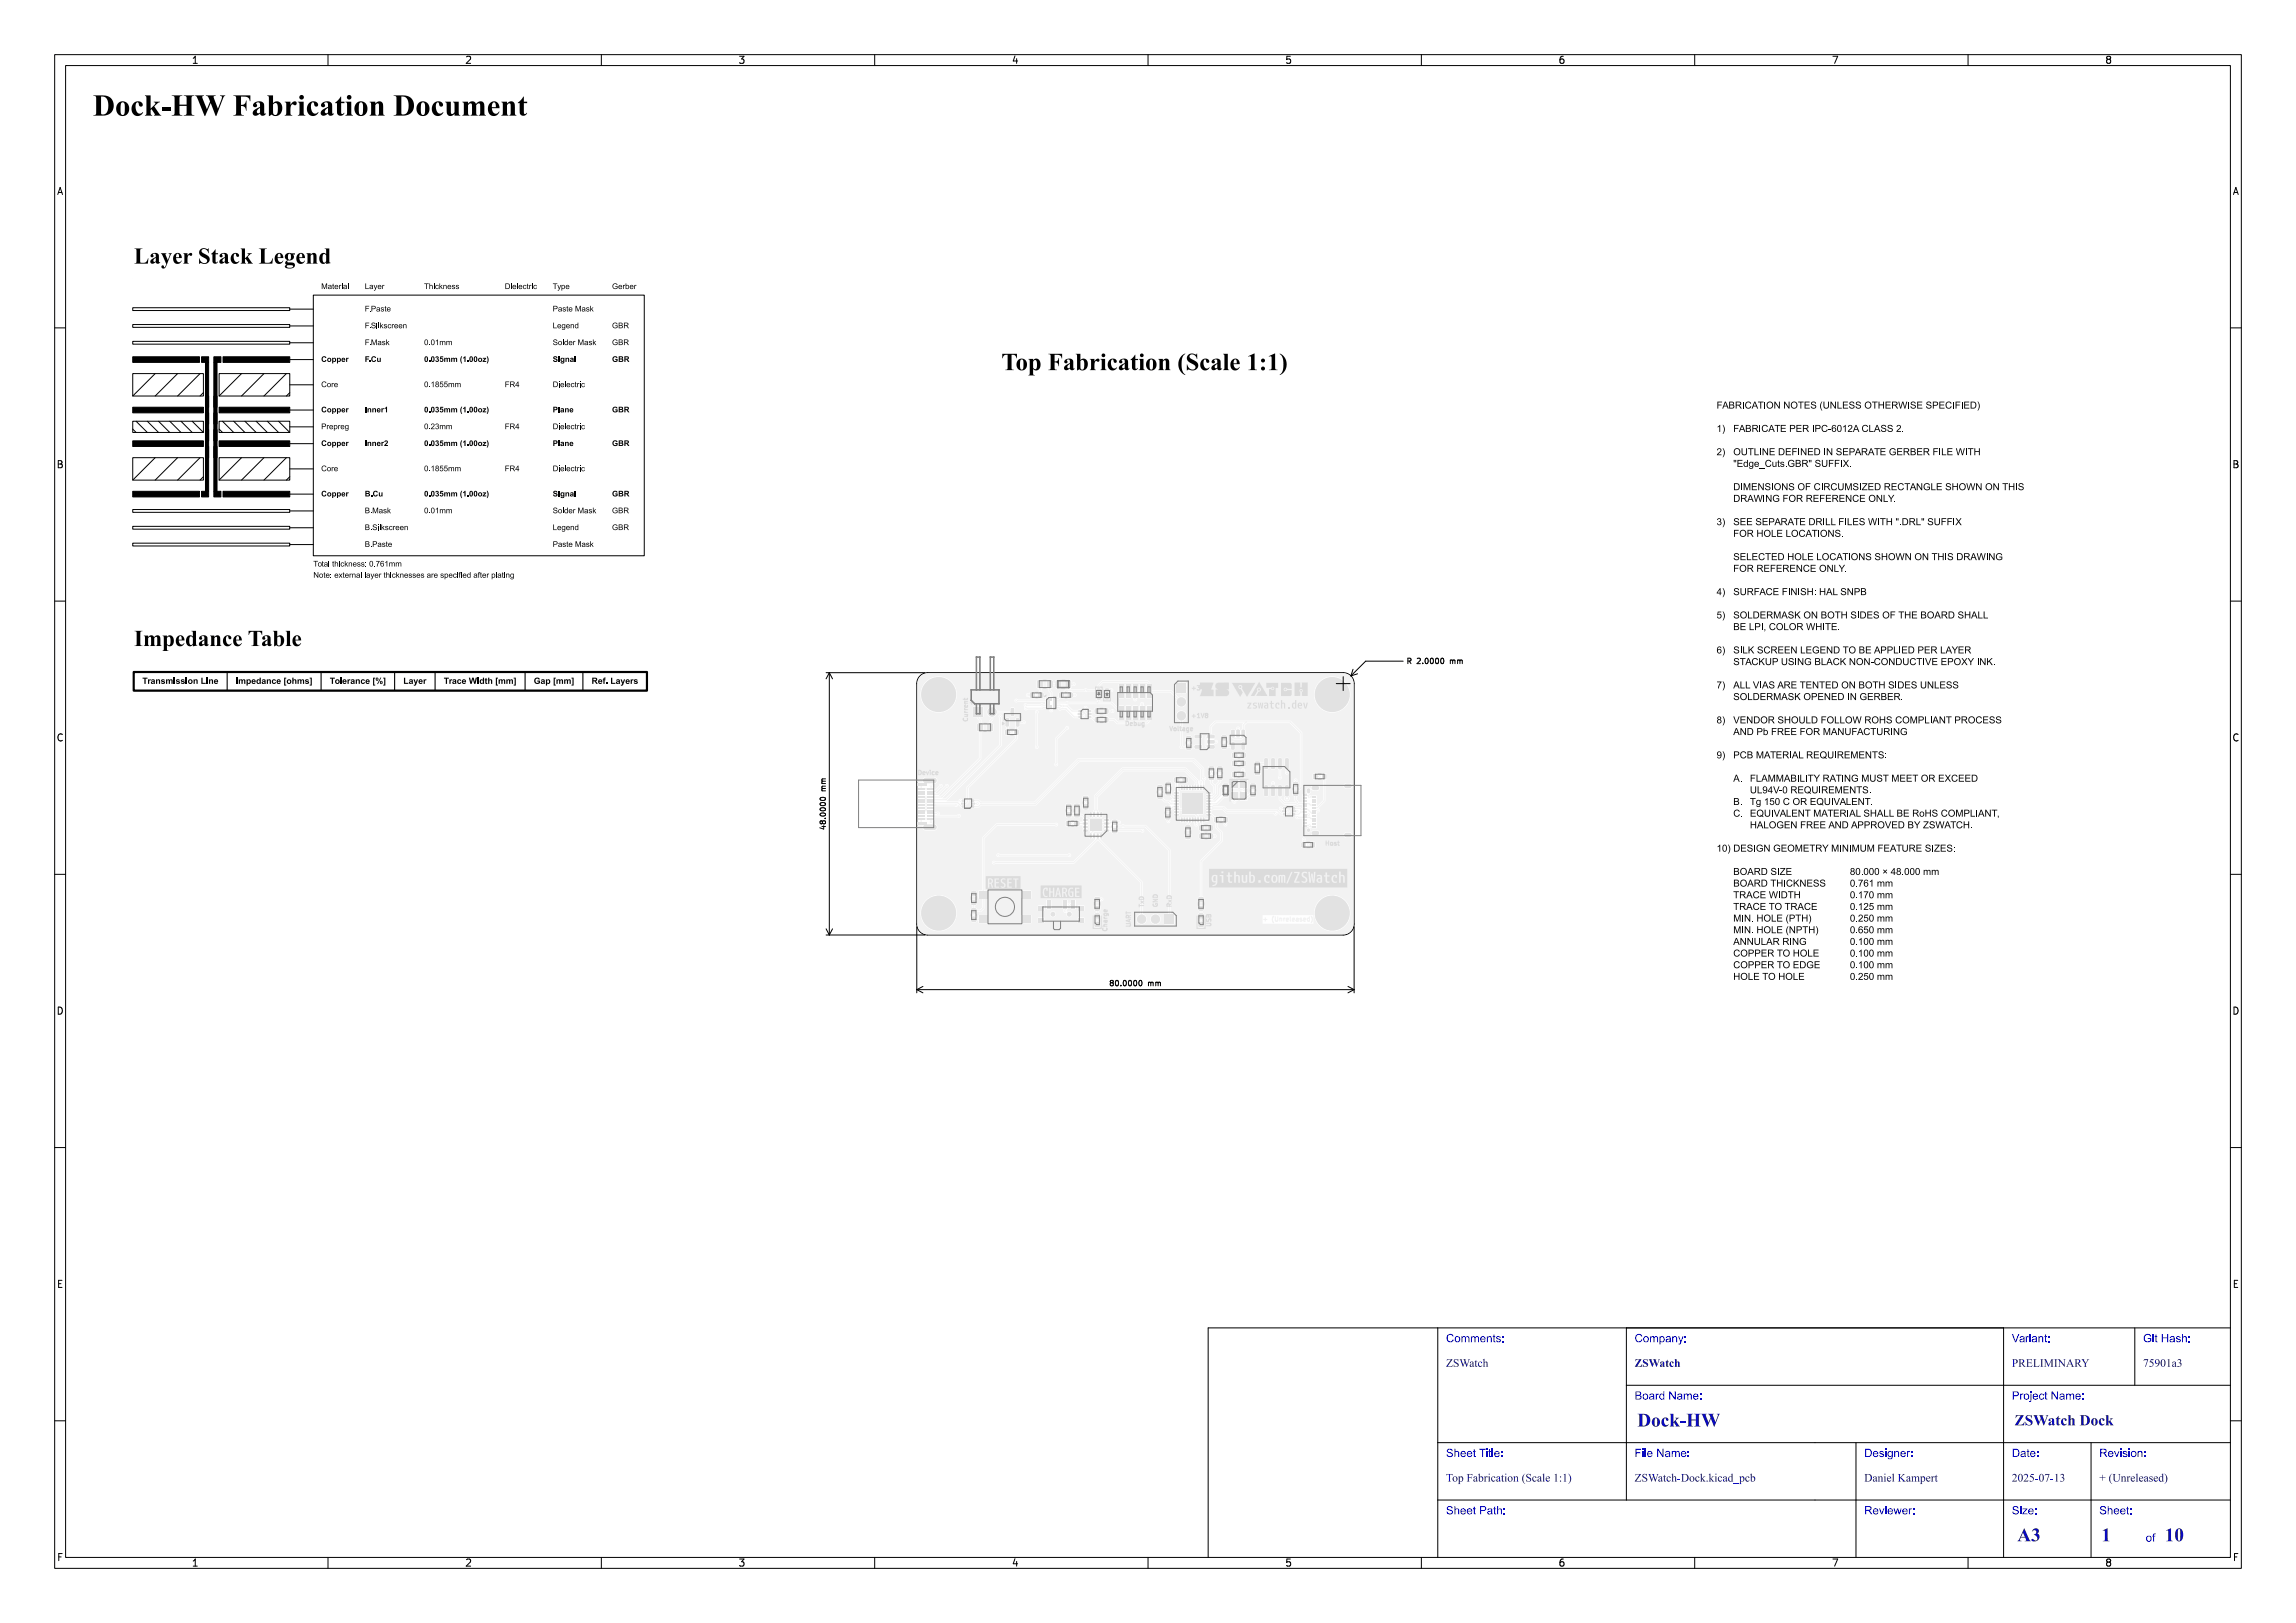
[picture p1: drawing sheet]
<svg xmlns="http://www.w3.org/2000/svg" width="420mm" height="297mm" viewBox="0 0 420 297" stroke-linecap="round" stroke-linejoin="round" font-family="sans-serif">
<defs><g id="words">
<text font-size="5.3" fill="#fff" x="17" y="21.5">Dock-HW Fabrication Document</text>
<text font-size="4.3" fill="#fff" x="174.4" y="68">Top Fabrication (Scale 1:1)</text>
<g font-size="3.3" fill="#fff">
<text x="299.5" y="261.2">Dock-HW</text>
<text x="369" y="282.2">A3</text>
<text x="384.4" y="282.3">1</text>
<text x="396" y="282.3">10</text>
</g>
<text font-size="2.7" fill="#fff" x="368.5" y="261">ZSWatch Dock</text>
<g font-size="2" fill="#fff">
<text x="264.5" y="245.7">Comments:</text>
<text x="299" y="245.7">Company:</text>
<text x="368" y="245.7">Variant:</text>
<text x="392" y="245.7">Git Hash:</text>
<text x="264.5" y="250.2">ZSWatch</text>
<text x="299" y="250.2">ZSWatch</text>
<text x="368" y="250.2">PRELIMINARY</text>
<text x="392" y="250.2">75901a3</text>
<text x="299" y="256.2">Board Name:</text>
<text x="368" y="256.2">Project Name:</text>
<text x="264.5" y="266.7">Sheet Title:</text>
<text x="299" y="266.7">File Name:</text>
<text x="341" y="266.7">Designer:</text>
<text x="368" y="266.7">Date:</text>
<text x="384" y="266.7">Revision:</text>
<text x="264.5" y="271.2">Top Fabrication (Scale 1:1)</text>
<text x="299" y="271.2">ZSWatch-Dock.kicad_pcb</text>
<text x="341" y="271.2">Daniel Kampert</text>
<text x="368" y="271.2">2025-07-13</text>
<text x="384" y="271.2">+ (Unreleased)</text>
<text x="264.5" y="277.2">Sheet Path:</text>
<text x="341" y="277.2">Reviewer:</text>
<text x="368" y="277.2">Size:</text>
<text x="384" y="277.2">Sheet:</text>
<text x="392.5" y="282.2">of</text>
</g>
<g font-size="1.7" fill="#fff">
<text x="35" y="11.6">1</text>
<text x="85" y="11.6">2</text>
<text x="135" y="11.6">3</text>
<text x="185" y="11.6">4</text>
<text x="235" y="11.6">5</text>
<text x="285" y="11.6">6</text>
<text x="335" y="11.6">7</text>
<text x="385" y="11.6">8</text>
<text x="10.5" y="35.6">A</text>
<text x="408.5" y="35.6">A</text>
<text x="10.5" y="85.6">B</text>
<text x="408.5" y="85.6">B</text>
<text x="10.5" y="135.6">C</text>
<text x="408.5" y="135.6">C</text>
<text x="10.5" y="185.6">D</text>
<text x="408.5" y="185.6">D</text>
<text x="10.5" y="235.6">E</text>
<text x="408.5" y="235.6">E</text>
<text x="10.5" y="285.6">F</text>
<text x="35" y="286.7">1</text>
<text x="85" y="286.7">2</text>
<text x="135" y="286.7">3</text>
<text x="185" y="286.7">4</text>
<text x="235" y="286.7">5</text>
<text x="285" y="286.7">6</text>
<text x="335" y="286.7">7</text>
<text x="385" y="286.7">8</text>
<text x="408.5" y="285.6">F</text>
</g>
<g font-size="1.3" fill="#fff">
<text x="258.1" y="121.5">R 2.0000 mm</text>
<text x="151" y="151.1" transform="rotate(-90 151 151.1)">48.0000 mm</text>
<text x="203.7" y="180.4">80.0000 mm</text>
</g>
<text font-size="1.1" fill="#fff" x="178.1" y="128.9" transform="rotate(-90 178.1 128.9)">+</text>
</g></defs>
<path d="M168.3 123.7l.9-.5 .5-.1h76a2 2 0 0 1 2 2v44a2 2 0 0 1-2 2h-76a2 2 0 0 1-2-2v-44l.1-.5z" fill="none" stroke="#000" stroke-width=".18"/>
<g fill="none" stroke="#f2f2f2" stroke-width=".18">
<path d="M231.1 168.3h.7M231.4 168v.6M233 167.6a.92 .92 0 0 0 0 1.3M233.3 167.8v.6l.1 .2 .3-.2v-.6M234.1 168v.6M234.1 168.1h.3l.1 .5M234.8 168v.6M235.1 168l-.3 .2M235.3 168.3l.4-.1-.1-.1h-.3v.4h.3M236 167.8v.6l.1 .2M236.4 168.3l.4-.1-.1-.1h-.3v.4h.3M237.1 168.1h.3l.1 .5"/>
<path d="M237.5 168.2l-.4 .2 .1 .2 .3-.1M238.1 168.1h-.3l.3 .2v.2h-.3M238.5 168.3l.3-.1v-.1h-.3v.4h.3M239.5 168.1l-.2-.1-.2 .2 .1 .3h.3M239.5 167.8v.8M239.8 167.6a.92 .92 0 0 1 0 1.3"/>
</g>
<g fill="#f2f2f2">
<path d="M202 151.9h.8v.2h-.8z" fill-rule="evenodd"/>
<path d="M202 151.2h.8v.3h-.8z" fill-rule="evenodd"/>
<path d="M202 150.6h.8v.2h-.8z" fill-rule="evenodd"/>
<path d="M202 149.9h.8v.3h-.8z" fill-rule="evenodd"/>
<path d="M201.3 148.7h.3v.8h-.3z" fill-rule="evenodd"/>
<path d="M200.7 148.7h.2v.8h-.2z" fill-rule="evenodd"/>
<path d="M200 148.7h.3v.8h-.3z" fill-rule="evenodd"/>
<path d="M199.4 148.7h.2v.8h-.2z" fill-rule="evenodd"/>
<path d="M198.1 149.9h.8v.3h-.8z" fill-rule="evenodd"/>
<path d="M198.1 150.6h.8v.2h-.8z" fill-rule="evenodd"/>
<path d="M198.1 151.2h.8v.3h-.8z" fill-rule="evenodd"/>
<path d="M198.1 151.9h.8v.2h-.8z" fill-rule="evenodd"/>
<path d="M199.4 152.6h.2v.8h-.2z" fill-rule="evenodd"/>
<path d="M200 152.6h.3v.8h-.3z" fill-rule="evenodd"/>
<path d="M200.7 152.6h.2v.8h-.2z" fill-rule="evenodd"/>
<path d="M201.3 152.6h.3v.8h-.3z" fill-rule="evenodd"/>
<path d="M199.4 150h2.1v2.1h-2.1z" fill-rule="evenodd"/>
<path d="M202.2 127.4h.6v.6h-.6z" fill-rule="evenodd"/>
<path d="M202.2 126h.6v.6h-.6z" fill-rule="evenodd"/>
<path d="M219.3 165.9h.8v.7h-.8z" fill-rule="evenodd"/>
<path d="M219.3 164.2h.8v.7h-.8z" fill-rule="evenodd"/>
<path d="M227.2 133.6l.5 .1-.1 1.2-.5-.1z" fill-rule="evenodd"/>
<path d="M226.2 133.6l.6 .1-.1 1.2-.5-.1z" fill-rule="evenodd"/>
<path d="M225.3 133.6l.5 .1-.1 1.2-.5-.1z" fill-rule="evenodd"/>
<path d="M225.3 135.9h.5l-.1 1.3-.5-.1z" fill-rule="evenodd"/>
<path d="M227.2 135.9h.5l-.1 1.3-.5-.1z" fill-rule="evenodd"/>
<path d="M203.5 151.6h.8v.8h-.8z" fill-rule="evenodd"/>
<path d="M203.5 150.1h.8v.8h-.8z" fill-rule="evenodd"/>
<path d="M219.5 152.6h.7v.8h-.7z" fill-rule="evenodd"/>
<path d="M221 152.6h.8v.8h-.8z" fill-rule="evenodd"/>
<path d="M241.9 141.7h.7v.8h-.7z" fill-rule="evenodd"/>
<path d="M240.2 141.7h.7v.8h-.7z" fill-rule="evenodd"/>
<path d="M238.4 150.9h.7v.3h-.7z" fill-rule="evenodd"/>
<path d="M238.4 150.4h.7v.3h-.7z" fill-rule="evenodd"/>
<path d="M238.4 149.9h.7v.3h-.7z" fill-rule="evenodd"/>
<path d="M238.4 149.4h.7v.3h-.7z" fill-rule="evenodd"/>
<path d="M238.4 148.9h.7v.3h-.7z" fill-rule="evenodd"/>
<path d="M238.4 148.4h.7v.3h-.7z" fill-rule="evenodd"/>
<path d="M238.4 147.9h.7v.3h-.7z" fill-rule="evenodd"/>
<path d="M238.4 147.4h.7v.3h-.7z" fill-rule="evenodd"/>
<path d="M238.4 146.9h.7v.3h-.7z" fill-rule="evenodd"/>
<path d="M238.4 146.4h.7v.3h-.7z" fill-rule="evenodd"/>
<path d="M238.4 145.9h.7v.3h-.7z" fill-rule="evenodd"/>
<path d="M238.4 145.4h.7v.3h-.7z" fill-rule="evenodd"/>
<path d="M240.1 145.7h.7v.3h-.7z" fill-rule="evenodd"/>
<path d="M240.1 146.2h.7v.3h-.7z" fill-rule="evenodd"/>
<path d="M240.1 146.7h.7v.3h-.7z" fill-rule="evenodd"/>
<path d="M240.1 147.2h.7v.3h-.7z" fill-rule="evenodd"/>
<path d="M240.1 147.7h.7v.3h-.7z" fill-rule="evenodd"/>
<path d="M240.1 148.2h.7v.3h-.7z" fill-rule="evenodd"/>
<path d="M240.1 148.7h.7v.3h-.7z" fill-rule="evenodd"/>
<path d="M240.1 149.2h.7v.3h-.7z" fill-rule="evenodd"/>
<path d="M240.1 149.7h.7v.3h-.7z" fill-rule="evenodd"/>
<path d="M240.1 150.2h.7v.3h-.7z" fill-rule="evenodd"/>
<path d="M240.1 150.7h.7v.3h-.7z" fill-rule="evenodd"/>
<path d="M240.1 151.2h.7v.3h-.7z" fill-rule="evenodd"/>
</g>
<g fill="#f2f2f2">
<circle cx="241.3" cy="167.1" r=".4"/>
<circle cx="242" cy="165.4" r=".4"/>
<circle cx="242" cy="168.8" r=".4"/>
<circle cx="243.7" cy="164.7" r=".4"/>
<circle cx="243.7" cy="167.1" r="3.2"/>
<circle cx="243.7" cy="169.5" r=".4"/>
<circle cx="245.4" cy="165.4" r=".4"/>
<circle cx="245.4" cy="168.8" r=".4"/>
<circle cx="246.1" cy="167.1" r=".4"/>
</g>
<path d="M240.3 152.4h.6M240.3 144.2h.6M246.3 152.8h.6M246.3 143.8h.6" fill="none" stroke="#f2f2f2" stroke-width=".8"/>
<g fill="#f2f2f2">
<path d="M239.8 154.2h.7v.8h-.7z" fill-rule="evenodd"/>
<path d="M238.1 154.2h.7v.8h-.7z" fill-rule="evenodd"/>
<path d="M200.3 165.9h.8v.7h-.8z" fill-rule="evenodd"/>
<path d="M200.3 164.2h.8v.7h-.8z" fill-rule="evenodd"/>
<path d="M216.9 152.8h.8v.7h-.8z" fill-rule="evenodd"/>
<path d="M216.9 151.1h.8v.7h-.8z" fill-rule="evenodd"/>
<path d="M178.1 129.4h1.7v1.7h-1.7z" fill-rule="evenodd"/>
<path d="M222.7 141.9h.8v.8h-.8z" fill-rule="evenodd"/>
<path d="M222.7 140.3h.8v.8h-.8z" fill-rule="evenodd"/>
<path d="M180.7 132.5l.7-.1 .2 .2v.9l-.1 .3h-.7l-.2-.2z" fill-rule="evenodd"/>
<path d="M178.8 132.5l.8-.1 .2 .2v.9l-.2 .3h-.6l-.2-.2z" fill-rule="evenodd"/>
<path d="M193.2 124.6l.7-.1 .2 .2v.9l-.1 .3h-.7l-.2-.2z" fill-rule="evenodd"/>
<path d="M195 124.6l.7-.1 .2 .2v.9l-.1 .3h-.6l-.3-.2z" fill-rule="evenodd"/>
<path d="M235.1 138.8l.6 .1-.1 1.8-.5-.1z" fill-rule="evenodd"/>
<path d="M233.9 138.8l.5 .1-.1 1.8-.5-.1z" fill-rule="evenodd"/>
<path d="M232.6 138.8l.6 .1-.1 1.8-.5-.1z" fill-rule="evenodd"/>
<path d="M231.3 138.8l.6 .1-.1 1.8-.5-.1z" fill-rule="evenodd"/>
<path d="M231.3 143.8h.6l-.1 1.9-.5-.1z" fill-rule="evenodd"/>
<path d="M232.6 143.8h.6l-.1 1.9-.5-.1z" fill-rule="evenodd"/>
<path d="M233.9 143.8h.5l-.1 1.9-.5-.1z" fill-rule="evenodd"/>
<path d="M235.1 143.8h.6l-.1 1.9-.5-.1z" fill-rule="evenodd"/>
<path d="M223.5 136.2h.8v.8h-.8z" fill-rule="evenodd"/>
<path d="M223.5 134.6h.8v.8h-.8z" fill-rule="evenodd"/>
<path d="M213.1 167.4h1.6v1.6h-1.6z" fill-rule="evenodd"/>
<path d="M183.9 133.6h.7v.8h-.7z" fill-rule="evenodd"/>
<path d="M185.6 133.6h.7v.8h-.7z" fill-rule="evenodd"/>
<path d="M179.1 163h1.5v1.4h-1.5z" fill-rule="evenodd"/>
<path d="M179.1 167.6h1.5v1.2h-1.5z" fill-rule="evenodd"/>
<path d="M187 163h1.6v1.4h-1.6z" fill-rule="evenodd"/>
<path d="M187 167.6h1.6v1.2h-1.6z" fill-rule="evenodd"/>
<path d="M200.3 129.7h.7v.8h-.7z" fill-rule="evenodd"/>
<path d="M202 129.7h.7v.8h-.7z" fill-rule="evenodd"/>
<path d="M213.2 147.5h.8v.8h-.8z" fill-rule="evenodd"/>
<path d="M213.2 149.1h.8v.8h-.8z" fill-rule="evenodd"/>
<path d="M200.7 126h.6v.6h-.6z" fill-rule="evenodd"/>
<path d="M200.7 127.4h.6v.6h-.6z" fill-rule="evenodd"/>
<path d="M229.6 139.4h.8v.7h-.8z" fill-rule="evenodd"/>
<path d="M229.6 141.1h.8v.7h-.8z" fill-rule="evenodd"/>
<path d="M177.7 147.4h.4l.1 .3-.5 .1z" fill-rule="evenodd"/>
<path d="M177.7 146.9h.6v.3h-.6z" fill-rule="evenodd"/>
<path d="M177.7 146.4h.5v.3h-.5z" fill-rule="evenodd"/>
<path d="M176 146.4h.5v.3h-.5z" fill-rule="evenodd"/>
<path d="M175.9 146.9h.5l.1 .3h-.6z" fill-rule="evenodd"/>
<path d="M176 147.4h.4l.1 .3-.5 .1z" fill-rule="evenodd"/>
<path d="M184 131.5h.5v1.4l-.5-.1z" fill-rule="evenodd"/>
<path d="M185.9 131.5h.5v1.4l-.5-.1z" fill-rule="evenodd"/>
<path d="M184.9 129.6l.6 .1-.1 1.3-.5-.1z" fill-rule="evenodd"/>
<path d="M211.8 145.3h.8v.8h-.8z" fill-rule="evenodd"/>
<path d="M211.8 143.8h.8v.7h-.8z" fill-rule="evenodd"/>
<path d="M197.3 130l.4-.1 .1 .4h-.4z" fill-rule="evenodd"/>
<path d="M197.2 130.5h.6v.3h-.6z" fill-rule="evenodd"/>
<path d="M197.3 131h.4l.1 .3-.4 .1z" fill-rule="evenodd"/>
<path d="M199 131h.4l.1 .3-.4 .1z" fill-rule="evenodd"/>
<path d="M199 130.5h.6v.3h-.6z" fill-rule="evenodd"/>
<path d="M199 130l.4-.1 .1 .4h-.4z" fill-rule="evenodd"/>
<path d="M196.6 147.2h.8v.6h-.8z" fill-rule="evenodd"/>
<path d="M196.6 148.8h.8v.7h-.8z" fill-rule="evenodd"/>
<path d="M213.3 143.1h.8v.7h-.8z" fill-rule="evenodd"/>
<path d="M213.3 144.8h.8v.7h-.8z" fill-rule="evenodd"/>
<path d="M190 126.8h.8v.8h-.8z" fill-rule="evenodd"/>
<path d="M188.5 126.8h.7v.8h-.7z" fill-rule="evenodd"/>
<path d="M234.7 147.8l.4-.1 .1 .4h-.4z" fill-rule="evenodd"/>
<path d="M234.6 148.3h.6v.3h-.6z" fill-rule="evenodd"/>
<path d="M234.7 148.8h.4l.1 .3-.4 .1z" fill-rule="evenodd"/>
<path d="M236.4 148.8h.4l.1 .3-.4 .1z" fill-rule="evenodd"/>
<path d="M236.4 148.3h.6v.3h-.6z" fill-rule="evenodd"/>
<path d="M236.4 147.8l.4-.1 .1 .4h-.4z" fill-rule="evenodd"/>
<path d="M177.7 163.2h.8v.7h-.8z" fill-rule="evenodd"/>
<path d="M177.7 164.8h.8v.7h-.8z" fill-rule="evenodd"/>
<path d="M225.2 142.8h1.2v1.4h-1.2z" fill-rule="evenodd"/>
<path d="M225.2 145h1.2v1.4h-1.2z" fill-rule="evenodd"/>
<path d="M226.9 145h1.2v1.4h-1.2z" fill-rule="evenodd"/>
<path d="M226.9 142.8h1.2v1.4h-1.2z" fill-rule="evenodd"/>
<path d="M236.6 144.8h.8v.7h-.8z" fill-rule="evenodd"/>
<path d="M236.6 143.2h.8v.8h-.8z" fill-rule="evenodd"/>
<path d="M177.7 166.3h.8v.8h-.8z" fill-rule="evenodd"/>
<path d="M177.7 167.8h.8v.8h-.8z" fill-rule="evenodd"/>
<path d="M220.1 143.8h.2l-.1 .8-.2-.1z" fill-rule="evenodd"/>
<path d="M219.6 143.8h.2l-.1 .8-.2-.1z" fill-rule="evenodd"/>
<path d="M219.1 143.8h.2l-.1 .8-.2-.1z" fill-rule="evenodd"/>
<path d="M218.6 143.8h.2l-.1 .8-.2-.1z" fill-rule="evenodd"/>
<path d="M218.1 143.8h.2l-.1 .8-.2-.1z" fill-rule="evenodd"/>
<path d="M217.6 143.8h.2l-.1 .8-.2-.1z" fill-rule="evenodd"/>
<path d="M217.1 143.8h.2l-.1 .8-.2-.1z" fill-rule="evenodd"/>
<path d="M216.6 143.8h.2l-.1 .8-.2-.1z" fill-rule="evenodd"/>
<path d="M216.1 143.8h.2l-.1 .8-.2-.1z" fill-rule="evenodd"/>
<path d="M214.8 145h.8v.2h-.7z" fill-rule="evenodd"/>
<path d="M214.8 145.5h.8v.2h-.7z" fill-rule="evenodd"/>
<path d="M214.8 146h.8v.2h-.7z" fill-rule="evenodd"/>
<path d="M214.8 146.5h.8v.2h-.7z" fill-rule="evenodd"/>
<path d="M214.8 147h.8v.2h-.7z" fill-rule="evenodd"/>
<path d="M214.8 147.5h.8v.2h-.7z" fill-rule="evenodd"/>
<path d="M214.8 148h.8v.2h-.7z" fill-rule="evenodd"/>
<path d="M214.8 148.5h.8v.2h-.7z" fill-rule="evenodd"/>
<path d="M214.8 149h.8v.2h-.7z" fill-rule="evenodd"/>
<path d="M216.1 149.6l.2 .1-.1 .8-.2-.1z" fill-rule="evenodd"/>
<path d="M216.6 149.6l.2 .1-.1 .8-.2-.1z" fill-rule="evenodd"/>
<path d="M217.1 149.6l.2 .1-.1 .8-.2-.1z" fill-rule="evenodd"/>
<path d="M217.6 149.6l.2 .1-.1 .8-.2-.1z" fill-rule="evenodd"/>
<path d="M218.1 149.6l.2 .1-.1 .8-.2-.1z" fill-rule="evenodd"/>
<path d="M218.6 149.6l.2 .1-.1 .8-.2-.1z" fill-rule="evenodd"/>
<path d="M219.1 149.6l.2 .1-.1 .8-.2-.1z" fill-rule="evenodd"/>
<path d="M219.6 149.6l.2 .1-.1 .8-.2-.1z" fill-rule="evenodd"/>
<path d="M220.1 149.6l.2 .1-.1 .8-.2-.1z" fill-rule="evenodd"/>
<path d="M220.7 149h.8v.2h-.8z" fill-rule="evenodd"/>
<path d="M220.7 148.5h.8v.2h-.8z" fill-rule="evenodd"/>
<path d="M220.7 148h.8v.2h-.8z" fill-rule="evenodd"/>
<path d="M220.7 147.5h.8v.2h-.8z" fill-rule="evenodd"/>
<path d="M220.7 147h.8v.2h-.8z" fill-rule="evenodd"/>
<path d="M220.7 146.5h.8v.2h-.8z" fill-rule="evenodd"/>
<path d="M220.7 146h.8v.2h-.8z" fill-rule="evenodd"/>
<path d="M220.7 145.5h.8v.2h-.8z" fill-rule="evenodd"/>
<path d="M220.7 145h.8v.2h-.8z" fill-rule="evenodd"/>
<path d="M216.3 145.2h3.7v3.7h-3.7z" fill-rule="evenodd"/>
<path d="M227 137.8h.8v.8h-.8z" fill-rule="evenodd"/>
<path d="M225.5 137.8h.7v.8h-.7z" fill-rule="evenodd"/>
<path d="M200.3 168.8h.8v.8h-.8z" fill-rule="evenodd"/>
<path d="M200.3 167.2h.8v.8h-.8z" fill-rule="evenodd"/>
<path d="M190 165.8h1v.8h-1z" fill-rule="evenodd"/>
<path d="M190 168h1v.8h-1z" fill-rule="evenodd"/>
<path d="M197.2 165.8h1.1v.8h-1.1z" fill-rule="evenodd"/>
<path d="M197.2 168h1.1v.8h-1.1z" fill-rule="evenodd"/>
<path d="M191.5 164.8h.7v1.5h-.7z" fill-rule="evenodd"/>
<path d="M194.5 164.8h.7v1.5h-.7z" fill-rule="evenodd"/>
<path d="M196 164.8h.7v1.5h-.7z" fill-rule="evenodd"/>
<path d="M222.2 149.6h.6v.8h-.6z" fill-rule="evenodd"/>
<path d="M223.8 149.6h.7v.8h-.7z" fill-rule="evenodd"/>
<path d="M227 139.3h.8v.8h-.8z" fill-rule="evenodd"/>
<path d="M225.5 139.3h.7v.8h-.7z" fill-rule="evenodd"/>
<path d="M169.7 149.7h1.2v.3h-1.2z" fill-rule="evenodd"/>
<path d="M169.7 149.2h1.2v.3h-1.2z" fill-rule="evenodd"/>
<path d="M169.7 148.7h1.2v.3h-1.2z" fill-rule="evenodd"/>
<path d="M169.7 148.2h1.2v.3h-1.2z" fill-rule="evenodd"/>
<path d="M169.7 147.7h1.2v.3h-1.2z" fill-rule="evenodd"/>
<path d="M169.7 147.2h1.2v.3h-1.2z" fill-rule="evenodd"/>
<path d="M169.7 146.7h1.2v.3h-1.2z" fill-rule="evenodd"/>
<path d="M169.7 146.2h1.2v.3h-1.2z" fill-rule="evenodd"/>
<path d="M169.7 145.7h1.2v.3h-1.2z" fill-rule="evenodd"/>
<path d="M169.7 145.2h1.2v.3h-1.2z" fill-rule="evenodd"/>
<path d="M169.7 144.7h1.2v.3h-1.2z" fill-rule="evenodd"/>
<path d="M169.7 144.2h1.2v.3h-1.2z" fill-rule="evenodd"/>
<path d="M167.9 144.2h1.1v.3h-1.1z" fill-rule="evenodd"/>
<path d="M167.9 144.7h1.1v.3h-1.1z" fill-rule="evenodd"/>
<path d="M167.9 145.2h1.1v.3h-1.1z" fill-rule="evenodd"/>
<path d="M167.9 145.7h1.1v.3h-1.1z" fill-rule="evenodd"/>
<path d="M167.9 146.2h1.1v.3h-1.1z" fill-rule="evenodd"/>
<path d="M167.9 146.7h1.1v.3h-1.1z" fill-rule="evenodd"/>
<path d="M167.9 147.2h1.1v.3h-1.1z" fill-rule="evenodd"/>
<path d="M167.9 147.7h1.1v.3h-1.1z" fill-rule="evenodd"/>
<path d="M167.9 148.2h1.1v.3h-1.1z" fill-rule="evenodd"/>
<path d="M167.9 148.7h1.1v.3h-1.1z" fill-rule="evenodd"/>
<path d="M167.9 149.2h1.1v.3h-1.1z" fill-rule="evenodd"/>
<path d="M167.9 149.7h1.1v.3h-1.1z" fill-rule="evenodd"/>
</g>
<g fill="#f2f2f2">
<circle cx="181.5" cy="130.3" r=".85"/>
<circle cx="211.4" cy="168.2" r=".85"/>
<circle cx="208.8" cy="168.2" r=".85"/>
<circle cx="241.3" cy="127.1" r=".4"/>
<circle cx="242" cy="125.4" r=".4"/>
<circle cx="242" cy="128.8" r=".4"/>
<circle cx="243.7" cy="124.7" r=".4"/>
<circle cx="243.7" cy="127.1" r="3.2"/>
<circle cx="243.7" cy="129.5" r=".4"/>
<circle cx="245.4" cy="125.4" r=".4"/>
<circle cx="245.4" cy="128.8" r=".4"/>
<circle cx="246.1" cy="127.1" r=".4"/>
<circle cx="169.3" cy="167.1" r=".4"/>
<circle cx="170" cy="165.4" r=".4"/>
<circle cx="170" cy="168.8" r=".4"/>
<circle cx="171.7" cy="164.7" r=".4"/>
<circle cx="171.7" cy="167.1" r="3.2"/>
<circle cx="171.7" cy="169.5" r=".4"/>
<circle cx="173.4" cy="165.4" r=".4"/>
<circle cx="173.4" cy="168.8" r=".4"/>
<circle cx="174.1" cy="167.1" r=".4"/>
</g>
<path d="M169.3 142.8h1.6" fill="none" stroke="#f2f2f2" stroke-width="1"/>
<g fill="#f2f2f2">
<path d="M167.8 143.3h1.8v.5h-1.8z" fill-rule="evenodd"/>
<path d="M167.8 150.4h1.8v.5h-1.8z" fill-rule="evenodd"/>
</g>
<path d="M169.3 151.4h1.6" fill="none" stroke="#f2f2f2" stroke-width="1"/>
<g fill="#f2f2f2">
<path d="M214.9 142.3h.7v.8h-.7z" fill-rule="evenodd"/>
<path d="M216.4 142.3h.8v.8h-.8z" fill-rule="evenodd"/>
<path d="M228.8 143.5h.8v.7h-.8z" fill-rule="evenodd"/>
<path d="M228.8 145h.8v.8h-.8z" fill-rule="evenodd"/>
<path d="M209.8 125.3h.8v2.4h-.8z" fill-rule="evenodd"/>
<path d="M209.8 129.2h.8v2.4h-.8z" fill-rule="evenodd"/>
<path d="M208.5 125.3h.8v2.4h-.8z" fill-rule="evenodd"/>
<path d="M208.5 129.2h.8v2.4h-.8z" fill-rule="evenodd"/>
<path d="M207.3 125.3h.7v2.4h-.7z" fill-rule="evenodd"/>
<path d="M207.3 129.2h.7v2.4h-.7z" fill-rule="evenodd"/>
<path d="M206 125.3h.7v2.4h-.7z" fill-rule="evenodd"/>
<path d="M206 129.2h.7v2.4h-.7z" fill-rule="evenodd"/>
<path d="M204.7 125.3h.8v2.4h-.8z" fill-rule="evenodd"/>
<path d="M204.7 129.2h.8v2.4h-.8z" fill-rule="evenodd"/>
<path d="M221.1 151.1h.7v.8h-.7z" fill-rule="evenodd"/>
<path d="M219.4 151.1h.7v.8h-.7z" fill-rule="evenodd"/>
<path d="M215.2 125.1h1.7v1.7h-1.7z" fill-rule="evenodd"/>
<path d="M189.8 124.6l.7-.1 .2 .2v.9l-.1 .3h-.7l-.2-.2z" fill-rule="evenodd"/>
<path d="M191.6 124.6l.7-.1 .2 .2v.9l-.1 .3h-.6l-.3-.2z" fill-rule="evenodd"/>
<path d="M191.3 127.7h.6v.2h-.6z" fill-rule="evenodd"/>
<path d="M191.8 127.5h.1v.3h-.1z" fill-rule="evenodd"/>
<path d="M191.3 128.1h.6v.2h-.6z" fill-rule="evenodd"/>
<path d="M191.3 128.5h.6v.2h-.6z" fill-rule="evenodd"/>
<path d="M191.3 128.9h.6v.2h-.6z" fill-rule="evenodd"/>
<path d="M191.3 129.3h.6v.2h-.6z" fill-rule="evenodd"/>
<path d="M192.2 129.1h.2v.6h-.2z" fill-rule="evenodd"/>
<path d="M192.6 129.3h.6v.2h-.6z" fill-rule="evenodd"/>
<path d="M192.6 128.9h.6v.2h-.6z" fill-rule="evenodd"/>
<path d="M192.6 128.5h.6v.2h-.6z" fill-rule="evenodd"/>
<path d="M192.6 128.1h.6v.2h-.6z" fill-rule="evenodd"/>
<path d="M192.6 127.7h.6v.2h-.6z" fill-rule="evenodd"/>
<path d="M192.2 127.5h.2v.6h-.2z" fill-rule="evenodd"/>
<path d="M219.3 168.8h.8v.8h-.8z" fill-rule="evenodd"/>
<path d="M219.3 167.2h.8v.8h-.8z" fill-rule="evenodd"/>
<path d="M223.8 143.4h.8v.7h-.8z" fill-rule="evenodd"/>
<path d="M223.8 145.1h.8v.7h-.8z" fill-rule="evenodd"/>
<path d="M193.8 126.8h.8v.8h-.8z" fill-rule="evenodd"/>
<path d="M195.4 126.8h.7v.8h-.7z" fill-rule="evenodd"/>
<path d="M195.1 148.7h.8v.8h-.8z" fill-rule="evenodd"/>
<path d="M195.1 147.2h.8v.7h-.8z" fill-rule="evenodd"/>
<path d="M221.2 142h.8v.7h-.8z" fill-rule="evenodd"/>
<path d="M221.2 140.3h.8v.7h-.8z" fill-rule="evenodd"/>
<path d="M196.6 150.3h.8v.8h-.8z" fill-rule="evenodd"/>
<path d="M195 150.3h.8v.8h-.8z" fill-rule="evenodd"/>
<path d="M200.3 131.3h.7v.8h-.7z" fill-rule="evenodd"/>
<path d="M202 131.3h.7v.8h-.7z" fill-rule="evenodd"/>
<path d="M198.2 147.3h.8v.7h-.8z" fill-rule="evenodd"/>
<path d="M198.2 145.7h.8v.8h-.8z" fill-rule="evenodd"/>
<path d="M227 141.3h.8v.8h-.8z" fill-rule="evenodd"/>
<path d="M225.4 141.3h.8v.8h-.8z" fill-rule="evenodd"/>
<path d="M217 136.3h.9v.8h-.9z" fill-rule="evenodd"/>
<path d="M217 134.8h.9v.8h-.9z" fill-rule="evenodd"/>
<path d="M220.9 136.4h1.2v.5l-1.2 .1z" fill-rule="evenodd"/>
<path d="M220.9 135.5l1.2-.1v.5l-1.2 .1z" fill-rule="evenodd"/>
<path d="M220.9 134.5h1.2v.5l-1.2 .1z" fill-rule="evenodd"/>
<path d="M218.6 134.5h1.2l.1 .5-1.3 .1z" fill-rule="evenodd"/>
<path d="M218.6 136.4h1.2l.1 .5-1.3 .1z" fill-rule="evenodd"/>
</g>
<g fill="#f2f2f2">
<circle cx="216.1" cy="128.4" r=".85"/>
<circle cx="216.1" cy="131" r=".85"/>
<circle cx="169.3" cy="127.1" r=".4"/>
<circle cx="170" cy="125.4" r=".4"/>
<circle cx="170" cy="128.8" r=".4"/>
<circle cx="171.7" cy="124.7" r=".4"/>
<circle cx="171.7" cy="127.1" r="3.2"/>
<circle cx="171.7" cy="129.5" r=".4"/>
<circle cx="173.4" cy="125.4" r=".4"/>
<circle cx="173.4" cy="128.8" r=".4"/>
<circle cx="174.1" cy="127.1" r=".4"/>
<circle cx="227.4" cy="140.9" r=".22"/>
<circle cx="237" cy="142.8" r=".23"/>
<circle cx="232.9" cy="143.3" r=".23"/>
<circle cx="235.6" cy="148.5" r=".23"/>
<circle cx="196.6" cy="127.2" r=".22"/>
<circle cx="222.2" cy="153" r=".23"/>
<circle cx="198.6" cy="146.9" r=".22"/>
<circle cx="207.6" cy="128" r=".23"/>
<circle cx="223.9" cy="135.8" r=".23"/>
<circle cx="178.1" cy="167.5" r=".22"/>
<circle cx="225.8" cy="146.7" r=".22"/>
<circle cx="196.2" cy="150.7" r=".23"/>
<circle cx="218.8" cy="150.9" r=".23"/>
<circle cx="196.4" cy="125.2" r=".22"/>
<circle cx="223.1" cy="141.5" r=".22"/>
<circle cx="198.2" cy="131" r=".23"/>
<circle cx="230" cy="140.7" r=".22"/>
<circle cx="217.4" cy="135.9" r=".22"/>
<circle cx="203.3" cy="126.3" r=".22"/>
<circle cx="222.4" cy="135.7" r=".22"/>
<circle cx="226.6" cy="139.7" r=".23"/>
<circle cx="212.2" cy="144.9" r=".22"/>
<circle cx="226.6" cy="138.2" r=".23"/>
<circle cx="170.3" cy="150.4" r=".23"/>
<circle cx="192.3" cy="130" r=".22"/>
<circle cx="229.2" cy="144.6" r=".23"/>
<circle cx="216.1" cy="142.7" r=".22"/>
<circle cx="213.7" cy="150.3" r=".23"/>
<circle cx="224.1" cy="150.9" r=".23"/>
<circle cx="239.5" cy="145.8" r=".23"/>
<circle cx="204.7" cy="150.5" r=".23"/>
<circle cx="221.6" cy="141.5" r=".22"/>
<circle cx="188" cy="127.2" r=".22"/>
<circle cx="219.7" cy="168.4" r=".22"/>
<circle cx="241.4" cy="142.1" r=".23"/>
<circle cx="170.3" cy="143.8" r=".23"/>
<circle cx="226.5" cy="133.3" r=".22"/>
<circle cx="178.8" cy="147.1" r=".23"/>
<circle cx="239.3" cy="154.6" r=".22"/>
<circle cx="227.5" cy="144.5" r=".23"/>
<circle cx="195.5" cy="148.2" r=".23"/>
<circle cx="239.6" cy="151.1" r=".22"/>
<circle cx="194.9" cy="166.7" r=".23"/>
<circle cx="189.6" cy="136.7" r=".22"/>
<circle cx="189.6" cy="130.3" r=".22"/>
<circle cx="189.6" cy="127.2" r=".22"/>
<circle cx="216.1" cy="136.7" r=".22"/>
<circle cx="209" cy="152" r=".22"/>
<circle cx="195.2" cy="133.2" r=".22"/>
<circle cx="195.2" cy="128.6" r=".22"/>
<circle cx="193.2" cy="150.9" r=".23"/>
<circle cx="193.2" cy="139.9" r=".22"/>
<circle cx="233.3" cy="148.9" r=".22"/>
<circle cx="234.3" cy="147.9" r=".23"/>
<circle cx="187.7" cy="129.6" r=".22"/>
<circle cx="173.2" cy="143.8" r=".23"/>
<circle cx="190.6" cy="129" r=".22"/>
<circle cx="172.1" cy="143.8" r=".23"/>
<circle cx="187.6" cy="129" r=".22"/>
<circle cx="187.3" cy="132.2" r=".23"/>
<circle cx="201.5" cy="164.6" r=".22"/>
<circle cx="235.4" cy="146.1" r=".4"/>
<circle cx="237.3" cy="147.1" r=".23"/>
<circle cx="237.3" cy="148.5" r=".23"/>
<circle cx="220.8" cy="150" r=".22"/>
<circle cx="237.3" cy="149.6" r=".23"/>
<circle cx="183" cy="131.1" r=".23"/>
<circle cx="185.9" cy="128.2" r=".22"/>
<circle cx="220.3" cy="142.5" r=".22"/>
<circle cx="219.7" cy="143.1" r=".23"/>
<circle cx="213.7" cy="144.3" r=".22"/>
<circle cx="235.4" cy="141.4" r=".23"/>
<circle cx="171.6" cy="148.8" r=".22"/>
<circle cx="181.8" cy="157.8" r=".22"/>
<circle cx="175.4" cy="149.3" r=".23"/>
<circle cx="195.6" cy="156.5" r=".23"/>
<circle cx="182.6" cy="156.5" r=".23"/>
<circle cx="205.4" cy="151.2" r=".22"/>
<circle cx="198.6" cy="126.3" r=".22"/>
<circle cx="198.6" cy="129.5" r=".22"/>
<circle cx="195.6" cy="165.5" r=".23"/>
<circle cx="185.1" cy="134" r=".23"/>
<circle cx="200.7" cy="168.4" r=".22"/>
<circle cx="194.4" cy="129.2" r=".22"/>
<circle cx="193.9" cy="129.7" r=".23"/>
<circle cx="234.1" cy="142.3" r=".23"/>
<circle cx="214.4" cy="146.6" r=".23"/>
<circle cx="203.5" cy="130.1" r=".22"/>
<circle cx="208.9" cy="128.8" r=".22"/>
<circle cx="238.5" cy="153.6" r=".22"/>
<circle cx="239.4" cy="149.1" r=".23"/>
<circle cx="238" cy="148.6" r=".23"/>
<circle cx="241.1" cy="148.3" r=".22"/>
<circle cx="174.9" cy="147.3" r=".23"/>
<circle cx="175.7" cy="146.5" r=".23"/>
</g>
<g fill="none" stroke="#f2f2f2" stroke-width=".2">
<path d="M178.9 130.3v1.1l.4 .4v7l-7 7.1h-3.8M179.3 133.1h.1M181.5 130.3v1.4l-.4 .3v1.1M181.5 130.3h.1M181.5 130.3h3.7M183 131.1v5.3l-10 10h-2.7M184.2 132.2l.1 1.8h.8M185.9 128.2h5.7v.4M187.3 132.2h-1.2v.8l-.2 .2v2l-8.9 8.9v2.6l-.4 .4h-.4M187.6 129h4M188 127.2h.9M189.6 127.2h1.4l.6 .6"/>
<path d="M189.6 130.3v6.4M190.2 125.2l.2 2M191.6 129.4h-.7l-.2 .2-3 .1M192.3 129.4v.6M192.9 127.8h.7l1.5-1.5h5.9v-.9l.7-.7h8.2l.3 .3v1.5h4l1.9 1.9M192.9 128.2v.4h10.4l1.8 1.8M192.9 129.4h.7l.3 .3h1.1l1.5 1.5h1M192.9 129l2.3 .2 .9 .9h1.4M193.6 125.2h-1.6v1.2l.3 .3v1.1M195.2 133.2l-2 2v4.7M195.4 125.2h1M195.8 127.2h.8"/>
<path d="M197.5 130.7h.4l.2 .2M198.6 129.5v.7l.5 .5h.2M199.3 131.2h.3l.5 .5h.6l-.2 .2M199.3 130.1h1.4M202.3 130.1h1.2M202.5 126.3h.8M202.5 127.7h-1.5v.6l-.3 .3M208.9 126.5h-1.3v1.5M208.9 128.8v1.6M210.2 130.4v1.5l-.4 .4h-5.4l-.6-.6h-1.5M216.1 131v5.7h3.1M217.5 135.2v.7"/>
<path d="M221.6 135.7h.8M221.6 134.8h-.7l-.3 .3v1.3l.2 .3h.8M223.9 135v.8M225.5 136.5l-1.6 .1M225.8 138.2h.8M225.8 139.7h.8M226.5 133.3v.9M227.4 136.5v3.2M227.4 138.2h.1M228 132.1l-.6 .6v2.1l-.3 .3h-1.3l-.3-.2v-.7M230.9 139.7l-.1 .1M231.6 139.7l-1.6 .1"/>
<path d="M234.1 139.7v2.6M235.4 139.7v1.7M238 134.1l-2-2h-13.7l-.8 .8v1.9M238 134.2v10M168.5 148.4h1.8M168.7 143.5l-.2 .2v.6h1.8v-.5M169 145.9l.4 .3v1.9l-.2 .3M170.3 150.4v-.5h-1.8v.6l.2 .2M170.3 148.9h1.3M170.3 146.9h4.9l.7 .7h.3M171.1 147.3h.1M172.1 143.8l-1 1h-.8"/>
<path d="M173.2 143.8l-1.6 1.6h-1.3M174.9 147.3h-4.6M175.4 149.3l-5.1 .1M175.7 146.5h.5M178 147.1h.8M182.6 156.5h13M193.2 150.9h-10.9l-2.4 2.4v12.9l-.5 .5h-1.3v-1.5M195.4 150.7h.8M195.5 147.6v.6M195.5 149.1l2.4 .1 .6 .6v.3M197 150.7h1.5M198.6 146.1v.8"/>
<path d="M198.6 147.6v1.2l.3 .3h.6M200.8 153.5l8 8v6.7M200.8 153.5l-4.4 4.4h-14.6M200.8 153v.5M202.4 152h6.6M202.4 151.3h1.9l.2-.1h5l4.4 4.4v12.6M204.7 150.5h-1.5l-.2 .2h-1.2l-.4 .3h-.9v.6l-1 1v.4M212.2 144.1v.8M212.2 145.7l.9 .9h.6l.5 .5h1M213.6 149.5l.1 .8M213.7 144.3v.8l1 1h.5M214.4 146.6h.8"/>
<path d="M215.2 147.6h-.6l-.3 .3h-.7M215.2 142.5v2.6M216.1 142.7h.7M216.7 147.1h1.5M217.7 150v.5l-.4 .3v.7M218.2 147.1l-1 1h-2M218.2 147.1v1.3l1 1v.6h-.5v.7l.1 .2M219.7 150v.5l.1 .2v2.3M220.2 150h.6M221.1 149.1h.5l.9 .9v1.4l1 1v1.4l-3.8 3.8v7M221.4 153h.8M221.6 140.7v.8"/>
<path d="M221.6 142.3v1l.5 .5v1.4l-.4 .4h-.6M223.1 140.7v.8M223.1 142.3v.8l-.6 .6v1.6l-.8 .8h-.6M224.2 150v.9M225.8 145.7v1M225.8 141.7v1.8h-.7l-.2 .3h-1.1l-.5 .5v1.2l-1.1 1.1h-1.1M225.8 142.4h.1M227.4 140.9v.8M227.5 143.5v1M229.2 145.4h-.6l-.3 .3h-.8v-.3l-.7-.7h-1.9l-2.4 2.4h-1.4M229.2 143.9v.7M230 140.7v.7"/>
<path d="M232.9 143.3v1.4M234.1 144.7v1.5l.9 .9h4.5l.2 .2h.7M234.9 148.5h.7M235.4 141.4h.1M236.7 148.5h.6M237 142.8v.8M237 145.2v1.2l.3 .3v.4M237.3 149.6h2.3l.2 .2h.6M238 144.1l-1 1.1M238.5 153.6v1M238.7 151.1h.9l.2 .2h.6M238.7 145.6h.6l.2 .2h.9"/>
<path d="M238.7 149.1h.7M239.3 154.6h.8M240.6 142.1h.8M242.2 142.1v4.5l-1.2 1.2h-.6M178.1 167.5v.7h1.8M194.9 165.5v1.2M195.6 165.5h.7M200.7 164.6h.8M200.7 166.2v1.4M200.7 168.4v.8M219.7 166.2v1.4M219.7 168.4v.8"/>
</g>
<path d="M218.7 144.2l.1-1.2-2.1-2.1h-11.2l-4.9 4.9v2.5l.2 .1v.7M219.2 144.2l-.1-1.3-2.2-2.2h-11.6l-5 5v2.6l-.1 .1v.7M219.7 143.1v1.1M220.2 144.2v-1.2l-.4-.4v-1.8l-1.6-1.6h-20.8l-8 8h-10l-.4 .4h-1.1M220.3 142.5l-.2-.3v-1.5l-1.7-1.7h-21.2l-7.9 7.9h-9.9l-.4-.4h-1.1M221.1 148.1l2.6-.1 .6 .6h8.8l.2 .3M221.1 147.6l2.7 .1 .7 .7h9.2l.6 .6h.6M234.3 147.9h.6M236.7 147.9l2.5 .2 .7 .7h.5M238.7 148.6h-.7l-.4 .4h-.9M240.4 148.3h.7" fill="none" stroke="#f2f2f2" stroke-width=".18"/>
<path d="M235.4 144.7v1.4" fill="none" stroke="#f2f2f2" stroke-width=".4"/>
<path d="M168.4 123.8l.6-.5 .7-.1h76.2a1.9 1.9 0 0 1 1.7 1.9v44.2a1.9 1.9 0 0 1-1.9 1.7h-76.2a1.91 1.91 0 0 1-1.7-1.9v-2.2h.6a3.3 3.3 0 0 0 4.4 3.4 3.3 3.3 0 0 0 1.4-5.4h3.3v.6l.4 .3v.3l-.4 .3v.6l.3 .3-.3 .7v.6l.3 .2h.7l.2-.4h.2l.2 .6h1.5l.1-1.5h6.2v1.4l.1 .1h1.6l.1-1h1.1v.8l.1 .1h1.1l.1-.9h6l.1 .9h1.1l.1-.1v-.8l-.1-.1h-1.1l-.1 .1h-6l-.1-.1-2.3 .1-.1-.6h-1.6l-.1 .1-7.8-.1-.1 .6a.49 .49 0 0 1-.5-.8h13.5v.2a.55 .55 0 0 0 .9 .4 .55 .55 0 0 0 0-1 .55 .55 0 0 0-.9 .4h-13.5l.2-.3h.8l.5-.6 .1-.5h9.7l.1 .9h1.1l.1-.1v-.8l-.1-.1h-1.1l-.1 .1h-9.7v-1h11.3v1.5l.1 .1 .8-.1v-1.5h2.1v1.5l.1 .1a.42 .42 0 0 0 .1 .5 .42 .42 0 0 0 .5 .1 .57 .57 0 0 0 .4 .9 .57 .57 0 0 0 .6-.8 .57 .57 0 0 0-.9-.2l-.1-.4 .2-.2 .1-.5 .5 .1 .1 .5h.7l.1-.1v-.5h.3v.8l.1 .1h1.1l.1-.7h1.7v.5l.4 .3v.2l-.4 .3v.6l.3 .3v.4l-.3 .3v.6l.3 .3 .6-.1 .3-.2v-.6l-.3-.3v-.4l.3-.3v-.6l-.4-.3v-.2l.4-.3-.1-.7-.1-.1h-.7l-.3 .3h-1.7l-.1-.3-1.5 .1-.1-1.1h-.7l-.1 .5h-.5l-.2-.5h-.7l-.1 .1h-2.1l-.1-.1h-.7l-.1 .1h-11.3v-.3l.6-.1v-1.4h6.2v1.4l.1 .1h1.6l.1-.2h11.4v.6l.1 .1 .8 .1 .2-.1a.46 .46 0 0 0 .6-.6l-.8-.4-.7 .1-.2 .2h-11.4v-1.3l-.1-.1h-1.6l-.1 .1h-6.2l-.6-.1v-5.1h1.3v.1a.37 .37 0 0 0 .3 .3 .37 .37 0 0 0 .4-.1h14.3l4.4-4.3 7.8 7.7v5.7a.98 .98 0 0 0-.7 1.2 .98 .98 0 0 0 1.1 .8 .98 .98 0 0 0 .8-1.1h.6v.2a.98 .98 0 0 0 1.5 .7 .98 .98 0 0 0 0-1.6 .98 .98 0 0 0-1.5 .7l-.6-.1a1.17 1.17 0 0 0-.8-.8v-5.9l-7.7-7.7 .4-.2v-.9l-.4-.1-.2 .2-.4-.2-.2 .2-.5-.2 .2-.2h1.4l.1-1.1 .2-.2 .1 .1-.1 .3 .1 .4h-.1v.5l1.3 .1 .3 .3h.8l.3-.3h4.1a.36 .36 0 0 0 .5 0 .36 .36 0 0 0 0-.5 .36 .36 0 0 0-.5 0h-4.1l-.2-.2 .2-.2 .8 .1 .3-.1h3.7l4.3 4.3v11.5l-.8 .1 .1 1.9 1.9-.1v-1.8l-.8-.1v-1.2h5v.5l.4 .3v.2l-.4 .4v.5l.3 .3v.4l-.3 .3v.5l.3 .4 .8-.1 .1-.6h20v-1.6h-9.3v1.6h-10.7l-.1-.3-.2-.2v-.4l.3-.3v-.6l-.4-.4h20.5a3.3 3.3 0 0 0 4.7 3.2 3.3 3.3 0 0 0 .6-5.7 3.3 3.3 0 0 0-5.3 2.2v.3h-20.5l.4-.4v-.6l-.2-.2h-.8l-.2 .3h-5v-1.7h5v.6l.1 .1 .8 .1 .2-.1 .1-.7-.4-.3v-6.3l3.4-3.4h14.7v.7l.2 .2h.6l.3-.3h.5l.2 .3h.6l.2-.1 .1-.8-.2-.2-.7-.1-.2 .3h-.5l-.4-.3a.41 .41 0 0 0 .1-.5 .41 .41 0 0 0-.5-.2l-.2 .3 .2 .3-.3 .4h-14.7l.4-.4v-1.5h16.1l.1 .4 .3 .2h.8l.4-.3h4.3l.1 .4 .3 .2h.8a.53 .53 0 0 0 .5-.5 .53 .53 0 0 0-.5-.5h-.8l-.4 .4h-4.3a.52 .52 0 0 0-.4-.8l-.9 .1-.3 .4h-16.1l-1-1.1v-.6l.3-.3v-.7h.6v.7l.3 .2a.38 .38 0 0 0 0 .5 .38 .38 0 0 0 .5 0 .38 .38 0 0 0 0-.5l.3-.3v-.7l-.2-.1-.6-.1-.3 .3h-.6l-.2-.3h-.6l-.6-.5v-.2h-1v.6l.9 .1 .5 .4v.6l.3 .3v.8l.9 1v1.2l-3.7 3.9v6.4l-.4 .3h-5v-8.8l-2.1-2.1h4.7l.2 .2h.7l.2-.1 .1-.3h-.5v.4h-.2v-.4h-.5v.2h-4.7l-.5-.5h5.2v.2h1.2l-.1-.4-.4-.1v.5h-.2v-.5l-.4 .1-.1 .2h-5.2l-2-2h-5a.39 .39 0 0 0 .5-.3 .39 .39 0 0 0-.3-.5l-.4-.2h-.7l-.3 .3-.3 .1-.1-.5h-.9a.32 .32 0 0 0 0 .5v.2h-.3l-.2-.7-2.2 .1v2.2l.1 .2-.2 .3v.8l.4 .1 .2-.1 .5 .2-4 4h-14.3a.35 .35 0 0 0-.6 .2h-1.3v-1.3h2.1a.37 .37 0 0 0 .3 .3 .37 .37 0 0 0 .4-.1h12.4a.36 .36 0 0 0 .6 0 .36 .36 0 0 0-.1-.5 .36 .36 0 0 0-.5 .1h-12.4a.35 .35 0 0 0-.4-.1 .35 .35 0 0 0-.3 .3h-2.1v-3l2.3-2.4h10.5a.36 .36 0 0 0 .5 .1 .36 .36 0 0 0 0-.6 .36 .36 0 0 0-.5 .1h-10.7l-2.6 2.6v9.6l-.6 .1v1.4l.6 .1v1.6l-.3 .3h-.5l-.4-.3v-.4l.3-.3v-.5l-.2-.2h-.7l-.3 .2h-3.3a3.3 3.3 0 0 0-3.6-.9 3.3 3.3 0 0 0-2.2 2.9h-.6v-3.1h9.7l.3 .2h.7l.2-.2v-.2h-.5v.4h-.1v-.4h-.6v.2h-9.7v-.5h9.7v.2h1.2v-.4l-.3-.1h-.2v.5h-.1v-.5l-.4 .1-.2 .2h-9.7v-12.2h1v.6l.4 .3h1.7a.63 .63 0 0 0 .6-.6 .63 .63 0 0 0-.6-.7h-.3l.1-.3h24.1l.1 .7 .1 .1 .8 .1a.58 .58 0 0 1 .9 0h.2v-1.2h-.3a.5 .5 0 0 1-.4 .3 .5 .5 0 0 1-.4-.3h-.7l-.3 .3h-24.1l-.1-.2 .3-.1 .1-.5h4.2a.36 .36 0 0 0 .5-.1 .36 .36 0 0 0-.1-.5 .36 .36 0 0 0-.5 .1h-3.2a.39 .39 0 0 0-.1-.5 .39 .39 0 0 0-.5 0h-.3v-1h3.6l.3 .1 .4-.4 .7 .6h.5l.1-.2v-.4l.6-.5v-.4h.4v1.3l.2 .2 1.3-.1 .4-.4h9.9l.2-.1h5.3v.6a.51 .51 0 0 1 0 .9v.6l.2 .3h.8l.3-.4h.2l.3 .4h.7l.2-.3h.2l.3 .3-.1 .3v.3h-.4l-.3-.2h-.3v1.2h.3l.3-.2h.4v.4l.1 .2-.1 .1v.4l1 .1 .1-.2-.2-.4 .2-.3v-1.4l-.6-.6h.7l.2 .2v-.5h-.2v.3h-.7l-.5-.4-.4-.1-.1-.2h1.7v.3h.2v-.5l-.2 .2-2.6-.1a.32 .32 0 0 1-.5 .2 .58 .58 0 0 1 0-1l.3-.1 .3 .3 1.3-.1 .3 .3h.7l.2-.3v-.2h-.5v.5h-.2v-.5h-.5v.2h-.5l.1-.3h-.5v.4h-.2v-.4h-.5v.1h-.3v-.4h.3v.1h1.2l-.1-.3-.2-.1h-.2v.4h-.2v-.4h-.4l-.1 .3h-.3l-.2-.3h-.7l-.3 .3h-5.3l1.5-1.5h6.9v.6a.5 .5 0 0 1 .3 .5 .5 .5 0 0 1-.3 .4v.3h1.2l-.1-.4-.2-.2v-.3l.3-.3v-.6l-.1-.2-.9-.1-.2 .3h-6.9l6.4-6.3h20.6l1.4 1.3 .1 1.9-.3 .2-2.4-2.5-11.7 .1-5.1 5v2.6l-.2 .6-.3-.2v1.1l.2-.2 .3 .2 .4-.1a.32 .32 0 0 0 .6 0l.5 .1 .1-.4h11.3v.6l.4 .3a.39 .39 0 0 0 .4 .5 .39 .39 0 0 0 .2-.6l.2-.3h1.7l.1 .8h.9l.2 .1v.3l-.4 .3 .1 .7 .2 .1h.7l.1-.1 .1-.7-.3-.3 .3-.4 .2 .1v-1.1l-3.9 .2v-.6l-.3-.2h-.6l-.3 .3h-11.3v-.6l-.4-.1-.2 .2-.3-.5h12.2l.2 .2 .4 .1v-.5h-.6v.2l-12.2-.1v-.4h12.2v.2h.6v-.6l-.4 .1-.2 .3h-12.2v-1.8l2-2h8.8v.6l.2 .2 .1 .4-.3 .3v.6l.2 .3h.6l.6 .5h.6l.4 .5h-.3v1.2l.4-.1 .6-.5v1.3l.2 .2 .8-.1 .1-1h.4l.1 .8h2.2l.3 .3-.4 .2-.2-.1v1.1l.2-.1v.3a.39 .39 0 0 0 .5 .4 .39 .39 0 0 0 .2-.6l.3-.1 .2 .3-.4 .4 .1 .7 .3 .5-.3 .2v.8l.1 .1h.9l.1-.1v-.7h.4v.7l.3 .2h.6l.3-.3a.39 .39 0 0 0 .5-.3 .39 .39 0 0 0-.5-.3l-.3-.3h-.6l-.3 .3h-.4l-.3-.3v-.3l.2-.3h.6l.3 .3h.5l.2-.2v-.3h-.4v.5h-.1v-.5h-.5v.2h-.6v-.6h.6v.2h1v-.3l-.2-.2h-.2v.5h-.1v-.5l-.4 .1-.1 .2h-.6l-.3-.3v-.3l.4-.1 .1-.2a.37 .37 0 0 0 .5 0 .37 .37 0 0 0 0-.5 .37 .37 0 0 0-.5 0l-.2-.3h-.9l-.2-.4 .9-.1v-3.5h.5v.3v2.7h1v-.2l.3-.1h1.7l.7 .7h8.6a.4 .4 0 0 0 .5 .3 .4 .4 0 0 0 .3-.4l.5 .4 .6 .1h.5v-.5a.39 .39 0 0 0 .6-.3 .39 .39 0 0 0-.6-.4l-.1-.5-.6 .1a.38 .38 0 0 0-.6 .2 .38 .38 0 0 0 .4 .4v.5l-.7-.7h-9.1l-.7-.6h-2l-.1-.1 .9-.1 1.3-1.3 .7-.1 .1-.2v-.6l.2-.1 .1 1.5 .3 .1a.39 .39 0 0 0 .4 .5 .39 .39 0 0 0 .4-.5l.3-.1 .1-1.5h.2l.1 1.5h1.2l.1-.5 .4-.2 .3 .2 .8-.1 .1-.2v-.6l-.3-.3v-.3l.3-.3v-.4h1.4v1.8l.2 .2h.5l.1-.2v-1.8h.4l.1 1.8 .1 .2h.4l.3-.2v-1.8l-.2-.2 .1-.3h3.2v.6l.1 .2 .8 .1 .3-.3v-.6l-.3-.3a.39 .39 0 0 0-.3-.5 .39 .39 0 0 0-.3 .5l-.3 .3h-3.2a.37 .37 0 0 0-.5-.3 .37 .37 0 0 0-.1 .6l-.2 .2h-.4l-.2-.2h-.5l-.1 .2h-1.4l-.1-.5h-.9l-.2 .2v.6l.3 .3v.4l-.6 .6-.1-.5-.5-.1 .1-.4 .4-.1v-1.5l-1.3-.1-.1 .1v1.4l.3 .2v.3l-.3-.2h-1.9l-.5 .4h-.6l-.2 .2-.1-.7 .2-.2 .9 .1 .4-.3 .2 .3h1.3v-1.5l-.5-.2 .1-.3 .3-.2v-.7h.4v.7l.1 .2h.8l.3-.3-.1-.6-.2-.3a.39 .39 0 0 0-.3-.5 .39 .39 0 0 0-.4 .5l-.2 .3h-.4l-.3-.3h-.6l-.2 .2v.8l.3 .2v.4h-.5v.5l-.3 .3-.3-.3-.7 .1-.1 .1-.1 .3-.5 .6v1.1l-1 1h-.2l.8-1v-1.6l.6-.6 .1-.3 .3-.2v-.8a.5 .5 0 0 1-.3-.4 .5 .5 0 0 1 .3-.4v-.7l-.1-.2-.8-.1-.2 .2-.1 .8 .3 .2v.4l-.3 .2v.6l.4 .5-.6 .6-.5-.4v-.3l.4-.3v-.6l-.3-.3v-.5l.3-.2-.1-.7-.2-.2-.8 .1-.1 .2v.6a.72 .72 0 0 1 .2 .8l-.2 .2v.6l.4 .3v.5l.5 .5v1.3l-.2 .1-.1-.1h-1v.3h-.5l-.1-.4h-3.7l-.2 2.8h-.3v-.5l-.1-.1 .1-2.3h5.8l-.1-.2h-.3v.2h-.2v-.2l-.3 .1-.1 .1h-4.8v-.3l-.3-.1v-.8h.4v.7l.1 .2h2.1v-1.1h-2l-.2 .2h-.4l.1-.5a.59 .59 0 0 1 .9 0h.6l.2-.1 .1-.8-.2-.2-.7-.1-.3 .3h-.3l-.2-.2-.4-.1v.6l-.6 .1v.4l.3 .2v1.2l-.3 .1-.1 1-.3-.3-.1-.7-.2-.2v-.5l.2-.1 .1-.4h-1.2v.3a.71 .71 0 0 1 .2 .8l-.2 .2 .1 .7 .1 .1 .7 .1 .4 .5-.4 .3-.3-.1h-.5l-.4-.4v-.6l-.3-.3v-.4l.3-.2v-.6l-.3-.3h-.7l-.2 .3h-8.8l.7-.7h9.6v.2h1.2l-.1-.3-.2-.2h-.2v.5h-.2v-.5l-.4 .1-.1 .2h-9.6l.8-.8h10.4v.3h.5v-.6l-.4 .1-.1 .2h-10.4l1.3-1.2h11l1.9 1.8-.1 .7-.2-.1v1.1l2.2-.1v-1.7a.43 .43 0 0 0 .2-.5 .43 .43 0 0 0-.3-.3l-.1-1.6-1.1-1.1h6.2v.7l.1 .1h.9a.46 .46 0 0 1 .8 .1h.6l.3-.2v-.3h-.5v.5h-.2v-.7l2.1-.1 .1 .7 .3 .2-.1 .5-.3 .2v.6l.2 .2h.8l.2-.2v-.5l-.3-.3-.1-.6 .3-.1 .1-.2h.5l.1 .8h.7l.1-.2v-1.7h.4l.1 1.8 .1 .1h.5l.2-.2v-1.7h.4v1.7l.2 .3v1.1a.36 .36 0 0 0 0 .5 .36 .36 0 0 0 .5 0 .36 .36 0 0 0 0-.5v-1.1l.2-.3v-1.7h.4v1.7l.2 .3v.2a.36 .36 0 0 0 0 .6 .36 .36 0 0 0 .5-.1 .36 .36 0 0 0-.1-.5l.2-.5v-1.7l-.2-.3-.5 .1-.1 .2h-.4l-.3-.3-.4 .1-.2 .2h-.4l-.3-.3-.4 .1-.2 .2h-.4l-.1-.2-.5-.1-.2 .2v.7h-.5l-.4-.3-.7 .1-.2 .2h-1.4l-.2-.3-.3-.1v.5h-.2v-.5l-.3 .1-.2 .2h-.4l-.2-.3h-.6l-.3 .3h-6.2l-.7-.7h-21.2l-8 8h-9.7l-.4-.4-1.3-.1-.2 .2h-.4l.1-2.2 4.3-4.3h11.2a.36 .36 0 0 0 .5 .3 .36 .36 0 0 0 .1-.6v-1.7h31.9v.7l.2 .2h.7l.2-.3h.4l.3 .3h.6l.3-.2v-.3h-.5v.5h-.2v-.7h.7l-.1-.4-.2-.1h-.2v.5h-.2v-.5h-.2l-.3 .3h-.4l-.2-.3h-.7l-.2 .3h-31.9v-2.6l1.8-1.7a.36 .36 0 0 0 .4-.4 .36 .36 0 0 0-.4-.4 .36 .36 0 0 0-.4 .4l-1.8 2v4.4l-.2 .3h-11.2l4.5-4.6 .1-.6 .3-.4-.1-.7-.2-.3 .4-.4v-.5h.4a.36 .36 0 0 0 .5 0 .36 .36 0 0 0 0-.5 .36 .36 0 0 0-.5 0h-.4v-.4l-.2-.2-.6 .1v1.6l-.2 .4a.62 .62 0 0 1-.8 .2l-.3-.3 .2-.5v-1.3l-.2-.2h-.5l-.2 .3v1.2l.2 .5-.2 .3v.8l.2 .2h.5l.3-.3h.6l.3 .3v.5l-8.9 8.9v2.6l-.2 .1-.1-.5h-.4a.49 .49 0 0 0-.6 0 .49 .49 0 0 0-.2 .5l-2.1-.1 10-10.1v-5.1a.36 .36 0 0 0 .1-.5 .36 .36 0 0 0-.6 0 .36 .36 0 0 0 .1 .5v4.9l-9.8 9.8h-.6l7.1-7.2v-4.9l.4-.3v-1.1h.6v1l.1 .3h1l.2-.3-.1-1.1-.4-.4 .4-.3v-.6l.4-.2 .3-.5h2.3l.2 .6 .5 .1 .2-.2v-.7h3.7l.1 .3v5.8a.36 .36 0 0 0 0 .6 .36 .36 0 0 0 .5-.1 .36 .36 0 0 0 0-.5v-5.8a.35 .35 0 0 0-.1-.6 .35 .35 0 0 0-.5 .3h-3.7v-.7l-.2-.2-.5 .1-.2 .6h-2.3a1 1 0 0 0-1.7-.5 1 1 0 0 0 .5 1.7l-.3 1h-.3l-.1 .3h-.6l-.3-.3-.1-.6-.3-.4 .7-.1v-1.8h-1.9v1.8l.7 .1v.2l.4 .4v.4h-.3l-.2 .3 .1 1.1 .4 .3v4.7l-6.9 6.9h-.4l1.4-1.4a.36 .36 0 0 0 .4-.4 .36 .36 0 0 0-.4-.4 .36 .36 0 0 0-.4 .4l-1.2 1.3h-.4l.9-.9a.36 .36 0 0 0 .3-.4 .36 .36 0 0 0-.4-.4 .36 .36 0 0 0-.3 .4l-.7 .7-.1-.4-.3-.1v-.5a.66 .66 0 0 0 .7-.2 .66 .66 0 0 0 .1-.8l-.5-.3h-1.6a.72 .72 0 0 0-.6 .9h-.9v-16.2h.6a3.3 3.3 0 0 0 2.7 3.5 3.3 3.3 0 0 0 3.8-2.2h10.7a.37 .37 0 0 0 .6 .3h5v.3l-.6-.1-.3 .1h-2.4a.38 .38 0 0 0-.6 .1 .38 .38 0 0 0 .1 .5 .36 .36 0 0 0 .1 .5 .36 .36 0 0 0 .5-.1h2.8l.2-.1h1a.39 .39 0 0 0 0 .5 .39 .39 0 0 0 .6 0 .39 .39 0 0 0 0-.5h.9a.37 .37 0 0 0 .3 .3 .37 .37 0 0 0 .4-.1h.7l1.6 1.5 1.2 .1 .3-.2a.39 .39 0 0 0 .5-.3 .39 .39 0 0 0-.4-.5l-.2-.1v-.4l-.1-.2-1.6 .1-.4-.4h2.5l.1 .8 .5 .6v.6h.6l.9 .8h.6l.1-.1 .1-.8h.6v.7l.2 .2h.6l.3-.4h.8l.7 .6h5.4l.6-.5v-.3l.3-.1v-.7h4.4a1.13 1.13 0 0 0 .8 1.1v4.4a.36 .36 0 0 0 0 .6 .36 .36 0 0 0 .5 0h.4l.3 .3h.6l.4-.3 .2-.1 .4 .2h1.1l.2-.2v-.5l-.2-.1-1.1-.1-.6 .3-.1-.2a.45 .45 0 0 1 0-.8v-.7l-.3-.2h-.6l-.2 .1v.8a.54 .54 0 0 1 0 .9h-.6v-1.8h2.1v.4l.3 .2h1.1l.2-.2h.4v1.5l.5 .6 1.3-.1 .1-.5-.3-.3 .2-.1a.4 .4 0 0 0 .6-.4 .4 .4 0 0 0-.6-.3l-.2-.2 .3-.2v-.2h1v.5a.66 .66 0 0 1 0 1v.6l.3 .2h.7l.2-.3h.5l.1 .3 .2 .2h.5l.1-.3h1.1l.2 .3h.5l.1-.2 .1-.5h-.4v.7h-.1v-.7h-.4v.4h-1.1v-1h1.1v.4h.9l-.1-.5-.1-.2h-.2v.7h-.1v-.7l-.3 .1-.1 .2h-1.1l-.1-.3h-.5l-.2 .2v.4l-.5 .1-.1-.3a.45 .45 0 0 1 0-.7v-.7l-.2-.2h-.7l-.3 .3h-1l-.1-.4-.5-.1v-1.3l.7-.7h5l-.2 .3v.8l-.3 .3-.1-.2a.39 .39 0 0 0-.3-.6 .39 .39 0 0 0-.4 .6l-.1 .2-.3-.3-.4 .1-.2 .1v1.2l.6 .5h1.5l.6-.4 .1-1.2-.2-.3v-.6l.4-.5h7.8l1.9 1.9v9.8l-.5 .6h-.7l-.2 .2v.7l.4 .2v.7l.2 .4h-1.9l-.7-.7 .5-.1a.54 .54 0 0 0 .7 .6 .54 .54 0 0 0 .2-.9v-2l-.6-.1-.2 .2v1.9l-.1 .3h-.5l.2-.4-.1-1.8-.2-.2-.5 .1-.1 1.9 .2 .2v.5l.9 1h2.2l.3 .1 .9-.1v.6l-1.4-.3-.5 .1v1.5l.2 .1h.5a.38 .38 0 0 0 .1 .5 .38 .38 0 0 0 .5 0h.6l.1 1.5h1l.1 .2a.45 .45 0 0 0-.4 .6 .45 .45 0 0 0 .7 .2 .45 .45 0 0 0 0-.8h1.2v-2.8a.41 .41 0 0 0 .5-.2 .41 .41 0 0 0-.1-.5l-.1-.1 1.3-1.3v-2.8h3.2l.1 .4 .3 .1 .8 .1a.53 .53 0 0 0 .5-.6 .53 .53 0 0 0-.5-.5h-.8l-.4 .5h-3.2v-1l.2-.3v-.8l-.2-.2-.7 .1a.59 .59 0 0 1-.7 .1l-.2-.2h-.6l-.2 .3v.7l.1 .1 .7 .1 .2-.3h.6l.3 .4v3.6l-1.1 1.1-.1-1.9h-1l-.4-.2 .4-.4 .1-.5 .3 .2 1-.1a.53 .53 0 0 0 .2-.5 .53 .53 0 0 0-.4-.4h-.9l-.4 .6a.43 .43 0 0 0-.5-.1 .43 .43 0 0 0-.3 .3l.2 .8-.9 .1v1.4h-.6l-.4-.5v-.5l.4-.3v-.7l.6-.5v-10.2l-2.1-2.2h-13.8l-1 1-.1 1.4-.4 .1-.4 .6h-.4v-.5l-.2-.2h-1.1l-.3 .3h-2.1v-2.7a.98 .98 0 0 0 .4-1.7 .98 .98 0 0 0-1.6 .7h-4.4v-1.7l-.9-.1-.1 .1v2.4l.3 .2-.3 .3h-5.2l-.6-.6h-1l-.3-.4h-.6l-.2 .3h-.6l-.2-.3h-.6l-.3 .3-.4-.4 .1-.7 .3 .1 .3 .3h.7l.1-.2v-.7h.6v.7l.2 .2h.6l.3-.3h.3a.36 .36 0 0 0 .6-.1 .36 .36 0 0 0-.1-.5 .36 .36 0 0 0-.5 .1h-.3l-.3-.4h-.6l-.2 .3h-.6l-.2-.3h-.6l-.3 .4h-1.3a.38 .38 0 0 0 0-.6 .38 .38 0 0 0-.5 .2h-2.5l-.5-.5 .2-.1h7.7l1.4 1.3v1.4l.1 .1 .9-.1v-2.4h.3v2.5l1-.1v-2.4h.2l.1 2.4 .9 .1v-2.5h.3v2.4l.9 .1 .1-2.5-.2-.2a.38 .38 0 0 0-.4-.5 .38 .38 0 0 0-.2 .6l-.2 .1-.4-.1h-.7l-.2 .1-.3-.1h-.8l-.1 .1-1.2-.1-.2 .4-1.1-1.1h-2.2v-.3l.3-.2h.5l.3 .2 .6-.1 .1-.6-.3-.1h-.5l-.2 .2-1.3-.2-.2 .1v.5l.3 .3-.2 .2h-7.2v-.3l.3-.1 .2-.2 .7-.1 .2-.1v-.7l.4-.4 .2 .1-.2 .3v.7l.1 .1 .8 .1 .2-.3a.41 .41 0 0 0 .5 0 .41 .41 0 0 0 .1-.5l-.3-.2-.2 .1-.3-.3 2.2-.1 .3 .2 .3-.2h1.6l.2 .2h.5l.3-.1v-.5h.5v.5l.2 .1h.6l.2-.2a.38 .38 0 0 0 .6 0 .38 .38 0 0 0-.1-.5 .38 .38 0 0 0-.5 .1l-.2-.2h-.5l-.3 .2h-.5l-.3-.2v-.4l.2-.2h3.2v2.4l.9 .1 .1-2.5h.3v2.4l.9 .1 .1-.1v-2.4h.2l.1 2.5a.43 .43 0 0 0 .2 .5 .43 .43 0 0 0 .5-.1l.2-.5 .1-1 .2 .1v1l1-.1-.1-2.5h-.9v1.1l-.3-.1v-.9l-.1-.1h-.7l-.2 .1-.3-.1h-.8l-.1 .1-.4-.1-4.1 .1 .4-.4h8l.2 .2-.3 .2 .1 2.5h.8l.1-1.1h3.3l1.3 1.2a.99 .99 0 0 0 .6 1.5 .99 .99 0 0 0 1.2-1.2 .99 .99 0 0 0-1.5-.6l-.7-.7h25.5v.4a3.3 3.3 0 0 0 5 2.7 3.3 3.3 0 0 0 0-5.8 3.3 3.3 0 0 0-5 2.7h-25.5l-.7-.6h-3.5v-1l-.3-.3h4.7v.8h.5v.2h-.5l.1 .8 .8 .1v-.5h.2v.5h.8l.1-.1v-.8h-.5v-.2h.5l-.1-.8-.8-.1v.5h-.2v-.5h-.8l-.1 .1h-4.7l-.5-.5h-8.2l-.9 .8v.5l-.3 .3h-1.6l-.3-.2-.3 .2h-2.4l.2-.6a.39 .39 0 0 0 .5 0 .39 .39 0 0 0 0-.6 .39 .39 0 0 0-.5 0 .45 .45 0 0 0-.4-.5h-.6l-.2 .1-.1 1.2 .2 .4-.5 .5-.7 .1-.3 .9h-1v-1l-.2-.3v-.3a.51 .51 0 0 0 .4-.6h.2a.48 .48 0 0 0 .4 .6h.7l.2-.3v-1.2l-.2-.1h-.7a.45 .45 0 0 0-.4 .6h-.2l-.1-.5-.2-.1h-.7l-.2 .1-.1 1.3 .4 .2v.5l.3 .3-.1 .6-.4 .1-1-1-.1-.4 .3-.4v-1.2l-.3-.1h-.8l-.1 .3v1.1l.6 .6a.52 .52 0 0 1-.4 .5 .52 .52 0 0 1-.6-.3h-.7l-.2 .3a.39 .39 0 0 0-.6 .1 .39 .39 0 0 0 .1 .5 .39 .39 0 0 0 .5 0l.3 .3h.6l.3-.3h.3l.3 .3h.6l.3-.2 .2 .4h-5a.35 .35 0 0 0-.4-.1 .35 .35 0 0 0-.2 .3h-10.7v-.3a3.3 3.3 0 0 0-2.7-4.1 3.3 3.3 0 0 0-3.8 3.1h-.6v-2.1l.1-.4z" fill-rule="evenodd" fill="#f2f2f2"/>
<g fill="#fff">
<circle cx="227.4" cy="140.9" r=".13"/>
<circle cx="237" cy="142.8" r=".12"/>
<circle cx="232.9" cy="143.3" r=".13"/>
<circle cx="235.6" cy="148.5" r=".12"/>
<circle cx="196.6" cy="127.2" r=".13"/>
<circle cx="222.2" cy="153" r=".12"/>
<circle cx="198.6" cy="146.8" r=".13"/>
<circle cx="207.6" cy="128" r=".12"/>
<circle cx="223.9" cy="135.8" r=".12"/>
<circle cx="178.1" cy="167.5" r=".12"/>
<circle cx="225.8" cy="146.7" r=".13"/>
<circle cx="196.2" cy="150.7" r=".13"/>
<circle cx="218.8" cy="150.9" r=".12"/>
<circle cx="196.4" cy="125.2" r=".13"/>
<circle cx="223.1" cy="141.5" r=".13"/>
<circle cx="198.1" cy="130.9" r=".12"/>
<circle cx="230" cy="140.7" r=".12"/>
<circle cx="217.4" cy="135.9" r=".12"/>
<circle cx="203.3" cy="126.3" r=".13"/>
<circle cx="222.5" cy="135.7" r=".13"/>
<circle cx="226.6" cy="139.7" r=".12"/>
<circle cx="212.2" cy="144.9" r=".13"/>
<circle cx="226.6" cy="138.2" r=".12"/>
<circle cx="170.3" cy="150.4" r=".12"/>
<circle cx="192.3" cy="130" r=".13"/>
<circle cx="229.2" cy="144.6" r=".12"/>
<circle cx="216.1" cy="142.7" r=".13"/>
<circle cx="213.7" cy="150.3" r=".12"/>
<circle cx="224.1" cy="150.9" r=".12"/>
<circle cx="239.5" cy="145.8" r=".13"/>
<circle cx="204.7" cy="150.5" r=".12"/>
<circle cx="221.6" cy="141.5" r=".13"/>
<circle cx="188" cy="127.2" r=".13"/>
<circle cx="219.7" cy="168.4" r=".12"/>
<circle cx="241.4" cy="142.1" r=".12"/>
<circle cx="170.3" cy="143.8" r=".12"/>
<circle cx="226.5" cy="133.3" r=".12"/>
<circle cx="178.8" cy="147.1" r=".12"/>
<circle cx="239.3" cy="154.6" r=".13"/>
<circle cx="227.5" cy="144.5" r=".12"/>
<circle cx="195.5" cy="148.2" r=".12"/>
<circle cx="239.6" cy="151.1" r=".12"/>
<circle cx="194.8" cy="166.7" r=".12"/>
<circle cx="189.6" cy="136.7" r=".13"/>
<circle cx="189.7" cy="130.3" r=".12"/>
<circle cx="189.6" cy="127.2" r=".13"/>
<circle cx="216.1" cy="136.7" r=".13"/>
<circle cx="209" cy="152" r=".12"/>
<circle cx="195.2" cy="133.2" r=".12"/>
<circle cx="195.2" cy="128.6" r=".12"/>
<circle cx="193.2" cy="150.9" r=".12"/>
<circle cx="193.2" cy="139.9" r=".13"/>
<circle cx="233.3" cy="148.9" r=".12"/>
<circle cx="234.3" cy="147.9" r=".12"/>
<circle cx="187.7" cy="129.7" r=".13"/>
<circle cx="173.2" cy="143.8" r=".13"/>
<circle cx="190.6" cy="129" r=".13"/>
<circle cx="172.1" cy="143.8" r=".12"/>
<circle cx="187.6" cy="129" r=".13"/>
<circle cx="187.3" cy="132.2" r=".13"/>
<circle cx="201.5" cy="164.6" r=".13"/>
<circle cx="235.4" cy="146.1" r=".2"/>
<circle cx="237.3" cy="147.1" r=".13"/>
<circle cx="237.3" cy="148.5" r=".12"/>
<circle cx="220.8" cy="150" r=".12"/>
<circle cx="237.3" cy="149.6" r=".12"/>
<circle cx="183" cy="131.1" r=".12"/>
<circle cx="185.9" cy="128.2" r=".13"/>
<circle cx="220.3" cy="142.5" r=".12"/>
<circle cx="219.7" cy="143.1" r=".12"/>
<circle cx="213.7" cy="144.3" r=".13"/>
<circle cx="235.4" cy="141.4" r=".12"/>
<circle cx="171.5" cy="148.9" r=".13"/>
<circle cx="181.8" cy="157.9" r=".12"/>
<circle cx="175.4" cy="149.3" r=".12"/>
<circle cx="195.6" cy="156.5" r=".13"/>
<circle cx="182.6" cy="156.5" r=".12"/>
<circle cx="205.4" cy="151.2" r=".12"/>
<circle cx="198.6" cy="126.3" r=".13"/>
<circle cx="198.6" cy="129.5" r=".13"/>
<circle cx="195.6" cy="165.5" r=".13"/>
<circle cx="185.1" cy="134" r=".12"/>
<circle cx="200.7" cy="168.4" r=".12"/>
<circle cx="194.4" cy="129.2" r=".13"/>
<circle cx="193.9" cy="129.7" r=".12"/>
<circle cx="234.1" cy="142.3" r=".12"/>
<circle cx="214.4" cy="146.6" r=".13"/>
<circle cx="203.5" cy="130.1" r=".12"/>
<circle cx="208.9" cy="128.8" r=".13"/>
<circle cx="238.5" cy="153.6" r=".13"/>
<circle cx="239.4" cy="149.1" r=".12"/>
<circle cx="238" cy="148.6" r=".12"/>
<circle cx="241.1" cy="148.3" r=".13"/>
<circle cx="174.9" cy="147.3" r=".12"/>
<circle cx="175.7" cy="146.5" r=".13"/>
<circle cx="241.3" cy="167.1" r=".25"/>
<circle cx="242" cy="165.4" r=".25"/>
<circle cx="242" cy="168.8" r=".25"/>
<circle cx="243.7" cy="164.7" r=".25"/>
<circle cx="243.7" cy="167.1" r="1.6"/>
<circle cx="243.7" cy="169.5" r=".25"/>
<circle cx="245.4" cy="165.4" r=".25"/>
<circle cx="245.4" cy="168.8" r=".25"/>
<circle cx="246.1" cy="167.1" r=".25"/>
<circle cx="239.4" cy="151.9" r=".33"/>
</g>
<path d="M239.4 144.6v.3" fill="none" stroke="#fff" stroke-width=".65"/>
<path d="M240.3 152.4h.6M240.3 144.2h.6M246.3 152.8h.6M246.3 143.8h.6" fill="none" stroke="#fff" stroke-width=".5"/>
<g fill="#fff">
<circle cx="178.9" cy="130.3" r=".5"/>
<circle cx="181.5" cy="130.3" r=".5"/>
<circle cx="213.9" cy="168.2" r=".5"/>
<circle cx="211.4" cy="168.2" r=".5"/>
<circle cx="208.8" cy="168.2" r=".5"/>
<circle cx="241.3" cy="127.1" r=".25"/>
<circle cx="242" cy="125.4" r=".25"/>
<circle cx="242" cy="128.8" r=".25"/>
<circle cx="243.7" cy="124.7" r=".25"/>
<circle cx="243.7" cy="127.1" r="1.6"/>
<circle cx="243.7" cy="129.5" r=".25"/>
<circle cx="245.4" cy="125.4" r=".25"/>
<circle cx="245.4" cy="128.8" r=".25"/>
<circle cx="246.1" cy="127.1" r=".25"/>
<circle cx="169.3" cy="167.1" r=".25"/>
<circle cx="170" cy="165.4" r=".25"/>
<circle cx="170" cy="168.8" r=".25"/>
<circle cx="171.7" cy="164.7" r=".25"/>
<circle cx="171.7" cy="167.1" r="1.6"/>
<circle cx="171.7" cy="169.5" r=".25"/>
<circle cx="173.4" cy="165.4" r=".25"/>
<circle cx="173.4" cy="168.8" r=".25"/>
<circle cx="174.1" cy="167.1" r=".25"/>
<circle cx="192.6" cy="167.3" r=".45"/>
<circle cx="195.6" cy="167.3" r=".45"/>
</g>
<path d="M169.3 142.8h1.6M169.3 151.4h1.6" fill="none" stroke="#fff" stroke-width=".5"/>
<g fill="#fff">
<circle cx="216.1" cy="125.9" r=".5"/>
<circle cx="216.1" cy="128.4" r=".5"/>
<circle cx="216.1" cy="131" r=".5"/>
<circle cx="169.3" cy="127.1" r=".25"/>
<circle cx="170" cy="125.4" r=".25"/>
<circle cx="170" cy="128.8" r=".25"/>
<circle cx="171.7" cy="124.7" r=".25"/>
<circle cx="171.7" cy="127.1" r="1.6"/>
<circle cx="171.7" cy="129.5" r=".25"/>
<circle cx="173.4" cy="125.4" r=".25"/>
<circle cx="173.4" cy="128.8" r=".25"/>
<circle cx="174.1" cy="127.1" r=".25"/>
</g>
<g fill="#e2e2e2">
<path d="M202 151.9h.8v.2h-.8z" fill-rule="evenodd"/>
<path d="M202 151.2h.8v.3h-.8z" fill-rule="evenodd"/>
<path d="M202 150.6h.8v.2h-.8z" fill-rule="evenodd"/>
<path d="M202 149.9h.8v.3h-.8z" fill-rule="evenodd"/>
<path d="M201.3 148.7h.3v.8h-.3z" fill-rule="evenodd"/>
<path d="M200.7 148.7h.2v.8h-.2z" fill-rule="evenodd"/>
<path d="M200 148.7h.3v.8h-.3z" fill-rule="evenodd"/>
<path d="M199.4 148.7h.2v.8h-.2z" fill-rule="evenodd"/>
<path d="M198.1 149.9h.8v.3h-.8z" fill-rule="evenodd"/>
<path d="M198.1 150.6h.8v.2h-.8z" fill-rule="evenodd"/>
<path d="M198.1 151.2h.8v.3h-.8z" fill-rule="evenodd"/>
<path d="M198.1 151.9h.8v.2h-.8z" fill-rule="evenodd"/>
<path d="M199.4 152.6h.2v.8h-.2z" fill-rule="evenodd"/>
<path d="M200 152.6h.3v.8h-.3z" fill-rule="evenodd"/>
<path d="M200.7 152.6h.2v.8h-.2z" fill-rule="evenodd"/>
<path d="M201.3 152.6h.3v.8h-.3z" fill-rule="evenodd"/>
<path d="M199.4 150h2.1v2.1h-2.1z" fill-rule="evenodd"/>
<path d="M202.2 127.4h.6v.6h-.6z" fill-rule="evenodd"/>
<path d="M202.2 126h.6v.6h-.6z" fill-rule="evenodd"/>
<path d="M219.3 165.9h.8v.7h-.8z" fill-rule="evenodd"/>
<path d="M219.3 164.2h.8v.7h-.8z" fill-rule="evenodd"/>
<path d="M227.2 133.6l.5 .1-.1 1.2-.5-.1z" fill-rule="evenodd"/>
<path d="M226.2 133.6l.6 .1-.1 1.2-.5-.1z" fill-rule="evenodd"/>
<path d="M225.3 133.6l.5 .1-.1 1.2-.5-.1z" fill-rule="evenodd"/>
<path d="M225.3 135.9h.5l-.1 1.3-.5-.1z" fill-rule="evenodd"/>
<path d="M227.2 135.9h.5l-.1 1.3-.5-.1z" fill-rule="evenodd"/>
<path d="M203.5 151.6h.8v.8h-.8z" fill-rule="evenodd"/>
<path d="M203.5 150.1h.8v.8h-.8z" fill-rule="evenodd"/>
<path d="M219.5 152.6h.7v.8h-.7z" fill-rule="evenodd"/>
<path d="M221 152.6h.8v.8h-.8z" fill-rule="evenodd"/>
<path d="M241.9 141.7h.7v.8h-.7z" fill-rule="evenodd"/>
<path d="M240.2 141.7h.7v.8h-.7z" fill-rule="evenodd"/>
</g>
<g fill="#e2e2e2">
<circle cx="241.3" cy="167.1" r=".4"/>
<circle cx="242" cy="165.4" r=".4"/>
<circle cx="242" cy="168.8" r=".4"/>
<circle cx="243.7" cy="164.7" r=".4"/>
<circle cx="243.7" cy="167.1" r="3.2"/>
<circle cx="243.7" cy="169.5" r=".4"/>
<circle cx="245.4" cy="165.4" r=".4"/>
<circle cx="245.4" cy="168.8" r=".4"/>
<circle cx="246.1" cy="167.1" r=".4"/>
<circle cx="239.4" cy="151.9" r=".33"/>
</g>
<path d="M239.4 144.6v.3" fill="none" stroke="#e2e2e2" stroke-width=".65"/>
<g fill="#e2e2e2">
<path d="M238.4 150.9h.7v.3h-.7z" fill-rule="evenodd"/>
<path d="M238.4 150.4h.7v.3h-.7z" fill-rule="evenodd"/>
<path d="M238.4 149.9h.7v.3h-.7z" fill-rule="evenodd"/>
<path d="M238.4 149.4h.7v.3h-.7z" fill-rule="evenodd"/>
<path d="M238.4 148.9h.7v.3h-.7z" fill-rule="evenodd"/>
<path d="M238.4 148.4h.7v.3h-.7z" fill-rule="evenodd"/>
<path d="M238.4 147.9h.7v.3h-.7z" fill-rule="evenodd"/>
<path d="M238.4 147.4h.7v.3h-.7z" fill-rule="evenodd"/>
<path d="M238.4 146.9h.7v.3h-.7z" fill-rule="evenodd"/>
<path d="M238.4 146.4h.7v.3h-.7z" fill-rule="evenodd"/>
<path d="M238.4 145.9h.7v.3h-.7z" fill-rule="evenodd"/>
<path d="M238.4 145.4h.7v.3h-.7z" fill-rule="evenodd"/>
<path d="M240.1 145.7h.7v.3h-.7z" fill-rule="evenodd"/>
<path d="M240.1 146.2h.7v.3h-.7z" fill-rule="evenodd"/>
<path d="M240.1 146.7h.7v.3h-.7z" fill-rule="evenodd"/>
<path d="M240.1 147.2h.7v.3h-.7z" fill-rule="evenodd"/>
<path d="M240.1 147.7h.7v.3h-.7z" fill-rule="evenodd"/>
<path d="M240.1 148.2h.7v.3h-.7z" fill-rule="evenodd"/>
<path d="M240.1 148.7h.7v.3h-.7z" fill-rule="evenodd"/>
<path d="M240.1 149.2h.7v.3h-.7z" fill-rule="evenodd"/>
<path d="M240.1 149.7h.7v.3h-.7z" fill-rule="evenodd"/>
<path d="M240.1 150.2h.7v.3h-.7z" fill-rule="evenodd"/>
<path d="M240.1 150.7h.7v.3h-.7z" fill-rule="evenodd"/>
<path d="M240.1 151.2h.7v.3h-.7z" fill-rule="evenodd"/>
</g>
<path d="M240.3 152.4h.6M240.3 144.2h.6M246.3 152.8h.6M246.3 143.8h.6" fill="none" stroke="#e2e2e2" stroke-width=".8"/>
<g fill="#e2e2e2">
<path d="M239.8 154.2h.7v.8h-.7z" fill-rule="evenodd"/>
<path d="M238.1 154.2h.7v.8h-.7z" fill-rule="evenodd"/>
<path d="M200.3 165.9h.8v.7h-.8z" fill-rule="evenodd"/>
<path d="M200.3 164.2h.8v.7h-.8z" fill-rule="evenodd"/>
<path d="M216.9 152.8h.8v.7h-.8z" fill-rule="evenodd"/>
<path d="M216.9 151.1h.8v.7h-.8z" fill-rule="evenodd"/>
<path d="M178.1 129.4h1.7v1.7h-1.7z" fill-rule="evenodd"/>
<path d="M222.7 141.9h.8v.8h-.8z" fill-rule="evenodd"/>
<path d="M222.7 140.3h.8v.8h-.8z" fill-rule="evenodd"/>
<path d="M180.7 132.5l.7-.1 .2 .2v.9l-.1 .3h-.7l-.2-.2z" fill-rule="evenodd"/>
<path d="M178.8 132.5l.8-.1 .2 .2v.9l-.2 .3h-.6l-.2-.2z" fill-rule="evenodd"/>
<path d="M193.2 124.6l.7-.1 .2 .2v.9l-.1 .3h-.7l-.2-.2z" fill-rule="evenodd"/>
<path d="M195 124.6l.7-.1 .2 .2v.9l-.1 .3h-.6l-.3-.2z" fill-rule="evenodd"/>
<path d="M235.1 138.8l.6 .1-.1 1.8-.5-.1z" fill-rule="evenodd"/>
<path d="M233.9 138.8l.5 .1-.1 1.8-.5-.1z" fill-rule="evenodd"/>
<path d="M232.6 138.8l.6 .1-.1 1.8-.5-.1z" fill-rule="evenodd"/>
<path d="M231.3 138.8l.6 .1-.1 1.8-.5-.1z" fill-rule="evenodd"/>
<path d="M231.3 143.8h.6l-.1 1.9-.5-.1z" fill-rule="evenodd"/>
<path d="M232.6 143.8h.6l-.1 1.9-.5-.1z" fill-rule="evenodd"/>
<path d="M233.9 143.8h.5l-.1 1.9-.5-.1z" fill-rule="evenodd"/>
<path d="M235.1 143.8h.6l-.1 1.9-.5-.1z" fill-rule="evenodd"/>
<path d="M223.5 136.2h.8v.8h-.8z" fill-rule="evenodd"/>
<path d="M223.5 134.6h.8v.8h-.8z" fill-rule="evenodd"/>
<path d="M213.1 167.4h1.6v1.6h-1.6z" fill-rule="evenodd"/>
<path d="M183.9 133.6h.7v.8h-.7z" fill-rule="evenodd"/>
<path d="M185.6 133.6h.7v.8h-.7z" fill-rule="evenodd"/>
<path d="M179.1 163h1.5v1.4h-1.5z" fill-rule="evenodd"/>
<path d="M179.1 167.6h1.5v1.2h-1.5z" fill-rule="evenodd"/>
<path d="M187 163h1.6v1.4h-1.6z" fill-rule="evenodd"/>
<path d="M187 167.6h1.6v1.2h-1.6z" fill-rule="evenodd"/>
<path d="M200.3 129.7h.7v.8h-.7z" fill-rule="evenodd"/>
<path d="M202 129.7h.7v.8h-.7z" fill-rule="evenodd"/>
<path d="M213.2 147.5h.8v.8h-.8z" fill-rule="evenodd"/>
<path d="M213.2 149.1h.8v.8h-.8z" fill-rule="evenodd"/>
<path d="M200.7 126h.6v.6h-.6z" fill-rule="evenodd"/>
<path d="M200.7 127.4h.6v.6h-.6z" fill-rule="evenodd"/>
<path d="M229.6 139.4h.8v.7h-.8z" fill-rule="evenodd"/>
<path d="M229.6 141.1h.8v.7h-.8z" fill-rule="evenodd"/>
<path d="M177.7 147.4h.4l.1 .3-.5 .1z" fill-rule="evenodd"/>
<path d="M177.7 146.9h.6v.3h-.6z" fill-rule="evenodd"/>
<path d="M177.7 146.4h.5v.3h-.5z" fill-rule="evenodd"/>
<path d="M176 146.4h.5v.3h-.5z" fill-rule="evenodd"/>
<path d="M175.9 146.9h.5l.1 .3h-.6z" fill-rule="evenodd"/>
<path d="M176 147.4h.4l.1 .3-.5 .1z" fill-rule="evenodd"/>
<path d="M184 131.5h.5v1.4l-.5-.1z" fill-rule="evenodd"/>
<path d="M185.9 131.5h.5v1.4l-.5-.1z" fill-rule="evenodd"/>
<path d="M184.9 129.6l.6 .1-.1 1.3-.5-.1z" fill-rule="evenodd"/>
<path d="M211.8 145.3h.8v.8h-.8z" fill-rule="evenodd"/>
<path d="M211.8 143.8h.8v.7h-.8z" fill-rule="evenodd"/>
<path d="M197.3 130l.4-.1 .1 .4h-.4z" fill-rule="evenodd"/>
<path d="M197.2 130.5h.6v.3h-.6z" fill-rule="evenodd"/>
<path d="M197.3 131h.4l.1 .3-.4 .1z" fill-rule="evenodd"/>
<path d="M199 131h.4l.1 .3-.4 .1z" fill-rule="evenodd"/>
<path d="M199 130.5h.6v.3h-.6z" fill-rule="evenodd"/>
<path d="M199 130l.4-.1 .1 .4h-.4z" fill-rule="evenodd"/>
<path d="M196.6 147.2h.8v.6h-.8z" fill-rule="evenodd"/>
<path d="M196.6 148.8h.8v.7h-.8z" fill-rule="evenodd"/>
<path d="M213.3 143.1h.8v.7h-.8z" fill-rule="evenodd"/>
<path d="M213.3 144.8h.8v.7h-.8z" fill-rule="evenodd"/>
<path d="M190 126.8h.8v.8h-.8z" fill-rule="evenodd"/>
<path d="M188.5 126.8h.7v.8h-.7z" fill-rule="evenodd"/>
<path d="M234.7 147.8l.4-.1 .1 .4h-.4z" fill-rule="evenodd"/>
<path d="M234.6 148.3h.6v.3h-.6z" fill-rule="evenodd"/>
<path d="M234.7 148.8h.4l.1 .3-.4 .1z" fill-rule="evenodd"/>
<path d="M236.4 148.8h.4l.1 .3-.4 .1z" fill-rule="evenodd"/>
<path d="M236.4 148.3h.6v.3h-.6z" fill-rule="evenodd"/>
<path d="M236.4 147.8l.4-.1 .1 .4h-.4z" fill-rule="evenodd"/>
<path d="M177.7 163.2h.8v.7h-.8z" fill-rule="evenodd"/>
<path d="M177.7 164.8h.8v.7h-.8z" fill-rule="evenodd"/>
<path d="M225.2 142.8h1.2v1.4h-1.2z" fill-rule="evenodd"/>
<path d="M225.2 145h1.2v1.4h-1.2z" fill-rule="evenodd"/>
<path d="M226.9 145h1.2v1.4h-1.2z" fill-rule="evenodd"/>
<path d="M226.9 142.8h1.2v1.4h-1.2z" fill-rule="evenodd"/>
<path d="M236.6 144.8h.8v.7h-.8z" fill-rule="evenodd"/>
<path d="M236.6 143.2h.8v.8h-.8z" fill-rule="evenodd"/>
<path d="M177.7 166.3h.8v.8h-.8z" fill-rule="evenodd"/>
<path d="M177.7 167.8h.8v.8h-.8z" fill-rule="evenodd"/>
<path d="M220.1 143.8h.2l-.1 .8-.2-.1z" fill-rule="evenodd"/>
<path d="M219.6 143.8h.2l-.1 .8-.2-.1z" fill-rule="evenodd"/>
<path d="M219.1 143.8h.2l-.1 .8-.2-.1z" fill-rule="evenodd"/>
<path d="M218.6 143.8h.2l-.1 .8-.2-.1z" fill-rule="evenodd"/>
<path d="M218.1 143.8h.2l-.1 .8-.2-.1z" fill-rule="evenodd"/>
<path d="M217.6 143.8h.2l-.1 .8-.2-.1z" fill-rule="evenodd"/>
<path d="M217.1 143.8h.2l-.1 .8-.2-.1z" fill-rule="evenodd"/>
<path d="M216.6 143.8h.2l-.1 .8-.2-.1z" fill-rule="evenodd"/>
<path d="M216.1 143.8h.2l-.1 .8-.2-.1z" fill-rule="evenodd"/>
<path d="M214.8 145h.8v.2h-.7z" fill-rule="evenodd"/>
<path d="M214.8 145.5h.8v.2h-.7z" fill-rule="evenodd"/>
<path d="M214.8 146h.8v.2h-.7z" fill-rule="evenodd"/>
<path d="M214.8 146.5h.8v.2h-.7z" fill-rule="evenodd"/>
<path d="M214.8 147h.8v.2h-.7z" fill-rule="evenodd"/>
<path d="M214.8 147.5h.8v.2h-.7z" fill-rule="evenodd"/>
<path d="M214.8 148h.8v.2h-.7z" fill-rule="evenodd"/>
<path d="M214.8 148.5h.8v.2h-.7z" fill-rule="evenodd"/>
<path d="M214.8 149h.8v.2h-.7z" fill-rule="evenodd"/>
<path d="M216.1 149.6l.2 .1-.1 .8-.2-.1z" fill-rule="evenodd"/>
<path d="M216.6 149.6l.2 .1-.1 .8-.2-.1z" fill-rule="evenodd"/>
<path d="M217.1 149.6l.2 .1-.1 .8-.2-.1z" fill-rule="evenodd"/>
<path d="M217.6 149.6l.2 .1-.1 .8-.2-.1z" fill-rule="evenodd"/>
<path d="M218.1 149.6l.2 .1-.1 .8-.2-.1z" fill-rule="evenodd"/>
<path d="M218.6 149.6l.2 .1-.1 .8-.2-.1z" fill-rule="evenodd"/>
<path d="M219.1 149.6l.2 .1-.1 .8-.2-.1z" fill-rule="evenodd"/>
<path d="M219.6 149.6l.2 .1-.1 .8-.2-.1z" fill-rule="evenodd"/>
<path d="M220.1 149.6l.2 .1-.1 .8-.2-.1z" fill-rule="evenodd"/>
<path d="M220.7 149h.8v.2h-.8z" fill-rule="evenodd"/>
<path d="M220.7 148.5h.8v.2h-.8z" fill-rule="evenodd"/>
<path d="M220.7 148h.8v.2h-.8z" fill-rule="evenodd"/>
<path d="M220.7 147.5h.8v.2h-.8z" fill-rule="evenodd"/>
<path d="M220.7 147h.8v.2h-.8z" fill-rule="evenodd"/>
<path d="M220.7 146.5h.8v.2h-.8z" fill-rule="evenodd"/>
<path d="M220.7 146h.8v.2h-.8z" fill-rule="evenodd"/>
<path d="M220.7 145.5h.8v.2h-.8z" fill-rule="evenodd"/>
<path d="M220.7 145h.8v.2h-.8z" fill-rule="evenodd"/>
<path d="M216.3 145.2h3.7v3.7h-3.7z" fill-rule="evenodd"/>
<path d="M227 137.8h.8v.8h-.8z" fill-rule="evenodd"/>
<path d="M225.5 137.8h.7v.8h-.7z" fill-rule="evenodd"/>
<path d="M200.3 168.8h.8v.8h-.8z" fill-rule="evenodd"/>
<path d="M200.3 167.2h.8v.8h-.8z" fill-rule="evenodd"/>
<path d="M190 165.8h1v.8h-1z" fill-rule="evenodd"/>
<path d="M190 168h1v.8h-1z" fill-rule="evenodd"/>
<path d="M197.2 165.8h1.1v.8h-1.1z" fill-rule="evenodd"/>
<path d="M197.2 168h1.1v.8h-1.1z" fill-rule="evenodd"/>
<path d="M191.5 164.8h.7v1.5h-.7z" fill-rule="evenodd"/>
<path d="M194.5 164.8h.7v1.5h-.7z" fill-rule="evenodd"/>
<path d="M196 164.8h.7v1.5h-.7z" fill-rule="evenodd"/>
<path d="M222.2 149.6h.6v.8h-.6z" fill-rule="evenodd"/>
<path d="M223.8 149.6h.7v.8h-.7z" fill-rule="evenodd"/>
<path d="M227 139.3h.8v.8h-.8z" fill-rule="evenodd"/>
<path d="M225.5 139.3h.7v.8h-.7z" fill-rule="evenodd"/>
<path d="M169.7 149.7h1.2v.3h-1.2z" fill-rule="evenodd"/>
<path d="M169.7 149.2h1.2v.3h-1.2z" fill-rule="evenodd"/>
<path d="M169.7 148.7h1.2v.3h-1.2z" fill-rule="evenodd"/>
<path d="M169.7 148.2h1.2v.3h-1.2z" fill-rule="evenodd"/>
<path d="M169.7 147.7h1.2v.3h-1.2z" fill-rule="evenodd"/>
<path d="M169.7 147.2h1.2v.3h-1.2z" fill-rule="evenodd"/>
<path d="M169.7 146.7h1.2v.3h-1.2z" fill-rule="evenodd"/>
<path d="M169.7 146.2h1.2v.3h-1.2z" fill-rule="evenodd"/>
<path d="M169.7 145.7h1.2v.3h-1.2z" fill-rule="evenodd"/>
<path d="M169.7 145.2h1.2v.3h-1.2z" fill-rule="evenodd"/>
<path d="M169.7 144.7h1.2v.3h-1.2z" fill-rule="evenodd"/>
<path d="M169.7 144.2h1.2v.3h-1.2z" fill-rule="evenodd"/>
<path d="M167.9 144.2h1.1v.3h-1.1z" fill-rule="evenodd"/>
<path d="M167.9 144.7h1.1v.3h-1.1z" fill-rule="evenodd"/>
<path d="M167.9 145.2h1.1v.3h-1.1z" fill-rule="evenodd"/>
<path d="M167.9 145.7h1.1v.3h-1.1z" fill-rule="evenodd"/>
<path d="M167.9 146.2h1.1v.3h-1.1z" fill-rule="evenodd"/>
<path d="M167.9 146.7h1.1v.3h-1.1z" fill-rule="evenodd"/>
<path d="M167.9 147.2h1.1v.3h-1.1z" fill-rule="evenodd"/>
<path d="M167.9 147.7h1.1v.3h-1.1z" fill-rule="evenodd"/>
<path d="M167.9 148.2h1.1v.3h-1.1z" fill-rule="evenodd"/>
<path d="M167.9 148.7h1.1v.3h-1.1z" fill-rule="evenodd"/>
<path d="M167.9 149.2h1.1v.3h-1.1z" fill-rule="evenodd"/>
<path d="M167.9 149.7h1.1v.3h-1.1z" fill-rule="evenodd"/>
</g>
<g fill="#e2e2e2">
<circle cx="181.5" cy="130.3" r=".85"/>
<circle cx="211.4" cy="168.2" r=".85"/>
<circle cx="208.8" cy="168.2" r=".85"/>
<circle cx="241.3" cy="127.1" r=".4"/>
<circle cx="242" cy="125.4" r=".4"/>
<circle cx="242" cy="128.8" r=".4"/>
<circle cx="243.7" cy="124.7" r=".4"/>
<circle cx="243.7" cy="127.1" r="3.2"/>
<circle cx="243.7" cy="129.5" r=".4"/>
<circle cx="245.4" cy="125.4" r=".4"/>
<circle cx="245.4" cy="128.8" r=".4"/>
<circle cx="246.1" cy="127.1" r=".4"/>
<circle cx="169.3" cy="167.1" r=".4"/>
<circle cx="170" cy="165.4" r=".4"/>
<circle cx="170" cy="168.8" r=".4"/>
<circle cx="171.7" cy="164.7" r=".4"/>
<circle cx="171.7" cy="167.1" r="3.2"/>
<circle cx="171.7" cy="169.5" r=".4"/>
<circle cx="173.4" cy="165.4" r=".4"/>
<circle cx="173.4" cy="168.8" r=".4"/>
<circle cx="174.1" cy="167.1" r=".4"/>
<circle cx="192.6" cy="167.3" r=".45"/>
<circle cx="195.6" cy="167.3" r=".45"/>
</g>
<path d="M169.3 142.8h1.6" fill="none" stroke="#e2e2e2" stroke-width="1"/>
<g fill="#e2e2e2">
<path d="M167.8 143.3h1.8v.5h-1.8z" fill-rule="evenodd"/>
<path d="M167.8 150.4h1.8v.5h-1.8z" fill-rule="evenodd"/>
</g>
<path d="M169.3 151.4h1.6" fill="none" stroke="#e2e2e2" stroke-width="1"/>
<g fill="#e2e2e2">
<path d="M214.9 142.3h.7v.8h-.7z" fill-rule="evenodd"/>
<path d="M216.4 142.3h.8v.8h-.8z" fill-rule="evenodd"/>
<path d="M228.8 143.5h.8v.7h-.8z" fill-rule="evenodd"/>
<path d="M228.8 145h.8v.8h-.8z" fill-rule="evenodd"/>
<path d="M209.8 125.3h.8v2.4h-.8z" fill-rule="evenodd"/>
<path d="M209.8 129.2h.8v2.4h-.8z" fill-rule="evenodd"/>
<path d="M208.5 125.3h.8v2.4h-.8z" fill-rule="evenodd"/>
<path d="M208.5 129.2h.8v2.4h-.8z" fill-rule="evenodd"/>
<path d="M207.3 125.3h.7v2.4h-.7z" fill-rule="evenodd"/>
<path d="M207.3 129.2h.7v2.4h-.7z" fill-rule="evenodd"/>
<path d="M206 125.3h.7v2.4h-.7z" fill-rule="evenodd"/>
<path d="M206 129.2h.7v2.4h-.7z" fill-rule="evenodd"/>
<path d="M204.7 125.3h.8v2.4h-.8z" fill-rule="evenodd"/>
<path d="M204.7 129.2h.8v2.4h-.8z" fill-rule="evenodd"/>
<path d="M221.1 151.1h.7v.8h-.7z" fill-rule="evenodd"/>
<path d="M219.4 151.1h.7v.8h-.7z" fill-rule="evenodd"/>
<path d="M215.2 125.1h1.7v1.7h-1.7z" fill-rule="evenodd"/>
<path d="M189.8 124.6l.7-.1 .2 .2v.9l-.1 .3h-.7l-.2-.2z" fill-rule="evenodd"/>
<path d="M191.6 124.6l.7-.1 .2 .2v.9l-.1 .3h-.6l-.3-.2z" fill-rule="evenodd"/>
<path d="M191.3 127.7h.6v.2h-.6z" fill-rule="evenodd"/>
<path d="M191.8 127.5h.1v.3h-.1z" fill-rule="evenodd"/>
<path d="M191.3 128.1h.6v.2h-.6z" fill-rule="evenodd"/>
<path d="M191.3 128.5h.6v.2h-.6z" fill-rule="evenodd"/>
<path d="M191.3 128.9h.6v.2h-.6z" fill-rule="evenodd"/>
<path d="M191.3 129.3h.6v.2h-.6z" fill-rule="evenodd"/>
<path d="M192.2 129.1h.2v.6h-.2z" fill-rule="evenodd"/>
<path d="M192.6 129.3h.6v.2h-.6z" fill-rule="evenodd"/>
<path d="M192.6 128.9h.6v.2h-.6z" fill-rule="evenodd"/>
<path d="M192.6 128.5h.6v.2h-.6z" fill-rule="evenodd"/>
<path d="M192.6 128.1h.6v.2h-.6z" fill-rule="evenodd"/>
<path d="M192.6 127.7h.6v.2h-.6z" fill-rule="evenodd"/>
<path d="M192.2 127.5h.2v.6h-.2z" fill-rule="evenodd"/>
<path d="M219.3 168.8h.8v.8h-.8z" fill-rule="evenodd"/>
<path d="M219.3 167.2h.8v.8h-.8z" fill-rule="evenodd"/>
<path d="M223.8 143.4h.8v.7h-.8z" fill-rule="evenodd"/>
<path d="M223.8 145.1h.8v.7h-.8z" fill-rule="evenodd"/>
<path d="M193.8 126.8h.8v.8h-.8z" fill-rule="evenodd"/>
<path d="M195.4 126.8h.7v.8h-.7z" fill-rule="evenodd"/>
<path d="M195.1 148.7h.8v.8h-.8z" fill-rule="evenodd"/>
<path d="M195.1 147.2h.8v.7h-.8z" fill-rule="evenodd"/>
<path d="M221.2 142h.8v.7h-.8z" fill-rule="evenodd"/>
<path d="M221.2 140.3h.8v.7h-.8z" fill-rule="evenodd"/>
<path d="M196.6 150.3h.8v.8h-.8z" fill-rule="evenodd"/>
<path d="M195 150.3h.8v.8h-.8z" fill-rule="evenodd"/>
<path d="M200.3 131.3h.7v.8h-.7z" fill-rule="evenodd"/>
<path d="M202 131.3h.7v.8h-.7z" fill-rule="evenodd"/>
<path d="M198.2 147.3h.8v.7h-.8z" fill-rule="evenodd"/>
<path d="M198.2 145.7h.8v.8h-.8z" fill-rule="evenodd"/>
<path d="M227 141.3h.8v.8h-.8z" fill-rule="evenodd"/>
<path d="M225.4 141.3h.8v.8h-.8z" fill-rule="evenodd"/>
<path d="M217 136.3h.9v.8h-.9z" fill-rule="evenodd"/>
<path d="M217 134.8h.9v.8h-.9z" fill-rule="evenodd"/>
<path d="M220.9 136.4h1.2v.5l-1.2 .1z" fill-rule="evenodd"/>
<path d="M220.9 135.5l1.2-.1v.5l-1.2 .1z" fill-rule="evenodd"/>
<path d="M220.9 134.5h1.2v.5l-1.2 .1z" fill-rule="evenodd"/>
<path d="M218.6 134.5h1.2l.1 .5-1.3 .1z" fill-rule="evenodd"/>
<path d="M218.6 136.4h1.2l.1 .5-1.3 .1z" fill-rule="evenodd"/>
<path d="M200.6 151.2h.8v.7h-.8z" fill-rule="evenodd"/>
<path d="M200.6 150.1h.8v.8h-.8z" fill-rule="evenodd"/>
<path d="M199.6 151.2h.7v.7h-.7z" fill-rule="evenodd"/>
<path d="M199.6 150.1h.7v.8h-.7z" fill-rule="evenodd"/>
<path d="M202 151.9h.8v.2h-.8z" fill-rule="evenodd"/>
<path d="M202 151.2h.8v.3h-.8z" fill-rule="evenodd"/>
<path d="M202 150.6h.8v.2h-.8z" fill-rule="evenodd"/>
<path d="M202 149.9h.8v.3h-.8z" fill-rule="evenodd"/>
<path d="M201.3 148.7h.3v.8h-.3z" fill-rule="evenodd"/>
<path d="M200.7 148.7h.2v.8h-.2z" fill-rule="evenodd"/>
<path d="M200 148.7h.3v.8h-.3z" fill-rule="evenodd"/>
<path d="M199.4 148.7h.2v.8h-.2z" fill-rule="evenodd"/>
<path d="M198.1 149.9h.8v.3h-.8z" fill-rule="evenodd"/>
<path d="M198.1 150.6h.8v.2h-.8z" fill-rule="evenodd"/>
<path d="M198.1 151.2h.8v.3h-.8z" fill-rule="evenodd"/>
<path d="M198.1 151.9h.8v.2h-.8z" fill-rule="evenodd"/>
<path d="M199.4 152.6h.2v.8h-.2z" fill-rule="evenodd"/>
<path d="M200 152.6h.3v.8h-.3z" fill-rule="evenodd"/>
<path d="M200.7 152.6h.2v.8h-.2z" fill-rule="evenodd"/>
<path d="M201.3 152.6h.3v.8h-.3z" fill-rule="evenodd"/>
<path d="M202.2 127.4h.6v.6h-.6z" fill-rule="evenodd"/>
<path d="M202.2 126h.6v.6h-.6z" fill-rule="evenodd"/>
<path d="M219.3 165.9h.8v.7h-.8z" fill-rule="evenodd"/>
<path d="M219.3 164.2h.8v.7h-.8z" fill-rule="evenodd"/>
<path d="M227.2 133.6l.5 .1-.1 1.2-.5-.1z" fill-rule="evenodd"/>
<path d="M226.2 133.6l.6 .1-.1 1.2-.5-.1z" fill-rule="evenodd"/>
<path d="M225.3 133.6l.5 .1-.1 1.2-.5-.1z" fill-rule="evenodd"/>
<path d="M225.3 135.9h.5l-.1 1.3-.5-.1z" fill-rule="evenodd"/>
<path d="M227.2 135.9h.5l-.1 1.3-.5-.1z" fill-rule="evenodd"/>
<path d="M203.5 151.6h.8v.8h-.8z" fill-rule="evenodd"/>
<path d="M203.5 150.1h.8v.8h-.8z" fill-rule="evenodd"/>
<path d="M219.5 152.6h.7v.8h-.7z" fill-rule="evenodd"/>
<path d="M221 152.6h.8v.8h-.8z" fill-rule="evenodd"/>
<path d="M241.9 141.7h.7v.8h-.7z" fill-rule="evenodd"/>
<path d="M240.2 141.7h.7v.8h-.7z" fill-rule="evenodd"/>
<path d="M238.4 150.9h.7v.3h-.7z" fill-rule="evenodd"/>
<path d="M238.4 150.4h.7v.3h-.7z" fill-rule="evenodd"/>
<path d="M238.4 149.9h.7v.3h-.7z" fill-rule="evenodd"/>
<path d="M238.4 149.4h.7v.3h-.7z" fill-rule="evenodd"/>
<path d="M238.4 148.9h.7v.3h-.7z" fill-rule="evenodd"/>
<path d="M238.4 148.4h.7v.3h-.7z" fill-rule="evenodd"/>
<path d="M238.4 147.9h.7v.3h-.7z" fill-rule="evenodd"/>
<path d="M238.4 147.4h.7v.3h-.7z" fill-rule="evenodd"/>
<path d="M238.4 146.9h.7v.3h-.7z" fill-rule="evenodd"/>
<path d="M238.4 146.4h.7v.3h-.7z" fill-rule="evenodd"/>
<path d="M238.4 145.9h.7v.3h-.7z" fill-rule="evenodd"/>
<path d="M238.4 145.4h.7v.3h-.7z" fill-rule="evenodd"/>
<path d="M240.1 145.7h.7v.3h-.7z" fill-rule="evenodd"/>
<path d="M240.1 146.2h.7v.3h-.7z" fill-rule="evenodd"/>
<path d="M240.1 146.7h.7v.3h-.7z" fill-rule="evenodd"/>
<path d="M240.1 147.2h.7v.3h-.7z" fill-rule="evenodd"/>
<path d="M240.1 147.7h.7v.3h-.7z" fill-rule="evenodd"/>
<path d="M240.1 148.2h.7v.3h-.7z" fill-rule="evenodd"/>
<path d="M240.1 148.7h.7v.3h-.7z" fill-rule="evenodd"/>
<path d="M240.1 149.2h.7v.3h-.7z" fill-rule="evenodd"/>
<path d="M240.1 149.7h.7v.3h-.7z" fill-rule="evenodd"/>
<path d="M240.1 150.2h.7v.3h-.7z" fill-rule="evenodd"/>
<path d="M240.1 150.7h.7v.3h-.7z" fill-rule="evenodd"/>
<path d="M240.1 151.2h.7v.3h-.7z" fill-rule="evenodd"/>
<path d="M239.8 154.2h.7v.8h-.7z" fill-rule="evenodd"/>
<path d="M238.1 154.2h.7v.8h-.7z" fill-rule="evenodd"/>
<path d="M200.3 165.9h.8v.7h-.8z" fill-rule="evenodd"/>
<path d="M200.3 164.2h.8v.7h-.8z" fill-rule="evenodd"/>
<path d="M216.9 152.8h.8v.7h-.8z" fill-rule="evenodd"/>
<path d="M216.9 151.1h.8v.7h-.8z" fill-rule="evenodd"/>
<path d="M222.7 141.9h.8v.8h-.8z" fill-rule="evenodd"/>
<path d="M222.7 140.3h.8v.8h-.8z" fill-rule="evenodd"/>
<path d="M180.7 132.5l.7-.1 .2 .2v.9l-.1 .3h-.7l-.2-.2z" fill-rule="evenodd"/>
<path d="M178.8 132.5l.8-.1 .2 .2v.9l-.2 .3h-.6l-.2-.2z" fill-rule="evenodd"/>
<path d="M235.1 138.8l.6 .1-.1 1.8-.5-.1z" fill-rule="evenodd"/>
<path d="M233.9 138.8l.5 .1-.1 1.8-.5-.1z" fill-rule="evenodd"/>
<path d="M232.6 138.8l.6 .1-.1 1.8-.5-.1z" fill-rule="evenodd"/>
<path d="M231.3 138.8l.6 .1-.1 1.8-.5-.1z" fill-rule="evenodd"/>
<path d="M231.3 143.8h.6l-.1 1.9-.5-.1z" fill-rule="evenodd"/>
<path d="M232.6 143.8h.6l-.1 1.9-.5-.1z" fill-rule="evenodd"/>
<path d="M233.9 143.8h.5l-.1 1.9-.5-.1z" fill-rule="evenodd"/>
<path d="M235.1 143.8h.6l-.1 1.9-.5-.1z" fill-rule="evenodd"/>
<path d="M223.5 136.2h.8v.8h-.8z" fill-rule="evenodd"/>
<path d="M223.5 134.6h.8v.8h-.8z" fill-rule="evenodd"/>
<path d="M183.9 133.6h.7v.8h-.7z" fill-rule="evenodd"/>
<path d="M185.6 133.6h.7v.8h-.7z" fill-rule="evenodd"/>
<path d="M179.1 163h1.5v1.4h-1.5z" fill-rule="evenodd"/>
<path d="M179.1 167.6h1.5v1.2h-1.5z" fill-rule="evenodd"/>
<path d="M187 163h1.6v1.4h-1.6z" fill-rule="evenodd"/>
<path d="M187 167.6h1.6v1.2h-1.6z" fill-rule="evenodd"/>
<path d="M200.3 129.7h.7v.8h-.7z" fill-rule="evenodd"/>
<path d="M202 129.7h.7v.8h-.7z" fill-rule="evenodd"/>
<path d="M213.2 147.5h.8v.8h-.8z" fill-rule="evenodd"/>
<path d="M213.2 149.1h.8v.8h-.8z" fill-rule="evenodd"/>
<path d="M200.7 126h.6v.6h-.6z" fill-rule="evenodd"/>
<path d="M200.7 127.4h.6v.6h-.6z" fill-rule="evenodd"/>
<path d="M229.6 139.4h.8v.7h-.8z" fill-rule="evenodd"/>
<path d="M229.6 141.1h.8v.7h-.8z" fill-rule="evenodd"/>
<path d="M177.7 147.4h.4l.1 .3-.5 .1z" fill-rule="evenodd"/>
<path d="M177.7 146.9h.6v.3h-.6z" fill-rule="evenodd"/>
<path d="M177.7 146.4h.5v.3h-.5z" fill-rule="evenodd"/>
<path d="M176 146.4h.5v.3h-.5z" fill-rule="evenodd"/>
<path d="M175.9 146.9h.5l.1 .3h-.6z" fill-rule="evenodd"/>
<path d="M176 147.4h.4l.1 .3-.5 .1z" fill-rule="evenodd"/>
<path d="M184 131.5h.5v1.4l-.5-.1z" fill-rule="evenodd"/>
<path d="M185.9 131.5h.5v1.4l-.5-.1z" fill-rule="evenodd"/>
<path d="M184.9 129.6l.6 .1-.1 1.3-.5-.1z" fill-rule="evenodd"/>
<path d="M211.8 145.3h.8v.8h-.8z" fill-rule="evenodd"/>
<path d="M211.8 143.8h.8v.7h-.8z" fill-rule="evenodd"/>
<path d="M197.3 130l.4-.1 .1 .4h-.4z" fill-rule="evenodd"/>
<path d="M197.2 130.5h.6v.3h-.6z" fill-rule="evenodd"/>
<path d="M197.3 131h.4l.1 .3-.4 .1z" fill-rule="evenodd"/>
<path d="M199 131h.4l.1 .3-.4 .1z" fill-rule="evenodd"/>
<path d="M199 130.5h.6v.3h-.6z" fill-rule="evenodd"/>
<path d="M199 130l.4-.1 .1 .4h-.4z" fill-rule="evenodd"/>
<path d="M196.6 147.2h.8v.6h-.8z" fill-rule="evenodd"/>
<path d="M196.6 148.8h.8v.7h-.8z" fill-rule="evenodd"/>
<path d="M213.3 143.1h.8v.7h-.8z" fill-rule="evenodd"/>
<path d="M213.3 144.8h.8v.7h-.8z" fill-rule="evenodd"/>
<path d="M190 126.8h.8v.8h-.8z" fill-rule="evenodd"/>
<path d="M188.5 126.8h.7v.8h-.7z" fill-rule="evenodd"/>
<path d="M234.7 147.8l.4-.1 .1 .4h-.4z" fill-rule="evenodd"/>
<path d="M234.6 148.3h.6v.3h-.6z" fill-rule="evenodd"/>
<path d="M234.7 148.8h.4l.1 .3-.4 .1z" fill-rule="evenodd"/>
<path d="M236.4 148.8h.4l.1 .3-.4 .1z" fill-rule="evenodd"/>
<path d="M236.4 148.3h.6v.3h-.6z" fill-rule="evenodd"/>
<path d="M236.4 147.8l.4-.1 .1 .4h-.4z" fill-rule="evenodd"/>
<path d="M177.7 163.2h.8v.7h-.8z" fill-rule="evenodd"/>
<path d="M177.7 164.8h.8v.7h-.8z" fill-rule="evenodd"/>
<path d="M225.2 142.8h1.2v1.4h-1.2z" fill-rule="evenodd"/>
<path d="M225.2 145h1.2v1.4h-1.2z" fill-rule="evenodd"/>
<path d="M226.9 145h1.2v1.4h-1.2z" fill-rule="evenodd"/>
<path d="M226.9 142.8h1.2v1.4h-1.2z" fill-rule="evenodd"/>
<path d="M236.6 144.8h.8v.7h-.8z" fill-rule="evenodd"/>
<path d="M236.6 143.2h.8v.8h-.8z" fill-rule="evenodd"/>
<path d="M177.7 166.3h.8v.8h-.8z" fill-rule="evenodd"/>
<path d="M177.7 167.8h.8v.8h-.8z" fill-rule="evenodd"/>
<path d="M219 145.4h.8v.9h-.8z" fill-rule="evenodd"/>
<path d="M217.7 145.4h.9v.9h-.9z" fill-rule="evenodd"/>
<path d="M216.5 145.4h.9v.9h-.9z" fill-rule="evenodd"/>
<path d="M219 146.7h.8v.8h-.8z" fill-rule="evenodd"/>
<path d="M217.7 146.7h.9v.8h-.9z" fill-rule="evenodd"/>
<path d="M216.5 146.7h.9v.8h-.9z" fill-rule="evenodd"/>
<path d="M219 147.9h.8v.9h-.8z" fill-rule="evenodd"/>
<path d="M217.7 147.9h.9v.9h-.9z" fill-rule="evenodd"/>
<path d="M216.5 147.9h.9v.9h-.9z" fill-rule="evenodd"/>
<path d="M220.1 143.8h.2l-.1 .8-.2-.1z" fill-rule="evenodd"/>
<path d="M219.6 143.8h.2l-.1 .8-.2-.1z" fill-rule="evenodd"/>
<path d="M219.1 143.8h.2l-.1 .8-.2-.1z" fill-rule="evenodd"/>
<path d="M218.6 143.8h.2l-.1 .8-.2-.1z" fill-rule="evenodd"/>
<path d="M218.1 143.8h.2l-.1 .8-.2-.1z" fill-rule="evenodd"/>
<path d="M217.6 143.8h.2l-.1 .8-.2-.1z" fill-rule="evenodd"/>
<path d="M217.1 143.8h.2l-.1 .8-.2-.1z" fill-rule="evenodd"/>
<path d="M216.6 143.8h.2l-.1 .8-.2-.1z" fill-rule="evenodd"/>
<path d="M216.1 143.8h.2l-.1 .8-.2-.1z" fill-rule="evenodd"/>
<path d="M214.8 145h.8v.2h-.7z" fill-rule="evenodd"/>
<path d="M214.8 145.5h.8v.2h-.7z" fill-rule="evenodd"/>
<path d="M214.8 146h.8v.2h-.7z" fill-rule="evenodd"/>
<path d="M214.8 146.5h.8v.2h-.7z" fill-rule="evenodd"/>
<path d="M214.8 147h.8v.2h-.7z" fill-rule="evenodd"/>
<path d="M214.8 147.5h.8v.2h-.7z" fill-rule="evenodd"/>
<path d="M214.8 148h.8v.2h-.7z" fill-rule="evenodd"/>
<path d="M214.8 148.5h.8v.2h-.7z" fill-rule="evenodd"/>
<path d="M214.8 149h.8v.2h-.7z" fill-rule="evenodd"/>
<path d="M216.1 149.6l.2 .1-.1 .8-.2-.1z" fill-rule="evenodd"/>
<path d="M216.6 149.6l.2 .1-.1 .8-.2-.1z" fill-rule="evenodd"/>
<path d="M217.1 149.6l.2 .1-.1 .8-.2-.1z" fill-rule="evenodd"/>
<path d="M217.6 149.6l.2 .1-.1 .8-.2-.1z" fill-rule="evenodd"/>
<path d="M218.1 149.6l.2 .1-.1 .8-.2-.1z" fill-rule="evenodd"/>
<path d="M218.6 149.6l.2 .1-.1 .8-.2-.1z" fill-rule="evenodd"/>
<path d="M219.1 149.6l.2 .1-.1 .8-.2-.1z" fill-rule="evenodd"/>
<path d="M219.6 149.6l.2 .1-.1 .8-.2-.1z" fill-rule="evenodd"/>
<path d="M220.1 149.6l.2 .1-.1 .8-.2-.1z" fill-rule="evenodd"/>
<path d="M220.7 149h.8v.2h-.8z" fill-rule="evenodd"/>
<path d="M220.7 148.5h.8v.2h-.8z" fill-rule="evenodd"/>
<path d="M220.7 148h.8v.2h-.8z" fill-rule="evenodd"/>
<path d="M220.7 147.5h.8v.2h-.8z" fill-rule="evenodd"/>
<path d="M220.7 147h.8v.2h-.8z" fill-rule="evenodd"/>
<path d="M220.7 146.5h.8v.2h-.8z" fill-rule="evenodd"/>
<path d="M220.7 146h.8v.2h-.8z" fill-rule="evenodd"/>
<path d="M220.7 145.5h.8v.2h-.8z" fill-rule="evenodd"/>
<path d="M220.7 145h.8v.2h-.8z" fill-rule="evenodd"/>
<path d="M227 137.8h.8v.8h-.8z" fill-rule="evenodd"/>
<path d="M225.5 137.8h.7v.8h-.7z" fill-rule="evenodd"/>
<path d="M200.3 168.8h.8v.8h-.8z" fill-rule="evenodd"/>
<path d="M200.3 167.2h.8v.8h-.8z" fill-rule="evenodd"/>
<path d="M190 165.8h1v.8h-1z" fill-rule="evenodd"/>
<path d="M190 168h1v.8h-1z" fill-rule="evenodd"/>
<path d="M197.2 165.8h1.1v.8h-1.1z" fill-rule="evenodd"/>
<path d="M197.2 168h1.1v.8h-1.1z" fill-rule="evenodd"/>
<path d="M191.5 164.8h.7v1.5h-.7z" fill-rule="evenodd"/>
<path d="M194.5 164.8h.7v1.5h-.7z" fill-rule="evenodd"/>
<path d="M196 164.8h.7v1.5h-.7z" fill-rule="evenodd"/>
<path d="M222.2 149.6h.6v.8h-.6z" fill-rule="evenodd"/>
<path d="M223.8 149.6h.7v.8h-.7z" fill-rule="evenodd"/>
<path d="M227 139.3h.8v.8h-.8z" fill-rule="evenodd"/>
<path d="M225.5 139.3h.7v.8h-.7z" fill-rule="evenodd"/>
<path d="M169.7 149.7h1.2v.3h-1.2z" fill-rule="evenodd"/>
<path d="M169.7 149.2h1.2v.3h-1.2z" fill-rule="evenodd"/>
<path d="M169.7 148.7h1.2v.3h-1.2z" fill-rule="evenodd"/>
<path d="M169.7 148.2h1.2v.3h-1.2z" fill-rule="evenodd"/>
<path d="M169.7 147.7h1.2v.3h-1.2z" fill-rule="evenodd"/>
<path d="M169.7 147.2h1.2v.3h-1.2z" fill-rule="evenodd"/>
<path d="M169.7 146.7h1.2v.3h-1.2z" fill-rule="evenodd"/>
<path d="M169.7 146.2h1.2v.3h-1.2z" fill-rule="evenodd"/>
<path d="M169.7 145.7h1.2v.3h-1.2z" fill-rule="evenodd"/>
<path d="M169.7 145.2h1.2v.3h-1.2z" fill-rule="evenodd"/>
<path d="M169.7 144.7h1.2v.3h-1.2z" fill-rule="evenodd"/>
<path d="M169.7 144.2h1.2v.3h-1.2z" fill-rule="evenodd"/>
<path d="M167.9 144.2h1.1v.3h-1.1z" fill-rule="evenodd"/>
<path d="M167.9 144.7h1.1v.3h-1.1z" fill-rule="evenodd"/>
<path d="M167.9 145.2h1.1v.3h-1.1z" fill-rule="evenodd"/>
<path d="M167.9 145.7h1.1v.3h-1.1z" fill-rule="evenodd"/>
<path d="M167.9 146.2h1.1v.3h-1.1z" fill-rule="evenodd"/>
<path d="M167.9 146.7h1.1v.3h-1.1z" fill-rule="evenodd"/>
<path d="M167.9 147.2h1.1v.3h-1.1z" fill-rule="evenodd"/>
<path d="M167.9 147.7h1.1v.3h-1.1z" fill-rule="evenodd"/>
<path d="M167.9 148.2h1.1v.3h-1.1z" fill-rule="evenodd"/>
<path d="M167.9 148.7h1.1v.3h-1.1z" fill-rule="evenodd"/>
<path d="M167.9 149.2h1.1v.3h-1.1z" fill-rule="evenodd"/>
<path d="M167.9 149.7h1.1v.3h-1.1z" fill-rule="evenodd"/>
<path d="M167.8 143.3h1.8v.5h-1.8z" fill-rule="evenodd"/>
<path d="M167.8 150.4h1.8v.5h-1.8z" fill-rule="evenodd"/>
<path d="M214.9 142.3h.7v.8h-.7z" fill-rule="evenodd"/>
<path d="M216.4 142.3h.8v.8h-.8z" fill-rule="evenodd"/>
<path d="M228.8 143.5h.8v.7h-.8z" fill-rule="evenodd"/>
<path d="M228.8 145h.8v.8h-.8z" fill-rule="evenodd"/>
<path d="M209.8 125.3h.8v2.4h-.8z" fill-rule="evenodd"/>
<path d="M209.8 129.2h.8v2.4h-.8z" fill-rule="evenodd"/>
<path d="M208.5 125.3h.8v2.4h-.8z" fill-rule="evenodd"/>
<path d="M208.5 129.2h.8v2.4h-.8z" fill-rule="evenodd"/>
<path d="M207.3 125.3h.7v2.4h-.7z" fill-rule="evenodd"/>
<path d="M207.3 129.2h.7v2.4h-.7z" fill-rule="evenodd"/>
<path d="M206 125.3h.7v2.4h-.7z" fill-rule="evenodd"/>
<path d="M206 129.2h.7v2.4h-.7z" fill-rule="evenodd"/>
<path d="M204.7 125.3h.8v2.4h-.8z" fill-rule="evenodd"/>
<path d="M204.7 129.2h.8v2.4h-.8z" fill-rule="evenodd"/>
<path d="M221.1 151.1h.7v.8h-.7z" fill-rule="evenodd"/>
<path d="M219.4 151.1h.7v.8h-.7z" fill-rule="evenodd"/>
<path d="M189.8 124.6l.7-.1 .2 .2v.9l-.1 .3h-.7l-.2-.2z" fill-rule="evenodd"/>
<path d="M191.6 124.6l.7-.1 .2 .2v.9l-.1 .3h-.6l-.3-.2z" fill-rule="evenodd"/>
<path d="M191.3 127.7h.6v.2h-.6z" fill-rule="evenodd"/>
<path d="M191.8 127.5h.1v.3h-.1z" fill-rule="evenodd"/>
<path d="M191.3 128.1h.6v.2h-.6z" fill-rule="evenodd"/>
<path d="M191.3 128.5h.6v.2h-.6z" fill-rule="evenodd"/>
<path d="M191.3 128.9h.6v.2h-.6z" fill-rule="evenodd"/>
<path d="M191.3 129.3h.6v.2h-.6z" fill-rule="evenodd"/>
<path d="M192.2 129.1h.2v.6h-.2z" fill-rule="evenodd"/>
<path d="M192.6 129.3h.6v.2h-.6z" fill-rule="evenodd"/>
<path d="M192.6 128.9h.6v.2h-.6z" fill-rule="evenodd"/>
<path d="M192.6 128.5h.6v.2h-.6z" fill-rule="evenodd"/>
<path d="M192.6 128.1h.6v.2h-.6z" fill-rule="evenodd"/>
<path d="M192.6 127.7h.6v.2h-.6z" fill-rule="evenodd"/>
<path d="M192.2 127.5h.2v.6h-.2z" fill-rule="evenodd"/>
<path d="M219.3 168.8h.8v.8h-.8z" fill-rule="evenodd"/>
<path d="M219.3 167.2h.8v.8h-.8z" fill-rule="evenodd"/>
<path d="M193.8 126.8h.8v.8h-.8z" fill-rule="evenodd"/>
<path d="M195.4 126.8h.7v.8h-.7z" fill-rule="evenodd"/>
<path d="M195.1 148.7h.8v.8h-.8z" fill-rule="evenodd"/>
<path d="M195.1 147.2h.8v.7h-.8z" fill-rule="evenodd"/>
<path d="M221.2 142h.8v.7h-.8z" fill-rule="evenodd"/>
<path d="M221.2 140.3h.8v.7h-.8z" fill-rule="evenodd"/>
<path d="M196.6 150.3h.8v.8h-.8z" fill-rule="evenodd"/>
<path d="M195 150.3h.8v.8h-.8z" fill-rule="evenodd"/>
<path d="M200.3 131.3h.7v.8h-.7z" fill-rule="evenodd"/>
<path d="M202 131.3h.7v.8h-.7z" fill-rule="evenodd"/>
<path d="M198.2 147.3h.8v.7h-.8z" fill-rule="evenodd"/>
<path d="M198.2 145.7h.8v.8h-.8z" fill-rule="evenodd"/>
<path d="M227 141.3h.8v.8h-.8z" fill-rule="evenodd"/>
<path d="M225.4 141.3h.8v.8h-.8z" fill-rule="evenodd"/>
<path d="M217 136.3h.9v.8h-.9z" fill-rule="evenodd"/>
<path d="M217 134.8h.9v.8h-.9z" fill-rule="evenodd"/>
<path d="M220.9 136.4h1.2v.5l-1.2 .1z" fill-rule="evenodd"/>
<path d="M220.9 135.5l1.2-.1v.5l-1.2 .1z" fill-rule="evenodd"/>
<path d="M220.9 134.5h1.2v.5l-1.2 .1z" fill-rule="evenodd"/>
<path d="M218.6 134.5h1.2l.1 .5-1.3 .1z" fill-rule="evenodd"/>
<path d="M218.6 136.4h1.2l.1 .5-1.3 .1z" fill-rule="evenodd"/>
</g>
<g fill="#e2e2e2">
<circle cx="216.1" cy="128.4" r=".85"/>
<circle cx="216.1" cy="131" r=".85"/>
<circle cx="169.3" cy="127.1" r=".4"/>
<circle cx="170" cy="125.4" r=".4"/>
<circle cx="170" cy="128.8" r=".4"/>
<circle cx="171.7" cy="124.7" r=".4"/>
<circle cx="171.7" cy="127.1" r="3.2"/>
<circle cx="171.7" cy="129.5" r=".4"/>
<circle cx="173.4" cy="125.4" r=".4"/>
<circle cx="173.4" cy="128.8" r=".4"/>
<circle cx="174.1" cy="127.1" r=".4"/>
</g>
<g fill="none" stroke="#dbdbdb" stroke-width=".18">
<path d="M176.3 131.4a.36 .36 0 0 0 .3 .5 .36 .36 0 0 0 .3-.5M176.5 130.7h.5M176.5 130.4h.5M176.5 130.1l.1 .3M176.5 127.8v.3M176.5 129.6l.1 .3M176.5 129.9h.5M176.5 128.7h.5M176.9 130.7l.1 .3-.5 .1M177 129.1l-.1 .3h-.4v-.3l.1-.1 .1 .4M177 127.8l-.1 .2h-.7M177 128.3l-.5 .1v.3"/>
<path d="M177.5 128.6h.6M177.8 128.3v.6M206 132a.4 .4 0 0 1 .4 .4 .4 .4 0 0 1-.4 .4zM206.7 132.5l.4-.1v-.1h-.4l.1 .4h.3M207.5 132.3l.2-.1 .2 .2-.1 .3h-.3M207.5 132v.8M208.2 132.2v.5h.3M208.5 132.2v.6M209.3 132.7h-.4l.1-.4h.3v.6l-.2 .1h-.2M214 132.9l.2 .8 .3-.8M214.8 133.2h.2l.1 .1-.1 .4-.3-.1zM215.5 132.9v.7l.1 .1"/>
<path d="M215.8 133.2h.3M215.9 132.9v.7l.2 .1M216.4 133.2h.3v.5M216.7 133.4l-.4 .1 .1 .2h.3M217.4 133.7l-.3-.1v-.4h.3v.6l-.1 .2h-.2M217.8 133.5l.4-.1-.1-.2-.3 .1v.4h.3M218.1 126h.6M218.1 131h.6M218.4 125.7v.6M218.4 130.7v.6M219 125.5h.5l-.3 .3h.2v.4h-.4M219 131.3h.5"/>
<path d="M219 130.8l.2-.3v.8M219.7 125.5l.3 .8 .2-.8M219.7 130.5l.3 .8 .2-.8M220.4 125.5h.5l-.2 .3h.2v.4h-.5M220.6 130.9l-.1-.2 .1-.2 .3 .2-.1 .2M220.6 130.9l-.1 .1 .1 .3 .3-.1-.1-.3M220.6 130.9h.2M168.1 141a.4 .4 0 0 1 .4 .4 .4 .4 0 0 1-.4 .4zM168.8 141.5l.4-.1v-.1h-.4l.1 .4h.3M169.5 141.2l.2 .6 .2-.6M170.2 141h.1M170.2 141.2v.6"/>
<path d="M170.9 141.3l-.2-.1-.2 .2 .1 .3h.3M171.2 141.5l.4-.1-.1-.1h-.3v.4h.3M242.6 153.9v.8M242.6 154.3h.4M243 153.9v.8M243.5 154.2h.1l.2 .1-.2 .4-.2-.2zM244.4 154.2l-.3 .1 .3 .2v.1h-.3M244.7 154.2h.3M244.8 153.9v.7l.2 .1M201.7 169.5h.8M201.8 169.8a.36 .36 0 0 0 .3 .5 .36 .36 0 0 0 .3-.5M202 167.8l.1 .2"/>
<path d="M202 168h.5M202 167.2h.6l.2 .2-.1 .1M202 167.2v.2l.1 .2 .4-.1v-.3M202.2 168.4l.1 .4 .2-.1v-.3M202.5 166.5l-.1 .4-.4-.1v-.3h.2v.4M202.5 168.4l-.5 .1v.3M202.5 169.1l-.5 .1v.3M206 169h.7l.1 .2-.1 .3h-.7M206 166.8v.5M206 167h.8M206.4 168v-.4l-.3-.1-.1 .5h.8M206.6 168.3v.4"/>
<path d="M206.8 168.2l-.8 .3 .8 .3M206.8 167.5l-.4 .3M208.4 165.5v.4M208.4 165.7h.8M208.4 164.3a.43 .43 0 0 1 .5-.2 .43 .43 0 0 1 .3 .5h-.8zM208.7 164.9l.5 .4M209.2 164.9l-.5 .4M210.9 164.6h.8l-.8 .4h.8M211 165.4a.36 .36 0 0 0 .3 .5 .36 .36 0 0 0 .3-.5h-.2v.1M211 163.9a.43 .43 0 0 1 .5-.1 .43 .43 0 0 1 .2 .4h-.8zM213.6 164a.42 .42 0 0 1 .5 0 .42 .42 0 0 1 .2 .4h-.8zM213.7 164.7l.6 .4"/>
<path d="M213.9 165.8l-.1-.4h-.3v.4h.8M214.3 165.4l-.4 .2M214.3 164.7l-.6 .4M220.7 169h.6l.2 .1-.2 .3h-.6M220.7 167.5l.2-.1 .2 .1 .2-.1 .2 .1v.3h-.8zM220.7 168.2l.1 .4a.33 .33 0 0 0 .4-.4h.3v.4M221.1 167.5v.3"/>
</g>
<g fill="#dbdbdb">
<path d="M181 160.9a.31 .31 0 0 1 .4 .3 .31 .31 0 0 1-.4 .3z" fill-rule="evenodd"/>
<path d="M180.3 160.3h6.4v2.4h-6.4v-1.9h.4v1.6h.3v-.7l.2 .2 .2 .5h1.3v-.2h-.5v-.6h.5v-.2h-.5v-.2h.8l.1 .3a.58 .58 0 0 1 .5 .7l-.3 .1-.2-.2v.3l.4 .1 1.6-.1v-.2h-.6v-.6h.5v-.2h-.5v-.5h1.2v1.5h.2v-1.5h.4v-.2h-1v.2h-.2v-.2h-.9v1.7h-.6a.58 .58 0 0 0 .3-.6 .58 .58 0 0 0-.5-.4v-.4h.5v-.2a.55 .55 0 0 0-.9 .4h-.8v-.3h.5v-.2h-.8v1.7h-.2l-.3-.7a.56 .56 0 0 0 .1-.8 .56 .56 0 0 0-.8-.1h-.4z" fill-rule="evenodd"/>
</g>
<path d="M201.9 126.3v2h1.2v-2M203.4 151.1v.3M204.4 151.1v.3M220.5 152.5h.3M220.5 153.5h.3M219.2 165.2v.4M220.2 165.2v.4" fill="none" stroke="#dbdbdb" stroke-width=".18"/>
<g fill="#dbdbdb">
<path d="M235.6 129.3h.3v.4h-.3z" fill-rule="evenodd"/>
<path d="M238.4 128.6h.2l.2 .9 .2-.9h.2l-.3 1.1h-.2z" fill-rule="evenodd"/>
<path d="M228.2 128.6h.7l-.5 .9h.5v.2h-.7l.4-.9h-.4z" fill-rule="evenodd"/>
<path d="M230.1 128.6h.2l.1 .8 .1-.8h.2l.1 .9 .1-.9h.2l-.2 1.1h-.2l-.1-.9-.2 .9h-.2z" fill-rule="evenodd"/>
<path d="M234.3 128.1h.2v.5l.5 .1 .1 1h-.2v-.8l-.2-.2-.2 .1v.9h-.2z" fill-rule="evenodd"/>
<path d="M232.5 128.2h.2v.4h.3v.2h-.3v.7h.3v.2h-.4l-.1-.2v-.7h-.3v-.2h.3z" fill-rule="evenodd"/>
<path d="M233.4 128.7l.6-.1v.4h-.2v-.3a.37 .37 0 0 0-.3 .5 .37 .37 0 0 0 .5 .3v.1a.57 .57 0 0 1-.7-.2 .57 .57 0 0 1 .1-.7z" fill-rule="evenodd"/>
<path d="M236.9 128.1h.2v1.5a.51 .51 0 0 1-.5 0 .51 .51 0 0 1-.3-.5h.3l.1 .4h.2l-.1-.7h-.2v.3h-.3a.41 .41 0 0 1 .1-.4 .41 .41 0 0 1 .5-.1z" fill-rule="evenodd"/>
<path d="M229.3 128.6h.6v.2l-.3-.1-.2 .2 .3 .2a.37 .37 0 0 1 .2 .5 .37 .37 0 0 1-.6 .1l-.1-.3 .3 .1 .2-.1-.5-.4z" fill-rule="evenodd"/>
<path d="M237.5 128.7a.44 .44 0 0 1 .5-.1 .44 .44 0 0 1 .2 .6h-.6l.1 .2 .4 .1v.1a.51 .51 0 0 1-.6 0 .51 .51 0 0 1-.1-.6h.6l-.2-.3-.2 .3h-.2z" fill-rule="evenodd"/>
<path d="M231.3 128.6a.43 .43 0 0 1 .4 0 .43 .43 0 0 1 .3 .4v.6a.51 .51 0 0 1-.8-.3l.6 .2v-.4l-.6 .2 .1-.2 .5-.1-.1-.2h-.4z" fill-rule="evenodd"/>
</g>
<g fill="none" stroke="#dbdbdb" stroke-width=".18">
<path d="M180 132.4h.4M180 133.8h.4M183.6 130.6v1.3M184.9 133.5h.4M184.9 134.5h.4M186.8 130.6v1.3M189.5 126.7h.3M189.5 127.7h.3M194.3 124.5h.4M194.3 125.9h.4M200.4 127.7v-2h1.2v2M201.3 129.6h.4"/>
<path d="M201.3 130.6h.4M223.4 135.7v.2M224.4 135.7v.2M196.5 148.1v.5M197.5 148.1v.5M211.7 144.8v.3M212.7 144.8v.3M213.1 148.6v.2M213.2 144.1v.4M214.1 148.6v.2M214.2 144.1v.4M216.8 152.1v.4"/>
<path d="M217.8 152.1v.4M222.6 141.4v.2M223.6 141.4v.2M229.5 140.4v.4M230.5 140.4v.4M239.1 154.1h.4M239.1 155.1h.4M241.2 141.6h.4M241.2 142.6h.4M200.2 165.2v.4M201.2 165.2v.4"/>
</g>
<path d="M183.4 132.2l.3 .2-.3 .2z" fill="#dbdbdb" stroke="#dbdbdb" stroke-width=".18"/>
<g fill="#dbdbdb">
<path d="M236.8 124.9h1l.1 .9h.2v-.9h1.1v2.5l-1.1-.1v-.6l.2-.4-.3-.2-.3 .2 .2 .4-.1 .7-1-.1z" fill-rule="evenodd"/>
<path d="M231.6 125h2.2v.9h-.5v1.5h-1.2v-1.3l.8 .2 .2-.3-.3-.3-.3 .2h-.9z" fill-rule="evenodd"/>
<path d="M219.5 124.9h2.5l-.5 1.3h.5v1.2h-2.5l.4-1.3h-.4z" fill-rule="evenodd"/>
<path d="M234.3 125h1.7l.2 .1 .1 .9h-.9l-.3-.2-.3 .3 .1 .3 .2 .1 .4-.2h.8v.8l-.2 .2-1.8 .1z" fill-rule="evenodd"/>
<path d="M222.5 125.1l.3-.2h2v1.3h-.4l.4 .3v.4l-.1 .3-.4 .2h-1.9v-1.2h.5l-.6-.4v-.4z" fill-rule="evenodd"/>
<path d="M230.3 124.8l1.5 2.6-2-.1 .4-.7 .3-.1 .2-.2-.2-.4-.3-.1-.2 .2v.5l-.5 .8h-.7z" fill-rule="evenodd"/>
<path d="M225.3 125h4.3l-1.5 2.5-.9-1.5v-.4l-.1-.2a.37 .37 0 0 0-.6 .3 .37 .37 0 0 0 .4 .4l.4 .6-.5 .8z" fill-rule="evenodd"/>
<circle cx="232.8" cy="126" r=".17"/>
<circle cx="226.9" cy="125.7" r=".19"/>
<circle cx="230.3" cy="126.2" r=".2"/>
<circle cx="235.1" cy="126.2" r=".18"/>
<circle cx="238" cy="126.4" r=".17"/>
</g>
<path d="M226.5 137.7h.3M226.5 138.7h.3M228.3 142.6h-3.3v4M236.5 144.2v.3M237.5 144.2v.3M177.6 164.1v.5M177.6 167.3v.3M178.6 167.3v.3M178.6 164.1v.5M200 167.6v2.3h1.4v-2.3" fill="none" stroke="#dbdbdb" stroke-width=".18"/>
<g fill="#dbdbdb">
<path d="M241.2 160.9l.3-.1v.5h-.3z" fill-rule="evenodd"/>
<path d="M222 160.4l.4-.1v.9l-.2 .1-.2-.2z" fill-rule="evenodd"/>
<path d="M228.8 160.4l.1-.1a.53 .53 0 0 1 .4 .5 .53 .53 0 0 1-.3 .6l-.2-.1z" fill-rule="evenodd"/>
<path d="M232.9 160.4l.1-.1a.52 .52 0 0 1 .5 .5 .52 .52 0 0 1-.4 .5l-.2-.2z" fill-rule="evenodd"/>
<path d="M221.2 159h25.2v3.4h-25.2v-1.6h.4l.2 .6h.6l-.2 .4-.4 .1v.3l.5-.1 .4-.5h12.9l.7-1.8h1.1l-.7 1.7h1v-.2h-.6l.5-1.3h.5l.1 .4 .2 .2a.41 .41 0 0 1 .4 .6 .41 .41 0 0 1-.7 0v.2l.1 .1a.62 .62 0 0 0 .9-.3 .62 .62 0 0 0-.5-.8l-.2-.2 .1-.4 .6 .1v-.3l-.2-.1h.4l.2 2h.3l.1-1.3 .2 1.3h.4v-.4h.3l.2 .3 .2 .2 .6-.1v-1.1l-.1-.2h.5v.2h.3l.1 1.1h.6v-.2h-.4v-.5h.8l.1 .6 .5 .2 1-.1v-1.1l.3-.1 .2 .2v1h.3v-1.1l-.2-.3-.6 .1v-.7h-.3v2h-.5h.1v-.2h-.1a.51 .51 0 0 1-.5-.4 .51 .51 0 0 1 .4-.6v.3h.3v-.5h-.2a.64 .64 0 0 0-.8 .7h-.8v-.4h.4v-.2h-.4v-.6h-.3v.6h-1.6v.2h.1a.33 .33 0 0 1 .5 .2l-.4 .1-.3 .4h-.3l.1-1.6h-.2l-.1 1.8-.2-1.4h-.2l-.2 1.2-.1-1.6h-1.1l-.3 .1-.1 .4h-.5l.1-.5h-1v.3h-.4l.1-.3h-.2l-.9 2.1h-12.6v-1.5h-.2h.6v.2h.4v1.2h.3v-1.3h.6v.2h.3v.9l.4 .3 1-.1v-1.1l.2-.1 .2 .2v1h.3v-.4h.3l.1 .4 .3 .1 3.1-.1v-.4h-.4v.4h-1l.3-.2 .1-.5h1.6a.66 .66 0 0 0 .3 .7 .66 .66 0 0 0 .7 0v-.2l-.3 .1-.3-.2-.1-.4h1a.59 .59 0 0 0 .6 .8 .59 .59 0 0 0 .6-.8l-.2-.6h.4v1.3h.2v-1.1l.2-.1 .1 1.2h.2v-1.1l.2-.1v1.2h.3l-.1-1.3h-1.6a.6 .6 0 0 0-.6 0 .6 .6 0 0 0-.3 .6h-1l.2-.5h.2v.3h.3v-.5h-.1a.64 .64 0 0 0-.9 .7h-1.6l-.2-.6-.6-.1v-.6h-.3v2h-.4v-1.4h-.3l.1 1.2h-.4l-.1-1.2h-.3v1h-.3l-.1-.9-.3-.1-.3 .1v-.7h-.3v2h-.4v-.2h-.4l-.1-.9h.5v-.2h-.5v-.6h-.2v.6l-2.7-.1-.2 .1-.2 .6h-.4v-1h2.6v-.3h-.4v.3h-2.2z" fill-rule="evenodd"/>
</g>
<path d="M226.5 139.2h.3M223.1 149.5h.5M223.1 150.5h.5M226.5 140.2h.3" fill="none" stroke="#dbdbdb" stroke-width=".18"/>
<g fill="#dbdbdb">
<path d="M193.5 162.7l.2 .8h-.3z" fill-rule="evenodd"/>
<path d="M194.5 162.6a.31 .31 0 0 1 .4 .3 .31 .31 0 0 1-.4 .3z" fill-rule="evenodd"/>
<path d="M190.4 162h7.4v2.4h-7.4v-1.1h.3a.66 .66 0 0 0 .8 .8h.7v-.8h.4v.8h.7v-.4h.4l.1 .4h.3l-.4-1.6h.6v1.6h.2v-.7l.3 .2 .2 .5h.2l-.3-.7 .5-.1a.65 .65 0 0 0 .1 .7 .65 .65 0 0 0 .7 .1h1.3v-.2h-.6v-.6h.5v-.2h-.5v-.5h.6v-.2h-.9v1.7h-.4h.2v-1h-.6v.2h.3v.6a.66 .66 0 0 1-.4-1l.1-.2h.5v-.2a.67 .67 0 0 0-.7 .1 .67 .67 0 0 0-.2 .7h-.3a.57 .57 0 0 0-.1-.8 .57 .57 0 0 0-.7 0l-.9-.1-.4 1.7h-.1v-1.7h-.3v.7h-.4v-.7h-.3v1.7h-.4l.1-.2a.46 .46 0 0 1-.5-.1 .46 .46 0 0 1-.1-.5l.2-.7h.2v.4h.2v-.5a.65 .65 0 0 0-.7 .1 .65 .65 0 0 0-.2 .7h-.3z" fill-rule="evenodd"/>
</g>
<g fill="none" stroke="#dbdbdb" stroke-width=".18">
<path d="M190.9 124.5h.4M190.9 125.9h.4M191.4 129.8h.5M192.6 129.8h.5M192.7 127.5h.4M194.8 126.7h.3M194.8 127.7h.3M201.3 131.2h.4M201.3 132.2h.4M216.9 135.8v.3M218 135.8v.3M195 148.2v.3"/>
<path d="M196 148.2v.3M196.1 150.2h.2M196.1 151.2h.2M198.1 146.7v.3M199.1 146.7v.3M215.9 142.2h.3M215.9 143.2h.3M220.4 151h.4M220.4 152h.4M221.1 141.3v.4M222.1 141.3v.4M223.7 144.4v.4"/>
<path d="M224.7 144.4v.4M226.5 142.2h.2M226.5 141.2h.2M228.7 144.5v.3M229.7 144.5v.3M219 167.6v2.3h1.4v-2.3"/>
</g>
<path d="M191.3 127.2v.3h-.3z" fill="#dbdbdb" stroke="#dbdbdb" stroke-width=".18"/>
<g fill="none" stroke="#818181" stroke-width=".18">
<path d="M177.6 126.2h5.2zM177.6 126.2l.1 2zM177.7 128.1l-.1 .1 .7 .6M177.7 128.1l.6 .7M178.3 128.7l4.5 .1zM178.6 120.2h.7zM178.6 120.2v6.1zM178.6 128.7v2zM178.6 130.6h.7zM179.2 132.5h2v1.2h-2zM179.2 120.2v6.1zM179.2 128.7v2z"/>
<path d="M181.1 120.2h.7zM181.1 120.2v6.1zM181.1 128.7v2zM181.1 130.6h.7zM181.8 120.2v6.1zM181.8 128.7v2zM182.7 126.2v2.6zM183.8 130.6h2.8v1.3h-2.5l-.3-.3zM184.3 133.6h1.6v.8h-1.6zM188.8 126.8h1.6v.8h-1.6zM190.1 124.6h2v1.2h-2zM191.9 127.6h1.2v2h-1.7v-1.5z"/>
<path d="M193.5 124.5l2.1 .1zM193.5 124.5v1.4zM193.5 125.8h2.1zM194.2 126.8h1.6v.8h-1.6zM195.5 124.5v1.4zM198.1 129.8h.9v1.7h-1.3v-1.4zM200.5 126.3h.9v1.4h-.9zM200.7 129.7h1.6v.8h-1.6zM200.7 131.3h1.6v.8h-1.6zM200.8 126.8h.4M201 126.8l.2 .3h-.4zM201 126.7v.1"/>
<path d="M201 127.1v.1M202 126.3h1v1.4h-1zM202.3 126.9h.4l-.2 .3zM202.3 127.2h.4M202.5 126.8v.1M202.5 127.2v.1M204.5 126.7h5.9l.4 .5v3h-6.3zM204.9 126.7v-1h.4v1M204.9 130.2v1h.4v-1M206.2 126.7v-1h.4v1M206.2 130.2v1h.4v-1M207.4 126.7v-1h.4v1"/>
<path d="M207.4 130.2v1h.4v-1M208.7 126.7v-1h.4v1M208.7 130.2v1h.4v-1M210 126.7v-1h.4v1M210 130.2v1h.4v-1M215.5 124.6h1.9v7.7h-2.6v-7zM217.1 135.1h.7v1.6h-.7zM219.6 134.3h1.6v2.5l-.5 .4h-1.1zM223.5 135h.8v1.6h-.8zM225 134.6h2.5l.4 .4v1.2h-2.9zM225.8 137.8h1.6v.8h-1.6zM225.8 139.3h1.6v.8h-1.6z"/>
<path d="M229.6 139.8h.8v1.6h-.8zM157 142.7h13.8v8.8h-13.8zM176.4 146.2h1.3v1.4l-.3 .3h-1zM195.1 147.5h.8v1.6h-.8zM195.4 150.3h1.6v.8h-1.6zM196.6 147.5h.8v1.6h-.8zM198.2 146.1h.8v1.6h-.8zM198.5 149h4v3l-1 1h-3zM203.5 150.5h.8v1.6h-.8zM211.8 144.1h.8v1.6h-.8zM213.2 147.9h.8v1.6h-.8zM213.3 143.5h.8v1.6h-.8z"/>
<path d="M215.2 144.1h5l1 1v5h-6zM215.2 142.3h1.6v.8h-1.6zM216.9 151.5h.8v1.6h-.8zM219.8 151.1h1.6v.8h-1.6zM219.8 152.6h1.6v.8h-1.6zM221.2 140.7h.8v1.6h-.8zM222.5 149.6h1.6v.8h-1.6zM222.7 140.7h.8v1.6h-.8zM223.8 143.8h.9zM223.8 143.8v1.7zM223.8 145.4h.9zM224.6 143.8v1.7z"/>
<path d="M225.6 143h2.1l.2 .2v2.8l-.2 .2h-2.1l-.2-.2v-2.8zM225.8 141.3h1.6v.8h-1.6zM226.4 143l-1 1M228.8 143.8h.8v1.6h-.8zM231.1 140.3h3.9l1 1v2.9h-4.9zM235.1 147.9l.4-.3h1v1.7h-1.4zM236.6 143.6h.8v1.6h-.8zM238.5 154.2h1.6v.8h-1.6zM238.5 143.7h10.5v9.2h-10.5zM240.6 141.7h1.6v.8h-1.6zM177.7 163.5h.8v1.6h-.8zM177.7 166.7h.8v1.6h-.8z"/>
<path d="M180.7 162.8h6.2v6.2h-6.2zM190.7 166h6.7v2.6h-6.7zM194 168.6v1.3l-.3 .2h-.8l-.2-.2v-1.3M200.3 164.6h.8v1.6h-.8zM200.3 167.6h.8v1.6h-.5l-.3-.3zM207.6 166.9h6.9l.7 .7v1.9h-7.6zM219.3 164.6h.8v1.6h-.8zM219.3 167.6h.8v1.6h-.5l-.3-.3z"/>
<circle cx="183.8" cy="166" r="1.75"/>
</g>
<path d="M24.5 123h93.8v3.4h-93.8z" fill="none" stroke="#000" stroke-width=".4"/>
<path d="M24.5 126.4h93.8M24.5 123h93.8M41.6 123v3.4M58.7 123v3.4M72.2 123v3.4M79.6 123v3.4M96 123v3.4M106.6 123v3.4" fill="none" stroke="#000" stroke-width=".2"/>
<g fill="#000">
<path d="M24.6 45.5h1.5l-.5 .3v2.1a.87 .87 0 0 0 1.5-.6l-.1 .9h-2.4l.3-.1 .1-.3v-2.1z" fill-rule="evenodd"/>
<path d="M27.6 46.6a.79 .79 0 0 1 .9-.3 .79 .79 0 0 1 .6 .7v.9h.2a.39 .39 0 0 1-.4 .4 .39 .39 0 0 1-.4-.3 .52 .52 0 0 1-.5 .3 .52 .52 0 0 1-.5-.4v-.2h.5l.3 .2 .2-.1v-.6l-.5 .5h-.5l.3-.3 .7-.4v-.4a.25 .25 0 0 0-.4-.2 .25 .25 0 0 0 0 .4 .3 .3 0 0 1-.5 .2 .3 .3 0 0 1 0-.4z" fill-rule="evenodd"/>
<path d="M29.4 46.3h1.1l-.2 .3 .4 1 .3-1-.2-.3h.7l-.3 .3-.8 2.2a.39 .39 0 0 1-.6 .4 .39 .39 0 0 1-.1-.6h.2l.2 .3 .3-.6z" fill-rule="evenodd"/>
<path d="M31.9 46.6a.77 .77 0 0 1 1-.2 .77 .77 0 0 1 .4 .8h-1.1a.54 .54 0 0 0 .3 .7 .54 .54 0 0 0 .7-.2 .79 .79 0 0 1-1 .6 .79 .79 0 0 1-.5-1v-.3l1.1 .1-.2-.6a.37 .37 0 0 0-.4 .1 .37 .37 0 0 0 0 .4h-.5z" fill-rule="evenodd"/>
<path d="M33.5 46.3h.8v.5a.46 .46 0 0 1 .3-.5 .46 .46 0 0 1 .6 .2 .33 .33 0 0 1-.3 .3 .33 .33 0 0 1-.4-.1l-.2 .4v.7v.3l.2 .1h-1l.2-.1v-.3v-1.2z" fill-rule="evenodd"/>
<path d="M36.7 45.6a1.57 1.57 0 0 1 1.4 0l.1-.2v.9a.78 .78 0 0 0-.5-.6 .78 .78 0 0 0-.8 .1l.1 .4a2.11 2.11 0 0 1 1.4 1.3 1.12 1.12 0 0 1-1.8 .6l-.2 .2v-1a.91 .91 0 0 0 1.4 .6 .57 .57 0 0 0-.5-.7 .92 .92 0 0 1-.8-.6 .92 .92 0 0 1 .2-1z" fill-rule="evenodd"/>
<path d="M39.4 45.6v.7h.5v.2h-.5v1.4l.2 .1 .2-.2a.51 .51 0 0 1-.6 .4 .51 .51 0 0 1-.3-.6v-1.1h-.3z" fill-rule="evenodd"/>
<path d="M40.3 46.6a.79 .79 0 0 1 .9-.3 .79 .79 0 0 1 .5 .7v.9h.2a.39 .39 0 0 1-.4 .4 .39 .39 0 0 1-.4-.3 .52 .52 0 0 1-.5 .3 .52 .52 0 0 1-.5-.4l.1-.2h.5l.2 .2 .2-.1v-.6l-.4 .5h-.5l.2-.3 .7-.4v-.4a.25 .25 0 0 0-.3-.2 .25 .25 0 0 0-.1 .4 .3 .3 0 0 1-.4 .2 .3 .3 0 0 1 0-.4z" fill-rule="evenodd"/>
<path d="M42.5 46.5a.63 .63 0 0 1 .8-.3 .63 .63 0 0 1 .4 .7 .38 .38 0 0 1-.5 0 .38 .38 0 0 1-.1-.4l-.1-.1a.92 .92 0 0 0 .4 1.6l.3-.2a.83 .83 0 0 1-1.1 .4 .83 .83 0 0 1-.4-1.1z" fill-rule="evenodd"/>
<path d="M44 45.5h.8v1.8l.6-.6v-.2l-.2-.2h.9l-.8 .7 1 1.2h-1l.1-.2-.5-.6-.1 .1v.5l.2 .2h-1l.2-.4v-2.1z" fill-rule="evenodd"/>
<path d="M47.4 45.5h1.4l-.4 .3v2.1a.87 .87 0 0 0 .9 .1 .87 .87 0 0 0 .5-.7v.9h-2.4l.3-.1v-.3v-2.1z" fill-rule="evenodd"/>
<path d="M50.5 46.6a.77 .77 0 0 1 .9-.2 .77 .77 0 0 1 .4 .8h-1a.54 .54 0 0 0 .3 .7 .54 .54 0 0 0 .7-.2 .79 .79 0 0 1-1 .6 .79 .79 0 0 1-.6-1l.1-.3 1 .1-.1-.6a.37 .37 0 0 0-.4 .1 .37 .37 0 0 0 0 .4h-.5z" fill-rule="evenodd"/>
<path d="M52.3 46.5l.6-.2 1.1 .1v.2h-.4a.73 .73 0 0 1 0 .9 .73 .73 0 0 1-.9 .2l-.1 .3a1.38 1.38 0 0 1 1.3 .4 .74 .74 0 0 1-.9 .7 .62 .62 0 0 1-.9-.4h.3a.72 .72 0 0 0 1.2 0l-.8-.2-.2 .1-.2 .1h-.3l.3-.2a.46 .46 0 0 1-.2-.5 .46 .46 0 0 1 .4-.4l-.4-.3-.1-.3h.6v.2a.27 .27 0 0 0 .3 .4 .27 .27 0 0 0 .2-.4v-.6a.24 .24 0 0 0-.3-.2 .24 .24 0 0 0-.2 .2v.4h-.6z" fill-rule="evenodd"/>
<path d="M54.5 46.6a.77 .77 0 0 1 .9-.2 .77 .77 0 0 1 .4 .8h-1.1a.54 .54 0 0 0 .3 .7 .54 .54 0 0 0 .7-.2 .79 .79 0 0 1-.9 .6 .79 .79 0 0 1-.6-1v-.3l1.1 .1-.2-.6a.37 .37 0 0 0-.4 .1 .37 .37 0 0 0 0 .4h-.5z" fill-rule="evenodd"/>
<path d="M56 46.3h.8v.3a.59 .59 0 0 1 .8-.3 .59 .59 0 0 1 .3 .8v.9l.2 .2h-1l.2-.2v-1.2a.21 .21 0 0 0-.1-.3 .21 .21 0 0 0-.3 .2l-.1 1.3 .2 .2h-1l.2-.4v-1.3z" fill-rule="evenodd"/>
<path d="M58.9 51.9h.2l.3 .8 .3-.8h.1v1h-.1v-.9l-.3 .9h-.1l-.3-.9v.9h-.1z" fill-rule="evenodd"/>
<path d="M59.4 45.5h.8v2.4l.3 .3-.8 .1v-.3a.75 .75 0 0 1-1 .2 .75 .75 0 0 1-.3-1h.6v.6a.31 .31 0 0 0 .4 .3 .31 .31 0 0 0 .3-.3v-1a.34 .34 0 0 0-.5-.3 .34 .34 0 0 0-.2 .4v.3h-.6a.76 .76 0 0 1 .4-.8 .76 .76 0 0 1 .9 .1l-.1-.8z" fill-rule="evenodd"/>
<path d="M60.1 52.2h.5l.1 .7-.2-.1-.4 .1-.1-.2h.1a.17 .17 0 0 0 .3 .1 .17 .17 0 0 0 0-.3l-.4 .2 .1-.2 .4-.1-.1-.2-.4 .2z" fill-rule="evenodd"/>
<path d="M60.9 52l.1-.1v.2h.1l-.1 .1v.5l.1 .2-.2-.1-.1-.6z" fill-rule="evenodd"/>
<path d="M61.3 52.2l.3-.1 .3 .2v.3h-.6l.1 .2 .5-.1a.36 .36 0 0 1-.5 .2 .36 .36 0 0 1-.2-.5h.5l-.2-.2-.3 .2z" fill-rule="evenodd"/>
<path d="M62 52.1l.1 .2 .3-.1-.2 .2v.5h-.2z" fill-rule="evenodd"/>
<path d="M62.5 51.9h.1v.1h-.1z" fill-rule="evenodd"/>
<path d="M62.5 52.1h.1v.8h-.1z" fill-rule="evenodd"/>
<path d="M62.9 52.2h.5l.1 .7-.2-.1-.4 .1-.1-.2h.1a.17 .17 0 0 0 .3 .1 .17 .17 0 0 0 0-.3l-.4 .2 .1-.2 .4-.1-.1-.2-.4 .2z" fill-rule="evenodd"/>
<path d="M63.6 51.9h.2v1h-.2z" fill-rule="evenodd"/>
<path d="M66.8 51.9h.2v.9h.5v.1h-.7z" fill-rule="evenodd"/>
<path d="M66.8 56h.7v.1h-.5v.3h.5v.1h-.5v.5h-.2z" fill-rule="evenodd"/>
<path d="M67.7 59.9h.1v.2h-.1z" fill-rule="evenodd"/>
<path d="M67.7 56.9h.1v.1h-.1z" fill-rule="evenodd"/>
<path d="M68 59.1l.4-.1a.16 .16 0 0 1 .2 .1 .16 .16 0 0 1 0 .2 .21 .21 0 0 0-.3-.2 .21 .21 0 0 0-.1 .3l.1 .1a.36 .36 0 0 1 .4 .5 .36 .36 0 0 1-.6 0l-.2-.3h.1a.24 .24 0 0 0 .3 .3 .24 .24 0 0 0 .2-.4l-.5-.1z" fill-rule="evenodd"/>
<path d="M67.7 52.2h.5l.1 .7-.2-.1-.4 .1-.1-.2h.1a.17 .17 0 0 0 .2 .1 .17 .17 0 0 0 .1-.3l-.4 .2 .1-.2 .4-.1-.1-.2-.4 .2z" fill-rule="evenodd"/>
<path d="M68.3 52.1h.2l.2 .6 .2-.6h.1l-.5 1.1-.1-.1 .2-.2z" fill-rule="evenodd"/>
<path d="M68 56h.3a.31 .31 0 0 1 .4 .3 .31 .31 0 0 1-.3 .3h-.3v.4h-.1v-.5l.5-.1 .1-.1-.1-.2h-.4v.4h-.1z" fill-rule="evenodd"/>
<path d="M68.9 59h.1v.2h-.1z" fill-rule="evenodd"/>
<path d="M68.9 59.3h.1v.8h-.1z" fill-rule="evenodd"/>
<path d="M69.2 59h.1v1.1h-.1z" fill-rule="evenodd"/>
<path d="M69 56.3h.5v.7l-.1-.1-.4 .1-.2-.2h.2a.17 .17 0 0 0 .2 .1 .17 .17 0 0 0 .1-.3l-.4 .2 .1-.2 .4-.1-.1-.2-.4 .2z" fill-rule="evenodd"/>
<path d="M69.2 52.2l.3-.1 .3 .2v.3h-.6l.1 .2 .5-.1a.36 .36 0 0 1-.5 .2 .36 .36 0 0 1-.2-.5h.5l-.2-.2-.3 .2z" fill-rule="evenodd"/>
<path d="M69.7 56.3h.4l.1 .1-.1 .1a.14 .14 0 0 0-.2-.2 .14 .14 0 0 0-.1 .2h.2a.28 .28 0 0 1 .2 .4 .28 .28 0 0 1-.3 .2 .28 .28 0 0 1-.3-.3h.2a.16 .16 0 0 0 .1 .2 .18 .18 0 0 0 .2-.3l-.4-.1z" fill-rule="evenodd"/>
<path d="M69.9 52.1l.1 .2 .3-.1-.2 .2v.5h-.2z" fill-rule="evenodd"/>
<path d="M70.3 59.4l.3-.1 .2 .2h-.1a.14 .14 0 0 0-.2-.1 .14 .14 0 0 0-.1 .2h.1a.28 .28 0 0 1 .2 .3 .28 .28 0 0 1-.3 .3 .28 .28 0 0 1-.2-.4h.1a.16 .16 0 0 0 .2 .2 .16 .16 0 0 0 .1-.2l-.4-.2z" fill-rule="evenodd"/>
<path d="M70.4 56.1l.2-.1v.3h.1h-.1v.5l.1 .2-.3-.1-.1-.6z" fill-rule="evenodd"/>
<path d="M70.9 56.3l.3-.1 .2 .3v.2h-.5l.1 .2 .4-.1a.36 .36 0 0 1-.4 .2 .36 .36 0 0 1-.2-.4h.5l-.2-.3-.3 .3z" fill-rule="evenodd"/>
<path d="M71 59.4l.4-.1 .2 .2-.2 .1a.21 .21 0 0 0-.3-.1 .21 .21 0 0 0 0 .4 .21 .21 0 0 0 .4-.1h.1a.37 .37 0 0 1-.6 .2 .37 .37 0 0 1 0-.6z" fill-rule="evenodd"/>
<path d="M72.2 59.4l.3-.1 .3 .2v.2h-.6l.2 .3 .4-.2a.36 .36 0 0 1-.4 .3 .36 .36 0 0 1-.3-.5h.6l-.2-.2-.4 .2z" fill-rule="evenodd"/>
<path d="M73 59.4l.3-.1 .3 .2v.2h-.6l.2 .3 .4-.2a.36 .36 0 0 1-.4 .3 .36 .36 0 0 1-.3-.5h.6l-.2-.2-.4 .2z" fill-rule="evenodd"/>
<path d="M77.6 51.9h.8v.1h-.3v.9h-.2v-.9h-.3z" fill-rule="evenodd"/>
<path d="M78.5 51.9h.2v.3l.2-.1 .2 .2 .1 .6h-.2v-.5l-.1-.2-.2 .1v.6h-.2z" fill-rule="evenodd"/>
<path d="M79.3 51.9h.2v.1h-.2z" fill-rule="evenodd"/>
<path d="M79.3 52.1h.2v.8h-.2z" fill-rule="evenodd"/>
<path d="M79.7 52.2h.4l.2 .2h-.2a.21 .21 0 0 0-.3 0 .21 .21 0 0 0 0 .3 .21 .21 0 0 0 .3-.1h.2a.37 .37 0 0 1-.6 .2 .37 .37 0 0 1 0-.6z" fill-rule="evenodd"/>
<path d="M80.4 51.9h.1v.5l.5-.3-.3 .3 .3 .5h-.2l-.2-.4-.1 .4h-.1z" fill-rule="evenodd"/>
<path d="M81.1 52.1l.6 .1v.7h-.1v-.5l-.2-.2-.2 .2v.5h-.1z" fill-rule="evenodd"/>
<path d="M81.9 52.2l.4-.1 .2 .2v.3h-.5l.1 .2 .4-.1a.36 .36 0 0 1-.4 .2 .36 .36 0 0 1-.2-.5h.5l-.2-.2-.3 .2z" fill-rule="evenodd"/>
<path d="M82.7 52.2h.4l.1 .1-.1 .1a.14 .14 0 0 0-.2-.2 .14 .14 0 0 0-.1 .2h.2a.28 .28 0 0 1 .2 .4 .28 .28 0 0 1-.3 .2 .28 .28 0 0 1-.3-.3h.2a.16 .16 0 0 0 .1 .2 .18 .18 0 0 0 .2-.3l-.4-.1z" fill-rule="evenodd"/>
<path d="M83.4 52.2h.4l.1 .1-.1 .1a.14 .14 0 0 0-.1-.2 .14 .14 0 0 0-.1 .2h.1a.28 .28 0 0 1 .2 .4 .28 .28 0 0 1-.3 .2 .28 .28 0 0 1-.2-.3h.1a.16 .16 0 0 0 .2 .2 .16 .16 0 0 0 .1-.3l-.4-.1z" fill-rule="evenodd"/>
<path d="M92.4 51.9h.4a.52 .52 0 0 1 .5 .5 .52 .52 0 0 1-.5 .5h-.4v-.1h.4a.4 .4 0 0 0 .3-.4 .4 .4 0 0 0-.3-.4h-.2v.8h-.2z" fill-rule="evenodd"/>
<path d="M93.5 51.9h.1v.1h-.1z" fill-rule="evenodd"/>
<path d="M93.5 52.1h.1v.8h-.1z" fill-rule="evenodd"/>
<path d="M93.8 52.2l.4-.1 .2 .2v.3h-.5l.1 .2 .4-.1a.36 .36 0 0 1-.4 .2 .36 .36 0 0 1-.3-.5h.6l-.2-.2-.4 .2z" fill-rule="evenodd"/>
<path d="M94.6 51.9h.1v1h-.1z" fill-rule="evenodd"/>
<path d="M95 52.2l.3-.1 .2 .2v.3h-.5l.1 .2 .4-.1a.36 .36 0 0 1-.4 .2 .36 .36 0 0 1-.2-.5h.5l-.2-.2-.3 .2z" fill-rule="evenodd"/>
<path d="M95.8 52.2h.4l.1 .2h-.1a.21 .21 0 0 0-.3 0 .21 .21 0 0 0 0 .3 .21 .21 0 0 0 .3-.1h.1a.37 .37 0 0 1-.6 .2 .37 .37 0 0 1 .1-.6z" fill-rule="evenodd"/>
<path d="M96.4 52l.2-.1v.2h.1l-.1 .1v.5l.1 .2-.2-.1-.1-.6h-.1z" fill-rule="evenodd"/>
<path d="M96.8 52.1l.1 .2 .3-.1-.2 .2-.1 .5h-.1z" fill-rule="evenodd"/>
<path d="M97.3 51.9h.1v.1h-.1z" fill-rule="evenodd"/>
<path d="M97.3 52.1h.1v.8h-.1z" fill-rule="evenodd"/>
<path d="M97.7 52.2h.4l.1 .2h-.1a.21 .21 0 0 0-.3 0 .21 .21 0 0 0 0 .3 .21 .21 0 0 0 .3-.1h.1a.37 .37 0 0 1-.6 .2 .37 .37 0 0 1 .1-.6z" fill-rule="evenodd"/>
<path d="M101.1 51.9h.8v.1h-.3v.9h-.1v-.9h-.4z" fill-rule="evenodd"/>
<path d="M101.2 56h.4a.31 .31 0 0 1 .4 .3 .31 .31 0 0 1-.4 .3h-.3v.4h-.1v-.5l.5-.1 .2-.1-.2-.2h-.4v.4h-.1z" fill-rule="evenodd"/>
<path d="M102 52.1h.1l.2 .6 .2-.6h.1l-.5 1.1-.1-.1 .2-.2z" fill-rule="evenodd"/>
<path d="M102 59.4l.4-.1 .2 .2v.2h-.5l.1 .3 .4-.2a.36 .36 0 0 1-.4 .3 .36 .36 0 0 1-.2-.5h.5l-.2-.2-.3 .2z" fill-rule="evenodd"/>
<path d="M102.2 56.3h.5l.1 .7-.2-.1-.3 .1-.2-.2h.1a.17 .17 0 0 0 .3 .1 .17 .17 0 0 0 .1-.3l-.5 .2 .1-.2 .4-.1-.1-.2-.4 .2z" fill-rule="evenodd"/>
<path d="M103 56.3h.4l.1 .1-.1 .1a.14 .14 0 0 0-.2-.2 .14 .14 0 0 0-.1 .2h.1a.28 .28 0 0 1 .3 .4 .28 .28 0 0 1-.4 .2 .28 .28 0 0 1-.2-.3h.1a.16 .16 0 0 0 .2 .2 .16 .16 0 0 0 .1-.3l-.3-.1z" fill-rule="evenodd"/>
<path d="M102.7 52.1l.1 .1a.34 .34 0 0 1 .6 .3 .34 .34 0 0 1-.6 .3v.4h-.1v-.7h.1a.25 .25 0 0 0 .4 .3 .25 .25 0 0 0 0-.5l-.2-.1-.3 .3z" fill-rule="evenodd"/>
<path d="M102.8 59.4l.6-.1v.7a.32 .32 0 0 1-.2 .4 .32 .32 0 0 1-.4-.3l.3 .2 .2-.2v-.1l-.2 .1-.3-.1-.1-.3h.2a.24 .24 0 0 0 .3 .2 .24 .24 0 0 0 .1-.4 .24 .24 0 0 0-.4 0v.2h-.2z" fill-rule="evenodd"/>
<path d="M103.6 52.2l.3-.1 .2 .2 .1 .3h-.6l.1 .2 .4-.1a.36 .36 0 0 1-.4 .2 .36 .36 0 0 1-.2-.5h.5l-.2-.2-.3 .2z" fill-rule="evenodd"/>
<path d="M103.7 56.1l.1-.1v.3h.1h-.1v.5l.2 .2-.3-.1v-.6h-.1z" fill-rule="evenodd"/>
<path d="M103.6 59.4l.4-.1 .2 .2v.2h-.5l.1 .3 .4-.2a.36 .36 0 0 1-.4 .3 .36 .36 0 0 1-.2-.5h.5l-.2-.2-.3 .2z" fill-rule="evenodd"/>
<path d="M104.1 56.3l.3-.1 .3 .3v.2h-.5l.1 .2 .4-.1a.36 .36 0 0 1-.4 .2 .36 .36 0 0 1-.3-.4h.6l-.2-.3-.4 .3z" fill-rule="evenodd"/>
<path d="M105.3 56h.2l.3 .8 .3-.8h.2v1h-.2v-.9l-.3 .9h-.1l-.3-.9v.9h-.1z" fill-rule="evenodd"/>
<path d="M106.5 56.3h.5l.1 .7-.2-.1-.3 .1-.2-.2h.2a.17 .17 0 0 0 .2 .1 .17 .17 0 0 0 .1-.3l-.5 .2 .1-.2 .4-.1-.1-.2-.4 .2z" fill-rule="evenodd"/>
<path d="M107.3 56.3h.4l.1 .1-.1 .1a.14 .14 0 0 0-.2-.2 .14 .14 0 0 0-.1 .2h.1a.28 .28 0 0 1 .3 .4 .28 .28 0 0 1-.4 .2 .28 .28 0 0 1-.2-.3h.1a.16 .16 0 0 0 .2 .2 .16 .16 0 0 0 .1-.3l-.3-.1z" fill-rule="evenodd"/>
<path d="M108 56h.1v.6l.5-.3-.3 .2 .3 .5h-.2l-.2-.4-.1 .4h-.1z" fill-rule="evenodd"/>
<path d="M112.2 52l.5-.1 .2 .1 .1 .2h-.2a.4 .4 0 0 0-.5-.1 .4 .4 0 0 0 0 .6 .4 .4 0 0 0 .5 0v-.2h-.3v-.1h.5v.3a.56 .56 0 0 1-.8 .1 .56 .56 0 0 1 0-.8z" fill-rule="evenodd"/>
<path d="M112.2 59.2l.5-.2 .2 .2 .1 .1-.2 .1a.4 .4 0 0 0-.5-.1 .4 .4 0 0 0 0 .6 .4 .4 0 0 0 .5 0v-.2h-.3v-.2h.5v.4a.56 .56 0 0 1-.8 .1 .56 .56 0 0 1 0-.8z" fill-rule="evenodd"/>
<path d="M113.2 52.2l.3-.1 .3 .2v.3h-.6l.2 .2 .4-.1a.36 .36 0 0 1-.4 .2 .36 .36 0 0 1-.3-.5h.6l-.2-.2-.4 .2z" fill-rule="evenodd"/>
<path d="M113.2 59l.7 .2-.1 .3 .1 .3-.1 .2-.6 .1v-.1l.5-.1 .1-.1-.1-.2h-.4v.4h-.1v-.5h.5l.1-.2-.1-.1h-.4v.3h-.1z" fill-rule="evenodd"/>
<path d="M114 52.1l.1 .2 .3-.1-.3 .2v.5h-.1z" fill-rule="evenodd"/>
<path d="M114.4 51.9h.2v.3a.34 .34 0 0 1 .5 .3 .34 .34 0 0 1-.5 .3l-.2 .1v-.4h.2a.24 .24 0 0 0 .3 .3 .25 .25 0 0 0 0-.5l-.2-.1-.3 .3z" fill-rule="evenodd"/>
<path d="M114.1 59h.5a.29 .29 0 0 1 .4 .3 .29 .29 0 0 1-.3 .3l.3 .5h-.1a.5 .5 0 0 0-.6-.5v.5h-.2v-.6h.6l.1-.2-.5-.1v.3h-.2z" fill-rule="evenodd"/>
<path d="M115.3 52.2l.3-.1 .3 .2v.3h-.6l.1 .2 .5-.1a.36 .36 0 0 1-.5 .2 .36 .36 0 0 1-.2-.5h.5l-.2-.2-.3 .2z" fill-rule="evenodd"/>
<path d="M116 52.1l.1 .2 .3-.1-.2 .2v.5h-.2z" fill-rule="evenodd"/>
<path d="M58.9 77.5h.3a.31 .31 0 0 1 .4 .3 .31 .31 0 0 1-.3 .3h-.3v.4h-.1v-.5h.5l.1-.2-.1-.2h-.4v.4h-.1z" fill-rule="evenodd"/>
<path d="M58.9 74.6l.6-.2 .2 .3-.2 .1a.28 .28 0 0 0-.4-.1 .28 .28 0 0 0 0 .4 .28 .28 0 0 0 .4 .1l.2-.1a.5 .5 0 0 1-.8 .3 .5 .5 0 0 1 0-.8z" fill-rule="evenodd"/>
<path d="M58.9 65.3l.6-.1 .2 .3h-.2a.28 .28 0 0 0-.4 0 .28 .28 0 0 0 0 .4 .28 .28 0 0 0 .4 0h.2a.5 .5 0 0 1-.8 .2 .5 .5 0 0 1 0-.8z" fill-rule="evenodd"/>
<path d="M59 69.9l.5-.1 .2 .2-.1 .1a.34 .34 0 0 0-.5 0 .34 .34 0 0 0 0 .5 .34 .34 0 0 0 .5-.1h.1a.5 .5 0 0 1-.7 .2 .5 .5 0 0 1 0-.8z" fill-rule="evenodd"/>
<path d="M59.8 77.8l.1 .1 .3-.1-.3 .2v.5h-.1z" fill-rule="evenodd"/>
<path d="M59.9 70.2a.37 .37 0 0 1 .6 0 .37 .37 0 0 1-.2 .6 .37 .37 0 0 1-.5-.3h.2a.25 .25 0 0 0 .3 .2 .25 .25 0 0 0 .1-.4 .25 .25 0 0 0-.4 0v.2h-.2z" fill-rule="evenodd"/>
<path d="M60 74.8a.39 .39 0 0 1 .6 .1 .39 .39 0 0 1-.3 .5 .39 .39 0 0 1-.5-.3h.2a.19 .19 0 0 0 .3 .1 .19 .19 0 0 0 .1-.3 .19 .19 0 0 0-.3 .1l-.3 .1z" fill-rule="evenodd"/>
<path d="M60 65.5a.39 .39 0 0 1 .6 .2 .39 .39 0 0 1-.3 .5 .39 .39 0 0 1-.5-.3h.2a.19 .19 0 0 0 .3 .1 .19 .19 0 0 0 .1-.3 .19 .19 0 0 0-.3 .1l-.3 .1z" fill-rule="evenodd"/>
<path d="M60.3 77.9l.4-.1 .2 .2v.2h-.5l.1 .2 .4-.1a.36 .36 0 0 1-.4 .2 .36 .36 0 0 1-.3-.4h.6l-.2-.2-.4 .2z" fill-rule="evenodd"/>
<path d="M60.7 70.1l.1 .1 .3-.1-.3 .2v.5h-.1z" fill-rule="evenodd"/>
<path d="M60.8 74.7h.1v.1a.34 .34 0 0 1 .5 .1 .34 .34 0 0 1 0 .4 .34 .34 0 0 1-.4 .1v.3h-.2v-.6h.2v.1a.18 .18 0 0 0 .3 0 .18 .18 0 0 0-.1-.2 .18 .18 0 0 0-.2 .1h-.2z" fill-rule="evenodd"/>
<path d="M60.8 65.5h.1v.1a.34 .34 0 0 1 .5 0 .34 .34 0 0 1 0 .5 .34 .34 0 0 1-.4 0v.4h-.2v-.7l.2 .1a.17 .17 0 0 0 .2 .1 .17 .17 0 0 0 0-.3 .17 .17 0 0 0-.2 .1h-.2z" fill-rule="evenodd"/>
<path d="M61.1 77.8l.1 .1a.34 .34 0 0 1 .5 .3 .34 .34 0 0 1-.5 .3v.3h-.1v-.6h.1a.24 .24 0 0 0 .3 .2 .24 .24 0 0 0 .1-.4l-.3-.1-.2 .3z" fill-rule="evenodd"/>
<path d="M61.2 70.2l.3-.1 .3 .2v.2h-.6l.2 .2 .4-.1a.36 .36 0 0 1-.5 .2 .36 .36 0 0 1-.2-.4h.6l-.2-.2-.4 .2z" fill-rule="evenodd"/>
<path d="M61.9 77.8l.1 .1 .3-.1-.3 .2v.5h-.1z" fill-rule="evenodd"/>
<path d="M61.6 74.7h.2v.1a.34 .34 0 0 1 .5 .1 .34 .34 0 0 1 0 .4 .34 .34 0 0 1-.5 .1v.3h-.2v-.6h.2l.1 .1a.19 .19 0 0 0 .2 0 .19 .19 0 0 0 0-.2 .19 .19 0 0 0-.3 .1h-.2z" fill-rule="evenodd"/>
<path d="M61.6 65.5h.2v.1a.34 .34 0 0 1 .5 0 .34 .34 0 0 1 0 .5 .34 .34 0 0 1-.5 0v.4h-.2v-.7l.2 .1a.17 .17 0 0 0 .3 .1 .17 .17 0 0 0 0-.3 .17 .17 0 0 0-.3 .1h-.2z" fill-rule="evenodd"/>
<path d="M62.4 77.9l.3-.1 .3 .2v.2h-.6l.2 .2 .4-.1a.36 .36 0 0 1-.5 .2 .36 .36 0 0 1-.2-.4h.6l-.2-.2-.4 .2z" fill-rule="evenodd"/>
<path d="M62.6 74.8h.4l.2 .3-.5 .1 .1 .1h.3a.36 .36 0 0 1-.4 .2 .36 .36 0 0 1-.2-.5h.5l-.2-.2-.3 .2z" fill-rule="evenodd"/>
<path d="M62.6 65.6l.4-.1 .2 .4-.5 .1 .1 .1 .3-.1a.36 .36 0 0 1-.4 .2 .36 .36 0 0 1-.2-.4h.5l-.2-.2-.3 .2z" fill-rule="evenodd"/>
<path d="M63.2 77.9l.6-.1v.6a.33 .33 0 0 1-.3 .4 .33 .33 0 0 1-.4-.2l.3 .1 .2-.1v-.2l-.2 .1-.2-.1-.1-.2h.1a.24 .24 0 0 0 .4 .1 .24 .24 0 0 0 0-.3 .24 .24 0 0 0-.3 0l-.1 .2h-.1z" fill-rule="evenodd"/>
<path d="M63.3 74.7h.2v.1l.3-.1-.1 .2h-.2v.6h-.2z" fill-rule="evenodd"/>
<path d="M63.3 65.5l.2 .1 .3-.1-.1 .2h-.2v.5h-.2z" fill-rule="evenodd"/>
<path d="M66.8 74.4h.2v1.1h-.2z" fill-rule="evenodd"/>
<path d="M66.8 65.2h.7v.2h-.5v.2h.5v.2h-.5v.4h-.2z" fill-rule="evenodd"/>
<path d="M66.8 62.1h.7v.1h-.5v.4h.5v.1h-.5v.5h-.2z" fill-rule="evenodd"/>
<path d="M66.8 59h.7v.2h-.5v.3h.5v.1h-.5v.5h-.2z" fill-rule="evenodd"/>
<path d="M67.6 66h.2v.2h-.2z" fill-rule="evenodd"/>
<path d="M67.7 63h.1v.2h-.1z" fill-rule="evenodd"/>
<path d="M67.2 74.7l.7 .1v.7h-.2v-.6l-.1-.1-.2 .2v.5h-.2z" fill-rule="evenodd"/>
<path d="M67.9 62.1h.3l.2 .9 .3-.9h.2v1.1h-.1v-.9l-.3 .9h-.1l-.3-.9v.9h-.2z" fill-rule="evenodd"/>
<path d="M68 65.3l.6-.1 .2 .3h-.2a.28 .28 0 0 0-.4 0 .28 .28 0 0 0 0 .4 .28 .28 0 0 0 .4 0h.2a.5 .5 0 0 1-.8 .2 .5 .5 0 0 1 0-.8z" fill-rule="evenodd"/>
<path d="M68.1 74.7l.6 .1 .1 .7h-.2v-.5l-.1-.2-.2 .2v.5h-.2z" fill-rule="evenodd"/>
<path d="M69 74.8h.5l.1 .3-.5 .1 .2 .1h.3a.36 .36 0 0 1-.4 .2 .36 .36 0 0 1-.3-.5h.5l-.1-.2-.4 .2z" fill-rule="evenodd"/>
<path d="M69 65.5h.2v.5l.1 .1 .1-.1 .1-.5h.2v.7h-.2v-.1l-.4 .1z" fill-rule="evenodd"/>
<path d="M69.5 59h.2v.6l.4-.3-.3 .3 .3 .5h-.1l-.3-.4v.4h-.2z" fill-rule="evenodd"/>
<path d="M69.2 62.5h.5l.1 .7-.2-.1-.4 .1-.1-.2h.1a.17 .17 0 0 0 .3 .1 .17 .17 0 0 0 0-.3l-.4 .2 .1-.2 .4-.1-.1-.2-.4 .1z" fill-rule="evenodd"/>
<path d="M69.9 62.5l.4-.1 .2 .2h-.2a.14 .14 0 0 0-.1-.2 .16 .16 0 0 0-.1 .3h.1a.28 .28 0 0 1 .2 .3 .28 .28 0 0 1-.3 .2 .28 .28 0 0 1-.2-.3h.1a.16 .16 0 0 0 .2 .2 .16 .16 0 0 0 .1-.2l-.3-.2z" fill-rule="evenodd"/>
<path d="M69.8 74.7h.2v.1l.3-.1-.3 .3v.5h-.2z" fill-rule="evenodd"/>
<path d="M70.6 62.1h.2v.6l.4-.3-.2 .3 .3 .5h-.2l-.2-.4-.1 .4h-.2z" fill-rule="evenodd"/>
<path d="M70.3 74.7l.5-.3v1.1h-.2v-.8l-.3 .2z" fill-rule="evenodd"/>
<path d="M71.7 59.3l.1 .1h.3l-.3 .1v.6h-.1z" fill-rule="evenodd"/>
<path d="M73.8 59.3l.5 .1 .1 .7h-.2v-.6l-.1-.1-.2 .1v.6h-.1z" fill-rule="evenodd"/>
<path d="M77.7 77.6l.2-.1a.51 .51 0 0 1 .4 .5 .51 .51 0 0 1-.5 .5l-.1-.2-.1-.3h.2a.26 .26 0 0 0 0 .4 .26 .26 0 0 0 .3 0 .26 .26 0 0 0 .1-.4 .26 .26 0 0 0-.1-.3 .26 .26 0 0 0-.3 0 .26 .26 0 0 0 0 .3h-.2z" fill-rule="evenodd"/>
<path d="M77.7 69.9l.2-.1a.51 .51 0 0 1 .4 .6 .51 .51 0 0 1-.5 .4l-.1-.2-.1-.3h.2a.26 .26 0 0 0 0 .4 .26 .26 0 0 0 .3 0 .26 .26 0 0 0 .1-.4 .26 .26 0 0 0-.1-.3 .26 .26 0 0 0-.3 0 .26 .26 0 0 0 0 .3h-.2z" fill-rule="evenodd"/>
<path d="M77.7 62.2l.2-.1a.51 .51 0 0 1 .4 .6 .51 .51 0 0 1-.5 .4l-.1-.2-.1-.3h.2a.26 .26 0 0 0 0 .4 .26 .26 0 0 0 .3 0 .26 .26 0 0 0 .1-.4 .26 .26 0 0 0-.1-.3 .26 .26 0 0 0-.3 0 .26 .26 0 0 0 0 .3h-.2z" fill-rule="evenodd"/>
<path d="M77.8 74.5a.5 .5 0 0 1 .5 .5 .5 .5 0 0 1-.5 .5l-.2-.5h.2l.2 .3 .1-.5-.2-.2-.1 .4h-.2z" fill-rule="evenodd"/>
<path d="M77.7 65.3l.1-.1a.5 .5 0 0 1 .5 .5 .5 .5 0 0 1-.5 .5l-.2-.5h.2l.2 .4 .1-.5-.2-.2-.1 .3h-.2z" fill-rule="evenodd"/>
<path d="M78.5 75.3h.2v.2h-.2z" fill-rule="evenodd"/>
<path d="M78.5 66h.2v.2h-.2z" fill-rule="evenodd"/>
<path d="M78.5 78.4h.1v.1h-.1z" fill-rule="evenodd"/>
<path d="M78.5 70.7h.1v.1h-.1z" fill-rule="evenodd"/>
<path d="M78.5 63h.1v.2h-.1z" fill-rule="evenodd"/>
<path d="M78.9 62.2l.2-.1a.51 .51 0 0 1 .4 .6 .51 .51 0 0 1-.5 .4l-.2-.3v-.2h.2a.26 .26 0 0 0 0 .4 .26 .26 0 0 0 .3 0 .26 .26 0 0 0 .1-.4 .26 .26 0 0 0-.1-.3 .26 .26 0 0 0-.3 0 .26 .26 0 0 0 0 .3h-.2z" fill-rule="evenodd"/>
<path d="M79 74.5a.5 .5 0 0 1 .5 .5 .5 .5 0 0 1-.5 .5l-.2-.5h.2l.2 .3 .1-.5-.2-.2-.1 .4h-.2z" fill-rule="evenodd"/>
<path d="M78.9 65.3l.1-.1a.5 .5 0 0 1 .5 .5 .5 .5 0 0 1-.5 .5l-.2-.5h.2l.2 .4 .1-.5-.2-.2-.1 .3h-.2z" fill-rule="evenodd"/>
<path d="M78.9 70.1l.4-.3v1h-.1v-.8l-.3 .2z" fill-rule="evenodd"/>
<path d="M78.9 77.6a.36 .36 0 0 1 .6 .1 .36 .36 0 0 1-.3 .5l-.2 .2h.5v.1h-.7l.4-.4a.22 .22 0 0 0 .2-.3 .22 .22 0 0 0-.2-.2 .22 .22 0 0 0-.2 .2h-.2z" fill-rule="evenodd"/>
<path d="M79.7 74.5a.28 .28 0 0 1 .5 0 .28 .28 0 0 1-.1 .4 .32 .32 0 0 1 0 .6 .32 .32 0 0 1-.5-.3h.2a.16 .16 0 0 0 .2 .1 .16 .16 0 0 0 .1-.2 .16 .16 0 0 0-.2-.1l.2-.3h-.5z" fill-rule="evenodd"/>
<path d="M79.7 65.3a.28 .28 0 0 1 .5-.1 .28 .28 0 0 1-.1 .5 .32 .32 0 0 1 0 .5 .32 .32 0 0 1-.5-.2l.2-.1a.16 .16 0 0 0 .2 .1 .16 .16 0 0 0 .1-.2 .16 .16 0 0 0-.2 0l.2-.4-.5 .1z" fill-rule="evenodd"/>
<path d="M79.7 77.6a.27 .27 0 0 1 .5 0 .27 .27 0 0 1-.1 .4 .32 .32 0 0 1 0 .5 .32 .32 0 0 1-.5-.2l.2-.1a.21 .21 0 0 0 .2 .2 .21 .21 0 0 0 .2-.2 .21 .21 0 0 0-.3-.2v-.1a.18 .18 0 0 0 .2-.1 .18 .18 0 0 0-.2-.2 .18 .18 0 0 0-.1 .2h-.2z" fill-rule="evenodd"/>
<path d="M79.7 69.9a.27 .27 0 0 1 .5 0 .27 .27 0 0 1-.1 .4 .32 .32 0 0 1 0 .5 .32 .32 0 0 1-.5-.3h.2a.21 .21 0 0 0 .3 .2 .21 .21 0 0 0 0-.3 .21 .21 0 0 0-.3 .1h-.2l.2-.2-.1-.2h.1a.17 .17 0 0 0 .2 .1 .17 .17 0 0 0 .1-.3 .17 .17 0 0 0-.3 .1l-.1 .1z" fill-rule="evenodd"/>
<path d="M79.7 62.4l.4-.3v1.1h-.1v-.9l-.3 .2z" fill-rule="evenodd"/>
<path d="M80.5 69.8h.6v.1h-.5v.3a.34 .34 0 0 1 .5 .2 .34 .34 0 0 1-.2 .4 .34 .34 0 0 1-.5-.2h.2a.23 .23 0 0 0 .3 .1 .23 .23 0 0 0 0-.4 .23 .23 0 0 0-.3 .1h-.2z" fill-rule="evenodd"/>
<path d="M80.6 74.4h.5v.2h-.4v.2a.35 .35 0 0 1 .4 .2 .35 .35 0 0 1-.3 .5 .35 .35 0 0 1-.4-.3h.2a.18 .18 0 0 0 .3 0 .18 .18 0 0 0 0-.3 .18 .18 0 0 0-.3 .1h-.1z" fill-rule="evenodd"/>
<path d="M80.6 65.2h.5v.2h-.4v.2a.35 .35 0 0 1 .4 .2 .35 .35 0 0 1-.3 .4 .35 .35 0 0 1-.4-.2l.2-.1a.18 .18 0 0 0 .3 .1 .18 .18 0 0 0 0-.3 .18 .18 0 0 0-.3 .1l-.1-.1z" fill-rule="evenodd"/>
<path d="M80.5 77.8l.1 .1 .3-.1 .1 .1 .4-.1 .1 .7h-.2v-.5l-.1-.1-.2 .1v.5h-.1v-.5l-.1-.1-.2 .1v.5h-.1z" fill-rule="evenodd"/>
<path d="M80.5 62.4l.5 .1 .4-.1 .1 .8h-.2v-.6l-.1-.1-.2 .1v.6h-.1v-.6l-.1-.1-.2 .1v.6h-.1z" fill-rule="evenodd"/>
<path d="M81.3 69.8h.6v.1h-.5v.3a.34 .34 0 0 1 .5 .2 .34 .34 0 0 1-.2 .4 .34 .34 0 0 1-.5-.2h.2a.23 .23 0 0 0 .3 .1 .23 .23 0 0 0 0-.4 .23 .23 0 0 0-.3 .1h-.2z" fill-rule="evenodd"/>
<path d="M81.3 74.7l.1 .1 .3-.1 .2 .1 .3-.1 .1 .8h-.2l-.1-.7-.1 .1v.6h-.2l-.1-.7-.1 .1-.1 .6h-.1z" fill-rule="evenodd"/>
<path d="M81.3 65.5l.1 .1 .3-.1 .2 .1 .3-.1 .1 .7h-.2l-.1-.6-.1 .1v.5h-.2l-.1-.6-.1 .1-.1 .5h-.1z" fill-rule="evenodd"/>
<path d="M81.7 77.8l.5 .1 .4-.1 .1 .7h-.2v-.5l-.1-.1-.2 .1v.5h-.1v-.5l-.1-.1-.2 .1v.5h-.1z" fill-rule="evenodd"/>
<path d="M81.7 62.4l.5 .1 .4-.1 .1 .8h-.2v-.6l-.1-.1-.2 .1v.6h-.1v-.6l-.1-.1-.2 .1v.6h-.1z" fill-rule="evenodd"/>
<path d="M82.1 70.1l.1 .1 .1-.1 .3 .1 .4-.1 .1 .7h-.2v-.5l-.1-.1-.2 .1v.5h-.1v-.5l-.1-.1-.2 .1v.5h-.1z" fill-rule="evenodd"/>
<path d="M82.5 74.7l.2 .1 .2-.1 .3 .1 .3-.1 .1 .8h-.2l-.1-.7-.1 .1v.6h-.2l-.1-.7-.2 .1v.6h-.2z" fill-rule="evenodd"/>
<path d="M82.5 65.5l.2 .1 .2-.1 .3 .1 .3-.1 .1 .7h-.2l-.1-.6-.1 .1v.5h-.2l-.1-.6-.2 .1v.5h-.2z" fill-rule="evenodd"/>
<path d="M83.2 70.1l.2 .1 .1-.1 .3 .1 .4-.1 .1 .7h-.2v-.5l-.1-.1-.2 .1v.5h-.1v-.5l-.1-.1-.2 .1v.5h-.2z" fill-rule="evenodd"/>
<path d="M84.4 74.4h.1l-.1 .7 .1 .7a.92 .92 0 0 1-.1-1.4z" fill-rule="evenodd"/>
<path d="M84.4 65.2h.1l-.1 .7 .1 .6a.92 .92 0 0 1-.1-1.3z" fill-rule="evenodd"/>
<path d="M84.7 74.7l.5-.3v1.1h-.2v-.8l-.3 .2z" fill-rule="evenodd"/>
<path d="M84.7 65.5l.5-.3v1h-.2v-.7l-.3 .1z" fill-rule="evenodd"/>
<path d="M85.5 75.3h.2v.2h-.2z" fill-rule="evenodd"/>
<path d="M85.5 66h.2v.2h-.2z" fill-rule="evenodd"/>
<path d="M86 74.5a.5 .5 0 0 1 .5 .5 .5 .5 0 0 1-.5 .5l-.1-.5h.2l.1 .3 .1-.5-.2-.2v.4h-.2z" fill-rule="evenodd"/>
<path d="M86 65.3v-.1a.5 .5 0 0 1 .5 .5 .5 .5 0 0 1-.5 .5l-.1-.5h.2l.1 .4 .1-.5-.2-.2v.3h-.2z" fill-rule="evenodd"/>
<path d="M86.7 74.5h.1a.5 .5 0 0 1 .5 .5 .5 .5 0 0 1-.5 .5l-.2-.5h.3l.1 .3 .1-.5-.2-.2v.4h-.3z" fill-rule="evenodd"/>
<path d="M86.7 65.3l.1-.1a.5 .5 0 0 1 .5 .5 .5 .5 0 0 1-.5 .5l-.2-.5h.3l.1 .4 .1-.5-.2-.2v.3h-.3z" fill-rule="evenodd"/>
<path d="M87.6 74.8a.39 .39 0 0 1 .6 .1 .39 .39 0 0 1-.3 .5 .39 .39 0 0 1-.5-.3h.2a.19 .19 0 0 0 .3 .1 .19 .19 0 0 0 .1-.3 .19 .19 0 0 0-.3 .1l-.3 .1z" fill-rule="evenodd"/>
<path d="M87.6 65.5a.39 .39 0 0 1 .6 .2 .39 .39 0 0 1-.3 .5 .39 .39 0 0 1-.5-.3h.2a.19 .19 0 0 0 .3 .1 .19 .19 0 0 0 .1-.3 .19 .19 0 0 0-.3 .1l-.3 .1z" fill-rule="evenodd"/>
<path d="M88.3 74.7h.6l-.4 .6h.4v.2h-.6l.4-.6h-.4z" fill-rule="evenodd"/>
<path d="M88.3 65.5h.6l-.4 .6h.4v.1h-.6l.4-.6h-.4z" fill-rule="evenodd"/>
<path d="M89 74.4l.2 .1 .2 .5-.2 .8h-.2l.2-.7z" fill-rule="evenodd"/>
<path d="M89 65.2l.2 .1 .2 .4-.2 .8h-.2l.2-.6z" fill-rule="evenodd"/>
<path d="M92.4 77.5h.7v.1h-.5v.3h.5v.2h-.5v.4h-.2z" fill-rule="evenodd"/>
<path d="M92.4 69.8h.7v.1h-.5v.4h.5v.1h-.5v.4h-.2z" fill-rule="evenodd"/>
<path d="M93.3 77.5h.5a.29 .29 0 0 1 .3 .2 .29 .29 0 0 1-.2 .4l.3 .4h-.1a.5 .5 0 0 0-.6-.4v.4h-.2v-.5l.6-.1 .1-.2-.5-.1v.4h-.2z" fill-rule="evenodd"/>
<path d="M93.3 69.8h.5a.29 .29 0 0 1 .3 .3 .29 .29 0 0 1-.2 .3l.3 .4h-.1a.5 .5 0 0 0-.6-.4v.4h-.2v-.5l.6-.1 .1-.2-.5-.1v.4h-.2z" fill-rule="evenodd"/>
<path d="M94.7 77.5h.1v.7h.2l-.2 .3h-.1v-.2h-.4v-.1h.4v-.5l-.4 .5z" fill-rule="evenodd"/>
<path d="M94.7 69.8h.1v.7h.2l-.2 .3h-.1v-.2h-.4v-.1h.4v-.5l-.4 .5z" fill-rule="evenodd"/>
<path d="M101.3 65.3l.4-.1 .2 .2 .1 .1h-.2l-.3-.1v.2a.39 .39 0 0 1 .5 .2 .39 .39 0 0 1-.3 .5 .39 .39 0 0 1-.5-.2v-.2h.2a.19 .19 0 0 0 .2 .2 .19 .19 0 0 0 .1-.3l-.5-.2z" fill-rule="evenodd"/>
<path d="M101.3 62.2l.4-.1a.16 .16 0 0 1 .2 .1 .16 .16 0 0 1-.1 .2 .22 .22 0 0 0-.2-.3 .22 .22 0 0 0-.1 .4h.1a.36 .36 0 0 1 .3 .6 .36 .36 0 0 1-.6 0l-.1-.3h.1a.24 .24 0 0 0 .3 .3 .24 .24 0 0 0 .1-.4l-.4-.1z" fill-rule="evenodd"/>
<path d="M101.2 59h.1v1h.5v.1h-.6z" fill-rule="evenodd"/>
<path d="M101.2 77.5h.4a.52 .52 0 0 1 .5 .5 .52 .52 0 0 1-.5 .5h-.4v-.1h.4a.4 .4 0 0 0 .3-.4 .4 .4 0 0 0-.3-.4h-.3v.8h-.1z" fill-rule="evenodd"/>
<path d="M101.2 69.8h.4a.52 .52 0 0 1 .5 .5 .52 .52 0 0 1-.5 .5h-.4v-.1h.4a.4 .4 0 0 0 .3-.4 .4 .4 0 0 0-.3-.4h-.3v.8h-.1z" fill-rule="evenodd"/>
<path d="M101.2 74.4h.3a.34 .34 0 0 1 .4 .1 .34 .34 0 0 1 0 .4l-.5 .2v.4h-.2v-.6h.5l.1-.1-.4-.2v.3h-.2z" fill-rule="evenodd"/>
<path d="M102.2 74.4h.2v1.1h-.2z" fill-rule="evenodd"/>
<path d="M102.2 65.2h.2v.2h-.2z" fill-rule="evenodd"/>
<path d="M102.2 65.5h.2v.7h-.2z" fill-rule="evenodd"/>
<path d="M102.2 77.5h.2v.1h-.2z" fill-rule="evenodd"/>
<path d="M102.2 77.8h.2v.7h-.2z" fill-rule="evenodd"/>
<path d="M102.2 69.8h.2v.2h-.2z" fill-rule="evenodd"/>
<path d="M102.2 70.1h.2v.7h-.2z" fill-rule="evenodd"/>
<path d="M102.2 62.5a.37 .37 0 0 1 .6 .1 .37 .37 0 0 1-.2 .5 .37 .37 0 0 1-.5-.3h.1a.23 .23 0 0 0 .4 .2 .23 .23 0 0 0 0-.4 .23 .23 0 0 0-.4 .1l-.1 .1z" fill-rule="evenodd"/>
<path d="M102.6 65.6l.6-.1v.7a.36 .36 0 0 1-.3 .3 .36 .36 0 0 1-.4-.2h.5v-.2l-.2 .1-.2-.1-.1-.3h.2a.18 .18 0 0 0 .3 .2 .18 .18 0 0 0 0-.3 .18 .18 0 0 0-.3 .1h-.2z" fill-rule="evenodd"/>
<path d="M102.6 77.9l.3-.1 .3 .2v.2h-.6l.2 .2 .4-.1a.36 .36 0 0 1-.5 .2 .36 .36 0 0 1-.2-.4h.6l-.2-.2-.4 .2z" fill-rule="evenodd"/>
<path d="M102.6 70.2l.3-.1 .3 .2v.2h-.6l.2 .2 .4-.1a.36 .36 0 0 1-.5 .2 .36 .36 0 0 1-.2-.4h.6l-.2-.2-.4 .2z" fill-rule="evenodd"/>
<path d="M102.6 74.8h.5l.1 .7-.6-.1-.1-.2 .3 .1 .2-.2-.5 .1 .5-.2-.1-.1h-.4z" fill-rule="evenodd"/>
<path d="M102.9 62.1h.2v1.1h-.2z" fill-rule="evenodd"/>
<path d="M103.3 77.5h.2v1h-.2z" fill-rule="evenodd"/>
<path d="M103.3 69.8h.2v1h-.2z" fill-rule="evenodd"/>
<path d="M103.3 62.5l.2-.1 .2 .1v-.4h.2v1.1l-.5-.1-.2-.2 .2-.1a.24 .24 0 0 0 .3 .2 .24 .24 0 0 0 0-.4l-.2-.1-.3 .3z" fill-rule="evenodd"/>
<path d="M103.4 74.7l.6 .1v.7h-.2v-.6l-.1-.1-.1 .2v.5h-.2z" fill-rule="evenodd"/>
<path d="M103.7 77.9l.3-.1 .3 .2v.2h-.5l.1 .2 .4-.1a.36 .36 0 0 1-.4 .2 .36 .36 0 0 1-.3-.4h.6l-.2-.2-.4 .2z" fill-rule="evenodd"/>
<path d="M103.7 70.2l.3-.1 .3 .2v.2h-.5l.1 .2 .4-.1a.36 .36 0 0 1-.4 .2 .36 .36 0 0 1-.3-.4h.6l-.2-.2-.4 .2z" fill-rule="evenodd"/>
<path d="M103.4 65.5h.7v.7h-.2v-.5l-.1-.1-.2 .1v.5h-.2z" fill-rule="evenodd"/>
<path d="M104.4 59.3l.5 .1 .1 .7h-.1v-.6l-.2-.1-.2 .1v.6h-.1z" fill-rule="evenodd"/>
<path d="M104.1 62.5l.3-.1 .3 .2v.2h-.5l.1 .2 .4-.1a.36 .36 0 0 1-.4 .2 .36 .36 0 0 1-.3-.4h.6l-.2-.2-.4 .2z" fill-rule="evenodd"/>
<path d="M104.3 74.8h.4l.2 .3-.5 .1 .1 .1h.4a.36 .36 0 0 1-.5 .2 .36 .36 0 0 1-.2-.5h.5l-.2-.2-.3 .2z" fill-rule="evenodd"/>
<path d="M104.3 65.6l.6-.1 .1 .7h-.7v-.2l.3 .1 .1-.1v-.1l-.4 .1 .4-.3-.1-.1-.3 .1z" fill-rule="evenodd"/>
<path d="M104.9 62.4l.1 .1 .3-.1-.3 .2v.6h-.1z" fill-rule="evenodd"/>
<path d="M104.5 77.9l.4-.1 .2 .2h-.2a.21 .21 0 0 0-.3 0 .21 .21 0 0 0 0 .3 .21 .21 0 0 0 .4 0h.1a.37 .37 0 0 1-.6 .2 .37 .37 0 0 1 0-.6z" fill-rule="evenodd"/>
<path d="M104.5 70.2l.4-.1 .2 .2h-.2a.21 .21 0 0 0-.3 0 .21 .21 0 0 0 0 .3 .21 .21 0 0 0 .4 0h.1a.37 .37 0 0 1-.6 .2 .37 .37 0 0 1 0-.6z" fill-rule="evenodd"/>
<path d="M105.1 65.2h.2v1h-.2z" fill-rule="evenodd"/>
<path d="M105.2 77.6l.1-.1v.3h.2l-.2 .1v.4l.2 .2h-.3l-.1-.6z" fill-rule="evenodd"/>
<path d="M105.2 69.9l.1-.1v.3h.2l-.2 .1v.4l.2 .2h-.3l-.1-.6z" fill-rule="evenodd"/>
<path d="M105.6 77.8l.1 .1 .3-.1-.3 .2v.5h-.1z" fill-rule="evenodd"/>
<path d="M105.6 70.1l.1 .1 .3-.1-.3 .2v.5h-.1z" fill-rule="evenodd"/>
<path d="M105.8 62.1h.2l.3 .9 .3-.9h.1v1.1h-.1v-.9l-.3 .9h-.1l-.3-.9v.9h-.1z" fill-rule="evenodd"/>
<path d="M105.2 59.4l.3-.1 .2 .1v-.4h.1v1.1l-.5-.1-.2-.2 .2-.1a.24 .24 0 0 0 .3 .3 .25 .25 0 0 0 0-.5l-.2-.1-.1 .3h-.2z" fill-rule="evenodd"/>
<path d="M106.1 77.5h.1v.1h-.1z" fill-rule="evenodd"/>
<path d="M106.1 77.8h.1v.7h-.1z" fill-rule="evenodd"/>
<path d="M106.1 69.8h.1v.2h-.1z" fill-rule="evenodd"/>
<path d="M106.1 70.1h.1v.7h-.1z" fill-rule="evenodd"/>
<path d="M106.5 77.9l.3-.1 .2 .2h-.1a.21 .21 0 0 0-.4 0 .21 .21 0 0 0 .1 .3 .21 .21 0 0 0 .3 0h.1a.37 .37 0 0 1-.6 .2 .37 .37 0 0 1 .1-.6z" fill-rule="evenodd"/>
<path d="M106.5 70.2l.3-.1 .2 .2h-.1a.21 .21 0 0 0-.4 0 .21 .21 0 0 0 .1 .3 .21 .21 0 0 0 .3 0h.1a.37 .37 0 0 1-.6 .2 .37 .37 0 0 1 .1-.6z" fill-rule="evenodd"/>
<path d="M107 62.5h.5l.1 .7-.2-.1-.4 .1-.1-.2h.1a.17 .17 0 0 0 .3 .1 .17 .17 0 0 0 0-.3l-.4 .2 .1-.2 .4-.1-.1-.2-.4 .1z" fill-rule="evenodd"/>
<path d="M107.8 62.5l.3-.1 .2 .2h-.1a.14 .14 0 0 0-.2-.2 .16 .16 0 0 0-.1 .3h.1a.28 .28 0 0 1 .2 .3 .28 .28 0 0 1-.3 .3 .28 .28 0 0 1-.2-.4h.1a.16 .16 0 0 0 .2 .2 .16 .16 0 0 0 .1-.2l-.3-.2z" fill-rule="evenodd"/>
<path d="M108.5 62.1h.1v.6l.4-.3-.2 .3 .3 .5h-.2l-.2-.4-.1 .4h-.1z" fill-rule="evenodd"/>
<path d="M112.2 74.5l.5-.1 .3 .3-.2 .1a.29 .29 0 0 0-.5-.1 .29 .29 0 0 0 0 .5 .29 .29 0 0 0 .5-.1h-.3v-.2h.5v.4a.56 .56 0 0 1-.8 .1 .56 .56 0 0 1 0-.9z" fill-rule="evenodd"/>
<path d="M112.2 65.3l.5-.1 .3 .3h-.2a.29 .29 0 0 0-.5 0 .29 .29 0 0 0 0 .4 .29 .29 0 0 0 .5 0h-.3v-.2h.5v.4a.56 .56 0 0 1-.8 0 .56 .56 0 0 1 0-.8z" fill-rule="evenodd"/>
<path d="M112.2 62.2l.5-.1 .2 .2 .1 .1h-.2a.4 .4 0 0 0-.5 0 .4 .4 0 0 0 0 .6 .4 .4 0 0 0 .5-.1v-.2h-.3v-.1h.5v.4a.56 .56 0 0 1-.8 0 .56 .56 0 0 1 0-.8z" fill-rule="evenodd"/>
<path d="M113.2 62.1l.7 .1-.1 .4 .1 .3-.1 .2-.6 .1v-.2h.5l.1-.1-.1-.2h-.4v.3h-.1v-.4l.5-.1 .1-.1-.1-.1-.4-.1v.4h-.1z" fill-rule="evenodd"/>
<path d="M113.2 74.4l.7 .1 .1 .2-.2 .2a.28 .28 0 0 1 .2 .3 .28 .28 0 0 1-.3 .3h-.5v-.2h.5l.1-.1-.1-.2h-.3v.3h-.2v-.5h.5l.1-.1-.4-.1v.2h-.2z" fill-rule="evenodd"/>
<path d="M113.2 65.2l.7 .1 .1 .2-.2 .2a.28 .28 0 0 1 .2 .3 .28 .28 0 0 1-.3 .2h-.5v-.1l.5-.1 .1-.1-.1-.1h-.3v.3h-.2v-.5l.6-.1-.4-.1v.2h-.2z" fill-rule="evenodd"/>
<path d="M114.1 62.1h.5a.29 .29 0 0 1 .4 .3 .29 .29 0 0 1-.3 .3l.3 .5h-.1a.5 .5 0 0 0-.6-.5v.5h-.2v-.6h.6l.1-.2-.5-.2v.4h-.2z" fill-rule="evenodd"/>
<path d="M114.2 74.4h.4a.3 .3 0 0 1 .4 .2 .3 .3 0 0 1-.2 .4l.3 .5h-.2l-.4-.5-.1 .5h-.2v-.6h.6v-.2l-.4-.1v.3h-.2z" fill-rule="evenodd"/>
<path d="M114.2 65.2h.4a.3 .3 0 0 1 .4 .2 .3 .3 0 0 1-.2 .4l.3 .4h-.2l-.4-.4-.1 .4h-.2v-.6h.6v-.1l-.4-.1v.2h-.2z" fill-rule="evenodd"/>
<path d="M314.1 73.5h.9v.1h-.7v.4h.6v.2h-.6v.6h-.2z" fill-rule="evenodd"/>
<path d="M314.2 78.1l.5-.3v1.2h-.2v-1l-.3 .2z" fill-rule="evenodd"/>
<path d="M315.1 77.7a1.04 1.04 0 0 1 0 1.7l.3-.8z" fill-rule="evenodd"/>
<path d="M315.5 73.5h.2l.5 1.3h-.2l-.1-.4h-.5l-.2 .4h-.2l.2-.6h.6l-.2-.6-.2 .6h-.2z" fill-rule="evenodd"/>
<path d="M316.3 73.5l.8 .1 .1 .3-.2 .2 .3 .3a.38 .38 0 0 1-.5 .4h-.5v-.2l.8-.1-.1-.3h-.5v.4h-.2v-.6h.4a.2 .2 0 0 0 .3-.1 .2 .2 0 0 0-.1-.3h-.4v.4h-.2z" fill-rule="evenodd"/>
<path d="M317.2 77.8h.9v.1h-.7v.4h.6v.2h-.6v.5h-.2z" fill-rule="evenodd"/>
<path d="M317.5 73.5h.6a.35 .35 0 0 1 .4 .3 .35 .35 0 0 1-.3 .4l.4 .6h-.2a.62 .62 0 0 0-.7-.6v.6h-.2v-.7l.8-.1a.21 .21 0 0 0 0-.3 .21 .21 0 0 0-.2-.1h-.4v.5h-.2z" fill-rule="evenodd"/>
<path d="M318.8 73.5h.2v1.3h-.2z" fill-rule="evenodd"/>
<path d="M318.6 77.8h.2l.5 1.2h-.2l-.2-.3h-.5l-.1 .3h-.2l.2-.5h.6l-.2-.6-.3 .6h-.1z" fill-rule="evenodd"/>
<path d="M319.4 77.8l.8 .1v.2l-.1 .3 .2 .3a.38 .38 0 0 1-.5 .3h-.4v-.1l.7-.1-.1-.3-.5-.1v.5h-.1v-.6h.4a.2 .2 0 0 0 .3-.1 .2 .2 0 0 0-.2-.3h-.4v.4h-.1z" fill-rule="evenodd"/>
<path d="M319.4 73.6l.6-.1 .3 .3-.1 .1a.45 .45 0 0 0-.7-.2 .45 .45 0 0 0-.1 .7l.4 .2h.2l.2-.3 .1 .1a.62 .62 0 0 1-.9 .2 .62 .62 0 0 1 0-1z" fill-rule="evenodd"/>
<path d="M320.5 77.8h.6a.35 .35 0 0 1 .5 .3 .35 .35 0 0 1-.4 .4l.5 .5h-.2l-.4-.5h-.2h-.2v.5h-.2v-.7l.9-.1a.21 .21 0 0 0-.1-.2 .21 .21 0 0 0-.2-.1h-.4v.4h-.2z" fill-rule="evenodd"/>
<path d="M320.9 73.5h.2l.5 1.3h-.2l-.1-.4h-.6l-.1 .4h-.2l.2-.6h.6l-.2-.6-.2 .6h-.2z" fill-rule="evenodd"/>
<path d="M321.9 77.8h.1v1.2h-.1z" fill-rule="evenodd"/>
<path d="M321.6 73.5h1v.1h-.4v1.2h-.2v-1.2h-.4z" fill-rule="evenodd"/>
<path d="M322.7 73.5h.2v1.3h-.2z" fill-rule="evenodd"/>
<path d="M322.4 77.9l.6-.1 .3 .2-.1 .2a.45 .45 0 0 0-.6-.2 .45 .45 0 0 0-.1 .7l.4 .2 .2-.1 .1-.2h.2a.62 .62 0 0 1-1 .3 .62 .62 0 0 1 0-1z" fill-rule="evenodd"/>
<path d="M323.3 73.7a.63 .63 0 0 1 1 0 .63 .63 0 0 1-.3 1 .63 .63 0 0 1-.9-.5h.2a.48 .48 0 0 0 .8 .3 .48 .48 0 0 0-.1-.8h-.5l-.2 .5h-.2z" fill-rule="evenodd"/>
<path d="M324.6 73.5h.1l.7 1v-1h.2v1.3h-.2l-.7-1v1h-.1z" fill-rule="evenodd"/>
<path d="M324 77.8h.1l.6 1.2h-.2l-.2-.3h-.5l-.2 .3h-.1l.2-.5h.6l-.3-.6-.2 .6h-.1z" fill-rule="evenodd"/>
<path d="M324.6 77.8h1v.1h-.4v1.1h-.2v-1.1h-.4z" fill-rule="evenodd"/>
<path d="M325.7 77.8h1v.1h-.8v.4h.7v.2h-.7v.4h.8v.1h-1z" fill-rule="evenodd"/>
<path d="M326.3 73.5h.2l.7 1v-1h.1v1.3h-.1l-.7-1v1h-.2z" fill-rule="evenodd"/>
<path d="M327.4 77.8h.5a.39 .39 0 0 1 .5 .3 .39 .39 0 0 1-.5 .4h-.3v.5h-.2v-.6l.7-.1 .1-.2-.1-.2h-.5v.5h-.2z" fill-rule="evenodd"/>
<path d="M327.7 73.7a.63 .63 0 0 1 1 0 .63 .63 0 0 1-.3 1 .63 .63 0 0 1-.8-.5h.2a.48 .48 0 0 0 .7 .3 .48 .48 0 0 0-.1-.8h-.5l-.1 .5h-.2z" fill-rule="evenodd"/>
<path d="M328.6 77.8h.9v.1h-.7v.4h.7v.2h-.7v.4h.8v.1h-1z" fill-rule="evenodd"/>
<path d="M328.9 73.5h1v.1h-.4v1.2h-.2v-1.2h-.4z" fill-rule="evenodd"/>
<path d="M330.1 73.5h.9v.1h-.7v.4h.7v.2h-.7v.4h.7v.2h-.9z" fill-rule="evenodd"/>
<path d="M329.8 77.8h.6a.35 .35 0 0 1 .4 .3 .35 .35 0 0 1-.3 .4l.4 .5h-.2l-.3-.5h-.2h-.2v.5h-.2v-.7h.7l.1-.2-.1-.2h-.5v.4h-.2z" fill-rule="evenodd"/>
<path d="M331.4 73.6l.6-.1 .2 .3-.2 .1a.27 .27 0 0 0-.3-.3 .27 .27 0 0 0-.2 .4h.2a.43 .43 0 0 1 .5 .6 .43 .43 0 0 1-.7 .1l-.3-.3 .2-.1a.31 .31 0 0 0 .3 .3 .31 .31 0 0 0 .3-.3l-.6-.3z" fill-rule="evenodd"/>
<path d="M331.6 77.8h.2v1.2h-.2z" fill-rule="evenodd"/>
<path d="M332.1 77.8h.4a.39 .39 0 0 1 .5 .3 .39 .39 0 0 1-.4 .4h-.4v.5h-.1v-.6l.6-.1 .2-.2-.2-.2h-.5v.5h-.1z" fill-rule="evenodd"/>
<path d="M333.2 73.5h.2l-.3 .9 .3 .7-.2-.1-.3-.6 .1-.5z" fill-rule="evenodd"/>
<path d="M333.4 77.9l.6-.1 .3 .2-.2 .2a.45 .45 0 0 0-.6-.2 .45 .45 0 0 0-.1 .7l.4 .2 .2-.1 .2-.2h.1a.62 .62 0 0 1-.9 .3 .62 .62 0 0 1 0-1z" fill-rule="evenodd"/>
<path d="M333.6 73.5h.1v.7a.34 .34 0 0 0 .4 .4 .34 .34 0 0 0 .3-.4v-.7h.2v.7a.5 .5 0 0 1-.5 .6 .5 .5 0 0 1-.5-.6z" fill-rule="evenodd"/>
<path d="M334.4 78.5h.5v.2h-.5z" fill-rule="evenodd"/>
<path d="M334.8 73.5h.2l.7 1v-1h.1v1.3h-.1l-.7-1v1h-.2z" fill-rule="evenodd"/>
<path d="M335.2 77.8h.4l.3 .3-.5-.2-.2 .5a.41 .41 0 0 1 .7 .1 .41 .41 0 0 1-.4 .6 .41 .41 0 0 1-.4-.5h.1a.26 .26 0 0 0 .4 .2 .26 .26 0 0 0 .1-.4 .26 .26 0 0 0-.5 .1l-.1 .1z" fill-rule="evenodd"/>
<path d="M336.1 73.5h.2v1.1h.6v.2h-.8z" fill-rule="evenodd"/>
<path d="M336.2 77.9l.3-.1a.71 .71 0 0 1 .4 .6 .71 .71 0 0 1-.4 .7 .51 .51 0 0 1-.5-.7h.2a.32 .32 0 0 0 0 .4 .32 .32 0 0 0 .5 0 .32 .32 0 0 0 0-.4 .32 .32 0 0 0 0-.4 .32 .32 0 0 0-.5 0 .32 .32 0 0 0 0 .4h-.2z" fill-rule="evenodd"/>
<path d="M337.1 73.5h.9v.1h-.7v.4h.7v.2h-.7v.4h.8v.2h-1z" fill-rule="evenodd"/>
<path d="M337.2 78.1l.4-.3v1.2h-.1v-1l-.3 .2z" fill-rule="evenodd"/>
<path d="M338.4 73.6l.6-.1 .2 .3-.2 .1a.27 .27 0 0 0-.3-.3 .27 .27 0 0 0-.2 .4h.2a.43 .43 0 0 1 .5 .6 .43 .43 0 0 1-.7 .1l-.3-.3 .2-.1a.31 .31 0 0 0 .3 .3 .31 .31 0 0 0 .3-.3l-.6-.3z" fill-rule="evenodd"/>
<path d="M338.2 77.9a.41 .41 0 0 1 .6 0 .41 .41 0 0 1-.2 .6l-.4 .4h.6v.1h-.8l.5-.6a.27 .27 0 0 0 .2-.2 .27 .27 0 0 0-.2-.3 .27 .27 0 0 0-.3 .2h-.2z" fill-rule="evenodd"/>
<path d="M339.6 73.6l.6-.1 .2 .3-.2 .1a.27 .27 0 0 0-.3-.3 .27 .27 0 0 0-.2 .4h.2a.43 .43 0 0 1 .5 .6 .43 .43 0 0 1-.7 .1l-.3-.3 .2-.1a.31 .31 0 0 0 .3 .3 .31 .31 0 0 0 .3-.3l-.7-.3z" fill-rule="evenodd"/>
<path d="M339.4 77.8h.2l.5 1.2h-.2l-.1-.3h-.6l-.1 .3h-.2l.2-.5h.6l-.2-.6-.2 .6h-.2z" fill-rule="evenodd"/>
<path d="M340.8 77.9l.6-.1 .3 .2-.2 .2a.45 .45 0 0 0-.6-.2 .45 .45 0 0 0-.1 .7l.4 .2 .2-.1 .2-.2h.1a.62 .62 0 0 1-.9 .3 .62 .62 0 0 1 0-1z" fill-rule="evenodd"/>
<path d="M341.3 73.7a.63 .63 0 0 1 1 0 .63 .63 0 0 1-.4 1 .63 .63 0 0 1-.8-.5h.2a.48 .48 0 0 0 .7 .3 .48 .48 0 0 0-.1-.8h-.4l-.2 .5h-.2z" fill-rule="evenodd"/>
<path d="M341.9 77.8h.2v1.1h.6v.1h-.8z" fill-rule="evenodd"/>
<path d="M342.4 73.5h1v.1h-.4v1.2h-.1v-1.2h-.5z" fill-rule="evenodd"/>
<path d="M343.6 73.5h.2v.5h.7v-.5h.1v1.3h-.1v-.6h-.7v.6h-.2z" fill-rule="evenodd"/>
<path d="M343.3 77.8h.2l.5 1.2h-.2l-.2-.3h-.5l-.1 .3h-.2l.2-.5h.6l-.2-.6-.3 .6h-.1z" fill-rule="evenodd"/>
<path d="M344.2 77.9l.6-.1 .2 .3h-.1a.27 .27 0 0 0-.4-.3 .27 .27 0 0 0-.2 .4l.3 .1a.43 .43 0 0 1 .4 .6 .43 .43 0 0 1-.7 .1l-.2-.3 .1-.1a.31 .31 0 0 0 .3 .3 .31 .31 0 0 0 .3-.4l-.6-.2z" fill-rule="evenodd"/>
<path d="M344.9 73.5h.9v.1h-.7v.4h.7v.2h-.7v.4h.8v.2h-1z" fill-rule="evenodd"/>
<path d="M345.4 77.9l.6-.1 .2 .3h-.2a.27 .27 0 0 0-.3-.3 .27 .27 0 0 0-.2 .4l.2 .1a.43 .43 0 0 1 .5 .6 .43 .43 0 0 1-.7 .1l-.3-.3 .2-.1a.31 .31 0 0 0 .3 .3 .31 .31 0 0 0 .3-.4l-.6-.2z" fill-rule="evenodd"/>
<path d="M346.1 73.5h.6a.35 .35 0 0 1 .4 .3 .35 .35 0 0 1-.3 .4l.4 .6h-.2a.62 .62 0 0 0-.7-.6v.6h-.2v-.7l.8-.1a.21 .21 0 0 0 0-.3 .21 .21 0 0 0-.2-.1h-.4v.5h-.2z" fill-rule="evenodd"/>
<path d="M347.2 73.5h.2l.3 1.1 .3-1.1h.2l.2 1.1 .3-1.1h.2l-.4 1.3h-.1l-.3-1.2-.3 1.2h-.2z" fill-rule="evenodd"/>
<path d="M347 77.9a.41 .41 0 0 1 .7 0 .41 .41 0 0 1-.2 .6l-.4 .4h.6v.1h-.8l.4-.6a.27 .27 0 0 0 .3-.2 .27 .27 0 0 0-.2-.3 .27 .27 0 0 0-.3 .2h-.2z" fill-rule="evenodd"/>
<path d="M348 78.9h.2v.1h-.2z" fill-rule="evenodd"/>
<path d="M349 73.5h.2v1.3h-.2z" fill-rule="evenodd"/>
<path d="M349.6 73.6l.6-.1 .2 .3-.1 .1a.27 .27 0 0 0-.3-.3 .27 .27 0 0 0-.2 .4h.2a.43 .43 0 0 1 .4 .6 .43 .43 0 0 1-.7 .1l-.2-.3 .1-.1a.31 .31 0 0 0 .4 .3 .31 .31 0 0 0 .2-.3l-.6-.3z" fill-rule="evenodd"/>
<path d="M350.7 73.5h.9v.1h-.7v.4h.7v.2h-.7v.4h.7v.2h-.9z" fill-rule="evenodd"/>
<path d="M352.5 73.6l.6-.1 .2 .3-.2 .1a.27 .27 0 0 0-.3-.3 .27 .27 0 0 0-.2 .4h.2a.43 .43 0 0 1 .5 .6 .43 .43 0 0 1-.7 .1l-.3-.3 .2-.1a.31 .31 0 0 0 .3 .3 .31 .31 0 0 0 .3-.3l-.7-.3z" fill-rule="evenodd"/>
<path d="M353.6 73.5h.4a.39 .39 0 0 1 .5 .4 .39 .39 0 0 1-.4 .3h-.4v.6h-.1v-.7h.6l.2-.2-.2-.2-.5-.1v.5h-.1z" fill-rule="evenodd"/>
<path d="M354.7 73.5h1v.1h-.8v.4h.7v.2h-.7v.4h.8v.2h-1z" fill-rule="evenodd"/>
<path d="M356.1 73.6l.6-.1 .3 .3-.2 .1a.45 .45 0 0 0-.6-.2 .45 .45 0 0 0-.1 .7l.4 .2h.2l.1-.3 .2 .1a.62 .62 0 0 1-1 .2 .62 .62 0 0 1 .1-1z" fill-rule="evenodd"/>
<path d="M357.2 73.5h.2v1.3h-.2z" fill-rule="evenodd"/>
<path d="M357.7 73.5h.9v.1h-.7v.4h.6v.2h-.6v.6h-.2z" fill-rule="evenodd"/>
<path d="M358.8 73.5h.2v1.3h-.2z" fill-rule="evenodd"/>
<path d="M359.3 73.5h.9v.1h-.7v.4h.7v.2h-.7v.4h.7v.2h-.9z" fill-rule="evenodd"/>
<path d="M360.5 73.5h.4a.64 .64 0 0 1 .6 .6 .64 .64 0 0 1-.6 .7h-.4v-.2h.4a.49 .49 0 0 0 .4-.5 .49 .49 0 0 0-.4-.5h-.3v1h-.1z" fill-rule="evenodd"/>
<path d="M361.7 73.5a1.04 1.04 0 0 1 0 1.6l.3-.8z" fill-rule="evenodd"/>
<path d="M58.9 89.9l.6-.1 .2 .3-.2 .1a.28 .28 0 0 0-.4-.1 .28 .28 0 0 0 0 .4 .28 .28 0 0 0 .4 0h.2a.5 .5 0 0 1-.8 .2 .5 .5 0 0 1 0-.8z" fill-rule="evenodd"/>
<path d="M58.9 80.7l.6-.1 .2 .3h-.2a.28 .28 0 0 0-.4 0 .28 .28 0 0 0 0 .4 .28 .28 0 0 0 .4 0h.2a.5 .5 0 0 1-.8 .2 .5 .5 0 0 1 0-.8z" fill-rule="evenodd"/>
<path d="M59 85.3l.5-.1 .2 .2-.1 .1a.34 .34 0 0 0-.5 0 .34 .34 0 0 0 0 .5 .34 .34 0 0 0 .5-.1h.1a.5 .5 0 0 1-.7 .2 .5 .5 0 0 1 0-.8z" fill-rule="evenodd"/>
<path d="M59.9 85.6a.37 .37 0 0 1 .6 0 .37 .37 0 0 1-.2 .6 .37 .37 0 0 1-.5-.3h.2a.25 .25 0 0 0 .3 .1 .25 .25 0 0 0 .1-.3 .25 .25 0 0 0-.4 0v.2h-.2z" fill-rule="evenodd"/>
<path d="M60 90.2a.39 .39 0 0 1 .6 .1 .39 .39 0 0 1-.3 .5 .39 .39 0 0 1-.5-.3h.2a.19 .19 0 0 0 .3 .1 .19 .19 0 0 0 .1-.3 .19 .19 0 0 0-.3 .1l-.3 .1z" fill-rule="evenodd"/>
<path d="M60 80.9a.39 .39 0 0 1 .6 .1 .39 .39 0 0 1-.3 .6 .39 .39 0 0 1-.5-.4h.2a.19 .19 0 0 0 .3 .2 .19 .19 0 0 0 .1-.3 .19 .19 0 0 0-.3 .1h-.3z" fill-rule="evenodd"/>
<path d="M60.7 85.5l.1 .1 .3-.1-.3 .2v.5h-.1z" fill-rule="evenodd"/>
<path d="M60.8 90.1h.1v.1a.34 .34 0 0 1 .5 0 .34 .34 0 0 1 0 .5 .34 .34 0 0 1-.4 .1v.3h-.2v-.6h.2a.17 .17 0 0 0 .2 .1 .17 .17 0 0 0 0-.3 .17 .17 0 0 0-.2 .2h-.2z" fill-rule="evenodd"/>
<path d="M60.8 80.9h.1v.1a.34 .34 0 0 1 .5 0 .34 .34 0 0 1 0 .5 .34 .34 0 0 1-.4 0v.4h-.2v-.7l.2 .1a.17 .17 0 0 0 .2 .1 .17 .17 0 0 0 0-.3 .17 .17 0 0 0-.2 .1h-.2z" fill-rule="evenodd"/>
<path d="M61.2 85.6l.3-.1 .3 .2v.2h-.6l.2 .2 .4-.1a.36 .36 0 0 1-.5 .2 .36 .36 0 0 1-.2-.4h.6l-.2-.2-.4 .2z" fill-rule="evenodd"/>
<path d="M61.6 90.1h.2v.1a.34 .34 0 0 1 .5 0 .34 .34 0 0 1 0 .5 .34 .34 0 0 1-.5 .1v.3h-.2v-.6h.2a.17 .17 0 0 0 .3 .1 .17 .17 0 0 0 0-.3 .18 .18 0 0 0-.3 .2h-.2z" fill-rule="evenodd"/>
<path d="M61.6 80.9h.2v.1a.34 .34 0 0 1 .5 0 .34 .34 0 0 1 0 .5 .34 .34 0 0 1-.5 0v.4h-.2v-.7l.2 .1a.17 .17 0 0 0 .3 .1 .17 .17 0 0 0 0-.3 .17 .17 0 0 0-.3 .1h-.2z" fill-rule="evenodd"/>
<path d="M62.6 90.2l.4-.1 .2 .4-.5 .1 .1 .1 .3-.1a.36 .36 0 0 1-.4 .3 .36 .36 0 0 1-.2-.5h.5l-.2-.2-.3 .2z" fill-rule="evenodd"/>
<path d="M62.6 81l.4-.1 .2 .4-.5 .1 .1 .1 .3-.1a.36 .36 0 0 1-.4 .2 .36 .36 0 0 1-.2-.4h.5l-.2-.2-.3 .2z" fill-rule="evenodd"/>
<path d="M63.3 90.1l.2 .1 .3-.1-.1 .2h-.2v.5h-.2z" fill-rule="evenodd"/>
<path d="M63.3 80.9h.2v.1l.3-.1-.1 .2h-.2v.5h-.2z" fill-rule="evenodd"/>
<path d="M66.8 80.6h.2v1h-.2z" fill-rule="evenodd"/>
<path d="M66.8 99.1l.7 .1-.1 .3 .2 .3-.1 .2-.7 .1v-.1l.6-.1 .1-.1-.1-.2h-.4v.4h-.2v-.5h.5l.1-.2-.1-.1h-.3v.3h-.2z" fill-rule="evenodd"/>
<path d="M66.8 96l.7 .1-.1 .4 .2 .2-.1 .2-.7 .1v-.1h.6l.1-.2-.1-.2h-.4v.4h-.2v-.5h.5l.1-.1-.1-.2h-.3v.3h-.2z" fill-rule="evenodd"/>
<path d="M66.8 92.9l.7 .1-.1 .4 .2 .2-.1 .3h-.7v-.1h.6l.1-.2-.1-.1-.4-.1v.4h-.2v-.5h.5l.1-.1-.1-.2h-.3v.3h-.2z" fill-rule="evenodd"/>
<path d="M66.8 89.8l.7 .1 .1 .2-.1 .2a.28 .28 0 0 1 .2 .3 .28 .28 0 0 1-.3 .2h-.6v-.1h.6l.1-.2-.1-.1h-.4v.3h-.2v-.5l.6-.1-.4-.1v.2h-.2z" fill-rule="evenodd"/>
<path d="M67.8 99.9h.2v.2h-.2z" fill-rule="evenodd"/>
<path d="M67.8 96.9h.2v.1h-.2z" fill-rule="evenodd"/>
<path d="M67.8 93.8h.2v.1h-.2z" fill-rule="evenodd"/>
<path d="M67.9 90.7h.2v.1h-.2z" fill-rule="evenodd"/>
<path d="M67.2 80.9h.7v.7h-.2v-.5l-.1-.1-.2 .1v.5h-.2z" fill-rule="evenodd"/>
<path d="M68.3 96.1l.4-.1a.16 .16 0 0 1 .2 .1 .16 .16 0 0 1-.1 .2 .22 .22 0 0 0-.3-.3 .22 .22 0 0 0-.1 .4h.2a.36 .36 0 0 1 .3 .5 .36 .36 0 0 1-.6 0l-.2-.2h.2a.24 .24 0 0 0 .3 .2 .24 .24 0 0 0 .1-.3l-.5-.2z" fill-rule="evenodd"/>
<path d="M68.2 92.9h.2l.3 .9 .3-.9h.2v1h-.2v-.8l-.3 .8h-.1l-.3-.8v.8h-.1z" fill-rule="evenodd"/>
<path d="M68.2 99.1h.4a.31 .31 0 0 1 .4 .2 .31 .31 0 0 1-.4 .4h-.3v.4h-.1v-.6h.5l.1-.1-.1-.2h-.4v.3h-.1z" fill-rule="evenodd"/>
<path d="M68.1 80.9h.6l.1 .7h-.2v-.5l-.1-.1-.2 .1v.5h-.2z" fill-rule="evenodd"/>
<path d="M68.4 89.9l.5-.1 .2 .3-.2 .1a.28 .28 0 0 0-.4-.1 .28 .28 0 0 0 0 .4 .28 .28 0 0 0 .4 0h.2a.5 .5 0 0 1-.7 .2 .5 .5 0 0 1 0-.8z" fill-rule="evenodd"/>
<path d="M69.1 96h.2v.1h-.2z" fill-rule="evenodd"/>
<path d="M69.1 96.3h.2v.7h-.2z" fill-rule="evenodd"/>
<path d="M69 81l.5-.1 .1 .4-.5 .1 .2 .1 .3-.1a.36 .36 0 0 1-.4 .2 .36 .36 0 0 1-.3-.4h.5l-.1-.2-.4 .2z" fill-rule="evenodd"/>
<path d="M69.4 96h.2v1h-.2z" fill-rule="evenodd"/>
<path d="M69.2 99.4h.5l.1 .7h-.6l-.1-.2h.1a.17 .17 0 0 0 .3 .1 .17 .17 0 0 0 0-.3l-.4 .2 .1-.2 .4-.1-.1-.2-.4 .1z" fill-rule="evenodd"/>
<path d="M69.8 96h.1v.6l.5-.3-.3 .2 .3 .5h-.2l-.2-.4-.1 .4h-.1z" fill-rule="evenodd"/>
<path d="M69.4 93.3l.5-.1 .1 .7-.1-.1-.4 .1-.2-.2h.2a.17 .17 0 0 0 .2 .1 .17 .17 0 0 0 .1-.2l-.5 .1 .2-.2h.3l-.1-.2-.3 .1z" fill-rule="evenodd"/>
<path d="M69.3 90.1h.2v.5l.1 .1 .2-.1v-.5h.2v.7h-.2v-.1l-.4 .1z" fill-rule="evenodd"/>
<path d="M70 99.4l.3-.1 .2 .2h-.2a.14 .14 0 0 0-.1-.1 .14 .14 0 0 0-.1 .2h.1a.28 .28 0 0 1 .2 .3 .28 .28 0 0 1-.3 .3 .28 .28 0 0 1-.2-.3l.1-.1a.16 .16 0 0 0 .2 .2 .16 .16 0 0 0 .1-.2l-.3-.1z" fill-rule="evenodd"/>
<path d="M69.8 80.9h.2v.1l.3-.1-.3 .2v.5h-.2z" fill-rule="evenodd"/>
<path d="M70.2 93.2h.4l.1 .2h-.1a.14 .14 0 0 0-.2-.2 .14 .14 0 0 0-.1 .2l.1 .1a.28 .28 0 0 1 .3 .3 .28 .28 0 0 1-.4 .2 .28 .28 0 0 1-.2-.3h.1a.16 .16 0 0 0 .2 .2 .16 .16 0 0 0 .1-.3l-.3-.1z" fill-rule="evenodd"/>
<path d="M70.5 96.3h.4l.1 .2h-.1a.14 .14 0 0 0-.2-.2 .14 .14 0 0 0-.1 .2l.2 .1a.28 .28 0 0 1 .2 .3 .28 .28 0 0 1-.3 .2 .28 .28 0 0 1-.3-.3h.2a.16 .16 0 0 0 .1 .2 .18 .18 0 0 0 .2-.3l-.4-.1z" fill-rule="evenodd"/>
<path d="M70.9 92.9h.1v.6l.5-.3-.3 .3 .3 .4h-.2l-.2-.4-.1 .4h-.1z" fill-rule="evenodd"/>
<path d="M70.7 99.2l.1-.1v.2h.1l-.1 .1v.5l.1 .2-.2-.1-.1-.6z" fill-rule="evenodd"/>
<path d="M70.4 80.7a.35 .35 0 0 1 .5 .1 .35 .35 0 0 1-.2 .5l-.1 .1h.4v.2h-.7l.4-.5a.15 .15 0 0 0 .1-.2 .15 .15 0 0 0-.2-.1 .15 .15 0 0 0-.1 .1h-.2z" fill-rule="evenodd"/>
<path d="M71.1 99.4l.3-.1 .3 .2v.2h-.6l.2 .3 .4-.1a.36 .36 0 0 1-.5 .2 .36 .36 0 0 1-.2-.5h.6l-.2-.2-.4 .2z" fill-rule="evenodd"/>
<path d="M71.3 96.3h.4l.1 .2h-.1a.21 .21 0 0 0-.3 0 .21 .21 0 0 0 0 .3 .21 .21 0 0 0 .3-.1h.1a.37 .37 0 0 1-.6 .2 .37 .37 0 0 1 .1-.6z" fill-rule="evenodd"/>
<path d="M71.9 96.3l.1 .1 .3-.1-.2 .2-.1 .5h-.1z" fill-rule="evenodd"/>
<path d="M72.5 96.3l.3-.1 .2 .3v.2h-.5l.1 .2 .4-.1a.36 .36 0 0 1-.4 .2 .36 .36 0 0 1-.2-.4h.5l-.2-.3-.3 .3z" fill-rule="evenodd"/>
<path d="M73.3 96.3l.3-.1 .2 .3v.2h-.5l.1 .2 .4-.1a.36 .36 0 0 1-.4 .2 .36 .36 0 0 1-.2-.4h.5l-.2-.3-.3 .3z" fill-rule="evenodd"/>
<path d="M74 96.3h.6v.7h-.1v-.6l-.2-.1-.2 .2v.5h-.1z" fill-rule="evenodd"/>
<path d="M77.7 93l.2-.1a.51 .51 0 0 1 .4 .5 .51 .51 0 0 1-.5 .5l-.1-.3-.1-.2h.2a.26 .26 0 0 0 0 .4 .26 .26 0 0 0 .3 0 .26 .26 0 0 0 .1-.4 .26 .26 0 0 0-.1-.3 .26 .26 0 0 0-.3 0 .26 .26 0 0 0 0 .3h-.2z" fill-rule="evenodd"/>
<path d="M77.7 85.3l.2-.1a.52 .52 0 0 1 .4 .5 .52 .52 0 0 1-.5 .5l-.1-.3-.1-.2h.2a.26 .26 0 0 0 0 .4 .26 .26 0 0 0 .3 0 .26 .26 0 0 0 .1-.4 .26 .26 0 0 0-.1-.3 .26 .26 0 0 0-.3 0 .26 .26 0 0 0 0 .3h-.2z" fill-rule="evenodd"/>
<path d="M77.7 89.9l.1-.1a.5 .5 0 0 1 .5 .5 .5 .5 0 0 1-.5 .5l-.2-.5h.2l.2 .4 .1-.5-.2-.2-.1 .3h-.2z" fill-rule="evenodd"/>
<path d="M77.8 80.6a.5 .5 0 0 1 .5 .5 .5 .5 0 0 1-.5 .5l-.2-.5h.2l.2 .4 .1-.6-.2-.1-.1 .3h-.2z" fill-rule="evenodd"/>
<path d="M78.5 90.7h.2v.1h-.2z" fill-rule="evenodd"/>
<path d="M78.5 81.4h.2v.2h-.2z" fill-rule="evenodd"/>
<path d="M78.5 93.8h.1v.1h-.1z" fill-rule="evenodd"/>
<path d="M78.5 86.1h.1v.1h-.1z" fill-rule="evenodd"/>
<path d="M78.9 93l.2-.1a.51 .51 0 0 1 .4 .5 .51 .51 0 0 1-.5 .5l-.2-.4v-.1h.2a.26 .26 0 0 0 0 .4 .26 .26 0 0 0 .3 0 .26 .26 0 0 0 .1-.4 .26 .26 0 0 0-.1-.3 .26 .26 0 0 0-.3 0 .26 .26 0 0 0 0 .3h-.2z" fill-rule="evenodd"/>
<path d="M78.9 89.9l.1-.1a.5 .5 0 0 1 .5 .5 .5 .5 0 0 1-.5 .5l-.2-.5h.2l.2 .4 .1-.5-.2-.2-.1 .3h-.2z" fill-rule="evenodd"/>
<path d="M79 80.6a.5 .5 0 0 1 .5 .5 .5 .5 0 0 1-.5 .5l-.2-.5h.2l.2 .4 .1-.6-.2-.1-.1 .3h-.2z" fill-rule="evenodd"/>
<path d="M78.9 85.5l.4-.3v1h-.1v-.8l-.3 .2z" fill-rule="evenodd"/>
<path d="M79.7 89.9a.28 .28 0 0 1 .5 0 .28 .28 0 0 1-.1 .4 .32 .32 0 0 1 0 .6 .32 .32 0 0 1-.5-.3l.2-.1a.16 .16 0 0 0 .2 .2 .16 .16 0 0 0 .1-.3 .16 .16 0 0 0-.2 0l.2-.3h-.5z" fill-rule="evenodd"/>
<path d="M79.7 80.7a.28 .28 0 0 1 .5-.1 .28 .28 0 0 1-.1 .5 .32 .32 0 0 1 0 .5 .32 .32 0 0 1-.5-.3h.2a.16 .16 0 0 0 .2 .1 .16 .16 0 0 0 .1-.2 .16 .16 0 0 0-.2 0l.2-.4-.5 .1z" fill-rule="evenodd"/>
<path d="M79.7 85.3a.27 .27 0 0 1 .5 0 .27 .27 0 0 1-.1 .4 .32 .32 0 0 1 0 .5 .32 .32 0 0 1-.5-.3h.2a.21 .21 0 0 0 .3 .2 .21 .21 0 0 0 0-.3 .21 .21 0 0 0-.3 .1h-.2l.2-.2-.1-.2h.1a.17 .17 0 0 0 .2 .1 .17 .17 0 0 0 .1-.3 .17 .17 0 0 0-.3 .1l-.1 .1z" fill-rule="evenodd"/>
<path d="M79.7 93.1l.4-.2v1h-.1v-.8l-.3 .2z" fill-rule="evenodd"/>
<path d="M80.5 85.2h.6v.1h-.5v.3a.34 .34 0 0 1 .5 .2 .34 .34 0 0 1-.2 .4 .34 .34 0 0 1-.5-.2h.2a.23 .23 0 0 0 .3 .1 .23 .23 0 0 0 0-.4 .23 .23 0 0 0-.3 .1l-.2-.1z" fill-rule="evenodd"/>
<path d="M80.6 89.8h.5v.2h-.4v.2a.35 .35 0 0 1 .4 .2 .35 .35 0 0 1-.3 .5 .35 .35 0 0 1-.4-.3h.2a.18 .18 0 0 0 .3 0 .18 .18 0 0 0 0-.3 .18 .18 0 0 0-.3 .1h-.1z" fill-rule="evenodd"/>
<path d="M80.6 80.6h.5v.2h-.4v.2a.35 .35 0 0 1 .4 .2 .35 .35 0 0 1-.3 .4 .35 .35 0 0 1-.4-.2l.2-.1a.18 .18 0 0 0 .3 .1 .18 .18 0 0 0 0-.3 .18 .18 0 0 0-.3 .1l-.1-.1z" fill-rule="evenodd"/>
<path d="M80.5 93.2l.5 .1 .4-.1 .1 .7h-.2v-.5l-.1-.1-.2 .1v.5h-.1v-.5l-.1-.1-.2 .1v.5h-.1z" fill-rule="evenodd"/>
<path d="M81.3 85.2h.6v.1h-.5v.3a.34 .34 0 0 1 .5 .2 .34 .34 0 0 1-.2 .4 .34 .34 0 0 1-.5-.2h.2a.23 .23 0 0 0 .3 .1 .23 .23 0 0 0 0-.4 .23 .23 0 0 0-.3 .1l-.2-.1z" fill-rule="evenodd"/>
<path d="M81.3 90.1l.1 .1 .2-.1 .3 .1 .3-.1 .1 .7h-.2l-.1-.6-.1 .1v.5h-.2l-.1-.6-.1 .1-.1 .5h-.1z" fill-rule="evenodd"/>
<path d="M81.3 80.9l.1 .1 .3-.2 .2 .2 .3-.1 .1 .7h-.2l-.1-.6-.1 .1v.5h-.2l-.1-.6-.1 .1-.1 .5h-.1z" fill-rule="evenodd"/>
<path d="M81.7 93.2l.5 .1 .4-.1 .1 .7h-.2v-.5l-.1-.1-.2 .1v.5h-.1v-.5l-.1-.1-.2 .1v.5h-.1z" fill-rule="evenodd"/>
<path d="M82.1 85.5l.1 .1 .2-.1 .2 .1 .4-.1 .1 .7h-.2v-.5l-.1-.1-.2 .1v.5h-.1v-.5l-.1-.1-.2 .1v.5h-.1z" fill-rule="evenodd"/>
<path d="M82.5 90.1l.2 .1 .2-.1 .3 .1 .3-.1 .1 .7h-.2l-.1-.6-.1 .1v.5h-.2l-.1-.6-.2 .1v.5h-.2z" fill-rule="evenodd"/>
<path d="M82.5 80.9l.2 .1 .2-.2 .3 .2 .3-.1 .1 .7h-.2l-.1-.6-.1 .1v.5h-.2l-.1-.6-.2 .1v.5h-.2z" fill-rule="evenodd"/>
<path d="M83.2 85.5l.2 .1 .2-.1 .2 .1 .4-.1 .1 .7h-.2v-.5l-.1-.1-.2 .1v.5h-.1v-.5l-.1-.1-.2 .1v.5h-.2z" fill-rule="evenodd"/>
<path d="M84.4 89.8h.1l-.1 .7 .1 .6a.92 .92 0 0 1-.1-1.3z" fill-rule="evenodd"/>
<path d="M84.4 80.6h.1l-.1 .6 .1 .7a.92 .92 0 0 1-.1-1.3z" fill-rule="evenodd"/>
<path d="M84.7 90.1l.5-.3v1h-.2v-.7l-.3 .2z" fill-rule="evenodd"/>
<path d="M84.7 80.8l.5-.2v1h-.2v-.7l-.3 .1z" fill-rule="evenodd"/>
<path d="M85.5 90.7h.2v.1h-.2z" fill-rule="evenodd"/>
<path d="M85.5 81.4h.2v.2h-.2z" fill-rule="evenodd"/>
<path d="M86 89.9v-.1a.5 .5 0 0 1 .5 .5 .5 .5 0 0 1-.5 .5l-.1-.5h.2l.1 .4 .1-.5-.2-.2v.3h-.2z" fill-rule="evenodd"/>
<path d="M86 80.6a.5 .5 0 0 1 .5 .5 .5 .5 0 0 1-.5 .5l-.1-.5h.2l.1 .4 .1-.6-.2-.1v.3h-.2z" fill-rule="evenodd"/>
<path d="M86.7 89.9l.1-.1a.5 .5 0 0 1 .5 .5 .5 .5 0 0 1-.5 .5l-.2-.5h.3l.1 .4 .1-.5-.2-.2v.3h-.3z" fill-rule="evenodd"/>
<path d="M86.8 80.6a.5 .5 0 0 1 .5 .5 .5 .5 0 0 1-.5 .5l-.2-.5h.3l.1 .4 .1-.6-.2-.1v.3h-.3z" fill-rule="evenodd"/>
<path d="M87.6 90.2a.39 .39 0 0 1 .6 .1 .39 .39 0 0 1-.3 .5 .39 .39 0 0 1-.5-.3h.2a.19 .19 0 0 0 .3 .1 .19 .19 0 0 0 .1-.3 .19 .19 0 0 0-.3 .1l-.3 .1z" fill-rule="evenodd"/>
<path d="M87.6 80.9a.39 .39 0 0 1 .6 .1 .39 .39 0 0 1-.3 .6 .39 .39 0 0 1-.5-.4h.2a.19 .19 0 0 0 .3 .2 .19 .19 0 0 0 .1-.3 .19 .19 0 0 0-.3 .1h-.3z" fill-rule="evenodd"/>
<path d="M88.3 90.1h.6l-.4 .6h.4v.1h-.6l.4-.5h-.4z" fill-rule="evenodd"/>
<path d="M88.3 80.9h.6l-.4 .5h.4v.2h-.6l.4-.6h-.4z" fill-rule="evenodd"/>
<path d="M89 89.8l.2 .1 .2 .4-.2 .8h-.2l.2-.6z" fill-rule="evenodd"/>
<path d="M89 80.6l.2 .1 .2 .4-.2 .8h-.2l.2-.7z" fill-rule="evenodd"/>
<path d="M92.4 85.2h.7v.1h-.5v.3h.5v.2h-.5v.4h-.2z" fill-rule="evenodd"/>
<path d="M93.3 85.2h.5a.29 .29 0 0 1 .3 .2 .29 .29 0 0 1-.2 .4l.3 .4h-.1a.5 .5 0 0 0-.6-.4v.4h-.2v-.5l.6-.1 .1-.2-.5-.1v.4h-.2z" fill-rule="evenodd"/>
<path d="M94.7 85.2h.1v.7h.2l-.2 .3h-.1v-.2h-.4v-.1h.4v-.5l-.4 .5z" fill-rule="evenodd"/>
<path d="M101.3 89.9l.4-.1 .2 .2 .1 .1h-.2l-.3-.1v.2a.39 .39 0 0 1 .5 .3 .39 .39 0 0 1-.3 .4 .39 .39 0 0 1-.5-.2v-.2h.2a.19 .19 0 0 0 .2 .3 .21 .21 0 0 0 .1-.4l-.5-.1z" fill-rule="evenodd"/>
<path d="M101.3 93l.4-.1a.16 .16 0 0 1 .2 .1 .16 .16 0 0 1-.1 .2 .22 .22 0 0 0-.2-.3 .22 .22 0 0 0-.1 .4h.1a.36 .36 0 0 1 .3 .5 .36 .36 0 0 1-.6 .1l-.1-.3h.1a.24 .24 0 0 0 .3 .3 .24 .24 0 0 0 .1-.4l-.4-.2z" fill-rule="evenodd"/>
<path d="M101.2 96h.1v.9h.5v.1h-.6z" fill-rule="evenodd"/>
<path d="M101.2 85.2h.4a.52 .52 0 0 1 .5 .5 .52 .52 0 0 1-.5 .5h-.4v-.1h.4a.4 .4 0 0 0 .3-.4 .4 .4 0 0 0-.3-.4h-.3v.8h-.1z" fill-rule="evenodd"/>
<path d="M101.2 99.1h.4a.31 .31 0 0 1 .4 .2 .31 .31 0 0 1-.4 .4h-.3v.4h-.1v-.6h.5l.2-.1-.2-.2h-.4v.3h-.1z" fill-rule="evenodd"/>
<path d="M101.2 80.6h.3a.34 .34 0 0 1 .4 .1 .34 .34 0 0 1 0 .4l-.5 .1v.4h-.2v-.5l.5-.1 .1-.1-.4-.1v.3h-.2z" fill-rule="evenodd"/>
<path d="M102.2 89.8h.2v.2h-.2z" fill-rule="evenodd"/>
<path d="M102.2 90.1h.2v.7h-.2z" fill-rule="evenodd"/>
<path d="M102.2 80.6h.2v1h-.2z" fill-rule="evenodd"/>
<path d="M102.2 85.2h.2v.1h-.2z" fill-rule="evenodd"/>
<path d="M102.2 85.5h.2v.7h-.2z" fill-rule="evenodd"/>
<path d="M102 96.3l.4-.1 .2 .3v.2h-.5l.1 .2 .4-.1a.36 .36 0 0 1-.4 .2 .36 .36 0 0 1-.2-.4h.5l-.2-.3-.3 .3z" fill-rule="evenodd"/>
<path d="M102.2 93.2a.37 .37 0 0 1 .6 .1 .37 .37 0 0 1-.2 .6 .37 .37 0 0 1-.5-.3h.1a.23 .23 0 0 0 .4 .1 .23 .23 0 0 0 0-.4 .23 .23 0 0 0-.4 .2l-.1 .1z" fill-rule="evenodd"/>
<path d="M102.2 99.4h.5l.1 .7h-.5l-.2-.2h.1a.17 .17 0 0 0 .3 .1 .17 .17 0 0 0 .1-.3l-.5 .2 .1-.2 .4-.1-.1-.2-.4 .1z" fill-rule="evenodd"/>
<path d="M102.6 90.2l.6-.1v.7a.36 .36 0 0 1-.3 .3 .36 .36 0 0 1-.4-.2h.5v-.2l-.2 .1-.2-.1-.1-.2h.2a.18 .18 0 0 0 .3 .1 .18 .18 0 0 0 0-.3 .18 .18 0 0 0-.3 .1l-.2 .1z" fill-rule="evenodd"/>
<path d="M103 99.4l.4-.1 .1 .2h-.1a.14 .14 0 0 0-.2-.1 .14 .14 0 0 0-.1 .2h.1a.28 .28 0 0 1 .3 .3 .28 .28 0 0 1-.4 .3 .28 .28 0 0 1-.2-.3l.1-.1a.16 .16 0 0 0 .2 .2 .16 .16 0 0 0 .1-.2l-.3-.1z" fill-rule="evenodd"/>
<path d="M102.6 85.6l.3-.1 .3 .2v.2h-.6l.2 .2 .4-.1a.36 .36 0 0 1-.5 .2 .36 .36 0 0 1-.2-.4h.6l-.2-.2-.4 .2z" fill-rule="evenodd"/>
<path d="M102.6 80.9h.5l.1 .7h-.6l-.1-.2 .3 .1 .2-.2-.5 .1 .5-.3-.1-.1-.4 .1z" fill-rule="evenodd"/>
<path d="M102.9 92.9h.2v1h-.2z" fill-rule="evenodd"/>
<path d="M102.8 96.3h.6v.6a.32 .32 0 0 1-.2 .4 .32 .32 0 0 1-.4-.2l.3 .1 .2-.1v-.2l-.2 .1-.3-.1-.1-.3h.2a.24 .24 0 0 0 .3 .2 .24 .24 0 0 0 .1-.4 .24 .24 0 0 0-.4 0v.2h-.2z" fill-rule="evenodd"/>
<path d="M103.3 85.2h.2v1h-.2z" fill-rule="evenodd"/>
<path d="M103.3 93.2h.2l.2 .1v-.4h.2v1h-.5l-.2-.3h.2a.24 .24 0 0 0 .3 .2 .24 .24 0 0 0 0-.4l-.2-.1-.1 .3h-.2z" fill-rule="evenodd"/>
<path d="M103.7 99.2l.1-.1v.2h.1l-.1 .1v.5l.2 .2-.3-.1v-.6h-.1z" fill-rule="evenodd"/>
<path d="M103.6 96.3l.4-.1 .2 .3v.2h-.5l.1 .2 .4-.1a.36 .36 0 0 1-.4 .2 .36 .36 0 0 1-.2-.4h.5l-.2-.3-.3 .3z" fill-rule="evenodd"/>
<path d="M103.4 80.9h.6v.7h-.2v-.5l-.1-.1-.1 .1v.5h-.2z" fill-rule="evenodd"/>
<path d="M103.7 85.6l.3-.1 .3 .2v.2h-.5l.1 .2 .4-.1a.36 .36 0 0 1-.4 .2 .36 .36 0 0 1-.3-.4h.6l-.2-.2-.4 .2z" fill-rule="evenodd"/>
<path d="M103.4 90.1l.7 .1v.6h-.2v-.5l-.1-.1-.2 .1v.5h-.2z" fill-rule="evenodd"/>
<path d="M104.4 96.3h.5l.1 .7h-.1v-.6l-.2-.1-.2 .2v.5h-.1z" fill-rule="evenodd"/>
<path d="M104.1 99.4l.3-.1 .3 .2v.2h-.5l.1 .3 .4-.1a.36 .36 0 0 1-.4 .2 .36 .36 0 0 1-.3-.5h.6l-.2-.2-.4 .2z" fill-rule="evenodd"/>
<path d="M104.1 93.3l.3-.1 .3 .2v.2h-.5l.1 .2 .4-.1a.36 .36 0 0 1-.4 .2 .36 .36 0 0 1-.3-.4h.6l-.2-.2-.4 .2z" fill-rule="evenodd"/>
<path d="M104.3 81l.4-.1 .2 .4-.5 .1 .1 .1 .4-.1a.36 .36 0 0 1-.5 .2 .36 .36 0 0 1-.2-.4h.5l-.2-.2-.3 .2z" fill-rule="evenodd"/>
<path d="M104.3 90.2h.6l.1 .6h-.7v-.2l.3 .1 .1-.1v-.1l-.4 .1 .4-.2-.1-.2-.3 .1z" fill-rule="evenodd"/>
<path d="M104.9 93.2l.1 .1 .3-.1-.3 .2v.5h-.1z" fill-rule="evenodd"/>
<path d="M104.5 85.6l.4-.1 .2 .2h-.2a.21 .21 0 0 0-.3 0 .21 .21 0 0 0 0 .3 .21 .21 0 0 0 .4 0h.1a.37 .37 0 0 1-.6 .2 .37 .37 0 0 1 0-.6z" fill-rule="evenodd"/>
<path d="M105.1 89.8h.2v1h-.2z" fill-rule="evenodd"/>
<path d="M105.2 85.3l.1-.1v.3h.2l-.2 .1v.4l.2 .2h-.3l-.1-.6z" fill-rule="evenodd"/>
<path d="M105.6 85.5l.1 .1 .3-.1-.3 .2v.5h-.1z" fill-rule="evenodd"/>
<path d="M105.8 92.9h.2l.3 .9 .3-.9h.1v1h-.1v-.8l-.3 .8h-.1l-.3-.8v.8h-.1z" fill-rule="evenodd"/>
<path d="M105.2 96.3l.3-.1 .2 .1v-.3h.1v1h-.5l-.2-.3 .2-.1a.24 .24 0 0 0 .3 .3 .24 .24 0 0 0 0-.4l-.2-.1-.1 .2h-.2z" fill-rule="evenodd"/>
<path d="M106.1 85.2h.1v.1h-.1z" fill-rule="evenodd"/>
<path d="M106.1 85.5h.1v.7h-.1z" fill-rule="evenodd"/>
<path d="M106.5 99.4h.5l.1 .7h-.5l-.2-.2h.2a.17 .17 0 0 0 .2 .1 .17 .17 0 0 0 .1-.3l-.5 .2 .1-.2 .4-.1-.1-.2-.4 .1z" fill-rule="evenodd"/>
<path d="M106.5 85.6l.3-.1 .2 .2h-.1a.21 .21 0 0 0-.4 0 .21 .21 0 0 0 0 .3 .21 .21 0 0 0 .4 0h.1a.37 .37 0 0 1-.6 .2 .37 .37 0 0 1 .1-.6z" fill-rule="evenodd"/>
<path d="M107.3 99.4l.4-.1 .1 .2h-.1a.14 .14 0 0 0-.2-.1 .14 .14 0 0 0-.1 .2h.1a.28 .28 0 0 1 .3 .3 .28 .28 0 0 1-.4 .3 .28 .28 0 0 1-.2-.3l.1-.1a.16 .16 0 0 0 .2 .2 .16 .16 0 0 0 .1-.2l-.3-.1z" fill-rule="evenodd"/>
<path d="M107 93.3l.5-.1 .1 .7-.2-.1-.4 .1-.1-.2h.1a.17 .17 0 0 0 .3 .1 .17 .17 0 0 0 0-.2l-.4 .1 .1-.2h.4l-.1-.2-.4 .1z" fill-rule="evenodd"/>
<path d="M107.8 93.2h.3l.2 .2h-.1a.14 .14 0 0 0-.2-.2 .14 .14 0 0 0-.1 .2l.1 .1a.28 .28 0 0 1 .2 .3 .28 .28 0 0 1-.3 .2 .28 .28 0 0 1-.2-.3h.1a.16 .16 0 0 0 .2 .2 .16 .16 0 0 0 .1-.3l-.3-.1z" fill-rule="evenodd"/>
<path d="M108.5 92.9h.1v.6l.4-.3-.2 .3 .3 .4h-.2l-.2-.4-.1 .4h-.1z" fill-rule="evenodd"/>
<path d="M112.2 89.9l.5-.1 .3 .3h-.2a.29 .29 0 0 0-.5 0 .29 .29 0 0 0 0 .4 .29 .29 0 0 0 .5 0h-.3v-.2h.5v.4a.56 .56 0 0 1-.8 0 .56 .56 0 0 1 0-.8z" fill-rule="evenodd"/>
<path d="M112.2 80.7l.5-.1 .3 .3h-.2a.29 .29 0 0 0-.5 0 .29 .29 0 0 0 0 .4 .29 .29 0 0 0 .5-.1h-.3v-.1h.5v.4a.56 .56 0 0 1-.8 0 .56 .56 0 0 1 0-.8z" fill-rule="evenodd"/>
<path d="M112.2 96.1l.5-.1 .2 .1 .1 .2h-.2a.4 .4 0 0 0-.5 0 .4 .4 0 0 0 0 .5 .4 .4 0 0 0 .5 0v-.2h-.3v-.1h.5v.4a.56 .56 0 0 1-.8 0 .56 .56 0 0 1 0-.8z" fill-rule="evenodd"/>
<path d="M112.2 93l.5-.1 .2 .2 .1 .1h-.2a.4 .4 0 0 0-.5 0 .4 .4 0 0 0 0 .6 .4 .4 0 0 0 .5-.1v-.2h-.3v-.1h.5v.4a.56 .56 0 0 1-.8 0 .56 .56 0 0 1 0-.8z" fill-rule="evenodd"/>
<path d="M113.2 96l.7 .1-.1 .4 .1 .2-.1 .2-.6 .1v-.1h.5l.1-.2-.1-.2h-.4v.4h-.1v-.5h.5l.1-.1-.1-.2h-.4v.3h-.1z" fill-rule="evenodd"/>
<path d="M113.2 92.9l.7 .1-.1 .4 .1 .2-.1 .3h-.6v-.1h.5l.1-.2-.1-.1-.4-.1v.4h-.1v-.5h.5l.1-.1-.1-.2h-.4v.3h-.1z" fill-rule="evenodd"/>
<path d="M113.2 89.8l.7 .1 .1 .2-.2 .2a.28 .28 0 0 1 .2 .3 .28 .28 0 0 1-.3 .2h-.5v-.1h.5l.1-.2-.1-.1h-.3v.3h-.2v-.5l.6-.1-.4-.1v.2h-.2z" fill-rule="evenodd"/>
<path d="M113.2 80.6h.7l.1 .2-.2 .3a.28 .28 0 0 1 .2 .3 .28 .28 0 0 1-.3 .2h-.5v-.2h.5l.1-.1-.1-.1h-.3v.2h-.2v-.4l.6-.1-.4-.1v.2h-.2z" fill-rule="evenodd"/>
<path d="M114.1 96h.5a.29 .29 0 0 1 .4 .2 .29 .29 0 0 1-.3 .3l.3 .5h-.1a.5 .5 0 0 0-.6-.5v.5h-.2v-.6h.6l.1-.2-.5-.1v.3h-.2z" fill-rule="evenodd"/>
<path d="M114.1 92.9h.5a.29 .29 0 0 1 .4 .2 .29 .29 0 0 1-.3 .4l.3 .4h-.1l-.5-.4h-.1v.4h-.2v-.6h.6l.1-.1-.1-.2h-.4v.3h-.2z" fill-rule="evenodd"/>
<path d="M114.2 89.8h.4a.3 .3 0 0 1 .4 .2 .3 .3 0 0 1-.2 .4l.3 .4h-.2l-.4-.4-.1 .4h-.2v-.5l.6-.1v-.1l-.4-.1v.3h-.2z" fill-rule="evenodd"/>
<path d="M114.2 80.6h.4a.3 .3 0 0 1 .4 .2 .3 .3 0 0 1-.2 .4l.3 .4h-.2l-.4-.4-.1 .4h-.2v-.6h.6v-.1l-.4-.1v.2h-.2z" fill-rule="evenodd"/>
<path d="M314.2 94.9a.34 .34 0 0 1 .5 0 .34 .34 0 0 1 0 .5 .4 .4 0 0 1 0 .7 .4 .4 0 0 1-.6-.3l.1-.1a.26 .26 0 0 0 .3 .3 .26 .26 0 0 0 .2-.3 .26 .26 0 0 0-.3-.2v-.1a.22 .22 0 0 0 .3-.2 .22 .22 0 0 0-.2-.3 .22 .22 0 0 0-.3 .3h-.1z" fill-rule="evenodd"/>
<path d="M314.2 82.1a.41 .41 0 0 1 .6 .1 .41 .41 0 0 1-.1 .6l-.4 .4h.6v.1h-.8l.4-.6a.27 .27 0 0 0 .3-.2 .27 .27 0 0 0-.3-.3 .27 .27 0 0 0-.3 .2h-.1z" fill-rule="evenodd"/>
<path d="M315.1 82a1.04 1.04 0 0 1 0 1.7l.3-.9z" fill-rule="evenodd"/>
<path d="M315.1 94.8a1.04 1.04 0 0 1 0 1.7l.3-.9z" fill-rule="evenodd"/>
<path d="M317.3 94.9h.6l.2 .2-.2 .1a.27 .27 0 0 0-.3-.3 .27 .27 0 0 0-.2 .4l.2 .1a.43 .43 0 0 1 .5 .5 .43 .43 0 0 1-.7 .2l-.3-.3 .2-.1a.31 .31 0 0 0 .3 .3 .31 .31 0 0 0 .3-.4l-.6-.2z" fill-rule="evenodd"/>
<path d="M317.1 84.2h.2v.4z" fill-rule="evenodd"/>
<path d="M317.2 97h.9v.1h-.7v.4h.6v.2h-.6v.5h-.2z" fill-rule="evenodd"/>
<path d="M317.4 84.2h.2v.4z" fill-rule="evenodd"/>
<path d="M317.2 88.4h.4a.64 .64 0 0 1 .6 .7 .64 .64 0 0 1-.6 .6h-.4v-.1h.4a.49 .49 0 0 0 .5-.5 .49 .49 0 0 0-.5-.5h-.2v1h-.2z" fill-rule="evenodd"/>
<path d="M317.2 90.6h.4a.64 .64 0 0 1 .6 .6 .64 .64 0 0 1-.6 .6h-.4v-.1h.4a.49 .49 0 0 0 .5-.5 .49 .49 0 0 0-.5-.5h-.2v1h-.2z" fill-rule="evenodd"/>
<path d="M317.8 84.2h.9v.1h-.7v.4h.7v.2h-.7v.4h.8v.1h-1z" fill-rule="evenodd"/>
<path d="M317.3 82.2a.63 .63 0 0 1 1 .1 .63 .63 0 0 1-.3 .9 .63 .63 0 0 1-.9-.5h.2a.48 .48 0 0 0 .8 .4 .48 .48 0 0 0-.1-.9h-.5l-.2 .5h-.2z" fill-rule="evenodd"/>
<path d="M318.4 94.8h.9v.2h-.8v.4h.7v.1h-.7v.5h.8v.1h-.9z" fill-rule="evenodd"/>
<path d="M318.5 88.4h.2v1.3h-.2z" fill-rule="evenodd"/>
<path d="M318.4 97.1a.63 .63 0 0 1 1 .1 .63 .63 0 0 1-.3 .9 .63 .63 0 0 1-.9-.5h.2a.48 .48 0 0 0 .7 .4 .48 .48 0 0 0 0-.8h-.5l-.2 .4h-.2z" fill-rule="evenodd"/>
<path d="M319 88.4h.2l.4 1.1 .3-1.1h.3v1.3h-.2v-1.1l-.4 1.1h-.1l-.4-1.1v1.1h-.1z" fill-rule="evenodd"/>
<path d="M318.5 90.6h.5a.35 .35 0 0 1 .5 .3 .35 .35 0 0 1-.4 .4l.5 .5h-.2l-.4-.5h-.2h-.2v.5h-.1v-.7h.7l.1-.2-.2-.2h-.5v.4h-.1z" fill-rule="evenodd"/>
<path d="M318.6 82h.1v.8a.34 .34 0 0 0 .4 .4 .34 .34 0 0 0 .3-.4v-.8h.2v.8a.5 .5 0 0 1-.5 .5 .5 .5 0 0 1-.5-.5z" fill-rule="evenodd"/>
<path d="M319.6 94.8h.9v.2h-.8v.4h.7v.1h-.7v.5h.8v.1h-.9z" fill-rule="evenodd"/>
<path d="M319.1 84.6l.2-.1 .3 .1v-.4h.1v1.2h-.1v-.1l-.2 .1h-.3l-.2-.4h.2a.29 .29 0 0 0 .4 .3 .29 .29 0 0 0 .1-.5l-.3-.2-.2 .4h-.2z" fill-rule="evenodd"/>
<path d="M319.8 82h1v.2h-.5v1.1h-.1v-1.1h-.4z" fill-rule="evenodd"/>
<path d="M319.7 97h.5a.35 .35 0 0 1 .5 .3 .35 .35 0 0 1-.4 .4l.5 .5h-.2a.62 .62 0 0 0-.8-.5v.5h-.1v-.7h.7l.1-.2-.2-.2h-.5v.4h-.1z" fill-rule="evenodd"/>
<path d="M320 84.6l.3-.1 .3 .1 .1-.1v.8a.4 .4 0 0 1-.3 .5 .4 .4 0 0 1-.5-.3l.4 .2 .2-.2 .1-.2-.3 .1-.3-.1-.1-.3h.2a.3 .3 0 0 0 .4 .3 .3 .3 0 0 0 0-.5l-.2-.2-.2 .4h-.2z" fill-rule="evenodd"/>
<path d="M320.4 88.4h1v.2h-.8v.4h.7v.1h-.7v.5h.8v.1h-1z" fill-rule="evenodd"/>
<path d="M320.1 90.6h.2l.5 1.2h-.2l-.1-.3h-.6l-.1 .3h-.2l.2-.5h.6l-.2-.6-.2 .6h-.2z" fill-rule="evenodd"/>
<path d="M320.9 82h.2v1.2h.6v.1h-.8z" fill-rule="evenodd"/>
<path d="M320.8 90.6h.2l.2 1.1 .3-1.1h.2l.3 1.1 .3-1.1h.1l-.3 1.2h-.2l-.3-1.1-.3 1.1h-.2z" fill-rule="evenodd"/>
<path d="M321.3 94.9h.6l.2 .2-.1 .1a.27 .27 0 0 0-.3-.3 .27 .27 0 0 0-.2 .4l.2 .1a.43 .43 0 0 1 .4 .5 .43 .43 0 0 1-.7 .2l-.2-.3 .1-.1a.31 .31 0 0 0 .4 .3 .31 .31 0 0 0 .2-.4l-.6-.2z" fill-rule="evenodd"/>
<path d="M321 84.6l.2-.1a.43 .43 0 0 1 .6 .5h-.7l.2 .3 .4-.1a.44 .44 0 0 1-.5 .2 .44 .44 0 0 1-.3-.5h.7l-.3-.3-.4 .3z" fill-rule="evenodd"/>
<path d="M321.4 97h.2v.5h.7v-.5h.1v1.2h-.1v-.6h-.7v.6h-.2z" fill-rule="evenodd"/>
<path d="M321.6 88.4h.2l.7 1v-1h.1v1.3h-.1l-.7-1v1h-.2z" fill-rule="evenodd"/>
<path d="M321.8 85.7h1v.1h-1z" fill-rule="evenodd"/>
<path d="M322 82h.1v1.3h-.1z" fill-rule="evenodd"/>
<path d="M322.4 82h.2l.7 1v-1h.1v1.3h-.2l-.6-1v1h-.2z" fill-rule="evenodd"/>
<path d="M322.4 94.8h.9v.2h-.7v.4h.7v.1h-.7v.5h.8v.1h-1z" fill-rule="evenodd"/>
<path d="M322.6 90.6h.1v1.2h-.1z" fill-rule="evenodd"/>
<path d="M323 88.5h.6l.2 .2-.1 .1a.27 .27 0 0 0-.3-.3 .27 .27 0 0 0-.2 .4l.2 .1a.43 .43 0 0 1 .4 .5 .43 .43 0 0 1-.7 .2l-.2-.3 .1-.1a.31 .31 0 0 0 .4 .3 .31 .31 0 0 0 .2-.4l-.6-.2z" fill-rule="evenodd"/>
<path d="M323 90.6h.2l.7 1v-1h.1v1.2h-.1l-.7-1v1h-.2z" fill-rule="evenodd"/>
<path d="M322.8 97.1a.63 .63 0 0 1 1 .1 .63 .63 0 0 1-.3 .9 .63 .63 0 0 1-.8-.5h.1a.48 .48 0 0 0 .8 .4 .48 .48 0 0 0 0-.8l-.5-.1-.2 .2-.1 .3h-.1z" fill-rule="evenodd"/>
<path d="M323.7 82h.9v.2h-.7v.4h.7v.1h-.7v.5h.8v.1h-1z" fill-rule="evenodd"/>
<path d="M323.1 84.3l.6-.1 .3 .2-.2 .2a.45 .45 0 0 0-.6-.2 .45 .45 0 0 0-.1 .7l.4 .2 .2-.1 .2-.2h.1a.62 .62 0 0 1-.9 .3 .62 .62 0 0 1 0-1z" fill-rule="evenodd"/>
<path d="M324.1 97h.2v1.1h.6v.1h-.8z" fill-rule="evenodd"/>
<path d="M324.1 88.4h.2v1.3h-.2z" fill-rule="evenodd"/>
<path d="M323.6 94.8h.5a.39 .39 0 0 1 .5 .4 .39 .39 0 0 1-.5 .4h-.3v.5h-.2v-.7h.6l.2-.2-.1-.2h-.5v.4h-.2z" fill-rule="evenodd"/>
<path d="M324.2 84.5h.2v.7l.2 .1 .2-.1v-.7h.2v.9h-.2v-.1l-.3 .2-.2-.2z" fill-rule="evenodd"/>
<path d="M324.5 90.7l.6-.1 .3 .2v.1l-.1 .1a.49 .49 0 0 0-.7-.1 .49 .49 0 0 0 0 .7 .49 .49 0 0 0 .7 0v-.3h-.4v-.1h.6v.5a.69 .69 0 0 1-1 0 .69 .69 0 0 1 0-1z" fill-rule="evenodd"/>
<path d="M325.1 97h.9v.1h-.7v.4h.7v.2h-.7v.4h.7v.1h-.9z" fill-rule="evenodd"/>
<path d="M324.7 88.6a.63 .63 0 0 1 1 .1 .63 .63 0 0 1-.3 .9 .63 .63 0 0 1-.9-.5h.2a.48 .48 0 0 0 .8 .4 .48 .48 0 0 0-.1-.9h-.5l-.2 .5h-.2z" fill-rule="evenodd"/>
<path d="M325.2 84.3l.2-.1v.3h.1v.1h-.1v.6l.2 .2a.23 .23 0 0 1-.3 0 .23 .23 0 0 1-.1-.2v-.6h-.1z" fill-rule="evenodd"/>
<path d="M325.7 84.6l.5-.1 .2 .3h-.2a.18 .18 0 0 0-.2-.2 .18 .18 0 0 0-.1 .2l.1 .1a.33 .33 0 0 1 .3 .5 .33 .33 0 0 1-.5 0l-.2-.2 .2-.1a.2 .2 0 0 0 .2 .3 .2 .2 0 0 0 .1-.3 .36 .36 0 0 1-.4-.5z" fill-rule="evenodd"/>
<path d="M325.1 94.8h.2l.5 1.3h-.2l-.2-.4h-.5l-.1 .4h-.2l.2-.5h.6l-.2-.6-.3 .6h-.1z" fill-rule="evenodd"/>
<path d="M325.4 82h.4a.64 .64 0 0 1 .6 .7 .64 .64 0 0 1-.6 .6h-.4v-.1h.4a.49 .49 0 0 0 .5-.5 .49 .49 0 0 0-.5-.5h-.3v1h-.1z" fill-rule="evenodd"/>
<path d="M326 88.4h.1l.7 1v-1h.2v1.3h-.2l-.7-1v1h-.1z" fill-rule="evenodd"/>
<path d="M326.2 90.6h.9v.1h-.7v.4h.6v.2h-.6v.5h-.2z" fill-rule="evenodd"/>
<path d="M325.8 94.8h.6a.35 .35 0 0 1 .5 .3 .35 .35 0 0 1-.4 .4l.5 .6h-.2a.62 .62 0 0 0-.8-.6v.6h-.2v-.7h.8l.1-.3-.2-.1h-.5v.4h-.2z" fill-rule="evenodd"/>
<path d="M326.6 85.3h.2v.1h-.2z" fill-rule="evenodd"/>
<path d="M326.7 82h.9v.2h-.8v.4h.7v.1h-.7v.5h.8v.1h-.9z" fill-rule="evenodd"/>
<path d="M326.8 97h.1v1.1h.6v.1h-.7z" fill-rule="evenodd"/>
<path d="M327.3 88.5h.6l.3 .2-.2 .1a.27 .27 0 0 0-.3-.3 .27 .27 0 0 0-.2 .4l.2 .1a.43 .43 0 0 1 .5 .5 .43 .43 0 0 1-.8 .2l-.2-.3 .2-.1a.31 .31 0 0 0 .3 .3 .31 .31 0 0 0 .3-.4l-.7-.2z" fill-rule="evenodd"/>
<path d="M327.2 84.3l.7-.1 .3 .2v.1l-.1 .1a.49 .49 0 0 0-.8-.1 .49 .49 0 0 0 0 .7 .49 .49 0 0 0 .8 0v-.3h-.4v-.1h.5v.5a.69 .69 0 0 1-.9 0 .69 .69 0 0 1-.1-1z" fill-rule="evenodd"/>
<path d="M327.9 82h.8v.2h-.7v.4h.6v.1h-.6v.6h-.1z" fill-rule="evenodd"/>
<path d="M327.4 90.7a.63 .63 0 0 1 1 .1 .63 .63 0 0 1-.3 .9 .63 .63 0 0 1-.9-.5h.2a.48 .48 0 0 0 .8 .4 .48 .48 0 0 0-.1-.8h-.5l-.2 .4h-.2z" fill-rule="evenodd"/>
<path d="M327.5 94.8h.2l.5 1.3h-.2l-.2-.4h-.5l-.1 .4h-.2l.2-.5h.6l-.2-.6-.2 .6h-.2z" fill-rule="evenodd"/>
<path d="M327.9 97.1a.63 .63 0 0 1 .9 .1 .63 .63 0 0 1-.3 .9 .63 .63 0 0 1-.8-.5h.2a.48 .48 0 0 0 .7 .4 .48 .48 0 0 0-.1-.8h-.4l-.2 .4h-.2z" fill-rule="evenodd"/>
<path d="M328.1 94.8h1.1v.2h-.5v1.1h-.1v-1.1h-.5z" fill-rule="evenodd"/>
<path d="M329 82h.1v1.3h-.1z" fill-rule="evenodd"/>
<path d="M328.5 84.2l.8 .1 .1 .2-.2 .3 .2 .3a.39 .39 0 0 1-.4 .3h-.5v-.1l.7-.1v-.3l-.6-.1v.5h-.1v-.6h.4a.2 .2 0 0 0 .3-.1 .2 .2 0 0 0-.2-.3h-.4v.4h-.1z" fill-rule="evenodd"/>
<path d="M329.3 94.8h.9v.2h-.8v.4h.7v.1h-.7v.5h.8v.1h-.9z" fill-rule="evenodd"/>
<path d="M328.7 90.6h.5a.35 .35 0 0 1 .5 .3 .35 .35 0 0 1-.4 .4l.5 .5h-.2l-.4-.5h-.2h-.2v.5h-.1v-.7h.7l.1-.2-.2-.2h-.5v.4h-.1z" fill-rule="evenodd"/>
<path d="M329.4 82h.2l.7 1v-1h.1v1.3h-.1l-.7-1v1h-.2z" fill-rule="evenodd"/>
<path d="M329.1 88.6a.63 .63 0 0 1 .9 .1 .63 .63 0 0 1-.3 .9 .63 .63 0 0 1-.8-.5h.2a.48 .48 0 0 0 .7 .4 .48 .48 0 0 0-.1-.9h-.4l-.2 .5h-.2z" fill-rule="evenodd"/>
<path d="M329.3 97.1l.6-.1 .3 .2-.2 .2a.45 .45 0 0 0-.6-.2 .45 .45 0 0 0-.1 .7l.4 .2 .2-.1 .1-.2h.2a.62 .62 0 0 1-1 .3 .62 .62 0 0 1 .1-1z" fill-rule="evenodd"/>
<path d="M330.3 88.4h.9v.2h-.7v.4h.6v.1h-.6v.6h-.2z" fill-rule="evenodd"/>
<path d="M329.7 84.2h.5a.35 .35 0 0 1 .5 .3 .35 .35 0 0 1-.4 .4l.5 .5h-.2l-.4-.5h-.2h-.2v.5h-.1v-.7h.7l.1-.2-.1-.2h-.6v.4h-.1z" fill-rule="evenodd"/>
<path d="M330.7 82h.9v.2h-.7v.4h.7v.1h-.7v.5h.8v.1h-1z" fill-rule="evenodd"/>
<path d="M330.9 84.2h.2l-.1 .4z" fill-rule="evenodd"/>
<path d="M330.4 90.6h.6a.35 .35 0 0 1 .5 .3 .35 .35 0 0 1-.4 .4l.5 .5h-.2l-.4-.5h-.2h-.2v.5h-.2v-.7h.8l.1-.2-.2-.2h-.5v.4h-.2z" fill-rule="evenodd"/>
<path d="M331.2 84.2h.2l-.1 .4z" fill-rule="evenodd"/>
<path d="M330.8 97h.1l.6 1.2h-.2l-.2-.3h-.5l-.1 .3h-.2l.2-.5h.6l-.3-.6-.2 .6h-.1z" fill-rule="evenodd"/>
<path d="M330.9 94.8h.5a.64 .64 0 0 1 .6 .7 .64 .64 0 0 1-.6 .6h-.5v-.1h.5a.49 .49 0 0 0 .4-.5 .49 .49 0 0 0-.4-.5h-.3v1h-.2z" fill-rule="evenodd"/>
<path d="M331.7 90.6h1v.1h-.8v.4h.7v.2h-.7v.4h.8v.1h-1z" fill-rule="evenodd"/>
<path d="M331.4 97h1v.1h-.4v1.1h-.1v-1.1h-.5z" fill-rule="evenodd"/>
<path d="M332.2 84.3l.6-.1 .2 .3h-.2a.27 .27 0 0 0-.3-.3 .27 .27 0 0 0-.2 .4l.2 .1a.43 .43 0 0 1 .5 .6 .43 .43 0 0 1-.7 .1l-.3-.3 .2-.1a.31 .31 0 0 0 .3 .3 .31 .31 0 0 0 .3-.4l-.7-.2z" fill-rule="evenodd"/>
<path d="M331.9 82h.4a.64 .64 0 0 1 .6 .7 .64 .64 0 0 1-.5 .6h-.5v-.1h.4a.49 .49 0 0 0 .5-.5 .49 .49 0 0 0-.5-.5h-.2v1h-.2z" fill-rule="evenodd"/>
<path d="M332.6 97h.1v1.2h-.1z" fill-rule="evenodd"/>
<path d="M332 88.6l.6-.2 .3 .3-.1 .1a.45 .45 0 0 0-.7-.1 .45 .45 0 0 0 0 .6l.3 .3 .3-.1 .1-.2h.2a.62 .62 0 0 1-1 .3 .62 .62 0 0 1 0-1z" fill-rule="evenodd"/>
<path d="M332.2 94.8h.6a.35 .35 0 0 1 .4 .3 .35 .35 0 0 1-.3 .4l.4 .6h-.2l-.3-.5-.2-.1h-.2v.6h-.2v-.7h.7l.2-.2-.1-.2h-.6v.4h-.2z" fill-rule="evenodd"/>
<path d="M332.9 90.6h.9v.1h-.7v.4h.6v.2h-.6v.5h-.2z" fill-rule="evenodd"/>
<path d="M333.2 88.4h.2v1.3h-.2z" fill-rule="evenodd"/>
<path d="M333.5 94.8h.2v1.3h-.2z" fill-rule="evenodd"/>
<path d="M333.2 97.1a.63 .63 0 0 1 .9 .1 .63 .63 0 0 1-.3 .9 .63 .63 0 0 1-.8-.5h.2a.48 .48 0 0 0 .7 .4 .48 .48 0 0 0 0-.8l-.5-.1-.2 .2v.3h-.2z" fill-rule="evenodd"/>
<path d="M333.7 82h.2v1.3h-.2z" fill-rule="evenodd"/>
<path d="M334 94.8h.2v1.2h.6v.1h-.8z" fill-rule="evenodd"/>
<path d="M334 90.6h.9v.1h-.7v.4h.7v.2h-.7v.4h.8v.1h-1z" fill-rule="evenodd"/>
<path d="M333.3 84.2h.1v.7a.34 .34 0 0 0 .4 .4 .34 .34 0 0 0 .3-.4v-.7h.2v.7a.5 .5 0 0 1-.5 .6 .5 .5 0 0 1-.5-.6z" fill-rule="evenodd"/>
<path d="M334.2 82h.1l.7 1v-1h.2v1.3h-.2l-.7-1v1h-.1z" fill-rule="evenodd"/>
<path d="M333.7 88.4h.5a.35 .35 0 0 1 .5 .3 .35 .35 0 0 1-.4 .4l.5 .6h-.2a.62 .62 0 0 0-.8-.6v.6h-.1v-.7h.7l.1-.3-.2-.1h-.5v.4h-.1z" fill-rule="evenodd"/>
<path d="M334.4 97h.2l.7 1v-1h.1v1.2h-.1l-.7-1v1h-.2z" fill-rule="evenodd"/>
<path d="M334.5 84.2h.9v.1h-.7v.4h.6v.2h-.6v.5h-.2z" fill-rule="evenodd"/>
<path d="M335 94.8h.2v1.2h.6v.1h-.8z" fill-rule="evenodd"/>
<path d="M335.6 84.2h.9v.1h-.7v.4h.6v.2h-.6v.5h-.2z" fill-rule="evenodd"/>
<path d="M335.8 97.1l.6-.1 .2 .3h-.1a.27 .27 0 0 0-.3-.3 .27 .27 0 0 0-.2 .4l.2 .1a.43 .43 0 0 1 .4 .6 .43 .43 0 0 1-.7 .1l-.2-.3 .1-.1a.31 .31 0 0 0 .4 .3 .31 .31 0 0 0 .2-.4l-.6-.2z" fill-rule="evenodd"/>
<path d="M335.1 88.6l.6-.2 .3 .3-.2 .1a.45 .45 0 0 0-.6-.1 .45 .45 0 0 0-.1 .6l.4 .3 .2-.1 .2-.2h.1a.62 .62 0 0 1-.9 .3 .62 .62 0 0 1 0-1z" fill-rule="evenodd"/>
<path d="M335.2 90.6h.6a.35 .35 0 0 1 .4 .3 .35 .35 0 0 1-.4 .4l.5 .5h-.2l-.3-.5h-.2h-.2v.5h-.2v-.7l.8-.1a.21 .21 0 0 0 0-.2 .21 .21 0 0 0-.2-.1h-.4v.4h-.2z" fill-rule="evenodd"/>
<path d="M336 82.1h.6l.2 .2-.1 .1a.27 .27 0 0 0-.3-.3 .27 .27 0 0 0-.2 .4l.2 .1a.43 .43 0 0 1 .5 .5 .43 .43 0 0 1-.8 .2l-.2-.3 .1-.1a.31 .31 0 0 0 .4 .3 .31 .31 0 0 0 .3-.4l-.7-.2z" fill-rule="evenodd"/>
<path d="M336.4 94.8h.9v.2h-.7v.4h.6v.1h-.6v.6h-.2z" fill-rule="evenodd"/>
<path d="M336.5 90.6h.9v.1h-.8v.4h.7v.2h-.7v.4h.8v.1h-.9z" fill-rule="evenodd"/>
<path d="M336.7 84.2h.2v1.2h-.2z" fill-rule="evenodd"/>
<path d="M336.9 98.1h.2v.1h-.2z" fill-rule="evenodd"/>
<path d="M336.2 88.4h.2v.8a.34 .34 0 0 0 .3 .4 .34 .34 0 0 0 .4-.4v-.8h.1v.8a.5 .5 0 0 1-.5 .5 .5 .5 0 0 1-.5-.5z" fill-rule="evenodd"/>
<path d="M337.1 84.2h.2l.4 .4 .3-.4h.2l-.4 .6 .4 .6h-.2l-.3-.5-.4 .5h-.2l.5-.6z" fill-rule="evenodd"/>
<path d="M337.1 82h.9v.2h-.7v.4h.7v.1h-.7v.5h.8v.1h-1z" fill-rule="evenodd"/>
<path d="M337.5 88.4h.3l.3 1.1 .4-1.1h.2v1.3h-.1v-1.1l-.4 1.1h-.2l-.3-1.1v1.1h-.2z" fill-rule="evenodd"/>
<path d="M337.5 94.8h.2v1.3h-.2z" fill-rule="evenodd"/>
<path d="M337.7 90.6h.1l.7 1v-1h.2v1.2h-.2l-.7-1v1h-.1z" fill-rule="evenodd"/>
<path d="M338 94.8h.1v1.2h.7v.1h-.8z" fill-rule="evenodd"/>
<path d="M338.4 85.3h.2v.1h-.2z" fill-rule="evenodd"/>
<path d="M338.3 82h.5a.39 .39 0 0 1 .5 .4 .39 .39 0 0 1-.5 .4h-.3v.5h-.2v-.7h.7l.1-.2-.1-.2h-.5v.4h-.2z" fill-rule="evenodd"/>
<path d="M339.1 88.5h.6l.2 .2-.1 .1a.27 .27 0 0 0-.4-.3 .27 .27 0 0 0-.2 .4l.3 .1a.43 .43 0 0 1 .4 .5 .43 .43 0 0 1-.7 .2l-.2-.3 .1-.1a.31 .31 0 0 0 .3 .3 .31 .31 0 0 0 .3-.4l-.6-.2z" fill-rule="evenodd"/>
<path d="M339 94.8h.9v.2h-.8v.4h.7v.1h-.7v.5h.8v.1h-.9z" fill-rule="evenodd"/>
<path d="M339.1 90.7l.6-.1 .3 .2-.2 .2a.45 .45 0 0 0-.6-.2 .45 .45 0 0 0-.1 .7l.4 .2 .2-.1 .1-.2h.2a.62 .62 0 0 1-.9 .3 .62 .62 0 0 1 0-1z" fill-rule="evenodd"/>
<path d="M340.2 94.9h.6l.3 .2-.2 .1a.27 .27 0 0 0-.3-.3 .27 .27 0 0 0-.2 .4l.2 .1a.43 .43 0 0 1 .5 .5 .43 .43 0 0 1-.7 .2l-.3-.3 .2-.1a.31 .31 0 0 0 .3 .3 .31 .31 0 0 0 .3-.4l-.7-.2z" fill-rule="evenodd"/>
<path d="M340.2 88.4h.2v1.3h-.2z" fill-rule="evenodd"/>
<path d="M340.2 90.6h.9v.1h-.7v.4h.7v.2h-.7v.4h.8v.1h-1z" fill-rule="evenodd"/>
<path d="M339.8 82h.2l.5 1.3h-.2l-.2-.4h-.5l-.1 .4h-.2l.2-.5h.6l-.2-.6-.2 .6h-.2z" fill-rule="evenodd"/>
<path d="M340.7 88.4h.9l-.8 1.2h.8v.1h-1l.8-1.1h-.7z" fill-rule="evenodd"/>
<path d="M340.6 82h.5a.35 .35 0 0 1 .5 .3 .35 .35 0 0 1-.4 .4l.5 .6h-.2a.62 .62 0 0 0-.8-.6v.6h-.1v-.7h.7l.1-.3-.2-.1h-.5v.4h-.1z" fill-rule="evenodd"/>
<path d="M341.8 88.4h.9v.2h-.8v.4h.7v.1h-.7v.5h.8v.1h-.9z" fill-rule="evenodd"/>
<path d="M341.7 94.8h.2l.2 1.1 .3-1.1h.2l.3 1.1 .3-1.1h.2l-.4 1.3h-.2l-.3-1.1-.3 1.1h-.1z" fill-rule="evenodd"/>
<path d="M342 90.7a.63 .63 0 0 1 1 .1 .63 .63 0 0 1-.3 .9 .63 .63 0 0 1-.9-.5h.2a.48 .48 0 0 0 .8 .4 .48 .48 0 0 0-.1-.8h-.5l-.2 .4h-.2z" fill-rule="evenodd"/>
<path d="M342.2 82h.2l.5 1.3h-.2l-.2-.4h-.5l-.1 .4h-.2l.2-.5h.6l-.2-.6-.2 .6h-.2z" fill-rule="evenodd"/>
<path d="M342.9 82h1v.2h-.5v1.1h-.1v-1.1h-.4z" fill-rule="evenodd"/>
<path d="M343.3 90.6h.1l.7 1v-1h.2v1.2h-.2l-.7-1v1h-.1z" fill-rule="evenodd"/>
<path d="M342.9 88.4h.5a.64 .64 0 0 1 .6 .7 .64 .64 0 0 1-.6 .6h-.5v-.1h.5a.49 .49 0 0 0 .4-.5 .49 .49 0 0 0-.4-.5h-.3v1h-.2z" fill-rule="evenodd"/>
<path d="M343.5 94.8h.2v1.3h-.2z" fill-rule="evenodd"/>
<path d="M344 82h.9v.2h-.8v.4h.7v.1h-.7v.5h.8v.1h-.9z" fill-rule="evenodd"/>
<path d="M343.9 94.8h1v.2h-.4v1.1h-.2v-1.1h-.4z" fill-rule="evenodd"/>
<path d="M344.6 90.6h.1v1.1h.7v.1h-.8z" fill-rule="evenodd"/>
<path d="M345.1 94.8h.2v.6h.6v-.6h.2v1.3h-.2v-.6h-.6v.6h-.2z" fill-rule="evenodd"/>
<path d="M344.7 88.4h.6a.35 .35 0 0 1 .4 .3 .35 .35 0 0 1-.3 .4l.4 .6h-.2a.62 .62 0 0 0-.7-.6v.6h-.2v-.7l.8-.1a.21 .21 0 0 0 0-.3 .21 .21 0 0 0-.2 0h-.4v.4h-.2z" fill-rule="evenodd"/>
<path d="M345.4 90.6h.2l.3 .6 .4-.6h.2l-.5 .7v.5h-.2v-.5z" fill-rule="evenodd"/>
<path d="M346 88.4h.9v.2h-.7v.4h.7v.1h-.7v.5h.8v.1h-1z" fill-rule="evenodd"/>
<path d="M345.8 82.2l.6-.2 .3 .2 .1 .2h-.2a.49 .49 0 0 0-.7 0 .49 .49 0 0 0 0 .7 .49 .49 0 0 0 .7-.1v-.2h-.4v-.1h.6v.4a.69 .69 0 0 1-1 .1 .69 .69 0 0 1 0-1z" fill-rule="evenodd"/>
<path d="M346.5 91.7h.2v.1h-.2z" fill-rule="evenodd"/>
<path d="M346.8 94.8h.2v.5z" fill-rule="evenodd"/>
<path d="M347 82h1v.2h-.8v.4h.7v.1h-.7v.5h.8v.1h-1z" fill-rule="evenodd"/>
<path d="M347.1 94.8h.2l-.1 .5z" fill-rule="evenodd"/>
<path d="M347.5 95.9h.2v.2h-.2z" fill-rule="evenodd"/>
<path d="M347.3 88.6l.6-.2 .3 .3-.1 .1a.45 .45 0 0 0-.7-.1 .45 .45 0 0 0 0 .6l.3 .3 .3-.1 .1-.2h.2a.62 .62 0 0 1-1 .3 .62 .62 0 0 1 0-1z" fill-rule="evenodd"/>
<path d="M348 94.8h.4a.64 .64 0 0 1 .6 .7 .64 .64 0 0 1-.5 .6h-.5v-.1h.4a.49 .49 0 0 0 .5-.5 .49 .49 0 0 0-.5-.5h-.2v1h-.2z" fill-rule="evenodd"/>
<path d="M348.4 88.4h1v.2h-.4v1.1h-.2v-1.1h-.4z" fill-rule="evenodd"/>
<path d="M348.2 82h.6a.35 .35 0 0 1 .4 .3 .35 .35 0 0 1-.3 .4l.4 .6h-.2a.62 .62 0 0 0-.7-.6v.6h-.2v-.7h.7l.2-.3-.2-.1h-.5v.4h-.2z" fill-rule="evenodd"/>
<path d="M349.3 94.8h.5a.35 .35 0 0 1 .5 .3 .35 .35 0 0 1-.4 .4l.5 .6h-.2a.62 .62 0 0 0-.8-.6v.6h-.1v-.7h.7l.1-.3-.2-.1h-.5v.4h-.1z" fill-rule="evenodd"/>
<path d="M349.5 82l.8 .1 .1 .3-.2 .2 .3 .3a.38 .38 0 0 1-.5 .4h-.5v-.1l.8-.2-.1-.2-.5-.1v.5h-.2v-.6h.4a.2 .2 0 0 0 .3-.2 .2 .2 0 0 0-.2-.2h-.3v.4h-.2z" fill-rule="evenodd"/>
<path d="M349.8 88.4h.2l.5 1.3h-.1l-.2-.4h-.5l-.2 .4h-.1l.2-.5h.6l-.3-.6-.2 .6h-.1z" fill-rule="evenodd"/>
<path d="M350.6 94.8h.1v1.2h.6v.1h-.7z" fill-rule="evenodd"/>
<path d="M350.6 88.4h.2l.7 1v-1h.1v1.3h-.2l-.6-1v1h-.2z" fill-rule="evenodd"/>
<path d="M350.7 82h.9v.2h-.7v.4h.7v.1h-.7v.5h.7v.1h-.9z" fill-rule="evenodd"/>
<path d="M351.5 94.8h.2l-.1 .5z" fill-rule="evenodd"/>
<path d="M351.8 94.8h.2l-.1 .5z" fill-rule="evenodd"/>
<path d="M352 88.6l.7-.2 .3 .2v.2h-.1a.49 .49 0 0 0-.8 0 .49 .49 0 0 0 0 .7 .49 .49 0 0 0 .8-.1v-.2h-.4v-.1h.5v.4a.69 .69 0 0 1-.9 .1 .69 .69 0 0 1-.1-1z" fill-rule="evenodd"/>
<path d="M351.9 82h.5a.35 .35 0 0 1 .5 .3 .35 .35 0 0 1-.4 .4l.5 .6h-.2a.62 .62 0 0 0-.8-.6v.6h-.1v-.7h.7l.1-.3-.2-.1h-.5v.4h-.1z" fill-rule="evenodd"/>
<path d="M352.8 94.9h.6l.2 .2-.2 .1a.27 .27 0 0 0-.3-.3 .27 .27 0 0 0-.2 .4l.2 .1a.43 .43 0 0 1 .5 .5 .43 .43 0 0 1-.7 .2l-.3-.3 .2-.1a.31 .31 0 0 0 .3 .3 .31 .31 0 0 0 .3-.4l-.7-.2z" fill-rule="evenodd"/>
<path d="M353.3 88.4h.1v1.2h.7v.1h-.8z" fill-rule="evenodd"/>
<path d="M353.7 82h.8v.2h-.7v.4h.6v.1h-.6v.6h-.1z" fill-rule="evenodd"/>
<path d="M354.3 88.4h.9v.2h-.8v.4h.7v.1h-.7v.5h.8v.1h-.9z" fill-rule="evenodd"/>
<path d="M353.9 94.8h.1v.8a.34 .34 0 0 0 .4 .4 .34 .34 0 0 0 .3-.4v-.8h.2v.8a.5 .5 0 0 1-.5 .5 .5 .5 0 0 1-.5-.5z" fill-rule="evenodd"/>
<path d="M354.8 82h.1v1.3h-.1z" fill-rule="evenodd"/>
<path d="M355.1 94.8h.9v.2h-.7v.4h.6v.1h-.6v.6h-.2z" fill-rule="evenodd"/>
<path d="M355.2 82h.2v1.2h.6v.1h-.8z" fill-rule="evenodd"/>
<path d="M356 88.5h.6l.3 .2-.2 .1a.27 .27 0 0 0-.3-.3 .27 .27 0 0 0-.2 .4l.2 .1a.43 .43 0 0 1 .5 .5 .43 .43 0 0 1-.8 .2l-.2-.3 .1-.1a.31 .31 0 0 0 .4 .3 .31 .31 0 0 0 .3-.4l-.7-.2z" fill-rule="evenodd"/>
<path d="M356.2 82h.9v.2h-.7v.4h.7v.1h-.7v.5h.8v.1h-1z" fill-rule="evenodd"/>
<path d="M356.2 94.8h.9v.2h-.7v.4h.6v.1h-.6v.6h-.2z" fill-rule="evenodd"/>
<path d="M357.1 88.4h.2v.6h.7v-.6h.1v1.3h-.1v-.6h-.7v.6h-.2z" fill-rule="evenodd"/>
<path d="M357.3 94.8h.2v1.3h-.2z" fill-rule="evenodd"/>
<path d="M357.7 94.8h.2l.4 .5 .3-.5h.2l-.4 .6 .4 .7h-.2l-.3-.5-.4 .5h-.2l.5-.7z" fill-rule="evenodd"/>
<path d="M357.8 82h.1l.3 1.1 .3-1.1h.2l.3 1.1 .2-1.1h.2l-.3 1.3h-.2l-.3-1.1-.3 1.1h-.2z" fill-rule="evenodd"/>
<path d="M358.5 88.6a.63 .63 0 0 1 1 .1 .63 .63 0 0 1-.3 .9 .63 .63 0 0 1-.8-.5h.1a.48 .48 0 0 0 .8 .4 .48 .48 0 0 0-.1-.9h-.5l-.2 .5h-.1z" fill-rule="evenodd"/>
<path d="M359.6 82h.2v1.3h-.2z" fill-rule="evenodd"/>
<path d="M359.7 88.4h.2l.2 1.1 .3-1.1h.2l.3 1.1 .2-1.1h.2l-.3 1.3h-.2l-.3-1.1-.3 1.1h-.2z" fill-rule="evenodd"/>
<path d="M360 82h1v.2h-.4v1.1h-.2v-1.1h-.4z" fill-rule="evenodd"/>
<path d="M361.2 82h.1v.6h.7v-.6h.2v1.3h-.2v-.6h-.7v.6h-.1z" fill-rule="evenodd"/>
<path d="M361.5 88.4h.1l.7 1v-1h.2v1.3h-.2l-.7-1v1h-.1z" fill-rule="evenodd"/>
<path d="M363.4 88.6a.63 .63 0 0 1 1 .1 .63 .63 0 0 1-.4 .9 .63 .63 0 0 1-.8-.5h.2a.48 .48 0 0 0 .7 .4 .48 .48 0 0 0 0-.8l-.5-.1-.2 .2v.3h-.2z" fill-rule="evenodd"/>
<path d="M364.6 88.4h.2l.7 1v-1h.1v1.3h-.1l-.7-1v1h-.2z" fill-rule="evenodd"/>
<path d="M366.3 88.4h1v.2h-.4v1.1h-.2v-1.1h-.4z" fill-rule="evenodd"/>
<path d="M367.5 88.4h.1v.6h.7v-.6h.2v1.3h-.2v-.6h-.7v.6h-.1z" fill-rule="evenodd"/>
<path d="M368.8 88.4h.1v1.3h-.1z" fill-rule="evenodd"/>
<path d="M369.3 88.5h.6l.2 .2-.1 .1a.27 .27 0 0 0-.3-.3 .27 .27 0 0 0-.2 .4l.2 .1a.43 .43 0 0 1 .5 .5 .43 .43 0 0 1-.8 .2l-.2-.3 .1-.1a.31 .31 0 0 0 .4 .3 .31 .31 0 0 0 .3-.4l-.7-.2z" fill-rule="evenodd"/>
<path d="M24.6 115.4h1.5l-.4 .3v2a.4 .4 0 0 0 .4 .5h-1.5l.3-.1 .1-.4v-2z" fill-rule="evenodd"/>
<path d="M26.3 116.3h.8v.3a.59 .59 0 0 1 .6-.4 .59 .59 0 0 1 .5 .4 .61 .61 0 0 1 .8-.3 .61 .61 0 0 1 .3 .7l.1 1 .1 .2h-.9l.2-.2v-1.2a.27 .27 0 0 0-.3-.3 .27 .27 0 0 0-.3 .3v1.2l.2 .2h-1l.2-.2v-1.2a.22 .22 0 0 0-.1-.3 .22 .22 0 0 0-.3 .2l-.1 .1v1l.2 .4h-1l.2-.4v-1.3z" fill-rule="evenodd"/>
<path d="M29.7 116.3h.8v.3a.73 .73 0 0 1 1-.2 .73 .73 0 0 1 .3 .9 .77 .77 0 0 1-.3 .8 .77 .77 0 0 1-1-.1l.1 .9 .2 .2h-1.1l.3-.2v-2.1h.5v1a.31 .31 0 0 0 .3 .3 .31 .31 0 0 0 .3-.3v-1.1a.31 .31 0 0 0-.3-.2 .31 .31 0 0 0-.3 .3h-.5l-.1-.4z" fill-rule="evenodd"/>
<path d="M32.4 116.5a.77 .77 0 0 1 .9-.2 .77 .77 0 0 1 .5 .9h-1.1a.54 .54 0 0 0 .3 .7 .54 .54 0 0 0 .7-.3 .79 .79 0 0 1-1 .7 .79 .79 0 0 1-.6-1l.1-.3 1 .1-.1-.7a.37 .37 0 0 0-.4 .2 .37 .37 0 0 0 0 .4h-.5z" fill-rule="evenodd"/>
<path d="M35 115.4h.9v2.5l.2 .2-.8 .2v-.3a.75 .75 0 0 1-1 .1 .75 .75 0 0 1-.3-.9h.6l.1 .6a.31 .31 0 0 0 .3 .2 .31 .31 0 0 0 .3-.2v-1.1a.34 .34 0 0 0-.4-.2 .34 .34 0 0 0-.3 .4v.3h-.6a.77 .77 0 0 1 .4-.8 .77 .77 0 0 1 .9 .1v-.9z" fill-rule="evenodd"/>
<path d="M36.5 116.5a.79 .79 0 0 1 .9-.3 .79 .79 0 0 1 .6 .8v.9h.2a.39 .39 0 0 1-.4 .3 .39 .39 0 0 1-.4-.3 .52 .52 0 0 1-.5 .4 .52 .52 0 0 1-.5-.4v-.2h.5l.2 .2 .3-.1v-.6l-.5 .5h-.5l.3-.3 .7-.4v-.4a.25 .25 0 0 0-.4-.2 .25 .25 0 0 0 0 .4 .3 .3 0 0 1-.5 .2 .3 .3 0 0 1 0-.5z" fill-rule="evenodd"/>
<path d="M38.4 116.3h.8v.3a.59 .59 0 0 1 .8-.3 .59 .59 0 0 1 .3 .8v.9l.2 .2h-1l.2-.2v-1.3a.21 .21 0 0 0-.2-.2 .21 .21 0 0 0-.2 .2l-.1 1.1 .2 .4h-1l.2-.4v-1.3z" fill-rule="evenodd"/>
<path d="M41.1 116.5a.63 .63 0 0 1 .8-.3 .63 .63 0 0 1 .4 .7 .38 .38 0 0 1-.5 0 .38 .38 0 0 1-.1-.5h-.1a.92 .92 0 0 0 .4 1.5l.3-.2a.83 .83 0 0 1-1.1 .5 .83 .83 0 0 1-.4-1.1z" fill-rule="evenodd"/>
<path d="M42.9 116.5a.77 .77 0 0 1 .9-.2 .77 .77 0 0 1 .4 .9h-1a.54 .54 0 0 0 .3 .7 .54 .54 0 0 0 .7-.3 .79 .79 0 0 1-1 .7 .79 .79 0 0 1-.6-1l.1-.3 1 .1-.1-.7a.37 .37 0 0 0-.4 .2 .37 .37 0 0 0 0 .4h-.5z" fill-rule="evenodd"/>
<path d="M45.5 115.4h2.5v.8a.76 .76 0 0 0-1-.6l.1 2.3 .3 .3h-1.4l.4-.3v-2.3a.75 .75 0 0 0-.9 .6z" fill-rule="evenodd"/>
<path d="M48.1 116.5a.79 .79 0 0 1 .9-.3 .79 .79 0 0 1 .5 .8v.9h.2a.39 .39 0 0 1-.4 .3 .39 .39 0 0 1-.4-.3 .52 .52 0 0 1-.5 .4 .52 .52 0 0 1-.5-.4l.1-.2h.5l.2 .2 .2-.1v-.6l-.4 .5h-.5l.2-.3 .7-.4v-.4a.25 .25 0 0 0-.3-.2 .25 .25 0 0 0-.1 .4 .3 .3 0 0 1-.4 .2 .3 .3 0 0 1 0-.5z" fill-rule="evenodd"/>
<path d="M49.9 115.4h.8v1.1a.78 .78 0 0 1 1-.1 .78 .78 0 0 1 .3 1 .88 .88 0 0 1-.5 .8 .88 .88 0 0 1-1-.1l-.4 .2v-1.6h.6a1.56 1.56 0 0 0 .1 1.4h.3a1.44 1.44 0 0 0 0-1.6l-.4 .2h-.6v-1.1z" fill-rule="evenodd"/>
<path d="M52.3 115.4h.8v2.6l.2 .2h-1l.2-.4v-2.1z" fill-rule="evenodd"/>
<path d="M53.8 116.5a.77 .77 0 0 1 .9-.2 .77 .77 0 0 1 .4 .9h-1.1a.54 .54 0 0 0 .3 .7 .54 .54 0 0 0 .7-.3 .79 .79 0 0 1-.9 .7 .79 .79 0 0 1-.6-1v-.3l1.1 .1-.2-.7a.37 .37 0 0 0-.4 .2 .37 .37 0 0 0 0 .4h-.5z" fill-rule="evenodd"/>
<path d="M57.4 104.7h.2l.5 .8v-.8h.1v1h-.1l-.5-.8v.8h-.2z" fill-rule="evenodd"/>
<path d="M57.3 102.6h.9v.2h-.4v.9h-.1v-.9h-.4z" fill-rule="evenodd"/>
<path d="M58.3 103a.37 .37 0 0 1 .5 .1 .37 .37 0 0 1-.2 .5 .37 .37 0 0 1-.4-.3h.1a.25 .25 0 0 0 .3 .2 .25 .25 0 0 0 .1-.4 .25 .25 0 0 0-.4 0v.2h-.1z" fill-rule="evenodd"/>
<path d="M58.5 105a.37 .37 0 0 1 .6 .1 .37 .37 0 0 1-.2 .6 .37 .37 0 0 1-.5-.4h.1a.25 .25 0 0 0 .4 .2 .25 .25 0 0 0 .1-.4 .25 .25 0 0 0-.4 .1l-.1 .1h-.1z" fill-rule="evenodd"/>
<path d="M58.9 102.7h.2v.2h.1l-.1 .1v.5l.1 .2-.2-.1-.1-.6z" fill-rule="evenodd"/>
<path d="M59.3 104.8l.1-.1v.3h.1l-.1 .1v.4l.1 .2h-.2v-.6h-.1z" fill-rule="evenodd"/>
<path d="M59.4 103h.5l.1 .7-.2-.1-.4 .1-.1-.2h.1a.17 .17 0 0 0 .3 .1 .17 .17 0 0 0 0-.3l-.4 .2 .1-.2 .4-.1-.1-.2-.4 .1z" fill-rule="evenodd"/>
<path d="M59.7 105.1l.3-.1 .3 .2v.2h-.6l.1 .2 .5-.1a.36 .36 0 0 1-.5 .2 .36 .36 0 0 1-.2-.4h.6l-.3-.2-.3 .2z" fill-rule="evenodd"/>
<path d="M60.1 102.6h.1v1.1h-.1z" fill-rule="evenodd"/>
<path d="M60.5 105h.1v.1h-.1z" fill-rule="evenodd"/>
<path d="M60.5 105.6h.1v.1h-.1z" fill-rule="evenodd"/>
<path d="M60.9 102.7h.1v.2h.1l-.1 .1v.5l.1 .2-.2-.1-.1-.6z" fill-rule="evenodd"/>
<path d="M61.2 102.6h.2v.4l.2-.1 .2 .1v.7h-.1v-.6l-.1-.1-.2 .1v.6h-.2z" fill-rule="evenodd"/>
<path d="M61.3 105.1l.3-.1 .3 .2v.2h-.6l.1 .2 .5-.1a.36 .36 0 0 1-.5 .2 .36 .36 0 0 1-.2-.4h.5l-.2-.2-.3 .2z" fill-rule="evenodd"/>
<path d="M62 105h.1l.2 .2 .2-.2h.1l-.2 .3 .2 .4h-.1l-.2-.3-.2 .3h-.2l.3-.4z" fill-rule="evenodd"/>
<path d="M62 102.6h.2v.2h-.2z" fill-rule="evenodd"/>
<path d="M62 102.9h.2v.8h-.2z" fill-rule="evenodd"/>
<path d="M62.4 103l.4-.1 .2 .2-.2 .1a.21 .21 0 0 0-.3-.1 .21 .21 0 0 0 0 .4 .21 .21 0 0 0 .3-.1h.2a.37 .37 0 0 1-.6 .2 .37 .37 0 0 1 0-.6z" fill-rule="evenodd"/>
<path d="M62.8 104.8l.1-.1v.3h.1l-.1 .1v.4l.1 .2h-.2l-.1-.6z" fill-rule="evenodd"/>
<path d="M63.1 102.6h.1v.6l.5-.3-.3 .3 .3 .5h-.2l-.2-.4-.1 .4h-.1z" fill-rule="evenodd"/>
<path d="M63.2 105.1l.3-.1 .3 .2v.2h-.6l.2 .2 .4-.1a.36 .36 0 0 1-.5 .2 .36 .36 0 0 1-.2-.4h.6l-.2-.2-.4 .2z" fill-rule="evenodd"/>
<path d="M63.8 102.9l.5 .1 .1 .7h-.1v-.6l-.2-.1-.2 .1v.6h-.1z" fill-rule="evenodd"/>
<path d="M63.9 105l.2 .1 .3-.1-.3 .2v.5h-.2z" fill-rule="evenodd"/>
<path d="M64.4 105h.6v.7h-.1v-.5l-.2-.1-.1 .1v.5h-.2z" fill-rule="evenodd"/>
<path d="M64.6 103l.4-.1 .2 .2v.2h-.5l.1 .3 .4-.2a.36 .36 0 0 1-.4 .3 .36 .36 0 0 1-.3-.5h.6l-.2-.2-.4 .2z" fill-rule="evenodd"/>
<path d="M65.4 103l.4-.1 .1 .2h-.1a.14 .14 0 0 0-.2-.1 .14 .14 0 0 0-.1 .2h.2a.28 .28 0 0 1 .2 .3 .28 .28 0 0 1-.3 .3 .28 .28 0 0 1-.3-.4h.2a.16 .16 0 0 0 .1 .2 .16 .16 0 0 0 .1-.2l-.3-.1z" fill-rule="evenodd"/>
<path d="M65.3 105h.5l.1 .7-.2-.1-.4 .1-.1-.2h.1a.17 .17 0 0 0 .3 .1 .17 .17 0 0 0 0-.2l-.4 .1 .1-.2 .4-.1-.1-.1-.4 .1z" fill-rule="evenodd"/>
<path d="M66 104.7h.1v1h-.1z" fill-rule="evenodd"/>
<path d="M66.1 103l.4-.1 .1 .2h-.1a.14 .14 0 0 0-.2-.1 .14 .14 0 0 0 0 .2h.1a.28 .28 0 0 1 .2 .3 .28 .28 0 0 1-.3 .3 .28 .28 0 0 1-.2-.4h.1a.16 .16 0 0 0 .2 .2 .16 .16 0 0 0 .1-.2l-.4-.1z" fill-rule="evenodd"/>
<path d="M66.7 104.7h.2v1h-.2z" fill-rule="evenodd"/>
<path d="M66.9 102.9h.1v.2h-.1z" fill-rule="evenodd"/>
<path d="M66.9 103.5h.1v.2h-.1z" fill-rule="evenodd"/>
<path d="M67.1 105h.5l.1 .7-.2-.1-.3 .1-.2-.2h.1a.17 .17 0 0 0 .3 .1 .17 .17 0 0 0 .1-.2l-.5 .1 .1-.2 .4-.1-.1-.1-.4 .1z" fill-rule="evenodd"/>
<path d="M67.8 105h.1l.2 .6 .2-.6h.2l-.5 1-.2-.1 .3-.2z" fill-rule="evenodd"/>
<path d="M67.7 102.7l.1-.1a.51 .51 0 0 1 .5 .6 .51 .51 0 0 1-.5 .5l-.2-.3v-.2h.1a.26 .26 0 0 0 0 .3 .26 .26 0 0 0 .4 0 .26 .26 0 0 0 0-.3 .26 .26 0 0 0 0-.4 .26 .26 0 0 0-.4 0 .26 .26 0 0 0 0 .4h-.1z" fill-rule="evenodd"/>
<path d="M68.4 103.5h.2v.2h-.2z" fill-rule="evenodd"/>
<path d="M68.8 102.7h.7l-.4 1h-.2l.1-.3 .3-.6h-.5z" fill-rule="evenodd"/>
<path d="M68.6 105.1l.4-.1 .2 .2v.2h-.5l.1 .2 .4-.1a.36 .36 0 0 1-.4 .2 .36 .36 0 0 1-.3-.4h.6l-.2-.2-.4 .2z" fill-rule="evenodd"/>
<path d="M69.4 105l.1 .1 .3-.1-.3 .2v.5h-.1z" fill-rule="evenodd"/>
<path d="M69.7 102.7h.4l.1 .2-.3-.2a.19 .19 0 0 0-.2 .1 .19 .19 0 0 0 0 .3 .19 .19 0 0 0 .3-.1 .34 .34 0 0 1 .3 .4 .34 .34 0 0 1-.4 .3 .34 .34 0 0 1-.3-.4h.1a.21 .21 0 0 0 .3 .2 .21 .21 0 0 0 .1-.3 .21 .21 0 0 0-.4 .1h-.1z" fill-rule="evenodd"/>
<path d="M70.3 104.8l.1-.1v.3h.1l-.1 .1v.4l.1 .2h-.2l-.1-.6z" fill-rule="evenodd"/>
<path d="M70.6 104.7h.2v.4l.2-.1 .2 .1 .1 .6h-.2v-.5l-.1-.1-.2 .1v.5h-.2z" fill-rule="evenodd"/>
<path d="M70.5 102.9l.3-.3v1.1h-.1v-.8l-.2 .1z" fill-rule="evenodd"/>
<path d="M71.2 102.9l.6 .1 .3-.1 .1 .8h-.1v-.6l-.1-.1-.2 .2v.5h-.2v-.6l-.1-.1-.1 .1-.1 .6h-.1z" fill-rule="evenodd"/>
<path d="M71.4 104.7h.2v.1h-.2z" fill-rule="evenodd"/>
<path d="M71.4 105h.2v.7h-.2z" fill-rule="evenodd"/>
<path d="M71.8 105h.4l.2 .2h-.2a.21 .21 0 0 0-.3 0 .21 .21 0 0 0 0 .3 .21 .21 0 0 0 .3 0h.2a.37 .37 0 0 1-.6 .1 .37 .37 0 0 1 0-.6z" fill-rule="evenodd"/>
<path d="M72.4 102.9l.6 .1 .3-.1 .1 .8h-.1v-.6l-.1-.1-.2 .2v.5h-.2v-.6l-.1-.1-.2 .1v.6h-.1z" fill-rule="evenodd"/>
<path d="M72.5 104.7h.1v.6l.5-.3-.3 .3 .3 .4h-.2l-.2-.4-.1 .4h-.1z" fill-rule="evenodd"/>
<path d="M73.2 105h.6v.7h-.1v-.5l-.2-.1-.2 .1v.5h-.1z" fill-rule="evenodd"/>
<path d="M74.1 105.1l.3-.1 .2 .2v.2h-.5l.1 .2 .4-.1a.36 .36 0 0 1-.4 .2 .36 .36 0 0 1-.2-.4h.5l-.2-.2-.3 .2z" fill-rule="evenodd"/>
<path d="M74.8 105h.4l.1 .2h-.1a.14 .14 0 0 0-.2-.2 .14 .14 0 0 0 0 .2l.1 .1a.28 .28 0 0 1 .2 .3 .28 .28 0 0 1-.3 .2 .28 .28 0 0 1-.3-.3h.2a.16 .16 0 0 0 .2 .2 .16 .16 0 0 0 .1-.3l-.4-.1z" fill-rule="evenodd"/>
<path d="M75.5 105h.4l.2 .2h-.2a.14 .14 0 0 0-.1-.2 .14 .14 0 0 0-.1 .2l.1 .1a.28 .28 0 0 1 .2 .3 .28 .28 0 0 1-.3 .2 .28 .28 0 0 1-.2-.3h.1a.16 .16 0 0 0 .2 .2 .16 .16 0 0 0 .1-.3l-.4-.1z" fill-rule="evenodd"/>
<path d="M76.3 105.1l.3-.1 .2 .2 .1 .2h-.6l.1 .2 .5-.1a.36 .36 0 0 1-.5 .2 .36 .36 0 0 1-.2-.4h.5l-.2-.2-.3 .2z" fill-rule="evenodd"/>
<path d="M77 105h.4l.2 .2h-.2a.14 .14 0 0 0-.1-.2 .14 .14 0 0 0-.1 .2l.1 .1a.28 .28 0 0 1 .2 .3 .28 .28 0 0 1-.3 .2 .28 .28 0 0 1-.2-.3h.1a.16 .16 0 0 0 .2 .2 .16 .16 0 0 0 .1-.3l-.3-.1z" fill-rule="evenodd"/>
<path d="M78.2 105.1l.5-.1 .1 .7-.2-.1-.4 .1-.1-.2h.1a.17 .17 0 0 0 .3 .1 .17 .17 0 0 0 0-.2l-.4 .1 .1-.2 .4-.1-.1-.1-.4 .1z" fill-rule="evenodd"/>
<path d="M78.9 105l.2 .1 .2-.1-.2 .2v.5h-.2z" fill-rule="evenodd"/>
<path d="M79.5 105.1l.3-.1 .2 .2 .1 .2h-.6l.1 .2 .5-.1a.36 .36 0 0 1-.5 .2 .36 .36 0 0 1-.2-.4h.5l-.2-.2-.3 .2z" fill-rule="evenodd"/>
<path d="M80.6 105h.4l.2 .2h-.2a.14 .14 0 0 0-.1-.2 .14 .14 0 0 0-.1 .2l.1 .1a.28 .28 0 0 1 .2 .3 .28 .28 0 0 1-.3 .2 .28 .28 0 0 1-.2-.3h.1a.16 .16 0 0 0 .2 .2 .16 .16 0 0 0 .1-.3l-.4-.1z" fill-rule="evenodd"/>
<path d="M81.3 105l.1 .1a.34 .34 0 0 1 .6 .2 .34 .34 0 0 1-.5 .3v.4h-.2v-.6h.1a.24 .24 0 0 0 .4 .2 .24 .24 0 0 0 0-.4l-.2-.1-.3 .3z" fill-rule="evenodd"/>
<path d="M82.2 105.1l.3-.1 .2 .2 .1 .2h-.6l.1 .2 .5-.1a.36 .36 0 0 1-.5 .2 .36 .36 0 0 1-.2-.4h.5l-.2-.2-.3 .2z" fill-rule="evenodd"/>
<path d="M83 105h.4l.1 .2h-.1a.21 .21 0 0 0-.3 0 .21 .21 0 0 0 0 .3 .21 .21 0 0 0 .3 0h.1a.37 .37 0 0 1-.5 .1 .37 .37 0 0 1 0-.6z" fill-rule="evenodd"/>
<path d="M83.6 104.7h.2v.1h-.2z" fill-rule="evenodd"/>
<path d="M83.6 105h.2v.7h-.2z" fill-rule="evenodd"/>
<path d="M84 104.7h.3l-.2 .2 .2 .2h-.2v.6h-.1v-.6h-.1z" fill-rule="evenodd"/>
<path d="M84.4 104.7h.1v.1h-.1z" fill-rule="evenodd"/>
<path d="M84.4 105h.1v.7h-.1z" fill-rule="evenodd"/>
<path d="M84.7 105.1l.4-.1 .2 .2v.2h-.5l.1 .2 .4-.1a.36 .36 0 0 1-.4 .2 .36 .36 0 0 1-.3-.4h.6l-.2-.2-.4 .2z" fill-rule="evenodd"/>
<path d="M85.5 105h.2l.3 .1v-.4h.1v1h-.5l-.2-.3 .2-.1a.24 .24 0 0 0 .3 .3 .24 .24 0 0 0 0-.4l-.2-.1-.1 .2h-.2z" fill-rule="evenodd"/>
<path d="M86.7 105h.5l.1 .7-.1-.1-.4 .1-.2-.2h.2a.17 .17 0 0 0 .2 .1 .17 .17 0 0 0 .1-.2l-.5 .1 .2-.2 .4-.1-.2-.1-.3 .1z" fill-rule="evenodd"/>
<path d="M87.6 104.7h.2l-.2 .2 .2 .2h-.2v.6h-.1v-.6h-.1z" fill-rule="evenodd"/>
<path d="M87.9 104.8l.1-.1v.3h.1l-.1 .1v.4l.2 .2h-.3l-.1-.6z" fill-rule="evenodd"/>
<path d="M88.3 105.1l.4-.1 .2 .2v.2h-.5l.1 .2 .4-.1a.36 .36 0 0 1-.4 .2 .36 .36 0 0 1-.3-.4h.6l-.2-.2-.4 .2z" fill-rule="evenodd"/>
<path d="M89.1 105l.1 .1 .3-.1-.3 .2v.5h-.1z" fill-rule="evenodd"/>
<path d="M89.9 105l.2 .1a.34 .34 0 0 1 .5 .2 .34 .34 0 0 1-.5 .3v.4h-.2v-.6h.2a.24 .24 0 0 0 .3 .2 .24 .24 0 0 0 0-.4l-.2-.1-.3 .3z" fill-rule="evenodd"/>
<path d="M90.7 104.7h.2v1h-.2z" fill-rule="evenodd"/>
<path d="M91.1 105.1l.5-.1 .1 .7-.1-.1-.4 .1-.2-.2h.2a.17 .17 0 0 0 .2 .1 .17 .17 0 0 0 .1-.2l-.5 .1 .2-.2 .3-.1-.1-.1-.4 .1z" fill-rule="evenodd"/>
<path d="M91.9 104.8l.1-.1v.3h.1l-.1 .1v.4l.2 .2h-.3l-.1-.6z" fill-rule="evenodd"/>
<path d="M92.3 104.7h.1v.1h-.1z" fill-rule="evenodd"/>
<path d="M92.3 105h.1v.7h-.1z" fill-rule="evenodd"/>
<path d="M92.6 105h.5l.1 .7h-.1v-.5l-.2-.1-.2 .1v.5h-.1z" fill-rule="evenodd"/>
<path d="M93.4 105h.6v.6a.33 .33 0 0 1-.3 .4 .33 .33 0 0 1-.3-.2l.2 .1 .2-.1 .1-.2-.2 .1-.3-.1-.1-.3h.2a.24 .24 0 0 0 .3 .2 .24 .24 0 0 0 .1-.4 .24 .24 0 0 0-.4 .1v.1h-.2z" fill-rule="evenodd"/>
<path d="M105.3 99.1h.2l.3 .8 .3-.8h.2v1h-.2v-.9l-.3 .9h-.1l-.3-.9v.9h-.1z" fill-rule="evenodd"/>
<path d="M108 99.1h.1v.5l.5-.3-.3 .3 .3 .5h-.2l-.2-.4-.1 .4h-.1z" fill-rule="evenodd"/>
<path d="M314.2 111.9h.7v.2h-.6v.3a.42 .42 0 0 1 .6 .2 .42 .42 0 0 1-.3 .6 .42 .42 0 0 1-.5-.4h.1a.28 .28 0 0 0 .5 .1 .28 .28 0 0 0 0-.4 .28 .28 0 0 0-.5 .1h-.1z" fill-rule="evenodd"/>
<path d="M314.3 118.4l.4-.1 .2 .3-.5-.2-.2 .5a.41 .41 0 0 1 .7 .2 .41 .41 0 0 1-.4 .5 .41 .41 0 0 1-.4-.4h.1a.26 .26 0 0 0 .4 .2 .26 .26 0 0 0 .1-.5 .26 .26 0 0 0-.4 .2l-.2 .1z" fill-rule="evenodd"/>
<path d="M314.6 107.6h.1v.9h.2v.1h-.2v.3h-.1v-.3h-.6v-.1h.6v-.6l-.4 .6h-.2z" fill-rule="evenodd"/>
<path d="M315.1 107.6a1.04 1.04 0 0 1 0 1.7l.3-.9z" fill-rule="evenodd"/>
<path d="M315.1 111.9a1.04 1.04 0 0 1 0 1.6l.3-.8z" fill-rule="evenodd"/>
<path d="M315.1 118.3a1.04 1.04 0 0 1 0 1.6l.3-.8z" fill-rule="evenodd"/>
<path d="M317.3 101.3h.6l.2 .2-.2 .1a.27 .27 0 0 0-.3-.3 .27 .27 0 0 0-.2 .4l.2 .1a.43 .43 0 0 1 .5 .5 .43 .43 0 0 1-.7 .2l-.3-.3 .2-.1a.31 .31 0 0 0 .3 .3 .31 .31 0 0 0 .3-.4l-.6-.2z" fill-rule="evenodd"/>
<path d="M317.3 107.7h.6l.2 .2-.2 .1a.27 .27 0 0 0-.3-.3 .27 .27 0 0 0-.2 .4l.2 .1a.43 .43 0 0 1 .5 .5 .43 .43 0 0 1-.7 .2l-.3-.3 .2-.1a.31 .31 0 0 0 .3 .3 .31 .31 0 0 0 .3-.4l-.6-.2z" fill-rule="evenodd"/>
<path d="M317.3 112l.6-.1 .2 .3-.2 .1a.27 .27 0 0 0-.3-.3 .27 .27 0 0 0-.2 .4h.2a.43 .43 0 0 1 .5 .6 .43 .43 0 0 1-.7 .1l-.3-.3 .2-.1a.31 .31 0 0 0 .3 .4 .31 .31 0 0 0 .3-.4l-.6-.3z" fill-rule="evenodd"/>
<path d="M317.3 118.4l.6-.1 .2 .3-.2 .1a.27 .27 0 0 0-.3-.3 .27 .27 0 0 0-.2 .4h.2a.43 .43 0 0 1 .5 .6 .43 .43 0 0 1-.7 .1l-.3-.3 .2-.1a.31 .31 0 0 0 .3 .4 .31 .31 0 0 0 .3-.4l-.6-.3z" fill-rule="evenodd"/>
<path d="M317.2 103.4h.9v.1h-.7v.4h.6v.2h-.6v.5h-.2z" fill-rule="evenodd"/>
<path d="M317.2 114l.8 .1 .1 .3-.2 .2 .2 .3a.39 .39 0 0 1-.4 .4h-.5v-.1l.7-.2v-.2l-.6-.1v.5h-.1v-.6h.4a.2 .2 0 0 0 .3-.2 .2 .2 0 0 0-.2-.2h-.4v.4h-.1z" fill-rule="evenodd"/>
<path d="M318.4 101.2h.9v.2h-.8v.4h.7v.1h-.7v.5h.8v.1h-.9z" fill-rule="evenodd"/>
<path d="M318.4 114h.9v.2h-.8v.4h.7v.1h-.7v.5h.8v.1h-.9z" fill-rule="evenodd"/>
<path d="M318.4 118.3h.2v1.3h-.2z" fill-rule="evenodd"/>
<path d="M318.9 118.3h.1v1.1h.7v.2h-.8z" fill-rule="evenodd"/>
<path d="M318.4 103.5a.63 .63 0 0 1 1 .1 .63 .63 0 0 1-.3 .9 .63 .63 0 0 1-.9-.5h.2a.48 .48 0 0 0 .7 .4 .48 .48 0 0 0 0-.8h-.5l-.2 .4h-.2z" fill-rule="evenodd"/>
<path d="M318.5 112.1a.63 .63 0 0 1 1 .1 .63 .63 0 0 1-.4 .9 .63 .63 0 0 1-.8-.5h.2a.48 .48 0 0 0 .7 .3 .48 .48 0 0 0 0-.8h-.5l-.2 .5h-.2z" fill-rule="evenodd"/>
<path d="M318.4 107.6h.1v.8a.34 .34 0 0 0 .4 .4 .34 .34 0 0 0 .3-.4v-.8h.2v.8a.5 .5 0 0 1-.5 .5 .5 .5 0 0 1-.5-.5z" fill-rule="evenodd"/>
<path d="M319.5 101.2h.2v1.2h.6v.1h-.8z" fill-rule="evenodd"/>
<path d="M319.7 111.9h.2v1.1h.6v.2h-.8z" fill-rule="evenodd"/>
<path d="M319.8 118.3h.2v.6l.6-.6h.3l-.6 .5 .6 .8h-.2l-.5-.7-.2 .2v.5h-.2z" fill-rule="evenodd"/>
<path d="M320 114h.2v1.2h.6v.1h-.8z" fill-rule="evenodd"/>
<path d="M319.7 103.4h.5a.35 .35 0 0 1 .5 .3 .35 .35 0 0 1-.4 .4l.5 .5h-.2a.62 .62 0 0 0-.8-.5v.5h-.1v-.7h.7l.1-.2-.2-.2h-.5v.4h-.1z" fill-rule="evenodd"/>
<path d="M319.7 107.6h.5a.35 .35 0 0 1 .5 .3 .35 .35 0 0 1-.4 .4l.5 .6h-.2l-.4-.5-.2-.1h-.2v.6h-.1v-.7h.7l.1-.2-.1-.2h-.6v.4h-.1z" fill-rule="evenodd"/>
<path d="M320.5 101.2h1v.2h-.8v.4h.7v.1h-.7v.5h.8v.1h-1z" fill-rule="evenodd"/>
<path d="M320.9 107.6h.9v.2h-.7v.4h.6v.1h-.6v.6h-.2z" fill-rule="evenodd"/>
<path d="M320.7 111.9h.5a.64 .64 0 0 1 .6 .6 .64 .64 0 0 1-.6 .7h-.5v-.2h.5a.49 .49 0 0 0 .4-.5 .49 .49 0 0 0-.4-.5h-.3v1h-.2z" fill-rule="evenodd"/>
<path d="M321.6 118.4l.6-.1 .2 .3-.1 .1a.27 .27 0 0 0-.3-.3 .27 .27 0 0 0-.2 .4h.2a.43 .43 0 0 1 .4 .6 .43 .43 0 0 1-.7 .1l-.2-.3 .1-.1a.31 .31 0 0 0 .4 .4 .31 .31 0 0 0 .2-.4l-.6-.3z" fill-rule="evenodd"/>
<path d="M321 114h.5a.39 .39 0 0 1 .5 .4 .39 .39 0 0 1-.5 .4h-.3v.5h-.2v-.7h.7l.1-.2-.1-.2h-.5v.4h-.2z" fill-rule="evenodd"/>
<path d="M322 111.9h.9v.1h-.7v.4h.7v.2h-.7v.4h.8v.2h-1z" fill-rule="evenodd"/>
<path d="M321.4 103.4h.6a.35 .35 0 0 1 .4 .3 .35 .35 0 0 1-.3 .4l.5 .5h-.3a.62 .62 0 0 0-.7-.5v.5h-.2v-.7h.7l.2-.2-.2-.2h-.5v.4h-.2z" fill-rule="evenodd"/>
<path d="M322.3 114h.1v1.3h-.1z" fill-rule="evenodd"/>
<path d="M321.8 101.4l.7-.2 .3 .3-.2 .1a.44 .44 0 0 0-.6-.1 .44 .44 0 0 0-.1 .6l.4 .3 .2-.1 .1-.2h.2a.62 .62 0 0 1-1 .3 .62 .62 0 0 1 0-1z" fill-rule="evenodd"/>
<path d="M322.7 103.4h.9v.1h-.7v.4h.7v.2h-.7v.4h.8v.1h-1z" fill-rule="evenodd"/>
<path d="M322.7 115.1a.22 .22 0 0 1 .2 .2 .22 .22 0 0 1-.1 .3z" fill-rule="evenodd"/>
<path d="M322.3 107.6h.2l.5 1.3h-.2l-.1-.4h-.5l-.2 .4h-.2l.2-.5h.6l-.2-.6-.2 .6h-.2z" fill-rule="evenodd"/>
<path d="M322.9 101.2h1v.2h-.4v1.1h-.2v-1.1h-.4z" fill-rule="evenodd"/>
<path d="M322.8 118.5l.6-.2 .3 .3-.1 .1a.45 .45 0 0 0-.7-.2 .45 .45 0 0 0 0 .7l.4 .2h.2l.1-.3 .2 .1a.62 .62 0 0 1-1 .3 .62 .62 0 0 1 0-1z" fill-rule="evenodd"/>
<path d="M323.2 111.9h.6a.35 .35 0 0 1 .4 .3 .35 .35 0 0 1-.3 .4l.4 .6h-.2l-.3-.5-.2-.1h-.2v.6h-.2v-.7l.8-.1a.21 .21 0 0 0 0-.3 .21 .21 0 0 0-.2-.1h-.4v.5h-.2z" fill-rule="evenodd"/>
<path d="M323.9 103.4h.9v.1h-.7v.4h.6v.2h-.6v.5h-.2z" fill-rule="evenodd"/>
<path d="M323.2 107.8l.6-.2 .3 .3-.1 .1a.45 .45 0 0 0-.7-.1 .45 .45 0 0 0 0 .6l.3 .3 .3-.1 .1-.2h.2a.62 .62 0 0 1-1 .3 .62 .62 0 0 1 0-1z" fill-rule="evenodd"/>
<path d="M324.1 101.2h.9v.2h-.7v.4h.7v.1h-.7v.5h.7v.1h-.9z" fill-rule="evenodd"/>
<path d="M324.4 107.6h.9v.2h-.7v.4h.7v.1h-.7v.5h.7v.1h-.9z" fill-rule="evenodd"/>
<path d="M324.5 111.9h.2l.4 1.1 .4-1.1h.2v1.3h-.2v-1.1l-.3 1.1h-.2l-.4-1.1v1.1h-.1z" fill-rule="evenodd"/>
<path d="M323.8 114.2l.6-.2 .3 .3-.1 .1a.45 .45 0 0 0-.7-.1 .45 .45 0 0 0 0 .6l.3 .3 .3-.1 .1-.2h.2a.62 .62 0 0 1-1 .3 .62 .62 0 0 1 0-1z" fill-rule="evenodd"/>
<path d="M324 118.3h.6a.35 .35 0 0 1 .4 .3 .35 .35 0 0 1-.3 .4l.4 .6h-.2a.62 .62 0 0 0-.7-.6v.6h-.2v-.7l.7-.1 .1-.2-.1-.2h-.5v.5h-.2z" fill-rule="evenodd"/>
<path d="M325 103.4h.9v.1h-.7v.4h.7v.2h-.7v.4h.7v.1h-.9z" fill-rule="evenodd"/>
<path d="M325.3 118.3h.9v.1h-.7v.4h.7v.2h-.7v.4h.7v.2h-.9z" fill-rule="evenodd"/>
<path d="M325.1 114.2a.63 .63 0 0 1 1 .1 .63 .63 0 0 1-.3 .9 .63 .63 0 0 1-.9-.5h.2a.48 .48 0 0 0 .8 .4 .48 .48 0 0 0-.1-.9h-.5l-.2 .5h-.2z" fill-rule="evenodd"/>
<path d="M325.3 101.2h.4a.64 .64 0 0 1 .6 .7 .64 .64 0 0 1-.6 .6h-.4v-.1h.4a.49 .49 0 0 0 .5-.5 .49 .49 0 0 0-.5-.5h-.3v1h-.1z" fill-rule="evenodd"/>
<path d="M326.1 107.6h.8v.2h-.7v.4h.6v.1h-.6v.6h-.1z" fill-rule="evenodd"/>
<path d="M326.4 114h.1v1.2h.7v.1h-.8z" fill-rule="evenodd"/>
<path d="M326.5 118.3h.9v.1h-.8v.4h.7v.2h-.7v.4h.8v.2h-.9z" fill-rule="evenodd"/>
<path d="M326.2 103.4h.5a.35 .35 0 0 1 .5 .3 .35 .35 0 0 1-.4 .4l.5 .5h-.2a.62 .62 0 0 0-.8-.5v.5h-.1v-.7l.8-.1a.21 .21 0 0 0 0-.2 .21 .21 0 0 0-.3-.1h-.4v.4h-.1z" fill-rule="evenodd"/>
<path d="M326.3 111.9h.2l.5 1.3h-.2l-.1-.4h-.5l-.2 .4h-.2l.2-.6h.6l-.2-.6-.2 .6h-.2z" fill-rule="evenodd"/>
<path d="M327.1 101.2h.1v.6h.7v-.6h.2v1.3h-.2v-.6h-.7v.6h-.1z" fill-rule="evenodd"/>
<path d="M327.2 112l.6-.1 .3 .3-.2 .1a.27 .27 0 0 0-.3-.3 .27 .27 0 0 0-.2 .4h.2a.43 .43 0 0 1 .5 .6 .43 .43 0 0 1-.7 .1l-.3-.3 .2-.1a.31 .31 0 0 0 .3 .4 .31 .31 0 0 0 .3-.4l-.7-.3z" fill-rule="evenodd"/>
<path d="M327.2 107.6h.2v1.3h-.2z" fill-rule="evenodd"/>
<path d="M327.5 103.4h.9v.1h-.8v.4h.7v.2h-.7v.4h.8v.1h-.9z" fill-rule="evenodd"/>
<path d="M327.6 107.6h.2l.7 1v-1h.1v1.3h-.1l-.7-1v1h-.2z" fill-rule="evenodd"/>
<path d="M327.6 118.3h.2l.7 1v-1h.2v1.3h-.2l-.7-1v1h-.2z" fill-rule="evenodd"/>
<path d="M327.5 114.2a.63 .63 0 0 1 1 .1 .63 .63 0 0 1-.4 .9 .63 .63 0 0 1-.8-.5h.2a.48 .48 0 0 0 .7 .4 .48 .48 0 0 0-.1-.9h-.4l-.2 .5h-.2z" fill-rule="evenodd"/>
<path d="M328.3 111.9h.2v.6l.6-.6h.3l-.6 .5 .6 .8h-.2l-.5-.7-.2 .2v.5h-.2z" fill-rule="evenodd"/>
<path d="M328.6 103.4h.2l.7 1v-1h.1v1.2h-.1l-.7-1v1h-.2z" fill-rule="evenodd"/>
<path d="M329 107.6h.1v1.3h-.1z" fill-rule="evenodd"/>
<path d="M328.5 101.4a.63 .63 0 0 1 .9 .1 .63 .63 0 0 1-.3 .9 .63 .63 0 0 1-.8-.5h.2a.48 .48 0 0 0 .7 .4 .48 .48 0 0 0-.1-.9h-.4l-.2 .5h-.2z" fill-rule="evenodd"/>
<path d="M329.5 107.7h.6l.2 .2-.1 .1a.27 .27 0 0 0-.3-.3 .27 .27 0 0 0-.2 .4l.2 .1a.43 .43 0 0 1 .4 .5 .43 .43 0 0 1-.7 .2l-.2-.3 .1-.1a.31 .31 0 0 0 .4 .3 .31 .31 0 0 0 .2-.4l-.6-.2z" fill-rule="evenodd"/>
<path d="M328.7 114h.6a.35 .35 0 0 1 .5 .3 .35 .35 0 0 1-.4 .4l.5 .6h-.2l-.4-.5-.2-.1h-.2v.6h-.2v-.7l.8-.1a.21 .21 0 0 0 0-.2 .21 .21 0 0 0-.2-.1h-.4v.4h-.2z" fill-rule="evenodd"/>
<path d="M329.4 118.3h.2v1.1h.6v.2h-.8z" fill-rule="evenodd"/>
<path d="M329.7 101.2h.2v1.2h.6v.1h-.8z" fill-rule="evenodd"/>
<path d="M330.4 118.3h.9v.1h-.7v.4h.7v.2h-.7v.4h.8v.2h-1z" fill-rule="evenodd"/>
<path d="M330.6 107.6h.2v.6h.6v-.6h.2v1.3h-.2v-.6h-.6v.6h-.2z" fill-rule="evenodd"/>
<path d="M330.1 112.1a.63 .63 0 0 1 1 0 .63 .63 0 0 1-.3 1 .63 .63 0 0 1-.8-.5h.1a.48 .48 0 0 0 .8 .3 .48 .48 0 0 0-.1-.8h-.5l-.2 .5h-.1z" fill-rule="evenodd"/>
<path d="M330.7 101.2h.9v.2h-.7v.4h.7v.1h-.7v.5h.8v.1h-1z" fill-rule="evenodd"/>
<path d="M330.4 114h.2l.2 1.1 .3-1.1h.2l.3 1.1 .3-1.1h.1l-.3 1.3h-.2l-.3-1.1-.3 1.1h-.2z" fill-rule="evenodd"/>
<path d="M330 103.5l.6-.1 .3 .2-.1 .2a.45 .45 0 0 0-.6-.2 .45 .45 0 0 0-.1 .7l.4 .2 .2-.1 .1-.2h.2a.62 .62 0 0 1-1 .3 .62 .62 0 0 1 0-1z" fill-rule="evenodd"/>
<path d="M331.2 103.4h.9v.1h-.7v.4h.7v.2h-.7v.4h.8v.1h-1z" fill-rule="evenodd"/>
<path d="M331.4 111.9h.2l.6 1v-1h.2v1.3h-.2l-.6-1v1h-.2z" fill-rule="evenodd"/>
<path d="M331.9 108h.2v.2h-.2z" fill-rule="evenodd"/>
<path d="M331.9 108.7h.2v.2h-.2z" fill-rule="evenodd"/>
<path d="M331.7 118.5l.7-.2 .3 .2v.2h-.1a.49 .49 0 0 0-.8 0 .49 .49 0 0 0 0 .7 .49 .49 0 0 0 .8-.1v-.2h-.4v-.2h.5v.5a.69 .69 0 0 1-.9 0 .69 .69 0 0 1-.1-.9z" fill-rule="evenodd"/>
<path d="M332.2 114h.2v.6h.6v-.6h.2v1.3h-.2v-.6h-.6v.6h-.2z" fill-rule="evenodd"/>
<path d="M332.4 101.2h.2v1.2h.6v.1h-.8z" fill-rule="evenodd"/>
<path d="M332.9 107.6h.2v.6h.6v-.6h.2v1.3h-.2v-.6h-.6v.6h-.2z" fill-rule="evenodd"/>
<path d="M333 118.3h.9v.1h-.7v.4h.7v.2h-.7v.4h.7v.2h-.9z" fill-rule="evenodd"/>
<path d="M333.5 114h.2v1.3h-.2z" fill-rule="evenodd"/>
<path d="M333 103.5a.63 .63 0 0 1 1 .1 .63 .63 0 0 1-.3 .9 .63 .63 0 0 1-.9-.5h.2a.48 .48 0 0 0 .8 .4 .48 .48 0 0 0-.1-.8h-.5l-.2 .4h-.2z" fill-rule="evenodd"/>
<path d="M333.2 111.9l.8 .1 .1 .3-.2 .2 .2 .3a.38 .38 0 0 1-.4 .4h-.5v-.2l.7-.1v-.3h-.6v.4h-.1v-.6h.4a.2 .2 0 0 0 .3-.1 .2 .2 0 0 0-.2-.2l-.4-.1v.4h-.1z" fill-rule="evenodd"/>
<path d="M333.5 101.4a.63 .63 0 0 1 1 .1 .63 .63 0 0 1-.3 .9 .63 .63 0 0 1-.9-.5h.2a.48 .48 0 0 0 .8 .4 .48 .48 0 0 0-.1-.9h-.5l-.2 .5h-.2z" fill-rule="evenodd"/>
<path d="M334.2 118.3h.1l.7 1v-1h.2v1.3h-.2l-.7-1v1h-.1z" fill-rule="evenodd"/>
<path d="M334.3 103.4h.1l.7 1v-1h.2v1.2h-.2l-.7-1v1h-.1z" fill-rule="evenodd"/>
<path d="M333.9 114h1v.2h-.4v1.1h-.2v-1.1h-.4z" fill-rule="evenodd"/>
<path d="M334.5 112.1a.63 .63 0 0 1 1 0 .63 .63 0 0 1-.4 1 .63 .63 0 0 1-.8-.5h.2a.48 .48 0 0 0 .7 .3 .48 .48 0 0 0-.1-.8h-.4l-.2 .5h-.2z" fill-rule="evenodd"/>
<path d="M335.1 114h.9v.2h-.8v.4h.7v.1h-.7v.5h.8v.1h-.9z" fill-rule="evenodd"/>
<path d="M334.5 107.6h.2l.5 1.3h-.2l-.1-.4h-.6l-.1 .4h-.2l.2-.5h.6l-.2-.6-.2 .6h-.2z" fill-rule="evenodd"/>
<path d="M335.3 107.6h.2v1.2h.6v.1h-.8z" fill-rule="evenodd"/>
<path d="M335.5 103.4h.2v1.1h.6v.1h-.8z" fill-rule="evenodd"/>
<path d="M334.9 101.4l.6-.2 .3 .3-.2 .1a.45 .45 0 0 0-.6-.1 .45 .45 0 0 0-.1 .6l.4 .3 .2-.1 .2-.2h.1a.62 .62 0 0 1-.9 .3 .62 .62 0 0 1 0-1z" fill-rule="evenodd"/>
<path d="M335.5 118.3h.4a.64 .64 0 0 1 .6 .6 .64 .64 0 0 1-.6 .7h-.4v-.2h.4a.49 .49 0 0 0 .4-.5 .49 .49 0 0 0-.4-.5h-.3v1h-.1z" fill-rule="evenodd"/>
<path d="M335.7 111.9h1v.1h-.5v1.2h-.1v-1.2h-.4z" fill-rule="evenodd"/>
<path d="M336.3 115.1h.1v.2h-.1z" fill-rule="evenodd"/>
<path d="M336.9 107.7h.6l.2 .2-.2 .1a.27 .27 0 0 0-.3-.3 .27 .27 0 0 0-.2 .4l.2 .1a.43 .43 0 0 1 .5 .5 .43 .43 0 0 1-.7 .2l-.3-.3 .2-.1a.31 .31 0 0 0 .3 .3 .31 .31 0 0 0 .3-.4l-.7-.2z" fill-rule="evenodd"/>
<path d="M336.3 103.4h.2l.4 .6 .4-.6h.2l-.5 .7v.5h-.2v-.5z" fill-rule="evenodd"/>
<path d="M336.8 111.9h.2v.5h.7v-.5h.1v1.3h-.1v-.6h-.7v.6h-.2z" fill-rule="evenodd"/>
<path d="M336.4 101.2h.2l.5 1.3h-.2l-.1-.4h-.6l-.1 .4h-.2l.2-.5h.6l-.2-.6-.2 .6h-.2z" fill-rule="evenodd"/>
<path d="M337.1 101.2h1v.2h-.4v1.1h-.2v-1.1h-.4z" fill-rule="evenodd"/>
<path d="M337.5 104.5h.2v.1h-.2z" fill-rule="evenodd"/>
<path d="M337.1 118.3h1v.1h-.4v1.2h-.2v-1.2h-.4z" fill-rule="evenodd"/>
<path d="M337.9 107.6h.2l.7 1v-1h.2v1.3h-.2l-.7-1v1h-.2z" fill-rule="evenodd"/>
<path d="M338.2 101.2h.2v1.3h-.2z" fill-rule="evenodd"/>
<path d="M338.7 112l.6-.1 .2 .3-.1 .1a.27 .27 0 0 0-.4-.3 .27 .27 0 0 0-.2 .4h.3a.43 .43 0 0 1 .4 .6 .43 .43 0 0 1-.7 .1l-.2-.3 .1-.1a.31 .31 0 0 0 .4 .4 .31 .31 0 0 0 .2-.4l-.6-.3z" fill-rule="evenodd"/>
<path d="M338.4 118.5a.63 .63 0 0 1 1 0 .63 .63 0 0 1-.4 1 .63 .63 0 0 1-.8-.5h.2a.48 .48 0 0 0 .7 .3 .48 .48 0 0 0-.1-.8h-.4l-.2 .5h-.2z" fill-rule="evenodd"/>
<path d="M338.8 101.4a.63 .63 0 0 1 1 .1 .63 .63 0 0 1-.3 .9 .63 .63 0 0 1-.9-.5h.2a.48 .48 0 0 0 .8 .4 .48 .48 0 0 0-.1-.9h-.5l-.2 .5h-.2z" fill-rule="evenodd"/>
<path d="M339.8 111.9h.2v1.3h-.2z" fill-rule="evenodd"/>
<path d="M339.2 107.6h.5a.39 .39 0 0 1 .5 .4 .39 .39 0 0 1-.5 .4h-.3v.5h-.2v-.7h.7l.1-.2-.1-.2h-.5v.4h-.2z" fill-rule="evenodd"/>
<path d="M340.1 101.2h.1l.7 1v-1h.2v1.3h-.2l-.7-1v1h-.1z" fill-rule="evenodd"/>
<path d="M340.1 118.3l.8 .1 .1 .3-.2 .2 .3 .3a.39 .39 0 0 1-.5 .4h-.5v-.2l.8-.1-.1-.3h-.5v.4h-.2v-.6h.5a.2 .2 0 0 0 .2-.1 .2 .2 0 0 0-.1-.2l-.4-.1v.4h-.2z" fill-rule="evenodd"/>
<path d="M340.3 111.9h.4a.64 .64 0 0 1 .6 .6 .64 .64 0 0 1-.6 .7h-.4v-.2h.4a.49 .49 0 0 0 .5-.5 .49 .49 0 0 0-.5-.5h-.2v1h-.2z" fill-rule="evenodd"/>
<path d="M340.4 107.6l.8 .1 .1 .3-.2 .2 .3 .3a.38 .38 0 0 1-.5 .4h-.5v-.1l.8-.2-.1-.2-.5-.1v.5h-.2v-.6h.5a.2 .2 0 0 0 .2-.2 .2 .2 0 0 0-.1-.2h-.4v.4h-.2z" fill-rule="evenodd"/>
<path d="M341.4 101.3h.6l.2 .2-.1 .1a.27 .27 0 0 0-.3-.3 .27 .27 0 0 0-.2 .4l.2 .1a.43 .43 0 0 1 .5 .5 .43 .43 0 0 1-.8 .2l-.2-.3 .1-.1a.31 .31 0 0 0 .4 .3 .31 .31 0 0 0 .3-.4l-.7-.2z" fill-rule="evenodd"/>
<path d="M341.3 118.3h.9v.1h-.7v.4h.7v.2h-.7v.4h.8v.2h-1z" fill-rule="evenodd"/>
<path d="M341.6 111.9h.9v.1h-.8v.4h.7v.2h-.7v.4h.8v.2h-.9z" fill-rule="evenodd"/>
<path d="M342.8 112l.6-.1 .3 .3-.2 .1a.27 .27 0 0 0-.3-.3 .27 .27 0 0 0-.2 .4h.2a.43 .43 0 0 1 .5 .6 .43 .43 0 0 1-.8 .1l-.2-.3 .2-.1a.31 .31 0 0 0 .3 .4 .31 .31 0 0 0 .3-.4l-.7-.3z" fill-rule="evenodd"/>
<path d="M343.1 101.3h.6l.2 .2-.1 .1a.27 .27 0 0 0-.3-.3 .27 .27 0 0 0-.2 .4l.2 .1a.43 .43 0 0 1 .4 .5 .43 .43 0 0 1-.7 .2l-.2-.3 .1-.1a.31 .31 0 0 0 .4 .3 .31 .31 0 0 0 .2-.4l-.6-.2z" fill-rule="evenodd"/>
<path d="M343.3 118.3h.2l.5 1.3h-.2l-.2-.4h-.5l-.1 .4h-.2l.2-.5h.6l-.2-.7-.2 .7h-.2z" fill-rule="evenodd"/>
<path d="M344.2 101.2h.2v.6h.6v-.6h.2v1.3h-.2v-.6h-.6v.6h-.2z" fill-rule="evenodd"/>
<path d="M344.1 118.3h.5a.39 .39 0 0 1 .4 .4 .39 .39 0 0 1-.4 .4h-.4v.5h-.1v-.7h.6l.2-.2-.2-.2-.5-.1v.5h-.1z" fill-rule="evenodd"/>
<path d="M344.6 112.1a.63 .63 0 0 1 .9 0 .63 .63 0 0 1-.3 1 .63 .63 0 0 1-.8-.5h.2a.48 .48 0 0 0 .7 .4 .48 .48 0 0 0 0-.9h-.5l-.2 .2v.3h-.2z" fill-rule="evenodd"/>
<path d="M345.8 111.9h.9v.1h-.7v.4h.6v.2h-.6v.6h-.2z" fill-rule="evenodd"/>
<path d="M345.3 118.3h.4a.39 .39 0 0 1 .5 .4 .39 .39 0 0 1-.4 .4h-.4v.5h-.1v-.7h.6l.2-.2-.2-.2-.5-.1v.5h-.1z" fill-rule="evenodd"/>
<path d="M345.6 101.4a.63 .63 0 0 1 1 .1 .63 .63 0 0 1-.3 .9 .63 .63 0 0 1-.9-.5h.2a.48 .48 0 0 0 .8 .4 .48 .48 0 0 0-.1-.9h-.5l-.2 .5h-.2z" fill-rule="evenodd"/>
<path d="M346.4 118.3h.2v1.1h.6v.2h-.8z" fill-rule="evenodd"/>
<path d="M346.8 101.2h.1l.3 1.1 .3-1.1h.2l.3 1.1 .2-1.1h.2l-.4 1.3h-.1l-.3-1.1-.3 1.1h-.2z" fill-rule="evenodd"/>
<path d="M347.5 118.3h.1v1.3h-.1z" fill-rule="evenodd"/>
<path d="M347.3 111.9h1v.1h-.4v1.2h-.2v-1.2h-.4z" fill-rule="evenodd"/>
<path d="M347.9 118.3h.9v.1h-.7v.4h.7v.2h-.7v.4h.8v.2h-1z" fill-rule="evenodd"/>
<path d="M348.5 111.9h.1v.5h.7v-.5h.2v1.3h-.2v-.6h-.7v.6h-.1z" fill-rule="evenodd"/>
<path d="M348.5 101.2h.2l.7 1v-1h.1v1.3h-.1l-.7-1v1h-.2z" fill-rule="evenodd"/>
<path d="M349.1 118.3h.4a.64 .64 0 0 1 .7 .6 .64 .64 0 0 1-.6 .7h-.5v-.2h.5a.49 .49 0 0 0 .4-.5 .49 .49 0 0 0-.5-.5h-.2v1h-.2z" fill-rule="evenodd"/>
<path d="M349.7 111.9h1v.1h-.8v.4h.7v.2h-.7v.4h.8v.2h-1z" fill-rule="evenodd"/>
<path d="M350.4 101.4a.63 .63 0 0 1 1 .1 .63 .63 0 0 1-.3 .9 .63 .63 0 0 1-.8-.5h.1a.48 .48 0 0 0 .8 .4 .48 .48 0 0 0-.1-.9h-.5l-.2 .5h-.1z" fill-rule="evenodd"/>
<path d="M350.9 118.3h.5a.39 .39 0 0 1 .5 .4 .39 .39 0 0 1-.5 .4h-.3v.5h-.2v-.7h.6l.2-.2-.2-.2-.4-.1v.5h-.2z" fill-rule="evenodd"/>
<path d="M351.7 101.2h.2l.6 1v-1h.2v1.3h-.2l-.6-1v1h-.2z" fill-rule="evenodd"/>
<path d="M351.4 111.9l.8 .1 .1 .3-.2 .2 .3 .3a.38 .38 0 0 1-.5 .4h-.5v-.2l.8-.1-.1-.3h-.5v.4h-.2v-.6h.4a.2 .2 0 0 0 .3-.1 .2 .2 0 0 0-.1-.2l-.4-.1v.4h-.2z" fill-rule="evenodd"/>
<path d="M352.1 118.3h.9v.1h-.8v.4h.7v.2h-.7v.4h.8v.2h-.9z" fill-rule="evenodd"/>
<path d="M352.7 112.1a.63 .63 0 0 1 1 .1 .63 .63 0 0 1-.3 .9 .63 .63 0 0 1-.9-.5h.2a.48 .48 0 0 0 .8 .3 .48 .48 0 0 0-.1-.8h-.5l-.2 .5h-.2z" fill-rule="evenodd"/>
<path d="M353.4 101.2h1v.2h-.4v1.1h-.2v-1.1h-.4z" fill-rule="evenodd"/>
<path d="M353.3 118.3h.5a.35 .35 0 0 1 .5 .3 .35 .35 0 0 1-.4 .4l.5 .6h-.2a.62 .62 0 0 0-.8-.6v.6h-.1v-.7l.8-.1a.21 .21 0 0 0 0-.3 .21 .21 0 0 0-.3-.1h-.4v.5h-.1z" fill-rule="evenodd"/>
<path d="M354.5 101.2h.2v.6h.7v-.6h.1v1.3h-.1v-.6h-.7v.6h-.2z" fill-rule="evenodd"/>
<path d="M355 118.3h.2v1.1h.6v.2h-.8z" fill-rule="evenodd"/>
<path d="M354.3 111.9h.2l.5 1.3h-.2l-.1-.4h-.5l-.2 .4h-.2l.2-.6h.6l-.2-.6-.2 .6h-.2z" fill-rule="evenodd"/>
<path d="M355.2 111.9h.5a.35 .35 0 0 1 .5 .3 .35 .35 0 0 1-.4 .4l.5 .6h-.2a.62 .62 0 0 0-.8-.6v.6h-.1v-.7l.8-.1a.21 .21 0 0 0 0-.3 .21 .21 0 0 0-.3-.1h-.4v.5h-.1z" fill-rule="evenodd"/>
<path d="M355.8 101.2h.2v1.3h-.2z" fill-rule="evenodd"/>
<path d="M356.4 101.3h.6l.2 .2-.1 .1a.27 .27 0 0 0-.3-.3 .27 .27 0 0 0-.2 .4l.2 .1a.43 .43 0 0 1 .4 .5 .43 .43 0 0 1-.7 .2l-.2-.3 .1-.1a.31 .31 0 0 0 .4 .3 .31 .31 0 0 0 .2-.4l-.6-.2z" fill-rule="evenodd"/>
<path d="M356.4 111.9h.5a.64 .64 0 0 1 .6 .6 .64 .64 0 0 1-.6 .7h-.5v-.2h.5a.49 .49 0 0 0 .4-.5 .49 .49 0 0 0-.4-.5h-.3v1h-.2z" fill-rule="evenodd"/>
<path d="M356.4 118.3h.2l.5 1.3h-.2l-.2-.4h-.5l-.1 .4h-.2l.2-.5h.6l-.2-.7-.3 .7h-.1z" fill-rule="evenodd"/>
<path d="M357 118.3h.2l.4 .6 .4-.6h.2l-.5 .7v.6h-.2v-.6z" fill-rule="evenodd"/>
<path d="M358.3 112l.6-.1 .2 .3-.1 .1a.27 .27 0 0 0-.3-.3 .27 .27 0 0 0-.2 .4h.2a.43 .43 0 0 1 .4 .6 .43 .43 0 0 1-.7 .1l-.2-.3 .1-.1a.31 .31 0 0 0 .4 .4 .31 .31 0 0 0 .2-.4l-.6-.3z" fill-rule="evenodd"/>
<path d="M358.3 118.3h.9v.1h-.8v.4h.7v.2h-.7v.4h.8v.2h-.9z" fill-rule="evenodd"/>
<path d="M358 101.2h.4a.64 .64 0 0 1 .6 .7 .64 .64 0 0 1-.6 .6h-.4v-.1h.4a.49 .49 0 0 0 .5-.5 .49 .49 0 0 0-.5-.5h-.2v1h-.2z" fill-rule="evenodd"/>
<path d="M359.4 111.9h.2v.5h.6v-.5h.2v1.3h-.2v-.6h-.6v.6h-.2z" fill-rule="evenodd"/>
<path d="M359.3 101.2h.5a.35 .35 0 0 1 .5 .3 .35 .35 0 0 1-.4 .4l.5 .6h-.2l-.4-.5-.2-.1h-.2v.6h-.1v-.7l.8-.1a.21 .21 0 0 0 0-.3 .21 .21 0 0 0-.3 0h-.4v.4h-.1z" fill-rule="evenodd"/>
<path d="M359.4 118.3h.6a.35 .35 0 0 1 .5 .3 .35 .35 0 0 1-.4 .4l.5 .6h-.2a.62 .62 0 0 0-.8-.6v.6h-.2v-.7l.8-.1 .1-.2-.2-.2h-.5v.5h-.2z" fill-rule="evenodd"/>
<path d="M360.9 101.2h.2l.5 1.3h-.2l-.1-.4h-.6l-.1 .4h-.2l.2-.5h.6l-.2-.6-.2 .6h-.2z" fill-rule="evenodd"/>
<path d="M361 111.9h.2l.5 1.3h-.2l-.1-.4h-.5l-.2 .4h-.2l.3-.6h.5l-.2-.6-.2 .6h-.1z" fill-rule="evenodd"/>
<path d="M361.9 111.9h.1v1.1h.7v.2h-.8z" fill-rule="evenodd"/>
<path d="M361.6 101.2h.2l.2 1.1 .3-1.1h.2l.3 1.1 .3-1.1h.1l-.3 1.3h-.2l-.3-1.1-.3 1.1h-.2z" fill-rule="evenodd"/>
<path d="M362.9 111.9h.1v1.1h.7v.2h-.8z" fill-rule="evenodd"/>
<path d="M363.4 101.2h.2v1.3h-.2z" fill-rule="evenodd"/>
<path d="M363.8 101.2h.2l.7 1v-1h.1v1.3h-.1l-.7-1v1h-.2z" fill-rule="evenodd"/>
<path d="M365.3 101.4l.6-.2 .3 .2v.2h-.1a.49 .49 0 0 0-.7 0 .49 .49 0 0 0 0 .7 .49 .49 0 0 0 .7-.1v-.2h-.4v-.1h.6v.4a.69 .69 0 0 1-1 .1 .69 .69 0 0 1 0-1z" fill-rule="evenodd"/>
<path d="M26.1 124h.9v.2h-.4v.9h-.2v-.9h-.3z" fill-rule="evenodd"/>
<path d="M27.1 124.3h.2v.1l.3-.1-.1 .2-.2 .1v.5h-.2z" fill-rule="evenodd"/>
<path d="M27.7 124.4l.3-.1 .3 .1 .1 .7h-.7l-.1-.2 .4 .1 .1-.2-.5 .1 .1-.2 .4-.1-.1-.1h-.4z" fill-rule="evenodd"/>
<path d="M28.5 124.3h.2v.1l.3-.1 .2 .1 .1 .7h-.2v-.5l-.2-.1-.1 .1v.5h-.3z" fill-rule="evenodd"/>
<path d="M29.5 124.4l.5-.1 .2 .2h-.4l-.1 .1a.34 .34 0 0 1 .5 .2 .34 .34 0 0 1-.2 .4 .34 .34 0 0 1-.4-.1l-.2-.2 .5 .1 .1-.1h-.1a.33 .33 0 0 1-.4-.4z" fill-rule="evenodd"/>
<path d="M30.4 124.3h.2v.1l.2-.1 .3 .1 .4-.1 .1 .8h-.2l-.2-.6-.1 .1v.5h-.2l-.1-.6-.2 .1v.5h-.2z" fill-rule="evenodd"/>
<path d="M31.8 124h.2v.2h-.2z" fill-rule="evenodd"/>
<path d="M31.8 124.3h.2v.8h-.2z" fill-rule="evenodd"/>
<path d="M32.3 124.4l.4-.1 .2 .2h-.4v.1a.34 .34 0 0 1 .4 .2 .34 .34 0 0 1-.2 .4 .34 .34 0 0 1-.4-.1l-.1-.2 .4 .1 .1-.1h-.1a.33 .33 0 0 1-.4-.4z" fill-rule="evenodd"/>
<path d="M33.2 124.4l.4-.1 .2 .2h-.4l-.1 .1a.34 .34 0 0 1 .5 .2 .34 .34 0 0 1-.2 .4 .34 .34 0 0 1-.4-.1l-.2-.2 .5 .1 .1-.1h-.1a.33 .33 0 0 1-.4-.4z" fill-rule="evenodd"/>
<path d="M34 124h.2v.2h-.2z" fill-rule="evenodd"/>
<path d="M34 124.3h.2v.8h-.2z" fill-rule="evenodd"/>
<path d="M34.5 124.4a.43 .43 0 0 1 .7 .1 .43 .43 0 0 1-.3 .6 .43 .43 0 0 1-.5-.4h.2a.21 .21 0 0 0 .3 .2 .21 .21 0 0 0 .1-.4 .22 .22 0 0 0-.4 .2h-.2z" fill-rule="evenodd"/>
<path d="M35.4 124.3h.2v.1l.3-.1 .2 .1 .1 .7h-.3v-.5l-.1-.1-.2 .1v.5h-.2z" fill-rule="evenodd"/>
<path d="M36.8 124h.3v1h.5v.1h-.8z" fill-rule="evenodd"/>
<path d="M37.8 124h.2v.2h-.2z" fill-rule="evenodd"/>
<path d="M37.8 124.3h.2v.8h-.2z" fill-rule="evenodd"/>
<path d="M38.2 124.3h.2v.1l.3-.1 .2 .1 .1 .7h-.2l-.1-.5-.1-.1-.1 .1-.1 .5h-.2z" fill-rule="evenodd"/>
<path d="M39.2 124.4l.3-.1 .2 .1 .2 .4-.5 .1 .1 .1 .4-.1a.4 .4 0 0 1-.5 .3 .4 .4 0 0 1-.3-.5h.6l-.2-.2-.1 .2h-.3z" fill-rule="evenodd"/>
<path d="M43.2 124h.3v1.1h-.3z" fill-rule="evenodd"/>
<path d="M43.7 124.3h.2v.1l.2-.1 .3 .1 .4-.1 .1 .8h-.2l-.1-.6-.2 .1v.5h-.2l-.1-.6-.2 .1v.5h-.2z" fill-rule="evenodd"/>
<path d="M45.1 124.3h.2v.1a.38 .38 0 0 1 .5 .1 .38 .38 0 0 1 0 .5 .38 .38 0 0 1-.5 0v.5h-.2v-.8h.2v.2a.2 .2 0 0 0 .3 0 .2 .2 0 0 0 0-.3 .2 .2 0 0 0-.3 0l-.2 .1z" fill-rule="evenodd"/>
<path d="M46.1 124.4l.3-.1 .2 .1 .2 .4-.6 .1 .2 .1 .4-.1a.4 .4 0 0 1-.5 .3 .4 .4 0 0 1-.3-.5h.6l-.2-.2-.2 .2h-.2z" fill-rule="evenodd"/>
<path d="M47 124.4l.3-.1 .2 .1v-.4h.2v1.1h-.2v-.1l-.4 .1-.2-.4h.2v.2a.2 .2 0 0 0 .3 0 .2 .2 0 0 0 0-.3 .2 .2 0 0 0-.3 0l-.2 .1z" fill-rule="evenodd"/>
<path d="M48 124.4l.2-.1 .3 .1 .1 .7h-.7v-.2l.3 .1 .2-.1v-.1l-.5 .1 .1-.2 .4-.1-.1-.1h-.4z" fill-rule="evenodd"/>
<path d="M48.8 124.3h.2v.1l.3-.1 .2 .1 .1 .7h-.3v-.5l-.1-.1-.2 .1v.5h-.2z" fill-rule="evenodd"/>
<path d="M49.8 124.4l.5-.1 .2 .3-.3-.1a.21 .21 0 0 0-.2 .1 .21 .21 0 0 0 0 .3 .21 .21 0 0 0 .3-.1l.2 .1a.42 .42 0 0 1-.6 .2 .42 .42 0 0 1-.1-.7z" fill-rule="evenodd"/>
<path d="M50.7 124.4l.3-.1 .2 .1 .2 .4-.6 .1 .2 .1 .3-.1a.4 .4 0 0 1-.5 .3 .4 .4 0 0 1-.2-.5h.5l-.1-.2-.2 .2h-.2z" fill-rule="evenodd"/>
<path d="M52 124h.4v.2h-.2v1.1h.2v.2h-.4z" fill-rule="evenodd"/>
<path d="M52.6 124.4a.43 .43 0 0 1 .7 .1 .43 .43 0 0 1-.3 .6 .43 .43 0 0 1-.5-.4h.2a.21 .21 0 0 0 .3 .2 .21 .21 0 0 0 0-.4 .21 .21 0 0 0-.3 .2h-.2z" fill-rule="evenodd"/>
<path d="M53.5 124h.2v.4l.2-.1 .3 .1v.7h-.2v-.6h-.1l-.2 .1v.5h-.2z" fill-rule="evenodd"/>
<path d="M54.4 124.3h.2v.1l.3-.1 .2 .1 .4-.1 .1 .8h-.2l-.1-.6-.1 .1-.1 .5h-.2l-.1-.6-.1 .1-.1 .5h-.2z" fill-rule="evenodd"/>
<path d="M55.9 124.4l.4-.1 .2 .2h-.4v.1a.34 .34 0 0 1 .4 .2 .34 .34 0 0 1-.1 .4 .34 .34 0 0 1-.5-.1l-.1-.2 .4 .1 .1-.1h-.1a.33 .33 0 0 1-.4-.4z" fill-rule="evenodd"/>
<path d="M56.6 124h.4v1.5h-.4v-.2h.2v-1.1h-.2z" fill-rule="evenodd"/>
<path d="M60.4 124h.9v.2h-.4v.9h-.2v-.9h-.3z" fill-rule="evenodd"/>
<path d="M61.4 124.4a.43 .43 0 0 1 .7 .1 .43 .43 0 0 1-.3 .6 .43 .43 0 0 1-.5-.4h.2a.21 .21 0 0 0 .3 .2 .21 .21 0 0 0 .1-.3 .21 .21 0 0 0-.4 .1h-.2z" fill-rule="evenodd"/>
<path d="M62.3 124h.2v1.1h-.2z" fill-rule="evenodd"/>
<path d="M62.7 124.4l.3-.1 .2 .1 .2 .4-.5 .1 .1 .1 .4-.1a.4 .4 0 0 1-.5 .3 .4 .4 0 0 1-.3-.5h.6l-.2-.2-.1 .2h-.3z" fill-rule="evenodd"/>
<path d="M63.6 124.3h.2v.1l.3-.1-.1 .2-.2 .1v.5h-.2z" fill-rule="evenodd"/>
<path d="M64.2 124.4l.3-.1 .3 .1 .1 .7h-.7l-.1-.2 .4 .1 .1-.2-.5 .1 .2-.2 .3-.1v-.1h-.4z" fill-rule="evenodd"/>
<path d="M65.1 124.3h.2v.1l.2-.1 .3 .1v.7h-.2v-.5l-.1-.1-.2 .1v.5h-.2z" fill-rule="evenodd"/>
<path d="M66.1 124.4l.4-.1 .3 .3-.3-.1a.21 .21 0 0 0-.3 .1 .21 .21 0 0 0 .1 .3 .21 .21 0 0 0 .3-.1l.2 .1a.42 .42 0 0 1-.7 .2 .42 .42 0 0 1 0-.7z" fill-rule="evenodd"/>
<path d="M67 124.4l.2-.1 .3 .1 .1 .4-.5 .1 .2 .1 .3-.1a.4 .4 0 0 1-.5 .3 .4 .4 0 0 1-.2-.5h.5l-.1-.2-.2 .2h-.2z" fill-rule="evenodd"/>
<path d="M68.2 124h.4v.2h-.1v1.1h.1v.2h-.4z" fill-rule="evenodd"/>
<path d="M68.8 124.1a.28 .28 0 0 1 .4 0 .28 .28 0 0 1-.1 .4 .28 .28 0 0 1-.4-.2l.3 .1v-.3l-.3 .2z" fill-rule="evenodd"/>
<path d="M69.6 124h.1l-.6 1.2h-.1z" fill-rule="evenodd"/>
<path d="M69.6 124.7a.28 .28 0 0 1 .4 0 .28 .28 0 0 1-.1 .4 .28 .28 0 0 1-.4-.2l.3 .1v-.3l-.3 .2z" fill-rule="evenodd"/>
<path d="M70.1 124h.4v1.5h-.4v-.2h.2v-1.1h-.2z" fill-rule="evenodd"/>
<path d="M73.9 124h.2v1h.6v.1h-.8z" fill-rule="evenodd"/>
<path d="M74.9 124.4l.3-.1 .3 .1 .1 .7h-.7l-.1-.2 .4 .1 .1-.2-.5 .1 .1-.2 .4-.1-.1-.1h-.4z" fill-rule="evenodd"/>
<path d="M75.6 124.3h.3l.2 .6 .2-.6h.2l-.4 1-.2 .2h-.2v-.2l.2-.1z" fill-rule="evenodd"/>
<path d="M76.7 124.4l.2-.1 .3 .1 .1 .4-.5 .1 .2 .1 .3-.1a.4 .4 0 0 1-.5 .3 .4 .4 0 0 1-.2-.5h.5l-.2-.2-.1 .2h-.2z" fill-rule="evenodd"/>
<path d="M77.5 124.3h.2v.1l.3-.1v.2l-.3 .1v.5h-.2z" fill-rule="evenodd"/>
<path d="M81.2 124h.9v.2h-.3v.9h-.3v-.9h-.3z" fill-rule="evenodd"/>
<path d="M82.2 124.3h.2v.1l.3-.1v.2l-.3 .1v.5h-.2z" fill-rule="evenodd"/>
<path d="M82.8 124.4l.3-.1 .3 .1 .1 .7h-.7l-.1-.2 .4 .1 .1-.2-.5 .1 .2-.2 .3-.1-.1-.1h-.3z" fill-rule="evenodd"/>
<path d="M83.7 124.4l.5-.1 .2 .3-.3-.1a.21 .21 0 0 0-.2 .1 .21 .21 0 0 0 0 .3 .21 .21 0 0 0 .3-.1l.2 .1a.42 .42 0 0 1-.6 .2 .42 .42 0 0 1-.1-.7z" fill-rule="evenodd"/>
<path d="M84.6 124.4h.5l.2 .4-.6 .1 .2 .1 .3-.1a.4 .4 0 0 1-.5 .3 .4 .4 0 0 1-.2-.5h.5l-.1-.2-.2 .2h-.2z" fill-rule="evenodd"/>
<path d="M85.8 124h.2l.2 .8 .2-.8h.2l.2 .8 .2-.8h.3l-.3 1.1h-.3l-.2-.8-.2 .8h-.3z" fill-rule="evenodd"/>
<path d="M87.4 124h.2v.2h-.2z" fill-rule="evenodd"/>
<path d="M87.4 124.3h.2v.8h-.2z" fill-rule="evenodd"/>
<path d="M87.8 124.4l.3-.1 .2 .1v-.4h.2v1.1h-.2v-.1l-.3 .1-.3-.4h.3v.2a.2 .2 0 0 0 .3 0 .2 .2 0 0 0 0-.3 .2 .2 0 0 0-.3 0l-.3 .1z" fill-rule="evenodd"/>
<path d="M88.8 124.2l.2-.2v.3h.1v.2h-.1v.3l.2 .3h-.4v-.6h-.1z" fill-rule="evenodd"/>
<path d="M89.3 124h.2v.4l.3-.1 .2 .1v.7h-.2v-.6h-.1l-.2 .1v.5h-.2z" fill-rule="evenodd"/>
<path d="M90.7 124h.4v.2h-.2v1.1h.2v.2h-.4z" fill-rule="evenodd"/>
<path d="M91.2 124.3h.2v.1l.3-.1 .2 .1 .4-.1 .1 .8h-.2l-.1-.6-.2 .1v.5h-.2l-.1-.6-.2 .1v.5h-.2z" fill-rule="evenodd"/>
<path d="M92.6 124.3h.2v.1l.3-.1 .2 .1 .4-.1 .1 .8h-.2l-.1-.6-.1 .1-.1 .5h-.2l-.1-.6-.1 .1-.1 .5h-.2z" fill-rule="evenodd"/>
<path d="M94 124h.4v1.5h-.4v-.2h.1v-1.1h-.1z" fill-rule="evenodd"/>
<path d="M97.9 124.1l.6-.1 .3 .3-.3 .1a.36 .36 0 0 0-.5 0 .36 .36 0 0 0 0 .5 .36 .36 0 0 0 .5 0v-.2h-.2v-.2h.5v.5a.62 .62 0 0 1-.9 0 .62 .62 0 0 1 0-.9z" fill-rule="evenodd"/>
<path d="M99 124.4l.3-.1 .3 .1 .1 .7h-.7l-.1-.2 .4 .1 .1-.2-.5 .1 .2-.2 .3-.1-.1-.1h-.4z" fill-rule="evenodd"/>
<path d="M99.9 124.3h.2v.1a.38 .38 0 0 1 .5 .1 .38 .38 0 0 1 0 .5 .38 .38 0 0 1-.5 0v.5h-.2v-.8h.2v.2a.2 .2 0 0 0 .3 0 .2 .2 0 0 0 0-.3 .2 .2 0 0 0-.3 0l-.2 .1z" fill-rule="evenodd"/>
<path d="M101.3 124h.4v.2h-.2v1.1h.2v.2h-.4z" fill-rule="evenodd"/>
<path d="M101.8 124.3h.2v.1l.2-.1 .3 .1 .4-.1 .1 .8h-.2l-.1-.6-.2 .1v.5h-.2l-.1-.6-.2 .1v.5h-.2z" fill-rule="evenodd"/>
<path d="M103.2 124.3h.2v.1l.3-.1 .2 .1 .4-.1 .1 .8h-.2l-.1-.6-.2 .1v.5h-.2l-.1-.6-.2 .1v.5h-.2z" fill-rule="evenodd"/>
<path d="M104.5 124h.4v1.5h-.4v-.2h.2v-1.1h-.2z" fill-rule="evenodd"/>
<path d="M108.3 124h.5a.33 .33 0 0 1 .4 .2 .33 .33 0 0 1-.2 .4l.3 .5h-.2l-.5-.4v.4h-.3v-.6h.6l.1-.2-.1-.1h-.3v.3h-.3z" fill-rule="evenodd"/>
<path d="M109.5 124.4l.3-.1 .2 .1 .2 .4-.6 .1 .2 .1 .4-.1a.4 .4 0 0 1-.5 .3 .4 .4 0 0 1-.3-.5h.6l-.2-.2-.2 .2h-.2z" fill-rule="evenodd"/>
<path d="M110.4 124h.4v.2h-.2l.2 .3h-.2v.6h-.2v-.6h-.1z" fill-rule="evenodd"/>
<path d="M110.9 124.9h.2v.2h-.2z" fill-rule="evenodd"/>
<path d="M111.8 124h.2v1h.6v.1h-.8z" fill-rule="evenodd"/>
<path d="M112.8 124.4l.3-.1 .2 .1 .1 .7h-.7v-.2l.3 .1 .2-.2-.5 .1 .1-.2 .4-.1-.1-.1h-.4z" fill-rule="evenodd"/>
<path d="M113.5 124.3h.2l.2 .6 .2-.6h.3l-.4 1-.2 .2h-.2v-.2l.2-.1z" fill-rule="evenodd"/>
<path d="M114.5 124.4l.3-.1 .2 .1 .2 .4-.5 .1 .1 .1 .4-.1a.4 .4 0 0 1-.5 .3 .4 .4 0 0 1-.3-.5h.6l-.2-.2-.1 .2h-.3z" fill-rule="evenodd"/>
<path d="M115.4 124.3h.2v.1l.3-.1-.1 .2-.2 .1v.5h-.2z" fill-rule="evenodd"/>
<path d="M116 124.4l.4-.1 .3 .2h-.5v.1a.34 .34 0 0 1 .4 .2 .34 .34 0 0 1-.1 .4 .34 .34 0 0 1-.5-.1l-.1-.2 .5 .1 .1-.1h-.1a.33 .33 0 0 1-.5-.4z" fill-rule="evenodd"/>
<path d="M314.1 124.7h.8l-.5 1.3h-.1v-.4l.4-.7h-.6z" fill-rule="evenodd"/>
<path d="M314.2 137.6l.2-.1a.64 .64 0 0 1 .5 .7 .64 .64 0 0 1-.6 .6l-.2-.3 .5 .1 .2-.4-.5 .1-.2-.3 .1-.1a.26 .26 0 0 0 .4 .2 .26 .26 0 0 0 .1-.4 .26 .26 0 0 0-.5 .1l-.1 .1z" fill-rule="evenodd"/>
<path d="M314.2 131.2a.34 .34 0 0 1 .5 0 .34 .34 0 0 1 0 .5 .4 .4 0 0 1 0 .7 .4 .4 0 0 1-.6-.4h.1a.26 .26 0 0 0 .4 .2 .26 .26 0 0 0 .1-.4 .26 .26 0 0 0-.5 .1l-.1 .1 .2-.3-.2-.3h.2a.21 .21 0 0 0 .3 .2 .21 .21 0 0 0 0-.3 .21 .21 0 0 0-.3 .1h-.2z" fill-rule="evenodd"/>
<path d="M315.1 124.7a1.04 1.04 0 0 1 0 1.6l.3-.8z" fill-rule="evenodd"/>
<path d="M315.1 131.1a1.04 1.04 0 0 1 0 1.6l.3-.8z" fill-rule="evenodd"/>
<path d="M315.1 137.5a1.04 1.04 0 0 1 0 1.7l.3-.9z" fill-rule="evenodd"/>
<path d="M317.3 120.5h.6l.2 .2-.2 .1a.27 .27 0 0 0-.3-.3 .27 .27 0 0 0-.2 .4l.2 .1a.43 .43 0 0 1 .5 .5 .43 .43 0 0 1-.7 .2l-.3-.3 .2-.1a.31 .31 0 0 0 .3 .3 .31 .31 0 0 0 .3-.4l-.6-.2z" fill-rule="evenodd"/>
<path d="M317.3 126.9h.6l.2 .2-.2 .1a.27 .27 0 0 0-.3-.3 .27 .27 0 0 0-.2 .4l.2 .1a.43 .43 0 0 1 .5 .5 .43 .43 0 0 1-.7 .2l-.3-.3 .2-.1a.31 .31 0 0 0 .3 .3 .31 .31 0 0 0 .3-.4l-.6-.2z" fill-rule="evenodd"/>
<path d="M317.1 131.1h.1l.4 1.1 .4-1.1h.2l-.5 1.3h-.2z" fill-rule="evenodd"/>
<path d="M317.2 137.5h.5a.39 .39 0 0 1 .5 .4 .39 .39 0 0 1-.5 .4h-.3v.5h-.2v-.7h.6l.2-.2-.2-.2h-.4v.4h-.2z" fill-rule="evenodd"/>
<path d="M317.5 124.7h.2l.5 1.3h-.2l-.1-.4h-.5l-.2 .4h-.2l.2-.6h.6l-.2-.6-.2 .6h-.2z" fill-rule="evenodd"/>
<path d="M317.5 133.2h.2l.5 1.3h-.2l-.1-.4h-.5l-.2 .4h-.2l.2-.5h.6l-.2-.6-.2 .6h-.2z" fill-rule="evenodd"/>
<path d="M318.4 124.7h.1v1.1h.7v.2h-.8z" fill-rule="evenodd"/>
<path d="M318.4 133.2h.1l.7 1v-1h.2v1.3h-.2l-.7-1v1h-.1z" fill-rule="evenodd"/>
<path d="M318.4 131.1h.9v.2h-.8v.3h.7v.2h-.7v.4h.8v.2h-.9z" fill-rule="evenodd"/>
<path d="M318.3 120.4h1v.2h-.4v1.1h-.2v-1.1h-.4z" fill-rule="evenodd"/>
<path d="M318.5 127a.63 .63 0 0 1 1 .1 .63 .63 0 0 1-.3 .9 .63 .63 0 0 1-.9-.5h.2a.48 .48 0 0 0 .7 .4 .48 .48 0 0 0 0-.9h-.5l-.2 .5h-.2z" fill-rule="evenodd"/>
<path d="M318.5 137.7l.6-.2 .3 .3-.1 .1a.45 .45 0 0 0-.7-.2 .45 .45 0 0 0-.1 .7l.4 .2h.2l.2-.3 .1 .1a.62 .62 0 0 1-.9 .3 .62 .62 0 0 1 0-1z" fill-rule="evenodd"/>
<path d="M319.4 124.7h.1v1.1h.6v.2h-.7z" fill-rule="evenodd"/>
<path d="M319.6 131.1h.1l.7 1v-1h.2v1.3h-.2l-.7-1v1h-.1z" fill-rule="evenodd"/>
<path d="M319.7 126.8h.2v1.2h.6v.1h-.8z" fill-rule="evenodd"/>
<path d="M319.6 137.5l.9 .1v.3l-.1 .2 .2 .3a.38 .38 0 0 1-.5 .4h-.5v-.2l.8-.1-.1-.3h-.5v.4h-.2v-.6h.5a.2 .2 0 0 0 .3-.1 .2 .2 0 0 0-.2-.2h-.4v.3h-.2z" fill-rule="evenodd"/>
<path d="M319.7 133.2h.4a.64 .64 0 0 1 .6 .7 .64 .64 0 0 1-.6 .6h-.4v-.1h.4a.49 .49 0 0 0 .4-.5 .49 .49 0 0 0-.4-.5h-.3v1h-.1z" fill-rule="evenodd"/>
<path d="M319.7 120.4h.2l.5 1.3h-.2l-.1-.4h-.5l-.2 .4h-.1l.2-.5h.5l-.2-.6-.2 .6h-.1z" fill-rule="evenodd"/>
<path d="M320.6 124.7h.2l.4 1.1 .4-1.1h.2l-.5 1.3h-.2z" fill-rule="evenodd"/>
<path d="M320.7 126.8h.5a.64 .64 0 0 1 .6 .7 .64 .64 0 0 1-.6 .6h-.5v-.1h.5a.49 .49 0 0 0 .4-.5 .49 .49 0 0 0-.4-.5h-.3v1h-.2z" fill-rule="evenodd"/>
<path d="M321.3 137.5h.3l.3 1.1 .4-1.1h.2v1.3h-.1v-1.1l-.4 1.1h-.1l-.4-1.1v1.1h-.2z" fill-rule="evenodd"/>
<path d="M320.8 131.1h.5a.64 .64 0 0 1 .6 .6 .64 .64 0 0 1-.6 .7h-.5v-.2h.5a.49 .49 0 0 0 .4-.5 .49 .49 0 0 0-.4-.4h-.3v.9h-.2z" fill-rule="evenodd"/>
<path d="M320.6 120.6l.6-.2 .3 .3-.1 .1a.45 .45 0 0 0-.7-.1 .45 .45 0 0 0 0 .6l.3 .3 .3-.1 .1-.2h.2a.62 .62 0 0 1-1 .3 .62 .62 0 0 1 0-1z" fill-rule="evenodd"/>
<path d="M321.8 120.4h.2v.7l.6-.7h.2l-.5 .6 .5 .7h-.2l-.4-.6-.2 .2v.4h-.2z" fill-rule="evenodd"/>
<path d="M322 124.7h.2v1.3h-.2z" fill-rule="evenodd"/>
<path d="M322 126.8h.9v.2h-.7v.4h.7v.1h-.7v.5h.8v.1h-1z" fill-rule="evenodd"/>
<path d="M321.4 133.2h.5a.39 .39 0 0 1 .5 .4 .39 .39 0 0 1-.5 .4h-.3v.5h-.2v-.7h.7l.1-.2-.1-.2h-.5v.4h-.2z" fill-rule="evenodd"/>
<path d="M322.6 133.2h.2v.5a.42 .42 0 0 1 .6 .4 .42 .42 0 0 1-.7 .3l-.1 .1v-.5h.1a.29 .29 0 0 0 .4 .4 .29 .29 0 0 0 .1-.5l-.3-.2-.2 .3h-.1z" fill-rule="evenodd"/>
<path d="M322.2 131.3a.63 .63 0 0 1 1 .1 .63 .63 0 0 1-.3 .9 .63 .63 0 0 1-.8-.5h.1a.48 .48 0 0 0 .8 .3 .48 .48 0 0 0-.1-.8h-.5l-.2 .5h-.1z" fill-rule="evenodd"/>
<path d="M322.8 124.7h.2l.5 1.3h-.2l-.1-.4h-.6l-.1 .4h-.2l.2-.6h.6l-.2-.6-.2 .6h-.2z" fill-rule="evenodd"/>
<path d="M323.7 124.8l.6-.1 .2 .3-.1 .1a.27 .27 0 0 0-.3-.3 .27 .27 0 0 0-.2 .4h.2a.43 .43 0 0 1 .5 .6 .43 .43 0 0 1-.8 .1l-.2-.3 .1-.1a.31 .31 0 0 0 .4 .4 .31 .31 0 0 0 .3-.4l-.7-.3z" fill-rule="evenodd"/>
<path d="M323 120.4h.1v.8a.34 .34 0 0 0 .4 .4 .34 .34 0 0 0 .3-.4v-.8h.2v.8a.5 .5 0 0 1-.5 .5 .5 .5 0 0 1-.5-.5z" fill-rule="evenodd"/>
<path d="M323.2 137.5h.1l.6 1.3h-.2l-.2-.4h-.5l-.1 .4h-.2l.2-.5h.6l-.3-.7-.2 .7h-.1z" fill-rule="evenodd"/>
<path d="M323.2 126.8h.6a.35 .35 0 0 1 .4 .3 .35 .35 0 0 1-.3 .4l.4 .6h-.2l-.3-.5-.2-.1h-.2v.6h-.2v-.7l.8-.1a.21 .21 0 0 0 0-.2 .21 .21 0 0 0-.2-.1h-.4v.4h-.2z" fill-rule="evenodd"/>
<path d="M324.1 133.2h.9v.2h-.7v.4h.6v.1h-.6v.6h-.2z" fill-rule="evenodd"/>
<path d="M323.5 131.1h.6a.35 .35 0 0 1 .4 .3 .35 .35 0 0 1-.3 .4l.4 .6h-.2l-.3-.5-.2-.1h-.2v.6h-.2v-.7l.8-.1a.21 .21 0 0 0 0-.3 .21 .21 0 0 0-.2-.1h-.4v.5h-.2z" fill-rule="evenodd"/>
<path d="M323.8 137.5h1v.2h-.4v1.1h-.1v-1.1h-.5z" fill-rule="evenodd"/>
<path d="M324.5 126.8h.2l.4 1.1 .4-1.1h.2v1.3h-.2v-1.1l-.3 1.1h-.2l-.4-1.1v1.1h-.1z" fill-rule="evenodd"/>
<path d="M324.3 120.4h.4a.39 .39 0 0 1 .5 .4 .39 .39 0 0 1-.4 .4h-.4v.5h-.1v-.7h.6l.2-.2-.2-.2h-.5v.4h-.1z" fill-rule="evenodd"/>
<path d="M325 137.5h.9v.2h-.8v.3h.7v.2h-.7v.4h.8v.2h-.9z" fill-rule="evenodd"/>
<path d="M325.4 131.2l.6-.1 .2 .3-.2 .1a.27 .27 0 0 0-.3-.3 .27 .27 0 0 0-.2 .4h.2a.43 .43 0 0 1 .5 .6 .43 .43 0 0 1-.7 .1l-.3-.3 .2-.1a.31 .31 0 0 0 .3 .4 .31 .31 0 0 0 .3-.4l-.7-.3z" fill-rule="evenodd"/>
<path d="M325.2 133.2h.5a.35 .35 0 0 1 .5 .3 .35 .35 0 0 1-.4 .4l.5 .6h-.2a.62 .62 0 0 0-.7-.6v.6h-.2v-.7h.7l.1-.3-.2-.1h-.4v.4h-.2z" fill-rule="evenodd"/>
<path d="M325.6 124.7h.2l.5 1.3h-.2l-.1-.4h-.6l-.1 .4h-.2l.2-.6h.6l-.2-.6-.2 .6h-.2z" fill-rule="evenodd"/>
<path d="M326.5 133.2h.9v.2h-.8v.4h.7v.1h-.7v.5h.8v.1h-.9z" fill-rule="evenodd"/>
<path d="M326.5 131.1h.1v.5h.7v-.5h.2v1.3h-.2v-.6h-.7v.6h-.1z" fill-rule="evenodd"/>
<path d="M325.9 120.4h.2v.8a.34 .34 0 0 0 .3 .4 .34 .34 0 0 0 .3-.4v-.8h.2v.8a.5 .5 0 0 1-.5 .5 .5 .5 0 0 1-.5-.5z" fill-rule="evenodd"/>
<path d="M326.1 137.5h.6a.35 .35 0 0 1 .5 .3 .35 .35 0 0 1-.4 .4l.5 .6h-.3l-.3-.5-.2-.1h-.2v.6h-.2v-.7l.7-.1 .2-.2-.1-.1-.6-.1v.5h-.2z" fill-rule="evenodd"/>
<path d="M326.3 126.8h.2l.5 1.3h-.2l-.1-.4h-.5l-.2 .4h-.2l.2-.5h.6l-.2-.6-.2 .6h-.2z" fill-rule="evenodd"/>
<path d="M326.4 124.7h.6a.35 .35 0 0 1 .4 .3 .35 .35 0 0 1-.3 .4l.4 .6h-.2a.62 .62 0 0 0-.7-.6v.6h-.2v-.7l.7-.1 .1-.2-.1-.2h-.5v.5h-.2z" fill-rule="evenodd"/>
<path d="M327.2 126.9h.6l.3 .2-.2 .1a.27 .27 0 0 0-.3-.3 .27 .27 0 0 0-.2 .4l.2 .1a.43 .43 0 0 1 .5 .5 .43 .43 0 0 1-.7 .2l-.3-.3 .2-.1a.31 .31 0 0 0 .3 .3 .31 .31 0 0 0 .3-.4l-.7-.2z" fill-rule="evenodd"/>
<path d="M327.3 120.5h.6l.2 .2-.2 .1a.27 .27 0 0 0-.3-.3 .27 .27 0 0 0-.2 .4l.2 .1a.43 .43 0 0 1 .5 .5 .43 .43 0 0 1-.7 .2l-.3-.3 .2-.1a.31 .31 0 0 0 .3 .3 .31 .31 0 0 0 .3-.4l-.6-.2z" fill-rule="evenodd"/>
<path d="M327.4 137.5h.2v1.3h-.2z" fill-rule="evenodd"/>
<path d="M327.7 133.2h.9v.2h-.8v.4h.7v.1h-.7v.5h.8v.1h-.9z" fill-rule="evenodd"/>
<path d="M327.7 124.7h.9v.2h-.7v.3h.7v.2h-.7v.4h.7v.2h-.9z" fill-rule="evenodd"/>
<path d="M328.3 126.8h.2v.7l.6-.7h.3l-.6 .6 .6 .7h-.2l-.5-.6-.2 .2v.4h-.2z" fill-rule="evenodd"/>
<path d="M327.9 131.3a.63 .63 0 0 1 .9 .1 .63 .63 0 0 1-.3 .9 .63 .63 0 0 1-.8-.5h.2a.48 .48 0 0 0 .7 .3 .48 .48 0 0 0-.1-.8h-.4l-.2 .5h-.2z" fill-rule="evenodd"/>
<path d="M328.4 120.4h.2v1.3h-.2z" fill-rule="evenodd"/>
<path d="M328.9 120.4h.1l.7 1v-1h.2v1.3h-.2l-.7-1v1h-.1z" fill-rule="evenodd"/>
<path d="M328.3 137.5h.1l.6 1.3h-.2l-.2-.4h-.5l-.1 .4h-.2l.2-.5h.6l-.3-.7-.2 .7h-.1z" fill-rule="evenodd"/>
<path d="M329.1 137.5h.2v1.1h.6v.2h-.8z" fill-rule="evenodd"/>
<path d="M329.3 133.2h.9v.2h-.7v.4h.6v.1h-.6v.6h-.2z" fill-rule="evenodd"/>
<path d="M329.3 124.7h1v.2h-.5v1.1h-.1v-1.1h-.4z" fill-rule="evenodd"/>
<path d="M329.1 131.1h.2v.7a.34 .34 0 0 0 .3 .4 .34 .34 0 0 0 .4-.4v-.7h.1v.7a.5 .5 0 0 1-.5 .6 .5 .5 0 0 1-.5-.6z" fill-rule="evenodd"/>
<path d="M330.4 131.1h.2v1.1h.6v.2h-.8z" fill-rule="evenodd"/>
<path d="M330.4 124.7h.9v.2h-.7v.3h.7v.2h-.7v.4h.8v.2h-1z" fill-rule="evenodd"/>
<path d="M330.1 127a.63 .63 0 0 1 1 .1 .63 .63 0 0 1-.3 .9 .63 .63 0 0 1-.8-.5h.1a.48 .48 0 0 0 .8 .4 .48 .48 0 0 0-.1-.9h-.5l-.2 .5h-.1z" fill-rule="evenodd"/>
<path d="M330.3 120.6l.6-.2 .3 .2 .1 .2h-.2a.49 .49 0 0 0-.7 0 .49 .49 0 0 0 0 .7 .49 .49 0 0 0 .7-.1v-.2h-.4v-.1h.6v.4a.69 .69 0 0 1-1 .1 .69 .69 0 0 1 0-1z" fill-rule="evenodd"/>
<path d="M330.5 133.4a.63 .63 0 0 1 1 .1 .63 .63 0 0 1-.3 .9 .63 .63 0 0 1-.8-.5h.1a.48 .48 0 0 0 .8 .4 .48 .48 0 0 0-.1-.9h-.5l-.2 .5h-.1z" fill-rule="evenodd"/>
<path d="M330.5 137.5h.6a.35 .35 0 0 1 .4 .3 .35 .35 0 0 1-.3 .4l.4 .6h-.2l-.3-.5-.2-.1h-.2v.6h-.2v-.7l.7-.1 .2-.2-.2-.2h-.5v.5h-.2z" fill-rule="evenodd"/>
<path d="M331.6 124.7h.2l.6 1v-1h.2v1.3h-.2l-.6-1v1h-.2z" fill-rule="evenodd"/>
<path d="M331.8 137.5h.9v.2h-.7v.3h.7v.2h-.7v.4h.7v.2h-.9z" fill-rule="evenodd"/>
<path d="M331.4 131.1h.4a.64 .64 0 0 1 .7 .6 .64 .64 0 0 1-.6 .7h-.5v-.2h.4a.49 .49 0 0 0 .5-.5 .49 .49 0 0 0-.5-.4h-.2v.9h-.2z" fill-rule="evenodd"/>
<path d="M331.4 126.8h.5a.39 .39 0 0 1 .5 .4 .39 .39 0 0 1-.5 .4h-.3v.5h-.2v-.7h.6l.2-.2-.1-.2h-.5v.4h-.2z" fill-rule="evenodd"/>
<path d="M331.8 133.2h.6a.35 .35 0 0 1 .4 .3 .35 .35 0 0 1-.3 .4l.4 .6h-.2a.62 .62 0 0 0-.7-.6v.6h-.2v-.7h.7l.1-.3-.1-.1h-.5v.4h-.2z" fill-rule="evenodd"/>
<path d="M332.6 126.8h.9v.2h-.7v.4h.7v.1h-.7v.5h.7v.1h-.9z" fill-rule="evenodd"/>
<path d="M332 120.4l.8 .1 .1 .3-.2 .2 .3 .3a.38 .38 0 0 1-.5 .4h-.5v-.1l.8-.2-.1-.2-.5-.1v.5h-.2v-.6h.5a.2 .2 0 0 0 .2-.2 .2 .2 0 0 0-.1-.2h-.4v.4h-.2z" fill-rule="evenodd"/>
<path d="M333.2 131.1h.8v.2h-.6v.3h.6v.2h-.6v.6h-.2z" fill-rule="evenodd"/>
<path d="M333.2 120.4h.2v1.2h.6v.1h-.8z" fill-rule="evenodd"/>
<path d="M332.8 124.7h1v.2h-.4v1.1h-.2v-1.1h-.4z" fill-rule="evenodd"/>
<path d="M333.6 133.2h.2l.4 1.1 .4-1.1h.2v1.3h-.2v-1.1l-.4 1.1h-.1l-.4-1.1v1.1h-.1z" fill-rule="evenodd"/>
<path d="M333.1 137.7a.65 .65 0 0 1 .9 0 .65 .65 0 0 1-.1 .9l.3 .2-.1 .1-.3-.2h-.6l-.3-.4v-.2h.2a.44 .44 0 0 0 .6 .5l-.2-.1 .1-.1a.3 .3 0 0 0 .4 0 .3 .3 0 0 0-.1-.5 .43 .43 0 0 0-.5-.3 .43 .43 0 0 0-.3 .5h-.2z" fill-rule="evenodd"/>
<path d="M333.8 126.8h.1l.7 1v-1h.2v1.3h-.2l-.7-1v1h-.1z" fill-rule="evenodd"/>
<path d="M334 124.7h.9v.2h-.8v.3h.7v.2h-.7v.4h.8v.2h-.9z" fill-rule="evenodd"/>
<path d="M334.4 131.3a.63 .63 0 0 1 1 .1 .63 .63 0 0 1-.4 .9 .63 .63 0 0 1-.8-.5h.2a.48 .48 0 0 0 .7 .3 .48 .48 0 0 0-.1-.8h-.4l-.2 .5h-.2z" fill-rule="evenodd"/>
<path d="M335.1 126.8h.9v.2h-.8v.4h.7v.1h-.7v.5h.8v.1h-.9z" fill-rule="evenodd"/>
<path d="M334.4 137.5h.1v.7a.34 .34 0 0 0 .4 .4 .34 .34 0 0 0 .3-.4v-.7h.2v.7a.5 .5 0 0 1-.5 .6 .5 .5 0 0 1-.5-.6z" fill-rule="evenodd"/>
<path d="M334.5 120.4h.2l.6 1.3h-.2l-.2-.4h-.5l-.2 .4h-.1l.2-.5h.6l-.3-.6-.2 .6h-.1z" fill-rule="evenodd"/>
<path d="M335.6 131.1h.2v1.1h.6v.2h-.8z" fill-rule="evenodd"/>
<path d="M335.7 137.5h.1v1.3h-.1z" fill-rule="evenodd"/>
<path d="M335.2 124.7h.4a.64 .64 0 0 1 .6 .6 .64 .64 0 0 1-.6 .7h-.4v-.2h.4a.49 .49 0 0 0 .4-.5 .49 .49 0 0 0-.4-.4h-.3v.9h-.1z" fill-rule="evenodd"/>
<path d="M335.4 133.2h.2l.5 1.3h-.2l-.1-.4h-.6l-.1 .4h-.2l.2-.5h.6l-.2-.6-.2 .6h-.2z" fill-rule="evenodd"/>
<path d="M336.2 133.2h.2l.7 1v-1h.1v1.3h-.1l-.7-1v1h-.2z" fill-rule="evenodd"/>
<path d="M335.5 120.6l.6-.2 .3 .3-.1 .1a.45 .45 0 0 0-.7-.1 .45 .45 0 0 0 0 .6l.3 .3 .3-.1 .1-.2h.2a.62 .62 0 0 1-1 .3 .62 .62 0 0 1 0-1z" fill-rule="evenodd"/>
<path d="M336.6 131.1h.2v1.1h.6v.2h-.8z" fill-rule="evenodd"/>
<path d="M336.7 120.4h.1v.7l.7-.7h.2l-.5 .6 .5 .7h-.2l-.5-.6-.2 .2v.4h-.1z" fill-rule="evenodd"/>
<path d="M336.2 126.8h.5a.64 .64 0 0 1 .6 .7 .64 .64 0 0 1-.6 .6h-.5v-.1h.5a.49 .49 0 0 0 .4-.5 .49 .49 0 0 0-.4-.5h-.3v1h-.2z" fill-rule="evenodd"/>
<path d="M336.1 137.5h.6a.35 .35 0 0 1 .5 .3 .35 .35 0 0 1-.4 .4l.5 .6h-.2l-.4-.5-.2-.1h-.2v.6h-.2v-.7l.8-.1 .1-.2-.2-.2h-.5v.5h-.2z" fill-rule="evenodd"/>
<path d="M337.4 137.5h.9v.2h-.7v.3h.7v.2h-.7v.4h.8v.2h-1z" fill-rule="evenodd"/>
<path d="M337.1 124.9a.63 .63 0 0 1 .9 .1 .63 .63 0 0 1-.3 .9 .63 .63 0 0 1-.8-.5h.2a.48 .48 0 0 0 .7 .4 .48 .48 0 0 0 0-.9h-.5l-.2 .2v.3h-.2z" fill-rule="evenodd"/>
<path d="M338 126.8h.2v1.3h-.2z" fill-rule="evenodd"/>
<path d="M337.7 131.3a.63 .63 0 0 1 1 .1 .63 .63 0 0 1-.3 .9 .63 .63 0 0 1-.8-.5h.1a.48 .48 0 0 0 .8 .3 .48 .48 0 0 0-.1-.8h-.5l-.2 .5h-.1z" fill-rule="evenodd"/>
<path d="M338.3 124.7h.2l.7 1v-1h.1v1.3h-.2l-.6-1v1h-.2z" fill-rule="evenodd"/>
<path d="M338.3 120.4h.2l.7 1v-1h.1v1.3h-.1l-.7-1v1h-.2z" fill-rule="evenodd"/>
<path d="M337.5 133.2h.2v.8a.34 .34 0 0 0 .3 .4 .34 .34 0 0 0 .4-.4v-.8h.1v.8a.5 .5 0 0 1-.5 .5 .5 .5 0 0 1-.5-.5z" fill-rule="evenodd"/>
<path d="M338.5 126.8h.2l.6 1v-1h.2v1.3h-.2l-.6-1v1h-.2z" fill-rule="evenodd"/>
<path d="M338.6 137.5h.3l.3 1.1 .4-1.1h.2v1.3h-.1v-1.1l-.4 1.1h-.2l-.3-1.1v1.1h-.2z" fill-rule="evenodd"/>
<path d="M338.8 133.2h.9v.2h-.7v.4h.6v.1h-.6v.6h-.2z" fill-rule="evenodd"/>
<path d="M338.9 131.1h.2l.2 1.1 .3-1.1h.2l.3 1.1 .3-1.1h.1l-.3 1.3h-.2l-.3-1.1-.3 1.1h-.2z" fill-rule="evenodd"/>
<path d="M340.1 137.5h.9v.2h-.7v.3h.7v.2h-.7v.4h.7v.2h-.9z" fill-rule="evenodd"/>
<path d="M339.7 120.6a.63 .63 0 0 1 1 .1 .63 .63 0 0 1-.3 .9 .63 .63 0 0 1-.8-.5h.2a.48 .48 0 0 0 .7 .4 .48 .48 0 0 0-.1-.9h-.5l-.1 .5h-.2z" fill-rule="evenodd"/>
<path d="M340.1 124.7l.8 .1 .1 .3-.2 .2 .2 .3a.38 .38 0 0 1-.4 .4h-.5v-.2l.7-.1v-.3h-.5v.4h-.2v-.6h.4a.2 .2 0 0 0 .3-.1 .2 .2 0 0 0-.2-.2h-.3v.3h-.2z" fill-rule="evenodd"/>
<path d="M340.4 127l.7-.2 .2 .2 .1 .2h-.2a.49 .49 0 0 0-.7 0 .49 .49 0 0 0 0 .7 .49 .49 0 0 0 .8-.1v-.2h-.4v-.1h.5v.4a.69 .69 0 0 1-1 .1 .69 .69 0 0 1 0-1z" fill-rule="evenodd"/>
<path d="M340.2 133.2h.2l.5 1.3h-.2l-.1-.4h-.6l-.1 .4h-.2l.2-.5h.6l-.2-.6-.2 .6h-.2z" fill-rule="evenodd"/>
<path d="M341 120.4h.2l.6 1v-1h.2v1.3h-.2l-.6-1v1h-.2z" fill-rule="evenodd"/>
<path d="M341.3 137.5h.1l.7 1v-1h.2v1.3h-.2l-.7-1v1h-.1z" fill-rule="evenodd"/>
<path d="M341.7 126.8h.9v.2h-.8v.4h.7v.1h-.7v.5h.8v.1h-.9z" fill-rule="evenodd"/>
<path d="M341.2 131.1h.5a.35 .35 0 0 1 .5 .3 .35 .35 0 0 1-.4 .4l.5 .6h-.2l-.4-.5-.2-.1h-.2v.6h-.1v-.7l.7-.1 .1-.2-.2-.2h-.5v.5h-.1z" fill-rule="evenodd"/>
<path d="M341.1 133.4l.6-.2 .3 .3-.1 .1a.45 .45 0 0 0-.7-.1 .45 .45 0 0 0-.1 .6l.4 .3 .3-.1 .1-.2h.2a.62 .62 0 0 1-1 .3 .62 .62 0 0 1 0-1z" fill-rule="evenodd"/>
<path d="M341.4 124.9a.63 .63 0 0 1 1 .1 .63 .63 0 0 1-.3 .9 .63 .63 0 0 1-.9-.5h.2a.48 .48 0 0 0 .8 .3 .48 .48 0 0 0-.1-.8h-.5l-.2 .5h-.2z" fill-rule="evenodd"/>
<path d="M342.2 121.2h.5v.1h-.5z" fill-rule="evenodd"/>
<path d="M342.2 133.2h1v.2h-.4v1.1h-.2v-1.1h-.4z" fill-rule="evenodd"/>
<path d="M342.5 137.5h1v.2h-.5v1.1h-.1v-1.1h-.4z" fill-rule="evenodd"/>
<path d="M342.6 124.7h1v.2h-.4v1.1h-.2v-1.1h-.4z" fill-rule="evenodd"/>
<path d="M342.6 131.3a.63 .63 0 0 1 1 .1 .63 .63 0 0 1-.4 .9 .63 .63 0 0 1-.8-.5h.2a.48 .48 0 0 0 .7 .3 .48 .48 0 0 0-.1-.8h-.4l-.2 .5h-.2z" fill-rule="evenodd"/>
<path d="M342.9 126.8h.5a.35 .35 0 0 1 .5 .3 .35 .35 0 0 1-.4 .4l.5 .6h-.2a.62 .62 0 0 0-.8-.6v.6h-.1v-.7h.7l.1-.3-.2-.1h-.5v.4h-.1z" fill-rule="evenodd"/>
<path d="M343.7 137.6l.6-.1 .2 .3-.1 .1a.27 .27 0 0 0-.3-.3 .27 .27 0 0 0-.2 .4h.2a.43 .43 0 0 1 .5 .6 .43 .43 0 0 1-.8 .1l-.2-.3h.1a.31 .31 0 0 0 .4 .3 .31 .31 0 0 0 .3-.4l-.7-.3z" fill-rule="evenodd"/>
<path d="M343.8 124.7h.1v.5h.7v-.5h.1v1.3h-.1v-.6h-.7v.6h-.1z" fill-rule="evenodd"/>
<path d="M343 120.6l.6-.2 .3 .3-.1 .1a.45 .45 0 0 0-.7-.1 .45 .45 0 0 0 0 .6l.3 .3 .3-.1 .1-.2h.2a.62 .62 0 0 1-1 .3 .62 .62 0 0 1 0-1z" fill-rule="evenodd"/>
<path d="M343.8 131.1h.2v.5h.7v-.5h.1v1.3h-.1v-.6h-.7v.6h-.2z" fill-rule="evenodd"/>
<path d="M343.3 133.2h.2v.8a.34 .34 0 0 0 .3 .4 .34 .34 0 0 0 .4-.4v-.8h.1v.8a.5 .5 0 0 1-.5 .5 .5 .5 0 0 1-.5-.5z" fill-rule="evenodd"/>
<path d="M344.1 126.8l.8 .1 .1 .3-.1 .2 .2 .3a.38 .38 0 0 1-.5 .4h-.5v-.1l.8-.2-.1-.2-.5-.1v.5h-.2v-.6h.5a.2 .2 0 0 0 .3-.2 .2 .2 0 0 0-.2-.2h-.4v.4h-.2z" fill-rule="evenodd"/>
<path d="M344.3 120.6a.63 .63 0 0 1 1 .1 .63 .63 0 0 1-.3 .9 .63 .63 0 0 1-.9-.5h.2a.48 .48 0 0 0 .7 .4 .48 .48 0 0 0 0-.9h-.5l-.2 .5h-.2z" fill-rule="evenodd"/>
<path d="M344.8 137.9h.2v.1h-.2z" fill-rule="evenodd"/>
<path d="M344.8 138.6h.2v.2h-.2z" fill-rule="evenodd"/>
<path d="M345.2 131.2l.6-.1 .2 .3-.1 .1a.27 .27 0 0 0-.3-.3 .27 .27 0 0 0-.2 .4h.2a.43 .43 0 0 1 .4 .6 .43 .43 0 0 1-.7 .1l-.2-.3 .1-.1a.31 .31 0 0 0 .4 .4 .31 .31 0 0 0 .2-.4l-.6-.3z" fill-rule="evenodd"/>
<path d="M344.6 133.2h.6a.35 .35 0 0 1 .4 .3 .35 .35 0 0 1-.3 .4l.5 .6h-.3l-.3-.5-.2-.1h-.2v.6h-.2v-.7l.8-.1a.21 .21 0 0 0 0-.2 .21 .21 0 0 0-.2-.1h-.4v.4h-.2z" fill-rule="evenodd"/>
<path d="M345.3 126.8h.9v.2h-.7v.4h.7v.1h-.7v.5h.8v.1h-1z" fill-rule="evenodd"/>
<path d="M345.6 124.8l.6-.1 .2 .3-.1 .1a.27 .27 0 0 0-.3-.3 .27 .27 0 0 0-.2 .4h.2a.43 .43 0 0 1 .4 .6 .43 .43 0 0 1-.7 .1l-.2-.3 .1-.1a.31 .31 0 0 0 .4 .4 .31 .31 0 0 0 .2-.4l-.6-.3z" fill-rule="evenodd"/>
<path d="M345.6 120.4h.1l.7 1v-1h.2v1.3h-.2l-.7-1v1h-.1z" fill-rule="evenodd"/>
<path d="M345.9 133.2h.2v1.3h-.2z" fill-rule="evenodd"/>
<path d="M346.4 133.2h.2l.6 1v-1h.2v1.3h-.2l-.6-1v1h-.2z" fill-rule="evenodd"/>
<path d="M346.7 124.7h.2v1.3h-.2z" fill-rule="evenodd"/>
<path d="M346.5 126.8h.6a.35 .35 0 0 1 .4 .3 .35 .35 0 0 1-.3 .4l.4 .6h-.2a.62 .62 0 0 0-.7-.6v.6h-.2v-.7l.8-.1a.21 .21 0 0 0 0-.2 .21 .21 0 0 0-.2-.1h-.4v.4h-.2z" fill-rule="evenodd"/>
<path d="M346.8 120.4h.5a.64 .64 0 0 1 .6 .7 .64 .64 0 0 1-.6 .6h-.5v-.1h.5a.49 .49 0 0 0 .4-.5 .49 .49 0 0 0-.4-.5h-.3v1h-.2z" fill-rule="evenodd"/>
<path d="M346.9 131.3l.6-.2 .3 .3-.1 .1a.44 .44 0 0 0-.7-.2 .44 .44 0 0 0 0 .7l.3 .2h.3l.1-.3 .2 .1a.62 .62 0 0 1-1 .3 .62 .62 0 0 1 0-1z" fill-rule="evenodd"/>
<path d="M347.2 124.7h.4a.64 .64 0 0 1 .7 .6 .64 .64 0 0 1-.6 .7h-.5v-.2h.4a.49 .49 0 0 0 .5-.5 .49 .49 0 0 0-.5-.4h-.2v.9h-.2z" fill-rule="evenodd"/>
<path d="M347.8 127.9h.2v.2h-.2z" fill-rule="evenodd"/>
<path d="M347.8 133.4l.7-.2 .2 .2 .1 .2h-.1a.49 .49 0 0 0-.8 0 .49 .49 0 0 0 0 .7 .49 .49 0 0 0 .8-.1v-.2h-.4v-.1h.5v.4a.69 .69 0 0 1-1 .1 .69 .69 0 0 1 0-1z" fill-rule="evenodd"/>
<path d="M348.5 124.7h.9v.2h-.7v.3h.7v.2h-.7v.4h.7v.2h-.9z" fill-rule="evenodd"/>
<path d="M348.2 131.3a.63 .63 0 0 1 1 .1 .63 .63 0 0 1-.3 .9 .63 .63 0 0 1-.9-.5h.2a.48 .48 0 0 0 .8 .3 .48 .48 0 0 0-.1-.8h-.5l-.2 .5h-.2z" fill-rule="evenodd"/>
<path d="M348.1 120.4h.2v.8a.34 .34 0 0 0 .3 .4 .34 .34 0 0 0 .4-.4v-.8h.1v.8a.5 .5 0 0 1-.5 .5 .5 .5 0 0 1-.5-.5z" fill-rule="evenodd"/>
<path d="M349.5 131.1h.2l.4 1.1 .3-1.1h.3v1.3h-.2v-1.1l-.4 1.1h-.1l-.4-1.1v1.1h-.1z" fill-rule="evenodd"/>
<path d="M349.8 124.8l.6-.1 .2 .3-.2 .1a.27 .27 0 0 0-.3-.3 .27 .27 0 0 0-.2 .4h.2a.43 .43 0 0 1 .5 .6 .43 .43 0 0 1-.7 .1l-.3-.3 .2-.1a.31 .31 0 0 0 .3 .4 .31 .31 0 0 0 .3-.4l-.7-.3z" fill-rule="evenodd"/>
<path d="M349.5 120.6l.6-.2 .3 .3-.1 .1a.45 .45 0 0 0-.7-.1 .45 .45 0 0 0 0 .6l.3 .3 .3-.1 .1-.2h.2a.62 .62 0 0 1-1 .3 .62 .62 0 0 1 0-1z" fill-rule="evenodd"/>
<path d="M350.6 120.4h1v.2h-.4v1.1h-.2v-1.1h-.4z" fill-rule="evenodd"/>
<path d="M350.9 131.1h.5a.39 .39 0 0 1 .5 .4 .39 .39 0 0 1-.5 .4h-.3v.5h-.2v-.7h.7l.1-.2-.1-.2h-.5v.4h-.2z" fill-rule="evenodd"/>
<path d="M351.8 120.4h.2v1.3h-.2z" fill-rule="evenodd"/>
<path d="M352.1 131.1h.2v1.1h.6v.2h-.8z" fill-rule="evenodd"/>
<path d="M351.3 124.7h.2v.7a.34 .34 0 0 0 .3 .4 .34 .34 0 0 0 .4-.4v-.7h.1v.7a.5 .5 0 0 1-.5 .6 .5 .5 0 0 1-.5-.6z" fill-rule="evenodd"/>
<path d="M352.1 120.4h.2l.4 1.2 .4-1.2h.2l-.5 1.3h-.2z" fill-rule="evenodd"/>
<path d="M352.6 124.7h.2l.7 1v-1h.1v1.3h-.1l-.7-1v1h-.2z" fill-rule="evenodd"/>
<path d="M353.1 131.1h.2v1.3h-.2z" fill-rule="evenodd"/>
<path d="M353.5 120.4h.9v.2h-.8v.4h.7v.1h-.7v.5h.8v.1h-.9z" fill-rule="evenodd"/>
<path d="M353.9 124.7h.2v1.1h.6v.2h-.8z" fill-rule="evenodd"/>
<path d="M354 131.1h.1l.6 1.3h-.2l-.2-.4h-.5l-.1 .4h-.2l.2-.5h.6l-.3-.7-.2 .7h-.1z" fill-rule="evenodd"/>
<path d="M354.8 131.1h.2l.6 1v-1h.2v1.3h-.2l-.6-1v1h-.2z" fill-rule="evenodd"/>
<path d="M354.9 124.7h.9v.2h-.7v.3h.7v.2h-.7v.4h.8v.2h-1z" fill-rule="evenodd"/>
<path d="M355.1 120.4h.9v.2h-.7v.4h.7v.1h-.7v.5h.8v.1h-1z" fill-rule="evenodd"/>
<path d="M356.2 124.8l.6-.1 .2 .3-.2 .1a.27 .27 0 0 0-.3-.3 .27 .27 0 0 0-.2 .4h.2a.43 .43 0 0 1 .5 .6 .43 .43 0 0 1-.7 .1l-.3-.3 .2-.1a.31 .31 0 0 0 .3 .4 .31 .31 0 0 0 .3-.4l-.6-.3z" fill-rule="evenodd"/>
<path d="M356 131.1h1v.2h-.4v1.1h-.2v-1.1h-.4z" fill-rule="evenodd"/>
<path d="M356.3 120.4h.5a.39 .39 0 0 1 .5 .4 .39 .39 0 0 1-.5 .4h-.3v.5h-.2v-.7h.7l.1-.2-.1-.2h-.5v.4h-.2z" fill-rule="evenodd"/>
<path d="M357.4 124.8l.6-.1 .2 .3-.2 .1a.27 .27 0 0 0-.3-.3 .27 .27 0 0 0-.2 .4h.2a.43 .43 0 0 1 .5 .6 .43 .43 0 0 1-.7 .1l-.3-.3 .2-.1a.31 .31 0 0 0 .3 .4 .31 .31 0 0 0 .3-.4l-.7-.3z" fill-rule="evenodd"/>
<path d="M357.6 120.6a.63 .63 0 0 1 1 .1 .63 .63 0 0 1-.3 .9 .63 .63 0 0 1-.9-.5h.2a.48 .48 0 0 0 .8 .4 .48 .48 0 0 0-.1-.9h-.5l-.2 .5h-.2z" fill-rule="evenodd"/>
<path d="M357.6 131.1h.5a.39 .39 0 0 1 .5 .4 .39 .39 0 0 1-.5 .4h-.3v.5h-.2v-.7h.7l.1-.2-.1-.2h-.5v.4h-.2z" fill-rule="evenodd"/>
<path d="M358.8 120.4h.2l.3 .5 .4-.5h.2l-.5 .6 .5 .7h-.2l-.4-.5-.3 .5h-.3l.5-.7z" fill-rule="evenodd"/>
<path d="M358.8 131.1h.6a.35 .35 0 0 1 .4 .3 .35 .35 0 0 1-.3 .4l.4 .6h-.2l-.3-.5-.2-.1h-.2v.6h-.2v-.7l.8-.1a.21 .21 0 0 0 0-.3 .21 .21 0 0 0-.2-.1h-.4v.5h-.2z" fill-rule="evenodd"/>
<path d="M359.9 120.4h.2l.4 .6 .4-.6h.2l-.5 .8v.5h-.2v-.5z" fill-rule="evenodd"/>
<path d="M360.2 131.3a.63 .63 0 0 1 1 .1 .63 .63 0 0 1-.3 .9 .63 .63 0 0 1-.9-.5h.2a.48 .48 0 0 0 .8 .3 .48 .48 0 0 0-.1-.8h-.5l-.2 .5h-.2z" fill-rule="evenodd"/>
<path d="M361.7 120.4h.2v1.3h-.2z" fill-rule="evenodd"/>
<path d="M362.2 120.4h.2l.6 1v-1h.2v1.3h-.2l-.6-1v1h-.2z" fill-rule="evenodd"/>
<path d="M361.6 131.3l.6-.2 .3 .3-.1 .1a.45 .45 0 0 0-.7-.2 .45 .45 0 0 0-.1 .7l.4 .2h.3l.1-.3 .2 .1a.62 .62 0 0 1-1 .3 .62 .62 0 0 1 0-1z" fill-rule="evenodd"/>
<path d="M362.8 131.1h.9v.2h-.8v.3h.7v.2h-.7v.4h.8v.2h-.9z" fill-rule="evenodd"/>
<path d="M363.5 120.4h.1v.7l.7-.7h.2l-.5 .6 .5 .7h-.2l-.4-.6-.3 .2v.4h-.1z" fill-rule="evenodd"/>
<path d="M364 131.2l.6-.1 .3 .3-.2 .1a.27 .27 0 0 0-.3-.3 .27 .27 0 0 0-.2 .4h.2a.43 .43 0 0 1 .5 .6 .43 .43 0 0 1-.8 .1l-.2-.3 .1-.1a.31 .31 0 0 0 .4 .4 .31 .31 0 0 0 .3-.4l-.7-.3z" fill-rule="evenodd"/>
<path d="M364.7 121.5h.2v.2h-.2z" fill-rule="evenodd"/>
<path d="M365.2 131.2l.6-.1 .2 .3-.1 .1a.27 .27 0 0 0-.3-.3 .27 .27 0 0 0-.2 .4h.2a.43 .43 0 0 1 .4 .6 .43 .43 0 0 1-.7 .1l-.2-.3 .1-.1a.31 .31 0 0 0 .4 .4 .31 .31 0 0 0 .2-.4l-.6-.3z" fill-rule="evenodd"/>
<path d="M314.2 154.9l.5-.3v1.2h-.2v-1l-.3 .2z" fill-rule="evenodd"/>
<path d="M315.2 154.6h.3a.71 .71 0 0 1 .4 .6 .71 .71 0 0 1-.4 .7 .49 .49 0 0 1-.4-.7h.1a.32 .32 0 0 0 .1 .5 .32 .32 0 0 0 .4 0 .32 .32 0 0 0 0-.5 .3 .3 0 0 0 0-.4 .3 .3 0 0 0-.4 0l-.1 .4h-.1z" fill-rule="evenodd"/>
<path d="M316.1 154.6a1.04 1.04 0 0 1 0 1.6l.2-.8z" fill-rule="evenodd"/>
<path d="M317.2 146l.8 .1 .1 .3-.2 .2 .2 .3a.38 .38 0 0 1-.4 .4h-.5v-.1l.7-.1v-.3l-.6-.1v.5h-.1v-.6h.4a.2 .2 0 0 0 .3-.2 .2 .2 0 0 0-.2-.2h-.4v.4h-.1z" fill-rule="evenodd"/>
<path d="M317.2 158.8l.8 .1 .1 .3-.2 .2 .2 .3a.39 .39 0 0 1-.4 .4h-.5v-.1l.7-.1v-.3l-.6-.1v.5h-.1v-.6h.4a.2 .2 0 0 0 .3-.2 .2 .2 0 0 0-.2-.2h-.4v.4h-.1z" fill-rule="evenodd"/>
<path d="M317.2 154.6h.4a.64 .64 0 0 1 .6 .6 .64 .64 0 0 1-.6 .6h-.4v-.1h.4a.49 .49 0 0 0 .5-.5 .49 .49 0 0 0-.5-.5h-.2v1h-.2z" fill-rule="evenodd"/>
<path d="M317.3 148.3l.6-.1 .3 .2-.1 .2a.45 .45 0 0 0-.7-.2 .45 .45 0 0 0 0 .7l.3 .2 .3-.1 .1-.2h.2a.62 .62 0 0 1-1 .3 .62 .62 0 0 1 0-1z" fill-rule="evenodd"/>
<path d="M317.5 141.8h.2l.5 1.2h-.2l-.1-.3h-.5l-.2 .3h-.2l.2-.5h.6l-.2-.6-.2 .6h-.2z" fill-rule="evenodd"/>
<path d="M318.4 142.9h.2v.1h-.2z" fill-rule="evenodd"/>
<path d="M318.4 147.1h.2v.2h-.2z" fill-rule="evenodd"/>
<path d="M318.5 154.6h.9v.1h-.8v.4h.7v.2h-.7v.4h.8v.1h-.9z" fill-rule="evenodd"/>
<path d="M318.5 149.3h.2v.1h-.2z" fill-rule="evenodd"/>
<path d="M318.5 159a.63 .63 0 0 1 1 .1 .63 .63 0 0 1-.4 .9 .63 .63 0 0 1-.8-.5h.2a.48 .48 0 0 0 .7 .4 .48 .48 0 0 0 0-.9h-.5l-.2 .5h-.2z" fill-rule="evenodd"/>
<path d="M319.7 154.7l.6-.1 .3 .3h-.2a.27 .27 0 0 0-.3-.3 .27 .27 0 0 0-.2 .4l.2 .1a.43 .43 0 0 1 .5 .6 .43 .43 0 0 1-.8 .1l-.2-.3 .2-.1a.31 .31 0 0 0 .3 .3 .31 .31 0 0 0 .3-.3l-.7-.3z" fill-rule="evenodd"/>
<path d="M320.2 148.2h1v.1h-.8v.4h.7v.2h-.7v.4h.8v.1h-1z" fill-rule="evenodd"/>
<path d="M320.2 150.3h.2v.5h.7v-.5h.1v1.3h-.1v-.6h-.7v.6h-.2z" fill-rule="evenodd"/>
<path d="M320.2 141.8h.9v.1h-.7v.4h.6v.2h-.6v.5h-.2z" fill-rule="evenodd"/>
<path d="M320.1 146h1v.2h-.4v1.1h-.1v-1.1h-.5z" fill-rule="evenodd"/>
<path d="M320.9 154.6h.1v1.2h-.1z" fill-rule="evenodd"/>
<path d="M320.2 143.9h.2v.7a.34 .34 0 0 0 .3 .4 .34 .34 0 0 0 .4-.4v-.7h.1v.7a.5 .5 0 0 1-.5 .6 .5 .5 0 0 1-.5-.6z" fill-rule="evenodd"/>
<path d="M321.3 141.8h.2v1.1h.6v.1h-.8z" fill-rule="evenodd"/>
<path d="M321.5 143.9h.2v1.1h.6v.2h-.8z" fill-rule="evenodd"/>
<path d="M320.9 158.8h.6a.35 .35 0 0 1 .5 .3 .35 .35 0 0 1-.4 .4l.5 .6h-.3l-.3-.5-.2-.1h-.2v.6h-.2v-.7l.8-.1a.21 .21 0 0 0 0-.2 .21 .21 0 0 0-.2-.1h-.4v.4h-.2z" fill-rule="evenodd"/>
<path d="M321.4 146.5l.2-.1 .3 .1 .2-.1v.8a.4 .4 0 0 1-.3 .5 .4 .4 0 0 1-.5-.3l.3 .2 .3-.2v-.2l-.3 .1-.3-.1-.1-.4h.2a.3 .3 0 0 0 .4 .3 .3 .3 0 0 0 .1-.5l-.3-.1-.2 .3h-.2z" fill-rule="evenodd"/>
<path d="M321.5 154.7l.6-.1 .3 .2v.1l-.1 .1a.49 .49 0 0 0-.7-.1 .49 .49 0 0 0 0 .7 .49 .49 0 0 0 .7 0v-.3h-.4v-.1h.6v.5a.69 .69 0 0 1-1 0 .69 .69 0 0 1 0-1z" fill-rule="evenodd"/>
<path d="M321.5 148.3a.65 .65 0 0 1 1 .1 .65 .65 0 0 1-.1 .9l.2 .1-.1 .1-.2-.1h-.7l-.2-.5v-.1h.1a.44 .44 0 0 0 .6 .5l-.1-.1v-.1a.3 .3 0 0 0 .4-.1 .3 .3 0 0 0 0-.4 .43 .43 0 0 0-.5-.3 .43 .43 0 0 0-.4 .5h-.1z" fill-rule="evenodd"/>
<path d="M321.9 150.3h.1l.6 1.3h-.2l-.2-.4h-.5l-.1 .4h-.2l.2-.5h.6l-.2-.7-.3 .7h-.1z" fill-rule="evenodd"/>
<path d="M322.7 150.3h.2v1.1h.6v.2h-.8z" fill-rule="evenodd"/>
<path d="M322.7 154.6h.2l.7 1v-1h.1v1.2h-.2l-.6-1v1h-.2z" fill-rule="evenodd"/>
<path d="M322.2 158.8h.5a.64 .64 0 0 1 .6 .7 .64 .64 0 0 1-.6 .6h-.5v-.1h.5a.49 .49 0 0 0 .4-.5 .49 .49 0 0 0-.4-.5h-.3v1h-.2z" fill-rule="evenodd"/>
<path d="M322.6 144l.2-.1a.64 .64 0 0 1 .5 .7 .64 .64 0 0 1-.6 .6l-.2-.3 .5 .1 .1-.4-.4 .1-.3-.3 .2-.1a.26 .26 0 0 0 .4 .2 .26 .26 0 0 0 0-.4 .26 .26 0 0 0-.4 .1l-.2 .1z" fill-rule="evenodd"/>
<path d="M322.9 146.4l.4-.4v1.3h-.1v-1l-.3 .2z" fill-rule="evenodd"/>
<path d="M322.7 141.8h.1l.6 1.2h-.2l-.2-.3h-.5l-.2 .3h-.1l.2-.5h.6l-.3-.6-.2 .6h-.1z" fill-rule="evenodd"/>
<path d="M323.5 141.8h.2l.4 1.1 .4-1.1h.2v1.2h-.2v-1l-.3 1h-.2l-.4-1v1h-.1z" fill-rule="evenodd"/>
<path d="M322.8 148.2h.2v.7a.34 .34 0 0 0 .3 .4 .34 .34 0 0 0 .3-.4v-.7h.2v.7a.5 .5 0 0 1-.5 .6 .5 .5 0 0 1-.5-.6z" fill-rule="evenodd"/>
<path d="M323.9 146.1h.6v.1h-.5l-.1 .3a.42 .42 0 0 1 .6 .2 .42 .42 0 0 1-.2 .6 .42 .42 0 0 1-.6-.3h.2a.28 .28 0 0 0 .4 .1 .28 .28 0 0 0 0-.5 .28 .28 0 0 0-.4 .1h-.1z" fill-rule="evenodd"/>
<path d="M324.1 158.9h.6l.2 .2-.1 .1a.27 .27 0 0 0-.4-.3 .27 .27 0 0 0-.2 .4l.3 .1a.43 .43 0 0 1 .4 .5 .43 .43 0 0 1-.7 .2l-.3-.3 .2-.1a.31 .31 0 0 0 .3 .3 .31 .31 0 0 0 .3-.4l-.6-.2z" fill-rule="evenodd"/>
<path d="M324 143.9h.1v.8h.2v.2h-.2v.3h-.2v-.3h-.5v-.2h.5v-.5l-.4 .5h-.1z" fill-rule="evenodd"/>
<path d="M324.1 148.2h.2v1.2h-.2z" fill-rule="evenodd"/>
<path d="M323.8 150.5a.63 .63 0 0 1 1 .1 .63 .63 0 0 1-.3 .9 .63 .63 0 0 1-.9-.5h.2a.48 .48 0 0 0 .8 .3 .48 .48 0 0 0-.1-.8h-.5l-.2 .5h-.2z" fill-rule="evenodd"/>
<path d="M324.4 143.9h.1l.4 1.1 .4-1.1h.2l-.5 1.3h-.2z" fill-rule="evenodd"/>
<path d="M324.4 148.2h.2l.4 1.1 .4-1.1h.2l-.5 1.2h-.2z" fill-rule="evenodd"/>
<path d="M325 141.8h.2l.4 1.1 .4-1.1h.2v1.2h-.2v-1l-.4 1h-.1l-.4-1v1h-.1z" fill-rule="evenodd"/>
<path d="M324.6 154.7l.7-.1 .2 .2 .1 .1-.1 .1a.49 .49 0 0 0-.8-.1 .49 .49 0 0 0 0 .7 .49 .49 0 0 0 .8 0v-.3h-.4v-.1h.5v.5a.69 .69 0 0 1-1 0 .69 .69 0 0 1 0-1z" fill-rule="evenodd"/>
<path d="M324.9 146.1l.2-.1a.71 .71 0 0 1 .5 .7 .71 .71 0 0 1-.5 .6 .49 .49 0 0 1-.4-.6h.2a.32 .32 0 0 0 0 .4 .32 .32 0 0 0 .4 0 .32 .32 0 0 0 .1-.4 .3 .3 0 0 0 0-.5 .3 .3 0 0 0-.5 .1v.4h-.2z" fill-rule="evenodd"/>
<path d="M325.2 158.8h.2v1.3h-.2z" fill-rule="evenodd"/>
<path d="M325.5 144.6h.5v.2h-.5z" fill-rule="evenodd"/>
<path d="M325.2 150.5l.6-.2 .3 .2 .1 .2h-.2a.49 .49 0 0 0-.7 0 .49 .49 0 0 0 0 .7 .49 .49 0 0 0 .7-.1v-.2h-.3v-.2h.5v.5a.69 .69 0 0 1-1 0 .69 .69 0 0 1 0-.9z" fill-rule="evenodd"/>
<path d="M325.9 154.6h.9v.1h-.8v.4h.7v.2h-.7v.4h.8v.1h-.9z" fill-rule="evenodd"/>
<path d="M326.5 150.3h.9v.2h-.8v.3h.7v.2h-.7v.4h.8v.2h-.9z" fill-rule="evenodd"/>
<path d="M326.3 144l.2-.1a.71 .71 0 0 1 .4 .6 .71 .71 0 0 1-.4 .7 .51 .51 0 0 1-.4-.7h.2a.32 .32 0 0 0 0 .5 .32 .32 0 0 0 .4 0 .32 .32 0 0 0 .1-.5 .3 .3 0 0 0-.1-.4 .3 .3 0 0 0-.4 .1v.3h-.2z" fill-rule="evenodd"/>
<path d="M326 148.2h.2l.5 1.2h-.1l-.2-.3h-.5l-.2 .3h-.1l.2-.5h.6l-.3-.6-.2 .6h-.1z" fill-rule="evenodd"/>
<path d="M326.8 148.2h.2v1.1h.6v.1h-.8z" fill-rule="evenodd"/>
<path d="M326.4 146.2l.6-.2 .3 .3-.2 .1a.44 .44 0 0 0-.6-.1 .44 .44 0 0 0-.1 .6l.4 .3 .2-.1 .2-.2h.1a.62 .62 0 0 1-.9 .3 .62 .62 0 0 1 0-1z" fill-rule="evenodd"/>
<path d="M326.8 141.8h.2l.5 1.2h-.2l-.1-.3h-.6l-.1 .3h-.2l.2-.5h.6l-.2-.6-.2 .6h-.2z" fill-rule="evenodd"/>
<path d="M327.6 150.3h.2l.7 1v-1h.1v1.3h-.1l-.7-1v1h-.2z" fill-rule="evenodd"/>
<path d="M327.2 154.7a.63 .63 0 0 1 1 .1 .63 .63 0 0 1-.4 1 .63 .63 0 0 1-.8-.6h.2a.48 .48 0 0 0 .7 .4 .48 .48 0 0 0 0-.8l-.5-.1-.2 .2v.3h-.2z" fill-rule="evenodd"/>
<path d="M327.8 148.2h.9v.1h-.7v.4h.7v.2h-.7v.4h.8v.1h-1z" fill-rule="evenodd"/>
<path d="M327.6 141.8l.8 .1 .1 .2-.1 .3 .2 .3a.39 .39 0 0 1-.5 .3h-.5v-.1l.8-.1-.1-.3h-.5v.4h-.2v-.6h.5a.2 .2 0 0 0 .3-.1 .2 .2 0 0 0-.2-.3h-.4v.4h-.2z" fill-rule="evenodd"/>
<path d="M327.6 143.9h.6a.35 .35 0 0 1 .5 .3 .35 .35 0 0 1-.4 .4l.5 .6h-.2l-.4-.5-.2-.1h-.2v.6h-.2v-.7l.8-.1 .1-.2-.1-.1-.6-.1v.5h-.2z" fill-rule="evenodd"/>
<path d="M328.4 154.6h.3l.3 1.1 .4-1.1h.2v1.2h-.1v-1l-.4 1h-.1l-.4-1v1h-.2z" fill-rule="evenodd"/>
<path d="M328.2 146.2a.63 .63 0 0 1 .9 .1 .63 .63 0 0 1-.3 .9 .63 .63 0 0 1-.8-.5h.2a.48 .48 0 0 0 .7 .4 .48 .48 0 0 0-.1-.9h-.4l-.2 .5h-.2z" fill-rule="evenodd"/>
<path d="M328.8 141.8h.2v1.2h-.2z" fill-rule="evenodd"/>
<path d="M328.9 143.9h.9v.2h-.7v.3h.7v.2h-.7v.4h.8v.2h-1z" fill-rule="evenodd"/>
<path d="M329 148.2h.2l.6 1v-1h.2v1.2h-.2l-.7-1v1h-.1z" fill-rule="evenodd"/>
<path d="M329.3 141.8h.2v1.1h.6v.1h-.8z" fill-rule="evenodd"/>
<path d="M329.4 150.3h.9v.2h-.7v.3h.6v.2h-.6v.6h-.2z" fill-rule="evenodd"/>
<path d="M329.9 154.6h.9v.1h-.7v.4h.7v.2h-.7v.4h.8v.1h-1z" fill-rule="evenodd"/>
<path d="M329.4 146h.6a.35 .35 0 0 1 .4 .3 .35 .35 0 0 1-.3 .4l.4 .6h-.2l-.3-.5-.2-.1h-.2v.6h-.2v-.7l.8-.1a.21 .21 0 0 0 0-.2 .21 .21 0 0 0-.2-.1h-.4v.4h-.2z" fill-rule="evenodd"/>
<path d="M330.3 141.8h.2v1.2h-.2z" fill-rule="evenodd"/>
<path d="M330.2 148.2h1v.1h-.4v1.1h-.2v-1.1h-.4z" fill-rule="evenodd"/>
<path d="M330.2 144.1a.65 .65 0 0 1 .9 0 .65 .65 0 0 1 0 .9l.2 .2-.1 .1-.2-.2h-.7l-.2-.4-.1-.2h.2a.44 .44 0 0 0 .6 .5l-.1-.1v-.1a.3 .3 0 0 0 .4 0 .3 .3 0 0 0 0-.4 .43 .43 0 0 0-.5-.4 .43 .43 0 0 0-.4 .5h-.2z" fill-rule="evenodd"/>
<path d="M330.7 141.8h1v.1h-.4v1.1h-.2v-1.1h-.4z" fill-rule="evenodd"/>
<path d="M330.5 150.3h.6a.35 .35 0 0 1 .4 .3 .35 .35 0 0 1-.3 .4l.4 .6h-.2l-.3-.5-.2-.1h-.2v.6h-.2v-.7l.8-.1a.21 .21 0 0 0 0-.3 .21 .21 0 0 0-.2-.1h-.4v.5h-.2z" fill-rule="evenodd"/>
<path d="M331.2 146h.9v.2h-.7v.4h.7v.1h-.7v.5h.7v.1h-.9z" fill-rule="evenodd"/>
<path d="M331 154.6h1v.1h-.4v1.1h-.2v-1.1h-.4z" fill-rule="evenodd"/>
<path d="M331.8 150.3h.9v.2h-.7v.3h.7v.2h-.7v.4h.7v.2h-.9z" fill-rule="evenodd"/>
<path d="M331.8 148.2h.3l.3 1.1 .4-1.1h.2v1.2h-.1v-1l-.4 1h-.2l-.3-1v1h-.2z" fill-rule="evenodd"/>
<path d="M331.8 141.8h.2l.3 .6 .4-.6h.2l-.5 .7v.5h-.2v-.5z" fill-rule="evenodd"/>
<path d="M331.5 143.9h.2v.7a.34 .34 0 0 0 .3 .4 .34 .34 0 0 0 .3-.4v-.7h.2v.7a.5 .5 0 0 1-.5 .6 .5 .5 0 0 1-.5-.6z" fill-rule="evenodd"/>
<path d="M332.8 143.9h.2v1.3h-.2z" fill-rule="evenodd"/>
<path d="M332.2 154.6h.6a.35 .35 0 0 1 .4 .3 .35 .35 0 0 1-.3 .4l.4 .5h-.2a.62 .62 0 0 0-.7-.5v.5h-.2v-.7h.7l.1-.2-.1-.2h-.5v.4h-.2z" fill-rule="evenodd"/>
<path d="M333 150.3h.9v.2h-.8v.3h.7v.2h-.7v.4h.8v.2h-.9z" fill-rule="evenodd"/>
<path d="M332.5 146.2a.65 .65 0 0 1 .9 0 .65 .65 0 0 1-.1 1l.3 .1-.1 .1-.3-.1-.6-.1-.3-.4v-.1h.2a.44 .44 0 0 0 .6 .4h-.2l.1-.1a.3 .3 0 0 0 .4-.1 .3 .3 0 0 0-.1-.4 .43 .43 0 0 0-.5-.3 .43 .43 0 0 0-.3 .5h-.2z" fill-rule="evenodd"/>
<path d="M333.3 154.6h.2l.4 .6 .4-.6h.2l-.5 .7v.5h-.2v-.5z" fill-rule="evenodd"/>
<path d="M333.3 143.9h.5a.35 .35 0 0 1 .5 .3 .35 .35 0 0 1-.4 .4l.5 .6h-.2l-.4-.5-.2-.1h-.2v.6h-.1v-.7l.8-.1a.21 .21 0 0 0 0-.3 .21 .21 0 0 0-.3-.1h-.4v.5h-.1z" fill-rule="evenodd"/>
<path d="M333.5 141.8h.6a.35 .35 0 0 1 .4 .3 .35 .35 0 0 1-.3 .4l.5 .5h-.3l-.3-.5h-.2h-.2v.5h-.2v-.7h.7l.2-.2-.2-.2h-.5v.4h-.2z" fill-rule="evenodd"/>
<path d="M333.6 148.2h.2l.5 1.2h-.1l-.2-.3h-.5l-.2 .3h-.1l.2-.5h.6l-.3-.6-.2 .6h-.1z" fill-rule="evenodd"/>
<path d="M334.6 143.9h.9v.2h-.8v.3h.7v.2h-.7v.4h.8v.2h-.9z" fill-rule="evenodd"/>
<path d="M333.8 146h.1v.8a.34 .34 0 0 0 .4 .4 .34 .34 0 0 0 .3-.4v-.8h.2v.8a.5 .5 0 0 1-.5 .5 .5 .5 0 0 1-.5-.5z" fill-rule="evenodd"/>
<path d="M334.3 148.2h1v.1h-.4v1.1h-.2v-1.1h-.4z" fill-rule="evenodd"/>
<path d="M335.1 146h.1v1.3h-.1z" fill-rule="evenodd"/>
<path d="M335.1 154.6h.2l.4 1.1 .4-1.1h.2v1.2h-.2v-1l-.3 1h-.2l-.4-1v1h-.1z" fill-rule="evenodd"/>
<path d="M335.4 148.2h1v.1h-.8v.4h.7v.2h-.7v.4h.8v.1h-1z" fill-rule="evenodd"/>
<path d="M334.9 150.3h.2l.5 1.3h-.1l-.2-.4h-.5l-.2 .4h-.1l.2-.5h.6l-.3-.7-.2 .7h-.1z" fill-rule="evenodd"/>
<path d="M335.7 143.9h.3l.3 1.1 .4-1.1h.2v1.3h-.1v-1.1l-.4 1.1h-.1l-.4-1.1v1.1h-.2z" fill-rule="evenodd"/>
<path d="M335.7 150.3h.2l.7 1v-1h.1v1.3h-.1l-.7-1v1h-.2z" fill-rule="evenodd"/>
<path d="M335.2 141.8h.1l.6 1.2h-.2l-.2-.3h-.5l-.1 .3h-.2l.2-.5h.6l-.3-.6-.2 .6h-.1z" fill-rule="evenodd"/>
<path d="M335.4 146h.2l.4 1.2 .4-1.2h.2l-.5 1.3h-.2z" fill-rule="evenodd"/>
<path d="M335.8 141.8h1v.1h-.4v1.1h-.1v-1.1h-.5z" fill-rule="evenodd"/>
<path d="M336.6 154.6h.2v1.2h-.2z" fill-rule="evenodd"/>
<path d="M337 141.8h.1v1.2h-.1z" fill-rule="evenodd"/>
<path d="M337.1 154.6h.1l.7 1v-1h.2v1.2h-.2l-.7-1v1h-.1z" fill-rule="evenodd"/>
<path d="M337.2 143.9h.9v.2h-.7v.3h.7v.2h-.7v.4h.8v.2h-1z" fill-rule="evenodd"/>
<path d="M336.6 148.2h.6a.35 .35 0 0 1 .4 .3 .35 .35 0 0 1-.3 .4l.4 .5h-.2a.62 .62 0 0 0-.7-.5v.5h-.2v-.7h.7l.2-.2-.2-.2h-.5v.4h-.2z" fill-rule="evenodd"/>
<path d="M337.4 141.8h.2l.7 1v-1h.1v1.2h-.1l-.7-1v1h-.2z" fill-rule="evenodd"/>
<path d="M337 150.3h.5a.64 .64 0 0 1 .6 .6 .64 .64 0 0 1-.6 .7h-.5v-.2h.5a.49 .49 0 0 0 .4-.5 .49 .49 0 0 0-.4-.4h-.3v.9h-.2z" fill-rule="evenodd"/>
<path d="M337 146h.2l.5 1.3h-.2l-.1-.4h-.6l-.1 .4h-.2l.2-.5h.6l-.2-.6-.2 .6h-.2z" fill-rule="evenodd"/>
<path d="M337.8 146h.1v1.2h.7v.1h-.8z" fill-rule="evenodd"/>
<path d="M337.9 148.2h.2v1.2h-.2z" fill-rule="evenodd"/>
<path d="M338.4 154.6h.1v1.2h-.1z" fill-rule="evenodd"/>
<path d="M338.4 143.9h.2l.6 1v-1h.2v1.3h-.2l-.6-1v1h-.2z" fill-rule="evenodd"/>
<path d="M338.8 146h.9v.2h-.8v.4h.7v.1h-.7v.5h.8v.1h-.9z" fill-rule="evenodd"/>
<path d="M338.8 154.6h.3l.3 1.1 .4-1.1h.2v1.2h-.1v-1l-.4 1h-.1l-.4-1v1h-.2z" fill-rule="evenodd"/>
<path d="M338.6 158.9a.34 .34 0 0 1 .5 0 .34 .34 0 0 1 0 .5 .4 .4 0 0 1-.1 .7 .4 .4 0 0 1-.5-.4h.1a.26 .26 0 0 0 .4 .3 .26 .26 0 0 0 0-.5 .26 .26 0 0 0-.4 .2h-.1l.2-.3-.2-.2h.2a.21 .21 0 0 0 .3 .1 .21 .21 0 0 0 0-.3 .21 .21 0 0 0-.3 .1l-.2 .1z" fill-rule="evenodd"/>
<path d="M338.9 141.9l.6-.1 .3 .2v.1l-.1 .1a.49 .49 0 0 0-.7-.1 .49 .49 0 0 0 0 .7 .49 .49 0 0 0 .7 0v-.3h-.4v-.1h.6v.5a.69 .69 0 0 1-1 0 .69 .69 0 0 1 0-1z" fill-rule="evenodd"/>
<path d="M338.7 148.2h.2l.5 1.2h-.1l-.2-.3h-.5l-.2 .3h-.1l.2-.5h.6l-.3-.6-.2 .6h-.1z" fill-rule="evenodd"/>
<path d="M339.6 148.2h.1v1.1h.7v.1h-.8z" fill-rule="evenodd"/>
<path d="M339.1 150.3h.2l.5 1.3h-.2l-.1-.4h-.6l-.1 .4h-.2l.2-.5h.6l-.2-.7-.2 .7h-.2z" fill-rule="evenodd"/>
<path d="M339.6 159l.3-.2a.71 .71 0 0 1 .4 .7 .71 .71 0 0 1-.4 .6 .51 .51 0 0 1-.5-.6h.2a.32 .32 0 0 0 0 .4 .32 .32 0 0 0 .5 0 .32 .32 0 0 0 0-.4 .32 .32 0 0 0 0-.5 .32 .32 0 0 0-.5 0 .32 .32 0 0 0 0 .5h-.2z" fill-rule="evenodd"/>
<path d="M339.9 146h.2l.7 1v-1h.1v1.3h-.1l-.7-1v1h-.2z" fill-rule="evenodd"/>
<path d="M339.6 143.9h1v.2h-.4v1.1h-.2v-1.1h-.4z" fill-rule="evenodd"/>
<path d="M339.9 150.3h.5a.39 .39 0 0 1 .5 .4 .39 .39 0 0 1-.5 .4h-.4v.5h-.1v-.7h.6l.2-.2-.2-.2h-.5v.4h-.1z" fill-rule="evenodd"/>
<path d="M340.5 159.9h.2v.2h-.2z" fill-rule="evenodd"/>
<path d="M340.6 141.8h.3l.3 1.1 .4-1.1h.2v1.2h-.1v-1l-.4 1h-.2l-.3-1v1h-.2z" fill-rule="evenodd"/>
<path d="M340.9 144l.6-.1 .2 .3-.2 .1a.27 .27 0 0 0-.3-.3 .27 .27 0 0 0-.2 .4h.2a.43 .43 0 0 1 .5 .6 .43 .43 0 0 1-.7 .1l-.3-.3h.2a.31 .31 0 0 0 .3 .3 .31 .31 0 0 0 .3-.4l-.7-.3z" fill-rule="evenodd"/>
<path d="M341.1 148.3l.6-.1 .2 .3h-.1a.27 .27 0 0 0-.4-.3 .27 .27 0 0 0-.2 .4l.3 .1a.43 .43 0 0 1 .4 .6 .43 .43 0 0 1-.7 .1l-.2-.3 .1-.1a.31 .31 0 0 0 .3 .3 .31 .31 0 0 0 .3-.3l-.6-.3z" fill-rule="evenodd"/>
<path d="M340.3 154.6h.2v.7a.34 .34 0 0 0 .3 .4 .34 .34 0 0 0 .4-.4v-.7h.1v.7a.5 .5 0 0 1-.5 .6 .5 .5 0 0 1-.5-.6z" fill-rule="evenodd"/>
<path d="M341.1 159l.2-.2a.71 .71 0 0 1 .5 .7 .71 .71 0 0 1-.5 .6 .51 .51 0 0 1-.4-.6h.2a.32 .32 0 0 0 0 .4 .32 .32 0 0 0 .5 0 .32 .32 0 0 0 0-.4 .32 .32 0 0 0 0-.5 .32 .32 0 0 0-.5 0 .32 .32 0 0 0 0 .5h-.2z" fill-rule="evenodd"/>
<path d="M341.1 146h1v.2h-.4v1.1h-.1v-1.1h-.5z" fill-rule="evenodd"/>
<path d="M341.6 154.6h.2l.4 1.1 .4-1.1h.2v1.2h-.2v-1l-.3 1h-.2l-.3-1v1h-.2z" fill-rule="evenodd"/>
<path d="M341.1 150.3h.4a.39 .39 0 0 1 .5 .4 .39 .39 0 0 1-.4 .4h-.4v.5h-.1v-.7h.6l.2-.2-.2-.2h-.5v.4h-.1z" fill-rule="evenodd"/>
<path d="M342 145h.2v.2h-.2z" fill-rule="evenodd"/>
<path d="M342.2 148.2h.2v.5h.6v-.5h.2v1.2h-.2v-.6h-.6v.6h-.2z" fill-rule="evenodd"/>
<path d="M342.2 147.1h.2v.2h-.2z" fill-rule="evenodd"/>
<path d="M342 159l.2-.2a.66 .66 0 0 1 .6 .7 .66 .66 0 0 1-.6 .6l-.3-.3v-.3h.2a.32 .32 0 0 0 0 .4 .32 .32 0 0 0 .4 0 .32 .32 0 0 0 .1-.4 .32 .32 0 0 0-.1-.5 .32 .32 0 0 0-.4 0 .32 .32 0 0 0 0 .5h-.2z" fill-rule="evenodd"/>
<path d="M342.1 141.8h.2v.7a.34 .34 0 0 0 .3 .4 .34 .34 0 0 0 .3-.4v-.7h.2v.7a.5 .5 0 0 1-.5 .6 .5 .5 0 0 1-.5-.6z" fill-rule="evenodd"/>
<path d="M342.3 150.3h.5a.35 .35 0 0 1 .5 .3 .35 .35 0 0 1-.4 .4l.5 .6h-.2l-.4-.5-.2-.1h-.2v.6h-.1v-.7l.7-.1 .1-.2-.1-.1-.6-.1v.5h-.1z" fill-rule="evenodd"/>
<path d="M343.5 141.9l.6-.1 .2 .3h-.2a.27 .27 0 0 0-.3-.3 .27 .27 0 0 0-.2 .4l.2 .1a.43 .43 0 0 1 .5 .6 .43 .43 0 0 1-.7 .1l-.3-.3 .2-.1a.31 .31 0 0 0 .3 .3 .31 .31 0 0 0 .3-.3l-.7-.3z" fill-rule="evenodd"/>
<path d="M343.1 158.9l.2-.1a.71 .71 0 0 1 .4 .7 .71 .71 0 0 1-.4 .6 .51 .51 0 0 1-.4-.6h.2a.32 .32 0 0 0 0 .4 .32 .32 0 0 0 .4 0 .32 .32 0 0 0 .1-.4 .3 .3 0 0 0-.1-.5 .3 .3 0 0 0-.4 .1v.4h-.2z" fill-rule="evenodd"/>
<path d="M343.6 154.6h.8v.1h-.6v.4h.5v.2h-.5v.5h-.2z" fill-rule="evenodd"/>
<path d="M343.7 150.5a.63 .63 0 0 1 .9 .1 .63 .63 0 0 1-.3 .9 .63 .63 0 0 1-.8-.5h.2a.48 .48 0 0 0 .7 .3 .48 .48 0 0 0-.1-.8h-.4l-.2 .5h-.2z" fill-rule="evenodd"/>
<path d="M344.6 159.1l.2 .3 .3-.3 .1 .1-.3 .3 .3 .3-.1 .1-.3-.3-.2 .3-.2-.1 .3-.3-.2-.3z" fill-rule="evenodd"/>
<path d="M343.8 148.2h.2l.5 1.2h-.2l-.1-.3h-.6l-.1 .3h-.2l.2-.5h.6l-.2-.6-.2 .6h-.2z" fill-rule="evenodd"/>
<path d="M344.6 148.2h.2v1.1h.6v.1h-.8z" fill-rule="evenodd"/>
<path d="M344.7 154.6h.9v.1h-.8v.4h.7v.2h-.7v.4h.8v.1h-.9z" fill-rule="evenodd"/>
<path d="M344.5 141.8h1v.1h-.5v1.1h-.1v-1.1h-.4z" fill-rule="evenodd"/>
<path d="M344.8 150.3h.2l.4 1.1 .4-1.1h.1l-.4 1.3h-.2z" fill-rule="evenodd"/>
<path d="M345.6 148.2h.2v1.1h.6v.1h-.8z" fill-rule="evenodd"/>
<path d="M346.1 141.8h.2l.4 1.1 .4-1.1h.2v1.2h-.2v-1l-.3 1h-.2l-.3-1v1h-.2z" fill-rule="evenodd"/>
<path d="M346.1 150.3h.9v.2h-.7v.3h.7v.2h-.7v.4h.8v.2h-1z" fill-rule="evenodd"/>
<path d="M346.4 158.8h.2v.9h.1v.1h-.1v.3h-.2v-.3h-.5v-.1h.5v-.6l-.4 .6h-.1z" fill-rule="evenodd"/>
<path d="M346.2 154.6h.2l.5 1.2h-.2l-.1-.3h-.6l-.1 .3h-.2l.2-.5h.6l-.2-.6-.2 .6h-.2z" fill-rule="evenodd"/>
<path d="M346.9 154.6h1v.1h-.4v1.1h-.2v-1.1h-.4z" fill-rule="evenodd"/>
<path d="M347.1 158.9a.34 .34 0 0 1 .5 0 .34 .34 0 0 1-.1 .5 .4 .4 0 0 1 0 .7 .4 .4 0 0 1-.6-.4h.2a.26 .26 0 0 0 .3 .3 .26 .26 0 0 0 .1-.5 .26 .26 0 0 0-.4 .2h-.2l.2-.3-.1-.2h.1a.21 .21 0 0 0 .3 .1 .21 .21 0 0 0 .1-.3 .21 .21 0 0 0-.4 .1l-.1 .1z" fill-rule="evenodd"/>
<path d="M347.6 141.8h.9v.1h-.7v.4h.7v.2h-.7v.4h.7v.1h-.9z" fill-rule="evenodd"/>
<path d="M347 148.2l.9 .1v.2l-.1 .3 .2 .3a.38 .38 0 0 1-.5 .3h-.5v-.1l.8-.1-.1-.3h-.5v.4h-.2v-.6h.5a.2 .2 0 0 0 .3-.1 .2 .2 0 0 0-.2-.3h-.4v.4h-.2z" fill-rule="evenodd"/>
<path d="M347.3 150.3h.4a.64 .64 0 0 1 .6 .6 .64 .64 0 0 1-.6 .7h-.4v-.2h.4a.49 .49 0 0 0 .5-.5 .49 .49 0 0 0-.5-.4h-.2v.9h-.2z" fill-rule="evenodd"/>
<path d="M348 159.9h.2v.2h-.2z" fill-rule="evenodd"/>
<path d="M348.2 148.2h1v.1h-.8v.4h.7v.2h-.7v.4h.8v.1h-1z" fill-rule="evenodd"/>
<path d="M348.8 141.8h.9v.1h-.8v.4h.7v.2h-.7v.4h.8v.1h-.9z" fill-rule="evenodd"/>
<path d="M348 154.6h.2v.7a.34 .34 0 0 0 .3 .4 .34 .34 0 0 0 .3-.4v-.7h.2v.7a.5 .5 0 0 1-.5 .6 .5 .5 0 0 1-.5-.6z" fill-rule="evenodd"/>
<path d="M348.6 158.9l.2-.1a.71 .71 0 0 1 .4 .7 .71 .71 0 0 1-.4 .6 .51 .51 0 0 1-.4-.6h.1a.32 .32 0 0 0 .1 .4 .32 .32 0 0 0 .4 0 .32 .32 0 0 0 .1-.4 .3 .3 0 0 0-.1-.5 .3 .3 0 0 0-.4 .1l-.1 .4h-.1z" fill-rule="evenodd"/>
<path d="M349.1 150.3l.7 .1 .2 .2-.2 .3 .2 .2a.38 .38 0 0 1-.5 .5h-.4v-.2l.7-.1-.1-.3h-.5v.4h-.1v-.6h.4a.2 .2 0 0 0 .3-.1 .2 .2 0 0 0-.2-.2h-.4v.3h-.1z" fill-rule="evenodd"/>
<path d="M349.5 159l.3-.2a.71 .71 0 0 1 .4 .7 .71 .71 0 0 1-.4 .6 .51 .51 0 0 1-.4-.6h.1a.32 .32 0 0 0 .1 .4 .32 .32 0 0 0 .4 0 .32 .32 0 0 0 0-.4 .32 .32 0 0 0 0-.5 .32 .32 0 0 0-.4 0 .32 .32 0 0 0-.1 .5h-.1z" fill-rule="evenodd"/>
<path d="M349.3 154.6h.5a.35 .35 0 0 1 .5 .3 .35 .35 0 0 1-.4 .4l.5 .5h-.2a.62 .62 0 0 0-.8-.5v.5h-.1v-.7h.7l.1-.2-.2-.2h-.5v.4h-.1z" fill-rule="evenodd"/>
<path d="M349.9 141.8h1v.1h-.5v1.1h-.1v-1.1h-.4z" fill-rule="evenodd"/>
<path d="M350.6 154.6h.9v.1h-.8v.4h.7v.2h-.7v.4h.8v.1h-.9z" fill-rule="evenodd"/>
<path d="M349.9 148.2h.6a.35 .35 0 0 1 .4 .3 .35 .35 0 0 1-.3 .4l.4 .5h-.2a.62 .62 0 0 0-.7-.5v.5h-.2v-.7h.7l.2-.2-.2-.2h-.5v.4h-.2z" fill-rule="evenodd"/>
<path d="M350.1 150.3h.2l.4 .6 .4-.6h.2l-.5 .7v.6h-.2v-.6z" fill-rule="evenodd"/>
<path d="M350.5 159l.2-.2a.66 .66 0 0 1 .5 .7 .66 .66 0 0 1-.5 .6l-.3-.3v-.3h.1a.32 .32 0 0 0 .1 .4 .32 .32 0 0 0 .4 0 .32 .32 0 0 0 0-.4 .32 .32 0 0 0 0-.5 .32 .32 0 0 0-.4 0 .32 .32 0 0 0-.1 .5h-.1z" fill-rule="evenodd"/>
<path d="M351.3 148.6a.46 .46 0 0 1 .7 .1 .46 .46 0 0 1-.3 .7 .46 .46 0 0 1-.6-.4h.2a.31 .31 0 0 0 .4 .3 .31 .31 0 0 0 .1-.5l-.3-.2-.2 .4h-.2z" fill-rule="evenodd"/>
<path d="M351.9 150.3h.9l-.8 1.1h.8v.2h-1l.8-1.1h-.7z" fill-rule="evenodd"/>
<path d="M351.6 141.9a.63 .63 0 0 1 1 .1 .63 .63 0 0 1-.3 1 .63 .63 0 0 1-.9-.6h.2a.48 .48 0 0 0 .8 .4 .48 .48 0 0 0-.1-.8h-.5l-.2 .4h-.2z" fill-rule="evenodd"/>
<path d="M352.3 154.7l.6-.1 .2 .3h-.1a.27 .27 0 0 0-.3-.3 .27 .27 0 0 0-.2 .4l.2 .1a.43 .43 0 0 1 .4 .6 .43 .43 0 0 1-.7 .1l-.2-.3 .1-.1a.31 .31 0 0 0 .4 .3 .31 .31 0 0 0 .2-.3l-.6-.3z" fill-rule="evenodd"/>
<path d="M352.2 148.2h.2v.5h.6v-.5h.2v1.2h-.2v-.6h-.6v.6h-.2z" fill-rule="evenodd"/>
<path d="M353.1 150.4l.6-.1 .2 .3-.2 .1a.27 .27 0 0 0-.3-.3 .27 .27 0 0 0-.2 .4h.2a.43 .43 0 0 1 .5 .6 .43 .43 0 0 1-.7 .1l-.3-.2 .2-.1a.31 .31 0 0 0 .3 .3 .31 .31 0 0 0 .3-.4l-.7-.3z" fill-rule="evenodd"/>
<path d="M353.6 148.3l.6-.1 .2 .3h-.2a.27 .27 0 0 0-.3-.3 .27 .27 0 0 0-.2 .4l.2 .1a.43 .43 0 0 1 .5 .6 .43 .43 0 0 1-.7 .1l-.3-.3 .2-.1a.31 .31 0 0 0 .3 .3 .31 .31 0 0 0 .3-.3l-.7-.3z" fill-rule="evenodd"/>
<path d="M353.4 154.6h.2v1.2h-.2z" fill-rule="evenodd"/>
<path d="M352.9 141.8h.5a.35 .35 0 0 1 .5 .3 .35 .35 0 0 1-.4 .4l.5 .5h-.2l-.3-.5h-.3h-.2v.5h-.1v-.7l.8-.1a.21 .21 0 0 0 0-.2 .21 .21 0 0 0-.2-.1h-.5v.4h-.1z" fill-rule="evenodd"/>
<path d="M353.9 154.6h.9l-.8 1.1h.8v.1h-1l.8-1.1h-.7z" fill-rule="evenodd"/>
<path d="M354 150.3h.2l.3 1.1 .3-1.1h.2l.3 1.1 .2-1.1h.2l-.4 1.3h-.1l-.3-1.1-.3 1.1h-.2z" fill-rule="evenodd"/>
<path d="M354.7 141.8h.9v.1h-.8v.4h.7v.2h-.7v.4h.8v.1h-.9z" fill-rule="evenodd"/>
<path d="M355 154.6h.9v.1h-.7v.4h.7v.2h-.7v.4h.7v.1h-.9z" fill-rule="evenodd"/>
<path d="M355.8 141.8h.2l.3 .5 .4-.5h.1l-.4 .6 .5 .6h-.2l-.4-.5-.4 .5h-.2l.5-.6z" fill-rule="evenodd"/>
<path d="M355.3 148.3l.6-.1 .3 .2-.2 .2a.45 .45 0 0 0-.6-.2 .45 .45 0 0 0-.1 .7l.4 .2 .2-.1 .2-.2h.1a.62 .62 0 0 1-.9 .3 .62 .62 0 0 1 0-1z" fill-rule="evenodd"/>
<path d="M356.3 154.7l.6-.1 .2 .3h-.2a.27 .27 0 0 0-.3-.3 .27 .27 0 0 0-.2 .4l.2 .1a.43 .43 0 0 1 .5 .6 .43 .43 0 0 1-.7 .1l-.3-.3 .2-.1a.31 .31 0 0 0 .3 .3 .31 .31 0 0 0 .3-.3l-.7-.3z" fill-rule="evenodd"/>
<path d="M356.2 150.3h.1l.6 1.3h-.2l-.2-.4h-.5l-.2 .4h-.1l.2-.5h.6l-.3-.7-.2 .7h-.1z" fill-rule="evenodd"/>
<path d="M356.6 148.3a.63 .63 0 0 1 .9 .1 .63 .63 0 0 1-.3 1 .63 .63 0 0 1-.8-.6h.2a.48 .48 0 0 0 .7 .4 .48 .48 0 0 0 0-.8l-.5-.1-.2 .2v.3h-.2z" fill-rule="evenodd"/>
<path d="M356.8 150.3h1v.2h-.4v1.1h-.2v-1.1h-.4z" fill-rule="evenodd"/>
<path d="M357.4 154.9h.2v.2h-.2z" fill-rule="evenodd"/>
<path d="M357.4 155.7h.2v.1h-.2z" fill-rule="evenodd"/>
<path d="M357.8 148.2h.3l.3 1.1 .4-1.1h.2v1.2h-.1v-1l-.4 1h-.2l-.3-1v1h-.2z" fill-rule="evenodd"/>
<path d="M357.1 141.9l.7-.1 .2 .2-.1 .2a.45 .45 0 0 0-.6-.2 .45 .45 0 0 0-.1 .7l.4 .2 .2-.1 .1-.2h.2a.62 .62 0 0 1-1 .3 .62 .62 0 0 1 0-1z" fill-rule="evenodd"/>
<path d="M358.3 141.8h.9v.1h-.7v.4h.7v.2h-.7v.4h.8v.1h-1z" fill-rule="evenodd"/>
<path d="M358 150.5l.6-.2 .3 .3-.1 .1a.45 .45 0 0 0-.7-.2 .45 .45 0 0 0 0 .7l.3 .3 .3-.1 .1-.3 .2 .1a.62 .62 0 0 1-1 .3 .62 .62 0 0 1 0-1z" fill-rule="evenodd"/>
<path d="M359.2 150.3h.2v.5h.6v-.5h.2v1.3h-.2v-.6h-.6v.6h-.2z" fill-rule="evenodd"/>
<path d="M359.5 141.8h.9v.1h-.7v.4h.7v.2h-.7v.4h.7v.1h-.9z" fill-rule="evenodd"/>
<path d="M359.3 148.2h.5a.39 .39 0 0 1 .5 .3 .39 .39 0 0 1-.5 .4h-.3v.5h-.2v-.6h.6l.2-.3-.2-.2h-.4v.5h-.2z" fill-rule="evenodd"/>
<path d="M360.5 148.2h.1v1.1h.7v.1h-.8z" fill-rule="evenodd"/>
<path d="M360.5 151.4h.2v.2h-.2z" fill-rule="evenodd"/>
<path d="M360.7 141.8h.4a.64 .64 0 0 1 .6 .6 .64 .64 0 0 1-.6 .6h-.4v-.1h.4a.49 .49 0 0 0 .5-.5 .49 .49 0 0 0-.5-.5h-.3v1h-.1z" fill-rule="evenodd"/>
<path d="M361.5 148.2h.2v1.2h-.2z" fill-rule="evenodd"/>
<path d="M362.3 148.2h.2l.5 1.2h-.2l-.1-.3h-.6l-.1 .3h-.2l.2-.5h.6l-.2-.6-.2 .6h-.2z" fill-rule="evenodd"/>
<path d="M363.1 148.2h.2l.7 1v-1h.1v1.2h-.1l-.7-1v1h-.2z" fill-rule="evenodd"/>
<path d="M364.3 148.2h1v.1h-.4v1.1h-.1v-1.1h-.5z" fill-rule="evenodd"/>
<path d="M365.4 149.3a.22 .22 0 0 1 .2 .2 .22 .22 0 0 1-.1 .2z" fill-rule="evenodd"/>
<path d="M317.2 167.4h.2l.4 1.1 .4-1.1h.2v1.2h-.2v-1l-.3 1h-.2l-.4-1v1h-.1z" fill-rule="evenodd"/>
<path d="M317.2 169.5h.2l.4 1.1 .4-1.1h.2v1.3h-.2v-1.1l-.3 1.1h-.2l-.4-1.1v1.1h-.1z" fill-rule="evenodd"/>
<path d="M317.2 178h.2v.6h.6v-.6h.2v1.3h-.2v-.6h-.6v.6h-.2z" fill-rule="evenodd"/>
<path d="M317.1 163.1h1v.2h-.4v1.1h-.2v-1.1h-.4z" fill-rule="evenodd"/>
<path d="M317.1 165.2h1v.2h-.4v1.1h-.2v-1.1h-.4z" fill-rule="evenodd"/>
<path d="M317.2 161l.8 .1 .1 .3-.2 .2 .2 .3a.38 .38 0 0 1-.4 .3h-.5v-.1l.7-.1v-.3h-.6v.4h-.1v-.6h.4a.2 .2 0 0 0 .3-.1 .2 .2 0 0 0-.2-.3h-.4v.4h-.1z" fill-rule="evenodd"/>
<path d="M317.3 173.9l.6-.1 .3 .2-.1 .2a.45 .45 0 0 0-.7-.2 .45 .45 0 0 0 0 .7l.3 .2 .3-.1 .1-.2h.2a.62 .62 0 0 1-1 .3 .62 .62 0 0 1 0-1z" fill-rule="evenodd"/>
<path d="M317.3 176.1l.6-.2 .3 .3-.1 .1a.45 .45 0 0 0-.7-.2 .45 .45 0 0 0 0 .7l.3 .3 .3-.1 .1-.3 .2 .1a.62 .62 0 0 1-1 .3 .62 .62 0 0 1 0-1z" fill-rule="evenodd"/>
<path d="M317.5 171.6h.2l.5 1.3h-.2l-.1-.4h-.5l-.2 .4h-.2l.2-.5h.6l-.2-.6-.2 .6h-.2z" fill-rule="evenodd"/>
<path d="M318.4 171.6h.1l.7 1v-1h.2v1.3h-.2l-.7-1v1h-.1z" fill-rule="evenodd"/>
<path d="M318.7 167.4h.2v1.2h-.2z" fill-rule="evenodd"/>
<path d="M318.7 169.5h.2v1.3h-.2z" fill-rule="evenodd"/>
<path d="M318.3 163.1h.5a.35 .35 0 0 1 .5 .3 .35 .35 0 0 1-.4 .4l.5 .6h-.2a.62 .62 0 0 0-.8-.6v.6h-.1v-.7l.7-.1 .1-.2-.2-.1-.5-.1v.5h-.1z" fill-rule="evenodd"/>
<path d="M318.3 165.2h.5a.35 .35 0 0 1 .5 .3 .35 .35 0 0 1-.4 .4l.5 .6h-.2l-.4-.5-.2-.1h-.2v.6h-.1v-.7h.7l.1-.2-.1-.2h-.6v.4h-.1z" fill-rule="evenodd"/>
<path d="M318.5 161.1a.63 .63 0 0 1 1 .1 .63 .63 0 0 1-.4 1 .63 .63 0 0 1-.8-.6h.2a.48 .48 0 0 0 .7 .4 .48 .48 0 0 0 0-.8h-.5l-.2 .4h-.2z" fill-rule="evenodd"/>
<path d="M318.6 173.9a.63 .63 0 0 1 1 .1 .63 .63 0 0 1-.4 1 .63 .63 0 0 1-.8-.6h.2a.48 .48 0 0 0 .7 .4 .48 .48 0 0 0 0-.8h-.5l-.2 .4h-.2z" fill-rule="evenodd"/>
<path d="M318.6 176.1a.63 .63 0 0 1 1 .1 .63 .63 0 0 1-.4 .9 .63 .63 0 0 1-.8-.5h.2a.48 .48 0 0 0 .7 .3 .48 .48 0 0 0 0-.8h-.5l-.2 .5h-.2z" fill-rule="evenodd"/>
<path d="M318.6 178.2a.63 .63 0 0 1 1 .1 .63 .63 0 0 1-.4 .9 .63 .63 0 0 1-.8-.5h.2a.48 .48 0 0 0 .7 .4 .48 .48 0 0 0 0-.9h-.5l-.2 .5h-.2z" fill-rule="evenodd"/>
<path d="M319.2 167.4h.1l.7 1v-1h.2v1.2h-.2l-.7-1v1h-.1z" fill-rule="evenodd"/>
<path d="M319.2 169.5h.1l.7 1v-1h.2v1.3h-.2l-.7-1v1h-.1z" fill-rule="evenodd"/>
<path d="M319.7 171.6h.1l.7 1v-1h.2v1.3h-.2l-.7-1v1h-.1z" fill-rule="evenodd"/>
<path d="M319.8 178h.2v1.2h.6v.1h-.8z" fill-rule="evenodd"/>
<path d="M319.8 173.8h.5a.39 .39 0 0 1 .5 .3 .39 .39 0 0 1-.5 .4h-.3v.5h-.2v-.6h.7l.1-.3-.1-.2h-.5v.5h-.2z" fill-rule="evenodd"/>
<path d="M319.8 175.9h.5a.39 .39 0 0 1 .5 .4 .39 .39 0 0 1-.5 .4h-.3v.5h-.2v-.7h.7l.1-.2-.1-.2h-.5v.4h-.2z" fill-rule="evenodd"/>
<path d="M320.5 168.5h.1v.1h-.1z" fill-rule="evenodd"/>
<path d="M320.5 170.6h.1v.2h-.1z" fill-rule="evenodd"/>
<path d="M319.9 163.1h.2l.5 1.3h-.2l-.1-.4h-.6l-.1 .4h-.2l.2-.5h.6l-.2-.7-.2 .7h-.2z" fill-rule="evenodd"/>
<path d="M319.9 165.2h.2l.5 1.3h-.2l-.1-.4h-.6l-.1 .4h-.2l.2-.5h.6l-.2-.6-.2 .6h-.2z" fill-rule="evenodd"/>
<path d="M320.1 158.8h.2l.5 1.3h-.2l-.1-.4h-.6l-.1 .4h-.2l.2-.5h.6l-.2-.6-.2 .6h-.2z" fill-rule="evenodd"/>
<path d="M320.1 161h.2l.5 1.2h-.2l-.1-.3h-.6l-.1 .3h-.2l.2-.5h.6l-.2-.6-.2 .6h-.2z" fill-rule="evenodd"/>
<path d="M320.8 178h1v.2h-.8v.4h.7v.1h-.7v.5h.8v.1h-1z" fill-rule="evenodd"/>
<path d="M321.4 167.4h.2v.5h.7v-.5h.1v1.2h-.1v-.6h-.7v.6h-.2z" fill-rule="evenodd"/>
<path d="M321.4 169.5h.2v.5h.7v-.5h.1v1.3h-.1v-.6h-.7v.6h-.2z" fill-rule="evenodd"/>
<path d="M320.9 161h.6a.35 .35 0 0 1 .5 .3 .35 .35 0 0 1-.4 .4l.5 .5h-.3l-.3-.4-.2-.1h-.2v.5h-.2v-.7l.8-.1a.21 .21 0 0 0 0-.2 .21 .21 0 0 0-.2-.1h-.4v.4h-.2z" fill-rule="evenodd"/>
<path d="M321 173.8h.5a.39 .39 0 0 1 .5 .3 .39 .39 0 0 1-.5 .4h-.3v.5h-.2v-.6h.7l.1-.3-.1-.2h-.5v.5h-.2z" fill-rule="evenodd"/>
<path d="M321 175.9h.5a.39 .39 0 0 1 .5 .4 .39 .39 0 0 1-.5 .4h-.3v.5h-.2v-.7h.7l.1-.2-.1-.2h-.5v.4h-.2z" fill-rule="evenodd"/>
<path d="M320.9 163.3l.6-.2 .3 .3-.2 .1a.45 .45 0 0 0-.6-.2 .45 .45 0 0 0-.1 .7l.4 .3 .2-.1 .1-.3 .2 .1a.62 .62 0 0 1-.9 .3 .62 .62 0 0 1 0-1z" fill-rule="evenodd"/>
<path d="M320.9 165.4l.6-.2 .3 .3-.2 .1a.45 .45 0 0 0-.6-.1 .45 .45 0 0 0-.1 .6l.4 .3 .2-.1 .1-.2h.2a.62 .62 0 0 1-.9 .3 .62 .62 0 0 1 0-1z" fill-rule="evenodd"/>
<path d="M320.9 171.6h.2v.8a.34 .34 0 0 0 .3 .4 .34 .34 0 0 0 .4-.4v-.8h.1v.8a.5 .5 0 0 1-.5 .5 .5 .5 0 0 1-.5-.5z" fill-rule="evenodd"/>
<path d="M322 163.1h.9v.2h-.7v.3h.7v.2h-.7v.4h.8v.2h-1z" fill-rule="evenodd"/>
<path d="M322 165.2h.9v.2h-.7v.4h.7v.1h-.7v.5h.8v.1h-1z" fill-rule="evenodd"/>
<path d="M322.2 171.6h.2v1.2h.6v.1h-.8z" fill-rule="evenodd"/>
<path d="M322.2 173.8h.9v.1h-.7v.4h.7v.2h-.7v.4h.8v.1h-1z" fill-rule="evenodd"/>
<path d="M322.2 175.9h.9v.2h-.7v.3h.7v.2h-.7v.4h.8v.2h-1z" fill-rule="evenodd"/>
<path d="M322.2 161h.5a.64 .64 0 0 1 .6 .6 .64 .64 0 0 1-.6 .6h-.5v-.1h.5a.49 .49 0 0 0 .4-.5 .49 .49 0 0 0-.4-.5h-.3v1h-.2z" fill-rule="evenodd"/>
<path d="M322.4 178h1v.2h-.4v1.1h-.2v-1.1h-.4z" fill-rule="evenodd"/>
<path d="M322.8 167.5a.63 .63 0 0 1 1 .1 .63 .63 0 0 1-.3 1 .63 .63 0 0 1-.8-.6h.1a.48 .48 0 0 0 .8 .4 .48 .48 0 0 0-.1-.8h-.5l-.2 .4h-.1z" fill-rule="evenodd"/>
<path d="M322.8 169.7a.63 .63 0 0 1 1 .1 .63 .63 0 0 1-.3 .9 .63 .63 0 0 1-.8-.5h.1a.48 .48 0 0 0 .8 .4 .48 .48 0 0 0 0-.9h-.5l-.2 .2-.1 .3h-.1z" fill-rule="evenodd"/>
<path d="M323.6 163.1h.2l.2 1.1 .3-1.1h.2l.3 1.1 .3-1.1h.1l-.3 1.3h-.2l-.3-1.1-.3 1.1h-.2z" fill-rule="evenodd"/>
<path d="M323.6 165.2h1v.2h-.4v1.1h-.2v-1.1h-.4z" fill-rule="evenodd"/>
<path d="M323.4 173.8h.6a.35 .35 0 0 1 .4 .3 .35 .35 0 0 1-.3 .4l.4 .5h-.2l-.3-.4-.2-.1h-.2v.5h-.2v-.7l.8-.1a.21 .21 0 0 0 0-.2 .21 .21 0 0 0-.2-.1h-.4v.4h-.2z" fill-rule="evenodd"/>
<path d="M323.4 175.9h.6a.35 .35 0 0 1 .4 .3 .35 .35 0 0 1-.3 .4l.4 .6h-.2l-.3-.5-.2-.1h-.2v.6h-.2v-.7l.8-.1a.21 .21 0 0 0 0-.3 .21 .21 0 0 0-.2-.1h-.4v.5h-.2z" fill-rule="evenodd"/>
<path d="M324.1 167.4h.2v1.1h.6v.1h-.8z" fill-rule="evenodd"/>
<path d="M324.1 169.5h.2v1.1h.6v.2h-.8z" fill-rule="evenodd"/>
<path d="M323.7 178.2a.63 .63 0 0 1 1 .1 .63 .63 0 0 1-.4 .9 .63 .63 0 0 1-.8-.5h.2a.48 .48 0 0 0 .7 .4 .48 .48 0 0 0-.1-.9h-.4l-.2 .5h-.2z" fill-rule="evenodd"/>
<path d="M323.6 171.6h.1l.6 1.3h-.2l-.2-.4h-.5l-.2 .4h-.1l.2-.5h.6l-.3-.6-.2 .6h-.1z" fill-rule="evenodd"/>
<path d="M323.9 161h1v.1h-.4v1.1h-.2v-1.1h-.4z" fill-rule="evenodd"/>
<path d="M325.1 161h.1v.5h.7v-.5h.2v1.2h-.2v-.6h-.7v.6h-.1z" fill-rule="evenodd"/>
<path d="M324.4 171.6h.6a.35 .35 0 0 1 .4 .3 .35 .35 0 0 1-.3 .4l.4 .6h-.2l-.3-.5-.2-.1h-.2v.6h-.2v-.7l.8-.1a.21 .21 0 0 0 0-.2 .21 .21 0 0 0-.2-.1h-.4v.4h-.2z" fill-rule="evenodd"/>
<path d="M325.1 167.4h.9v.1h-.7v.4h.7v.2h-.7v.4h.7v.1h-.9z" fill-rule="evenodd"/>
<path d="M325.1 169.5h.9v.2h-.7v.3h.7v.2h-.7v.4h.7v.2h-.9z" fill-rule="evenodd"/>
<path d="M324.9 165.4a.63 .63 0 0 1 .9 .1 .63 .63 0 0 1-.3 .9 .63 .63 0 0 1-.8-.5h.2a.48 .48 0 0 0 .7 .4 .48 .48 0 0 0-.1-.9h-.4l-.2 .5h-.2z" fill-rule="evenodd"/>
<path d="M325.4 163.1h.2v1.3h-.2z" fill-rule="evenodd"/>
<path d="M325.4 178h.2v.6h.6v-.6h.2v1.3h-.2v-.6h-.6v.6h-.2z" fill-rule="evenodd"/>
<path d="M325.1 173.8h1v.1h-.4v1.1h-.2v-1.1h-.4z" fill-rule="evenodd"/>
<path d="M325.1 175.9h1v.2h-.4v1.1h-.2v-1.1h-.4z" fill-rule="evenodd"/>
<path d="M325.6 158.8h1l-.8 1.2h.8v.1h-1l.8-1.1h-.8z" fill-rule="evenodd"/>
<path d="M326.4 161h.1v1.2h-.1z" fill-rule="evenodd"/>
<path d="M325.9 163.1h.4a.64 .64 0 0 1 .6 .6 .64 .64 0 0 1-.6 .7h-.4v-.2h.4a.49 .49 0 0 0 .4-.5 .49 .49 0 0 0-.4-.4h-.3v.9h-.1z" fill-rule="evenodd"/>
<path d="M326.8 158.8h.9v.2h-.8v.4h.7v.1h-.7v.5h.8v.1h-.9z" fill-rule="evenodd"/>
<path d="M326.2 171.6h.5a.35 .35 0 0 1 .5 .3 .35 .35 0 0 1-.4 .4l.5 .6h-.2l-.4-.5-.2-.1h-.2v.6h-.1v-.7l.8-.1a.21 .21 0 0 0 0-.2 .21 .21 0 0 0-.3-.1h-.4v.4h-.1z" fill-rule="evenodd"/>
<path d="M326.3 173.9a.63 .63 0 0 1 1 .1 .63 .63 0 0 1-.3 1 .63 .63 0 0 1-.8-.6h.1a.48 .48 0 0 0 .8 .4 .48 .48 0 0 0-.1-.8h-.5l-.2 .4h-.1z" fill-rule="evenodd"/>
<path d="M326.3 176.1a.63 .63 0 0 1 1 .1 .63 .63 0 0 1-.3 .9 .63 .63 0 0 1-.8-.5h.1a.48 .48 0 0 0 .8 .3 .48 .48 0 0 0-.1-.8h-.5l-.2 .5h-.1z" fill-rule="evenodd"/>
<path d="M326.5 165.2h1v.2h-.4v1.1h-.2v-1.1h-.4z" fill-rule="evenodd"/>
<path d="M327 167.4h.2l-.3 .9 .3 .7-.2-.1-.3-.6 .1-.5z" fill-rule="evenodd"/>
<path d="M327 169.5h.2l-.3 1 .3 .7-.2-.2-.3-.6 .1-.5z" fill-rule="evenodd"/>
<path d="M326.8 178.2a.63 .63 0 0 1 1 .1 .63 .63 0 0 1-.3 .9 .63 .63 0 0 1-.9-.5h.2a.48 .48 0 0 0 .7 .4 .48 .48 0 0 0 0-.8l-.4-.1-.2 .2-.1 .3h-.2z" fill-rule="evenodd"/>
<path d="M327.4 169.5h.1l.7 1v-1h.2v1.3h-.2l-.7-1v1h-.1z" fill-rule="evenodd"/>
<path d="M327.1 163.1h1v.2h-.5v1.1h-.1v-1.1h-.4z" fill-rule="evenodd"/>
<path d="M327.5 171.6h.1v1.3h-.1z" fill-rule="evenodd"/>
<path d="M326.9 161.1l.7-.1 .2 .2-.1 .2a.45 .45 0 0 0-.6-.2 .45 .45 0 0 0-.1 .7l.4 .2 .2-.1 .1-.2h.2a.62 .62 0 0 1-1 .3 .62 .62 0 0 1 0-1z" fill-rule="evenodd"/>
<path d="M327.9 171.6h.2l.7 1v-1h.1v1.3h-.1l-.7-1v1h-.2z" fill-rule="evenodd"/>
<path d="M327.4 167.4h.4a.39 .39 0 0 1 .5 .3 .39 .39 0 0 1-.5 .4h-.3v.5h-.1v-.6h.6l.2-.3-.2-.2h-.5v.5h-.1z" fill-rule="evenodd"/>
<path d="M328.1 178h.1v1.2h.7v.1h-.8z" fill-rule="evenodd"/>
<path d="M328.1 175.9h.9v.2h-.7v.3h.7v.2h-.7v.4h.7v.2h-.9z" fill-rule="evenodd"/>
<path d="M328.1 173.8h.2v.5h.6v-.5h.2v1.2h-.2v-.6h-.6v.6h-.2z" fill-rule="evenodd"/>
<path d="M328.1 161h.2v.6l.6-.6h.2l-.5 .5 .6 .7h-.3l-.4-.6-.2 .2v.4h-.2z" fill-rule="evenodd"/>
<path d="M328.2 163.1h.2v.5h.7v-.5h.1v1.3h-.1v-.6h-.7v.6h-.2z" fill-rule="evenodd"/>
<path d="M327.7 165.2h.5a.35 .35 0 0 1 .5 .3 .35 .35 0 0 1-.4 .4l.5 .6h-.2l-.4-.5-.2-.1h-.2v.6h-.1v-.7l.8-.1a.21 .21 0 0 0 0-.2 .21 .21 0 0 0-.3-.1h-.4v.4h-.1z" fill-rule="evenodd"/>
<path d="M328.4 167.4h1.1v.1h-.5v1.1h-.1v-1.1h-.5z" fill-rule="evenodd"/>
<path d="M329.1 178h.9v.2h-.8v.4h.7v.1h-.7v.5h.8v.1h-.9z" fill-rule="evenodd"/>
<path d="M328.6 169.5h.5a.39 .39 0 0 1 .5 .4 .39 .39 0 0 1-.5 .4h-.3v.5h-.2v-.7h.7l.1-.2-.1-.2h-.5v.4h-.2z" fill-rule="evenodd"/>
<path d="M329.3 161h.2l.6 1v-1h.2v1.2h-.2l-.6-1v1h-.2z" fill-rule="evenodd"/>
<path d="M329.6 167.4h.2v.5h.7v-.5h.1v1.2h-.1v-.6h-.7v.6h-.2z" fill-rule="evenodd"/>
<path d="M329.4 171.8l.6-.2 .3 .2v.2h-.1a.49 .49 0 0 0-.7 0 .49 .49 0 0 0 0 .7 .49 .49 0 0 0 .7 0v-.3h-.4v-.1h.6v.4a.69 .69 0 0 1-1 .1 .69 .69 0 0 1 0-1z" fill-rule="evenodd"/>
<path d="M329.3 175.9h.4a.64 .64 0 0 1 .6 .6 .64 .64 0 0 1-.6 .7h-.4v-.2h.4a.49 .49 0 0 0 .4-.5 .49 .49 0 0 0-.4-.4h-.3v.9h-.1z" fill-rule="evenodd"/>
<path d="M329.3 165.2h.2l.5 1.3h-.2l-.2-.4h-.5l-.1 .4h-.2l.2-.5h.6l-.2-.6-.2 .6h-.2z" fill-rule="evenodd"/>
<path d="M329.5 173.9a.63 .63 0 0 1 1 .1 .63 .63 0 0 1-.4 1 .63 .63 0 0 1-.8-.6h.2a.48 .48 0 0 0 .7 .4 .48 .48 0 0 0-.1-.8h-.4l-.2 .4h-.2z" fill-rule="evenodd"/>
<path d="M329.7 169.5h1v.2h-.4v1.1h-.2v-1.1h-.4z" fill-rule="evenodd"/>
<path d="M330.6 161h.9v.1h-.8v.4h.8v.2h-.8v.4h.8v.1h-.9z" fill-rule="evenodd"/>
<path d="M330.7 173.8h.2v1.1h.6v.1h-.8z" fill-rule="evenodd"/>
<path d="M330.9 169.5h.2v.5h.6v-.5h.2v1.3h-.2v-.6h-.6v.6h-.2z" fill-rule="evenodd"/>
<path d="M330.9 167.4a1.04 1.04 0 0 1 0 1.6l.2-.8z" fill-rule="evenodd"/>
<path d="M330.2 165.4l.6-.2 .3 .3-.1 .1a.45 .45 0 0 0-.6-.1 .45 .45 0 0 0-.1 .6l.4 .3 .2-.1 .1-.2h.2a.62 .62 0 0 1-1 .3 .62 .62 0 0 1 0-1z" fill-rule="evenodd"/>
<path d="M330.7 176.1l.6-.2 .3 .2 .1 .2h-.2a.49 .49 0 0 0-.7-.1 .49 .49 0 0 0 0 .7 .49 .49 0 0 0 .7 .1v-.3h-.4v-.2h.6v.5a.69 .69 0 0 1-1 0 .69 .69 0 0 1 0-.9z" fill-rule="evenodd"/>
<path d="M331.4 165.2h.9v.2h-.7v.4h.7v.1h-.7v.5h.8v.1h-1z" fill-rule="evenodd"/>
<path d="M331.8 161.1l.7-.1 .2 .3h-.2a.27 .27 0 0 0-.3-.3 .27 .27 0 0 0-.2 .4l.2 .1a.43 .43 0 0 1 .5 .6 .43 .43 0 0 1-.7 .1l-.3-.3 .2-.1a.31 .31 0 0 0 .3 .3 .31 .31 0 0 0 .3-.3l-.7-.3z" fill-rule="evenodd"/>
<path d="M331.7 173.8h1v.1h-.8v.4h.7v.2h-.7v.4h.8v.1h-1z" fill-rule="evenodd"/>
<path d="M331.9 175.9h1v.2h-.8v.3h.7v.2h-.7v.4h.8v.2h-1z" fill-rule="evenodd"/>
<path d="M332.2 169.5a1.04 1.04 0 0 1 0 1.7l.2-.9z" fill-rule="evenodd"/>
<path d="M333 161.1l.6-.1 .3 .3h-.2a.27 .27 0 0 0-.3-.3 .27 .27 0 0 0-.2 .4l.2 .1a.43 .43 0 0 1 .5 .6 .43 .43 0 0 1-.8 .1l-.2-.3 .1-.1a.31 .31 0 0 0 .4 .3 .31 .31 0 0 0 .3-.3l-.7-.3z" fill-rule="evenodd"/>
<path d="M338.6 161h.3a.71 .71 0 0 1 .4 .6 .71 .71 0 0 1-.4 .7 .49 .49 0 0 1-.4-.7h.1a.32 .32 0 0 0 .1 .5 .32 .32 0 0 0 .4 0 .32 .32 0 0 0 0-.5 .3 .3 0 0 0 0-.4 .3 .3 0 0 0-.4 0l-.1 .4h-.1z" fill-rule="evenodd"/>
<path d="M338.6 163.2l.3-.1a.71 .71 0 0 1 .4 .7 .71 .71 0 0 1-.4 .6 .49 .49 0 0 1-.4-.6h.1a.32 .32 0 0 0 .1 .4 .32 .32 0 0 0 .4 0 .32 .32 0 0 0 0-.4 .3 .3 0 0 0 0-.5 .3 .3 0 0 0-.4 .1l-.1 .4h-.1z" fill-rule="evenodd"/>
<path d="M338.6 165.4l.3-.2a.71 .71 0 0 1 .4 .7 .71 .71 0 0 1-.4 .6 .51 .51 0 0 1-.4-.6h.1a.32 .32 0 0 0 .1 .4 .32 .32 0 0 0 .4 0 .32 .32 0 0 0 0-.4 .3 .3 0 0 0 0-.5 .3 .3 0 0 0-.4 .1l-.1 .4h-.1z" fill-rule="evenodd"/>
<path d="M338.6 167.4h.3a.71 .71 0 0 1 .4 .6 .71 .71 0 0 1-.4 .7 .49 .49 0 0 1-.4-.7h.1a.32 .32 0 0 0 .1 .5 .32 .32 0 0 0 .4 0 .32 .32 0 0 0 0-.5 .3 .3 0 0 0 0-.4 .3 .3 0 0 0-.4 0l-.1 .4h-.1z" fill-rule="evenodd"/>
<path d="M338.6 169.6l.3-.1a.71 .71 0 0 1 .4 .7 .71 .71 0 0 1-.4 .6 .49 .49 0 0 1-.4-.6h.1a.32 .32 0 0 0 .1 .4 .32 .32 0 0 0 .4 0 .32 .32 0 0 0 0-.4 .3 .3 0 0 0 0-.5 .3 .3 0 0 0-.4 .1l-.1 .4h-.1z" fill-rule="evenodd"/>
<path d="M338.6 171.8l.3-.2a.71 .71 0 0 1 .4 .7 .71 .71 0 0 1-.4 .6 .51 .51 0 0 1-.4-.6h.1a.32 .32 0 0 0 .1 .4 .32 .32 0 0 0 .4 0 .32 .32 0 0 0 0-.4 .3 .3 0 0 0 0-.5 .3 .3 0 0 0-.4 .1l-.1 .4h-.1z" fill-rule="evenodd"/>
<path d="M338.6 173.8h.3a.71 .71 0 0 1 .4 .6 .71 .71 0 0 1-.4 .7 .51 .51 0 0 1-.4-.7h.1a.32 .32 0 0 0 .1 .5 .32 .32 0 0 0 .4 0 .32 .32 0 0 0 0-.5 .3 .3 0 0 0 0-.4 .3 .3 0 0 0-.4 0l-.1 .4h-.1z" fill-rule="evenodd"/>
<path d="M338.6 176l.3-.1a.71 .71 0 0 1 .4 .7 .71 .71 0 0 1-.4 .6 .49 .49 0 0 1-.4-.6h.1a.32 .32 0 0 0 .1 .4 .32 .32 0 0 0 .4 0 .32 .32 0 0 0 0-.4 .3 .3 0 0 0 0-.5 .3 .3 0 0 0-.4 .1l-.1 .4h-.1z" fill-rule="evenodd"/>
<path d="M338.6 178.1l.3-.1a.71 .71 0 0 1 .4 .7 .71 .71 0 0 1-.4 .6 .49 .49 0 0 1-.4-.6h.1a.32 .32 0 0 0 .1 .4 .32 .32 0 0 0 .4 0 .32 .32 0 0 0 0-.4 .3 .3 0 0 0 0-.4 .3 .3 0 0 0-.4 0l-.1 .4h-.1z" fill-rule="evenodd"/>
<path d="M339.5 162.1h.2v.1h-.2z" fill-rule="evenodd"/>
<path d="M339.5 164.2h.2v.2h-.2z" fill-rule="evenodd"/>
<path d="M339.5 166.3h.2v.2h-.2z" fill-rule="evenodd"/>
<path d="M339.5 168.5h.2v.1h-.2z" fill-rule="evenodd"/>
<path d="M339.5 170.6h.2v.2h-.2z" fill-rule="evenodd"/>
<path d="M339.5 172.7h.2v.2h-.2z" fill-rule="evenodd"/>
<path d="M339.5 174.9h.2v.1h-.2z" fill-rule="evenodd"/>
<path d="M339.5 177h.2v.2h-.2z" fill-rule="evenodd"/>
<path d="M339.5 179.1h.2v.2h-.2z" fill-rule="evenodd"/>
<path d="M339.9 161h.9l-.5 1.2h-.2l.1-.3 .4-.8h-.7z" fill-rule="evenodd"/>
<path d="M340.1 169.6l.4-.1 .2 .3-.4-.2-.2 .5a.41 .41 0 0 1 .6 .2 .41 .41 0 0 1-.3 .6 .41 .41 0 0 1-.5-.5h.2a.26 .26 0 0 0 .4 .2 .26 .26 0 0 0 0-.4 .26 .26 0 0 0-.4 .1l-.2 .1z" fill-rule="evenodd"/>
<path d="M340.1 163.4l.4-.3v1.3h-.1v-1l-.3 .2z" fill-rule="evenodd"/>
<path d="M340.1 165.6l.4-.4v1.3h-.1v-1l-.3 .2z" fill-rule="evenodd"/>
<path d="M340.1 172l.4-.4v1.3h-.1v-1l-.3 .2z" fill-rule="evenodd"/>
<path d="M340.1 174.1l.4-.3v1.2h-.1v-.9l-.3 .1z" fill-rule="evenodd"/>
<path d="M340.1 176.2l.4-.3v1.3h-.1v-1l-.3 .2z" fill-rule="evenodd"/>
<path d="M340.1 167.5a.41 .41 0 0 1 .6 0 .41 .41 0 0 1-.2 .6l-.4 .4h.7v.1h-.9l.5-.5a.27 .27 0 0 0 .3-.3 .27 .27 0 0 0-.3-.3 .27 .27 0 0 0-.3 .3l-.2-.1z" fill-rule="evenodd"/>
<path d="M340.1 178.1a.41 .41 0 0 1 .6 .1 .41 .41 0 0 1-.2 .6l-.4 .4h.7v.1h-.9l.5-.6a.27 .27 0 0 0 .3-.2 .27 .27 0 0 0-.3-.3 .27 .27 0 0 0-.3 .2h-.2z" fill-rule="evenodd"/>
<path d="M341.1 167.4h.6v.1h-.5l-.1 .4a.42 .42 0 0 1 .6 .2 .42 .42 0 0 1-.2 .6 .42 .42 0 0 1-.6-.4h.2a.28 .28 0 0 0 .4 .1 .28 .28 0 0 0 0-.4 .28 .28 0 0 0-.4 .1l-.1-.1z" fill-rule="evenodd"/>
<path d="M341.1 169.5h.6v.2h-.5l-.1 .3a.42 .42 0 0 1 .6 .2 .42 .42 0 0 1-.2 .6 .42 .42 0 0 1-.6-.4h.2a.28 .28 0 0 0 .4 .2 .28 .28 0 0 0 0-.5 .28 .28 0 0 0-.4 .1h-.1z" fill-rule="evenodd"/>
<path d="M341.1 178.1h.6v.1h-.5l-.1 .3a.42 .42 0 0 1 .6 .3 .42 .42 0 0 1-.2 .5 .42 .42 0 0 1-.6-.3h.2a.28 .28 0 0 0 .4 .1 .28 .28 0 0 0 0-.5 .28 .28 0 0 0-.4 .1h-.1z" fill-rule="evenodd"/>
<path d="M340.9 163.1h.9l-.5 1.3h-.2l.1-.4 .4-.7h-.7z" fill-rule="evenodd"/>
<path d="M341.1 171.8l.2-.2a.71 .71 0 0 1 .5 .7 .71 .71 0 0 1-.5 .6 .51 .51 0 0 1-.4-.6h.2a.32 .32 0 0 0 0 .4 .32 .32 0 0 0 .5 0 .32 .32 0 0 0 0-.4 .32 .32 0 0 0 0-.5 .32 .32 0 0 0-.5 0 .32 .32 0 0 0 0 .5h-.2z" fill-rule="evenodd"/>
<path d="M341.1 173.9l.2-.1a.71 .71 0 0 1 .5 .6 .71 .71 0 0 1-.5 .7 .51 .51 0 0 1-.4-.7h.2a.32 .32 0 0 0 0 .5 .32 .32 0 0 0 .5 0 .32 .32 0 0 0 0-.5 .32 .32 0 0 0 0-.4 .32 .32 0 0 0-.5 0 .32 .32 0 0 0 0 .4h-.2z" fill-rule="evenodd"/>
<path d="M341.1 176l.2-.1a.71 .71 0 0 1 .5 .7 .71 .71 0 0 1-.5 .6 .49 .49 0 0 1-.4-.6h.2a.32 .32 0 0 0 0 .4 .32 .32 0 0 0 .5 0 .32 .32 0 0 0 0-.4 .32 .32 0 0 0 0-.5 .32 .32 0 0 0-.5 0 .32 .32 0 0 0 0 .5h-.2z" fill-rule="evenodd"/>
<path d="M341.1 161.1l.4-.1 .2 .3-.4-.2-.2 .5a.41 .41 0 0 1 .6 .1 .41 .41 0 0 1-.3 .6 .41 .41 0 0 1-.5-.5h.2a.26 .26 0 0 0 .4 .3 .26 .26 0 0 0 0-.5 .26 .26 0 0 0-.4 .2h-.2z" fill-rule="evenodd"/>
<path d="M341.1 165.3a.41 .41 0 0 1 .6 .1 .41 .41 0 0 1-.2 .6l-.4 .4h.6v.1h-.8l.5-.6a.27 .27 0 0 0 .2-.2 .27 .27 0 0 0-.2-.3 .27 .27 0 0 0-.3 .2h-.2z" fill-rule="evenodd"/>
<path d="M342.1 165.3h.6v.1h-.5l-.1 .3a.42 .42 0 0 1 .6 .2 .42 .42 0 0 1-.3 .6 .42 .42 0 0 1-.5-.3h.2a.28 .28 0 0 0 .4 .1 .28 .28 0 0 0 0-.5 .28 .28 0 0 0-.4 .1h-.2z" fill-rule="evenodd"/>
<path d="M342 163.2l.2-.1a.65 .65 0 0 1 .6 .7 .65 .65 0 0 1-.6 .6l-.3-.4v-.2h.2a.32 .32 0 0 0 0 .4 .32 .32 0 0 0 .4 0 .32 .32 0 0 0 .1-.4 .32 .32 0 0 0-.1-.5 .32 .32 0 0 0-.4 0 .32 .32 0 0 0 0 .5h-.2z" fill-rule="evenodd"/>
<path d="M342 167.5l.2-.1a.66 .66 0 0 1 .6 .6 .66 .66 0 0 1-.6 .7l-.3-.4v-.3h.2a.32 .32 0 0 0 0 .5 .32 .32 0 0 0 .4 0 .32 .32 0 0 0 .1-.5 .32 .32 0 0 0-.1-.4 .32 .32 0 0 0-.4 0 .32 .32 0 0 0 0 .4h-.2z" fill-rule="evenodd"/>
<path d="M342 169.6l.2-.1a.66 .66 0 0 1 .6 .7 .66 .66 0 0 1-.6 .6l-.3-.4v-.2h.2a.32 .32 0 0 0 0 .4 .32 .32 0 0 0 .4 0 .32 .32 0 0 0 .1-.4 .32 .32 0 0 0-.1-.5 .32 .32 0 0 0-.4 0 .32 .32 0 0 0 0 .5h-.2z" fill-rule="evenodd"/>
<path d="M342 171.8l.2-.2a.66 .66 0 0 1 .6 .7 .66 .66 0 0 1-.6 .6l-.3-.3v-.3h.2a.32 .32 0 0 0 0 .4 .32 .32 0 0 0 .4 0 .32 .32 0 0 0 .1-.4 .32 .32 0 0 0-.1-.5 .32 .32 0 0 0-.4 0 .32 .32 0 0 0 0 .5h-.2z" fill-rule="evenodd"/>
<path d="M342 173.9l.2-.1a.66 .66 0 0 1 .6 .6 .66 .66 0 0 1-.6 .7l-.3-.4v-.3h.2a.32 .32 0 0 0 0 .5 .32 .32 0 0 0 .4 0 .32 .32 0 0 0 .1-.5 .32 .32 0 0 0-.1-.4 .32 .32 0 0 0-.4 0 .32 .32 0 0 0 0 .4h-.2z" fill-rule="evenodd"/>
<path d="M342 176l.2-.1a.66 .66 0 0 1 .6 .7 .66 .66 0 0 1-.6 .6l-.3-.4v-.2h.2a.32 .32 0 0 0 0 .4 .32 .32 0 0 0 .4 0 .32 .32 0 0 0 .1-.4 .32 .32 0 0 0-.1-.5 .32 .32 0 0 0-.4 0 .32 .32 0 0 0 0 .5h-.2z" fill-rule="evenodd"/>
<path d="M342 178.2l.2-.2a.65 .65 0 0 1 .6 .7 .65 .65 0 0 1-.6 .6l-.3-.3v-.3h.2a.32 .32 0 0 0 0 .4 .32 .32 0 0 0 .4 0 .32 .32 0 0 0 .1-.4 .32 .32 0 0 0-.1-.4 .32 .32 0 0 0-.4 0 .32 .32 0 0 0 0 .4h-.2z" fill-rule="evenodd"/>
<path d="M342 161.3l.5-.3v1.2h-.2v-1l-.3 .2z" fill-rule="evenodd"/>
<path d="M343.4 161.3h.2v.2l.2-.2 .3 .2 .2-.2h.3l.1 .9h-.2v-.6l-.1-.2-.2 .2-.1 .6h-.1v-.6l-.2-.2-.2 .2v.6h-.2z" fill-rule="evenodd"/>
<path d="M343.4 163.5h.2v.1l.2-.2 .3 .2 .2-.2 .3 .1 .1 .9h-.2v-.7l-.1-.1-.2 .2-.1 .6h-.1v-.7l-.2-.1-.2 .1v.7h-.2z" fill-rule="evenodd"/>
<path d="M343.4 165.6h.2v.1l.3-.1 .2 .1 .2-.1h.3l.1 .9h-.2v-.7l-.1-.1-.2 .2-.1 .6h-.1v-.7l-.2-.1-.2 .1v.7h-.2z" fill-rule="evenodd"/>
<path d="M343.4 167.7h.2v.2l.2-.2 .3 .2 .2-.2 .3 .1 .1 .8h-.2v-.6l-.1-.2-.2 .2-.1 .6h-.1v-.6l-.2-.2-.2 .2v.6h-.2z" fill-rule="evenodd"/>
<path d="M343.4 169.9h.2v.1l.2-.2 .3 .2 .2-.2 .3 .1 .1 .9h-.2v-.7l-.1-.1-.2 .2-.1 .6h-.1v-.7l-.2-.1-.2 .1v.7h-.2z" fill-rule="evenodd"/>
<path d="M343.4 172h.2v.1l.3-.1 .2 .1 .2-.1h.3l.1 .9h-.2v-.7l-.1-.1-.2 .2-.1 .6h-.1v-.7l-.2-.1-.2 .1v.7h-.2z" fill-rule="evenodd"/>
<path d="M343.4 174.1h.2v.2l.2-.2 .3 .2 .2-.2h.3l.1 .9h-.2v-.7l-.1-.1-.2 .2-.1 .6h-.1v-.6l-.2-.2-.2 .2v.6h-.2z" fill-rule="evenodd"/>
<path d="M343.4 176.3h.2v.1l.2-.2 .3 .2 .2-.2 .3 .1 .1 .9h-.2v-.7l-.1-.1-.2 .2-.1 .6h-.1v-.7l-.2-.1-.2 .1v.7h-.2z" fill-rule="evenodd"/>
<path d="M343.4 178.4h.2v.1l.2-.1 .3 .1 .2-.1h.3l.1 .9h-.2v-.7l-.1-.1-.2 .2-.1 .6h-.1v-.7l-.2-.1-.2 .1v.7h-.2z" fill-rule="evenodd"/>
<path d="M344.9 161.3h.2v.2l.2-.2 .3 .2 .2-.2h.3l.1 .9h-.2v-.6l-.2-.2-.2 .2v.6h-.1v-.6l-.2-.2-.2 .2v.6h-.2z" fill-rule="evenodd"/>
<path d="M344.9 163.5h.2v.1l.2-.2 .3 .2 .2-.2 .3 .1 .1 .9h-.2v-.7l-.2-.1-.2 .2v.6h-.1v-.7l-.2-.1-.2 .1v.7h-.2z" fill-rule="evenodd"/>
<path d="M344.9 165.6h.2v.1l.3-.1 .2 .1 .2-.1h.3l.1 .9h-.2v-.7l-.2-.1-.2 .2v.6h-.1v-.7l-.2-.1-.2 .1v.7h-.2z" fill-rule="evenodd"/>
<path d="M344.9 167.7h.2v.2l.2-.2 .3 .2 .2-.2 .3 .1 .1 .8h-.2v-.6l-.2-.2-.2 .2v.6h-.1v-.6l-.2-.2-.2 .2v.6h-.2z" fill-rule="evenodd"/>
<path d="M344.9 169.9h.2v.1l.2-.2 .3 .2 .2-.2 .3 .1 .1 .9h-.2v-.7l-.2-.1-.2 .2v.6h-.1v-.7l-.2-.1-.2 .1v.7h-.2z" fill-rule="evenodd"/>
<path d="M344.9 172h.2v.1l.3-.1 .2 .1 .2-.1h.3l.1 .9h-.2v-.7l-.2-.1-.2 .2v.6h-.1v-.7l-.2-.1-.2 .1v.7h-.2z" fill-rule="evenodd"/>
<path d="M344.9 174.1h.2v.2l.2-.2 .3 .2 .2-.2h.3l.1 .9h-.2v-.6l-.2-.2-.2 .2v.6h-.1v-.6l-.2-.2-.2 .2v.6h-.2z" fill-rule="evenodd"/>
<path d="M344.9 176.3h.2v.1l.2-.2 .3 .2 .2-.2 .3 .1 .1 .9h-.2v-.7l-.2-.1-.2 .2v.6h-.1v-.7l-.2-.1-.2 .1v.7h-.2z" fill-rule="evenodd"/>
<path d="M344.9 178.4h.2v.1l.2-.1 .3 .1 .2-.1h.3l.1 .9h-.2v-.7l-.2-.1-.2 .2v.6h-.1v-.7l-.2-.1-.2 .1v.7h-.2z" fill-rule="evenodd"/>
<path d="M351.9 159.2h.1v.1l.4-.1 .2 .1 .2-.1h.2l.1 .9h-.1v-.7l-.2-.1-.2 .2v.6h-.2v-.7l-.1-.1-.2 .1-.1 .7h-.1z" fill-rule="evenodd"/>
<path d="M353.4 159.2h.1v.1l.3-.1 .2 .1 .3-.1h.2l.1 .9h-.1l-.1-.7-.1-.1-.2 .2v.6h-.2v-.7l-.2-.1-.2 .1v.7h-.1z" fill-rule="evenodd"/>
</g>
<g fill="none" stroke="#000" stroke-width=".18">
<path d="M10 10h400v277h-400zM12 12h396v273h-396zM35.3 11.6h.8M35.3 10.7l.4-.4v1.3M60 10v2M85.3 10.4l.5-.1 .3 .4-.8 .9h.8M110 10v2M135.3 10.3h.8l-.4 .5 .3 .1v.6l-.2 .1-.5-.1M160 10v2M185.7 10.2l-.4 1h.9M186 10.7v.9M210 10v2"/>
<path d="M236 10.3h-.6l-.1 .6 .2-.1 .5 .1 .1 .1-.1 .5-.2 .1-.5-.1M260 10v2M286 10.3l-.4 .1a.87 .87 0 0 0 0 1.2l.4-.1 .1-.5-.3-.2-.3 .1-.2 .1M310 10v2M335.3 10.3h.9l-.6 1.3M360 10v2M385.6 10.9l-.3 .2 .1 .4 .2 .1 .4-.1 .1-.2-.1-.3-.2-.1M385.6 10.9l-.3-.3 .3-.3h.2l.3 .2-.3 .4M385.6 10.9h.2M10.6 35.6l.4-1.3 .4 1.3M10.7 35.2h.6M408.6 35.6l.4-1.3 .4 1.3"/>
<path d="M408.7 35.2h.6M10 60h2M24.3 59.4h28.7v.5h-28.7zM24.3 56.3h28.7v.5h-28.7zM53 59.6h4.3M53 56.6h4.3M57.3 54h60.6v47.7h-60.6zM408 60h2M24.3 77.1h12.9v2h-12.9zM24.3 68.4h12.9v4.1h-12.9zM24.3 62.5h28.7v.5h-28.7zM24.3 78.5l.6 .6"/>
<path d="M24.9 77.1l2 2M26.9 77.1l2.1 2M28.4 68.4l-4.1 4.1M29 77.1l2.1 2M31.1 77.1l2 2M32.5 68.4l-4.1 4.1M33.1 77.1l2.1 2M35.2 77.1l2 2M36.6 68.4l-4.1 4.1M37.2 71.9l-.6 .6M40.1 77.1h12.9v2h-12.9zM40.1 68.4h12.9v4.1h-12.9z"/>
<path d="M40.1 78.5l.6 .6M40.7 77.1l2 2M42.7 77.1l2.1 2M44.2 68.4l-4.1 4.1M44.8 77.1l2 2M46.8 77.1l2.1 2M48.3 68.4l-4.1 4.1M48.9 77.1l2.1 2M51 77.1l2 2M52.4 68.4l-4.1 4.1M53 71.9l-.6 .6M53 78.1h4.3"/>
<path d="M53 75h4.3M53 70.4h4.3M53 65.8h4.3M53 62.7h4.3M10.7 84.3h.4l.2 .2-.2 .4 .2 .1 .1 .3-.2 .3h-.5zM10.7 84.9h.4M24.3 99.4h28.7v.5h-28.7zM24.3 96.3h28.7v.5h-28.7zM24.3 93.2h28.7v.6h-28.7zM24.3 83.8h12.9v4.1h-12.9zM28.4 83.8l-4.1 4.1M32.5 83.8l-4.1 4.1"/>
<path d="M36.6 83.8l-4.1 4.1M37.2 87.2l-.6 .7M40.1 83.8h12.9v4.1h-12.9zM44.2 83.8l-4.1 4.1M48.3 83.8l-4.1 4.1M52.4 83.8l-4.1 4.1M53 87.2l-.6 .7M53 99.7h4.3M53 96.6h4.3M53 93.5h4.3M53 90.4h4.3M53 85.8h4.3"/>
<path d="M53 81.2h4.3M408.6 84.3h.5l.2 .2-.2 .4 .2 .1 .1 .3-.3 .3h-.5zM408.6 84.9h.5M10 110h2M408 110h2M11.4 134.4a.62 .62 0 0 0-.9 .5 .62 .62 0 0 0 .7 .7l.2-.1M151.1 123.1h18.1M151.7 123.1v48M151.7 123.1l.6 1.1M151.7 123.1l-.6 1.1M244.4 125.1h2.6M245.7 123.8v2.6"/>
<path d="M247.5 122.5l-.4 1.2M248.3 123.3l-1.2 .4M256.7 121h-6.9l-2.7 2.7M257.5 121l.5-.1 .1-.4-.6-.1v1M257.8 121l.3 .4M259.2 120.5l.4-.1 .2 .3-.6 .7h.6M260.2 121.4h.1M260.8 120.5l.1-.1a.54 .54 0 0 1 .4 .5 .54 .54 0 0 1-.4 .5l-.2-.3zM261.7 120.5l.2-.1a.53 .53 0 0 1 .3 .5 .53 .53 0 0 1-.3 .5l-.3-.3zM262.7 120.5l.1-.1a.53 .53 0 0 1 .4 .5 .53 .53 0 0 1-.4 .5l-.2-.3zM263.6 120.5l.2-.1a.53 .53 0 0 1 .3 .5 .53 .53 0 0 1-.3 .5l-.3-.3zM265.3 120.8v.6"/>
<path d="M265.3 120.9l.3-.1 .1 .1M265.7 120.9l.2-.1h.2l.1 .6M265.7 120.9v.5M266.6 120.9l.3-.1 .2 .1M266.6 120.8v.6M267.1 120.9l.1-.1h.2l.1 .6M267.1 120.9v.5M409.4 134.4a.62 .62 0 0 0-.9 .5 .62 .62 0 0 0 .6 .7l.3-.1M10 160h2M150.1 148a.49 .49 0 0 1 .5-.3 .49 .49 0 0 1 .4 .5 .49 .49 0 0 1-.6 .3 .49 .49 0 0 1-.3-.5zM150.1 148.9a.49 .49 0 0 1 .5-.2 .49 .49 0 0 1 .4 .5 .49 .49 0 0 1-.6 .2 .49 .49 0 0 1-.3-.5zM150.1 146a.48 .48 0 0 1 .6-.1 .48 .48 0 0 1 .3 .4 .49 .49 0 0 1-.6 .3 .49 .49 0 0 1-.3-.5z"/>
<path d="M150.1 147a.48 .48 0 0 1 .6-.2 .48 .48 0 0 1 .3 .5 .49 .49 0 0 1-.6 .2 .49 .49 0 0 1-.3-.5zM150.3 151.2h.7M150.3 144.7h.7M150.3 143.4h.7M150.4 150.4l-.2-.2-.2 .2 .2 .4 .2-.2M150.4 150.4l.2-.2 .4 .2-.2 .4-.4-.2M150.4 150.4v.2M150.5 144.3l-.2 .1 .1 .3M150.5 143l-.2 .1 .1 .3M150.5 144.3h.5M150.5 143h.5M150.7 151.1v.6l-.7-.2"/>
<path d="M150.9 149.8h.1M151 142.5l-.6 .1-.1 .2 .2 .2M151 143.9h-.6l-.1 .2 .2 .2M408 160h2M151.1 171.1h18.1M151.1 170l.6 1.1M152.3 170l-.6 1.1M167.7 169.6v12.1M203.3 179.8l-.2-.2 .2-.2 .4 .2-.2 .2M203.3 179.8l-.2 .2 .2 .4 .4-.2-.2-.4M203.3 179.8h.2M204.2 179.5l.1-.1a.53 .53 0 0 1 .3 .5 .53 .53 0 0 1-.3 .5 .67 .67 0 0 1-.1-.9z"/>
<path d="M205.6 179.5l.1-.1a.53 .53 0 0 1 .3 .5 .53 .53 0 0 1-.3 .5 .66 .66 0 0 1-.1-.9zM206.6 179.5l.1-.1a.53 .53 0 0 1 .3 .5 .53 .53 0 0 1-.3 .5 .67 .67 0 0 1-.1-.9zM207.5 179.5l.1-.1a.53 .53 0 0 1 .4 .5 .53 .53 0 0 1-.4 .5 .67 .67 0 0 1-.1-.9zM208.5 179.5l.1-.1a.53 .53 0 0 1 .3 .5 .53 .53 0 0 1-.3 .5 .67 .67 0 0 1-.1-.9zM210.1 179.7v.7M210.1 179.8l.3-.1 .1 .2M210.5 179.9l.2-.2 .2 .1v.6M210.5 179.9v.5M211.4 179.8l.3-.1 .1 .2M211.4 179.7v.7M211.8 179.9l.2-.2 .2 .1 .1 .6M211.8 179.9v.5"/>
<path d="M247.7 169.6v12.1M10.7 184.3a.66 .66 0 0 1 .7 .6 .66 .66 0 0 1-.7 .7zM167.7 181.1h80M167.7 181.1l1.1 .6M168.8 180.5l-1.1 .6M205 180.3v.1M246.6 180.5l1.1 .6M247.7 181.1l-1.1 .6M408.6 184.3a.66 .66 0 0 1 .8 .6 .66 .66 0 0 1-.8 .7zM10 210h2M408 210h2M10.7 234.9h.5"/>
<path d="M11.3 234.3h-.6v1.3h.6M408.7 234.9h.4M409.3 234.3h-.6v1.3h.6M10 260h2M408 260h2M10.8 284.9h.4M11.4 284.3h-.6v1.3M35.3 285.7l.4-.4v1.3M35.3 286.6h.8M60 285v2M85.3 285.4l.5-.1 .3 .4-.8 .9h.8M110 285v2"/>
<path d="M135.3 285.3h.8l-.4 .5 .3 .1v.6l-.2 .1-.5-.1M160 285v2M185.7 285.2l-.4 1h.9M186 285.7v.9M210 285v2M236 285.3h-.6l-.1 .6 .2-.1 .5 .1 .1 .1-.1 .5-.2 .1-.5-.1M260 285v2M286 285.3l-.4 .1a.87 .87 0 0 0 0 1.2l.4-.1 .1-.5-.3-.2-.3 .1-.2 .1M310 285v2M335.3 285.3h.9l-.6 1.3M360 285v2M385.6 285.9l-.3-.3 .3-.3h.2l.3 .2-.3 .4"/>
<path d="M385.6 285.9l-.3 .2v.2l.3 .3 .4-.1 .1-.2v-.2l-.3-.2M385.6 285.9h.2M408.7 284.9h.5M409.4 284.3h-.7v1.3"/>
</g>
<g fill="#000" stroke="#000" stroke-width=".18">
<path d="M24.3 74.5h12.9v1h-12.9z" fill-rule="evenodd"/>
<path d="M24.3 65.3h12.2v1h-12.2z" fill-rule="evenodd"/>
<path d="M36.9 65.3h1.3v1h-1.3z" fill-rule="evenodd"/>
<path d="M37.6 78.6h.6v5.2h-.6z" fill-rule="evenodd"/>
<path d="M37.6 75.5h.6v5.2h-.6z" fill-rule="evenodd"/>
<path d="M37.6 72.5h.6v5.1h-.6z" fill-rule="evenodd"/>
<path d="M37.6 66.3h.6v8.2h-.6z" fill-rule="evenodd"/>
<path d="M39.1 78.6h.6v5.2h-.6z" fill-rule="evenodd"/>
<path d="M39.1 75.5h.6v5.2h-.6z" fill-rule="evenodd"/>
<path d="M39.1 72.5h.6v5.1h-.6z" fill-rule="evenodd"/>
<path d="M39.1 66.3h.6v8.2h-.6z" fill-rule="evenodd"/>
<path d="M39.1 65.3h1.3v1h-1.3z" fill-rule="evenodd"/>
<path d="M40.1 74.5h12.9v1h-12.9z" fill-rule="evenodd"/>
<path d="M40.8 65.3h12.2v1h-12.2z" fill-rule="evenodd"/>
<path d="M24.3 89.9h12.2v1h-12.2z" fill-rule="evenodd"/>
<path d="M24.3 80.7h12.9v1h-12.9z" fill-rule="evenodd"/>
<path d="M36.9 89.9h1.3v1h-1.3z" fill-rule="evenodd"/>
<path d="M37.6 81.7h.6v8.2h-.6z" fill-rule="evenodd"/>
<path d="M39.1 89.9h1.3v1h-1.3z" fill-rule="evenodd"/>
<path d="M39.1 81.7h.6v8.2h-.6z" fill-rule="evenodd"/>
<path d="M40.1 80.7h12.9v1h-12.9z" fill-rule="evenodd"/>
<path d="M40.8 89.9h12.2v1h-12.2z" fill-rule="evenodd"/>
</g>
<path d="M384.6 280.1l.9-.4v2.1l.4 .2h-1.2l.3-.1v-1.5v-.3z" fill-rule="evenodd" fill="#00007f"/>
<g fill="#00f">
<path d="M384.3 275.7l.3-.1h.4l.2 .4-.1 .1a.32 .32 0 0 0-.4-.4 .32 .32 0 0 0-.3 .5h.1a.57 .57 0 0 1 .8 .6 .64 .64 0 0 1-.7 .3 .64 .64 0 0 1-.5-.5h.2a.39 .39 0 0 0 .4 .4 .39 .39 0 0 0 .4-.4l-.3-.1a.49 .49 0 0 1-.5-.2 .49 .49 0 0 1 0-.6z" fill-rule="evenodd"/>
<path d="M385.5 275.6h.2v.6l.3-.2 .4 .2v.9h-.2v-.7a.27 .27 0 0 0-.3-.2 .27 .27 0 0 0-.2 .3v.6h-.2z" fill-rule="evenodd"/>
<path d="M386.8 276.2a.51 .51 0 0 1 .6-.1 .51 .51 0 0 1 .2 .5h-.8l.3 .4 .5-.2a.52 .52 0 0 1-.6 .3 .52 .52 0 0 1-.3-.6h.8l-.2-.3a.31 .31 0 0 0-.5 .3h-.1z" fill-rule="evenodd"/>
<path d="M388 276.2a.51 .51 0 0 1 .6-.1 .51 .51 0 0 1 .2 .5h-.8l.2 .4 .6-.2a.52 .52 0 0 1-.6 .3 .52 .52 0 0 1-.4-.6h.8l-.2-.3a.31 .31 0 0 0-.4 .3h-.2z" fill-rule="evenodd"/>
<path d="M389.1 275.8l.2-.1v.3h.1v.2h-.1v.6l.2 .3a.27 .27 0 0 1-.3 0 .27 .27 0 0 1-.1-.3v-.6h-.2z" fill-rule="evenodd"/>
<path d="M389.7 276h.2v.2h-.2z" fill-rule="evenodd"/>
<path d="M389.7 276.9h.2v.2h-.2z" fill-rule="evenodd"/>
<path d="M392.7 281.1a.54 .54 0 0 1 .8 .1 .54 .54 0 0 1-.2 .8 .54 .54 0 0 1-.7-.3v-.1h.2a.36 .36 0 0 0 .4 .4 .36 .36 0 0 0 .2-.6l-.4-.2-.2 .4h-.2z" fill-rule="evenodd"/>
<path d="M393.9 280.7l.4-.1v.2a.19 .19 0 0 0-.2 0 .19 .19 0 0 0-.1 .2h.2v.2h-.2v.9h-.2v-.9h-.1v-.2h.1z" fill-rule="evenodd"/>
</g>
<g fill="#00007f">
<path d="M396.2 280.1l.9-.4v2.1l.4 .2h-1.2l.3-.1v-1.5v-.3z" fill-rule="evenodd"/>
<path d="M398.1 279.9a.73 .73 0 0 1 .9-.1 .73 .73 0 0 1 .3 .8 1.04 1.04 0 0 1-.8 1.5 .95 .95 0 0 1-.6-1h.5v.7a.2 .2 0 0 0 .2 .2 .2 .2 0 0 0 .2-.3v-1.7a.2 .2 0 0 0-.2-.2 .2 .2 0 0 0-.2 .2v1.1h-.5v-.7z" fill-rule="evenodd"/>
</g>
<g fill="#00f">
<path d="M368.3 275.7l.3-.1h.4l.2 .4-.1 .1a.32 .32 0 0 0-.4-.4 .32 .32 0 0 0-.3 .5h.1a.57 .57 0 0 1 .8 .6 .64 .64 0 0 1-.7 .3 .64 .64 0 0 1-.5-.5h.2a.39 .39 0 0 0 .4 .4 .39 .39 0 0 0 .4-.4l-.3-.1a.49 .49 0 0 1-.5-.2 .49 .49 0 0 1 0-.6z" fill-rule="evenodd"/>
<path d="M369.5 275.6h.2v.2h-.2z" fill-rule="evenodd"/>
<path d="M369.5 276h.2v1.1h-.2z" fill-rule="evenodd"/>
<path d="M369.9 276h.9l-.7 1h.8v.1h-1l.7-.9h-.7z" fill-rule="evenodd"/>
<path d="M371.1 276.2a.51 .51 0 0 1 .6-.1 .51 .51 0 0 1 .3 .5h-.8l.2 .4 .6-.2a.52 .52 0 0 1-.7 .3 .52 .52 0 0 1-.3-.6h.8l-.2-.3a.31 .31 0 0 0-.4 .3h-.2z" fill-rule="evenodd"/>
<path d="M372.3 276h.2v.2h-.2z" fill-rule="evenodd"/>
<path d="M372.3 276.9h.2v.2h-.2z" fill-rule="evenodd"/>
</g>
<g fill="#00007f">
<path d="M370.3 279.7l.9 2.1 .3 .2h-1.1l.2-.1-.1-.5h-.9l-.1 .5 .3 .1h-.8l.6-.8h.8l-.3-.7-.4 .7h-.1z" fill-rule="evenodd"/>
<path d="M371.9 279.9a.55 .55 0 0 1 .8-.2 .55 .55 0 0 1 0 .9 .81 .81 0 0 1 .1 1.2 .81 .81 0 0 1-1.2 0l.2-.2a.54 .54 0 0 0 .8 .2 .72 .72 0 0 0-.6-1 .41 .41 0 0 0 .5-.3 .41 .41 0 0 0-.3-.5 .41 .41 0 0 0-.5 .3z" fill-rule="evenodd"/>
</g>
<path d="M366.5 274.5h41.5M382.5 274.5v10.5M408 264h-41.5v21" fill="none" stroke="#000" stroke-width=".18"/>
<g fill="#00f">
<path d="M384.2 265.1h.6a.42 .42 0 0 1 .6 .4 .42 .42 0 0 1-.5 .4l.6 .7h-.3l-.4-.6h-.2h-.2v.6h-.2v-.8h.6a.26 .26 0 0 0 .4-.2 .26 .26 0 0 0-.4-.3h-.4v.5h-.2z" fill-rule="evenodd"/>
<path d="M385.7 265.7a.51 .51 0 0 1 .6-.1 .51 .51 0 0 1 .3 .5h-.8l.2 .4 .6-.2a.52 .52 0 0 1-.7 .3 .52 .52 0 0 1-.3-.6h.8l-.2-.3a.31 .31 0 0 0-.4 .3h-.2z" fill-rule="evenodd"/>
<path d="M386.7 265.5h.2l.3 .9 .3-.9h.2l-.4 1.1h-.2z" fill-rule="evenodd"/>
<path d="M387.9 265.1h.2v.2h-.2z" fill-rule="evenodd"/>
<path d="M387.9 265.5h.2v1.1h-.2z" fill-rule="evenodd"/>
<path d="M388.4 265.6l.2-.1a.39 .39 0 0 1 .5 .3h-.2a.21 .21 0 0 0-.2-.2 .21 .21 0 0 0-.1 .3 .43 .43 0 0 1 .4 .1 .43 .43 0 0 1 .1 .4l-.2 .2h-.4l-.2-.3h.1a.24 .24 0 0 0 .3 .3 .24 .24 0 0 0 .2-.4 .43 .43 0 0 1-.6-.5z" fill-rule="evenodd"/>
<path d="M389.4 265.1h.2v.2h-.2z" fill-rule="evenodd"/>
<path d="M389.4 265.5h.2v1.1h-.2z" fill-rule="evenodd"/>
<path d="M390 265.6a.54 .54 0 0 1 .8 .1 .54 .54 0 0 1-.3 .8 .54 .54 0 0 1-.7-.3v-.1h.2a.36 .36 0 0 0 .4 .4 .36 .36 0 0 0 .2-.6l-.4-.2-.2 .4h-.2z" fill-rule="evenodd"/>
<path d="M391 265.5h.2v.2l.2-.2a.37 .37 0 0 1 .4 .1 .37 .37 0 0 1 .1 .4v.6h-.2v-.6a.27 .27 0 0 0-.3-.3 .27 .27 0 0 0-.2 .3v.6h-.2z" fill-rule="evenodd"/>
<path d="M392.2 265.5h.2v.2h-.2z" fill-rule="evenodd"/>
<path d="M392.2 266.4h.2v.2h-.2z" fill-rule="evenodd"/>
</g>
<g fill="#00007f">
<path d="M384 270.4h.5l.1-.5v.5l.5 .1h-.5l-.1 .5v-.5z" fill-rule="evenodd"/>
<path d="M386.1 269.8l.3-.1a1.42 1.42 0 0 0 0 1.9l-.3-.2a1.12 1.12 0 0 1 0-1.6z" fill-rule="evenodd"/>
<path d="M386.4 269.7h.6l-.2 .2v.7a.41 .41 0 0 0 .4 .5 .41 .41 0 0 0 .4-.6v-.7l-.2-.1h.5l-.2 .2v.6a.55 .55 0 0 1-.6 .7 .55 .55 0 0 1-.5-.7v-.7z" fill-rule="evenodd"/>
<path d="M387.9 270.3l.4-.1v.2a.29 .29 0 0 1 .3-.2 .29 .29 0 0 1 .2 .3v.5l.2 .1h-.5l.2-.2-.1-.5-.1-.1-.2 .1v.6l.1 .1h-.4l.1-.1v-.6z" fill-rule="evenodd"/>
<path d="M389 270.3l.3-.1v.2l.2-.2h.2l-.4 .3v.5l.2 .1h-.5l.1-.1v-.6z" fill-rule="evenodd"/>
<path d="M389.9 270.3l.4-.1 .2 .2v.1h-.6l.2 .4 .3 .1 .1-.2a.41 .41 0 0 1-.6 .3 .41 .41 0 0 1-.1-.6h.5l-.2-.3-.3 .3z" fill-rule="evenodd"/>
<path d="M390.7 269.8l.3-.1v1.3l.1 .1h-.4l.1-.1v-.9v-.3z" fill-rule="evenodd"/>
<path d="M391.4 270.3l.4-.1 .2 .2 .1 .1h-.7l.2 .4 .3 .1 .1-.2a.41 .41 0 0 1-.5 .3 .41 .41 0 0 1-.2-.6h.5l-.2-.3-.3 .3z" fill-rule="evenodd"/>
<path d="M392.3 270.2l.5 .1 .1 .7 .1-.1-.1 .2h-.1l-.1-.1-.2 .1h-.2l-.1-.2 .3 .1 .2-.1v-.3l-.5 .3 .5-.4-.2-.3-.2 .3z" fill-rule="evenodd"/>
<path d="M393.2 270.2h.5v.3l-.2-.3a.15 .15 0 0 0-.2 .1 .15 .15 0 0 0 0 .2h.1a.34 .34 0 0 1 .4 .5 .34 .34 0 0 1-.6 .1v-.3l.2 .3 .2-.2-.4-.4z" fill-rule="evenodd"/>
<path d="M394.1 270.3l.4-.1 .2 .2v.1h-.6l.1 .4 .3 .1 .2-.2a.41 .41 0 0 1-.6 .3 .41 .41 0 0 1-.1-.6h.5l-.2-.3-.3 .3z" fill-rule="evenodd"/>
<path d="M395.4 269.8l.3-.1v1.3h.2l-.6 .2-.4-.2v-.4h.2l.1 .4 .3-.1-.1-.7-.3 .1v.3h-.2a.42 .42 0 0 1 .6-.4v-.4z" fill-rule="evenodd"/>
<path d="M395.9 269.7a1.08 1.08 0 0 1 0 1.9 1.42 1.42 0 0 0 0-1.9z" fill-rule="evenodd"/>
</g>
<path d="M382.5 264v10.5" fill="none" stroke="#000" stroke-width=".18"/>
<g fill="#00f">
<path d="M368.2 265.1h.5a.75 .75 0 0 1 .7 .8 .75 .75 0 0 1-.7 .7h-.5v-.2h.5a.58 .58 0 0 0 .5-.5 .58 .58 0 0 0-.5-.6h-.3v1.1h-.2z" fill-rule="evenodd"/>
<path d="M369.7 265.6l.2-.1a.47 .47 0 0 1 .5 .1 .47 .47 0 0 1 .1 .6l.1 .4h-.2v-.1l-.5 .1-.3-.1v-.2l.6 .2 .1-.4-.7 .2a.57 .57 0 0 1 .7-.4 .28 .28 0 0 0-.2-.2 .28 .28 0 0 0-.3 .2l-.2-.1z" fill-rule="evenodd"/>
<path d="M370.9 265.3l.1-.1v.3h.2v.2h-.2v.6l.2 .3a.27 .27 0 0 1-.3 0 .27 .27 0 0 1 0-.3v-.6h-.2z" fill-rule="evenodd"/>
<path d="M371.5 265.7a.51 .51 0 0 1 .6-.1 .51 .51 0 0 1 .2 .5h-.8l.3 .4 .5-.2a.52 .52 0 0 1-.6 .3 .52 .52 0 0 1-.4-.6h.9l-.2-.3a.31 .31 0 0 0-.5 .3h-.2z" fill-rule="evenodd"/>
<path d="M372.6 265.5h.2v.2h-.2z" fill-rule="evenodd"/>
<path d="M372.6 266.4h.2v.2h-.2z" fill-rule="evenodd"/>
</g>
<path d="M408 253.5h-41.5v10.5" fill="none" stroke="#000" stroke-width=".18"/>
<g fill="#00f">
<path d="M368.2 254.6h.5a.46 .46 0 0 1 .6 .5 .46 .46 0 0 1-.6 .4h-.3v.6h-.2v-.8h.5a.28 .28 0 0 0 .4-.2 .28 .28 0 0 0-.4-.3h-.3v.5h-.2z" fill-rule="evenodd"/>
<path d="M369.5 255h.2v.2l.2-.2h.2v.2a.24 .24 0 0 0-.3 .1 .24 .24 0 0 0-.1 .3v.5h-.2z" fill-rule="evenodd"/>
<path d="M370.3 255.1a.55 .55 0 0 1 .9 .1 .55 .55 0 0 1-.3 .8 .55 .55 0 0 1-.7-.4h.2a.36 .36 0 0 0 .4 .4 .36 .36 0 0 0 .2-.6l-.4-.2-.2 .4h-.2z" fill-rule="evenodd"/>
<path d="M371.4 254.6h.2v.2h-.2z" fill-rule="evenodd"/>
<path d="M371.4 255h.2v1.2a.3 .3 0 0 1-.1 .3 .3 .3 0 0 1-.3 0l.2-.2z" fill-rule="evenodd"/>
<path d="M371.9 255.2a.51 .51 0 0 1 .7-.1 .51 .51 0 0 1 .2 .5h-.8l.2 .4 .6-.2a.52 .52 0 0 1-.6 .3 .52 .52 0 0 1-.4-.6h.8l-.2-.3a.31 .31 0 0 0-.4 .3h-.2z" fill-rule="evenodd"/>
<path d="M373.1 255.1h.6l.2 .3h-.2a.34 .34 0 0 0-.5-.2 .34 .34 0 0 0 0 .6l.3 .2 .2-.3h.2a.53 .53 0 0 1-.8 .3 .53 .53 0 0 1 0-.8z" fill-rule="evenodd"/>
<path d="M374.1 254.8l.2-.1v.3h.2v.2h-.2v.6l.2 .3a.27 .27 0 0 1-.3 0 .27 .27 0 0 1-.1-.3v-.6h-.1z" fill-rule="evenodd"/>
<path d="M375.3 254.6h.2l.8 1.2v-1.2h.2v1.5h-.2l-.8-1.2v1.2h-.2z" fill-rule="evenodd"/>
<path d="M376.9 255.1l.1-.1a.47 .47 0 0 1 .6 .1 .47 .47 0 0 1 0 .6l.1 .4h-.2v-.1l-.5 .1-.3-.1v-.2l.4 .2h.2l.2-.4-.8 .2a.57 .57 0 0 1 .8-.4 .28 .28 0 0 0-.3-.2 .28 .28 0 0 0-.3 .2l-.2-.1z" fill-rule="evenodd"/>
<path d="M377.9 255h.2v.2l.3-.2 .3 .2 .3-.2 .3 .1 .1 .2v.8h-.2v-.7a.24 .24 0 0 0-.2-.2 .24 .24 0 0 0-.2 .3v.6h-.2v-.7a.25 .25 0 0 0-.3-.2 .25 .25 0 0 0-.2 .4v.5h-.2z" fill-rule="evenodd"/>
<path d="M379.8 255.2a.51 .51 0 0 1 .6-.1 .51 .51 0 0 1 .2 .5h-.8l.3 .4 .5-.2a.52 .52 0 0 1-.6 .3 .52 .52 0 0 1-.4-.6h.8l-.1-.3a.31 .31 0 0 0-.5 .3h-.2z" fill-rule="evenodd"/>
<path d="M380.9 255h.2v.2h-.2z" fill-rule="evenodd"/>
<path d="M380.9 255.9h.2v.2h-.2z" fill-rule="evenodd"/>
</g>
<g fill="#00007f">
<path d="M368.2 269.8a.42 .42 0 0 1 .6 .1 .42 .42 0 0 1-.1 .6l-.4 .5 .7-.1-.1 .2h-.9a1.05 1.05 0 0 0 .7-1.1l-.3-.1-.3 .2z" fill-rule="evenodd"/>
<path d="M369.3 269.8a.47 .47 0 0 1 .6 0 .47 .47 0 0 1 .1 .6 .48 .48 0 0 1-.1 .6 .48 .48 0 0 1-.6 0l-.2-.5h.2a.36 .36 0 0 0 0 .4 .36 .36 0 0 0 .4 .1l.1-.6-.1-.6a.24 .24 0 0 0-.3 0 .24 .24 0 0 0 0 .3l-.1 .4h-.2z" fill-rule="evenodd"/>
<path d="M370.3 269.8a.42 .42 0 0 1 .6 .1 .42 .42 0 0 1-.1 .6l-.4 .5 .7-.1-.1 .2h-.9a1.06 1.06 0 0 0 .7-1.1l-.3-.1-.3 .2z" fill-rule="evenodd"/>
<path d="M371.6 269.7h.5l-.1 .2h-.4l-.1 .2a.5 .5 0 0 1 .5 .6 .5 .5 0 0 1-.7 .3 .4 .4 0 0 0 .6-.2 .4 .4 0 0 0-.5-.5h-.1z" fill-rule="evenodd"/>
<path d="M372.3 270.6h.5v.1h-.5z" fill-rule="evenodd"/>
<path d="M373.2 269.8a.47 .47 0 0 1 .6 0 .47 .47 0 0 1 .1 .6 .48 .48 0 0 1-.2 .6 .48 .48 0 0 1-.6 0l-.1-.5h.2a.36 .36 0 0 0-.1 .4 .36 .36 0 0 0 .4 .1l.2-.6-.2-.6a.24 .24 0 0 0-.2 0 .24 .24 0 0 0-.1 .3v.4h-.2z" fill-rule="evenodd"/>
<path d="M374.2 269.7h.7l-.5 1.4h-.1l.4-1.2h-.5l-.1 .2z" fill-rule="evenodd"/>
<path d="M375.1 270.6h.5v.1h-.5z" fill-rule="evenodd"/>
<path d="M375.9 269.9l.4-.2v1.3l.2 .1h-.5l.1-.1v-1z" fill-rule="evenodd"/>
<path d="M377 269.8h.4a.31 .31 0 0 1 0 .5 .44 .44 0 0 1 .1 .7 .44 .44 0 0 1-.6 0 .34 .34 0 0 0 .5 0 .34 .34 0 0 0-.1-.5l-.2-.1a.28 .28 0 0 0 .3-.2 .28 .28 0 0 0-.2-.3 .28 .28 0 0 0-.3 .1z" fill-rule="evenodd"/>
</g>
<g fill="#00f">
<path d="M341.2 275.6h.6a.42 .42 0 0 1 .6 .4 .42 .42 0 0 1-.5 .4l.6 .7h-.3a.74 .74 0 0 0-.8-.6v.6h-.2v-.8h.6a.26 .26 0 0 0 .4-.2 .26 .26 0 0 0-.4-.3h-.4v.5h-.2z" fill-rule="evenodd"/>
<path d="M342.7 276.2a.51 .51 0 0 1 .6-.1 .51 .51 0 0 1 .3 .5h-.8l.2 .4 .6-.2a.52 .52 0 0 1-.7 .3 .52 .52 0 0 1-.3-.6h.8l-.2-.3a.31 .31 0 0 0-.4 .3h-.2z" fill-rule="evenodd"/>
<path d="M343.7 276h.2l.3 .9 .3-.9h.2l-.4 1.1h-.2z" fill-rule="evenodd"/>
<path d="M344.9 275.6h.2v.2h-.2z" fill-rule="evenodd"/>
<path d="M344.9 276h.2v1.1h-.2z" fill-rule="evenodd"/>
<path d="M345.4 276.2a.51 .51 0 0 1 .6-.1 .51 .51 0 0 1 .3 .5h-.8l.2 .4 .6-.2a.52 .52 0 0 1-.7 .3 .52 .52 0 0 1-.3-.6h.8l-.2-.3a.31 .31 0 0 0-.4 .3h-.2z" fill-rule="evenodd"/>
<path d="M346.4 276h.2l.2 .9 .2-.9h.2l.2 .9 .3-.9h.2l-.4 1.1h-.2l-.2-.8-.2 .8h-.2z" fill-rule="evenodd"/>
<path d="M348.1 276.2a.51 .51 0 0 1 .6-.1 .51 .51 0 0 1 .3 .5h-.9l.3 .4 .6-.2a.52 .52 0 0 1-.7 .3 .52 .52 0 0 1-.3-.6h.8l-.2-.3a.31 .31 0 0 0-.4 .3h-.2z" fill-rule="evenodd"/>
<path d="M349.2 276h.1v.2l.2-.2h.2v.2a.24 .24 0 0 0-.3 .1 .24 .24 0 0 0 0 .3v.5h-.2z" fill-rule="evenodd"/>
<path d="M349.9 276h.2v.2h-.2z" fill-rule="evenodd"/>
<path d="M349.9 276.9h.2v.2h-.2z" fill-rule="evenodd"/>
</g>
<path d="M332 274.5h34.5M339.5 274.5v10.5" fill="none" stroke="#000" stroke-width=".18"/>
<g fill="#00f">
<path d="M341.2 265.1h.5a.75 .75 0 0 1 .7 .8 .75 .75 0 0 1-.7 .7h-.5v-.2h.5a.58 .58 0 0 0 .5-.5 .58 .58 0 0 0-.5-.6h-.3v1.1h-.2z" fill-rule="evenodd"/>
<path d="M342.7 265.7a.51 .51 0 0 1 .6-.1 .51 .51 0 0 1 .3 .5h-.8l.2 .4 .6-.2a.52 .52 0 0 1-.7 .3 .52 .52 0 0 1-.3-.6h.8l-.2-.3a.31 .31 0 0 0-.4 .3h-.2z" fill-rule="evenodd"/>
<path d="M343.8 265.6l.3-.1a.39 .39 0 0 1 .5 .3h-.2a.21 .21 0 0 0-.2-.2 .21 .21 0 0 0-.2 .3 .43 .43 0 0 1 .5 .1 .43 .43 0 0 1 .1 .4l-.2 .2h-.4l-.3-.3h.2a.24 .24 0 0 0 .3 .3 .24 .24 0 0 0 .2-.4 .43 .43 0 0 1-.6-.5z" fill-rule="evenodd"/>
<path d="M344.9 265.1h.2v.2h-.2z" fill-rule="evenodd"/>
<path d="M344.9 265.5h.2v1.1h-.2z" fill-rule="evenodd"/>
<path d="M345.4 265.6a.43 .43 0 0 1 .7 .1v-.2h.1v1a.48 .48 0 0 1-.3 .5 .48 .48 0 0 1-.6-.3l.4 .2a.3 .3 0 0 0 .3-.4 .46 .46 0 0 1-.5 .1 .46 .46 0 0 1-.2-.5h.2a.34 .34 0 0 0 .4 .3 .34 .34 0 0 0 .1-.5 .3 .3 0 0 0-.3-.2 .3 .3 0 0 0-.2 .4h-.2z" fill-rule="evenodd"/>
<path d="M346.5 265.5h.2v.2l.1-.2a.37 .37 0 0 1 .5 .1 .37 .37 0 0 1 .1 .4v.6h-.2v-.6a.27 .27 0 0 0-.3-.3 .27 .27 0 0 0-.2 .3v.6h-.2z" fill-rule="evenodd"/>
<path d="M347.7 265.7a.51 .51 0 0 1 .7-.1 .51 .51 0 0 1 .2 .5h-.8l.2 .4 .6-.2a.52 .52 0 0 1-.6 .3 .52 .52 0 0 1-.4-.6h.8l-.2-.3a.31 .31 0 0 0-.4 .3h-.2z" fill-rule="evenodd"/>
<path d="M348.8 265.5h.2v.2l.2-.2h.2v.2a.24 .24 0 0 0-.3 .1 .24 .24 0 0 0-.1 .3v.5h-.2z" fill-rule="evenodd"/>
<path d="M349.6 265.5h.2v.2h-.2z" fill-rule="evenodd"/>
<path d="M349.6 266.4h.2v.2h-.2z" fill-rule="evenodd"/>
</g>
<path d="M332 264h34.5M339.5 264v10.5" fill="none" stroke="#000" stroke-width=".18"/>
<g fill="#00007f">
<path d="M341 269.7h.6a.7 .7 0 0 1 .8 .7 .7 .7 0 0 1-.7 .7h-.7l.2-.1v-1.2h.2v1.2a.65 .65 0 0 0 .8-.7 .65 .65 0 0 0-1-.5z" fill-rule="evenodd"/>
<path d="M342.7 270.2l.5 .1 .1 .7 .1-.1-.1 .2-.2-.1-.3 .1-.2-.1v-.1l.3 .1 .2-.1v-.3l-.5 .3 .5-.4-.2-.3-.3 .3z" fill-rule="evenodd"/>
<path d="M343.5 270.3l.3-.1v.2a.29 .29 0 0 1 .3-.2 .29 .29 0 0 1 .2 .3v.5l.2 .1h-.5l.2-.2v-.5l-.2-.1-.2 .1v.6l.1 .1h-.4l.1-.1v-.6z" fill-rule="evenodd"/>
<path d="M344.6 270.3l.3-.1v.8l.1 .1h-.4l.1-.1v-.5v-.2z" fill-rule="evenodd"/>
<path d="M345.3 270.3l.4-.1 .2 .2 .1 .1h-.7l.2 .4 .3 .1 .1-.2a.41 .41 0 0 1-.5 .3 .41 .41 0 0 1-.2-.6h.5l-.2-.3-.3 .3z" fill-rule="evenodd"/>
<path d="M346.1 269.8l.3-.1v1.3l.2 .1h-.5l.1-.1v-1.1z" fill-rule="evenodd"/>
<path d="M347.2 269.7h.5l-.1 .1-.1 .6 .6-.5-.1-.2h.5l-.8 .7 1 .7h-.7l.1-.1-.6-.6 .1 .6 .1 .1h-.5l.2-.2-.1-1z" fill-rule="evenodd"/>
<path d="M348.8 270.2l.6 .1v.7l.2-.1-.2 .2-.2-.1-.3 .1-.2-.1v-.1l.3 .1 .2-.1v-.3l-.5 .3 .5-.4-.1-.3-.3 .3z" fill-rule="evenodd"/>
<path d="M349.6 270.3l.3-.1v.2l.4-.2a.29 .29 0 0 0 .5 0l.2 .1 .1 .7 .1 .1h-.5l.2-.1v-.5a.2 .2 0 0 0-.2-.2 .2 .2 0 0 0-.2 .2v.5l.1 .1h-.4l.1-.1v-.5l-.1-.2-.3 .1v.6l.2 .1h-.5l.1-.1v-.5v-.2z" fill-rule="evenodd"/>
<path d="M351.2 270.3l.3-.1v.2a.39 .39 0 0 1 .6-.1 .39 .39 0 0 1 0 .5l-.2 .3h-.4v.4l.2 .1h-.5l.2-.2v-1h.1l.1 .6a.33 .33 0 0 0 .4-.3 .33 .33 0 0 0-.4-.3h-.2z" fill-rule="evenodd"/>
<path d="M352.4 270.3l.4-.1 .3 .2v.1h-.6l.1 .4 .3 .1 .2-.2a.41 .41 0 0 1-.6 .3 .41 .41 0 0 1-.1-.6h.5l-.2-.3-.3 .3z" fill-rule="evenodd"/>
<path d="M353.2 270.3l.3-.1v.2l.2-.2h.2l-.4 .3v.5l.2 .1h-.5l.1-.1 .1-.5-.1-.2z" fill-rule="evenodd"/>
<path d="M354.2 269.9v.3h.2h-.2v.7h.3l-.3 .2-.1-.1-.1-.8h-.1z" fill-rule="evenodd"/>
<circle cx="344.8" cy="269.8" r=".1"/>
</g>
<path d="M332 264h-34.5v10.5h34.5" fill="none" stroke="#000" stroke-width=".18"/>
<g fill="#00007f">
<path d="M299.2 269.7h1l-.9 1.3h.7l.2-.3v.4h-1.2l.9-1.3h-.6l-.2 .3z" fill-rule="evenodd"/>
<path d="M300.5 269.8l.7-.1v.5a.29 .29 0 0 0-.3-.4 .29 .29 0 0 0-.2 .4h.1a.51 .51 0 0 1 .4 .3 .51 .51 0 0 1 0 .5l-.8 .2 .1-.5a.33 .33 0 0 0 .3 .4 .33 .33 0 0 0 .3-.4l-.1-.1a.51 .51 0 0 1-.5-.2 .51 .51 0 0 1 0-.6z" fill-rule="evenodd"/>
<path d="M301.5 269.7h.5l-.1 .2 .3 .9 .2-.7-.3-.4h.6l-.2 .2 .3 .9 .3-.9-.1-.2h.4l-.2 .2-.4 1.3-.3-.9-.4 .9-.5-1.4z" fill-rule="evenodd"/>
<path d="M303.5 270.2l.5 .1v.7l.2-.1-.1 .2h-.2v-.1l-.3 .1-.2-.1-.1-.1 .4 .1 .2-.1v-.3l-.6 .3 .6-.4-.2-.3-.3 .3z" fill-rule="evenodd"/>
<path d="M304.5 269.9v.3h.3h-.3v.7h.3l-.3 .2-.1-.1v-.8h-.2z" fill-rule="evenodd"/>
<path d="M305 270.3l.4-.1 .2 .1-.1 .2a.28 .28 0 0 0-.4-.3 .28 .28 0 0 0-.1 .5 .3 .3 0 0 0 .3 .3 .3 .3 0 0 0 .3-.2 .43 .43 0 0 1-.6 .3 .43 .43 0 0 1-.1-.7z" fill-rule="evenodd"/>
<path d="M305.7 269.8l.3-.1v.7l.3-.2h.2l.1 .8 .1 .1h-.4l.1-.2v-.5l-.1-.1-.3 .1 .1 .6 .1 .1h-.5l.2-.1v-.9v-.3z" fill-rule="evenodd"/>
<path d="M306.8 270.6h.6v.1h-.6z" fill-rule="evenodd"/>
<path d="M307.5 269.7h.6a.7 .7 0 0 1 .8 .7 .7 .7 0 0 1-.8 .7h-.6l.2-.1v-1.2h.2v1.2a.65 .65 0 0 0 .7-.7 .65 .65 0 0 0-.9-.5z" fill-rule="evenodd"/>
<path d="M309.2 270.3a.46 .46 0 0 1 .7 .1 .46 .46 0 0 1-.3 .7 .46 .46 0 0 1-.6-.5h.2a.31 .31 0 0 0 .1 .4 .31 .31 0 0 0 .4-.1 .38 .38 0 0 0 0-.5 .38 .38 0 0 0-.4-.1l-.1 .3h-.2z" fill-rule="evenodd"/>
<path d="M310.2 270.3l.4-.1 .2 .1v.2a.28 .28 0 0 0-.4-.3 .28 .28 0 0 0-.1 .5 .3 .3 0 0 0 .2 .3 .3 .3 0 0 0 .4-.2 .43 .43 0 0 1-.7 .3 .43 .43 0 0 1 0-.7z" fill-rule="evenodd"/>
<path d="M311 269.8l.3-.1v.9l.3-.3v-.1h.4l-.5 .3 .5 .6h-.4v-.1l-.3-.4v.4l.1 .1h-.4l.1-.2v-1z" fill-rule="evenodd"/>
<path d="M312.5 269.8l.4-.1v.9l.3-.3-.1-.1h.4l-.5 .3 .6 .6h-.5l.1-.1-.3-.4v.4l.1 .1h-.5l.2-.2v-1z" fill-rule="evenodd"/>
<path d="M313.6 270.3l.4-.1v.8l.1 .1h-.4l.1-.1v-.5v-.2z" fill-rule="evenodd"/>
<path d="M314.4 270.3l.4-.1 .2 .1-.1 .2a.28 .28 0 0 0-.4-.3 .28 .28 0 0 0-.1 .5 .3 .3 0 0 0 .3 .3 .3 .3 0 0 0 .3-.2 .43 .43 0 0 1-.6 .3 .43 .43 0 0 1-.1-.7z" fill-rule="evenodd"/>
<path d="M315.3 270.2l.5 .1 .1 .7 .1-.1-.1 .2h-.1l-.1-.1-.3 .1-.2-.1v-.1l.3 .1 .2-.1v-.3l-.5 .3 .5-.4-.2-.3-.3 .3z" fill-rule="evenodd"/>
<path d="M316.6 269.8l.3-.1v1.3h.2l-.6 .2-.3-.2-.1-.4h.2l.2 .4 .3-.1-.2-.7-.2 .1-.1 .3h-.2a.42 .42 0 0 1 .7-.4l-.1-.4z" fill-rule="evenodd"/>
<path d="M317.1 271.5l1 .1z" fill-rule="evenodd"/>
<path d="M318.1 270.3l.3-.1v.2a.39 .39 0 0 1 .6-.1 .39 .39 0 0 1 .1 .5l-.3 .3h-.4l.1 .4 .1 .1h-.5l.2-.2v-1h.1l.1 .6a.33 .33 0 0 0 .4-.3 .33 .33 0 0 0-.4-.3h-.2z" fill-rule="evenodd"/>
<path d="M319.4 270.3l.4-.1 .2 .1-.1 .2a.28 .28 0 0 0-.4-.3 .28 .28 0 0 0-.1 .5 .3 .3 0 0 0 .3 .3 .3 .3 0 0 0 .3-.2 .43 .43 0 0 1-.6 .3 .43 .43 0 0 1-.1-.7z" fill-rule="evenodd"/>
<path d="M320.1 269.8l.3-.1v.6a.43 .43 0 0 1 .7 .1 .43 .43 0 0 1-.3 .7l-.2 .1-.3-.2v-.6h.1v.6a.32 .32 0 0 0 .5-.3 .32 .32 0 0 0-.5-.3h-.1v-.5z" fill-rule="evenodd"/>
<circle cx="312.3" cy="271" r=".11"/>
<circle cx="313.9" cy="269.8" r=".1"/>
</g>
<path d="M366.5 253.5h-69v10.5" fill="none" stroke="#000" stroke-width=".18"/>
<g fill="#00f">
<path d="M299.2 254.6l.8 .1 .2 .4a.25 .25 0 0 0-.1 .2 .25 .25 0 0 0 .2 .2 .45 .45 0 0 1-.1 .5 .45 .45 0 0 1-.5 .1h-.5v-.2h.7l.2-.1-.1-.3-.6-.1v.5h-.2v-.7h.5a.24 .24 0 0 0 .3-.1 .24 .24 0 0 0-.2-.3h-.4v.4h-.2z" fill-rule="evenodd"/>
<path d="M300.6 255.1a.55 .55 0 0 1 .9 .1 .55 .55 0 0 1-.3 .8 .55 .55 0 0 1-.7-.4h.2a.36 .36 0 0 0 .4 .4 .36 .36 0 0 0 .2-.6l-.4-.2-.2 .4h-.2z" fill-rule="evenodd"/>
<path d="M301.8 255.2l.1-.2a.47 .47 0 0 1 .6 .1 .47 .47 0 0 1 .1 .6v.4h-.1l-.1-.1-.5 .1-.2-.1-.1-.2 .4 .2h.2l.2-.4-.8 .2a.57 .57 0 0 1 .8-.4 .28 .28 0 0 0-.2-.2 .28 .28 0 0 0-.3 .2l-.2-.1z" fill-rule="evenodd"/>
<path d="M302.9 255h.1v.2l.2-.2h.2v.2a.25 .25 0 0 0-.3 .1 .25 .25 0 0 0 0 .3v.5h-.2z" fill-rule="evenodd"/>
<path d="M303.7 255.1l.3-.1 .3 .2v-.6h.1v1.5h-.1v-.1a.45 .45 0 0 1-.6 .1 .45 .45 0 0 1-.2-.5h.2a.34 .34 0 0 0 .4 .4 .34 .34 0 0 0 .2-.6l-.4-.2-.2 .4h-.2z" fill-rule="evenodd"/>
<path d="M305.3 254.6h.2l.8 1.2v-1.2h.2v1.5h-.2l-.8-1.2v1.2h-.2z" fill-rule="evenodd"/>
<path d="M306.9 255.2l.1-.2a.47 .47 0 0 1 .6 .1 .47 .47 0 0 1 .1 .6l.1 .4h-.2l-.1-.1-.4 .1-.3-.1v-.2l.3 .2h.3l.1-.4-.7 .2a.57 .57 0 0 1 .7-.4 .28 .28 0 0 0-.2-.2 .28 .28 0 0 0-.3 .2l-.2-.1z" fill-rule="evenodd"/>
<path d="M308 255h.2v.2l.2-.2 .4 .2 .3-.2 .2 .1 .2 .2v.8h-.2v-.7a.24 .24 0 0 0-.3-.2 .24 .24 0 0 0-.2 .3v.6h-.2v-.7a.25 .25 0 0 0-.3-.2 .25 .25 0 0 0-.1 .4v.5h-.2z" fill-rule="evenodd"/>
<path d="M309.8 255.2a.51 .51 0 0 1 .6-.1 .51 .51 0 0 1 .3 .5h-.8l.2 .4 .6-.2a.52 .52 0 0 1-.7 .3 .52 .52 0 0 1-.3-.6h.8l-.2-.3a.31 .31 0 0 0-.4 .3h-.2z" fill-rule="evenodd"/>
<path d="M311 255h.2v.2h-.2z" fill-rule="evenodd"/>
<path d="M311 255.9h.2v.2h-.2z" fill-rule="evenodd"/>
<path d="M368 244.1h.2l.5 1.4 .5-1.4h.2l-.6 1.5h-.2z" fill-rule="evenodd"/>
<path d="M369.6 244.6l.1-.1a.47 .47 0 0 1 .5 .1 .47 .47 0 0 1 .1 .6l.1 .4h-.2v-.1l-.5 .1-.3-.1v-.2l.6 .2 .2-.4-.8 .2a.57 .57 0 0 1 .8-.4 .28 .28 0 0 0-.3-.2 .28 .28 0 0 0-.3 .2l-.2-.1z" fill-rule="evenodd"/>
<path d="M370.5 244.5h.2v.2l.2-.2h.2v.2a.25 .25 0 0 0-.3 .1 .25 .25 0 0 0-.1 .3v.5h-.2z" fill-rule="evenodd"/>
<path d="M371.2 244.1h.2v.2h-.2z" fill-rule="evenodd"/>
<path d="M371.2 244.5h.2v1.1h-.2z" fill-rule="evenodd"/>
<path d="M371.8 244.6l.1-.1a.47 .47 0 0 1 .6 .1 .47 .47 0 0 1 .1 .6l.1 .4h-.2l-.1-.1-.5 .1-.2-.1v-.2l.3 .2h.3l.1-.4-.7 .2a.57 .57 0 0 1 .7-.4 .28 .28 0 0 0-.2-.2 .28 .28 0 0 0-.3 .2l-.2-.1z" fill-rule="evenodd"/>
<path d="M372.9 244.5h.1v.2l.2-.2a.37 .37 0 0 1 .4 .1 .37 .37 0 0 1 .2 .4v.6h-.2v-.6a.27 .27 0 0 0-.3-.3 .27 .27 0 0 0-.2 .3v.6h-.2z" fill-rule="evenodd"/>
<path d="M374.1 244.3l.2-.1v.3h.2v.2h-.2v.6l.2 .3a.27 .27 0 0 1-.3 0 .27 .27 0 0 1-.1-.3v-.6h-.2z" fill-rule="evenodd"/>
<path d="M374.7 244.5h.2v.2h-.2z" fill-rule="evenodd"/>
<path d="M374.7 245.4h.2v.2h-.2z" fill-rule="evenodd"/>
</g>
<path d="M408 243h-41.5v10.5" fill="none" stroke="#000" stroke-width=".18"/>
<g fill="#00007f">
<path d="M368 248.7h.5a.42 .42 0 0 1 .6 .5 .42 .42 0 0 1-.7 .3v.5l.2 .1h-.6l.2-.1v-1.2h.2v.6a.31 .31 0 0 0 .5-.3 .31 .31 0 0 0-.5-.3z" fill-rule="evenodd"/>
<path d="M369.2 248.7h.8l.2 .2a.35 .35 0 0 1 .1 .3 .35 .35 0 0 1-.4 .2l.7 .7h-.4l-.5-.6h-.1v.5l.2 .1h-.6l.2-.1v-1.2h.2v.6a.32 .32 0 0 0 .5-.3 .32 .32 0 0 0-.5-.3z" fill-rule="evenodd"/>
<path d="M370.6 248.7h1.1v.3l-.2-.2h-.5v.6l.4-.1 .2-.1v.4l-.2-.1-.4-.1 .1 .6a.51 .51 0 0 0 .7-.2l-.1 .3h-1.1l.2-.2v-1z" fill-rule="evenodd"/>
<path d="M371.9 248.7h.6l-.2 .2v1a.48 .48 0 0 0 .8-.2l-.1 .4h-1.1l.2-.2v-1z" fill-rule="evenodd"/>
<path d="M373.2 248.7h.6l-.2 .3v1l.2 .1h-.6l.2-.2v-1z" fill-rule="evenodd"/>
<path d="M373.9 248.7h.4l.5 1.1 .5-1.1h.4l-.2 .3v1l.2 .1h-.6l.2-.1v-1l-.6 1.1-.5-1.1v1l.1 .1h-.4l.2-.2v-1z" fill-rule="evenodd"/>
<path d="M375.7 248.7h.6l-.2 .3v1l.2 .1h-.6l.2-.2v-1z" fill-rule="evenodd"/>
<path d="M376.4 248.7h.3l.9 1.1v-1l-.2-.1h.5l-.2 .2v1.2l-1-1.1v1l.2 .1h-.5l.2-.1v-1.1z" fill-rule="evenodd"/>
<path d="M378.6 248.7l.6 1.3 .2 .1h-.5l.1-.1-.1-.3h-.6l-.1 .3 .2 .1h-.5l.4-.5h.5l-.2-.6-.3 .6z" fill-rule="evenodd"/>
<path d="M379.5 248.7h.7l.3 .2a.35 .35 0 0 1 0 .3 .35 .35 0 0 1-.3 .2l.6 .7h-.3l-.5-.6h-.1v.5l.2 .1h-.6l.2-.1-.1-1.2h.3v.6a.32 .32 0 0 0 .4-.3 .32 .32 0 0 0-.4-.3z" fill-rule="evenodd"/>
<path d="M380.7 248.7h.6l-.1 .2 .3 .5 .3-.5-.1-.2h.5l-.6 .8v.5l.2 .1h-.6l.1-.1 .1-.4z" fill-rule="evenodd"/>
</g>
<path d="M366.5 243h-69v10.5" fill="none" stroke="#000" stroke-width=".18"/>
<g fill="#00f">
<path d="M299.3 244.3l.4-.2h.3l.4 .3v.1l-.2 .1a.53 .53 0 0 0-.8-.2 .53 .53 0 0 0 0 .8l.4 .3 .3-.1 .1-.3h.2a.72 .72 0 0 1-1 .4 .72 .72 0 0 1-.2-1.1z" fill-rule="evenodd"/>
<path d="M300.8 244.6a.54 .54 0 0 1 .8 .1 .54 .54 0 0 1-.3 .8 .54 .54 0 0 1-.7-.3v-.1h.2a.36 .36 0 0 0 .4 .4 .36 .36 0 0 0 .2-.6l-.4-.2-.2 .4h-.2z" fill-rule="evenodd"/>
<path d="M301.8 244.5h.2v.2l.4-.2 .2 .2 .3-.2 .3 .1 .1 .2v.8h-.2v-.7a.24 .24 0 0 0-.3-.2 .24 .24 0 0 0-.1 .3v.6h-.2v-.7a.25 .25 0 0 0-.4-.2 .25 .25 0 0 0-.1 .4v.5h-.2z" fill-rule="evenodd"/>
<path d="M303.6 244.5h.1v.2a.5 .5 0 0 1 .8 .4 .5 .5 0 0 1-.7 .4v.5h-.2v-.9h.1a.33 .33 0 0 0 .4 .4 .33 .33 0 0 0 .2-.5l-.1-.3h-.2l-.3 .4h-.1z" fill-rule="evenodd"/>
<path d="M304.8 244.6l.1-.1a.47 .47 0 0 1 .6 .1 .47 .47 0 0 1 .1 .6l.1 .4h-.2l-.1-.1-.4 .1-.3-.1v-.2l.3 .2h.3l.1-.4-.7 .2a.57 .57 0 0 1 .7-.4 .28 .28 0 0 0-.2-.2 .28 .28 0 0 0-.3 .2l-.2-.1z" fill-rule="evenodd"/>
<path d="M305.9 244.5h.2v.2l.1-.2a.37 .37 0 0 1 .5 .1 .37 .37 0 0 1 .1 .4v.6h-.2v-.6a.27 .27 0 0 0-.3-.3 .27 .27 0 0 0-.2 .3v.6h-.2z" fill-rule="evenodd"/>
<path d="M307 244.5h.2l.3 .9 .3-.9h.2l-.5 1.1a.38 .38 0 0 1-.4 .4l-.1-.1 .3-.1 .1-.2z" fill-rule="evenodd"/>
<path d="M308.2 244.5h.2v.2h-.2z" fill-rule="evenodd"/>
<path d="M308.2 245.4h.2v.2h-.2z" fill-rule="evenodd"/>
</g>
<g fill="#00007f">
<path d="M299.2 248.7h1.1l-.8 1.3a.68 .68 0 0 0 .9-.4l-.1 .5h-1.3l.9-1.3a.54 .54 0 0 0-.8 .3z" fill-rule="evenodd"/>
<path d="M300.6 248.8l.8-.1v.5l-.4-.4-.3 .2 .2 .2a.5 .5 0 0 1 .6 .3 .5 .5 0 0 1-.3 .6l-.7 .1v-.6a.35 .35 0 0 0 .3 .5 .35 .35 0 0 0 .4-.3l-.2-.2a.46 .46 0 0 1-.4-.3 .46 .46 0 0 1 0-.5z" fill-rule="evenodd"/>
<path d="M301.6 248.7h.6l-.1 .2 .3 .8 .2-.5-.3-.5h.7l-.2 .1 .3 .8 .3-.7-.1-.2 .3 .1-.6 1.4-.4-.9-.4 .9z" fill-rule="evenodd"/>
<path d="M303.7 249.3l.4-.2 .3 .1v.8h.2l-.1 .1h-.3l-.1-.1-.2 .1-.2-.1v-.1h.4v-.3l-.2 .3h-.2l.4-.4v-.2h-.2a.15 .15 0 0 1 0 .2 .15 .15 0 0 1-.2 0 .15 .15 0 0 1 0-.2z" fill-rule="evenodd"/>
<path d="M305 248.8v.4h.3l-.3 .1 .1 .7 .2-.1-.2 .2a.26 .26 0 0 1-.3-.3v-.5l-.2-.1z" fill-rule="evenodd"/>
<path d="M305.5 249.3l.2-.2a.23 .23 0 0 1 .4 .1 .23 .23 0 0 1-.1 .3l-.2-.3a.37 .37 0 0 0-.1 .5 .37 .37 0 0 0 .5 .2 .47 .47 0 0 1-.8 .1 .47 .47 0 0 1 .1-.7z" fill-rule="evenodd"/>
<path d="M306.3 248.7h.4v.6l.2-.2a.29 .29 0 0 1 .3 .4l.1 .6h-.4v-.2v-.6l-.2 .1 .1 .7h-.5l.1-.2z" fill-rule="evenodd"/>
<path d="M368.7 259h1.5l-1.1 1.7a.91 .91 0 0 0 1.2-.5l-.1 .6h-1.7l1.1-1.7a.73 .73 0 0 0-.9 .4z" fill-rule="evenodd"/>
<path d="M370.7 259.1l.4-.2 .4 .2 .2-.2-.1 .7a.43 .43 0 0 0-.3-.6 .43 .43 0 0 0-.5 .3l.2 .2a.95 .95 0 0 1 .8 .9 .88 .88 0 0 1-1.2 .4l-.1 .1 .1-.7a.48 .48 0 0 0 .3 .5 .48 .48 0 0 0 .6-.3l-.2-.2a.72 .72 0 0 1-.7-1z" fill-rule="evenodd"/>
<path d="M371.9 259h.8l-.1 .2 .4 1 .3-.7-.4-.5h.9l-.2 .1 .4 1.1 .4-1-.2-.2h.5l-.2 .1-.6 1.8-.5-1.2-.6 1.2z" fill-rule="evenodd"/>
<path d="M374.8 259.7l.1-.1a.5 .5 0 0 1 .6-.1 .5 .5 0 0 1 .2 .5l.1 .6h.1a.29 .29 0 0 1-.3 .3 .29 .29 0 0 1-.2-.3 .33 .33 0 0 1-.4 .3 .33 .33 0 0 1-.3-.4h.4l.1 .1 .2-.1v-.4l-.3 .4h-.4l.7-.5-.1-.3h-.3a.2 .2 0 0 1 .1 .3 .2 .2 0 0 1-.3 0 .2 .2 0 0 1 0-.3z" fill-rule="evenodd"/>
<path d="M376.5 259.1l.1 .5h.3v.1h-.3v.9h.2a.34 .34 0 0 1-.4 .2 .34 .34 0 0 1-.2-.4v-.7l-.2-.1z" fill-rule="evenodd"/>
<path d="M377.2 259.7a.4 .4 0 0 1 .5-.2 .4 .4 0 0 1 .2 .5h-.2l-.1-.4a.52 .52 0 0 0-.2 .7 .52 .52 0 0 0 .7 .2 .62 .62 0 0 1-1 .2 .62 .62 0 0 1 0-.9z" fill-rule="evenodd"/>
<path d="M378.2 259h.6v.7a.4 .4 0 0 1 .5-.2 .4 .4 0 0 1 .2 .6v.6l.1 .1h-.6l.1-.2v-.8l-.1-.1-.2 .2v.8l.1 .1h-.7l.2-.2v-1.5z" fill-rule="evenodd"/>
<path d="M380.4 259h.9a.93 .93 0 0 1 1 .9 .93 .93 0 0 1-1 .9h-.9l.3-.1v-.2h.4l.1 .2a.57 .57 0 0 0 .6-.8 .64 .64 0 0 0-.7-.8v1.4h-.4v-1.3z" fill-rule="evenodd"/>
<path d="M382.8 259.6a.63 .63 0 0 1 .8 .2 .63 .63 0 0 1-.1 .9 .63 .63 0 0 1-.9-.1l-.1-.3h.4v.3a.18 .18 0 0 0 .2 .2 .18 .18 0 0 0 .2-.2v-.8a.19 .19 0 0 0-.3-.2 .19 .19 0 0 0-.1 .3v.4h-.4z" fill-rule="evenodd"/>
<path d="M384.1 259.7a.4 .4 0 0 1 .5-.2 .4 .4 0 0 1 .3 .5h-.2l-.2-.4a.52 .52 0 0 0-.2 .7 .52 .52 0 0 0 .7 .2 .62 .62 0 0 1-.9 .2 .62 .62 0 0 1 0-.9z" fill-rule="evenodd"/>
<path d="M385.1 259h.6v1.2l.4-.5-.1-.1h.5l-.5 .4 .6 .8h-.6l.1-.1-.3-.5-.1 .5 .1 .1h-.7l.2-.2v-1.5z" fill-rule="evenodd"/>
<path d="M299.5 258.7h1.1a1.17 1.17 0 0 1 1.3 1.2 1.17 1.17 0 0 1-1.3 1.1h-1.1l.3-.1 .1-.2h.5v.1a.53 .53 0 0 0 .7 0 .53 .53 0 0 0 .1-.6 .93 .93 0 0 0-.8-1.4v1.9h-.5v-1.7z" fill-rule="evenodd"/>
<path d="M302.5 259.5a.79 .79 0 0 1 1.1 .8 .79 .79 0 0 1-1.3 .5l-.1-.4h.5v.3a.22 .22 0 0 0 .2 .3 .22 .22 0 0 0 .2-.2v-1.1a.23 .23 0 0 0-.3-.2 .23 .23 0 0 0-.1 .3v.6h-.5v-.5z" fill-rule="evenodd"/>
<path d="M304.2 259.6a.53 .53 0 0 1 .6-.2 .53 .53 0 0 1 .3 .6 .38 .38 0 0 1-.5-.5 .42 .42 0 0 0-.2 .7 .51 .51 0 0 0 .3 .6 .51 .51 0 0 0 .5-.1 .76 .76 0 0 1-1 .2 .76 .76 0 0 1-.2-1.1z" fill-rule="evenodd"/>
<path d="M305.4 258.7h.7v1.5l.5-.5-.1-.3h.7l-.7 .6 .8 1h-.8l.1-.1-.4-.6-.1 .6 .2 .1h-.9l.2-.3v-1.8z" fill-rule="evenodd"/>
<path d="M307.4 260.1h1v.3h-1z" fill-rule="evenodd"/>
<path d="M308.5 258.7h1.2l-.3 .2v.9h.8v-.9l-.3-.2h1.2l-.3 .1v.3v1.7l.3 .2h-1.2l.3-.1v-1h-.8v1l.3 .1h-1.2l.3-.1v-.3v-1.6z" fill-rule="evenodd"/>
<path d="M311.2 258.7h1l-.2 .3 .5 1.3 .4-.9-.2-.5-.3-.2h1.1l-.2 .2 .5 1.3 .4-1.2v-.1l-.2-.2 .6 .1-.2 .1-.8 2.2-.6-1.5-.7 1.5-.9-2.2z" fill-rule="evenodd"/>
</g>
<path d="M263 274.5h34.5M297.5 264h-34.5v21" fill="none" stroke="#000" stroke-width=".18"/>
<g fill="#00f">
<path d="M299.2 265.1h1v.2h-.8v.5h.7v.1h-.7v.7h-.2z" fill-rule="evenodd"/>
<path d="M300.4 265.1h.2v.2h-.2z" fill-rule="evenodd"/>
<path d="M300.4 265.5h.2v1.1h-.2z" fill-rule="evenodd"/>
<path d="M300.9 265.1h.2v1.5h-.2z" fill-rule="evenodd"/>
<path d="M301.4 265.7a.51 .51 0 0 1 .6-.1 .51 .51 0 0 1 .3 .5h-.8l.2 .4 .6-.2a.52 .52 0 0 1-.7 .3 .52 .52 0 0 1-.3-.6h.8l-.2-.3a.31 .31 0 0 0-.4 .3h-.2z" fill-rule="evenodd"/>
<path d="M303.1 265.1h.2l.8 1.2v-1.2h.2v1.5h-.2l-.8-1.2v1.2h-.2z" fill-rule="evenodd"/>
<path d="M304.7 265.6l.1-.1a.47 .47 0 0 1 .6 .1 .47 .47 0 0 1 .1 .6l.1 .4h-.2l-.1-.1-.5 .1-.2-.1v-.2l.6 .2 .1-.4-.7 .2a.57 .57 0 0 1 .7-.4 .28 .28 0 0 0-.2-.2 .28 .28 0 0 0-.3 .2l-.2-.1z" fill-rule="evenodd"/>
<path d="M305.8 265.5h.1v.2l.5-.2 .2 .2 .2-.2 .3 .1 .2 .2v.8h-.2v-.7a.24 .24 0 0 0-.3-.2 .24 .24 0 0 0-.2 .3v.6h-.2v-.7a.25 .25 0 0 0-.3-.2 .25 .25 0 0 0-.1 .4v.5h-.2z" fill-rule="evenodd"/>
<path d="M307.6 265.7a.51 .51 0 0 1 .6-.1 .51 .51 0 0 1 .3 .5h-.8l.2 .4 .6-.2a.52 .52 0 0 1-.7 .3 .52 .52 0 0 1-.3-.6h.8l-.2-.3a.31 .31 0 0 0-.4 .3h-.2z" fill-rule="evenodd"/>
<path d="M308.8 265.5h.2v.2h-.2z" fill-rule="evenodd"/>
<path d="M308.8 266.4h.2v.2h-.2z" fill-rule="evenodd"/>
<path d="M264.8 265.2l.3-.1h.4l.2 .4-.1 .1a.32 .32 0 0 0-.4-.4 .32 .32 0 0 0-.3 .5h.1a.57 .57 0 0 1 .8 .7 .64 .64 0 0 1-.7 .2 .64 .64 0 0 1-.5-.5h.2a.39 .39 0 0 0 .4 .4 .39 .39 0 0 0 .4-.4l-.3-.1a.49 .49 0 0 1-.5-.2 .49 .49 0 0 1 0-.6z" fill-rule="evenodd"/>
<path d="M266 265.1h.2v.6l.3-.2 .4 .2v.9h-.2v-.7a.27 .27 0 0 0-.3-.2 .27 .27 0 0 0-.2 .3v.6h-.2z" fill-rule="evenodd"/>
<path d="M267.3 265.7a.51 .51 0 0 1 .6-.1 .51 .51 0 0 1 .2 .5h-.8l.3 .4 .5-.2a.52 .52 0 0 1-.6 .3 .52 .52 0 0 1-.3-.6h.8l-.2-.3a.31 .31 0 0 0-.5 .3h-.1z" fill-rule="evenodd"/>
<path d="M268.5 265.7a.51 .51 0 0 1 .6-.1 .51 .51 0 0 1 .2 .5h-.8l.2 .4 .6-.2a.52 .52 0 0 1-.6 .3 .52 .52 0 0 1-.4-.6h.8l-.2-.3a.31 .31 0 0 0-.4 .3h-.2z" fill-rule="evenodd"/>
<path d="M269.6 265.3l.2-.1v.3h.1v.2h-.1v.6l.2 .3a.27 .27 0 0 1-.3 0 .27 .27 0 0 1-.1-.3v-.6h-.2z" fill-rule="evenodd"/>
<path d="M270.6 265.1h1.2v.2h-.5v1.3h-.2v-1.3h-.5z" fill-rule="evenodd"/>
<path d="M271.9 265.1h.2v.2h-.2z" fill-rule="evenodd"/>
<path d="M271.9 265.5h.2v1.1h-.2z" fill-rule="evenodd"/>
<path d="M272.4 265.3l.2-.1v.3h.1v.2h-.1v.6l.2 .3a.27 .27 0 0 1-.3 0 .27 .27 0 0 1-.1-.3v-.6h-.2z" fill-rule="evenodd"/>
<path d="M272.9 265.1h.2v1.5h-.2z" fill-rule="evenodd"/>
<path d="M273.5 265.7a.51 .51 0 0 1 .6-.1 .51 .51 0 0 1 .2 .5h-.8l.3 .4 .5-.2a.52 .52 0 0 1-.6 .3 .52 .52 0 0 1-.4-.6h.8l-.1-.3a.31 .31 0 0 0-.5 .3h-.2z" fill-rule="evenodd"/>
<path d="M274.6 265.5h.2v.2h-.2z" fill-rule="evenodd"/>
<path d="M274.6 266.4h.2v.2h-.2z" fill-rule="evenodd"/>
<path d="M264.8 275.7l.3-.1h.4l.2 .4-.1 .1a.32 .32 0 0 0-.4-.4 .32 .32 0 0 0-.3 .5h.1a.57 .57 0 0 1 .8 .6 .64 .64 0 0 1-.7 .3 .64 .64 0 0 1-.5-.5h.2a.39 .39 0 0 0 .4 .4 .39 .39 0 0 0 .4-.4l-.3-.1a.49 .49 0 0 1-.5-.2 .49 .49 0 0 1 0-.6z" fill-rule="evenodd"/>
<path d="M266 275.6h.2v.6l.3-.2 .4 .2v.9h-.2v-.7a.27 .27 0 0 0-.3-.2 .27 .27 0 0 0-.2 .3v.6h-.2z" fill-rule="evenodd"/>
<path d="M267.3 276.2a.51 .51 0 0 1 .6-.1 .51 .51 0 0 1 .2 .5h-.8l.3 .4 .5-.2a.52 .52 0 0 1-.6 .3 .52 .52 0 0 1-.3-.6h.8l-.2-.3a.31 .31 0 0 0-.5 .3h-.1z" fill-rule="evenodd"/>
<path d="M268.5 276.2a.51 .51 0 0 1 .6-.1 .51 .51 0 0 1 .2 .5h-.8l.2 .4 .6-.2a.52 .52 0 0 1-.6 .3 .52 .52 0 0 1-.4-.6h.8l-.2-.3a.31 .31 0 0 0-.4 .3h-.2z" fill-rule="evenodd"/>
<path d="M269.6 275.8l.2-.1v.3h.1v.2h-.1v.6l.2 .3a.27 .27 0 0 1-.3 0 .27 .27 0 0 1-.1-.3v-.6h-.2z" fill-rule="evenodd"/>
<path d="M270.7 275.6h.6a.46 .46 0 0 1 .6 .5 .46 .46 0 0 1-.6 .4h-.4v.6h-.2v-.8h.6a.28 .28 0 0 0 .4-.2 .28 .28 0 0 0-.4-.3h-.4v.5h-.2z" fill-rule="evenodd"/>
<path d="M272.2 276.2l.1-.2a.47 .47 0 0 1 .6 .1 .47 .47 0 0 1 .1 .6v.4h-.1l-.1-.1-.5 .1-.2-.1-.1-.2 .4 .2h.2l.2-.4-.8 .2a.57 .57 0 0 1 .8-.4 .28 .28 0 0 0-.2-.2 .28 .28 0 0 0-.3 .2l-.2-.1z" fill-rule="evenodd"/>
<path d="M273.3 275.8l.2-.1v.3h.2v.2h-.2v.6l.2 .3a.27 .27 0 0 1-.3 0 .27 .27 0 0 1-.1-.3v-.6h-.1z" fill-rule="evenodd"/>
<path d="M273.9 275.6h.1v.6l.4-.2 .3 .1v1h-.1v-.7a.27 .27 0 0 0-.4-.2 .27 .27 0 0 0-.2 .3v.6h-.1z" fill-rule="evenodd"/>
<path d="M275.1 276h.2v.2h-.2z" fill-rule="evenodd"/>
<path d="M275.1 276.9h.2v.2h-.2z" fill-rule="evenodd"/>
</g>
<g fill="#00007f">
<path d="M264.6 269.7h1.1v.4l-.1-.2-.4-.1v1.2l.2 .1h-.6l.2-.1v-1.2h-.3l-.1 .3z" fill-rule="evenodd"/>
<path d="M265.9 270.3a.46 .46 0 0 1 .7 .1 .46 .46 0 0 1-.3 .7 .46 .46 0 0 1-.6-.5h.2a.31 .31 0 0 0 .1 .4 .31 .31 0 0 0 .4-.1 .37 .37 0 0 0 0-.5 .37 .37 0 0 0-.4-.1l-.1 .3h-.2z" fill-rule="evenodd"/>
<path d="M266.7 270.3l.3-.1v.2a.39 .39 0 0 1 .6-.1 .39 .39 0 0 1 0 .5l-.2 .3h-.4v.4l.2 .1h-.5l.1-.2v-1h.2v.6a.33 .33 0 0 0 .5-.3 .33 .33 0 0 0-.4-.3h-.3z" fill-rule="evenodd"/>
<path d="M268.3 269.7h1v.3l-.1-.2h-.5v.6l.3-.1 .2-.1v.4l-.2-.1-.3-.1v.6l.2 .1h-.6l.2-.2v-1z" fill-rule="evenodd"/>
<path d="M269.6 270.2l.6 .1v.7l.2-.1-.2 .2h-.1l-.1-.1-.3 .1-.2-.1v-.1l.3 .1 .2-.1v-.3l-.5 .3 .5-.4-.2-.3-.2 .3z" fill-rule="evenodd"/>
<path d="M270.4 269.8l.3-.1v.6a.43 .43 0 0 1 .7 .1 .43 .43 0 0 1-.3 .7l-.2 .1-.4-.2v-.6h.2v.6a.32 .32 0 0 0 .5-.3 .32 .32 0 0 0-.5-.3h-.2v-.5z" fill-rule="evenodd"/>
<path d="M271.4 270.3l.3-.1v.2l.2-.2h.2l-.4 .3 .1 .5 .1 .1h-.5l.2-.1v-.5v-.2z" fill-rule="evenodd"/>
<path d="M272.2 270.3l.3-.1v.8l.1 .1h-.4l.1-.1v-.6z" fill-rule="evenodd"/>
<path d="M272.9 270.3l.4-.1 .2 .1-.1 .2a.28 .28 0 0 0-.4-.3 .28 .28 0 0 0-.1 .5 .3 .3 0 0 0 .3 .3 .3 .3 0 0 0 .3-.2 .43 .43 0 0 1-.6 .3 .43 .43 0 0 1-.1-.7z" fill-rule="evenodd"/>
<path d="M273.8 270.2l.5 .1 .1 .7 .1-.1-.1 .2h-.1l-.1-.1-.3 .1-.2-.1v-.1l.3 .1 .2-.1v-.3l-.5 .3 .5-.4-.2-.3-.2 .3z" fill-rule="evenodd"/>
<path d="M274.9 269.9v.3h.2h-.2v.7h.2l-.2 .2-.2-.1v-.8h-.1z" fill-rule="evenodd"/>
<path d="M275.2 270.3l.3-.1v.8l.2 .1h-.5l.1-.1 .1-.5-.1-.2z" fill-rule="evenodd"/>
<path d="M276 270.3a.46 .46 0 0 1 .7 .1 .46 .46 0 0 1-.4 .7 .46 .46 0 0 1-.5-.5h.2a.31 .31 0 0 0 .1 .4 .31 .31 0 0 0 .4-.1 .38 .38 0 0 0 0-.5 .38 .38 0 0 0-.4-.1l-.1 .3h-.2z" fill-rule="evenodd"/>
<path d="M276.8 270.3l.3-.1v.2a.29 .29 0 0 1 .4-.2 .29 .29 0 0 1 .2 .3v.5l.1 .1h-.5l.2-.2v-.5l-.1-.1-.3 .1v.6l.2 .1h-.5l.1-.1v-.6z" fill-rule="evenodd"/>
<path d="M278.8 269.8l.2-.1a1.42 1.42 0 0 0 0 1.9l-.3-.2a1.12 1.12 0 0 1 .1-1.6z" fill-rule="evenodd"/>
<path d="M279.3 269.8l.7-.1v.5a.29 .29 0 0 0-.3-.4 .29 .29 0 0 0-.3 .4h.1a.51 .51 0 0 1 .5 .3 .51 .51 0 0 1 0 .5l-.8 .2v-.5a.33 .33 0 0 0 .3 .4 .33 .33 0 0 0 .4-.4l-.2-.1a.51 .51 0 0 1-.4-.2 .51 .51 0 0 1 0-.6z" fill-rule="evenodd"/>
<path d="M280.4 270.3l.4-.1 .2 .1-.1 .2a.28 .28 0 0 0-.3-.3 .28 .28 0 0 0-.1 .5 .3 .3 0 0 0 .2 .3 .3 .3 0 0 0 .3-.2 .43 .43 0 0 1-.6 .3 .43 .43 0 0 1 0-.7z" fill-rule="evenodd"/>
<path d="M281.3 270.2l.6 .1v.7l.2-.1-.2 .2h-.1l-.1-.1-.3 .1-.2-.1v-.1l.3 .1 .2-.1v-.3l-.5 .3 .5-.4-.1-.3-.3 .3z" fill-rule="evenodd"/>
<path d="M282.1 269.8l.4-.1v1.3l.1 .1h-.4l.1-.1v-.9v-.3z" fill-rule="evenodd"/>
<path d="M282.9 270.3l.3-.1 .3 .2v.1h-.6l.1 .4 .3 .1 .2-.2a.41 .41 0 0 1-.6 .3 .41 .41 0 0 1-.1-.6h.5l-.2-.3-.3 .3z" fill-rule="evenodd"/>
<path d="M284.4 269.9l.3-.2v1.3l.2 .1h-.5l.1-.1 .1-.9-.1-.2z" fill-rule="evenodd"/>
<path d="M286 269.9l.4-.2v1.3l.1 .1h-.5l.2-.1v-.9v-.2z" fill-rule="evenodd"/>
<path d="M286.8 269.7a1.08 1.08 0 0 1 0 1.9 1.42 1.42 0 0 0 0-1.9z" fill-rule="evenodd"/>
<circle cx="272.4" cy="269.8" r=".1"/>
<circle cx="275.4" cy="269.8" r=".1"/>
<circle cx="285.5" cy="270.3" r=".11"/>
<circle cx="285.5" cy="271" r=".11"/>
</g>
<path d="M297.5 243h-34.5v21" fill="none" stroke="#000" stroke-width=".18"/>
<g fill="#00f">
<path d="M264.8 244.3l.4-.2h.3l.4 .3v.1l-.2 .1a.53 .53 0 0 0-.8-.2 .53 .53 0 0 0 0 .8l.4 .3 .3-.1 .1-.3h.2a.72 .72 0 0 1-1 .4 .72 .72 0 0 1-.2-1.1z" fill-rule="evenodd"/>
<path d="M266.3 244.6a.54 .54 0 0 1 .8 .1 .54 .54 0 0 1-.3 .8 .54 .54 0 0 1-.7-.3v-.1h.2a.36 .36 0 0 0 .4 .4 .36 .36 0 0 0 .2-.6l-.4-.2-.2 .4h-.2z" fill-rule="evenodd"/>
<path d="M267.3 244.5h.2v.2l.4-.2 .2 .2 .3-.2 .3 .1 .1 .2v.8h-.2v-.7a.24 .24 0 0 0-.3-.2 .24 .24 0 0 0-.1 .3v.6h-.2v-.7a.25 .25 0 0 0-.4-.2 .25 .25 0 0 0-.1 .4v.5h-.2z" fill-rule="evenodd"/>
<path d="M269.1 244.5h.1v.2l.4-.2 .3 .2 .2-.2 .3 .1 .1 .2v.8h-.1v-.7a.24 .24 0 0 0-.3-.2 .24 .24 0 0 0-.2 .3v.6h-.2v-.7a.25 .25 0 0 0-.3-.2 .25 .25 0 0 0-.1 .4v.5h-.2z" fill-rule="evenodd"/>
<path d="M270.9 244.7a.51 .51 0 0 1 .6-.1 .51 .51 0 0 1 .3 .5h-.9l.3 .4 .6-.2a.52 .52 0 0 1-.7 .3 .52 .52 0 0 1-.3-.6h.8l-.2-.3a.31 .31 0 0 0-.4 .3h-.2z" fill-rule="evenodd"/>
<path d="M272 244.5h.1v.2l.2-.2a.37 .37 0 0 1 .4 .1 .37 .37 0 0 1 .2 .4v.6h-.2v-.6a.27 .27 0 0 0-.3-.3 .27 .27 0 0 0-.2 .3v.6h-.2z" fill-rule="evenodd"/>
<path d="M273.2 244.3l.2-.1v.3h.2v.2h-.2v.6l.2 .3a.27 .27 0 0 1-.3 0 .27 .27 0 0 1-.1-.3v-.6h-.2z" fill-rule="evenodd"/>
<path d="M273.8 244.6l.2-.1a.39 .39 0 0 1 .5 .3h-.2a.21 .21 0 0 0-.2-.2 .21 .21 0 0 0-.1 .3 .43 .43 0 0 1 .4 .1 .43 .43 0 0 1 .1 .4l-.2 .2h-.4l-.2-.3h.1a.24 .24 0 0 0 .3 .3 .24 .24 0 0 0 .2-.4 .43 .43 0 0 1-.6-.5z" fill-rule="evenodd"/>
<path d="M274.8 244.5h.2v.2h-.2z" fill-rule="evenodd"/>
<path d="M274.8 245.4h.2v.2h-.2z" fill-rule="evenodd"/>
</g>
<g fill="#00007f">
<path d="M264.7 248.7h1l-.9 1.3h.7l.2-.3v.4h-1.2l.9-1.3h-.6l-.1 .3z" fill-rule="evenodd"/>
<path d="M266 248.8l.7-.1v.5a.29 .29 0 0 0-.3-.4 .29 .29 0 0 0-.2 .4h.1a.51 .51 0 0 1 .4 .3 .51 .51 0 0 1 0 .5l-.8 .2 .1-.5a.33 .33 0 0 0 .3 .4 .33 .33 0 0 0 .3-.4l-.1-.1a.51 .51 0 0 1-.5-.2 .51 .51 0 0 1 0-.6z" fill-rule="evenodd"/>
<path d="M267 248.7h.5l-.1 .1 .3 1 .2-.7-.3-.4h.6l-.2 .2 .3 .9 .3-.9-.1-.2h.4l-.2 .2-.4 1.3-.3-.9-.4 .9-.5-1.4z" fill-rule="evenodd"/>
<path d="M269 249.2h.3l.2 .1v.7h.2l-.2 .1-.1-.1a.29 .29 0 0 1-.5 0l-.1-.1 .4 .1 .2-.1v-.3l-.6 .3 .6-.4-.2-.3-.3 .3z" fill-rule="evenodd"/>
<path d="M270 248.9v.3h.3h-.3v.7h.3l-.3 .2-.1-.1v-.8h-.2z" fill-rule="evenodd"/>
<path d="M270.5 249.3l.4-.1 .2 .1-.1 .2a.28 .28 0 0 0-.4-.3 .28 .28 0 0 0-.1 .5 .3 .3 0 0 0 .3 .3 .3 .3 0 0 0 .3-.2 .43 .43 0 0 1-.6 .3 .43 .43 0 0 1-.1-.7z" fill-rule="evenodd"/>
<path d="M271.2 248.8l.3-.1v.7l.3-.2h.2l.1 .8 .1 .1h-.4l.1-.2v-.5l-.1-.1-.3 .1 .1 .6 .1 .1h-.5l.2-.1v-.9v-.3z" fill-rule="evenodd"/>
</g>
<path d="M263 243h-42v42M297.5 243h69" fill="none" stroke="#000" stroke-width=".18"/>
<g fill="#000">
<path d="M17.1 17.5a5.9 5.9 0 0 1 2.7 .1 1.87 1.87 0 0 1 .9 2.2 1.87 1.87 0 0 1-2 1.4h-1.6l.4-.2 .1-.4h.9v.2a.65 .65 0 0 0 .7 .2 .65 .65 0 0 0 .4-.6 2.21 2.21 0 0 0-.5-2.7h-.6v2.9h-.9v-2.8l-.2-.2z" fill-rule="evenodd"/>
<path d="M21.7 18.8a1.31 1.31 0 0 1 2 .9 1.31 1.31 0 0 1-1.5 1.5l-.6-.4-.3-.7h.7l.1 .6a.35 .35 0 0 0 .3 .3 .35 .35 0 0 0 .4-.3v-1.7a.37 .37 0 0 0-.5-.3 .37 .37 0 0 0-.2 .5l-.1 .9h-.7v-.7z" fill-rule="evenodd"/>
<path d="M26.5 17.5h1.1v2.4l.8-.9v-.2l-.3-.2h1.2l-1.1 .9 1.3 1.7h-1.3l.1-.3-.6-.9-.1 .1v.8l.2 .3h-1.3l.2-.2 .1-.4v-2.9z" fill-rule="evenodd"/>
<path d="M29.6 19.6h1.6v.6h-1.6z" fill-rule="evenodd"/>
<path d="M31.4 17.5h2l-.5 .2-.1 1.4h1.3v-1.4l-.5-.2h2l-.5 .2-.1 .4v2.7l.2 .2 .4 .2h-2l.5-.3v-1.5h-1.3l.1 1.5 .5 .3h-2l.5-.2v-.5v-2.7l-.1-.2z" fill-rule="evenodd"/>
<path d="M35.7 17.5h1.6l-.3 .2v.2l.8 2.1 .6-1.4a1.18 1.18 0 0 0-.7-1.1h1.8l-.4 .2 .8 2.2 .7-1.9v-.3l-.4-.2h1l-.3 .3-1.3 3.4h-.1l-1-2.3-1.1 2.3-1.4-3.4z" fill-rule="evenodd"/>
<path d="M42.7 17.5h3.1v1h-.1a.94 .94 0 0 0-1.3-.8h-.3v1.5l.6-.2 .4-.6v1.9h-.1a.79 .79 0 0 0-.9-.9v1.5l.5 .3h-1.9l.4-.2 .1-.5v-2.7l-.2-.2z" fill-rule="evenodd"/>
<path d="M46.4 18.9a1.05 1.05 0 0 1 1.2-.4 1.05 1.05 0 0 1 .7 1v1.2h.3a.52 .52 0 0 1-.5 .5 .52 .52 0 0 1-.5-.4 .75 .75 0 0 1-.7 .4 .75 .75 0 0 1-.7-.4l.1-.4h.7l.3 .3 .3-.1v-.9l-.5 .4-.1 .3h-.7l.4-.4 .9-.4v-.6a.33 .33 0 0 0-.5-.3 .33 .33 0 0 0-.1 .6 .39 .39 0 0 1-.6 .3 .39 .39 0 0 1 0-.7z" fill-rule="evenodd"/>
<path d="M48.9 17.5h1v1.4a1.05 1.05 0 0 1 1.4-.1 1.05 1.05 0 0 1 .3 1.3 1.17 1.17 0 0 1-.7 1 1.17 1.17 0 0 1-1.2-.1l-.5 .2v-2.1h.7l.1 1.6a.4 .4 0 0 0 .4 .4 .4 .4 0 0 0 .4-.4v-1.3a.46 .46 0 0 0-.3-.5 .46 .46 0 0 0-.6 .2h-.7v-1.3z" fill-rule="evenodd"/>
<path d="M52.1 18.6h1v.6l.2-.3a.49 .49 0 0 1 .5-.4 .49 .49 0 0 1 .5 .4 .39 .39 0 0 1-.3 .4 .39 .39 0 0 1-.5-.2l-.3 .3-.1 1.2a.46 .46 0 0 0 .4 .6h-1.4l.2-.2 .1-.4v-1.6z" fill-rule="evenodd"/>
<path d="M54.5 18.6h1l.1 2.3 .3 .3h-1.4l.2-.2 .1-.4v-1.7z" fill-rule="evenodd"/>
<path d="M58.9 18.9a1.05 1.05 0 0 1 1.1-.4 1.05 1.05 0 0 1 .8 1v1.2h.2a.52 .52 0 0 1-.5 .5 .52 .52 0 0 1-.5-.4 .75 .75 0 0 1-.6 .4 .75 .75 0 0 1-.7-.4v-.4h.7l.3 .3 .3-.1v-.9l-.5 .4-.1 .3h-.7l.4-.4 .9-.4v-.6a.33 .33 0 0 0-.5-.3 .33 .33 0 0 0 0 .6 .39 .39 0 0 1-.6 .3 .39 .39 0 0 1 0-.7z" fill-rule="evenodd"/>
<path d="M62.3 17.7l.1 .9h.6v.3h-.6v1.8l.2 .2 .3-.3a.68 .68 0 0 1-.8 .6 .68 .68 0 0 1-.5-.9v-1.4h-.3v-.1z" fill-rule="evenodd"/>
<path d="M63.2 18.6h1.1v2.3l.3 .3h-1.4l.2-.2 .1-.4v-1.7z" fill-rule="evenodd"/>
<path d="M65.3 18.8a1.31 1.31 0 0 1 1.9 .9 1.31 1.31 0 0 1-1.5 1.5l-.6-.4-.3-.7h.8l.1 .6a.35 .35 0 0 0 .3 .3 .35 .35 0 0 0 .4-.3v-1.7a.37 .37 0 0 0-.5-.3 .37 .37 0 0 0-.2 .5l-.1 .9h-.8l.1-.7z" fill-rule="evenodd"/>
<path d="M67.6 18.6h1.1v.4a.79 .79 0 0 1 1-.4 .79 .79 0 0 1 .4 1v1.3l.3 .3h-1.3l.2-.3v-1.7a.28 .28 0 0 0-.2-.3 .28 .28 0 0 0-.3 .2l-.1 .2v1.6l.2 .3h-1.3l.2-.2 .1-.4v-1.7z" fill-rule="evenodd"/>
<path d="M72 17.5a5.9 5.9 0 0 1 2.7 .1 1.87 1.87 0 0 1 1 2.2 1.87 1.87 0 0 1-2 1.4h-1.7l.4-.2 .1-.4h.9v.2a.65 .65 0 0 0 .7 .2 .65 .65 0 0 0 .5-.6 2.21 2.21 0 0 0-.5-2.7h-.7v2.9h-.9v-2.8l-.1-.2z" fill-rule="evenodd"/>
<path d="M76.7 18.8a1.31 1.31 0 0 1 1.9 .9 1.31 1.31 0 0 1-1.5 1.5l-.6-.4-.3-.7h.8v.6a.35 .35 0 0 0 .3 .3 .35 .35 0 0 0 .4-.3v-1.7a.37 .37 0 0 0-.5-.3 .37 .37 0 0 0-.2 .5v.9h-.8l.1-.7z" fill-rule="evenodd"/>
<path d="M81.4 18.6h1.1v2a.27 .27 0 0 0 .2 .3 .27 .27 0 0 0 .3-.2l.1-.2v-1.3v-.4l-.2-.2h1v2.3l.3 .3h-1.1v-.4a.79 .79 0 0 1-1 .4 .79 .79 0 0 1-.4-1v-1.3z" fill-rule="evenodd"/>
<path d="M84.6 18.6h1v.4a.79 .79 0 0 1 .8-.5 .79 .79 0 0 1 .7 .5 .82 .82 0 0 1 1-.4 .82 .82 0 0 1 .5 1v1.3l.3 .3h-1.3l.2-.3v-1.7a.31 .31 0 0 0-.2-.3 .31 .31 0 0 0-.4 .2l-.1 .1v1.7l.3 .3h-1.3l.2-.4v-1.6a.3 .3 0 0 0-.2-.3 .3 .3 0 0 0-.3 .2l-.2 .1v1.4l.1 .4 .2 .2h-1.3l.2-.2v-.4v-1.7z" fill-rule="evenodd"/>
<path d="M89.6 18.9a1.03 1.03 0 0 1 1.2-.3 1.03 1.03 0 0 1 .6 1.2h-1.4a.73 .73 0 0 0 .2 .8 .73 .73 0 0 0 .9 0l.2-.2 .1 .1a1.1 1.1 0 0 1-1.3 .7 1.1 1.1 0 0 1-.9-1.3l.1-.4 1.4 .1v-.6l-.3-.3-.4 .3v.5h-.7z" fill-rule="evenodd"/>
<path d="M91.7 18.6h1v.4a.79 .79 0 0 1 1.1-.4 .79 .79 0 0 1 .4 1v1.3l.3 .3h-1.3l.2-.3v-1.7a.28 .28 0 0 0-.2-.3 .28 .28 0 0 0-.3 .2l-.2 .2 .1 1.6 .2 .3h-1.3l.2-.2 .1-.4v-1.7z" fill-rule="evenodd"/>
<path d="M95.7 17.7l.1 .9h.6v.3h-.6v1.8l.2 .2 .3-.3a.68 .68 0 0 1-.8 .6 .68 .68 0 0 1-.4-.9v-1.4h-.4v-.1z" fill-rule="evenodd"/>
<path d="M24.5 18.8a.91 .91 0 0 1 .9-.3 .91 .91 0 0 1 .7 .8 .43 .43 0 0 1-.6 .1 .43 .43 0 0 1-.1-.5l-.3-.2a1.36 1.36 0 0 0 .5 2.1l.5-.3 .1 .1a1.15 1.15 0 0 1-1.5 .5 1.15 1.15 0 0 1-.6-1.4z" fill-rule="evenodd"/>
<path d="M56.6 18.8a.91 .91 0 0 1 .9-.3 .91 .91 0 0 1 .7 .8 .43 .43 0 0 1-.6 .1 .43 .43 0 0 1-.2-.5l-.2-.2a1.35 1.35 0 0 0 .5 2.1l.5-.3 .1 .1a1.16 1.16 0 0 1-1.5 .5 1.16 1.16 0 0 1-.7-1.4z" fill-rule="evenodd"/>
<path d="M79.4 18.8a.91 .91 0 0 1 1-.3 .91 .91 0 0 1 .6 .8 .43 .43 0 0 1-.6 .1 .43 .43 0 0 1-.1-.5l-.3-.2a1.43 1.43 0 0 0 .4 2.1l.7-.2a1.16 1.16 0 0 1-1.5 .5 1.16 1.16 0 0 1-.6-1.4z" fill-rule="evenodd"/>
<path d="M183.3 64.7h2.7v.9a.82 .82 0 0 0-1-.7v2.5l.5 .3h-1.6l.4-.3v-2.5a.81 .81 0 0 0-1 .7z" fill-rule="evenodd"/>
<path d="M186.3 65.8a1.04 1.04 0 0 1 1.6 .9 1.04 1.04 0 0 1-1.6 .9l-.4-.7h.7v.4a.28 .28 0 0 0 .3 .3 .28 .28 0 0 0 .3-.2v-1.4a.3 .3 0 0 0-.4-.2 .3 .3 0 0 0-.2 .4v.7h-.7l.1-.6z" fill-rule="evenodd"/>
<path d="M188.1 65.7h.9v.3a.79 .79 0 0 1 1-.3 .79 .79 0 0 1 .3 1 .82 .82 0 0 1-.3 .9 .82 .82 0 0 1-1-.1v1l.3 .2h-1.2l.2-.2 .1-2.3h.6v1.1a.33 .33 0 0 0 .3 .3 .33 .33 0 0 0 .3-.3v-1.1a.33 .33 0 0 0-.3-.3 .33 .33 0 0 0-.3 .3h-.6l-.1-.4z" fill-rule="evenodd"/>
<path d="M191.8 64.7h2.5v.9a1.02 1.02 0 0 0-1.4-.7v1.2a.73 .73 0 0 0 .8-.6v1.5a.76 .76 0 0 0-.8-.7v1.2l.4 .2h-1.5l.3-.1 .1-.4v-2.2z" fill-rule="evenodd"/>
<path d="M194.8 65.9a.85 .85 0 0 1 .9-.3 .85 .85 0 0 1 .6 .8v1h.2a.42 .42 0 0 1-.4 .4 .42 .42 0 0 1-.4-.4 .6 .6 0 0 1-.5 .4 .6 .6 0 0 1-.6-.3l.1-.3h.5l.3 .2 .2-.1v-.7l-.5 .6h-.5l.3-.4 .7-.4v-.4a.27 .27 0 0 0-.4-.2 .27 .27 0 0 0 0 .4 .32 .32 0 0 1-.5 .2 .32 .32 0 0 1 0-.5z" fill-rule="evenodd"/>
<path d="M196.8 64.7h.8v1.2a.84 .84 0 0 1 1.1-.1 .84 .84 0 0 1 .3 1 .95 .95 0 0 1-.6 .9 .95 .95 0 0 1-1-.1l-.4 .2v-1.7h.6a1.69 1.69 0 0 0 .1 1.5h.4a1.54 1.54 0 0 0 0-1.7l-.5 .2h-.6v-1.1z" fill-rule="evenodd"/>
<path d="M199.4 65.7h.8v.4a.55 .55 0 0 1 .3-.4 .55 .55 0 0 1 .6 .1 .35 .35 0 0 1-.2 .4 .35 .35 0 0 1-.4-.1l-.3 .4v.7v.3l.3 .2h-1.1l.1-.1 .1-.3v-1.3z" fill-rule="evenodd"/>
<path d="M201.3 65.7h.8l.1 1.8 .2 .2h-1.1l.2-.1v-.3v-1.4z" fill-rule="evenodd"/>
<path d="M203 65.9a.68 .68 0 0 1 .8-.3 .68 .68 0 0 1 .4 .7 .41 .41 0 0 1-.5 0 .41 .41 0 0 1-.1-.5h-.1a1.04 1.04 0 0 0 .3 1.6l.5-.2a.89 .89 0 0 1-1.2 .5 .89 .89 0 0 1-.5-1.2z" fill-rule="evenodd"/>
<path d="M204.8 65.9a.85 .85 0 0 1 1-.3 .85 .85 0 0 1 .6 .8v1h.2a.42 .42 0 0 1-.4 .4 .42 .42 0 0 1-.5-.4 .6 .6 0 0 1-.5 .4 .6 .6 0 0 1-.5-.3v-.3h.6l.2 .2 .2-.1v-.7l-.4 .6h-.6l.3-.4 .7-.4v-.4a.27 .27 0 0 0-.4-.2 .27 .27 0 0 0 0 .4 .32 .32 0 0 1-.5 .2 .32 .32 0 0 1 0-.5z" fill-rule="evenodd"/>
<path d="M207.6 64.9l.1 .8h.5v.2h-.5v1.5l.1 .1 .3-.2a.54 .54 0 0 1-.7 .4 .54 .54 0 0 1-.3-.7v-1.1l-.3-.1z" fill-rule="evenodd"/>
<path d="M208.3 65.7h.9v1.8l.2 .2h-1.1l.2-.1 .1-.3-.1-1.4z" fill-rule="evenodd"/>
<path d="M210 65.8a1.04 1.04 0 0 1 1.6 .9 1.04 1.04 0 0 1-1.6 .9l-.4-.7h.7v.4a.28 .28 0 0 0 .3 .3 .28 .28 0 0 0 .3-.2v-1.4a.3 .3 0 0 0-.4-.2 .3 .3 0 0 0-.2 .4v.7h-.7l.1-.6z" fill-rule="evenodd"/>
<path d="M211.9 65.7h.8v.3a.64 .64 0 0 1 .9-.3 .64 .64 0 0 1 .3 .8v1l.2 .2h-1l.1-.2 .1-1.4a.23 .23 0 0 0-.2-.2 .23 .23 0 0 0-.3 .2l-.1 1.2 .2 .4h-1l.2-.1v-.3v-1.4z" fill-rule="evenodd"/>
<path d="M216.1 65.1l.7-.4a3.2 3.2 0 0 0-.2 3.7l.2 .2a2.2 2.2 0 0 1-.7-3.5z" fill-rule="evenodd"/>
<path d="M217.4 64.9a1.69 1.69 0 0 1 1.5 0l.1-.2v1a.88 .88 0 0 0-1.4-.6l.1 .4a2.28 2.28 0 0 1 1.5 1.4 1.2 1.2 0 0 1-1.9 .7l-.2 .2v-1.1a.98 .98 0 0 0 1.5 .7 .62 .62 0 0 0-.5-.8 1.01 1.01 0 0 1-.9-1.5z" fill-rule="evenodd"/>
<path d="M219.9 65.9a.68 .68 0 0 1 .8-.3 .68 .68 0 0 1 .4 .7 .41 .41 0 0 1-.4 0 .41 .41 0 0 1-.1-.5h-.2a1.04 1.04 0 0 0 .4 1.6l.4-.2a.89 .89 0 0 1-1.2 .5 .89 .89 0 0 1-.4-1.2z" fill-rule="evenodd"/>
<path d="M221.7 65.9a.85 .85 0 0 1 1-.3 .85 .85 0 0 1 .6 .8v1h.2a.42 .42 0 0 1-.4 .4 .42 .42 0 0 1-.4-.4 .6 .6 0 0 1-.6 .4 .6 .6 0 0 1-.5-.3v-.3h.6l.2 .2 .3-.1v-.7l-.5 .6h-.6l.3-.4 .8-.4v-.4a.27 .27 0 0 0-.4-.2 .27 .27 0 0 0-.1 .4 .32 .32 0 0 1-.4 .2 .32 .32 0 0 1-.1-.5z" fill-rule="evenodd"/>
<path d="M223.7 64.7h.9v2.8l.2 .2h-1.1l.2-.1 .1-.3v-2.3z" fill-rule="evenodd"/>
<path d="M225.3 65.9a.83 .83 0 0 1 1-.2 .83 .83 0 0 1 .5 .9h-1.1a.58 .58 0 0 0 .3 .8 .58 .58 0 0 0 .7-.3 .85 .85 0 0 1-1 .7 .85 .85 0 0 1-.6-1.1v-.3l1.1 .1-.1-.7a.4 .4 0 0 0-.5 .2 .4 .4 0 0 0 0 .4h-.5z" fill-rule="evenodd"/>
<path d="M228.3 65.2l1.2-.5v2.4a.46 .46 0 0 0 .4 .6h-1.5l.4-.2v-1.9v-.4z" fill-rule="evenodd"/>
<path d="M232.1 65.2l1.1-.5 .1 2.7 .1 .2 .3 .1h-1.6l.5-.2v-1.9l-.1-.4z" fill-rule="evenodd"/>
<path d="M234.1 64.7a2.18 2.18 0 0 1 1.3 2 2.18 2.18 0 0 1-1.3 1.9 3.2 3.2 0 0 0 .2-3.7z" fill-rule="evenodd"/>
<circle cx="55.2" cy="17.8" r=".42"/>
<circle cx="63.9" cy="17.8" r=".42"/>
<circle cx="201.8" cy="65" r=".34"/>
<circle cx="208.9" cy="65" r=".34"/>
<circle cx="231" cy="67.4" r=".36"/>
<circle cx="231" cy="66" r=".36"/>
</g>
<g fill="#00007f">
<path d="M392.2 248.7h.8l-.5 1.4h-.1l.4-1.2h-.5l-.2 .2z" fill-rule="evenodd"/>
<path d="M393.5 248.7h.5l-.1 .2h-.4l-.1 .2a.5 .5 0 0 1 .5 .6 .5 .5 0 0 1-.7 .3 .4 .4 0 0 0 .6-.3 .4 .4 0 0 0-.5-.4h-.1z" fill-rule="evenodd"/>
<path d="M394.4 248.8a.57 .57 0 0 1 .7 .3 .57 .57 0 0 1-.2 .7l-.4 .3h-.3l.4-.2 .2-.4a.39 .39 0 0 1-.5 0 .39 .39 0 0 1-.1-.4h.2l.1 .3a.28 .28 0 0 0 .4 0 .28 .28 0 0 0-.1-.4l-.1-.2a.24 .24 0 0 0-.3 0 .24 .24 0 0 0 0 .3h-.2z" fill-rule="evenodd"/>
<path d="M395.4 248.8a.47 .47 0 0 1 .6 0 .47 .47 0 0 1 .1 .6 .48 .48 0 0 1-.1 .6 .48 .48 0 0 1-.6 0l-.2-.5h.2a.36 .36 0 0 0 0 .4 .36 .36 0 0 0 .4 .1l.1-.6-.1-.6a.24 .24 0 0 0-.3 0 .24 .24 0 0 0 0 .3l-.1 .4h-.2z" fill-rule="evenodd"/>
<path d="M396.4 248.9l.4-.2v1.3l.2 .1h-.5l.1-.1v-.9v-.2z" fill-rule="evenodd"/>
<path d="M397.4 249.2h.4l.2 .1v.7h.2l-.2 .1-.2-.1a.29 .29 0 0 1-.4 0l-.1-.1 .3 .1 .2-.1v-.3l-.5 .3 .5-.4-.1-.3-.3 .3z" fill-rule="evenodd"/>
<path d="M398.4 248.8h.5a.31 .31 0 0 1-.1 .5 .43 .43 0 0 1 .2 .7 .43 .43 0 0 1-.7 0 .34 .34 0 0 0 .5 0 .34 .34 0 0 0-.1-.5l-.2-.1a.28 .28 0 0 0 .3-.2 .28 .28 0 0 0-.1-.3 .28 .28 0 0 0-.4 .1z" fill-rule="evenodd"/>
</g>
<path d="M390.5 243v10.5" fill="none" stroke="#000" stroke-width=".18"/>
<g fill="#00f">
<path d="M392.3 244.3l.3-.2h.5l.3 .3 .1 .1-.2 .1a.58 .58 0 0 0-.8-.2 .58 .58 0 0 0-.2 .8 .58 .58 0 0 0 .8 .2l.2-.1v-.3h-.4v-.1h.6v.5a.81 .81 0 0 1-1.2 .1 .81 .81 0 0 1 0-1.2z" fill-rule="evenodd"/>
<path d="M393.8 244.1h.2v.2h-.2z" fill-rule="evenodd"/>
<path d="M393.8 244.5h.2v1.1h-.2z" fill-rule="evenodd"/>
<path d="M394.3 244.3l.2-.1v.3h.1v.2h-.1v.6l.2 .3a.27 .27 0 0 1-.3 0 .27 .27 0 0 1-.1-.3v-.6h-.2z" fill-rule="evenodd"/>
<path d="M395.4 244.1h.2v.6h.8v-.6h.2v1.5h-.2v-.7h-.8v.7h-.2z" fill-rule="evenodd"/>
<path d="M397 244.6l.1-.1a.47 .47 0 0 1 .6 .1 .47 .47 0 0 1 .1 .6l.1 .4h-.2l-.1-.1-.5 .1-.2-.1v-.2l.3 .2h.3l.1-.4-.7 .2a.57 .57 0 0 1 .7-.4 .28 .28 0 0 0-.2-.2 .28 .28 0 0 0-.3 .2l-.2-.1z" fill-rule="evenodd"/>
<path d="M398.1 244.6l.3-.1a.39 .39 0 0 1 .5 .3h-.2a.21 .21 0 0 0-.3-.2 .21 .21 0 0 0-.1 .3 .43 .43 0 0 1 .5 .1 .43 .43 0 0 1 .1 .4l-.3 .2h-.3l-.3-.3h.2a.24 .24 0 0 0 .3 .3 .24 .24 0 0 0 .1-.4 .43 .43 0 0 1-.5-.5z" fill-rule="evenodd"/>
<path d="M399.1 244.1h.2v.6l.3-.2 .4 .1v1h-.2v-.7a.27 .27 0 0 0-.3-.2 .27 .27 0 0 0-.2 .3v.6h-.2z" fill-rule="evenodd"/>
<path d="M400.4 244.5h.2v.2h-.2z" fill-rule="evenodd"/>
<path d="M400.4 245.4h.2v.2h-.2z" fill-rule="evenodd"/>
</g>
<use href="#words"/>
</svg>
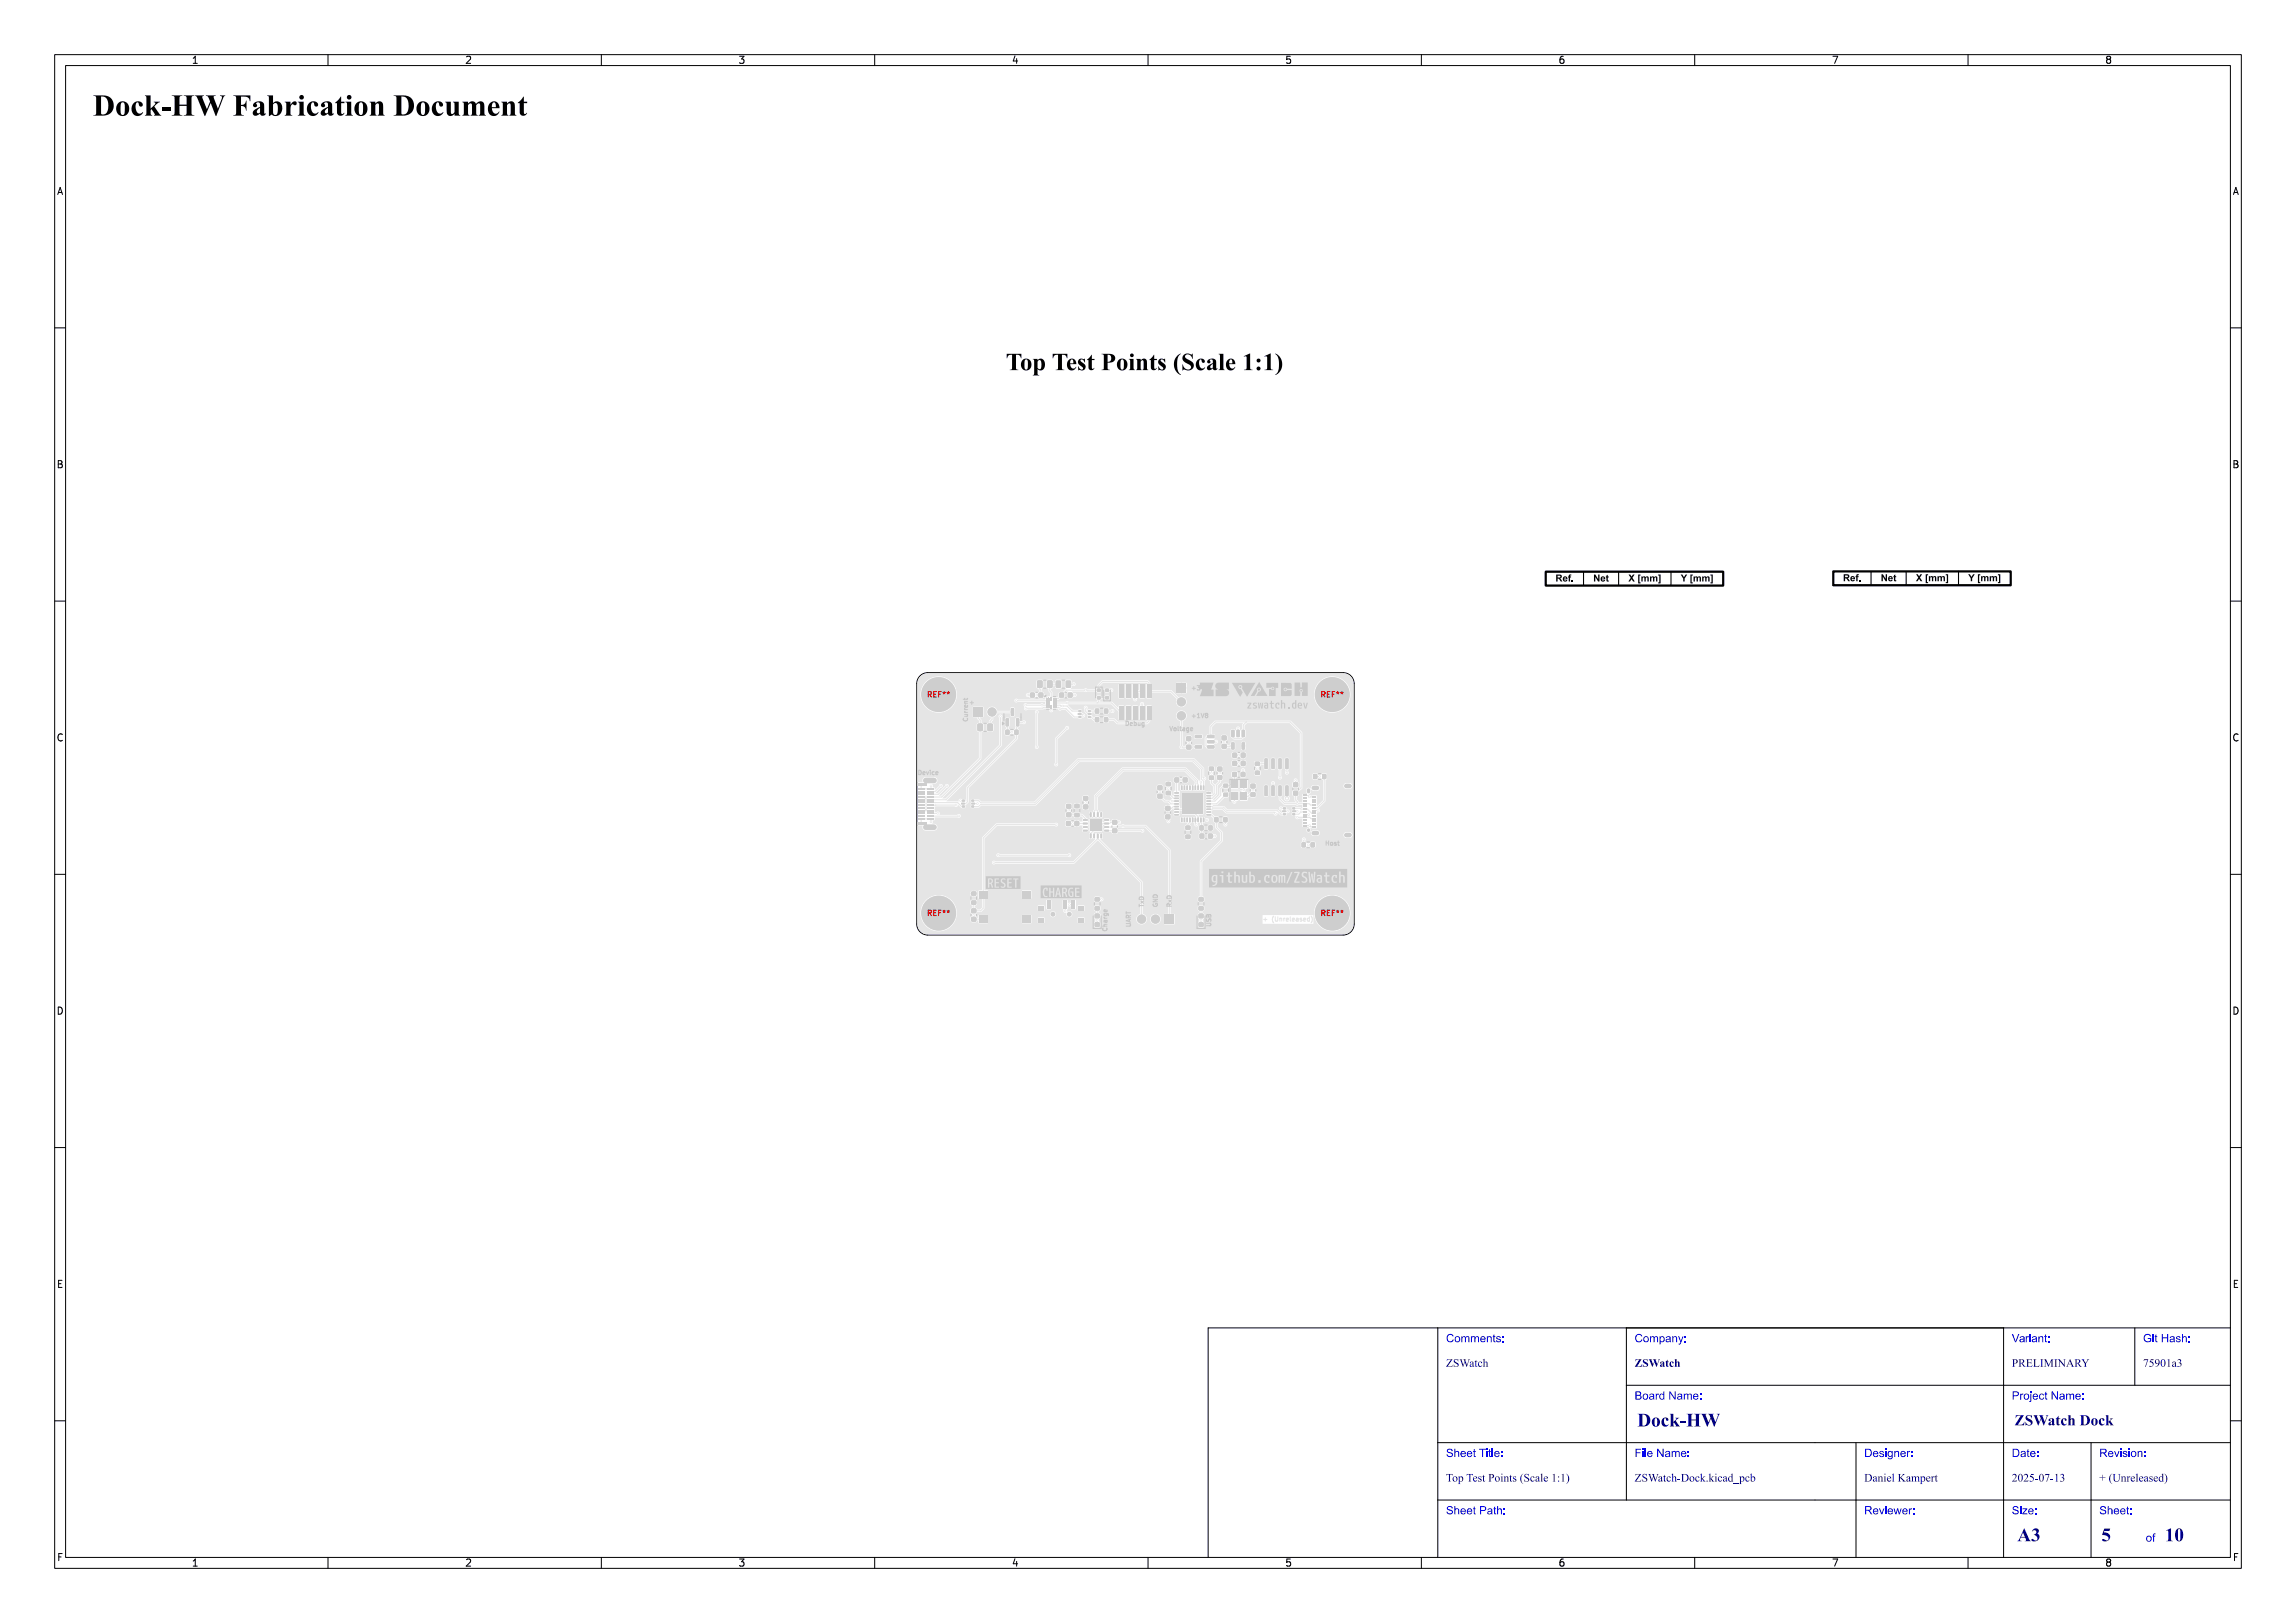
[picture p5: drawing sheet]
<svg xmlns="http://www.w3.org/2000/svg" width="420mm" height="297mm" viewBox="0 0 420 297" stroke-linecap="round" stroke-linejoin="round" font-family="sans-serif">
<defs><g id="words">
<text font-size="5.3" fill="#fff" x="17" y="21.5">Dock-HW Fabrication Document</text>
<text font-size="4.3" fill="#fff" x="174.4" y="68">Top Test Points (Scale 1:1)</text>
<g font-size="3.3" fill="#fff">
<text x="299.5" y="261.2">Dock-HW</text>
<text x="369" y="282.2">A3</text>
<text x="384.4" y="282.3">5</text>
<text x="396" y="282.3">10</text>
</g>
<text font-size="2.7" fill="#fff" x="368.5" y="261">ZSWatch Dock</text>
<g font-size="2" fill="#fff">
<text x="264.5" y="245.7">Comments:</text>
<text x="299" y="245.7">Company:</text>
<text x="368" y="245.7">Variant:</text>
<text x="392" y="245.7">Git Hash:</text>
<text x="264.5" y="250.2">ZSWatch</text>
<text x="299" y="250.2">ZSWatch</text>
<text x="368" y="250.2">PRELIMINARY</text>
<text x="392" y="250.2">75901a3</text>
<text x="299" y="256.2">Board Name:</text>
<text x="368" y="256.2">Project Name:</text>
<text x="264.5" y="266.7">Sheet Title:</text>
<text x="299" y="266.7">File Name:</text>
<text x="341" y="266.7">Designer:</text>
<text x="368" y="266.7">Date:</text>
<text x="384" y="266.7">Revision:</text>
<text x="264.5" y="271.2">Top Test Points (Scale 1:1)</text>
<text x="299" y="271.2">ZSWatch-Dock.kicad_pcb</text>
<text x="341" y="271.2">Daniel Kampert</text>
<text x="368" y="271.2">2025-07-13</text>
<text x="384" y="271.2">+ (Unreleased)</text>
<text x="264.5" y="277.2">Sheet Path:</text>
<text x="341" y="277.2">Reviewer:</text>
<text x="368" y="277.2">Size:</text>
<text x="384" y="277.2">Sheet:</text>
<text x="392.5" y="282.2">of</text>
</g>
<g font-size="1.7" fill="#fff">
<text x="35" y="11.6">1</text>
<text x="85" y="11.6">2</text>
<text x="135" y="11.6">3</text>
<text x="185" y="11.6">4</text>
<text x="235" y="11.6">5</text>
<text x="285" y="11.6">6</text>
<text x="335" y="11.6">7</text>
<text x="385" y="11.6">8</text>
<text x="10.5" y="35.6">A</text>
<text x="408.5" y="35.6">A</text>
<text x="10.5" y="85.6">B</text>
<text x="408.5" y="85.6">B</text>
<text x="10.5" y="135.6">C</text>
<text x="408.5" y="135.6">C</text>
<text x="10.5" y="185.6">D</text>
<text x="408.5" y="185.6">D</text>
<text x="10.5" y="235.6">E</text>
<text x="408.5" y="235.6">E</text>
<text x="10.5" y="285.6">F</text>
<text x="35" y="286.7">1</text>
<text x="85" y="286.7">2</text>
<text x="135" y="286.7">3</text>
<text x="185" y="286.7">4</text>
<text x="235" y="286.7">5</text>
<text x="285" y="286.7">6</text>
<text x="335" y="286.7">7</text>
<text x="385" y="286.7">8</text>
<text x="408.5" y="285.6">F</text>
</g>
<g font-size="1.3" fill="#fff">
<text x="169.7" y="127.6">REF**</text>
<text x="241.7" y="127.6">REF**</text>
<text x="169.7" y="167.6">REF**</text>
<text x="241.7" y="167.6">REF**</text>
</g>
<g font-size="1.1" fill="#fff">
<text x="206" y="132.8">Debug</text>
<text x="213.9" y="133.8">Voltage</text>
<text x="209.2" y="166.1" transform="rotate(-90 209.2 166.1)">TxD</text>
<text x="214.3" y="166.1" transform="rotate(-90 214.3 166.1)">RxD</text>
</g>
</g></defs>
<path d="M168.3 123.7l.9-.5 .5-.1h76a2 2 0 0 1 2 2v44a2 2 0 0 1-2 2h-76a2 2 0 0 1-2-2v-44l.1-.5z" fill="none" stroke="#000" stroke-width=".18"/>
<g fill="none" stroke="#e5e5e5" stroke-width=".18">
<path d="M231.1 168.3h.7M231.4 168v.6M233 167.6a.92 .92 0 0 0 0 1.3M233.3 167.8v.6l.1 .2 .3-.2v-.6M234.1 168v.6M234.1 168.1h.3l.1 .5M234.8 168v.6M235.1 168l-.3 .2M235.3 168.3l.4-.1-.1-.1h-.3v.4h.3M236 167.8v.6l.1 .2M236.4 168.3l.4-.1-.1-.1h-.3v.4h.3M237.1 168.1h.3l.1 .5"/>
<path d="M237.5 168.2l-.4 .2 .1 .2 .3-.1M238.1 168.1h-.3l.3 .2v.2h-.3M238.5 168.3l.3-.1v-.1h-.3v.4h.3M239.5 168.1l-.2-.1-.2 .2 .1 .3h.3M239.5 167.8v.8M239.8 167.6a.92 .92 0 0 1 0 1.3"/>
</g>
<g fill="#e5e5e5">
<path d="M202 151.9h.8v.2h-.8z" fill-rule="evenodd"/>
<path d="M202 151.2h.8v.3h-.8z" fill-rule="evenodd"/>
<path d="M202 150.6h.8v.2h-.8z" fill-rule="evenodd"/>
<path d="M202 149.9h.8v.3h-.8z" fill-rule="evenodd"/>
<path d="M201.3 148.7h.3v.8h-.3z" fill-rule="evenodd"/>
<path d="M200.7 148.7h.2v.8h-.2z" fill-rule="evenodd"/>
<path d="M200 148.7h.3v.8h-.3z" fill-rule="evenodd"/>
<path d="M199.4 148.7h.2v.8h-.2z" fill-rule="evenodd"/>
<path d="M198.1 149.9h.8v.3h-.8z" fill-rule="evenodd"/>
<path d="M198.1 150.6h.8v.2h-.8z" fill-rule="evenodd"/>
<path d="M198.1 151.2h.8v.3h-.8z" fill-rule="evenodd"/>
<path d="M198.1 151.9h.8v.2h-.8z" fill-rule="evenodd"/>
<path d="M199.4 152.6h.2v.8h-.2z" fill-rule="evenodd"/>
<path d="M200 152.6h.3v.8h-.3z" fill-rule="evenodd"/>
<path d="M200.7 152.6h.2v.8h-.2z" fill-rule="evenodd"/>
<path d="M201.3 152.6h.3v.8h-.3z" fill-rule="evenodd"/>
<path d="M199.4 150h2.1v2.1h-2.1z" fill-rule="evenodd"/>
<path d="M202.2 127.4h.6v.6h-.6z" fill-rule="evenodd"/>
<path d="M202.2 126h.6v.6h-.6z" fill-rule="evenodd"/>
<path d="M219.3 165.9h.8v.7h-.8z" fill-rule="evenodd"/>
<path d="M219.3 164.2h.8v.7h-.8z" fill-rule="evenodd"/>
<path d="M227.2 133.6l.5 .1-.1 1.2-.5-.1z" fill-rule="evenodd"/>
<path d="M226.2 133.6l.6 .1-.1 1.2-.5-.1z" fill-rule="evenodd"/>
<path d="M225.3 133.6l.5 .1-.1 1.2-.5-.1z" fill-rule="evenodd"/>
<path d="M225.3 135.9h.5l-.1 1.3-.5-.1z" fill-rule="evenodd"/>
<path d="M227.2 135.9h.5l-.1 1.3-.5-.1z" fill-rule="evenodd"/>
<path d="M203.5 151.6h.8v.8h-.8z" fill-rule="evenodd"/>
<path d="M203.5 150.1h.8v.8h-.8z" fill-rule="evenodd"/>
<path d="M219.5 152.6h.7v.8h-.7z" fill-rule="evenodd"/>
<path d="M221 152.6h.8v.8h-.8z" fill-rule="evenodd"/>
<path d="M241.9 141.7h.7v.8h-.7z" fill-rule="evenodd"/>
<path d="M240.2 141.7h.7v.8h-.7z" fill-rule="evenodd"/>
<path d="M238.4 150.9h.7v.3h-.7z" fill-rule="evenodd"/>
<path d="M238.4 150.4h.7v.3h-.7z" fill-rule="evenodd"/>
<path d="M238.4 149.9h.7v.3h-.7z" fill-rule="evenodd"/>
<path d="M238.4 149.4h.7v.3h-.7z" fill-rule="evenodd"/>
<path d="M238.4 148.9h.7v.3h-.7z" fill-rule="evenodd"/>
<path d="M238.4 148.4h.7v.3h-.7z" fill-rule="evenodd"/>
<path d="M238.4 147.9h.7v.3h-.7z" fill-rule="evenodd"/>
<path d="M238.4 147.4h.7v.3h-.7z" fill-rule="evenodd"/>
<path d="M238.4 146.9h.7v.3h-.7z" fill-rule="evenodd"/>
<path d="M238.4 146.4h.7v.3h-.7z" fill-rule="evenodd"/>
<path d="M238.4 145.9h.7v.3h-.7z" fill-rule="evenodd"/>
<path d="M238.4 145.4h.7v.3h-.7z" fill-rule="evenodd"/>
<path d="M240.1 145.7h.7v.3h-.7z" fill-rule="evenodd"/>
<path d="M240.1 146.2h.7v.3h-.7z" fill-rule="evenodd"/>
<path d="M240.1 146.7h.7v.3h-.7z" fill-rule="evenodd"/>
<path d="M240.1 147.2h.7v.3h-.7z" fill-rule="evenodd"/>
<path d="M240.1 147.7h.7v.3h-.7z" fill-rule="evenodd"/>
<path d="M240.1 148.2h.7v.3h-.7z" fill-rule="evenodd"/>
<path d="M240.1 148.7h.7v.3h-.7z" fill-rule="evenodd"/>
<path d="M240.1 149.2h.7v.3h-.7z" fill-rule="evenodd"/>
<path d="M240.1 149.7h.7v.3h-.7z" fill-rule="evenodd"/>
<path d="M240.1 150.2h.7v.3h-.7z" fill-rule="evenodd"/>
<path d="M240.1 150.7h.7v.3h-.7z" fill-rule="evenodd"/>
<path d="M240.1 151.2h.7v.3h-.7z" fill-rule="evenodd"/>
</g>
<g fill="#e5e5e5">
<circle cx="241.3" cy="167.1" r=".4"/>
<circle cx="242" cy="165.4" r=".4"/>
<circle cx="242" cy="168.8" r=".4"/>
<circle cx="243.7" cy="164.7" r=".4"/>
<circle cx="243.7" cy="167.1" r="3.2"/>
<circle cx="243.7" cy="169.5" r=".4"/>
<circle cx="245.4" cy="165.4" r=".4"/>
<circle cx="245.4" cy="168.8" r=".4"/>
<circle cx="246.1" cy="167.1" r=".4"/>
</g>
<path d="M240.3 152.4h.6M240.3 144.2h.6M246.3 152.8h.6M246.3 143.8h.6" fill="none" stroke="#e5e5e5" stroke-width=".8"/>
<g fill="#e5e5e5">
<path d="M239.8 154.2h.7v.8h-.7z" fill-rule="evenodd"/>
<path d="M238.1 154.2h.7v.8h-.7z" fill-rule="evenodd"/>
<path d="M200.3 165.9h.8v.7h-.8z" fill-rule="evenodd"/>
<path d="M200.3 164.2h.8v.7h-.8z" fill-rule="evenodd"/>
<path d="M216.9 152.8h.8v.7h-.8z" fill-rule="evenodd"/>
<path d="M216.9 151.1h.8v.7h-.8z" fill-rule="evenodd"/>
<path d="M178.1 129.4h1.7v1.7h-1.7z" fill-rule="evenodd"/>
<path d="M222.7 141.9h.8v.8h-.8z" fill-rule="evenodd"/>
<path d="M222.7 140.3h.8v.8h-.8z" fill-rule="evenodd"/>
<path d="M180.7 132.5l.7-.1 .2 .2v.9l-.1 .3h-.7l-.2-.2z" fill-rule="evenodd"/>
<path d="M178.8 132.5l.8-.1 .2 .2v.9l-.2 .3h-.6l-.2-.2z" fill-rule="evenodd"/>
<path d="M193.2 124.6l.7-.1 .2 .2v.9l-.1 .3h-.7l-.2-.2z" fill-rule="evenodd"/>
<path d="M195 124.6l.7-.1 .2 .2v.9l-.1 .3h-.6l-.3-.2z" fill-rule="evenodd"/>
<path d="M235.1 138.8l.6 .1-.1 1.8-.5-.1z" fill-rule="evenodd"/>
<path d="M233.9 138.8l.5 .1-.1 1.8-.5-.1z" fill-rule="evenodd"/>
<path d="M232.6 138.8l.6 .1-.1 1.8-.5-.1z" fill-rule="evenodd"/>
<path d="M231.3 138.8l.6 .1-.1 1.8-.5-.1z" fill-rule="evenodd"/>
<path d="M231.3 143.8h.6l-.1 1.9-.5-.1z" fill-rule="evenodd"/>
<path d="M232.6 143.8h.6l-.1 1.9-.5-.1z" fill-rule="evenodd"/>
<path d="M233.9 143.8h.5l-.1 1.9-.5-.1z" fill-rule="evenodd"/>
<path d="M235.1 143.8h.6l-.1 1.9-.5-.1z" fill-rule="evenodd"/>
<path d="M223.5 136.2h.8v.8h-.8z" fill-rule="evenodd"/>
<path d="M223.5 134.6h.8v.8h-.8z" fill-rule="evenodd"/>
<path d="M213.1 167.4h1.6v1.6h-1.6z" fill-rule="evenodd"/>
<path d="M183.9 133.6h.7v.8h-.7z" fill-rule="evenodd"/>
<path d="M185.6 133.6h.7v.8h-.7z" fill-rule="evenodd"/>
<path d="M179.1 163h1.5v1.4h-1.5z" fill-rule="evenodd"/>
<path d="M179.1 167.6h1.5v1.2h-1.5z" fill-rule="evenodd"/>
<path d="M187 163h1.6v1.4h-1.6z" fill-rule="evenodd"/>
<path d="M187 167.6h1.6v1.2h-1.6z" fill-rule="evenodd"/>
<path d="M200.3 129.7h.7v.8h-.7z" fill-rule="evenodd"/>
<path d="M202 129.7h.7v.8h-.7z" fill-rule="evenodd"/>
<path d="M213.2 147.5h.8v.8h-.8z" fill-rule="evenodd"/>
<path d="M213.2 149.1h.8v.8h-.8z" fill-rule="evenodd"/>
<path d="M200.7 126h.6v.6h-.6z" fill-rule="evenodd"/>
<path d="M200.7 127.4h.6v.6h-.6z" fill-rule="evenodd"/>
<path d="M229.6 139.4h.8v.7h-.8z" fill-rule="evenodd"/>
<path d="M229.6 141.1h.8v.7h-.8z" fill-rule="evenodd"/>
<path d="M177.7 147.4h.4l.1 .3-.5 .1z" fill-rule="evenodd"/>
<path d="M177.7 146.9h.6v.3h-.6z" fill-rule="evenodd"/>
<path d="M177.7 146.4h.5v.3h-.5z" fill-rule="evenodd"/>
<path d="M176 146.4h.5v.3h-.5z" fill-rule="evenodd"/>
<path d="M175.9 146.9h.5l.1 .3h-.6z" fill-rule="evenodd"/>
<path d="M176 147.4h.4l.1 .3-.5 .1z" fill-rule="evenodd"/>
<path d="M184 131.5h.5v1.4l-.5-.1z" fill-rule="evenodd"/>
<path d="M185.9 131.5h.5v1.4l-.5-.1z" fill-rule="evenodd"/>
<path d="M184.9 129.6l.6 .1-.1 1.3-.5-.1z" fill-rule="evenodd"/>
<path d="M211.8 145.3h.8v.8h-.8z" fill-rule="evenodd"/>
<path d="M211.8 143.8h.8v.7h-.8z" fill-rule="evenodd"/>
<path d="M197.3 130l.4-.1 .1 .4h-.4z" fill-rule="evenodd"/>
<path d="M197.2 130.5h.6v.3h-.6z" fill-rule="evenodd"/>
<path d="M197.3 131h.4l.1 .3-.4 .1z" fill-rule="evenodd"/>
<path d="M199 131h.4l.1 .3-.4 .1z" fill-rule="evenodd"/>
<path d="M199 130.5h.6v.3h-.6z" fill-rule="evenodd"/>
<path d="M199 130l.4-.1 .1 .4h-.4z" fill-rule="evenodd"/>
<path d="M196.6 147.2h.8v.6h-.8z" fill-rule="evenodd"/>
<path d="M196.6 148.8h.8v.7h-.8z" fill-rule="evenodd"/>
<path d="M213.3 143.1h.8v.7h-.8z" fill-rule="evenodd"/>
<path d="M213.3 144.8h.8v.7h-.8z" fill-rule="evenodd"/>
<path d="M190 126.8h.8v.8h-.8z" fill-rule="evenodd"/>
<path d="M188.5 126.8h.7v.8h-.7z" fill-rule="evenodd"/>
<path d="M234.7 147.8l.4-.1 .1 .4h-.4z" fill-rule="evenodd"/>
<path d="M234.6 148.3h.6v.3h-.6z" fill-rule="evenodd"/>
<path d="M234.7 148.8h.4l.1 .3-.4 .1z" fill-rule="evenodd"/>
<path d="M236.4 148.8h.4l.1 .3-.4 .1z" fill-rule="evenodd"/>
<path d="M236.4 148.3h.6v.3h-.6z" fill-rule="evenodd"/>
<path d="M236.4 147.8l.4-.1 .1 .4h-.4z" fill-rule="evenodd"/>
<path d="M177.7 163.2h.8v.7h-.8z" fill-rule="evenodd"/>
<path d="M177.7 164.8h.8v.7h-.8z" fill-rule="evenodd"/>
<path d="M225.2 142.8h1.2v1.4h-1.2z" fill-rule="evenodd"/>
<path d="M225.2 145h1.2v1.4h-1.2z" fill-rule="evenodd"/>
<path d="M226.9 145h1.2v1.4h-1.2z" fill-rule="evenodd"/>
<path d="M226.9 142.8h1.2v1.4h-1.2z" fill-rule="evenodd"/>
<path d="M236.6 144.8h.8v.7h-.8z" fill-rule="evenodd"/>
<path d="M236.6 143.2h.8v.8h-.8z" fill-rule="evenodd"/>
<path d="M177.7 166.3h.8v.8h-.8z" fill-rule="evenodd"/>
<path d="M177.7 167.8h.8v.8h-.8z" fill-rule="evenodd"/>
<path d="M220.1 143.8h.2l-.1 .8-.2-.1z" fill-rule="evenodd"/>
<path d="M219.6 143.8h.2l-.1 .8-.2-.1z" fill-rule="evenodd"/>
<path d="M219.1 143.8h.2l-.1 .8-.2-.1z" fill-rule="evenodd"/>
<path d="M218.6 143.8h.2l-.1 .8-.2-.1z" fill-rule="evenodd"/>
<path d="M218.1 143.8h.2l-.1 .8-.2-.1z" fill-rule="evenodd"/>
<path d="M217.6 143.8h.2l-.1 .8-.2-.1z" fill-rule="evenodd"/>
<path d="M217.1 143.8h.2l-.1 .8-.2-.1z" fill-rule="evenodd"/>
<path d="M216.6 143.8h.2l-.1 .8-.2-.1z" fill-rule="evenodd"/>
<path d="M216.1 143.8h.2l-.1 .8-.2-.1z" fill-rule="evenodd"/>
<path d="M214.8 145h.8v.2h-.7z" fill-rule="evenodd"/>
<path d="M214.8 145.5h.8v.2h-.7z" fill-rule="evenodd"/>
<path d="M214.8 146h.8v.2h-.7z" fill-rule="evenodd"/>
<path d="M214.8 146.5h.8v.2h-.7z" fill-rule="evenodd"/>
<path d="M214.8 147h.8v.2h-.7z" fill-rule="evenodd"/>
<path d="M214.8 147.5h.8v.2h-.7z" fill-rule="evenodd"/>
<path d="M214.8 148h.8v.2h-.7z" fill-rule="evenodd"/>
<path d="M214.8 148.5h.8v.2h-.7z" fill-rule="evenodd"/>
<path d="M214.8 149h.8v.2h-.7z" fill-rule="evenodd"/>
<path d="M216.1 149.6l.2 .1-.1 .8-.2-.1z" fill-rule="evenodd"/>
<path d="M216.6 149.6l.2 .1-.1 .8-.2-.1z" fill-rule="evenodd"/>
<path d="M217.1 149.6l.2 .1-.1 .8-.2-.1z" fill-rule="evenodd"/>
<path d="M217.6 149.6l.2 .1-.1 .8-.2-.1z" fill-rule="evenodd"/>
<path d="M218.1 149.6l.2 .1-.1 .8-.2-.1z" fill-rule="evenodd"/>
<path d="M218.6 149.6l.2 .1-.1 .8-.2-.1z" fill-rule="evenodd"/>
<path d="M219.1 149.6l.2 .1-.1 .8-.2-.1z" fill-rule="evenodd"/>
<path d="M219.6 149.6l.2 .1-.1 .8-.2-.1z" fill-rule="evenodd"/>
<path d="M220.1 149.6l.2 .1-.1 .8-.2-.1z" fill-rule="evenodd"/>
<path d="M220.7 149h.8v.2h-.8z" fill-rule="evenodd"/>
<path d="M220.7 148.5h.8v.2h-.8z" fill-rule="evenodd"/>
<path d="M220.7 148h.8v.2h-.8z" fill-rule="evenodd"/>
<path d="M220.7 147.5h.8v.2h-.8z" fill-rule="evenodd"/>
<path d="M220.7 147h.8v.2h-.8z" fill-rule="evenodd"/>
<path d="M220.7 146.5h.8v.2h-.8z" fill-rule="evenodd"/>
<path d="M220.7 146h.8v.2h-.8z" fill-rule="evenodd"/>
<path d="M220.7 145.5h.8v.2h-.8z" fill-rule="evenodd"/>
<path d="M220.7 145h.8v.2h-.8z" fill-rule="evenodd"/>
<path d="M216.3 145.2h3.7v3.7h-3.7z" fill-rule="evenodd"/>
<path d="M227 137.8h.8v.8h-.8z" fill-rule="evenodd"/>
<path d="M225.5 137.8h.7v.8h-.7z" fill-rule="evenodd"/>
<path d="M200.3 168.8h.8v.8h-.8z" fill-rule="evenodd"/>
<path d="M200.3 167.2h.8v.8h-.8z" fill-rule="evenodd"/>
<path d="M190 165.8h1v.8h-1z" fill-rule="evenodd"/>
<path d="M190 168h1v.8h-1z" fill-rule="evenodd"/>
<path d="M197.2 165.8h1.1v.8h-1.1z" fill-rule="evenodd"/>
<path d="M197.2 168h1.1v.8h-1.1z" fill-rule="evenodd"/>
<path d="M191.5 164.8h.7v1.5h-.7z" fill-rule="evenodd"/>
<path d="M194.5 164.8h.7v1.5h-.7z" fill-rule="evenodd"/>
<path d="M196 164.8h.7v1.5h-.7z" fill-rule="evenodd"/>
<path d="M222.2 149.6h.6v.8h-.6z" fill-rule="evenodd"/>
<path d="M223.8 149.6h.7v.8h-.7z" fill-rule="evenodd"/>
<path d="M227 139.3h.8v.8h-.8z" fill-rule="evenodd"/>
<path d="M225.5 139.3h.7v.8h-.7z" fill-rule="evenodd"/>
<path d="M169.7 149.7h1.2v.3h-1.2z" fill-rule="evenodd"/>
<path d="M169.7 149.2h1.2v.3h-1.2z" fill-rule="evenodd"/>
<path d="M169.7 148.7h1.2v.3h-1.2z" fill-rule="evenodd"/>
<path d="M169.7 148.2h1.2v.3h-1.2z" fill-rule="evenodd"/>
<path d="M169.7 147.7h1.2v.3h-1.2z" fill-rule="evenodd"/>
<path d="M169.7 147.2h1.2v.3h-1.2z" fill-rule="evenodd"/>
<path d="M169.7 146.7h1.2v.3h-1.2z" fill-rule="evenodd"/>
<path d="M169.7 146.2h1.2v.3h-1.2z" fill-rule="evenodd"/>
<path d="M169.7 145.7h1.2v.3h-1.2z" fill-rule="evenodd"/>
<path d="M169.7 145.2h1.2v.3h-1.2z" fill-rule="evenodd"/>
<path d="M169.7 144.7h1.2v.3h-1.2z" fill-rule="evenodd"/>
<path d="M169.7 144.2h1.2v.3h-1.2z" fill-rule="evenodd"/>
<path d="M167.9 144.2h1.1v.3h-1.1z" fill-rule="evenodd"/>
<path d="M167.9 144.7h1.1v.3h-1.1z" fill-rule="evenodd"/>
<path d="M167.9 145.2h1.1v.3h-1.1z" fill-rule="evenodd"/>
<path d="M167.9 145.7h1.1v.3h-1.1z" fill-rule="evenodd"/>
<path d="M167.9 146.2h1.1v.3h-1.1z" fill-rule="evenodd"/>
<path d="M167.9 146.7h1.1v.3h-1.1z" fill-rule="evenodd"/>
<path d="M167.9 147.2h1.1v.3h-1.1z" fill-rule="evenodd"/>
<path d="M167.9 147.7h1.1v.3h-1.1z" fill-rule="evenodd"/>
<path d="M167.9 148.2h1.1v.3h-1.1z" fill-rule="evenodd"/>
<path d="M167.9 148.7h1.1v.3h-1.1z" fill-rule="evenodd"/>
<path d="M167.9 149.2h1.1v.3h-1.1z" fill-rule="evenodd"/>
<path d="M167.9 149.7h1.1v.3h-1.1z" fill-rule="evenodd"/>
</g>
<g fill="#e5e5e5">
<circle cx="181.5" cy="130.3" r=".85"/>
<circle cx="211.4" cy="168.2" r=".85"/>
<circle cx="208.8" cy="168.2" r=".85"/>
<circle cx="241.3" cy="127.1" r=".4"/>
<circle cx="242" cy="125.4" r=".4"/>
<circle cx="242" cy="128.8" r=".4"/>
<circle cx="243.7" cy="124.7" r=".4"/>
<circle cx="243.7" cy="127.1" r="3.2"/>
<circle cx="243.7" cy="129.5" r=".4"/>
<circle cx="245.4" cy="125.4" r=".4"/>
<circle cx="245.4" cy="128.8" r=".4"/>
<circle cx="246.1" cy="127.1" r=".4"/>
<circle cx="169.3" cy="167.1" r=".4"/>
<circle cx="170" cy="165.4" r=".4"/>
<circle cx="170" cy="168.8" r=".4"/>
<circle cx="171.7" cy="164.7" r=".4"/>
<circle cx="171.7" cy="167.1" r="3.2"/>
<circle cx="171.7" cy="169.5" r=".4"/>
<circle cx="173.4" cy="165.4" r=".4"/>
<circle cx="173.4" cy="168.8" r=".4"/>
<circle cx="174.1" cy="167.1" r=".4"/>
</g>
<path d="M169.3 142.8h1.6" fill="none" stroke="#e5e5e5" stroke-width="1"/>
<g fill="#e5e5e5">
<path d="M167.8 143.3h1.8v.5h-1.8z" fill-rule="evenodd"/>
<path d="M167.8 150.4h1.8v.5h-1.8z" fill-rule="evenodd"/>
</g>
<path d="M169.3 151.4h1.6" fill="none" stroke="#e5e5e5" stroke-width="1"/>
<g fill="#e5e5e5">
<path d="M214.9 142.3h.7v.8h-.7z" fill-rule="evenodd"/>
<path d="M216.4 142.3h.8v.8h-.8z" fill-rule="evenodd"/>
<path d="M228.8 143.5h.8v.7h-.8z" fill-rule="evenodd"/>
<path d="M228.8 145h.8v.8h-.8z" fill-rule="evenodd"/>
<path d="M209.8 125.3h.8v2.4h-.8z" fill-rule="evenodd"/>
<path d="M209.8 129.2h.8v2.4h-.8z" fill-rule="evenodd"/>
<path d="M208.5 125.3h.8v2.4h-.8z" fill-rule="evenodd"/>
<path d="M208.5 129.2h.8v2.4h-.8z" fill-rule="evenodd"/>
<path d="M207.3 125.3h.7v2.4h-.7z" fill-rule="evenodd"/>
<path d="M207.3 129.2h.7v2.4h-.7z" fill-rule="evenodd"/>
<path d="M206 125.3h.7v2.4h-.7z" fill-rule="evenodd"/>
<path d="M206 129.2h.7v2.4h-.7z" fill-rule="evenodd"/>
<path d="M204.7 125.3h.8v2.4h-.8z" fill-rule="evenodd"/>
<path d="M204.7 129.2h.8v2.4h-.8z" fill-rule="evenodd"/>
<path d="M221.1 151.1h.7v.8h-.7z" fill-rule="evenodd"/>
<path d="M219.4 151.1h.7v.8h-.7z" fill-rule="evenodd"/>
<path d="M215.2 125.1h1.7v1.7h-1.7z" fill-rule="evenodd"/>
<path d="M189.8 124.6l.7-.1 .2 .2v.9l-.1 .3h-.7l-.2-.2z" fill-rule="evenodd"/>
<path d="M191.6 124.6l.7-.1 .2 .2v.9l-.1 .3h-.6l-.3-.2z" fill-rule="evenodd"/>
<path d="M191.3 127.7h.6v.2h-.6z" fill-rule="evenodd"/>
<path d="M191.8 127.5h.1v.3h-.1z" fill-rule="evenodd"/>
<path d="M191.3 128.1h.6v.2h-.6z" fill-rule="evenodd"/>
<path d="M191.3 128.5h.6v.2h-.6z" fill-rule="evenodd"/>
<path d="M191.3 128.9h.6v.2h-.6z" fill-rule="evenodd"/>
<path d="M191.3 129.3h.6v.2h-.6z" fill-rule="evenodd"/>
<path d="M192.2 129.1h.2v.6h-.2z" fill-rule="evenodd"/>
<path d="M192.6 129.3h.6v.2h-.6z" fill-rule="evenodd"/>
<path d="M192.6 128.9h.6v.2h-.6z" fill-rule="evenodd"/>
<path d="M192.6 128.5h.6v.2h-.6z" fill-rule="evenodd"/>
<path d="M192.6 128.1h.6v.2h-.6z" fill-rule="evenodd"/>
<path d="M192.6 127.7h.6v.2h-.6z" fill-rule="evenodd"/>
<path d="M192.2 127.5h.2v.6h-.2z" fill-rule="evenodd"/>
<path d="M219.3 168.8h.8v.8h-.8z" fill-rule="evenodd"/>
<path d="M219.3 167.2h.8v.8h-.8z" fill-rule="evenodd"/>
<path d="M223.8 143.4h.8v.7h-.8z" fill-rule="evenodd"/>
<path d="M223.8 145.1h.8v.7h-.8z" fill-rule="evenodd"/>
<path d="M193.8 126.8h.8v.8h-.8z" fill-rule="evenodd"/>
<path d="M195.4 126.8h.7v.8h-.7z" fill-rule="evenodd"/>
<path d="M195.1 148.7h.8v.8h-.8z" fill-rule="evenodd"/>
<path d="M195.1 147.2h.8v.7h-.8z" fill-rule="evenodd"/>
<path d="M221.2 142h.8v.7h-.8z" fill-rule="evenodd"/>
<path d="M221.2 140.3h.8v.7h-.8z" fill-rule="evenodd"/>
<path d="M196.6 150.3h.8v.8h-.8z" fill-rule="evenodd"/>
<path d="M195 150.3h.8v.8h-.8z" fill-rule="evenodd"/>
<path d="M200.3 131.3h.7v.8h-.7z" fill-rule="evenodd"/>
<path d="M202 131.3h.7v.8h-.7z" fill-rule="evenodd"/>
<path d="M198.2 147.3h.8v.7h-.8z" fill-rule="evenodd"/>
<path d="M198.2 145.7h.8v.8h-.8z" fill-rule="evenodd"/>
<path d="M227 141.3h.8v.8h-.8z" fill-rule="evenodd"/>
<path d="M225.4 141.3h.8v.8h-.8z" fill-rule="evenodd"/>
<path d="M217 136.3h.9v.8h-.9z" fill-rule="evenodd"/>
<path d="M217 134.8h.9v.8h-.9z" fill-rule="evenodd"/>
<path d="M220.9 136.4h1.2v.5l-1.2 .1z" fill-rule="evenodd"/>
<path d="M220.9 135.5l1.2-.1v.5l-1.2 .1z" fill-rule="evenodd"/>
<path d="M220.9 134.5h1.2v.5l-1.2 .1z" fill-rule="evenodd"/>
<path d="M218.6 134.5h1.2l.1 .5-1.3 .1z" fill-rule="evenodd"/>
<path d="M218.6 136.4h1.2l.1 .5-1.3 .1z" fill-rule="evenodd"/>
</g>
<g fill="#e5e5e5">
<circle cx="216.1" cy="128.4" r=".85"/>
<circle cx="216.1" cy="131" r=".85"/>
<circle cx="169.3" cy="127.1" r=".4"/>
<circle cx="170" cy="125.4" r=".4"/>
<circle cx="170" cy="128.8" r=".4"/>
<circle cx="171.7" cy="124.7" r=".4"/>
<circle cx="171.7" cy="127.1" r="3.2"/>
<circle cx="171.7" cy="129.5" r=".4"/>
<circle cx="173.4" cy="125.4" r=".4"/>
<circle cx="173.4" cy="128.8" r=".4"/>
<circle cx="174.1" cy="127.1" r=".4"/>
<circle cx="227.4" cy="140.9" r=".22"/>
<circle cx="237" cy="142.8" r=".23"/>
<circle cx="232.9" cy="143.3" r=".23"/>
<circle cx="235.6" cy="148.5" r=".23"/>
<circle cx="196.6" cy="127.2" r=".22"/>
<circle cx="222.2" cy="153" r=".23"/>
<circle cx="198.6" cy="146.9" r=".22"/>
<circle cx="207.6" cy="128" r=".23"/>
<circle cx="223.9" cy="135.8" r=".23"/>
<circle cx="178.1" cy="167.5" r=".22"/>
<circle cx="225.8" cy="146.7" r=".22"/>
<circle cx="196.2" cy="150.7" r=".23"/>
<circle cx="218.8" cy="150.9" r=".23"/>
<circle cx="196.4" cy="125.2" r=".22"/>
<circle cx="223.1" cy="141.5" r=".22"/>
<circle cx="198.2" cy="131" r=".23"/>
<circle cx="230" cy="140.7" r=".22"/>
<circle cx="217.4" cy="135.9" r=".22"/>
<circle cx="203.3" cy="126.3" r=".22"/>
<circle cx="222.4" cy="135.7" r=".22"/>
<circle cx="226.6" cy="139.7" r=".23"/>
<circle cx="212.2" cy="144.9" r=".22"/>
<circle cx="226.6" cy="138.2" r=".23"/>
<circle cx="170.3" cy="150.4" r=".23"/>
<circle cx="192.3" cy="130" r=".22"/>
<circle cx="229.2" cy="144.6" r=".23"/>
<circle cx="216.1" cy="142.7" r=".22"/>
<circle cx="213.7" cy="150.3" r=".23"/>
<circle cx="224.1" cy="150.9" r=".23"/>
<circle cx="239.5" cy="145.8" r=".23"/>
<circle cx="204.7" cy="150.5" r=".23"/>
<circle cx="221.6" cy="141.5" r=".22"/>
<circle cx="188" cy="127.2" r=".22"/>
<circle cx="219.7" cy="168.4" r=".22"/>
<circle cx="241.4" cy="142.1" r=".23"/>
<circle cx="170.3" cy="143.8" r=".23"/>
<circle cx="226.5" cy="133.3" r=".22"/>
<circle cx="178.8" cy="147.1" r=".23"/>
<circle cx="239.3" cy="154.6" r=".22"/>
<circle cx="227.5" cy="144.5" r=".23"/>
<circle cx="195.5" cy="148.2" r=".23"/>
<circle cx="239.6" cy="151.1" r=".22"/>
<circle cx="194.9" cy="166.7" r=".23"/>
<circle cx="189.6" cy="136.7" r=".22"/>
<circle cx="189.6" cy="130.3" r=".22"/>
<circle cx="189.6" cy="127.2" r=".22"/>
<circle cx="216.1" cy="136.7" r=".22"/>
<circle cx="209" cy="152" r=".22"/>
<circle cx="195.2" cy="133.2" r=".22"/>
<circle cx="195.2" cy="128.6" r=".22"/>
<circle cx="193.2" cy="150.9" r=".23"/>
<circle cx="193.2" cy="139.9" r=".22"/>
<circle cx="233.3" cy="148.9" r=".22"/>
<circle cx="234.3" cy="147.9" r=".23"/>
<circle cx="187.7" cy="129.6" r=".22"/>
<circle cx="173.2" cy="143.8" r=".23"/>
<circle cx="190.6" cy="129" r=".22"/>
<circle cx="172.1" cy="143.8" r=".23"/>
<circle cx="187.6" cy="129" r=".22"/>
<circle cx="187.3" cy="132.2" r=".23"/>
<circle cx="201.5" cy="164.6" r=".22"/>
<circle cx="235.4" cy="146.1" r=".4"/>
<circle cx="237.3" cy="147.1" r=".23"/>
<circle cx="237.3" cy="148.5" r=".23"/>
<circle cx="220.8" cy="150" r=".22"/>
<circle cx="237.3" cy="149.6" r=".23"/>
<circle cx="183" cy="131.1" r=".23"/>
<circle cx="185.9" cy="128.2" r=".22"/>
<circle cx="220.3" cy="142.5" r=".22"/>
<circle cx="219.7" cy="143.1" r=".23"/>
<circle cx="213.7" cy="144.3" r=".22"/>
<circle cx="235.4" cy="141.4" r=".23"/>
<circle cx="171.6" cy="148.8" r=".22"/>
<circle cx="181.8" cy="157.8" r=".22"/>
<circle cx="175.4" cy="149.3" r=".23"/>
<circle cx="195.6" cy="156.5" r=".23"/>
<circle cx="182.6" cy="156.5" r=".23"/>
<circle cx="205.4" cy="151.2" r=".22"/>
<circle cx="198.6" cy="126.3" r=".22"/>
<circle cx="198.6" cy="129.5" r=".22"/>
<circle cx="195.6" cy="165.5" r=".23"/>
<circle cx="185.1" cy="134" r=".23"/>
<circle cx="200.7" cy="168.4" r=".22"/>
<circle cx="194.4" cy="129.2" r=".22"/>
<circle cx="193.9" cy="129.7" r=".23"/>
<circle cx="234.1" cy="142.3" r=".23"/>
<circle cx="214.4" cy="146.6" r=".23"/>
<circle cx="203.5" cy="130.1" r=".22"/>
<circle cx="208.9" cy="128.8" r=".22"/>
<circle cx="238.5" cy="153.6" r=".22"/>
<circle cx="239.4" cy="149.1" r=".23"/>
<circle cx="238" cy="148.6" r=".23"/>
<circle cx="241.1" cy="148.3" r=".22"/>
<circle cx="174.9" cy="147.3" r=".23"/>
<circle cx="175.7" cy="146.5" r=".23"/>
</g>
<g fill="none" stroke="#e5e5e5" stroke-width=".2">
<path d="M178.9 130.3v1.1l.4 .4v7l-7 7.1h-3.8M179.3 133.1h.1M181.5 130.3v1.4l-.4 .3v1.1M181.5 130.3h.1M181.5 130.3h3.7M183 131.1v5.3l-10 10h-2.7M184.2 132.2l.1 1.8h.8M185.9 128.2h5.7v.4M187.3 132.2h-1.2v.8l-.2 .2v2l-8.9 8.9v2.6l-.4 .4h-.4M187.6 129h4M188 127.2h.9M189.6 127.2h1.4l.6 .6"/>
<path d="M189.6 130.3v6.4M190.2 125.2l.2 2M191.6 129.4h-.7l-.2 .2-3 .1M192.3 129.4v.6M192.9 127.8h.7l1.5-1.5h5.9v-.9l.7-.7h8.2l.3 .3v1.5h4l1.9 1.9M192.9 128.2v.4h10.4l1.8 1.8M192.9 129.4h.7l.3 .3h1.1l1.5 1.5h1M192.9 129l2.3 .2 .9 .9h1.4M193.6 125.2h-1.6v1.2l.3 .3v1.1M195.2 133.2l-2 2v4.7M195.4 125.2h1M195.8 127.2h.8"/>
<path d="M197.5 130.7h.4l.2 .2M198.6 129.5v.7l.5 .5h.2M199.3 131.2h.3l.5 .5h.6l-.2 .2M199.3 130.1h1.4M202.3 130.1h1.2M202.5 126.3h.8M202.5 127.7h-1.5v.6l-.3 .3M208.9 126.5h-1.3v1.5M208.9 128.8v1.6M210.2 130.4v1.5l-.4 .4h-5.4l-.6-.6h-1.5M216.1 131v5.7h3.1M217.5 135.2v.7"/>
<path d="M221.6 135.7h.8M221.6 134.8h-.7l-.3 .3v1.3l.2 .3h.8M223.9 135v.8M225.5 136.5l-1.6 .1M225.8 138.2h.8M225.8 139.7h.8M226.5 133.3v.9M227.4 136.5v3.2M227.4 138.2h.1M228 132.1l-.6 .6v2.1l-.3 .3h-1.3l-.3-.2v-.7M230.9 139.7l-.1 .1M231.6 139.7l-1.6 .1"/>
<path d="M234.1 139.7v2.6M235.4 139.7v1.7M238 134.1l-2-2h-13.7l-.8 .8v1.9M238 134.2v10M168.5 148.4h1.8M168.7 143.5l-.2 .2v.6h1.8v-.5M169 145.9l.4 .3v1.9l-.2 .3M170.3 150.4v-.5h-1.8v.6l.2 .2M170.3 148.9h1.3M170.3 146.9h4.9l.7 .7h.3M171.1 147.3h.1M172.1 143.8l-1 1h-.8"/>
<path d="M173.2 143.8l-1.6 1.6h-1.3M174.9 147.3h-4.6M175.4 149.3l-5.1 .1M175.7 146.5h.5M178 147.1h.8M182.6 156.5h13M193.2 150.9h-10.9l-2.4 2.4v12.9l-.5 .5h-1.3v-1.5M195.4 150.7h.8M195.5 147.6v.6M195.5 149.1l2.4 .1 .6 .6v.3M197 150.7h1.5M198.6 146.1v.8"/>
<path d="M198.6 147.6v1.2l.3 .3h.6M200.8 153.5l8 8v6.7M200.8 153.5l-4.4 4.4h-14.6M200.8 153v.5M202.4 152h6.6M202.4 151.3h1.9l.2-.1h5l4.4 4.4v12.6M204.7 150.5h-1.5l-.2 .2h-1.2l-.4 .3h-.9v.6l-1 1v.4M212.2 144.1v.8M212.2 145.7l.9 .9h.6l.5 .5h1M213.6 149.5l.1 .8M213.7 144.3v.8l1 1h.5M214.4 146.6h.8"/>
<path d="M215.2 147.6h-.6l-.3 .3h-.7M215.2 142.5v2.6M216.1 142.7h.7M216.7 147.1h1.5M217.7 150v.5l-.4 .3v.7M218.2 147.1l-1 1h-2M218.2 147.1v1.3l1 1v.6h-.5v.7l.1 .2M219.7 150v.5l.1 .2v2.3M220.2 150h.6M221.1 149.1h.5l.9 .9v1.4l1 1v1.4l-3.8 3.8v7M221.4 153h.8M221.6 140.7v.8"/>
<path d="M221.6 142.3v1l.5 .5v1.4l-.4 .4h-.6M223.1 140.7v.8M223.1 142.3v.8l-.6 .6v1.6l-.8 .8h-.6M224.2 150v.9M225.8 145.7v1M225.8 141.7v1.8h-.7l-.2 .3h-1.1l-.5 .5v1.2l-1.1 1.1h-1.1M225.8 142.4h.1M227.4 140.9v.8M227.5 143.5v1M229.2 145.4h-.6l-.3 .3h-.8v-.3l-.7-.7h-1.9l-2.4 2.4h-1.4M229.2 143.9v.7M230 140.7v.7"/>
<path d="M232.9 143.3v1.4M234.1 144.7v1.5l.9 .9h4.5l.2 .2h.7M234.9 148.5h.7M235.4 141.4h.1M236.7 148.5h.6M237 142.8v.8M237 145.2v1.2l.3 .3v.4M237.3 149.6h2.3l.2 .2h.6M238 144.1l-1 1.1M238.5 153.6v1M238.7 151.1h.9l.2 .2h.6M238.7 145.6h.6l.2 .2h.9"/>
<path d="M238.7 149.1h.7M239.3 154.6h.8M240.6 142.1h.8M242.2 142.1v4.5l-1.2 1.2h-.6M178.1 167.5v.7h1.8M194.9 165.5v1.2M195.6 165.5h.7M200.7 164.6h.8M200.7 166.2v1.4M200.7 168.4v.8M219.7 166.2v1.4M219.7 168.4v.8"/>
</g>
<path d="M218.7 144.2l.1-1.2-2.1-2.1h-11.2l-4.9 4.9v2.5l.2 .1v.7M219.2 144.2l-.1-1.3-2.2-2.2h-11.6l-5 5v2.6l-.1 .1v.7M219.7 143.1v1.1M220.2 144.2v-1.2l-.4-.4v-1.8l-1.6-1.6h-20.8l-8 8h-10l-.4 .4h-1.1M220.3 142.5l-.2-.3v-1.5l-1.7-1.7h-21.2l-7.9 7.9h-9.9l-.4-.4h-1.1M221.1 148.1l2.6-.1 .6 .6h8.8l.2 .3M221.1 147.6l2.7 .1 .7 .7h9.2l.6 .6h.6M234.3 147.9h.6M236.7 147.9l2.5 .2 .7 .7h.5M238.7 148.6h-.7l-.4 .4h-.9M240.4 148.3h.7" fill="none" stroke="#e5e5e5" stroke-width=".18"/>
<path d="M235.4 144.7v1.4" fill="none" stroke="#e5e5e5" stroke-width=".4"/>
<path d="M168.4 123.8l.6-.5 .7-.1h76.2a1.9 1.9 0 0 1 1.7 1.9v44.2a1.9 1.9 0 0 1-1.9 1.7h-76.2a1.91 1.91 0 0 1-1.7-1.9v-2.2h.6a3.3 3.3 0 0 0 4.4 3.4 3.3 3.3 0 0 0 1.4-5.4h3.3v.6l.4 .3v.3l-.4 .3v.6l.3 .3-.3 .7v.6l.3 .2h.7l.2-.4h.2l.2 .6h1.5l.1-1.5h6.2v1.4l.1 .1h1.6l.1-1h1.1v.8l.1 .1h1.1l.1-.9h6l.1 .9h1.1l.1-.1v-.8l-.1-.1h-1.1l-.1 .1h-6l-.1-.1-2.3 .1-.1-.6h-1.6l-.1 .1-7.8-.1-.1 .6a.49 .49 0 0 1-.5-.8h13.5v.2a.55 .55 0 0 0 .9 .4 .55 .55 0 0 0 0-1 .55 .55 0 0 0-.9 .4h-13.5l.2-.3h.8l.5-.6 .1-.5h9.7l.1 .9h1.1l.1-.1v-.8l-.1-.1h-1.1l-.1 .1h-9.7v-1h11.3v1.5l.1 .1 .8-.1v-1.5h2.1v1.5l.1 .1a.42 .42 0 0 0 .1 .5 .42 .42 0 0 0 .5 .1 .57 .57 0 0 0 .4 .9 .57 .57 0 0 0 .6-.8 .57 .57 0 0 0-.9-.2l-.1-.4 .2-.2 .1-.5 .5 .1 .1 .5h.7l.1-.1v-.5h.3v.8l.1 .1h1.1l.1-.7h1.7v.5l.4 .3v.2l-.4 .3v.6l.3 .3v.4l-.3 .3v.6l.3 .3 .6-.1 .3-.2v-.6l-.3-.3v-.4l.3-.3v-.6l-.4-.3v-.2l.4-.3-.1-.7-.1-.1h-.7l-.3 .3h-1.7l-.1-.3-1.5 .1-.1-1.1h-.7l-.1 .5h-.5l-.2-.5h-.7l-.1 .1h-2.1l-.1-.1h-.7l-.1 .1h-11.3v-.3l.6-.1v-1.4h6.2v1.4l.1 .1h1.6l.1-.2h11.4v.6l.1 .1 .8 .1 .2-.1a.46 .46 0 0 0 .6-.6l-.8-.4-.7 .1-.2 .2h-11.4v-1.3l-.1-.1h-1.6l-.1 .1h-6.2l-.6-.1v-5.1h1.3v.1a.37 .37 0 0 0 .3 .3 .37 .37 0 0 0 .4-.1h14.3l4.4-4.3 7.8 7.7v5.7a.98 .98 0 0 0-.7 1.2 .98 .98 0 0 0 1.1 .8 .98 .98 0 0 0 .8-1.1h.6v.2a.98 .98 0 0 0 1.5 .7 .98 .98 0 0 0 0-1.6 .98 .98 0 0 0-1.5 .7l-.6-.1a1.17 1.17 0 0 0-.8-.8v-5.9l-7.7-7.7 .4-.2v-.9l-.4-.1-.2 .2-.4-.2-.2 .2-.5-.2 .2-.2h1.4l.1-1.1 .2-.2 .1 .1-.1 .3 .1 .4h-.1v.5l1.3 .1 .3 .3h.8l.3-.3h4.1a.36 .36 0 0 0 .5 0 .36 .36 0 0 0 0-.5 .36 .36 0 0 0-.5 0h-4.1l-.2-.2 .2-.2 .8 .1 .3-.1h3.7l4.3 4.3v11.5l-.8 .1 .1 1.9 1.9-.1v-1.8l-.8-.1v-1.2h5v.5l.4 .3v.2l-.4 .4v.5l.3 .3v.4l-.3 .3v.5l.3 .4 .8-.1 .1-.6h20v-1.6h-9.3v1.6h-10.7l-.1-.3-.2-.2v-.4l.3-.3v-.6l-.4-.4h20.5a3.3 3.3 0 0 0 4.7 3.2 3.3 3.3 0 0 0 .6-5.7 3.3 3.3 0 0 0-5.3 2.2v.3h-20.5l.4-.4v-.6l-.2-.2h-.8l-.2 .3h-5v-1.7h5v.6l.1 .1 .8 .1 .2-.1 .1-.7-.4-.3v-6.3l3.4-3.4h14.7v.7l.2 .2h.6l.3-.3h.5l.2 .3h.6l.2-.1 .1-.8-.2-.2-.7-.1-.2 .3h-.5l-.4-.3a.41 .41 0 0 0 .1-.5 .41 .41 0 0 0-.5-.2l-.2 .3 .2 .3-.3 .4h-14.7l.4-.4v-1.5h16.1l.1 .4 .3 .2h.8l.4-.3h4.3l.1 .4 .3 .2h.8a.53 .53 0 0 0 .5-.5 .53 .53 0 0 0-.5-.5h-.8l-.4 .4h-4.3a.52 .52 0 0 0-.4-.8l-.9 .1-.3 .4h-16.1l-1-1.1v-.6l.3-.3v-.7h.6v.7l.3 .2a.38 .38 0 0 0 0 .5 .38 .38 0 0 0 .5 0 .38 .38 0 0 0 0-.5l.3-.3v-.7l-.2-.1-.6-.1-.3 .3h-.6l-.2-.3h-.6l-.6-.5v-.2h-1v.6l.9 .1 .5 .4v.6l.3 .3v.8l.9 1v1.2l-3.7 3.9v6.4l-.4 .3h-5v-8.8l-2.1-2.1h4.7l.2 .2h.7l.2-.1 .1-.3h-.5v.4h-.2v-.4h-.5v.2h-4.7l-.5-.5h5.2v.2h1.2l-.1-.4-.4-.1v.5h-.2v-.5l-.4 .1-.1 .2h-5.2l-2-2h-5a.39 .39 0 0 0 .5-.3 .39 .39 0 0 0-.3-.5l-.4-.2h-.7l-.3 .3-.3 .1-.1-.5h-.9a.32 .32 0 0 0 0 .5v.2h-.3l-.2-.7-2.2 .1v2.2l.1 .2-.2 .3v.8l.4 .1 .2-.1 .5 .2-4 4h-14.3a.35 .35 0 0 0-.6 .2h-1.3v-1.3h2.1a.37 .37 0 0 0 .3 .3 .37 .37 0 0 0 .4-.1h12.4a.36 .36 0 0 0 .6 0 .36 .36 0 0 0-.1-.5 .36 .36 0 0 0-.5 .1h-12.4a.35 .35 0 0 0-.4-.1 .35 .35 0 0 0-.3 .3h-2.1v-3l2.3-2.4h10.5a.36 .36 0 0 0 .5 .1 .36 .36 0 0 0 0-.6 .36 .36 0 0 0-.5 .1h-10.7l-2.6 2.6v9.6l-.6 .1v1.4l.6 .1v1.6l-.3 .3h-.5l-.4-.3v-.4l.3-.3v-.5l-.2-.2h-.7l-.3 .2h-3.3a3.3 3.3 0 0 0-3.6-.9 3.3 3.3 0 0 0-2.2 2.9h-.6v-3.1h9.7l.3 .2h.7l.2-.2v-.2h-.5v.4h-.1v-.4h-.6v.2h-9.7v-.5h9.7v.2h1.2v-.4l-.3-.1h-.2v.5h-.1v-.5l-.4 .1-.2 .2h-9.7v-12.2h1v.6l.4 .3h1.7a.63 .63 0 0 0 .6-.6 .63 .63 0 0 0-.6-.7h-.3l.1-.3h24.1l.1 .7 .1 .1 .8 .1a.58 .58 0 0 1 .9 0h.2v-1.2h-.3a.5 .5 0 0 1-.4 .3 .5 .5 0 0 1-.4-.3h-.7l-.3 .3h-24.1l-.1-.2 .3-.1 .1-.5h4.2a.36 .36 0 0 0 .5-.1 .36 .36 0 0 0-.1-.5 .36 .36 0 0 0-.5 .1h-3.2a.39 .39 0 0 0-.1-.5 .39 .39 0 0 0-.5 0h-.3v-1h3.6l.3 .1 .4-.4 .7 .6h.5l.1-.2v-.4l.6-.5v-.4h.4v1.3l.2 .2 1.3-.1 .4-.4h9.9l.2-.1h5.3v.6a.51 .51 0 0 1 0 .9v.6l.2 .3h.8l.3-.4h.2l.3 .4h.7l.2-.3h.2l.3 .3-.1 .3v.3h-.4l-.3-.2h-.3v1.2h.3l.3-.2h.4v.4l.1 .2-.1 .1v.4l1 .1 .1-.2-.2-.4 .2-.3v-1.4l-.6-.6h.7l.2 .2v-.5h-.2v.3h-.7l-.5-.4-.4-.1-.1-.2h1.7v.3h.2v-.5l-.2 .2-2.6-.1a.32 .32 0 0 1-.5 .2 .58 .58 0 0 1 0-1l.3-.1 .3 .3 1.3-.1 .3 .3h.7l.2-.3v-.2h-.5v.5h-.2v-.5h-.5v.2h-.5l.1-.3h-.5v.4h-.2v-.4h-.5v.1h-.3v-.4h.3v.1h1.2l-.1-.3-.2-.1h-.2v.4h-.2v-.4h-.4l-.1 .3h-.3l-.2-.3h-.7l-.3 .3h-5.3l1.5-1.5h6.9v.6a.5 .5 0 0 1 .3 .5 .5 .5 0 0 1-.3 .4v.3h1.2l-.1-.4-.2-.2v-.3l.3-.3v-.6l-.1-.2-.9-.1-.2 .3h-6.9l6.4-6.3h20.6l1.4 1.3 .1 1.9-.3 .2-2.4-2.5-11.7 .1-5.1 5v2.6l-.2 .6-.3-.2v1.1l.2-.2 .3 .2 .4-.1a.32 .32 0 0 0 .6 0l.5 .1 .1-.4h11.3v.6l.4 .3a.39 .39 0 0 0 .4 .5 .39 .39 0 0 0 .2-.6l.2-.3h1.7l.1 .8h.9l.2 .1v.3l-.4 .3 .1 .7 .2 .1h.7l.1-.1 .1-.7-.3-.3 .3-.4 .2 .1v-1.1l-3.9 .2v-.6l-.3-.2h-.6l-.3 .3h-11.3v-.6l-.4-.1-.2 .2-.3-.5h12.2l.2 .2 .4 .1v-.5h-.6v.2l-12.2-.1v-.4h12.2v.2h.6v-.6l-.4 .1-.2 .3h-12.2v-1.8l2-2h8.8v.6l.2 .2 .1 .4-.3 .3v.6l.2 .3h.6l.6 .5h.6l.4 .5h-.3v1.2l.4-.1 .6-.5v1.3l.2 .2 .8-.1 .1-1h.4l.1 .8h2.2l.3 .3-.4 .2-.2-.1v1.1l.2-.1v.3a.39 .39 0 0 0 .5 .4 .39 .39 0 0 0 .2-.6l.3-.1 .2 .3-.4 .4 .1 .7 .3 .5-.3 .2v.8l.1 .1h.9l.1-.1v-.7h.4v.7l.3 .2h.6l.3-.3a.39 .39 0 0 0 .5-.3 .39 .39 0 0 0-.5-.3l-.3-.3h-.6l-.3 .3h-.4l-.3-.3v-.3l.2-.3h.6l.3 .3h.5l.2-.2v-.3h-.4v.5h-.1v-.5h-.5v.2h-.6v-.6h.6v.2h1v-.3l-.2-.2h-.2v.5h-.1v-.5l-.4 .1-.1 .2h-.6l-.3-.3v-.3l.4-.1 .1-.2a.37 .37 0 0 0 .5 0 .37 .37 0 0 0 0-.5 .37 .37 0 0 0-.5 0l-.2-.3h-.9l-.2-.4 .9-.1v-3.5h.5v.3v2.7h1v-.2l.3-.1h1.7l.7 .7h8.6a.4 .4 0 0 0 .5 .3 .4 .4 0 0 0 .3-.4l.5 .4 .6 .1h.5v-.5a.39 .39 0 0 0 .6-.3 .39 .39 0 0 0-.6-.4l-.1-.5-.6 .1a.38 .38 0 0 0-.6 .2 .38 .38 0 0 0 .4 .4v.5l-.7-.7h-9.1l-.7-.6h-2l-.1-.1 .9-.1 1.3-1.3 .7-.1 .1-.2v-.6l.2-.1 .1 1.5 .3 .1a.39 .39 0 0 0 .4 .5 .39 .39 0 0 0 .4-.5l.3-.1 .1-1.5h.2l.1 1.5h1.2l.1-.5 .4-.2 .3 .2 .8-.1 .1-.2v-.6l-.3-.3v-.3l.3-.3v-.4h1.4v1.8l.2 .2h.5l.1-.2v-1.8h.4l.1 1.8 .1 .2h.4l.3-.2v-1.8l-.2-.2 .1-.3h3.2v.6l.1 .2 .8 .1 .3-.3v-.6l-.3-.3a.39 .39 0 0 0-.3-.5 .39 .39 0 0 0-.3 .5l-.3 .3h-3.2a.37 .37 0 0 0-.5-.3 .37 .37 0 0 0-.1 .6l-.2 .2h-.4l-.2-.2h-.5l-.1 .2h-1.4l-.1-.5h-.9l-.2 .2v.6l.3 .3v.4l-.6 .6-.1-.5-.5-.1 .1-.4 .4-.1v-1.5l-1.3-.1-.1 .1v1.4l.3 .2v.3l-.3-.2h-1.9l-.5 .4h-.6l-.2 .2-.1-.7 .2-.2 .9 .1 .4-.3 .2 .3h1.3v-1.5l-.5-.2 .1-.3 .3-.2v-.7h.4v.7l.1 .2h.8l.3-.3-.1-.6-.2-.3a.39 .39 0 0 0-.3-.5 .39 .39 0 0 0-.4 .5l-.2 .3h-.4l-.3-.3h-.6l-.2 .2v.8l.3 .2v.4h-.5v.5l-.3 .3-.3-.3-.7 .1-.1 .1-.1 .3-.5 .6v1.1l-1 1h-.2l.8-1v-1.6l.6-.6 .1-.3 .3-.2v-.8a.5 .5 0 0 1-.3-.4 .5 .5 0 0 1 .3-.4v-.7l-.1-.2-.8-.1-.2 .2-.1 .8 .3 .2v.4l-.3 .2v.6l.4 .5-.6 .6-.5-.4v-.3l.4-.3v-.6l-.3-.3v-.5l.3-.2-.1-.7-.2-.2-.8 .1-.1 .2v.6a.72 .72 0 0 1 .2 .8l-.2 .2v.6l.4 .3v.5l.5 .5v1.3l-.2 .1-.1-.1h-1v.3h-.5l-.1-.4h-3.7l-.2 2.8h-.3v-.5l-.1-.1 .1-2.3h5.8l-.1-.2h-.3v.2h-.2v-.2l-.3 .1-.1 .1h-4.8v-.3l-.3-.1v-.8h.4v.7l.1 .2h2.1v-1.1h-2l-.2 .2h-.4l.1-.5a.59 .59 0 0 1 .9 0h.6l.2-.1 .1-.8-.2-.2-.7-.1-.3 .3h-.3l-.2-.2-.4-.1v.6l-.6 .1v.4l.3 .2v1.2l-.3 .1-.1 1-.3-.3-.1-.7-.2-.2v-.5l.2-.1 .1-.4h-1.2v.3a.71 .71 0 0 1 .2 .8l-.2 .2 .1 .7 .1 .1 .7 .1 .4 .5-.4 .3-.3-.1h-.5l-.4-.4v-.6l-.3-.3v-.4l.3-.2v-.6l-.3-.3h-.7l-.2 .3h-8.8l.7-.7h9.6v.2h1.2l-.1-.3-.2-.2h-.2v.5h-.2v-.5l-.4 .1-.1 .2h-9.6l.8-.8h10.4v.3h.5v-.6l-.4 .1-.1 .2h-10.4l1.3-1.2h11l1.9 1.8-.1 .7-.2-.1v1.1l2.2-.1v-1.7a.43 .43 0 0 0 .2-.5 .43 .43 0 0 0-.3-.3l-.1-1.6-1.1-1.1h6.2v.7l.1 .1h.9a.46 .46 0 0 1 .8 .1h.6l.3-.2v-.3h-.5v.5h-.2v-.7l2.1-.1 .1 .7 .3 .2-.1 .5-.3 .2v.6l.2 .2h.8l.2-.2v-.5l-.3-.3-.1-.6 .3-.1 .1-.2h.5l.1 .8h.7l.1-.2v-1.7h.4l.1 1.8 .1 .1h.5l.2-.2v-1.7h.4v1.7l.2 .3v1.1a.36 .36 0 0 0 0 .5 .36 .36 0 0 0 .5 0 .36 .36 0 0 0 0-.5v-1.1l.2-.3v-1.7h.4v1.7l.2 .3v.2a.36 .36 0 0 0 0 .6 .36 .36 0 0 0 .5-.1 .36 .36 0 0 0-.1-.5l.2-.5v-1.7l-.2-.3-.5 .1-.1 .2h-.4l-.3-.3-.4 .1-.2 .2h-.4l-.3-.3-.4 .1-.2 .2h-.4l-.1-.2-.5-.1-.2 .2v.7h-.5l-.4-.3-.7 .1-.2 .2h-1.4l-.2-.3-.3-.1v.5h-.2v-.5l-.3 .1-.2 .2h-.4l-.2-.3h-.6l-.3 .3h-6.2l-.7-.7h-21.2l-8 8h-9.7l-.4-.4-1.3-.1-.2 .2h-.4l.1-2.2 4.3-4.3h11.2a.36 .36 0 0 0 .5 .3 .36 .36 0 0 0 .1-.6v-1.7h31.9v.7l.2 .2h.7l.2-.3h.4l.3 .3h.6l.3-.2v-.3h-.5v.5h-.2v-.7h.7l-.1-.4-.2-.1h-.2v.5h-.2v-.5h-.2l-.3 .3h-.4l-.2-.3h-.7l-.2 .3h-31.9v-2.6l1.8-1.7a.36 .36 0 0 0 .4-.4 .36 .36 0 0 0-.4-.4 .36 .36 0 0 0-.4 .4l-1.8 2v4.4l-.2 .3h-11.2l4.5-4.6 .1-.6 .3-.4-.1-.7-.2-.3 .4-.4v-.5h.4a.36 .36 0 0 0 .5 0 .36 .36 0 0 0 0-.5 .36 .36 0 0 0-.5 0h-.4v-.4l-.2-.2-.6 .1v1.6l-.2 .4a.62 .62 0 0 1-.8 .2l-.3-.3 .2-.5v-1.3l-.2-.2h-.5l-.2 .3v1.2l.2 .5-.2 .3v.8l.2 .2h.5l.3-.3h.6l.3 .3v.5l-8.9 8.9v2.6l-.2 .1-.1-.5h-.4a.49 .49 0 0 0-.6 0 .49 .49 0 0 0-.2 .5l-2.1-.1 10-10.1v-5.1a.36 .36 0 0 0 .1-.5 .36 .36 0 0 0-.6 0 .36 .36 0 0 0 .1 .5v4.9l-9.8 9.8h-.6l7.1-7.2v-4.9l.4-.3v-1.1h.6v1l.1 .3h1l.2-.3-.1-1.1-.4-.4 .4-.3v-.6l.4-.2 .3-.5h2.3l.2 .6 .5 .1 .2-.2v-.7h3.7l.1 .3v5.8a.36 .36 0 0 0 0 .6 .36 .36 0 0 0 .5-.1 .36 .36 0 0 0 0-.5v-5.8a.35 .35 0 0 0-.1-.6 .35 .35 0 0 0-.5 .3h-3.7v-.7l-.2-.2-.5 .1-.2 .6h-2.3a1 1 0 0 0-1.7-.5 1 1 0 0 0 .5 1.7l-.3 1h-.3l-.1 .3h-.6l-.3-.3-.1-.6-.3-.4 .7-.1v-1.8h-1.9v1.8l.7 .1v.2l.4 .4v.4h-.3l-.2 .3 .1 1.1 .4 .3v4.7l-6.9 6.9h-.4l1.4-1.4a.36 .36 0 0 0 .4-.4 .36 .36 0 0 0-.4-.4 .36 .36 0 0 0-.4 .4l-1.2 1.3h-.4l.9-.9a.36 .36 0 0 0 .3-.4 .36 .36 0 0 0-.4-.4 .36 .36 0 0 0-.3 .4l-.7 .7-.1-.4-.3-.1v-.5a.66 .66 0 0 0 .7-.2 .66 .66 0 0 0 .1-.8l-.5-.3h-1.6a.72 .72 0 0 0-.6 .9h-.9v-16.2h.6a3.3 3.3 0 0 0 2.7 3.5 3.3 3.3 0 0 0 3.8-2.2h10.7a.37 .37 0 0 0 .6 .3h5v.3l-.6-.1-.3 .1h-2.4a.38 .38 0 0 0-.6 .1 .38 .38 0 0 0 .1 .5 .36 .36 0 0 0 .1 .5 .36 .36 0 0 0 .5-.1h2.8l.2-.1h1a.39 .39 0 0 0 0 .5 .39 .39 0 0 0 .6 0 .39 .39 0 0 0 0-.5h.9a.37 .37 0 0 0 .3 .3 .37 .37 0 0 0 .4-.1h.7l1.6 1.5 1.2 .1 .3-.2a.39 .39 0 0 0 .5-.3 .39 .39 0 0 0-.4-.5l-.2-.1v-.4l-.1-.2-1.6 .1-.4-.4h2.5l.1 .8 .5 .6v.6h.6l.9 .8h.6l.1-.1 .1-.8h.6v.7l.2 .2h.6l.3-.4h.8l.7 .6h5.4l.6-.5v-.3l.3-.1v-.7h4.4a1.13 1.13 0 0 0 .8 1.1v4.4a.36 .36 0 0 0 0 .6 .36 .36 0 0 0 .5 0h.4l.3 .3h.6l.4-.3 .2-.1 .4 .2h1.1l.2-.2v-.5l-.2-.1-1.1-.1-.6 .3-.1-.2a.45 .45 0 0 1 0-.8v-.7l-.3-.2h-.6l-.2 .1v.8a.54 .54 0 0 1 0 .9h-.6v-1.8h2.1v.4l.3 .2h1.1l.2-.2h.4v1.5l.5 .6 1.3-.1 .1-.5-.3-.3 .2-.1a.4 .4 0 0 0 .6-.4 .4 .4 0 0 0-.6-.3l-.2-.2 .3-.2v-.2h1v.5a.66 .66 0 0 1 0 1v.6l.3 .2h.7l.2-.3h.5l.1 .3 .2 .2h.5l.1-.3h1.1l.2 .3h.5l.1-.2 .1-.5h-.4v.7h-.1v-.7h-.4v.4h-1.1v-1h1.1v.4h.9l-.1-.5-.1-.2h-.2v.7h-.1v-.7l-.3 .1-.1 .2h-1.1l-.1-.3h-.5l-.2 .2v.4l-.5 .1-.1-.3a.45 .45 0 0 1 0-.7v-.7l-.2-.2h-.7l-.3 .3h-1l-.1-.4-.5-.1v-1.3l.7-.7h5l-.2 .3v.8l-.3 .3-.1-.2a.39 .39 0 0 0-.3-.6 .39 .39 0 0 0-.4 .6l-.1 .2-.3-.3-.4 .1-.2 .1v1.2l.6 .5h1.5l.6-.4 .1-1.2-.2-.3v-.6l.4-.5h7.8l1.9 1.9v9.8l-.5 .6h-.7l-.2 .2v.7l.4 .2v.7l.2 .4h-1.9l-.7-.7 .5-.1a.54 .54 0 0 0 .7 .6 .54 .54 0 0 0 .2-.9v-2l-.6-.1-.2 .2v1.9l-.1 .3h-.5l.2-.4-.1-1.8-.2-.2-.5 .1-.1 1.9 .2 .2v.5l.9 1h2.2l.3 .1 .9-.1v.6l-1.4-.3-.5 .1v1.5l.2 .1h.5a.38 .38 0 0 0 .1 .5 .38 .38 0 0 0 .5 0h.6l.1 1.5h1l.1 .2a.45 .45 0 0 0-.4 .6 .45 .45 0 0 0 .7 .2 .45 .45 0 0 0 0-.8h1.2v-2.8a.41 .41 0 0 0 .5-.2 .41 .41 0 0 0-.1-.5l-.1-.1 1.3-1.3v-2.8h3.2l.1 .4 .3 .1 .8 .1a.53 .53 0 0 0 .5-.6 .53 .53 0 0 0-.5-.5h-.8l-.4 .5h-3.2v-1l.2-.3v-.8l-.2-.2-.7 .1a.59 .59 0 0 1-.7 .1l-.2-.2h-.6l-.2 .3v.7l.1 .1 .7 .1 .2-.3h.6l.3 .4v3.6l-1.1 1.1-.1-1.9h-1l-.4-.2 .4-.4 .1-.5 .3 .2 1-.1a.53 .53 0 0 0 .2-.5 .53 .53 0 0 0-.4-.4h-.9l-.4 .6a.43 .43 0 0 0-.5-.1 .43 .43 0 0 0-.3 .3l.2 .8-.9 .1v1.4h-.6l-.4-.5v-.5l.4-.3v-.7l.6-.5v-10.2l-2.1-2.2h-13.8l-1 1-.1 1.4-.4 .1-.4 .6h-.4v-.5l-.2-.2h-1.1l-.3 .3h-2.1v-2.7a.98 .98 0 0 0 .4-1.7 .98 .98 0 0 0-1.6 .7h-4.4v-1.7l-.9-.1-.1 .1v2.4l.3 .2-.3 .3h-5.2l-.6-.6h-1l-.3-.4h-.6l-.2 .3h-.6l-.2-.3h-.6l-.3 .3-.4-.4 .1-.7 .3 .1 .3 .3h.7l.1-.2v-.7h.6v.7l.2 .2h.6l.3-.3h.3a.36 .36 0 0 0 .6-.1 .36 .36 0 0 0-.1-.5 .36 .36 0 0 0-.5 .1h-.3l-.3-.4h-.6l-.2 .3h-.6l-.2-.3h-.6l-.3 .4h-1.3a.38 .38 0 0 0 0-.6 .38 .38 0 0 0-.5 .2h-2.5l-.5-.5 .2-.1h7.7l1.4 1.3v1.4l.1 .1 .9-.1v-2.4h.3v2.5l1-.1v-2.4h.2l.1 2.4 .9 .1v-2.5h.3v2.4l.9 .1 .1-2.5-.2-.2a.38 .38 0 0 0-.4-.5 .38 .38 0 0 0-.2 .6l-.2 .1-.4-.1h-.7l-.2 .1-.3-.1h-.8l-.1 .1-1.2-.1-.2 .4-1.1-1.1h-2.2v-.3l.3-.2h.5l.3 .2 .6-.1 .1-.6-.3-.1h-.5l-.2 .2-1.3-.2-.2 .1v.5l.3 .3-.2 .2h-7.2v-.3l.3-.1 .2-.2 .7-.1 .2-.1v-.7l.4-.4 .2 .1-.2 .3v.7l.1 .1 .8 .1 .2-.3a.41 .41 0 0 0 .5 0 .41 .41 0 0 0 .1-.5l-.3-.2-.2 .1-.3-.3 2.2-.1 .3 .2 .3-.2h1.6l.2 .2h.5l.3-.1v-.5h.5v.5l.2 .1h.6l.2-.2a.38 .38 0 0 0 .6 0 .38 .38 0 0 0-.1-.5 .38 .38 0 0 0-.5 .1l-.2-.2h-.5l-.3 .2h-.5l-.3-.2v-.4l.2-.2h3.2v2.4l.9 .1 .1-2.5h.3v2.4l.9 .1 .1-.1v-2.4h.2l.1 2.5a.43 .43 0 0 0 .2 .5 .43 .43 0 0 0 .5-.1l.2-.5 .1-1 .2 .1v1l1-.1-.1-2.5h-.9v1.1l-.3-.1v-.9l-.1-.1h-.7l-.2 .1-.3-.1h-.8l-.1 .1-.4-.1-4.1 .1 .4-.4h8l.2 .2-.3 .2 .1 2.5h.8l.1-1.1h3.3l1.3 1.2a.99 .99 0 0 0 .6 1.5 .99 .99 0 0 0 1.2-1.2 .99 .99 0 0 0-1.5-.6l-.7-.7h25.5v.4a3.3 3.3 0 0 0 5 2.7 3.3 3.3 0 0 0 0-5.8 3.3 3.3 0 0 0-5 2.7h-25.5l-.7-.6h-3.5v-1l-.3-.3h4.7v.8h.5v.2h-.5l.1 .8 .8 .1v-.5h.2v.5h.8l.1-.1v-.8h-.5v-.2h.5l-.1-.8-.8-.1v.5h-.2v-.5h-.8l-.1 .1h-4.7l-.5-.5h-8.2l-.9 .8v.5l-.3 .3h-1.6l-.3-.2-.3 .2h-2.4l.2-.6a.39 .39 0 0 0 .5 0 .39 .39 0 0 0 0-.6 .39 .39 0 0 0-.5 0 .45 .45 0 0 0-.4-.5h-.6l-.2 .1-.1 1.2 .2 .4-.5 .5-.7 .1-.3 .9h-1v-1l-.2-.3v-.3a.51 .51 0 0 0 .4-.6h.2a.48 .48 0 0 0 .4 .6h.7l.2-.3v-1.2l-.2-.1h-.7a.45 .45 0 0 0-.4 .6h-.2l-.1-.5-.2-.1h-.7l-.2 .1-.1 1.3 .4 .2v.5l.3 .3-.1 .6-.4 .1-1-1-.1-.4 .3-.4v-1.2l-.3-.1h-.8l-.1 .3v1.1l.6 .6a.52 .52 0 0 1-.4 .5 .52 .52 0 0 1-.6-.3h-.7l-.2 .3a.39 .39 0 0 0-.6 .1 .39 .39 0 0 0 .1 .5 .39 .39 0 0 0 .5 0l.3 .3h.6l.3-.3h.3l.3 .3h.6l.3-.2 .2 .4h-5a.35 .35 0 0 0-.4-.1 .35 .35 0 0 0-.2 .3h-10.7v-.3a3.3 3.3 0 0 0-2.7-4.1 3.3 3.3 0 0 0-3.8 3.1h-.6v-2.1l.1-.4z" fill-rule="evenodd" fill="#e5e5e5"/>
<g fill="#fff">
<circle cx="227.4" cy="140.9" r=".13"/>
<circle cx="237" cy="142.8" r=".12"/>
<circle cx="232.9" cy="143.3" r=".13"/>
<circle cx="235.6" cy="148.5" r=".12"/>
<circle cx="196.6" cy="127.2" r=".13"/>
<circle cx="222.2" cy="153" r=".12"/>
<circle cx="198.6" cy="146.8" r=".13"/>
<circle cx="207.6" cy="128" r=".12"/>
<circle cx="223.9" cy="135.8" r=".12"/>
<circle cx="178.1" cy="167.5" r=".12"/>
<circle cx="225.8" cy="146.7" r=".13"/>
<circle cx="196.2" cy="150.7" r=".13"/>
<circle cx="218.8" cy="150.9" r=".12"/>
<circle cx="196.4" cy="125.2" r=".13"/>
<circle cx="223.1" cy="141.5" r=".13"/>
<circle cx="198.1" cy="130.9" r=".12"/>
<circle cx="230" cy="140.7" r=".12"/>
<circle cx="217.4" cy="135.9" r=".12"/>
<circle cx="203.3" cy="126.3" r=".13"/>
<circle cx="222.5" cy="135.7" r=".13"/>
<circle cx="226.6" cy="139.7" r=".12"/>
<circle cx="212.2" cy="144.9" r=".13"/>
<circle cx="226.6" cy="138.2" r=".12"/>
<circle cx="170.3" cy="150.4" r=".12"/>
<circle cx="192.3" cy="130" r=".13"/>
<circle cx="229.2" cy="144.6" r=".12"/>
<circle cx="216.1" cy="142.7" r=".13"/>
<circle cx="213.7" cy="150.3" r=".12"/>
<circle cx="224.1" cy="150.9" r=".12"/>
<circle cx="239.5" cy="145.8" r=".13"/>
<circle cx="204.7" cy="150.5" r=".12"/>
<circle cx="221.6" cy="141.5" r=".13"/>
<circle cx="188" cy="127.2" r=".13"/>
<circle cx="219.7" cy="168.4" r=".12"/>
<circle cx="241.4" cy="142.1" r=".12"/>
<circle cx="170.3" cy="143.8" r=".12"/>
<circle cx="226.5" cy="133.3" r=".12"/>
<circle cx="178.8" cy="147.1" r=".12"/>
<circle cx="239.3" cy="154.6" r=".13"/>
<circle cx="227.5" cy="144.5" r=".12"/>
<circle cx="195.5" cy="148.2" r=".12"/>
<circle cx="239.6" cy="151.1" r=".12"/>
<circle cx="194.8" cy="166.7" r=".12"/>
<circle cx="189.6" cy="136.7" r=".13"/>
<circle cx="189.7" cy="130.3" r=".12"/>
<circle cx="189.6" cy="127.2" r=".13"/>
<circle cx="216.1" cy="136.7" r=".13"/>
<circle cx="209" cy="152" r=".12"/>
<circle cx="195.2" cy="133.2" r=".12"/>
<circle cx="195.2" cy="128.6" r=".12"/>
<circle cx="193.2" cy="150.9" r=".12"/>
<circle cx="193.2" cy="139.9" r=".13"/>
<circle cx="233.3" cy="148.9" r=".12"/>
<circle cx="234.3" cy="147.9" r=".12"/>
<circle cx="187.7" cy="129.7" r=".13"/>
<circle cx="173.2" cy="143.8" r=".13"/>
<circle cx="190.6" cy="129" r=".13"/>
<circle cx="172.1" cy="143.8" r=".12"/>
<circle cx="187.6" cy="129" r=".13"/>
<circle cx="187.3" cy="132.2" r=".13"/>
<circle cx="201.5" cy="164.6" r=".13"/>
<circle cx="235.4" cy="146.1" r=".2"/>
<circle cx="237.3" cy="147.1" r=".13"/>
<circle cx="237.3" cy="148.5" r=".12"/>
<circle cx="220.8" cy="150" r=".12"/>
<circle cx="237.3" cy="149.6" r=".12"/>
<circle cx="183" cy="131.1" r=".12"/>
<circle cx="185.9" cy="128.2" r=".13"/>
<circle cx="220.3" cy="142.5" r=".12"/>
<circle cx="219.7" cy="143.1" r=".12"/>
<circle cx="213.7" cy="144.3" r=".13"/>
<circle cx="235.4" cy="141.4" r=".12"/>
<circle cx="171.5" cy="148.9" r=".13"/>
<circle cx="181.8" cy="157.9" r=".12"/>
<circle cx="175.4" cy="149.3" r=".12"/>
<circle cx="195.6" cy="156.5" r=".13"/>
<circle cx="182.6" cy="156.5" r=".12"/>
<circle cx="205.4" cy="151.2" r=".12"/>
<circle cx="198.6" cy="126.3" r=".13"/>
<circle cx="198.6" cy="129.5" r=".13"/>
<circle cx="195.6" cy="165.5" r=".13"/>
<circle cx="185.1" cy="134" r=".12"/>
<circle cx="200.7" cy="168.4" r=".12"/>
<circle cx="194.4" cy="129.2" r=".13"/>
<circle cx="193.9" cy="129.7" r=".12"/>
<circle cx="234.1" cy="142.3" r=".12"/>
<circle cx="214.4" cy="146.6" r=".13"/>
<circle cx="203.5" cy="130.1" r=".12"/>
<circle cx="208.9" cy="128.8" r=".13"/>
<circle cx="238.5" cy="153.6" r=".13"/>
<circle cx="239.4" cy="149.1" r=".12"/>
<circle cx="238" cy="148.6" r=".12"/>
<circle cx="241.1" cy="148.3" r=".13"/>
<circle cx="174.9" cy="147.3" r=".12"/>
<circle cx="175.7" cy="146.5" r=".13"/>
<circle cx="241.3" cy="167.1" r=".25"/>
<circle cx="242" cy="165.4" r=".25"/>
<circle cx="242" cy="168.8" r=".25"/>
<circle cx="243.7" cy="164.7" r=".25"/>
<circle cx="243.7" cy="167.1" r="1.6"/>
<circle cx="243.7" cy="169.5" r=".25"/>
<circle cx="245.4" cy="165.4" r=".25"/>
<circle cx="245.4" cy="168.8" r=".25"/>
<circle cx="246.1" cy="167.1" r=".25"/>
<circle cx="239.4" cy="151.9" r=".33"/>
</g>
<path d="M239.4 144.6v.3" fill="none" stroke="#fff" stroke-width=".65"/>
<path d="M240.3 152.4h.6M240.3 144.2h.6M246.3 152.8h.6M246.3 143.8h.6" fill="none" stroke="#fff" stroke-width=".5"/>
<g fill="#fff">
<circle cx="178.9" cy="130.3" r=".5"/>
<circle cx="181.5" cy="130.3" r=".5"/>
<circle cx="213.9" cy="168.2" r=".5"/>
<circle cx="211.4" cy="168.2" r=".5"/>
<circle cx="208.8" cy="168.2" r=".5"/>
<circle cx="241.3" cy="127.1" r=".25"/>
<circle cx="242" cy="125.4" r=".25"/>
<circle cx="242" cy="128.8" r=".25"/>
<circle cx="243.7" cy="124.7" r=".25"/>
<circle cx="243.7" cy="127.1" r="1.6"/>
<circle cx="243.7" cy="129.5" r=".25"/>
<circle cx="245.4" cy="125.4" r=".25"/>
<circle cx="245.4" cy="128.8" r=".25"/>
<circle cx="246.1" cy="127.1" r=".25"/>
<circle cx="169.3" cy="167.1" r=".25"/>
<circle cx="170" cy="165.4" r=".25"/>
<circle cx="170" cy="168.8" r=".25"/>
<circle cx="171.7" cy="164.7" r=".25"/>
<circle cx="171.7" cy="167.1" r="1.6"/>
<circle cx="171.7" cy="169.5" r=".25"/>
<circle cx="173.4" cy="165.4" r=".25"/>
<circle cx="173.4" cy="168.8" r=".25"/>
<circle cx="174.1" cy="167.1" r=".25"/>
<circle cx="192.6" cy="167.3" r=".45"/>
<circle cx="195.6" cy="167.3" r=".45"/>
</g>
<path d="M169.3 142.8h1.6M169.3 151.4h1.6" fill="none" stroke="#fff" stroke-width=".5"/>
<g fill="#fff">
<circle cx="216.1" cy="125.9" r=".5"/>
<circle cx="216.1" cy="128.4" r=".5"/>
<circle cx="216.1" cy="131" r=".5"/>
<circle cx="169.3" cy="127.1" r=".25"/>
<circle cx="170" cy="125.4" r=".25"/>
<circle cx="170" cy="128.8" r=".25"/>
<circle cx="171.7" cy="124.7" r=".25"/>
<circle cx="171.7" cy="127.1" r="1.6"/>
<circle cx="171.7" cy="129.5" r=".25"/>
<circle cx="173.4" cy="125.4" r=".25"/>
<circle cx="173.4" cy="128.8" r=".25"/>
<circle cx="174.1" cy="127.1" r=".25"/>
</g>
<g fill="#cecece">
<path d="M202 151.9h.8v.2h-.8z" fill-rule="evenodd"/>
<path d="M202 151.2h.8v.3h-.8z" fill-rule="evenodd"/>
<path d="M202 150.6h.8v.2h-.8z" fill-rule="evenodd"/>
<path d="M202 149.9h.8v.3h-.8z" fill-rule="evenodd"/>
<path d="M201.3 148.7h.3v.8h-.3z" fill-rule="evenodd"/>
<path d="M200.7 148.7h.2v.8h-.2z" fill-rule="evenodd"/>
<path d="M200 148.7h.3v.8h-.3z" fill-rule="evenodd"/>
<path d="M199.4 148.7h.2v.8h-.2z" fill-rule="evenodd"/>
<path d="M198.1 149.9h.8v.3h-.8z" fill-rule="evenodd"/>
<path d="M198.1 150.6h.8v.2h-.8z" fill-rule="evenodd"/>
<path d="M198.1 151.2h.8v.3h-.8z" fill-rule="evenodd"/>
<path d="M198.1 151.9h.8v.2h-.8z" fill-rule="evenodd"/>
<path d="M199.4 152.6h.2v.8h-.2z" fill-rule="evenodd"/>
<path d="M200 152.6h.3v.8h-.3z" fill-rule="evenodd"/>
<path d="M200.7 152.6h.2v.8h-.2z" fill-rule="evenodd"/>
<path d="M201.3 152.6h.3v.8h-.3z" fill-rule="evenodd"/>
<path d="M199.4 150h2.1v2.1h-2.1z" fill-rule="evenodd"/>
<path d="M202.2 127.4h.6v.6h-.6z" fill-rule="evenodd"/>
<path d="M202.2 126h.6v.6h-.6z" fill-rule="evenodd"/>
<path d="M219.3 165.9h.8v.7h-.8z" fill-rule="evenodd"/>
<path d="M219.3 164.2h.8v.7h-.8z" fill-rule="evenodd"/>
<path d="M227.2 133.6l.5 .1-.1 1.2-.5-.1z" fill-rule="evenodd"/>
<path d="M226.2 133.6l.6 .1-.1 1.2-.5-.1z" fill-rule="evenodd"/>
<path d="M225.3 133.6l.5 .1-.1 1.2-.5-.1z" fill-rule="evenodd"/>
<path d="M225.3 135.9h.5l-.1 1.3-.5-.1z" fill-rule="evenodd"/>
<path d="M227.2 135.9h.5l-.1 1.3-.5-.1z" fill-rule="evenodd"/>
<path d="M203.5 151.6h.8v.8h-.8z" fill-rule="evenodd"/>
<path d="M203.5 150.1h.8v.8h-.8z" fill-rule="evenodd"/>
<path d="M219.5 152.6h.7v.8h-.7z" fill-rule="evenodd"/>
<path d="M221 152.6h.8v.8h-.8z" fill-rule="evenodd"/>
<path d="M241.9 141.7h.7v.8h-.7z" fill-rule="evenodd"/>
<path d="M240.2 141.7h.7v.8h-.7z" fill-rule="evenodd"/>
</g>
<g fill="#cecece">
<circle cx="241.3" cy="167.1" r=".4"/>
<circle cx="242" cy="165.4" r=".4"/>
<circle cx="242" cy="168.8" r=".4"/>
<circle cx="243.7" cy="164.7" r=".4"/>
<circle cx="243.7" cy="167.1" r="3.2"/>
<circle cx="243.7" cy="169.5" r=".4"/>
<circle cx="245.4" cy="165.4" r=".4"/>
<circle cx="245.4" cy="168.8" r=".4"/>
<circle cx="246.1" cy="167.1" r=".4"/>
<circle cx="239.4" cy="151.9" r=".33"/>
</g>
<path d="M239.4 144.6v.3" fill="none" stroke="#cecece" stroke-width=".65"/>
<g fill="#cecece">
<path d="M238.4 150.9h.7v.3h-.7z" fill-rule="evenodd"/>
<path d="M238.4 150.4h.7v.3h-.7z" fill-rule="evenodd"/>
<path d="M238.4 149.9h.7v.3h-.7z" fill-rule="evenodd"/>
<path d="M238.4 149.4h.7v.3h-.7z" fill-rule="evenodd"/>
<path d="M238.4 148.9h.7v.3h-.7z" fill-rule="evenodd"/>
<path d="M238.4 148.4h.7v.3h-.7z" fill-rule="evenodd"/>
<path d="M238.4 147.9h.7v.3h-.7z" fill-rule="evenodd"/>
<path d="M238.4 147.4h.7v.3h-.7z" fill-rule="evenodd"/>
<path d="M238.4 146.9h.7v.3h-.7z" fill-rule="evenodd"/>
<path d="M238.4 146.4h.7v.3h-.7z" fill-rule="evenodd"/>
<path d="M238.4 145.9h.7v.3h-.7z" fill-rule="evenodd"/>
<path d="M238.4 145.4h.7v.3h-.7z" fill-rule="evenodd"/>
<path d="M240.1 145.7h.7v.3h-.7z" fill-rule="evenodd"/>
<path d="M240.1 146.2h.7v.3h-.7z" fill-rule="evenodd"/>
<path d="M240.1 146.7h.7v.3h-.7z" fill-rule="evenodd"/>
<path d="M240.1 147.2h.7v.3h-.7z" fill-rule="evenodd"/>
<path d="M240.1 147.7h.7v.3h-.7z" fill-rule="evenodd"/>
<path d="M240.1 148.2h.7v.3h-.7z" fill-rule="evenodd"/>
<path d="M240.1 148.7h.7v.3h-.7z" fill-rule="evenodd"/>
<path d="M240.1 149.2h.7v.3h-.7z" fill-rule="evenodd"/>
<path d="M240.1 149.7h.7v.3h-.7z" fill-rule="evenodd"/>
<path d="M240.1 150.2h.7v.3h-.7z" fill-rule="evenodd"/>
<path d="M240.1 150.7h.7v.3h-.7z" fill-rule="evenodd"/>
<path d="M240.1 151.2h.7v.3h-.7z" fill-rule="evenodd"/>
</g>
<path d="M240.3 152.4h.6M240.3 144.2h.6M246.3 152.8h.6M246.3 143.8h.6" fill="none" stroke="#cecece" stroke-width=".8"/>
<g fill="#cecece">
<path d="M239.8 154.2h.7v.8h-.7z" fill-rule="evenodd"/>
<path d="M238.1 154.2h.7v.8h-.7z" fill-rule="evenodd"/>
<path d="M200.3 165.9h.8v.7h-.8z" fill-rule="evenodd"/>
<path d="M200.3 164.2h.8v.7h-.8z" fill-rule="evenodd"/>
<path d="M216.9 152.8h.8v.7h-.8z" fill-rule="evenodd"/>
<path d="M216.9 151.1h.8v.7h-.8z" fill-rule="evenodd"/>
<path d="M178.1 129.4h1.7v1.7h-1.7z" fill-rule="evenodd"/>
<path d="M222.7 141.9h.8v.8h-.8z" fill-rule="evenodd"/>
<path d="M222.7 140.3h.8v.8h-.8z" fill-rule="evenodd"/>
<path d="M180.7 132.5l.7-.1 .2 .2v.9l-.1 .3h-.7l-.2-.2z" fill-rule="evenodd"/>
<path d="M178.8 132.5l.8-.1 .2 .2v.9l-.2 .3h-.6l-.2-.2z" fill-rule="evenodd"/>
<path d="M193.2 124.6l.7-.1 .2 .2v.9l-.1 .3h-.7l-.2-.2z" fill-rule="evenodd"/>
<path d="M195 124.6l.7-.1 .2 .2v.9l-.1 .3h-.6l-.3-.2z" fill-rule="evenodd"/>
<path d="M235.1 138.8l.6 .1-.1 1.8-.5-.1z" fill-rule="evenodd"/>
<path d="M233.9 138.8l.5 .1-.1 1.8-.5-.1z" fill-rule="evenodd"/>
<path d="M232.6 138.8l.6 .1-.1 1.8-.5-.1z" fill-rule="evenodd"/>
<path d="M231.3 138.8l.6 .1-.1 1.8-.5-.1z" fill-rule="evenodd"/>
<path d="M231.3 143.8h.6l-.1 1.9-.5-.1z" fill-rule="evenodd"/>
<path d="M232.6 143.8h.6l-.1 1.9-.5-.1z" fill-rule="evenodd"/>
<path d="M233.9 143.8h.5l-.1 1.9-.5-.1z" fill-rule="evenodd"/>
<path d="M235.1 143.8h.6l-.1 1.9-.5-.1z" fill-rule="evenodd"/>
<path d="M223.5 136.2h.8v.8h-.8z" fill-rule="evenodd"/>
<path d="M223.5 134.6h.8v.8h-.8z" fill-rule="evenodd"/>
<path d="M213.1 167.4h1.6v1.6h-1.6z" fill-rule="evenodd"/>
<path d="M183.9 133.6h.7v.8h-.7z" fill-rule="evenodd"/>
<path d="M185.6 133.6h.7v.8h-.7z" fill-rule="evenodd"/>
<path d="M179.1 163h1.5v1.4h-1.5z" fill-rule="evenodd"/>
<path d="M179.1 167.6h1.5v1.2h-1.5z" fill-rule="evenodd"/>
<path d="M187 163h1.6v1.4h-1.6z" fill-rule="evenodd"/>
<path d="M187 167.6h1.6v1.2h-1.6z" fill-rule="evenodd"/>
<path d="M200.3 129.7h.7v.8h-.7z" fill-rule="evenodd"/>
<path d="M202 129.7h.7v.8h-.7z" fill-rule="evenodd"/>
<path d="M213.2 147.5h.8v.8h-.8z" fill-rule="evenodd"/>
<path d="M213.2 149.1h.8v.8h-.8z" fill-rule="evenodd"/>
<path d="M200.7 126h.6v.6h-.6z" fill-rule="evenodd"/>
<path d="M200.7 127.4h.6v.6h-.6z" fill-rule="evenodd"/>
<path d="M229.6 139.4h.8v.7h-.8z" fill-rule="evenodd"/>
<path d="M229.6 141.1h.8v.7h-.8z" fill-rule="evenodd"/>
<path d="M177.7 147.4h.4l.1 .3-.5 .1z" fill-rule="evenodd"/>
<path d="M177.7 146.9h.6v.3h-.6z" fill-rule="evenodd"/>
<path d="M177.7 146.4h.5v.3h-.5z" fill-rule="evenodd"/>
<path d="M176 146.4h.5v.3h-.5z" fill-rule="evenodd"/>
<path d="M175.9 146.9h.5l.1 .3h-.6z" fill-rule="evenodd"/>
<path d="M176 147.4h.4l.1 .3-.5 .1z" fill-rule="evenodd"/>
<path d="M184 131.5h.5v1.4l-.5-.1z" fill-rule="evenodd"/>
<path d="M185.9 131.5h.5v1.4l-.5-.1z" fill-rule="evenodd"/>
<path d="M184.9 129.6l.6 .1-.1 1.3-.5-.1z" fill-rule="evenodd"/>
<path d="M211.8 145.3h.8v.8h-.8z" fill-rule="evenodd"/>
<path d="M211.8 143.8h.8v.7h-.8z" fill-rule="evenodd"/>
<path d="M197.3 130l.4-.1 .1 .4h-.4z" fill-rule="evenodd"/>
<path d="M197.2 130.5h.6v.3h-.6z" fill-rule="evenodd"/>
<path d="M197.3 131h.4l.1 .3-.4 .1z" fill-rule="evenodd"/>
<path d="M199 131h.4l.1 .3-.4 .1z" fill-rule="evenodd"/>
<path d="M199 130.5h.6v.3h-.6z" fill-rule="evenodd"/>
<path d="M199 130l.4-.1 .1 .4h-.4z" fill-rule="evenodd"/>
<path d="M196.6 147.2h.8v.6h-.8z" fill-rule="evenodd"/>
<path d="M196.6 148.8h.8v.7h-.8z" fill-rule="evenodd"/>
<path d="M213.3 143.1h.8v.7h-.8z" fill-rule="evenodd"/>
<path d="M213.3 144.8h.8v.7h-.8z" fill-rule="evenodd"/>
<path d="M190 126.8h.8v.8h-.8z" fill-rule="evenodd"/>
<path d="M188.5 126.8h.7v.8h-.7z" fill-rule="evenodd"/>
<path d="M234.7 147.8l.4-.1 .1 .4h-.4z" fill-rule="evenodd"/>
<path d="M234.6 148.3h.6v.3h-.6z" fill-rule="evenodd"/>
<path d="M234.7 148.8h.4l.1 .3-.4 .1z" fill-rule="evenodd"/>
<path d="M236.4 148.8h.4l.1 .3-.4 .1z" fill-rule="evenodd"/>
<path d="M236.4 148.3h.6v.3h-.6z" fill-rule="evenodd"/>
<path d="M236.4 147.8l.4-.1 .1 .4h-.4z" fill-rule="evenodd"/>
<path d="M177.7 163.2h.8v.7h-.8z" fill-rule="evenodd"/>
<path d="M177.7 164.8h.8v.7h-.8z" fill-rule="evenodd"/>
<path d="M225.2 142.8h1.2v1.4h-1.2z" fill-rule="evenodd"/>
<path d="M225.2 145h1.2v1.4h-1.2z" fill-rule="evenodd"/>
<path d="M226.9 145h1.2v1.4h-1.2z" fill-rule="evenodd"/>
<path d="M226.9 142.8h1.2v1.4h-1.2z" fill-rule="evenodd"/>
<path d="M236.6 144.8h.8v.7h-.8z" fill-rule="evenodd"/>
<path d="M236.6 143.2h.8v.8h-.8z" fill-rule="evenodd"/>
<path d="M177.7 166.3h.8v.8h-.8z" fill-rule="evenodd"/>
<path d="M177.7 167.8h.8v.8h-.8z" fill-rule="evenodd"/>
<path d="M220.1 143.8h.2l-.1 .8-.2-.1z" fill-rule="evenodd"/>
<path d="M219.6 143.8h.2l-.1 .8-.2-.1z" fill-rule="evenodd"/>
<path d="M219.1 143.8h.2l-.1 .8-.2-.1z" fill-rule="evenodd"/>
<path d="M218.6 143.8h.2l-.1 .8-.2-.1z" fill-rule="evenodd"/>
<path d="M218.1 143.8h.2l-.1 .8-.2-.1z" fill-rule="evenodd"/>
<path d="M217.6 143.8h.2l-.1 .8-.2-.1z" fill-rule="evenodd"/>
<path d="M217.1 143.8h.2l-.1 .8-.2-.1z" fill-rule="evenodd"/>
<path d="M216.6 143.8h.2l-.1 .8-.2-.1z" fill-rule="evenodd"/>
<path d="M216.1 143.8h.2l-.1 .8-.2-.1z" fill-rule="evenodd"/>
<path d="M214.8 145h.8v.2h-.7z" fill-rule="evenodd"/>
<path d="M214.8 145.5h.8v.2h-.7z" fill-rule="evenodd"/>
<path d="M214.8 146h.8v.2h-.7z" fill-rule="evenodd"/>
<path d="M214.8 146.5h.8v.2h-.7z" fill-rule="evenodd"/>
<path d="M214.8 147h.8v.2h-.7z" fill-rule="evenodd"/>
<path d="M214.8 147.5h.8v.2h-.7z" fill-rule="evenodd"/>
<path d="M214.8 148h.8v.2h-.7z" fill-rule="evenodd"/>
<path d="M214.8 148.5h.8v.2h-.7z" fill-rule="evenodd"/>
<path d="M214.8 149h.8v.2h-.7z" fill-rule="evenodd"/>
<path d="M216.1 149.6l.2 .1-.1 .8-.2-.1z" fill-rule="evenodd"/>
<path d="M216.6 149.6l.2 .1-.1 .8-.2-.1z" fill-rule="evenodd"/>
<path d="M217.1 149.6l.2 .1-.1 .8-.2-.1z" fill-rule="evenodd"/>
<path d="M217.6 149.6l.2 .1-.1 .8-.2-.1z" fill-rule="evenodd"/>
<path d="M218.1 149.6l.2 .1-.1 .8-.2-.1z" fill-rule="evenodd"/>
<path d="M218.6 149.6l.2 .1-.1 .8-.2-.1z" fill-rule="evenodd"/>
<path d="M219.1 149.6l.2 .1-.1 .8-.2-.1z" fill-rule="evenodd"/>
<path d="M219.6 149.6l.2 .1-.1 .8-.2-.1z" fill-rule="evenodd"/>
<path d="M220.1 149.6l.2 .1-.1 .8-.2-.1z" fill-rule="evenodd"/>
<path d="M220.7 149h.8v.2h-.8z" fill-rule="evenodd"/>
<path d="M220.7 148.5h.8v.2h-.8z" fill-rule="evenodd"/>
<path d="M220.7 148h.8v.2h-.8z" fill-rule="evenodd"/>
<path d="M220.7 147.5h.8v.2h-.8z" fill-rule="evenodd"/>
<path d="M220.7 147h.8v.2h-.8z" fill-rule="evenodd"/>
<path d="M220.7 146.5h.8v.2h-.8z" fill-rule="evenodd"/>
<path d="M220.7 146h.8v.2h-.8z" fill-rule="evenodd"/>
<path d="M220.7 145.5h.8v.2h-.8z" fill-rule="evenodd"/>
<path d="M220.7 145h.8v.2h-.8z" fill-rule="evenodd"/>
<path d="M216.3 145.2h3.7v3.7h-3.7z" fill-rule="evenodd"/>
<path d="M227 137.8h.8v.8h-.8z" fill-rule="evenodd"/>
<path d="M225.5 137.8h.7v.8h-.7z" fill-rule="evenodd"/>
<path d="M200.3 168.8h.8v.8h-.8z" fill-rule="evenodd"/>
<path d="M200.3 167.2h.8v.8h-.8z" fill-rule="evenodd"/>
<path d="M190 165.8h1v.8h-1z" fill-rule="evenodd"/>
<path d="M190 168h1v.8h-1z" fill-rule="evenodd"/>
<path d="M197.2 165.8h1.1v.8h-1.1z" fill-rule="evenodd"/>
<path d="M197.2 168h1.1v.8h-1.1z" fill-rule="evenodd"/>
<path d="M191.5 164.8h.7v1.5h-.7z" fill-rule="evenodd"/>
<path d="M194.5 164.8h.7v1.5h-.7z" fill-rule="evenodd"/>
<path d="M196 164.8h.7v1.5h-.7z" fill-rule="evenodd"/>
<path d="M222.2 149.6h.6v.8h-.6z" fill-rule="evenodd"/>
<path d="M223.8 149.6h.7v.8h-.7z" fill-rule="evenodd"/>
<path d="M227 139.3h.8v.8h-.8z" fill-rule="evenodd"/>
<path d="M225.5 139.3h.7v.8h-.7z" fill-rule="evenodd"/>
<path d="M169.7 149.7h1.2v.3h-1.2z" fill-rule="evenodd"/>
<path d="M169.7 149.2h1.2v.3h-1.2z" fill-rule="evenodd"/>
<path d="M169.7 148.7h1.2v.3h-1.2z" fill-rule="evenodd"/>
<path d="M169.7 148.2h1.2v.3h-1.2z" fill-rule="evenodd"/>
<path d="M169.7 147.7h1.2v.3h-1.2z" fill-rule="evenodd"/>
<path d="M169.7 147.2h1.2v.3h-1.2z" fill-rule="evenodd"/>
<path d="M169.7 146.7h1.2v.3h-1.2z" fill-rule="evenodd"/>
<path d="M169.7 146.2h1.2v.3h-1.2z" fill-rule="evenodd"/>
<path d="M169.7 145.7h1.2v.3h-1.2z" fill-rule="evenodd"/>
<path d="M169.7 145.2h1.2v.3h-1.2z" fill-rule="evenodd"/>
<path d="M169.7 144.7h1.2v.3h-1.2z" fill-rule="evenodd"/>
<path d="M169.7 144.2h1.2v.3h-1.2z" fill-rule="evenodd"/>
<path d="M167.9 144.2h1.1v.3h-1.1z" fill-rule="evenodd"/>
<path d="M167.9 144.7h1.1v.3h-1.1z" fill-rule="evenodd"/>
<path d="M167.9 145.2h1.1v.3h-1.1z" fill-rule="evenodd"/>
<path d="M167.9 145.7h1.1v.3h-1.1z" fill-rule="evenodd"/>
<path d="M167.9 146.2h1.1v.3h-1.1z" fill-rule="evenodd"/>
<path d="M167.9 146.7h1.1v.3h-1.1z" fill-rule="evenodd"/>
<path d="M167.9 147.2h1.1v.3h-1.1z" fill-rule="evenodd"/>
<path d="M167.9 147.7h1.1v.3h-1.1z" fill-rule="evenodd"/>
<path d="M167.9 148.2h1.1v.3h-1.1z" fill-rule="evenodd"/>
<path d="M167.9 148.7h1.1v.3h-1.1z" fill-rule="evenodd"/>
<path d="M167.9 149.2h1.1v.3h-1.1z" fill-rule="evenodd"/>
<path d="M167.9 149.7h1.1v.3h-1.1z" fill-rule="evenodd"/>
</g>
<g fill="#cecece">
<circle cx="181.5" cy="130.3" r=".85"/>
<circle cx="211.4" cy="168.2" r=".85"/>
<circle cx="208.8" cy="168.2" r=".85"/>
<circle cx="241.3" cy="127.1" r=".4"/>
<circle cx="242" cy="125.4" r=".4"/>
<circle cx="242" cy="128.8" r=".4"/>
<circle cx="243.7" cy="124.7" r=".4"/>
<circle cx="243.7" cy="127.1" r="3.2"/>
<circle cx="243.7" cy="129.5" r=".4"/>
<circle cx="245.4" cy="125.4" r=".4"/>
<circle cx="245.4" cy="128.8" r=".4"/>
<circle cx="246.1" cy="127.1" r=".4"/>
<circle cx="169.3" cy="167.1" r=".4"/>
<circle cx="170" cy="165.4" r=".4"/>
<circle cx="170" cy="168.8" r=".4"/>
<circle cx="171.7" cy="164.7" r=".4"/>
<circle cx="171.7" cy="167.1" r="3.2"/>
<circle cx="171.7" cy="169.5" r=".4"/>
<circle cx="173.4" cy="165.4" r=".4"/>
<circle cx="173.4" cy="168.8" r=".4"/>
<circle cx="174.1" cy="167.1" r=".4"/>
<circle cx="192.6" cy="167.3" r=".45"/>
<circle cx="195.6" cy="167.3" r=".45"/>
</g>
<path d="M169.3 142.8h1.6" fill="none" stroke="#cecece" stroke-width="1"/>
<g fill="#cecece">
<path d="M167.8 143.3h1.8v.5h-1.8z" fill-rule="evenodd"/>
<path d="M167.8 150.4h1.8v.5h-1.8z" fill-rule="evenodd"/>
</g>
<path d="M169.3 151.4h1.6" fill="none" stroke="#cecece" stroke-width="1"/>
<g fill="#cecece">
<path d="M214.9 142.3h.7v.8h-.7z" fill-rule="evenodd"/>
<path d="M216.4 142.3h.8v.8h-.8z" fill-rule="evenodd"/>
<path d="M228.8 143.5h.8v.7h-.8z" fill-rule="evenodd"/>
<path d="M228.8 145h.8v.8h-.8z" fill-rule="evenodd"/>
<path d="M209.8 125.3h.8v2.4h-.8z" fill-rule="evenodd"/>
<path d="M209.8 129.2h.8v2.4h-.8z" fill-rule="evenodd"/>
<path d="M208.5 125.3h.8v2.4h-.8z" fill-rule="evenodd"/>
<path d="M208.5 129.2h.8v2.4h-.8z" fill-rule="evenodd"/>
<path d="M207.3 125.3h.7v2.4h-.7z" fill-rule="evenodd"/>
<path d="M207.3 129.2h.7v2.4h-.7z" fill-rule="evenodd"/>
<path d="M206 125.3h.7v2.4h-.7z" fill-rule="evenodd"/>
<path d="M206 129.2h.7v2.4h-.7z" fill-rule="evenodd"/>
<path d="M204.7 125.3h.8v2.4h-.8z" fill-rule="evenodd"/>
<path d="M204.7 129.2h.8v2.4h-.8z" fill-rule="evenodd"/>
<path d="M221.1 151.1h.7v.8h-.7z" fill-rule="evenodd"/>
<path d="M219.4 151.1h.7v.8h-.7z" fill-rule="evenodd"/>
<path d="M215.2 125.1h1.7v1.7h-1.7z" fill-rule="evenodd"/>
<path d="M189.8 124.6l.7-.1 .2 .2v.9l-.1 .3h-.7l-.2-.2z" fill-rule="evenodd"/>
<path d="M191.6 124.6l.7-.1 .2 .2v.9l-.1 .3h-.6l-.3-.2z" fill-rule="evenodd"/>
<path d="M191.3 127.7h.6v.2h-.6z" fill-rule="evenodd"/>
<path d="M191.8 127.5h.1v.3h-.1z" fill-rule="evenodd"/>
<path d="M191.3 128.1h.6v.2h-.6z" fill-rule="evenodd"/>
<path d="M191.3 128.5h.6v.2h-.6z" fill-rule="evenodd"/>
<path d="M191.3 128.9h.6v.2h-.6z" fill-rule="evenodd"/>
<path d="M191.3 129.3h.6v.2h-.6z" fill-rule="evenodd"/>
<path d="M192.2 129.1h.2v.6h-.2z" fill-rule="evenodd"/>
<path d="M192.6 129.3h.6v.2h-.6z" fill-rule="evenodd"/>
<path d="M192.6 128.9h.6v.2h-.6z" fill-rule="evenodd"/>
<path d="M192.6 128.5h.6v.2h-.6z" fill-rule="evenodd"/>
<path d="M192.6 128.1h.6v.2h-.6z" fill-rule="evenodd"/>
<path d="M192.6 127.7h.6v.2h-.6z" fill-rule="evenodd"/>
<path d="M192.2 127.5h.2v.6h-.2z" fill-rule="evenodd"/>
<path d="M219.3 168.8h.8v.8h-.8z" fill-rule="evenodd"/>
<path d="M219.3 167.2h.8v.8h-.8z" fill-rule="evenodd"/>
<path d="M223.8 143.4h.8v.7h-.8z" fill-rule="evenodd"/>
<path d="M223.8 145.1h.8v.7h-.8z" fill-rule="evenodd"/>
<path d="M193.8 126.8h.8v.8h-.8z" fill-rule="evenodd"/>
<path d="M195.4 126.8h.7v.8h-.7z" fill-rule="evenodd"/>
<path d="M195.1 148.7h.8v.8h-.8z" fill-rule="evenodd"/>
<path d="M195.1 147.2h.8v.7h-.8z" fill-rule="evenodd"/>
<path d="M221.2 142h.8v.7h-.8z" fill-rule="evenodd"/>
<path d="M221.2 140.3h.8v.7h-.8z" fill-rule="evenodd"/>
<path d="M196.6 150.3h.8v.8h-.8z" fill-rule="evenodd"/>
<path d="M195 150.3h.8v.8h-.8z" fill-rule="evenodd"/>
<path d="M200.3 131.3h.7v.8h-.7z" fill-rule="evenodd"/>
<path d="M202 131.3h.7v.8h-.7z" fill-rule="evenodd"/>
<path d="M198.2 147.3h.8v.7h-.8z" fill-rule="evenodd"/>
<path d="M198.2 145.7h.8v.8h-.8z" fill-rule="evenodd"/>
<path d="M227 141.3h.8v.8h-.8z" fill-rule="evenodd"/>
<path d="M225.4 141.3h.8v.8h-.8z" fill-rule="evenodd"/>
<path d="M217 136.3h.9v.8h-.9z" fill-rule="evenodd"/>
<path d="M217 134.8h.9v.8h-.9z" fill-rule="evenodd"/>
<path d="M220.9 136.4h1.2v.5l-1.2 .1z" fill-rule="evenodd"/>
<path d="M220.9 135.5l1.2-.1v.5l-1.2 .1z" fill-rule="evenodd"/>
<path d="M220.9 134.5h1.2v.5l-1.2 .1z" fill-rule="evenodd"/>
<path d="M218.6 134.5h1.2l.1 .5-1.3 .1z" fill-rule="evenodd"/>
<path d="M218.6 136.4h1.2l.1 .5-1.3 .1z" fill-rule="evenodd"/>
<path d="M200.6 151.2h.8v.7h-.8z" fill-rule="evenodd"/>
<path d="M200.6 150.1h.8v.8h-.8z" fill-rule="evenodd"/>
<path d="M199.6 151.2h.7v.7h-.7z" fill-rule="evenodd"/>
<path d="M199.6 150.1h.7v.8h-.7z" fill-rule="evenodd"/>
<path d="M202 151.9h.8v.2h-.8z" fill-rule="evenodd"/>
<path d="M202 151.2h.8v.3h-.8z" fill-rule="evenodd"/>
<path d="M202 150.6h.8v.2h-.8z" fill-rule="evenodd"/>
<path d="M202 149.9h.8v.3h-.8z" fill-rule="evenodd"/>
<path d="M201.3 148.7h.3v.8h-.3z" fill-rule="evenodd"/>
<path d="M200.7 148.7h.2v.8h-.2z" fill-rule="evenodd"/>
<path d="M200 148.7h.3v.8h-.3z" fill-rule="evenodd"/>
<path d="M199.4 148.7h.2v.8h-.2z" fill-rule="evenodd"/>
<path d="M198.1 149.9h.8v.3h-.8z" fill-rule="evenodd"/>
<path d="M198.1 150.6h.8v.2h-.8z" fill-rule="evenodd"/>
<path d="M198.1 151.2h.8v.3h-.8z" fill-rule="evenodd"/>
<path d="M198.1 151.9h.8v.2h-.8z" fill-rule="evenodd"/>
<path d="M199.4 152.6h.2v.8h-.2z" fill-rule="evenodd"/>
<path d="M200 152.6h.3v.8h-.3z" fill-rule="evenodd"/>
<path d="M200.7 152.6h.2v.8h-.2z" fill-rule="evenodd"/>
<path d="M201.3 152.6h.3v.8h-.3z" fill-rule="evenodd"/>
<path d="M202.2 127.4h.6v.6h-.6z" fill-rule="evenodd"/>
<path d="M202.2 126h.6v.6h-.6z" fill-rule="evenodd"/>
<path d="M219.3 165.9h.8v.7h-.8z" fill-rule="evenodd"/>
<path d="M219.3 164.2h.8v.7h-.8z" fill-rule="evenodd"/>
<path d="M227.2 133.6l.5 .1-.1 1.2-.5-.1z" fill-rule="evenodd"/>
<path d="M226.2 133.6l.6 .1-.1 1.2-.5-.1z" fill-rule="evenodd"/>
<path d="M225.3 133.6l.5 .1-.1 1.2-.5-.1z" fill-rule="evenodd"/>
<path d="M225.3 135.9h.5l-.1 1.3-.5-.1z" fill-rule="evenodd"/>
<path d="M227.2 135.9h.5l-.1 1.3-.5-.1z" fill-rule="evenodd"/>
<path d="M203.5 151.6h.8v.8h-.8z" fill-rule="evenodd"/>
<path d="M203.5 150.1h.8v.8h-.8z" fill-rule="evenodd"/>
<path d="M219.5 152.6h.7v.8h-.7z" fill-rule="evenodd"/>
<path d="M221 152.6h.8v.8h-.8z" fill-rule="evenodd"/>
<path d="M241.9 141.7h.7v.8h-.7z" fill-rule="evenodd"/>
<path d="M240.2 141.7h.7v.8h-.7z" fill-rule="evenodd"/>
<path d="M238.4 150.9h.7v.3h-.7z" fill-rule="evenodd"/>
<path d="M238.4 150.4h.7v.3h-.7z" fill-rule="evenodd"/>
<path d="M238.4 149.9h.7v.3h-.7z" fill-rule="evenodd"/>
<path d="M238.4 149.4h.7v.3h-.7z" fill-rule="evenodd"/>
<path d="M238.4 148.9h.7v.3h-.7z" fill-rule="evenodd"/>
<path d="M238.4 148.4h.7v.3h-.7z" fill-rule="evenodd"/>
<path d="M238.4 147.9h.7v.3h-.7z" fill-rule="evenodd"/>
<path d="M238.4 147.4h.7v.3h-.7z" fill-rule="evenodd"/>
<path d="M238.4 146.9h.7v.3h-.7z" fill-rule="evenodd"/>
<path d="M238.4 146.4h.7v.3h-.7z" fill-rule="evenodd"/>
<path d="M238.4 145.9h.7v.3h-.7z" fill-rule="evenodd"/>
<path d="M238.4 145.4h.7v.3h-.7z" fill-rule="evenodd"/>
<path d="M240.1 145.7h.7v.3h-.7z" fill-rule="evenodd"/>
<path d="M240.1 146.2h.7v.3h-.7z" fill-rule="evenodd"/>
<path d="M240.1 146.7h.7v.3h-.7z" fill-rule="evenodd"/>
<path d="M240.1 147.2h.7v.3h-.7z" fill-rule="evenodd"/>
<path d="M240.1 147.7h.7v.3h-.7z" fill-rule="evenodd"/>
<path d="M240.1 148.2h.7v.3h-.7z" fill-rule="evenodd"/>
<path d="M240.1 148.7h.7v.3h-.7z" fill-rule="evenodd"/>
<path d="M240.1 149.2h.7v.3h-.7z" fill-rule="evenodd"/>
<path d="M240.1 149.7h.7v.3h-.7z" fill-rule="evenodd"/>
<path d="M240.1 150.2h.7v.3h-.7z" fill-rule="evenodd"/>
<path d="M240.1 150.7h.7v.3h-.7z" fill-rule="evenodd"/>
<path d="M240.1 151.2h.7v.3h-.7z" fill-rule="evenodd"/>
<path d="M239.8 154.2h.7v.8h-.7z" fill-rule="evenodd"/>
<path d="M238.1 154.2h.7v.8h-.7z" fill-rule="evenodd"/>
<path d="M200.3 165.9h.8v.7h-.8z" fill-rule="evenodd"/>
<path d="M200.3 164.2h.8v.7h-.8z" fill-rule="evenodd"/>
<path d="M216.9 152.8h.8v.7h-.8z" fill-rule="evenodd"/>
<path d="M216.9 151.1h.8v.7h-.8z" fill-rule="evenodd"/>
<path d="M222.7 141.9h.8v.8h-.8z" fill-rule="evenodd"/>
<path d="M222.7 140.3h.8v.8h-.8z" fill-rule="evenodd"/>
<path d="M180.7 132.5l.7-.1 .2 .2v.9l-.1 .3h-.7l-.2-.2z" fill-rule="evenodd"/>
<path d="M178.8 132.5l.8-.1 .2 .2v.9l-.2 .3h-.6l-.2-.2z" fill-rule="evenodd"/>
<path d="M235.1 138.8l.6 .1-.1 1.8-.5-.1z" fill-rule="evenodd"/>
<path d="M233.9 138.8l.5 .1-.1 1.8-.5-.1z" fill-rule="evenodd"/>
<path d="M232.6 138.8l.6 .1-.1 1.8-.5-.1z" fill-rule="evenodd"/>
<path d="M231.3 138.8l.6 .1-.1 1.8-.5-.1z" fill-rule="evenodd"/>
<path d="M231.3 143.8h.6l-.1 1.9-.5-.1z" fill-rule="evenodd"/>
<path d="M232.6 143.8h.6l-.1 1.9-.5-.1z" fill-rule="evenodd"/>
<path d="M233.9 143.8h.5l-.1 1.9-.5-.1z" fill-rule="evenodd"/>
<path d="M235.1 143.8h.6l-.1 1.9-.5-.1z" fill-rule="evenodd"/>
<path d="M223.5 136.2h.8v.8h-.8z" fill-rule="evenodd"/>
<path d="M223.5 134.6h.8v.8h-.8z" fill-rule="evenodd"/>
<path d="M183.9 133.6h.7v.8h-.7z" fill-rule="evenodd"/>
<path d="M185.6 133.6h.7v.8h-.7z" fill-rule="evenodd"/>
<path d="M179.1 163h1.5v1.4h-1.5z" fill-rule="evenodd"/>
<path d="M179.1 167.6h1.5v1.2h-1.5z" fill-rule="evenodd"/>
<path d="M187 163h1.6v1.4h-1.6z" fill-rule="evenodd"/>
<path d="M187 167.6h1.6v1.2h-1.6z" fill-rule="evenodd"/>
<path d="M200.3 129.7h.7v.8h-.7z" fill-rule="evenodd"/>
<path d="M202 129.7h.7v.8h-.7z" fill-rule="evenodd"/>
<path d="M213.2 147.5h.8v.8h-.8z" fill-rule="evenodd"/>
<path d="M213.2 149.1h.8v.8h-.8z" fill-rule="evenodd"/>
<path d="M200.7 126h.6v.6h-.6z" fill-rule="evenodd"/>
<path d="M200.7 127.4h.6v.6h-.6z" fill-rule="evenodd"/>
<path d="M229.6 139.4h.8v.7h-.8z" fill-rule="evenodd"/>
<path d="M229.6 141.1h.8v.7h-.8z" fill-rule="evenodd"/>
<path d="M177.7 147.4h.4l.1 .3-.5 .1z" fill-rule="evenodd"/>
<path d="M177.7 146.9h.6v.3h-.6z" fill-rule="evenodd"/>
<path d="M177.7 146.4h.5v.3h-.5z" fill-rule="evenodd"/>
<path d="M176 146.4h.5v.3h-.5z" fill-rule="evenodd"/>
<path d="M175.9 146.9h.5l.1 .3h-.6z" fill-rule="evenodd"/>
<path d="M176 147.4h.4l.1 .3-.5 .1z" fill-rule="evenodd"/>
<path d="M184 131.5h.5v1.4l-.5-.1z" fill-rule="evenodd"/>
<path d="M185.9 131.5h.5v1.4l-.5-.1z" fill-rule="evenodd"/>
<path d="M184.9 129.6l.6 .1-.1 1.3-.5-.1z" fill-rule="evenodd"/>
<path d="M211.8 145.3h.8v.8h-.8z" fill-rule="evenodd"/>
<path d="M211.8 143.8h.8v.7h-.8z" fill-rule="evenodd"/>
<path d="M197.3 130l.4-.1 .1 .4h-.4z" fill-rule="evenodd"/>
<path d="M197.2 130.5h.6v.3h-.6z" fill-rule="evenodd"/>
<path d="M197.3 131h.4l.1 .3-.4 .1z" fill-rule="evenodd"/>
<path d="M199 131h.4l.1 .3-.4 .1z" fill-rule="evenodd"/>
<path d="M199 130.5h.6v.3h-.6z" fill-rule="evenodd"/>
<path d="M199 130l.4-.1 .1 .4h-.4z" fill-rule="evenodd"/>
<path d="M196.6 147.2h.8v.6h-.8z" fill-rule="evenodd"/>
<path d="M196.6 148.8h.8v.7h-.8z" fill-rule="evenodd"/>
<path d="M213.3 143.1h.8v.7h-.8z" fill-rule="evenodd"/>
<path d="M213.3 144.8h.8v.7h-.8z" fill-rule="evenodd"/>
<path d="M190 126.8h.8v.8h-.8z" fill-rule="evenodd"/>
<path d="M188.5 126.8h.7v.8h-.7z" fill-rule="evenodd"/>
<path d="M234.7 147.8l.4-.1 .1 .4h-.4z" fill-rule="evenodd"/>
<path d="M234.6 148.3h.6v.3h-.6z" fill-rule="evenodd"/>
<path d="M234.7 148.8h.4l.1 .3-.4 .1z" fill-rule="evenodd"/>
<path d="M236.4 148.8h.4l.1 .3-.4 .1z" fill-rule="evenodd"/>
<path d="M236.4 148.3h.6v.3h-.6z" fill-rule="evenodd"/>
<path d="M236.4 147.8l.4-.1 .1 .4h-.4z" fill-rule="evenodd"/>
<path d="M177.7 163.2h.8v.7h-.8z" fill-rule="evenodd"/>
<path d="M177.7 164.8h.8v.7h-.8z" fill-rule="evenodd"/>
<path d="M225.2 142.8h1.2v1.4h-1.2z" fill-rule="evenodd"/>
<path d="M225.2 145h1.2v1.4h-1.2z" fill-rule="evenodd"/>
<path d="M226.9 145h1.2v1.4h-1.2z" fill-rule="evenodd"/>
<path d="M226.9 142.8h1.2v1.4h-1.2z" fill-rule="evenodd"/>
<path d="M236.6 144.8h.8v.7h-.8z" fill-rule="evenodd"/>
<path d="M236.6 143.2h.8v.8h-.8z" fill-rule="evenodd"/>
<path d="M177.7 166.3h.8v.8h-.8z" fill-rule="evenodd"/>
<path d="M177.7 167.8h.8v.8h-.8z" fill-rule="evenodd"/>
<path d="M219 145.4h.8v.9h-.8z" fill-rule="evenodd"/>
<path d="M217.7 145.4h.9v.9h-.9z" fill-rule="evenodd"/>
<path d="M216.5 145.4h.9v.9h-.9z" fill-rule="evenodd"/>
<path d="M219 146.7h.8v.8h-.8z" fill-rule="evenodd"/>
<path d="M217.7 146.7h.9v.8h-.9z" fill-rule="evenodd"/>
<path d="M216.5 146.7h.9v.8h-.9z" fill-rule="evenodd"/>
<path d="M219 147.9h.8v.9h-.8z" fill-rule="evenodd"/>
<path d="M217.7 147.9h.9v.9h-.9z" fill-rule="evenodd"/>
<path d="M216.5 147.9h.9v.9h-.9z" fill-rule="evenodd"/>
<path d="M220.1 143.8h.2l-.1 .8-.2-.1z" fill-rule="evenodd"/>
<path d="M219.6 143.8h.2l-.1 .8-.2-.1z" fill-rule="evenodd"/>
<path d="M219.1 143.8h.2l-.1 .8-.2-.1z" fill-rule="evenodd"/>
<path d="M218.6 143.8h.2l-.1 .8-.2-.1z" fill-rule="evenodd"/>
<path d="M218.1 143.8h.2l-.1 .8-.2-.1z" fill-rule="evenodd"/>
<path d="M217.6 143.8h.2l-.1 .8-.2-.1z" fill-rule="evenodd"/>
<path d="M217.1 143.8h.2l-.1 .8-.2-.1z" fill-rule="evenodd"/>
<path d="M216.6 143.8h.2l-.1 .8-.2-.1z" fill-rule="evenodd"/>
<path d="M216.1 143.8h.2l-.1 .8-.2-.1z" fill-rule="evenodd"/>
<path d="M214.8 145h.8v.2h-.7z" fill-rule="evenodd"/>
<path d="M214.8 145.5h.8v.2h-.7z" fill-rule="evenodd"/>
<path d="M214.8 146h.8v.2h-.7z" fill-rule="evenodd"/>
<path d="M214.8 146.5h.8v.2h-.7z" fill-rule="evenodd"/>
<path d="M214.8 147h.8v.2h-.7z" fill-rule="evenodd"/>
<path d="M214.8 147.5h.8v.2h-.7z" fill-rule="evenodd"/>
<path d="M214.8 148h.8v.2h-.7z" fill-rule="evenodd"/>
<path d="M214.8 148.5h.8v.2h-.7z" fill-rule="evenodd"/>
<path d="M214.8 149h.8v.2h-.7z" fill-rule="evenodd"/>
<path d="M216.1 149.6l.2 .1-.1 .8-.2-.1z" fill-rule="evenodd"/>
<path d="M216.6 149.6l.2 .1-.1 .8-.2-.1z" fill-rule="evenodd"/>
<path d="M217.1 149.6l.2 .1-.1 .8-.2-.1z" fill-rule="evenodd"/>
<path d="M217.6 149.6l.2 .1-.1 .8-.2-.1z" fill-rule="evenodd"/>
<path d="M218.1 149.6l.2 .1-.1 .8-.2-.1z" fill-rule="evenodd"/>
<path d="M218.6 149.6l.2 .1-.1 .8-.2-.1z" fill-rule="evenodd"/>
<path d="M219.1 149.6l.2 .1-.1 .8-.2-.1z" fill-rule="evenodd"/>
<path d="M219.6 149.6l.2 .1-.1 .8-.2-.1z" fill-rule="evenodd"/>
<path d="M220.1 149.6l.2 .1-.1 .8-.2-.1z" fill-rule="evenodd"/>
<path d="M220.7 149h.8v.2h-.8z" fill-rule="evenodd"/>
<path d="M220.7 148.5h.8v.2h-.8z" fill-rule="evenodd"/>
<path d="M220.7 148h.8v.2h-.8z" fill-rule="evenodd"/>
<path d="M220.7 147.5h.8v.2h-.8z" fill-rule="evenodd"/>
<path d="M220.7 147h.8v.2h-.8z" fill-rule="evenodd"/>
<path d="M220.7 146.5h.8v.2h-.8z" fill-rule="evenodd"/>
<path d="M220.7 146h.8v.2h-.8z" fill-rule="evenodd"/>
<path d="M220.7 145.5h.8v.2h-.8z" fill-rule="evenodd"/>
<path d="M220.7 145h.8v.2h-.8z" fill-rule="evenodd"/>
<path d="M227 137.8h.8v.8h-.8z" fill-rule="evenodd"/>
<path d="M225.5 137.8h.7v.8h-.7z" fill-rule="evenodd"/>
<path d="M200.3 168.8h.8v.8h-.8z" fill-rule="evenodd"/>
<path d="M200.3 167.2h.8v.8h-.8z" fill-rule="evenodd"/>
<path d="M190 165.8h1v.8h-1z" fill-rule="evenodd"/>
<path d="M190 168h1v.8h-1z" fill-rule="evenodd"/>
<path d="M197.2 165.8h1.1v.8h-1.1z" fill-rule="evenodd"/>
<path d="M197.2 168h1.1v.8h-1.1z" fill-rule="evenodd"/>
<path d="M191.5 164.8h.7v1.5h-.7z" fill-rule="evenodd"/>
<path d="M194.5 164.8h.7v1.5h-.7z" fill-rule="evenodd"/>
<path d="M196 164.8h.7v1.5h-.7z" fill-rule="evenodd"/>
<path d="M222.2 149.6h.6v.8h-.6z" fill-rule="evenodd"/>
<path d="M223.8 149.6h.7v.8h-.7z" fill-rule="evenodd"/>
<path d="M227 139.3h.8v.8h-.8z" fill-rule="evenodd"/>
<path d="M225.5 139.3h.7v.8h-.7z" fill-rule="evenodd"/>
<path d="M169.7 149.7h1.2v.3h-1.2z" fill-rule="evenodd"/>
<path d="M169.7 149.2h1.2v.3h-1.2z" fill-rule="evenodd"/>
<path d="M169.7 148.7h1.2v.3h-1.2z" fill-rule="evenodd"/>
<path d="M169.7 148.2h1.2v.3h-1.2z" fill-rule="evenodd"/>
<path d="M169.7 147.7h1.2v.3h-1.2z" fill-rule="evenodd"/>
<path d="M169.7 147.2h1.2v.3h-1.2z" fill-rule="evenodd"/>
<path d="M169.7 146.7h1.2v.3h-1.2z" fill-rule="evenodd"/>
<path d="M169.7 146.2h1.2v.3h-1.2z" fill-rule="evenodd"/>
<path d="M169.7 145.7h1.2v.3h-1.2z" fill-rule="evenodd"/>
<path d="M169.7 145.2h1.2v.3h-1.2z" fill-rule="evenodd"/>
<path d="M169.7 144.7h1.2v.3h-1.2z" fill-rule="evenodd"/>
<path d="M169.7 144.2h1.2v.3h-1.2z" fill-rule="evenodd"/>
<path d="M167.9 144.2h1.1v.3h-1.1z" fill-rule="evenodd"/>
<path d="M167.9 144.7h1.1v.3h-1.1z" fill-rule="evenodd"/>
<path d="M167.9 145.2h1.1v.3h-1.1z" fill-rule="evenodd"/>
<path d="M167.9 145.7h1.1v.3h-1.1z" fill-rule="evenodd"/>
<path d="M167.9 146.2h1.1v.3h-1.1z" fill-rule="evenodd"/>
<path d="M167.9 146.7h1.1v.3h-1.1z" fill-rule="evenodd"/>
<path d="M167.9 147.2h1.1v.3h-1.1z" fill-rule="evenodd"/>
<path d="M167.9 147.7h1.1v.3h-1.1z" fill-rule="evenodd"/>
<path d="M167.9 148.2h1.1v.3h-1.1z" fill-rule="evenodd"/>
<path d="M167.9 148.7h1.1v.3h-1.1z" fill-rule="evenodd"/>
<path d="M167.9 149.2h1.1v.3h-1.1z" fill-rule="evenodd"/>
<path d="M167.9 149.7h1.1v.3h-1.1z" fill-rule="evenodd"/>
<path d="M167.8 143.3h1.8v.5h-1.8z" fill-rule="evenodd"/>
<path d="M167.8 150.4h1.8v.5h-1.8z" fill-rule="evenodd"/>
<path d="M214.9 142.3h.7v.8h-.7z" fill-rule="evenodd"/>
<path d="M216.4 142.3h.8v.8h-.8z" fill-rule="evenodd"/>
<path d="M228.8 143.5h.8v.7h-.8z" fill-rule="evenodd"/>
<path d="M228.8 145h.8v.8h-.8z" fill-rule="evenodd"/>
<path d="M209.8 125.3h.8v2.4h-.8z" fill-rule="evenodd"/>
<path d="M209.8 129.2h.8v2.4h-.8z" fill-rule="evenodd"/>
<path d="M208.5 125.3h.8v2.4h-.8z" fill-rule="evenodd"/>
<path d="M208.5 129.2h.8v2.4h-.8z" fill-rule="evenodd"/>
<path d="M207.3 125.3h.7v2.4h-.7z" fill-rule="evenodd"/>
<path d="M207.3 129.2h.7v2.4h-.7z" fill-rule="evenodd"/>
<path d="M206 125.3h.7v2.4h-.7z" fill-rule="evenodd"/>
<path d="M206 129.2h.7v2.4h-.7z" fill-rule="evenodd"/>
<path d="M204.7 125.3h.8v2.4h-.8z" fill-rule="evenodd"/>
<path d="M204.7 129.2h.8v2.4h-.8z" fill-rule="evenodd"/>
<path d="M221.1 151.1h.7v.8h-.7z" fill-rule="evenodd"/>
<path d="M219.4 151.1h.7v.8h-.7z" fill-rule="evenodd"/>
<path d="M189.8 124.6l.7-.1 .2 .2v.9l-.1 .3h-.7l-.2-.2z" fill-rule="evenodd"/>
<path d="M191.6 124.6l.7-.1 .2 .2v.9l-.1 .3h-.6l-.3-.2z" fill-rule="evenodd"/>
<path d="M191.3 127.7h.6v.2h-.6z" fill-rule="evenodd"/>
<path d="M191.8 127.5h.1v.3h-.1z" fill-rule="evenodd"/>
<path d="M191.3 128.1h.6v.2h-.6z" fill-rule="evenodd"/>
<path d="M191.3 128.5h.6v.2h-.6z" fill-rule="evenodd"/>
<path d="M191.3 128.9h.6v.2h-.6z" fill-rule="evenodd"/>
<path d="M191.3 129.3h.6v.2h-.6z" fill-rule="evenodd"/>
<path d="M192.2 129.1h.2v.6h-.2z" fill-rule="evenodd"/>
<path d="M192.6 129.3h.6v.2h-.6z" fill-rule="evenodd"/>
<path d="M192.6 128.9h.6v.2h-.6z" fill-rule="evenodd"/>
<path d="M192.6 128.5h.6v.2h-.6z" fill-rule="evenodd"/>
<path d="M192.6 128.1h.6v.2h-.6z" fill-rule="evenodd"/>
<path d="M192.6 127.7h.6v.2h-.6z" fill-rule="evenodd"/>
<path d="M192.2 127.5h.2v.6h-.2z" fill-rule="evenodd"/>
<path d="M219.3 168.8h.8v.8h-.8z" fill-rule="evenodd"/>
<path d="M219.3 167.2h.8v.8h-.8z" fill-rule="evenodd"/>
<path d="M193.8 126.8h.8v.8h-.8z" fill-rule="evenodd"/>
<path d="M195.4 126.8h.7v.8h-.7z" fill-rule="evenodd"/>
<path d="M195.1 148.7h.8v.8h-.8z" fill-rule="evenodd"/>
<path d="M195.1 147.2h.8v.7h-.8z" fill-rule="evenodd"/>
<path d="M221.2 142h.8v.7h-.8z" fill-rule="evenodd"/>
<path d="M221.2 140.3h.8v.7h-.8z" fill-rule="evenodd"/>
<path d="M196.6 150.3h.8v.8h-.8z" fill-rule="evenodd"/>
<path d="M195 150.3h.8v.8h-.8z" fill-rule="evenodd"/>
<path d="M200.3 131.3h.7v.8h-.7z" fill-rule="evenodd"/>
<path d="M202 131.3h.7v.8h-.7z" fill-rule="evenodd"/>
<path d="M198.2 147.3h.8v.7h-.8z" fill-rule="evenodd"/>
<path d="M198.2 145.7h.8v.8h-.8z" fill-rule="evenodd"/>
<path d="M227 141.3h.8v.8h-.8z" fill-rule="evenodd"/>
<path d="M225.4 141.3h.8v.8h-.8z" fill-rule="evenodd"/>
<path d="M217 136.3h.9v.8h-.9z" fill-rule="evenodd"/>
<path d="M217 134.8h.9v.8h-.9z" fill-rule="evenodd"/>
<path d="M220.9 136.4h1.2v.5l-1.2 .1z" fill-rule="evenodd"/>
<path d="M220.9 135.5l1.2-.1v.5l-1.2 .1z" fill-rule="evenodd"/>
<path d="M220.9 134.5h1.2v.5l-1.2 .1z" fill-rule="evenodd"/>
<path d="M218.6 134.5h1.2l.1 .5-1.3 .1z" fill-rule="evenodd"/>
<path d="M218.6 136.4h1.2l.1 .5-1.3 .1z" fill-rule="evenodd"/>
</g>
<g fill="#cecece">
<circle cx="216.1" cy="128.4" r=".85"/>
<circle cx="216.1" cy="131" r=".85"/>
<circle cx="169.3" cy="127.1" r=".4"/>
<circle cx="170" cy="125.4" r=".4"/>
<circle cx="170" cy="128.8" r=".4"/>
<circle cx="171.7" cy="124.7" r=".4"/>
<circle cx="171.7" cy="127.1" r="3.2"/>
<circle cx="171.7" cy="129.5" r=".4"/>
<circle cx="173.4" cy="125.4" r=".4"/>
<circle cx="173.4" cy="128.8" r=".4"/>
<circle cx="174.1" cy="127.1" r=".4"/>
</g>
<g fill="none" stroke="#c7c7c7" stroke-width=".18">
<path d="M176.3 131.4a.36 .36 0 0 0 .3 .5 .36 .36 0 0 0 .3-.5M176.5 130.7h.5M176.5 130.4h.5M176.5 130.1l.1 .3M176.5 127.8v.3M176.5 129.6l.1 .3M176.5 129.9h.5M176.5 128.7h.5M176.9 130.7l.1 .3-.5 .1M177 129.1l-.1 .3h-.4v-.3l.1-.1 .1 .4M177 127.8l-.1 .2h-.7M177 128.3l-.5 .1v.3"/>
<path d="M177.5 128.6h.6M177.8 128.3v.6M206 132a.4 .4 0 0 1 .4 .4 .4 .4 0 0 1-.4 .4zM206.7 132.5l.4-.1v-.1h-.4l.1 .4h.3M207.5 132.3l.2-.1 .2 .2-.1 .3h-.3M207.5 132v.8M208.2 132.2v.5h.3M208.5 132.2v.6M209.3 132.7h-.4l.1-.4h.3v.6l-.2 .1h-.2M214 132.9l.2 .8 .3-.8M214.8 133.2h.2l.1 .1-.1 .4-.3-.1zM215.5 132.9v.7l.1 .1"/>
<path d="M215.8 133.2h.3M215.9 132.9v.7l.2 .1M216.4 133.2h.3v.5M216.7 133.4l-.4 .1 .1 .2h.3M217.4 133.7l-.3-.1v-.4h.3v.6l-.1 .2h-.2M217.8 133.5l.4-.1-.1-.2-.3 .1v.4h.3M218.1 126h.6M218.1 131h.6M218.4 125.7v.6M218.4 130.7v.6M219 125.5h.5l-.3 .3h.2v.4h-.4M219 131.3h.5"/>
<path d="M219 130.8l.2-.3v.8M219.7 125.5l.3 .8 .2-.8M219.7 130.5l.3 .8 .2-.8M220.4 125.5h.5l-.2 .3h.2v.4h-.5M220.6 130.9l-.1-.2 .1-.2 .3 .2-.1 .2M220.6 130.9l-.1 .1 .1 .3 .3-.1-.1-.3M220.6 130.9h.2M168.1 141a.4 .4 0 0 1 .4 .4 .4 .4 0 0 1-.4 .4zM168.8 141.5l.4-.1v-.1h-.4l.1 .4h.3M169.5 141.2l.2 .6 .2-.6M170.2 141h.1M170.2 141.2v.6"/>
<path d="M170.9 141.3l-.2-.1-.2 .2 .1 .3h.3M171.2 141.5l.4-.1-.1-.1h-.3v.4h.3M242.6 153.9v.8M242.6 154.3h.4M243 153.9v.8M243.5 154.2h.1l.2 .1-.2 .4-.2-.2zM244.4 154.2l-.3 .1 .3 .2v.1h-.3M244.7 154.2h.3M244.8 153.9v.7l.2 .1M201.7 169.5h.8M201.8 169.8a.36 .36 0 0 0 .3 .5 .36 .36 0 0 0 .3-.5M202 167.8l.1 .2"/>
<path d="M202 168h.5M202 167.2h.6l.2 .2-.1 .1M202 167.2v.2l.1 .2 .4-.1v-.3M202.2 168.4l.1 .4 .2-.1v-.3M202.5 166.5l-.1 .4-.4-.1v-.3h.2v.4M202.5 168.4l-.5 .1v.3M202.5 169.1l-.5 .1v.3M206 169h.7l.1 .2-.1 .3h-.7M206 166.8v.5M206 167h.8M206.4 168v-.4l-.3-.1-.1 .5h.8M206.6 168.3v.4"/>
<path d="M206.8 168.2l-.8 .3 .8 .3M206.8 167.5l-.4 .3M208.4 165.5v.4M208.4 165.7h.8M208.4 164.3a.43 .43 0 0 1 .5-.2 .43 .43 0 0 1 .3 .5h-.8zM208.7 164.9l.5 .4M209.2 164.9l-.5 .4M210.9 164.6h.8l-.8 .4h.8M211 165.4a.36 .36 0 0 0 .3 .5 .36 .36 0 0 0 .3-.5h-.2v.1M211 163.9a.43 .43 0 0 1 .5-.1 .43 .43 0 0 1 .2 .4h-.8zM213.6 164a.42 .42 0 0 1 .5 0 .42 .42 0 0 1 .2 .4h-.8zM213.7 164.7l.6 .4"/>
<path d="M213.9 165.8l-.1-.4h-.3v.4h.8M214.3 165.4l-.4 .2M214.3 164.7l-.6 .4M220.7 169h.6l.2 .1-.2 .3h-.6M220.7 167.5l.2-.1 .2 .1 .2-.1 .2 .1v.3h-.8zM220.7 168.2l.1 .4a.33 .33 0 0 0 .4-.4h.3v.4M221.1 167.5v.3"/>
</g>
<g fill="#c7c7c7">
<path d="M181 160.9a.31 .31 0 0 1 .4 .3 .31 .31 0 0 1-.4 .3z" fill-rule="evenodd"/>
<path d="M180.3 160.3h6.4v2.4h-6.4v-1.9h.4v1.6h.3v-.7l.2 .2 .2 .5h1.3v-.2h-.5v-.6h.5v-.2h-.5v-.2h.8l.1 .3a.58 .58 0 0 1 .5 .7l-.3 .1-.2-.2v.3l.4 .1 1.6-.1v-.2h-.6v-.6h.5v-.2h-.5v-.5h1.2v1.5h.2v-1.5h.4v-.2h-1v.2h-.2v-.2h-.9v1.7h-.6a.58 .58 0 0 0 .3-.6 .58 .58 0 0 0-.5-.4v-.4h.5v-.2a.55 .55 0 0 0-.9 .4h-.8v-.3h.5v-.2h-.8v1.7h-.2l-.3-.7a.56 .56 0 0 0 .1-.8 .56 .56 0 0 0-.8-.1h-.4z" fill-rule="evenodd"/>
</g>
<path d="M201.9 126.3v2h1.2v-2M203.4 151.1v.3M204.4 151.1v.3M220.5 152.5h.3M220.5 153.5h.3M219.2 165.2v.4M220.2 165.2v.4" fill="none" stroke="#c7c7c7" stroke-width=".18"/>
<g fill="#c7c7c7">
<path d="M235.6 129.3h.3v.4h-.3z" fill-rule="evenodd"/>
<path d="M238.4 128.6h.2l.2 .9 .2-.9h.2l-.3 1.1h-.2z" fill-rule="evenodd"/>
<path d="M228.2 128.6h.7l-.5 .9h.5v.2h-.7l.4-.9h-.4z" fill-rule="evenodd"/>
<path d="M230.1 128.6h.2l.1 .8 .1-.8h.2l.1 .9 .1-.9h.2l-.2 1.1h-.2l-.1-.9-.2 .9h-.2z" fill-rule="evenodd"/>
<path d="M234.3 128.1h.2v.5l.5 .1 .1 1h-.2v-.8l-.2-.2-.2 .1v.9h-.2z" fill-rule="evenodd"/>
<path d="M232.5 128.2h.2v.4h.3v.2h-.3v.7h.3v.2h-.4l-.1-.2v-.7h-.3v-.2h.3z" fill-rule="evenodd"/>
<path d="M233.4 128.7l.6-.1v.4h-.2v-.3a.37 .37 0 0 0-.3 .5 .37 .37 0 0 0 .5 .3v.1a.57 .57 0 0 1-.7-.2 .57 .57 0 0 1 .1-.7z" fill-rule="evenodd"/>
<path d="M236.9 128.1h.2v1.5a.51 .51 0 0 1-.5 0 .51 .51 0 0 1-.3-.5h.3l.1 .4h.2l-.1-.7h-.2v.3h-.3a.41 .41 0 0 1 .1-.4 .41 .41 0 0 1 .5-.1z" fill-rule="evenodd"/>
<path d="M229.3 128.6h.6v.2l-.3-.1-.2 .2 .3 .2a.37 .37 0 0 1 .2 .5 .37 .37 0 0 1-.6 .1l-.1-.3 .3 .1 .2-.1-.5-.4z" fill-rule="evenodd"/>
<path d="M237.5 128.7a.44 .44 0 0 1 .5-.1 .44 .44 0 0 1 .2 .6h-.6l.1 .2 .4 .1v.1a.51 .51 0 0 1-.6 0 .51 .51 0 0 1-.1-.6h.6l-.2-.3-.2 .3h-.2z" fill-rule="evenodd"/>
<path d="M231.3 128.6a.43 .43 0 0 1 .4 0 .43 .43 0 0 1 .3 .4v.6a.51 .51 0 0 1-.8-.3l.6 .2v-.4l-.6 .2 .1-.2 .5-.1-.1-.2h-.4z" fill-rule="evenodd"/>
</g>
<g fill="none" stroke="#c7c7c7" stroke-width=".18">
<path d="M180 132.4h.4M180 133.8h.4M183.6 130.6v1.3M184.9 133.5h.4M184.9 134.5h.4M186.8 130.6v1.3M189.5 126.7h.3M189.5 127.7h.3M194.3 124.5h.4M194.3 125.9h.4M200.4 127.7v-2h1.2v2M201.3 129.6h.4"/>
<path d="M201.3 130.6h.4M223.4 135.7v.2M224.4 135.7v.2M196.5 148.1v.5M197.5 148.1v.5M211.7 144.8v.3M212.7 144.8v.3M213.1 148.6v.2M213.2 144.1v.4M214.1 148.6v.2M214.2 144.1v.4M216.8 152.1v.4"/>
<path d="M217.8 152.1v.4M222.6 141.4v.2M223.6 141.4v.2M229.5 140.4v.4M230.5 140.4v.4M239.1 154.1h.4M239.1 155.1h.4M241.2 141.6h.4M241.2 142.6h.4M200.2 165.2v.4M201.2 165.2v.4"/>
</g>
<path d="M183.4 132.2l.3 .2-.3 .2z" fill="#c7c7c7" stroke="#c7c7c7" stroke-width=".18"/>
<g fill="#c7c7c7">
<path d="M236.8 124.9h1l.1 .9h.2v-.9h1.1v2.5l-1.1-.1v-.6l.2-.4-.3-.2-.3 .2 .2 .4-.1 .7-1-.1z" fill-rule="evenodd"/>
<path d="M231.6 125h2.2v.9h-.5v1.5h-1.2v-1.3l.8 .2 .2-.3-.3-.3-.3 .2h-.9z" fill-rule="evenodd"/>
<path d="M219.5 124.9h2.5l-.5 1.3h.5v1.2h-2.5l.4-1.3h-.4z" fill-rule="evenodd"/>
<path d="M234.3 125h1.7l.2 .1 .1 .9h-.9l-.3-.2-.3 .3 .1 .3 .2 .1 .4-.2h.8v.8l-.2 .2-1.8 .1z" fill-rule="evenodd"/>
<path d="M222.5 125.1l.3-.2h2v1.3h-.4l.4 .3v.4l-.1 .3-.4 .2h-1.9v-1.2h.5l-.6-.4v-.4z" fill-rule="evenodd"/>
<path d="M230.3 124.8l1.5 2.6-2-.1 .4-.7 .3-.1 .2-.2-.2-.4-.3-.1-.2 .2v.5l-.5 .8h-.7z" fill-rule="evenodd"/>
<path d="M225.3 125h4.3l-1.5 2.5-.9-1.5v-.4l-.1-.2a.37 .37 0 0 0-.6 .3 .37 .37 0 0 0 .4 .4l.4 .6-.5 .8z" fill-rule="evenodd"/>
<circle cx="232.8" cy="126" r=".17"/>
<circle cx="226.9" cy="125.7" r=".19"/>
<circle cx="230.3" cy="126.2" r=".2"/>
<circle cx="235.1" cy="126.2" r=".18"/>
<circle cx="238" cy="126.4" r=".17"/>
</g>
<path d="M226.5 137.7h.3M226.5 138.7h.3M228.3 142.6h-3.3v4M236.5 144.2v.3M237.5 144.2v.3M177.6 164.1v.5M177.6 167.3v.3M178.6 167.3v.3M178.6 164.1v.5M200 167.6v2.3h1.4v-2.3" fill="none" stroke="#c7c7c7" stroke-width=".18"/>
<g fill="#c7c7c7">
<path d="M241.2 160.9l.3-.1v.5h-.3z" fill-rule="evenodd"/>
<path d="M222 160.4l.4-.1v.9l-.2 .1-.2-.2z" fill-rule="evenodd"/>
<path d="M228.8 160.4l.1-.1a.53 .53 0 0 1 .4 .5 .53 .53 0 0 1-.3 .6l-.2-.1z" fill-rule="evenodd"/>
<path d="M232.9 160.4l.1-.1a.52 .52 0 0 1 .5 .5 .52 .52 0 0 1-.4 .5l-.2-.2z" fill-rule="evenodd"/>
<path d="M221.2 159h25.2v3.4h-25.2v-1.6h.4l.2 .6h.6l-.2 .4-.4 .1v.3l.5-.1 .4-.5h12.9l.7-1.8h1.1l-.7 1.7h1v-.2h-.6l.5-1.3h.5l.1 .4 .2 .2a.41 .41 0 0 1 .4 .6 .41 .41 0 0 1-.7 0v.2l.1 .1a.62 .62 0 0 0 .9-.3 .62 .62 0 0 0-.5-.8l-.2-.2 .1-.4 .6 .1v-.3l-.2-.1h.4l.2 2h.3l.1-1.3 .2 1.3h.4v-.4h.3l.2 .3 .2 .2 .6-.1v-1.1l-.1-.2h.5v.2h.3l.1 1.1h.6v-.2h-.4v-.5h.8l.1 .6 .5 .2 1-.1v-1.1l.3-.1 .2 .2v1h.3v-1.1l-.2-.3-.6 .1v-.7h-.3v2h-.5h.1v-.2h-.1a.51 .51 0 0 1-.5-.4 .51 .51 0 0 1 .4-.6v.3h.3v-.5h-.2a.64 .64 0 0 0-.8 .7h-.8v-.4h.4v-.2h-.4v-.6h-.3v.6h-1.6v.2h.1a.33 .33 0 0 1 .5 .2l-.4 .1-.3 .4h-.3l.1-1.6h-.2l-.1 1.8-.2-1.4h-.2l-.2 1.2-.1-1.6h-1.1l-.3 .1-.1 .4h-.5l.1-.5h-1v.3h-.4l.1-.3h-.2l-.9 2.1h-12.6v-1.5h-.2h.6v.2h.4v1.2h.3v-1.3h.6v.2h.3v.9l.4 .3 1-.1v-1.1l.2-.1 .2 .2v1h.3v-.4h.3l.1 .4 .3 .1 3.1-.1v-.4h-.4v.4h-1l.3-.2 .1-.5h1.6a.66 .66 0 0 0 .3 .7 .66 .66 0 0 0 .7 0v-.2l-.3 .1-.3-.2-.1-.4h1a.59 .59 0 0 0 .6 .8 .59 .59 0 0 0 .6-.8l-.2-.6h.4v1.3h.2v-1.1l.2-.1 .1 1.2h.2v-1.1l.2-.1v1.2h.3l-.1-1.3h-1.6a.6 .6 0 0 0-.6 0 .6 .6 0 0 0-.3 .6h-1l.2-.5h.2v.3h.3v-.5h-.1a.64 .64 0 0 0-.9 .7h-1.6l-.2-.6-.6-.1v-.6h-.3v2h-.4v-1.4h-.3l.1 1.2h-.4l-.1-1.2h-.3v1h-.3l-.1-.9-.3-.1-.3 .1v-.7h-.3v2h-.4v-.2h-.4l-.1-.9h.5v-.2h-.5v-.6h-.2v.6l-2.7-.1-.2 .1-.2 .6h-.4v-1h2.6v-.3h-.4v.3h-2.2z" fill-rule="evenodd"/>
</g>
<path d="M226.5 139.2h.3M223.1 149.5h.5M223.1 150.5h.5M226.5 140.2h.3" fill="none" stroke="#c7c7c7" stroke-width=".18"/>
<g fill="#c7c7c7">
<path d="M193.5 162.7l.2 .8h-.3z" fill-rule="evenodd"/>
<path d="M194.5 162.6a.31 .31 0 0 1 .4 .3 .31 .31 0 0 1-.4 .3z" fill-rule="evenodd"/>
<path d="M190.4 162h7.4v2.4h-7.4v-1.1h.3a.66 .66 0 0 0 .8 .8h.7v-.8h.4v.8h.7v-.4h.4l.1 .4h.3l-.4-1.6h.6v1.6h.2v-.7l.3 .2 .2 .5h.2l-.3-.7 .5-.1a.65 .65 0 0 0 .1 .7 .65 .65 0 0 0 .7 .1h1.3v-.2h-.6v-.6h.5v-.2h-.5v-.5h.6v-.2h-.9v1.7h-.4h.2v-1h-.6v.2h.3v.6a.66 .66 0 0 1-.4-1l.1-.2h.5v-.2a.67 .67 0 0 0-.7 .1 .67 .67 0 0 0-.2 .7h-.3a.57 .57 0 0 0-.1-.8 .57 .57 0 0 0-.7 0l-.9-.1-.4 1.7h-.1v-1.7h-.3v.7h-.4v-.7h-.3v1.7h-.4l.1-.2a.46 .46 0 0 1-.5-.1 .46 .46 0 0 1-.1-.5l.2-.7h.2v.4h.2v-.5a.65 .65 0 0 0-.7 .1 .65 .65 0 0 0-.2 .7h-.3z" fill-rule="evenodd"/>
</g>
<g fill="none" stroke="#c7c7c7" stroke-width=".18">
<path d="M190.9 124.5h.4M190.9 125.9h.4M191.4 129.8h.5M192.6 129.8h.5M192.7 127.5h.4M194.8 126.7h.3M194.8 127.7h.3M201.3 131.2h.4M201.3 132.2h.4M216.9 135.8v.3M218 135.8v.3M195 148.2v.3"/>
<path d="M196 148.2v.3M196.1 150.2h.2M196.1 151.2h.2M198.1 146.7v.3M199.1 146.7v.3M215.9 142.2h.3M215.9 143.2h.3M220.4 151h.4M220.4 152h.4M221.1 141.3v.4M222.1 141.3v.4M223.7 144.4v.4"/>
<path d="M224.7 144.4v.4M226.5 142.2h.2M226.5 141.2h.2M228.7 144.5v.3M229.7 144.5v.3M219 167.6v2.3h1.4v-2.3"/>
</g>
<path d="M191.3 127.2v.3h-.3z" fill="#c7c7c7" stroke="#c7c7c7" stroke-width=".18"/>
<g fill="none" stroke="#e10000" stroke-width=".18">
<path d="M169.8 127.1l.5-.1v-.3l-.5-.1v1M170 127.1l.4 .5M170.8 127h.3M171.3 126.6h-.5v1h.5M171.7 127h.3M172.2 126.6h-.5v1M172.5 126.7l.2 .1M172.7 126.6v.2M172.7 126.8l-.1 .2M172.7 126.8l.1 .2M172.9 126.7l-.2 .1M173.2 126.7l.3 .1"/>
<path d="M173.5 126.6v.2M173.5 126.8l-.2 .2M173.5 126.8l.1 .2M173.7 126.7l-.2 .1M241.8 127.1l.5-.1v-.3l-.5-.1v1M242 127.1l.4 .5M242.8 127h.3M243.3 126.6h-.5v1h.5M243.7 127h.3M244.2 126.6h-.5v1M244.5 126.7l.2 .1M244.7 126.6v.2"/>
<path d="M244.7 126.8l-.1 .2M244.7 126.8l.1 .2M244.9 126.7l-.2 .1M245.2 126.7l.3 .1M245.5 126.6v.2M245.5 126.8l-.2 .2M245.5 126.8l.1 .2M245.7 126.7l-.2 .1M169.8 167.1l.5-.1v-.3l-.5-.1v1M170 167.1l.4 .5M170.8 167h.3M171.3 166.6h-.5v1h.5"/>
<path d="M171.7 167h.3M172.2 166.6h-.5v1M172.5 166.7l.2 .1M172.7 166.6v.2M172.7 166.8l-.1 .2M172.7 166.8l.1 .2M172.9 166.7l-.2 .1M173.2 166.7l.3 .1M173.5 166.6v.2M173.5 166.8l-.2 .2M173.5 166.8l.1 .2M173.7 166.7l-.2 .1"/>
<path d="M241.8 167.1l.5-.1v-.3l-.5-.1v1M242 167.1l.4 .5M242.8 167h.3M243.3 166.6h-.5v1h.5M243.7 167h.3M244.2 166.6h-.5v1M244.5 166.7l.2 .1M244.7 166.6v.2M244.7 166.8l-.1 .2M244.7 166.8l.1 .2M244.9 166.7l-.2 .1M245.2 166.7l.3 .1"/>
<path d="M245.5 166.6v.2M245.5 166.8l-.2 .2M245.5 166.8l.1 .2M245.7 166.7l-.2 .1"/>
</g>
<path d="M282.7 104.6h32.5v2.6h-32.5zM335.3 104.6h32.5v2.5h-32.5z" fill="none" stroke="#000" stroke-width=".4"/>
<path d="M282.7 107.2h32.5M282.7 104.6h32.5M289.7 104.6v2.6M296.1 104.6v2.6M305.7 104.6v2.6M335.3 107.1h32.5M335.3 104.6h32.5M342.3 104.6v2.5M348.7 104.6v2.5M358.3 104.6v2.5" fill="none" stroke="#000" stroke-width=".2"/>
<g fill="#000">
<path d="M284.7 105.1h.5a.37 .37 0 0 1 .5 .3 .37 .37 0 0 1-.3 .5l.4 .5h-.3l-.3-.5h-.2l-.1 .5h-.2v-.7h.6l.1-.2v-.1l-.5-.1v.4h-.2z" fill-rule="evenodd"/>
<path d="M286 105.6l.3-.1h.3l.1 .5-.6 .1 .2 .1 .2-.1 .2 .1a.44 .44 0 0 1-.5 .2 .44 .44 0 0 1-.3-.5h.6l-.2-.2-.2 .2h-.2z" fill-rule="evenodd"/>
<path d="M287 105.2l.4-.1v.2l-.2 .1v.1h.2v.2h-.2v.7h-.2v-.7h-.2z" fill-rule="evenodd"/>
<path d="M287.5 106.2h.3v.2h-.3z" fill-rule="evenodd"/>
<path d="M291.6 105.1h.2l.5 .9v-.9h.3v1.3h-.3l-.5-.8v.8h-.2z" fill-rule="evenodd"/>
<path d="M292.9 105.6l.3-.1h.3l.1 .5-.6 .1 .2 .1 .2-.1 .2 .1a.44 .44 0 0 1-.5 .2 .44 .44 0 0 1-.3-.5h.6l-.2-.2-.2 .2h-.2z" fill-rule="evenodd"/>
<path d="M293.9 105.3l.2-.1v.3h.2v.2h-.2v.4l.2 .3-.4-.1v-.6h-.2z" fill-rule="evenodd"/>
<path d="M297.9 105.1h.3l.3 .4 .2-.4h.3l-.4 .6 .4 .7h-.3l-.3-.4-.2 .4h-.3l.4-.7z" fill-rule="evenodd"/>
<path d="M299.7 105.1h.4v.2h-.2v1.3h.2v.2h-.4z" fill-rule="evenodd"/>
<path d="M300.2 105.5h.3v.1l.3-.1 .2 .1 .5-.1 .1 .2v.7h-.3v-.7h-.1l-.1 .1-.1 .6h-.2v-.7h-.1l-.2 .1v.6h-.3z" fill-rule="evenodd"/>
<path d="M301.8 105.5h.2v.1l.3-.1 .3 .1 .4-.1 .2 .2v.7h-.3v-.6l-.1-.1-.2 .1v.6h-.2v-.7h-.2l-.1 .1v.6h-.3z" fill-rule="evenodd"/>
<path d="M303.3 105.1h.5v1.7h-.5v-.2h.2v-1.3h-.2z" fill-rule="evenodd"/>
<path d="M307.4 105.1h.3l.3 .5 .3-.5h.3l-.4 .8v.5h-.3v-.5z" fill-rule="evenodd"/>
<path d="M309.2 105.1h.4v.2h-.2v1.3h.2v.2h-.4z" fill-rule="evenodd"/>
<path d="M309.8 105.5h.2v.1l.3-.1 .3 .1 .4-.1 .1 .2v.7h-.2v-.6l-.1-.1-.2 .1v.6h-.3v-.7h-.1l-.2 .1v.6h-.2z" fill-rule="evenodd"/>
<path d="M311.4 105.5h.2v.1l.3-.1 .2 .1 .5-.1 .1 .2v.7h-.2v-.6l-.2-.1-.1 .1v.6h-.3v-.7h-.1l-.2 .1v.6h-.2z" fill-rule="evenodd"/>
<path d="M312.9 105.1h.4v1.7h-.4v-.2h.2v-1.3h-.2z" fill-rule="evenodd"/>
<path d="M337.3 105.1h.5a.37 .37 0 0 1 .5 .3 .37 .37 0 0 1-.3 .4l.4 .6h-.3l-.3-.5-.2-.1-.1 .6h-.2v-.8h.6l.1-.1-.1-.2h-.4v.3h-.2z" fill-rule="evenodd"/>
<path d="M338.6 105.5l.2-.1 .3 .1 .2 .5h-.6l.2 .2 .2-.1h.2a.45 .45 0 0 1-.5 .3 .45 .45 0 0 1-.3-.6h.6l-.2-.2-.2 .2h-.2z" fill-rule="evenodd"/>
<path d="M339.6 105.1h.4v.2h-.2l.2 .3h-.2v.8h-.2v-.8h-.2z" fill-rule="evenodd"/>
<path d="M340.1 106.1h.3v.3h-.3z" fill-rule="evenodd"/>
<path d="M344.2 105.1h.2l.5 .8v-.8h.3v1.3h-.3l-.5-.9v.9h-.2z" fill-rule="evenodd"/>
<path d="M345.5 105.5l.2-.1 .4 .1 .1 .5h-.6l.2 .2 .2-.1h.2a.45 .45 0 0 1-.5 .3 .45 .45 0 0 1-.3-.6h.6l-.2-.2-.2 .2h-.2z" fill-rule="evenodd"/>
<path d="M346.4 105.3l.3-.2v.3h.2v.2h-.2v.4l.2 .4-.4-.1-.1-.7h-.1z" fill-rule="evenodd"/>
<path d="M350.5 105.1h.3l.2 .4 .3-.4h.3l-.4 .6 .4 .7h-.3l-.3-.5-.2 .5h-.3l.4-.7z" fill-rule="evenodd"/>
<path d="M352.3 105.1h.4v.2h-.2v1.2h.2v.2h-.4z" fill-rule="evenodd"/>
<path d="M352.8 105.4h.3v.2l.2-.2 .3 .2 .5-.1 .1 .1v.8h-.3v-.7l-.1-.1-.1 .1-.1 .7h-.2v-.7l-.1-.1-.2 .1v.7h-.3z" fill-rule="evenodd"/>
<path d="M354.4 105.4h.2v.2l.3-.2 .3 .2 .4-.1 .2 .1v.8h-.3v-.7l-.1-.1-.2 .1v.7h-.2v-.7l-.2-.1-.1 .1v.7h-.3z" fill-rule="evenodd"/>
<path d="M355.9 105.1h.5v1.6h-.5v-.2h.2v-1.2h-.2z" fill-rule="evenodd"/>
<path d="M360 105.1h.3l.3 .5 .3-.5h.3l-.4 .7v.6h-.3v-.6z" fill-rule="evenodd"/>
<path d="M361.8 105.1h.4v.2h-.2v1.2h.2v.2h-.4z" fill-rule="evenodd"/>
<path d="M362.4 105.4h.2v.2l.3-.2 .3 .2 .4-.1 .1 .1v.8h-.2v-.7l-.1-.1-.2 .1v.7h-.3v-.7l-.1-.1-.2 .1v.7h-.2z" fill-rule="evenodd"/>
<path d="M364 105.4h.2v.2l.3-.2 .2 .2 .5-.1 .1 .1v.8h-.2v-.7l-.2-.1-.1 .1v.7h-.3v-.7l-.1-.1-.2 .1v.7h-.2z" fill-rule="evenodd"/>
<path d="M365.5 105.1h.4v1.6h-.4v-.2h.2v-1.2h-.2z" fill-rule="evenodd"/>
</g>
<g fill="none" stroke="#000" stroke-width=".18">
<path d="M10 10h400v277h-400zM12 12h396v273h-396zM35.3 11.6h.8M35.3 10.7l.4-.4v1.3M60 10v2M85.3 10.4l.5-.1 .3 .4-.8 .9h.8M110 10v2M135.3 10.3h.8l-.4 .5 .3 .1v.6l-.2 .1-.5-.1M160 10v2M185.7 10.2l-.4 1h.9M186 10.7v.9M210 10v2"/>
<path d="M236 10.3h-.6l-.1 .6 .2-.1 .5 .1 .1 .1-.1 .5-.2 .1-.5-.1M260 10v2M286 10.3l-.4 .1a.87 .87 0 0 0 0 1.2l.4-.1 .1-.5-.3-.2-.3 .1-.2 .1M310 10v2M335.3 10.3h.9l-.6 1.3M360 10v2M385.6 10.9l-.3 .2 .1 .4 .2 .1 .4-.1 .1-.2-.1-.3-.2-.1M385.6 10.9l-.3-.3 .3-.3h.2l.3 .2-.3 .4M385.6 10.9h.2M10.6 35.6l.4-1.3 .4 1.3M10.7 35.2h.6M408.6 35.6l.4-1.3 .4 1.3"/>
<path d="M408.7 35.2h.6M10 60h2M408 60h2M10.7 84.3h.4l.2 .2-.2 .4 .2 .1 .1 .3-.2 .3h-.5zM10.7 84.9h.4M408.6 84.3h.5l.2 .2-.2 .4 .2 .1 .1 .3-.3 .3h-.5zM408.6 84.9h.5M10 110h2M408 110h2M11.4 134.4a.62 .62 0 0 0-.9 .5 .62 .62 0 0 0 .7 .7l.2-.1M409.4 134.4a.62 .62 0 0 0-.9 .5 .62 .62 0 0 0 .6 .7l.3-.1M10 160h2"/>
<path d="M408 160h2M10.7 184.3a.66 .66 0 0 1 .7 .6 .66 .66 0 0 1-.7 .7zM408.6 184.3a.66 .66 0 0 1 .8 .6 .66 .66 0 0 1-.8 .7zM10 210h2M408 210h2M10.7 234.9h.5M11.3 234.3h-.6v1.3h.6M408.7 234.9h.4M409.3 234.3h-.6v1.3h.6M10 260h2M408 260h2M10.8 284.9h.4"/>
<path d="M11.4 284.3h-.6v1.3M35.3 285.7l.4-.4v1.3M35.3 286.6h.8M60 285v2M85.3 285.4l.5-.1 .3 .4-.8 .9h.8M110 285v2M135.3 285.3h.8l-.4 .5 .3 .1v.6l-.2 .1-.5-.1M160 285v2M185.7 285.2l-.4 1h.9M186 285.7v.9M210 285v2M236 285.3h-.6l-.1 .6 .2-.1 .5 .1 .1 .1-.1 .5-.2 .1-.5-.1"/>
<path d="M260 285v2M286 285.3l-.4 .1a.87 .87 0 0 0 0 1.2l.4-.1 .1-.5-.3-.2-.3 .1-.2 .1M310 285v2M335.3 285.3h.9l-.6 1.3M360 285v2M385.6 285.9l-.3-.3 .3-.3h.2l.3 .2-.3 .4M385.6 285.9l-.3 .2v.2l.3 .3 .4-.1 .1-.2v-.2l-.3-.2M385.6 285.9h.2M408.7 284.9h.5M409.4 284.3h-.7v1.3"/>
</g>
<path d="M384.9 279.7h1.1l-.2 .5h-.9l-.1 .2a.87 .87 0 0 1 1 .3 .87 .87 0 0 1 0 1.1 .71 .71 0 0 1-1.3-.1 .57 .57 0 0 1 .8 .2 .44 .44 0 0 0 .4-.5 .44 .44 0 0 0-.4-.4l-.8-.1z" fill-rule="evenodd" fill="#00007f"/>
<g fill="#00f">
<path d="M384.3 275.7l.3-.1h.4l.2 .4-.1 .1a.32 .32 0 0 0-.4-.4 .32 .32 0 0 0-.3 .5h.1a.57 .57 0 0 1 .8 .6 .64 .64 0 0 1-.7 .3 .64 .64 0 0 1-.5-.5h.2a.39 .39 0 0 0 .4 .4 .39 .39 0 0 0 .4-.4l-.3-.1a.49 .49 0 0 1-.5-.2 .49 .49 0 0 1 0-.6z" fill-rule="evenodd"/>
<path d="M385.5 275.6h.2v.6l.3-.2 .4 .2v.9h-.2v-.7a.27 .27 0 0 0-.3-.2 .27 .27 0 0 0-.2 .3v.6h-.2z" fill-rule="evenodd"/>
<path d="M386.8 276.2a.51 .51 0 0 1 .6-.1 .51 .51 0 0 1 .2 .5h-.8l.3 .4 .5-.2a.52 .52 0 0 1-.6 .3 .52 .52 0 0 1-.3-.6h.8l-.2-.3a.31 .31 0 0 0-.5 .3h-.1z" fill-rule="evenodd"/>
<path d="M388 276.2a.51 .51 0 0 1 .6-.1 .51 .51 0 0 1 .2 .5h-.8l.2 .4 .6-.2a.52 .52 0 0 1-.6 .3 .52 .52 0 0 1-.4-.6h.8l-.2-.3a.31 .31 0 0 0-.4 .3h-.2z" fill-rule="evenodd"/>
<path d="M389.1 275.8l.2-.1v.3h.1v.2h-.1v.6l.2 .3a.27 .27 0 0 1-.3 0 .27 .27 0 0 1-.1-.3v-.6h-.2z" fill-rule="evenodd"/>
<path d="M389.7 276h.2v.2h-.2z" fill-rule="evenodd"/>
<path d="M389.7 276.9h.2v.2h-.2z" fill-rule="evenodd"/>
<path d="M392.7 281.1a.54 .54 0 0 1 .8 .1 .54 .54 0 0 1-.2 .8 .54 .54 0 0 1-.7-.3v-.1h.2a.36 .36 0 0 0 .4 .4 .36 .36 0 0 0 .2-.6l-.4-.2-.2 .4h-.2z" fill-rule="evenodd"/>
<path d="M393.9 280.7l.4-.1v.2a.19 .19 0 0 0-.2 0 .19 .19 0 0 0-.1 .2h.2v.2h-.2v.9h-.2v-.9h-.1v-.2h.1z" fill-rule="evenodd"/>
</g>
<g fill="#00007f">
<path d="M396.2 280.1l.9-.4v2.1l.4 .2h-1.2l.3-.1v-1.5v-.3z" fill-rule="evenodd"/>
<path d="M398.1 279.9a.73 .73 0 0 1 .9-.1 .73 .73 0 0 1 .3 .8 1.04 1.04 0 0 1-.8 1.5 .95 .95 0 0 1-.6-1h.5v.7a.2 .2 0 0 0 .2 .2 .2 .2 0 0 0 .2-.3v-1.7a.2 .2 0 0 0-.2-.2 .2 .2 0 0 0-.2 .2v1.1h-.5v-.7z" fill-rule="evenodd"/>
</g>
<g fill="#00f">
<path d="M368.3 275.7l.3-.1h.4l.2 .4-.1 .1a.32 .32 0 0 0-.4-.4 .32 .32 0 0 0-.3 .5h.1a.57 .57 0 0 1 .8 .6 .64 .64 0 0 1-.7 .3 .64 .64 0 0 1-.5-.5h.2a.39 .39 0 0 0 .4 .4 .39 .39 0 0 0 .4-.4l-.3-.1a.49 .49 0 0 1-.5-.2 .49 .49 0 0 1 0-.6z" fill-rule="evenodd"/>
<path d="M369.5 275.6h.2v.2h-.2z" fill-rule="evenodd"/>
<path d="M369.5 276h.2v1.1h-.2z" fill-rule="evenodd"/>
<path d="M369.9 276h.9l-.7 1h.8v.1h-1l.7-.9h-.7z" fill-rule="evenodd"/>
<path d="M371.1 276.2a.51 .51 0 0 1 .6-.1 .51 .51 0 0 1 .3 .5h-.8l.2 .4 .6-.2a.52 .52 0 0 1-.7 .3 .52 .52 0 0 1-.3-.6h.8l-.2-.3a.31 .31 0 0 0-.4 .3h-.2z" fill-rule="evenodd"/>
<path d="M372.3 276h.2v.2h-.2z" fill-rule="evenodd"/>
<path d="M372.3 276.9h.2v.2h-.2z" fill-rule="evenodd"/>
</g>
<g fill="#00007f">
<path d="M370.3 279.7l.9 2.1 .3 .2h-1.1l.2-.1-.1-.5h-.9l-.1 .5 .3 .1h-.8l.6-.8h.8l-.3-.7-.4 .7h-.1z" fill-rule="evenodd"/>
<path d="M371.9 279.9a.55 .55 0 0 1 .8-.2 .55 .55 0 0 1 0 .9 .81 .81 0 0 1 .1 1.2 .81 .81 0 0 1-1.2 0l.2-.2a.54 .54 0 0 0 .8 .2 .72 .72 0 0 0-.6-1 .41 .41 0 0 0 .5-.3 .41 .41 0 0 0-.3-.5 .41 .41 0 0 0-.5 .3z" fill-rule="evenodd"/>
</g>
<path d="M366.5 274.5h41.5M382.5 274.5v10.5M408 264h-41.5v21" fill="none" stroke="#000" stroke-width=".18"/>
<g fill="#00f">
<path d="M384.2 265.1h.6a.42 .42 0 0 1 .6 .4 .42 .42 0 0 1-.5 .4l.6 .7h-.3l-.4-.6h-.2h-.2v.6h-.2v-.8h.6a.26 .26 0 0 0 .4-.2 .26 .26 0 0 0-.4-.3h-.4v.5h-.2z" fill-rule="evenodd"/>
<path d="M385.7 265.7a.51 .51 0 0 1 .6-.1 .51 .51 0 0 1 .3 .5h-.8l.2 .4 .6-.2a.52 .52 0 0 1-.7 .3 .52 .52 0 0 1-.3-.6h.8l-.2-.3a.31 .31 0 0 0-.4 .3h-.2z" fill-rule="evenodd"/>
<path d="M386.7 265.5h.2l.3 .9 .3-.9h.2l-.4 1.1h-.2z" fill-rule="evenodd"/>
<path d="M387.9 265.1h.2v.2h-.2z" fill-rule="evenodd"/>
<path d="M387.9 265.5h.2v1.1h-.2z" fill-rule="evenodd"/>
<path d="M388.4 265.6l.2-.1a.39 .39 0 0 1 .5 .3h-.2a.21 .21 0 0 0-.2-.2 .21 .21 0 0 0-.1 .3 .43 .43 0 0 1 .4 .1 .43 .43 0 0 1 .1 .4l-.2 .2h-.4l-.2-.3h.1a.24 .24 0 0 0 .3 .3 .24 .24 0 0 0 .2-.4 .43 .43 0 0 1-.6-.5z" fill-rule="evenodd"/>
<path d="M389.4 265.1h.2v.2h-.2z" fill-rule="evenodd"/>
<path d="M389.4 265.5h.2v1.1h-.2z" fill-rule="evenodd"/>
<path d="M390 265.6a.54 .54 0 0 1 .8 .1 .54 .54 0 0 1-.3 .8 .54 .54 0 0 1-.7-.3v-.1h.2a.36 .36 0 0 0 .4 .4 .36 .36 0 0 0 .2-.6l-.4-.2-.2 .4h-.2z" fill-rule="evenodd"/>
<path d="M391 265.5h.2v.2l.2-.2a.37 .37 0 0 1 .4 .1 .37 .37 0 0 1 .1 .4v.6h-.2v-.6a.27 .27 0 0 0-.3-.3 .27 .27 0 0 0-.2 .3v.6h-.2z" fill-rule="evenodd"/>
<path d="M392.2 265.5h.2v.2h-.2z" fill-rule="evenodd"/>
<path d="M392.2 266.4h.2v.2h-.2z" fill-rule="evenodd"/>
</g>
<g fill="#00007f">
<path d="M384 270.4h.5l.1-.5v.5l.5 .1h-.5l-.1 .5v-.5z" fill-rule="evenodd"/>
<path d="M386.1 269.8l.3-.1a1.42 1.42 0 0 0 0 1.9l-.3-.2a1.12 1.12 0 0 1 0-1.6z" fill-rule="evenodd"/>
<path d="M386.4 269.7h.6l-.2 .2v.7a.41 .41 0 0 0 .4 .5 .41 .41 0 0 0 .4-.6v-.7l-.2-.1h.5l-.2 .2v.6a.55 .55 0 0 1-.6 .7 .55 .55 0 0 1-.5-.7v-.7z" fill-rule="evenodd"/>
<path d="M387.9 270.3l.4-.1v.2a.29 .29 0 0 1 .3-.2 .29 .29 0 0 1 .2 .3v.5l.2 .1h-.5l.2-.2-.1-.5-.1-.1-.2 .1v.6l.1 .1h-.4l.1-.1v-.6z" fill-rule="evenodd"/>
<path d="M389 270.3l.3-.1v.2l.2-.2h.2l-.4 .3v.5l.2 .1h-.5l.1-.1v-.6z" fill-rule="evenodd"/>
<path d="M389.9 270.3l.4-.1 .2 .2v.1h-.6l.2 .4 .3 .1 .1-.2a.41 .41 0 0 1-.6 .3 .41 .41 0 0 1-.1-.6h.5l-.2-.3-.3 .3z" fill-rule="evenodd"/>
<path d="M390.7 269.8l.3-.1v1.3l.1 .1h-.4l.1-.1v-.9v-.3z" fill-rule="evenodd"/>
<path d="M391.4 270.3l.4-.1 .2 .2 .1 .1h-.7l.2 .4 .3 .1 .1-.2a.41 .41 0 0 1-.5 .3 .41 .41 0 0 1-.2-.6h.5l-.2-.3-.3 .3z" fill-rule="evenodd"/>
<path d="M392.3 270.2l.5 .1 .1 .7 .1-.1-.1 .2h-.1l-.1-.1-.2 .1h-.2l-.1-.2 .3 .1 .2-.1v-.3l-.5 .3 .5-.4-.2-.3-.2 .3z" fill-rule="evenodd"/>
<path d="M393.2 270.2h.5v.3l-.2-.3a.15 .15 0 0 0-.2 .1 .15 .15 0 0 0 0 .2h.1a.34 .34 0 0 1 .4 .5 .34 .34 0 0 1-.6 .1v-.3l.2 .3 .2-.2-.4-.4z" fill-rule="evenodd"/>
<path d="M394.1 270.3l.4-.1 .2 .2v.1h-.6l.1 .4 .3 .1 .2-.2a.41 .41 0 0 1-.6 .3 .41 .41 0 0 1-.1-.6h.5l-.2-.3-.3 .3z" fill-rule="evenodd"/>
<path d="M395.4 269.8l.3-.1v1.3h.2l-.6 .2-.4-.2v-.4h.2l.1 .4 .3-.1-.1-.7-.3 .1v.3h-.2a.42 .42 0 0 1 .6-.4v-.4z" fill-rule="evenodd"/>
<path d="M395.9 269.7a1.08 1.08 0 0 1 0 1.9 1.42 1.42 0 0 0 0-1.9z" fill-rule="evenodd"/>
</g>
<path d="M382.5 264v10.5" fill="none" stroke="#000" stroke-width=".18"/>
<g fill="#00f">
<path d="M368.2 265.1h.5a.75 .75 0 0 1 .7 .8 .75 .75 0 0 1-.7 .7h-.5v-.2h.5a.58 .58 0 0 0 .5-.5 .58 .58 0 0 0-.5-.6h-.3v1.1h-.2z" fill-rule="evenodd"/>
<path d="M369.7 265.6l.2-.1a.47 .47 0 0 1 .5 .1 .47 .47 0 0 1 .1 .6l.1 .4h-.2v-.1l-.5 .1-.3-.1v-.2l.6 .2 .1-.4-.7 .2a.57 .57 0 0 1 .7-.4 .28 .28 0 0 0-.2-.2 .28 .28 0 0 0-.3 .2l-.2-.1z" fill-rule="evenodd"/>
<path d="M370.9 265.3l.1-.1v.3h.2v.2h-.2v.6l.2 .3a.27 .27 0 0 1-.3 0 .27 .27 0 0 1 0-.3v-.6h-.2z" fill-rule="evenodd"/>
<path d="M371.5 265.7a.51 .51 0 0 1 .6-.1 .51 .51 0 0 1 .2 .5h-.8l.3 .4 .5-.2a.52 .52 0 0 1-.6 .3 .52 .52 0 0 1-.4-.6h.9l-.2-.3a.31 .31 0 0 0-.5 .3h-.2z" fill-rule="evenodd"/>
<path d="M372.6 265.5h.2v.2h-.2z" fill-rule="evenodd"/>
<path d="M372.6 266.4h.2v.2h-.2z" fill-rule="evenodd"/>
</g>
<path d="M408 253.5h-41.5v10.5" fill="none" stroke="#000" stroke-width=".18"/>
<g fill="#00f">
<path d="M368.2 254.6h.5a.46 .46 0 0 1 .6 .5 .46 .46 0 0 1-.6 .4h-.3v.6h-.2v-.8h.5a.28 .28 0 0 0 .4-.2 .28 .28 0 0 0-.4-.3h-.3v.5h-.2z" fill-rule="evenodd"/>
<path d="M369.5 255h.2v.2l.2-.2h.2v.2a.24 .24 0 0 0-.3 .1 .24 .24 0 0 0-.1 .3v.5h-.2z" fill-rule="evenodd"/>
<path d="M370.3 255.1a.55 .55 0 0 1 .9 .1 .55 .55 0 0 1-.3 .8 .55 .55 0 0 1-.7-.4h.2a.36 .36 0 0 0 .4 .4 .36 .36 0 0 0 .2-.6l-.4-.2-.2 .4h-.2z" fill-rule="evenodd"/>
<path d="M371.4 254.6h.2v.2h-.2z" fill-rule="evenodd"/>
<path d="M371.4 255h.2v1.2a.3 .3 0 0 1-.1 .3 .3 .3 0 0 1-.3 0l.2-.2z" fill-rule="evenodd"/>
<path d="M371.9 255.2a.51 .51 0 0 1 .7-.1 .51 .51 0 0 1 .2 .5h-.8l.2 .4 .6-.2a.52 .52 0 0 1-.6 .3 .52 .52 0 0 1-.4-.6h.8l-.2-.3a.31 .31 0 0 0-.4 .3h-.2z" fill-rule="evenodd"/>
<path d="M373.1 255.1h.6l.2 .3h-.2a.34 .34 0 0 0-.5-.2 .34 .34 0 0 0 0 .6l.3 .2 .2-.3h.2a.53 .53 0 0 1-.8 .3 .53 .53 0 0 1 0-.8z" fill-rule="evenodd"/>
<path d="M374.1 254.8l.2-.1v.3h.2v.2h-.2v.6l.2 .3a.27 .27 0 0 1-.3 0 .27 .27 0 0 1-.1-.3v-.6h-.1z" fill-rule="evenodd"/>
<path d="M375.3 254.6h.2l.8 1.2v-1.2h.2v1.5h-.2l-.8-1.2v1.2h-.2z" fill-rule="evenodd"/>
<path d="M376.9 255.1l.1-.1a.47 .47 0 0 1 .6 .1 .47 .47 0 0 1 0 .6l.1 .4h-.2v-.1l-.5 .1-.3-.1v-.2l.4 .2h.2l.2-.4-.8 .2a.57 .57 0 0 1 .8-.4 .28 .28 0 0 0-.3-.2 .28 .28 0 0 0-.3 .2l-.2-.1z" fill-rule="evenodd"/>
<path d="M377.9 255h.2v.2l.3-.2 .3 .2 .3-.2 .3 .1 .1 .2v.8h-.2v-.7a.24 .24 0 0 0-.2-.2 .24 .24 0 0 0-.2 .3v.6h-.2v-.7a.25 .25 0 0 0-.3-.2 .25 .25 0 0 0-.2 .4v.5h-.2z" fill-rule="evenodd"/>
<path d="M379.8 255.2a.51 .51 0 0 1 .6-.1 .51 .51 0 0 1 .2 .5h-.8l.3 .4 .5-.2a.52 .52 0 0 1-.6 .3 .52 .52 0 0 1-.4-.6h.8l-.1-.3a.31 .31 0 0 0-.5 .3h-.2z" fill-rule="evenodd"/>
<path d="M380.9 255h.2v.2h-.2z" fill-rule="evenodd"/>
<path d="M380.9 255.9h.2v.2h-.2z" fill-rule="evenodd"/>
</g>
<g fill="#00007f">
<path d="M368.2 269.8a.42 .42 0 0 1 .6 .1 .42 .42 0 0 1-.1 .6l-.4 .5 .7-.1-.1 .2h-.9a1.05 1.05 0 0 0 .7-1.1l-.3-.1-.3 .2z" fill-rule="evenodd"/>
<path d="M369.3 269.8a.47 .47 0 0 1 .6 0 .47 .47 0 0 1 .1 .6 .48 .48 0 0 1-.1 .6 .48 .48 0 0 1-.6 0l-.2-.5h.2a.36 .36 0 0 0 0 .4 .36 .36 0 0 0 .4 .1l.1-.6-.1-.6a.24 .24 0 0 0-.3 0 .24 .24 0 0 0 0 .3l-.1 .4h-.2z" fill-rule="evenodd"/>
<path d="M370.3 269.8a.42 .42 0 0 1 .6 .1 .42 .42 0 0 1-.1 .6l-.4 .5 .7-.1-.1 .2h-.9a1.06 1.06 0 0 0 .7-1.1l-.3-.1-.3 .2z" fill-rule="evenodd"/>
<path d="M371.6 269.7h.5l-.1 .2h-.4l-.1 .2a.5 .5 0 0 1 .5 .6 .5 .5 0 0 1-.7 .3 .4 .4 0 0 0 .6-.2 .4 .4 0 0 0-.5-.5h-.1z" fill-rule="evenodd"/>
<path d="M372.3 270.6h.5v.1h-.5z" fill-rule="evenodd"/>
<path d="M373.2 269.8a.47 .47 0 0 1 .6 0 .47 .47 0 0 1 .1 .6 .48 .48 0 0 1-.2 .6 .48 .48 0 0 1-.6 0l-.1-.5h.2a.36 .36 0 0 0-.1 .4 .36 .36 0 0 0 .4 .1l.2-.6-.2-.6a.24 .24 0 0 0-.2 0 .24 .24 0 0 0-.1 .3v.4h-.2z" fill-rule="evenodd"/>
<path d="M374.2 269.7h.7l-.5 1.4h-.1l.4-1.2h-.5l-.1 .2z" fill-rule="evenodd"/>
<path d="M375.1 270.6h.5v.1h-.5z" fill-rule="evenodd"/>
<path d="M375.9 269.9l.4-.2v1.3l.2 .1h-.5l.1-.1v-1z" fill-rule="evenodd"/>
<path d="M377 269.8h.4a.31 .31 0 0 1 0 .5 .44 .44 0 0 1 .1 .7 .44 .44 0 0 1-.6 0 .34 .34 0 0 0 .5 0 .34 .34 0 0 0-.1-.5l-.2-.1a.28 .28 0 0 0 .3-.2 .28 .28 0 0 0-.2-.3 .28 .28 0 0 0-.3 .1z" fill-rule="evenodd"/>
</g>
<g fill="#00f">
<path d="M341.2 275.6h.6a.42 .42 0 0 1 .6 .4 .42 .42 0 0 1-.5 .4l.6 .7h-.3a.74 .74 0 0 0-.8-.6v.6h-.2v-.8h.6a.26 .26 0 0 0 .4-.2 .26 .26 0 0 0-.4-.3h-.4v.5h-.2z" fill-rule="evenodd"/>
<path d="M342.7 276.2a.51 .51 0 0 1 .6-.1 .51 .51 0 0 1 .3 .5h-.8l.2 .4 .6-.2a.52 .52 0 0 1-.7 .3 .52 .52 0 0 1-.3-.6h.8l-.2-.3a.31 .31 0 0 0-.4 .3h-.2z" fill-rule="evenodd"/>
<path d="M343.7 276h.2l.3 .9 .3-.9h.2l-.4 1.1h-.2z" fill-rule="evenodd"/>
<path d="M344.9 275.6h.2v.2h-.2z" fill-rule="evenodd"/>
<path d="M344.9 276h.2v1.1h-.2z" fill-rule="evenodd"/>
<path d="M345.4 276.2a.51 .51 0 0 1 .6-.1 .51 .51 0 0 1 .3 .5h-.8l.2 .4 .6-.2a.52 .52 0 0 1-.7 .3 .52 .52 0 0 1-.3-.6h.8l-.2-.3a.31 .31 0 0 0-.4 .3h-.2z" fill-rule="evenodd"/>
<path d="M346.4 276h.2l.2 .9 .2-.9h.2l.2 .9 .3-.9h.2l-.4 1.1h-.2l-.2-.8-.2 .8h-.2z" fill-rule="evenodd"/>
<path d="M348.1 276.2a.51 .51 0 0 1 .6-.1 .51 .51 0 0 1 .3 .5h-.9l.3 .4 .6-.2a.52 .52 0 0 1-.7 .3 .52 .52 0 0 1-.3-.6h.8l-.2-.3a.31 .31 0 0 0-.4 .3h-.2z" fill-rule="evenodd"/>
<path d="M349.2 276h.1v.2l.2-.2h.2v.2a.24 .24 0 0 0-.3 .1 .24 .24 0 0 0 0 .3v.5h-.2z" fill-rule="evenodd"/>
<path d="M349.9 276h.2v.2h-.2z" fill-rule="evenodd"/>
<path d="M349.9 276.9h.2v.2h-.2z" fill-rule="evenodd"/>
</g>
<path d="M332 274.5h34.5M339.5 274.5v10.5" fill="none" stroke="#000" stroke-width=".18"/>
<g fill="#00f">
<path d="M341.2 265.1h.5a.75 .75 0 0 1 .7 .8 .75 .75 0 0 1-.7 .7h-.5v-.2h.5a.58 .58 0 0 0 .5-.5 .58 .58 0 0 0-.5-.6h-.3v1.1h-.2z" fill-rule="evenodd"/>
<path d="M342.7 265.7a.51 .51 0 0 1 .6-.1 .51 .51 0 0 1 .3 .5h-.8l.2 .4 .6-.2a.52 .52 0 0 1-.7 .3 .52 .52 0 0 1-.3-.6h.8l-.2-.3a.31 .31 0 0 0-.4 .3h-.2z" fill-rule="evenodd"/>
<path d="M343.8 265.6l.3-.1a.39 .39 0 0 1 .5 .3h-.2a.21 .21 0 0 0-.2-.2 .21 .21 0 0 0-.2 .3 .43 .43 0 0 1 .5 .1 .43 .43 0 0 1 .1 .4l-.2 .2h-.4l-.3-.3h.2a.24 .24 0 0 0 .3 .3 .24 .24 0 0 0 .2-.4 .43 .43 0 0 1-.6-.5z" fill-rule="evenodd"/>
<path d="M344.9 265.1h.2v.2h-.2z" fill-rule="evenodd"/>
<path d="M344.9 265.5h.2v1.1h-.2z" fill-rule="evenodd"/>
<path d="M345.4 265.6a.43 .43 0 0 1 .7 .1v-.2h.1v1a.48 .48 0 0 1-.3 .5 .48 .48 0 0 1-.6-.3l.4 .2a.3 .3 0 0 0 .3-.4 .46 .46 0 0 1-.5 .1 .46 .46 0 0 1-.2-.5h.2a.34 .34 0 0 0 .4 .3 .34 .34 0 0 0 .1-.5 .3 .3 0 0 0-.3-.2 .3 .3 0 0 0-.2 .4h-.2z" fill-rule="evenodd"/>
<path d="M346.5 265.5h.2v.2l.1-.2a.37 .37 0 0 1 .5 .1 .37 .37 0 0 1 .1 .4v.6h-.2v-.6a.27 .27 0 0 0-.3-.3 .27 .27 0 0 0-.2 .3v.6h-.2z" fill-rule="evenodd"/>
<path d="M347.7 265.7a.51 .51 0 0 1 .7-.1 .51 .51 0 0 1 .2 .5h-.8l.2 .4 .6-.2a.52 .52 0 0 1-.6 .3 .52 .52 0 0 1-.4-.6h.8l-.2-.3a.31 .31 0 0 0-.4 .3h-.2z" fill-rule="evenodd"/>
<path d="M348.8 265.5h.2v.2l.2-.2h.2v.2a.24 .24 0 0 0-.3 .1 .24 .24 0 0 0-.1 .3v.5h-.2z" fill-rule="evenodd"/>
<path d="M349.6 265.5h.2v.2h-.2z" fill-rule="evenodd"/>
<path d="M349.6 266.4h.2v.2h-.2z" fill-rule="evenodd"/>
</g>
<path d="M332 264h34.5M339.5 264v10.5" fill="none" stroke="#000" stroke-width=".18"/>
<g fill="#00007f">
<path d="M341 269.7h.6a.7 .7 0 0 1 .8 .7 .7 .7 0 0 1-.7 .7h-.7l.2-.1v-1.2h.2v1.2a.65 .65 0 0 0 .8-.7 .65 .65 0 0 0-1-.5z" fill-rule="evenodd"/>
<path d="M342.7 270.2l.5 .1 .1 .7 .1-.1-.1 .2-.2-.1-.3 .1-.2-.1v-.1l.3 .1 .2-.1v-.3l-.5 .3 .5-.4-.2-.3-.3 .3z" fill-rule="evenodd"/>
<path d="M343.5 270.3l.3-.1v.2a.29 .29 0 0 1 .3-.2 .29 .29 0 0 1 .2 .3v.5l.2 .1h-.5l.2-.2v-.5l-.2-.1-.2 .1v.6l.1 .1h-.4l.1-.1v-.6z" fill-rule="evenodd"/>
<path d="M344.6 270.3l.3-.1v.8l.1 .1h-.4l.1-.1v-.5v-.2z" fill-rule="evenodd"/>
<path d="M345.3 270.3l.4-.1 .2 .2 .1 .1h-.7l.2 .4 .3 .1 .1-.2a.41 .41 0 0 1-.5 .3 .41 .41 0 0 1-.2-.6h.5l-.2-.3-.3 .3z" fill-rule="evenodd"/>
<path d="M346.1 269.8l.3-.1v1.3l.2 .1h-.5l.1-.1v-1.1z" fill-rule="evenodd"/>
<path d="M347.2 269.7h.5l-.1 .1-.1 .6 .6-.5-.1-.2h.5l-.8 .7 1 .7h-.7l.1-.1-.6-.6 .1 .6 .1 .1h-.5l.2-.2-.1-1z" fill-rule="evenodd"/>
<path d="M348.8 270.2l.6 .1v.7l.2-.1-.2 .2-.2-.1-.3 .1-.2-.1v-.1l.3 .1 .2-.1v-.3l-.5 .3 .5-.4-.1-.3-.3 .3z" fill-rule="evenodd"/>
<path d="M349.6 270.3l.3-.1v.2l.4-.2a.29 .29 0 0 0 .5 0l.2 .1 .1 .7 .1 .1h-.5l.2-.1v-.5a.2 .2 0 0 0-.2-.2 .2 .2 0 0 0-.2 .2v.5l.1 .1h-.4l.1-.1v-.5l-.1-.2-.3 .1v.6l.2 .1h-.5l.1-.1v-.5v-.2z" fill-rule="evenodd"/>
<path d="M351.2 270.3l.3-.1v.2a.39 .39 0 0 1 .6-.1 .39 .39 0 0 1 0 .5l-.2 .3h-.4v.4l.2 .1h-.5l.2-.2v-1h.1l.1 .6a.33 .33 0 0 0 .4-.3 .33 .33 0 0 0-.4-.3h-.2z" fill-rule="evenodd"/>
<path d="M352.4 270.3l.4-.1 .3 .2v.1h-.6l.1 .4 .3 .1 .2-.2a.41 .41 0 0 1-.6 .3 .41 .41 0 0 1-.1-.6h.5l-.2-.3-.3 .3z" fill-rule="evenodd"/>
<path d="M353.2 270.3l.3-.1v.2l.2-.2h.2l-.4 .3v.5l.2 .1h-.5l.1-.1 .1-.5-.1-.2z" fill-rule="evenodd"/>
<path d="M354.2 269.9v.3h.2h-.2v.7h.3l-.3 .2-.1-.1-.1-.8h-.1z" fill-rule="evenodd"/>
<circle cx="344.8" cy="269.8" r=".1"/>
</g>
<path d="M332 264h-34.5v10.5h34.5" fill="none" stroke="#000" stroke-width=".18"/>
<g fill="#00007f">
<path d="M299.2 269.7h1l-.9 1.3h.7l.2-.3v.4h-1.2l.9-1.3h-.6l-.2 .3z" fill-rule="evenodd"/>
<path d="M300.5 269.8l.7-.1v.5a.29 .29 0 0 0-.3-.4 .29 .29 0 0 0-.2 .4h.1a.51 .51 0 0 1 .4 .3 .51 .51 0 0 1 0 .5l-.8 .2 .1-.5a.33 .33 0 0 0 .3 .4 .33 .33 0 0 0 .3-.4l-.1-.1a.51 .51 0 0 1-.5-.2 .51 .51 0 0 1 0-.6z" fill-rule="evenodd"/>
<path d="M301.5 269.7h.5l-.1 .2 .3 .9 .2-.7-.3-.4h.6l-.2 .2 .3 .9 .3-.9-.1-.2h.4l-.2 .2-.4 1.3-.3-.9-.4 .9-.5-1.4z" fill-rule="evenodd"/>
<path d="M303.5 270.2l.5 .1v.7l.2-.1-.1 .2h-.2v-.1l-.3 .1-.2-.1-.1-.1 .4 .1 .2-.1v-.3l-.6 .3 .6-.4-.2-.3-.3 .3z" fill-rule="evenodd"/>
<path d="M304.5 269.9v.3h.3h-.3v.7h.3l-.3 .2-.1-.1v-.8h-.2z" fill-rule="evenodd"/>
<path d="M305 270.3l.4-.1 .2 .1-.1 .2a.28 .28 0 0 0-.4-.3 .28 .28 0 0 0-.1 .5 .3 .3 0 0 0 .3 .3 .3 .3 0 0 0 .3-.2 .43 .43 0 0 1-.6 .3 .43 .43 0 0 1-.1-.7z" fill-rule="evenodd"/>
<path d="M305.7 269.8l.3-.1v.7l.3-.2h.2l.1 .8 .1 .1h-.4l.1-.2v-.5l-.1-.1-.3 .1 .1 .6 .1 .1h-.5l.2-.1v-.9v-.3z" fill-rule="evenodd"/>
<path d="M306.8 270.6h.6v.1h-.6z" fill-rule="evenodd"/>
<path d="M307.5 269.7h.6a.7 .7 0 0 1 .8 .7 .7 .7 0 0 1-.8 .7h-.6l.2-.1v-1.2h.2v1.2a.65 .65 0 0 0 .7-.7 .65 .65 0 0 0-.9-.5z" fill-rule="evenodd"/>
<path d="M309.2 270.3a.46 .46 0 0 1 .7 .1 .46 .46 0 0 1-.3 .7 .46 .46 0 0 1-.6-.5h.2a.31 .31 0 0 0 .1 .4 .31 .31 0 0 0 .4-.1 .38 .38 0 0 0 0-.5 .38 .38 0 0 0-.4-.1l-.1 .3h-.2z" fill-rule="evenodd"/>
<path d="M310.2 270.3l.4-.1 .2 .1v.2a.28 .28 0 0 0-.4-.3 .28 .28 0 0 0-.1 .5 .3 .3 0 0 0 .2 .3 .3 .3 0 0 0 .4-.2 .43 .43 0 0 1-.7 .3 .43 .43 0 0 1 0-.7z" fill-rule="evenodd"/>
<path d="M311 269.8l.3-.1v.9l.3-.3v-.1h.4l-.5 .3 .5 .6h-.4v-.1l-.3-.4v.4l.1 .1h-.4l.1-.2v-1z" fill-rule="evenodd"/>
<path d="M312.5 269.8l.4-.1v.9l.3-.3-.1-.1h.4l-.5 .3 .6 .6h-.5l.1-.1-.3-.4v.4l.1 .1h-.5l.2-.2v-1z" fill-rule="evenodd"/>
<path d="M313.6 270.3l.4-.1v.8l.1 .1h-.4l.1-.1v-.5v-.2z" fill-rule="evenodd"/>
<path d="M314.4 270.3l.4-.1 .2 .1-.1 .2a.28 .28 0 0 0-.4-.3 .28 .28 0 0 0-.1 .5 .3 .3 0 0 0 .3 .3 .3 .3 0 0 0 .3-.2 .43 .43 0 0 1-.6 .3 .43 .43 0 0 1-.1-.7z" fill-rule="evenodd"/>
<path d="M315.3 270.2l.5 .1 .1 .7 .1-.1-.1 .2h-.1l-.1-.1-.3 .1-.2-.1v-.1l.3 .1 .2-.1v-.3l-.5 .3 .5-.4-.2-.3-.3 .3z" fill-rule="evenodd"/>
<path d="M316.6 269.8l.3-.1v1.3h.2l-.6 .2-.3-.2-.1-.4h.2l.2 .4 .3-.1-.2-.7-.2 .1-.1 .3h-.2a.42 .42 0 0 1 .7-.4l-.1-.4z" fill-rule="evenodd"/>
<path d="M317.1 271.5l1 .1z" fill-rule="evenodd"/>
<path d="M318.1 270.3l.3-.1v.2a.39 .39 0 0 1 .6-.1 .39 .39 0 0 1 .1 .5l-.3 .3h-.4l.1 .4 .1 .1h-.5l.2-.2v-1h.1l.1 .6a.33 .33 0 0 0 .4-.3 .33 .33 0 0 0-.4-.3h-.2z" fill-rule="evenodd"/>
<path d="M319.4 270.3l.4-.1 .2 .1-.1 .2a.28 .28 0 0 0-.4-.3 .28 .28 0 0 0-.1 .5 .3 .3 0 0 0 .3 .3 .3 .3 0 0 0 .3-.2 .43 .43 0 0 1-.6 .3 .43 .43 0 0 1-.1-.7z" fill-rule="evenodd"/>
<path d="M320.1 269.8l.3-.1v.6a.43 .43 0 0 1 .7 .1 .43 .43 0 0 1-.3 .7l-.2 .1-.3-.2v-.6h.1v.6a.32 .32 0 0 0 .5-.3 .32 .32 0 0 0-.5-.3h-.1v-.5z" fill-rule="evenodd"/>
<circle cx="312.3" cy="271" r=".11"/>
<circle cx="313.9" cy="269.8" r=".1"/>
</g>
<path d="M366.5 253.5h-69v10.5" fill="none" stroke="#000" stroke-width=".18"/>
<g fill="#00f">
<path d="M299.2 254.6l.8 .1 .2 .4a.25 .25 0 0 0-.1 .2 .25 .25 0 0 0 .2 .2 .45 .45 0 0 1-.1 .5 .45 .45 0 0 1-.5 .1h-.5v-.2h.7l.2-.1-.1-.3-.6-.1v.5h-.2v-.7h.5a.24 .24 0 0 0 .3-.1 .24 .24 0 0 0-.2-.3h-.4v.4h-.2z" fill-rule="evenodd"/>
<path d="M300.6 255.1a.55 .55 0 0 1 .9 .1 .55 .55 0 0 1-.3 .8 .55 .55 0 0 1-.7-.4h.2a.36 .36 0 0 0 .4 .4 .36 .36 0 0 0 .2-.6l-.4-.2-.2 .4h-.2z" fill-rule="evenodd"/>
<path d="M301.8 255.2l.1-.2a.47 .47 0 0 1 .6 .1 .47 .47 0 0 1 .1 .6v.4h-.1l-.1-.1-.5 .1-.2-.1-.1-.2 .4 .2h.2l.2-.4-.8 .2a.57 .57 0 0 1 .8-.4 .28 .28 0 0 0-.2-.2 .28 .28 0 0 0-.3 .2l-.2-.1z" fill-rule="evenodd"/>
<path d="M302.9 255h.1v.2l.2-.2h.2v.2a.25 .25 0 0 0-.3 .1 .25 .25 0 0 0 0 .3v.5h-.2z" fill-rule="evenodd"/>
<path d="M303.7 255.1l.3-.1 .3 .2v-.6h.1v1.5h-.1v-.1a.45 .45 0 0 1-.6 .1 .45 .45 0 0 1-.2-.5h.2a.34 .34 0 0 0 .4 .4 .34 .34 0 0 0 .2-.6l-.4-.2-.2 .4h-.2z" fill-rule="evenodd"/>
<path d="M305.3 254.6h.2l.8 1.2v-1.2h.2v1.5h-.2l-.8-1.2v1.2h-.2z" fill-rule="evenodd"/>
<path d="M306.9 255.2l.1-.2a.47 .47 0 0 1 .6 .1 .47 .47 0 0 1 .1 .6l.1 .4h-.2l-.1-.1-.4 .1-.3-.1v-.2l.3 .2h.3l.1-.4-.7 .2a.57 .57 0 0 1 .7-.4 .28 .28 0 0 0-.2-.2 .28 .28 0 0 0-.3 .2l-.2-.1z" fill-rule="evenodd"/>
<path d="M308 255h.2v.2l.2-.2 .4 .2 .3-.2 .2 .1 .2 .2v.8h-.2v-.7a.24 .24 0 0 0-.3-.2 .24 .24 0 0 0-.2 .3v.6h-.2v-.7a.25 .25 0 0 0-.3-.2 .25 .25 0 0 0-.1 .4v.5h-.2z" fill-rule="evenodd"/>
<path d="M309.8 255.2a.51 .51 0 0 1 .6-.1 .51 .51 0 0 1 .3 .5h-.8l.2 .4 .6-.2a.52 .52 0 0 1-.7 .3 .52 .52 0 0 1-.3-.6h.8l-.2-.3a.31 .31 0 0 0-.4 .3h-.2z" fill-rule="evenodd"/>
<path d="M311 255h.2v.2h-.2z" fill-rule="evenodd"/>
<path d="M311 255.9h.2v.2h-.2z" fill-rule="evenodd"/>
<path d="M368 244.1h.2l.5 1.4 .5-1.4h.2l-.6 1.5h-.2z" fill-rule="evenodd"/>
<path d="M369.6 244.6l.1-.1a.47 .47 0 0 1 .5 .1 .47 .47 0 0 1 .1 .6l.1 .4h-.2v-.1l-.5 .1-.3-.1v-.2l.6 .2 .2-.4-.8 .2a.57 .57 0 0 1 .8-.4 .28 .28 0 0 0-.3-.2 .28 .28 0 0 0-.3 .2l-.2-.1z" fill-rule="evenodd"/>
<path d="M370.5 244.5h.2v.2l.2-.2h.2v.2a.25 .25 0 0 0-.3 .1 .25 .25 0 0 0-.1 .3v.5h-.2z" fill-rule="evenodd"/>
<path d="M371.2 244.1h.2v.2h-.2z" fill-rule="evenodd"/>
<path d="M371.2 244.5h.2v1.1h-.2z" fill-rule="evenodd"/>
<path d="M371.8 244.6l.1-.1a.47 .47 0 0 1 .6 .1 .47 .47 0 0 1 .1 .6l.1 .4h-.2l-.1-.1-.5 .1-.2-.1v-.2l.3 .2h.3l.1-.4-.7 .2a.57 .57 0 0 1 .7-.4 .28 .28 0 0 0-.2-.2 .28 .28 0 0 0-.3 .2l-.2-.1z" fill-rule="evenodd"/>
<path d="M372.9 244.5h.1v.2l.2-.2a.37 .37 0 0 1 .4 .1 .37 .37 0 0 1 .2 .4v.6h-.2v-.6a.27 .27 0 0 0-.3-.3 .27 .27 0 0 0-.2 .3v.6h-.2z" fill-rule="evenodd"/>
<path d="M374.1 244.3l.2-.1v.3h.2v.2h-.2v.6l.2 .3a.27 .27 0 0 1-.3 0 .27 .27 0 0 1-.1-.3v-.6h-.2z" fill-rule="evenodd"/>
<path d="M374.7 244.5h.2v.2h-.2z" fill-rule="evenodd"/>
<path d="M374.7 245.4h.2v.2h-.2z" fill-rule="evenodd"/>
</g>
<path d="M408 243h-41.5v10.5" fill="none" stroke="#000" stroke-width=".18"/>
<g fill="#00007f">
<path d="M368 248.7h.5a.42 .42 0 0 1 .6 .5 .42 .42 0 0 1-.7 .3v.5l.2 .1h-.6l.2-.1v-1.2h.2v.6a.31 .31 0 0 0 .5-.3 .31 .31 0 0 0-.5-.3z" fill-rule="evenodd"/>
<path d="M369.2 248.7h.8l.2 .2a.35 .35 0 0 1 .1 .3 .35 .35 0 0 1-.4 .2l.7 .7h-.4l-.5-.6h-.1v.5l.2 .1h-.6l.2-.1v-1.2h.2v.6a.32 .32 0 0 0 .5-.3 .32 .32 0 0 0-.5-.3z" fill-rule="evenodd"/>
<path d="M370.6 248.7h1.1v.3l-.2-.2h-.5v.6l.4-.1 .2-.1v.4l-.2-.1-.4-.1 .1 .6a.51 .51 0 0 0 .7-.2l-.1 .3h-1.1l.2-.2v-1z" fill-rule="evenodd"/>
<path d="M371.9 248.7h.6l-.2 .2v1a.48 .48 0 0 0 .8-.2l-.1 .4h-1.1l.2-.2v-1z" fill-rule="evenodd"/>
<path d="M373.2 248.7h.6l-.2 .3v1l.2 .1h-.6l.2-.2v-1z" fill-rule="evenodd"/>
<path d="M373.9 248.7h.4l.5 1.1 .5-1.1h.4l-.2 .3v1l.2 .1h-.6l.2-.1v-1l-.6 1.1-.5-1.1v1l.1 .1h-.4l.2-.2v-1z" fill-rule="evenodd"/>
<path d="M375.7 248.7h.6l-.2 .3v1l.2 .1h-.6l.2-.2v-1z" fill-rule="evenodd"/>
<path d="M376.4 248.7h.3l.9 1.1v-1l-.2-.1h.5l-.2 .2v1.2l-1-1.1v1l.2 .1h-.5l.2-.1v-1.1z" fill-rule="evenodd"/>
<path d="M378.6 248.7l.6 1.3 .2 .1h-.5l.1-.1-.1-.3h-.6l-.1 .3 .2 .1h-.5l.4-.5h.5l-.2-.6-.3 .6z" fill-rule="evenodd"/>
<path d="M379.5 248.7h.7l.3 .2a.35 .35 0 0 1 0 .3 .35 .35 0 0 1-.3 .2l.6 .7h-.3l-.5-.6h-.1v.5l.2 .1h-.6l.2-.1-.1-1.2h.3v.6a.32 .32 0 0 0 .4-.3 .32 .32 0 0 0-.4-.3z" fill-rule="evenodd"/>
<path d="M380.7 248.7h.6l-.1 .2 .3 .5 .3-.5-.1-.2h.5l-.6 .8v.5l.2 .1h-.6l.1-.1 .1-.4z" fill-rule="evenodd"/>
</g>
<path d="M366.5 243h-69v10.5" fill="none" stroke="#000" stroke-width=".18"/>
<g fill="#00f">
<path d="M299.3 244.3l.4-.2h.3l.4 .3v.1l-.2 .1a.53 .53 0 0 0-.8-.2 .53 .53 0 0 0 0 .8l.4 .3 .3-.1 .1-.3h.2a.72 .72 0 0 1-1 .4 .72 .72 0 0 1-.2-1.1z" fill-rule="evenodd"/>
<path d="M300.8 244.6a.54 .54 0 0 1 .8 .1 .54 .54 0 0 1-.3 .8 .54 .54 0 0 1-.7-.3v-.1h.2a.36 .36 0 0 0 .4 .4 .36 .36 0 0 0 .2-.6l-.4-.2-.2 .4h-.2z" fill-rule="evenodd"/>
<path d="M301.8 244.5h.2v.2l.4-.2 .2 .2 .3-.2 .3 .1 .1 .2v.8h-.2v-.7a.24 .24 0 0 0-.3-.2 .24 .24 0 0 0-.1 .3v.6h-.2v-.7a.25 .25 0 0 0-.4-.2 .25 .25 0 0 0-.1 .4v.5h-.2z" fill-rule="evenodd"/>
<path d="M303.6 244.5h.1v.2a.5 .5 0 0 1 .8 .4 .5 .5 0 0 1-.7 .4v.5h-.2v-.9h.1a.33 .33 0 0 0 .4 .4 .33 .33 0 0 0 .2-.5l-.1-.3h-.2l-.3 .4h-.1z" fill-rule="evenodd"/>
<path d="M304.8 244.6l.1-.1a.47 .47 0 0 1 .6 .1 .47 .47 0 0 1 .1 .6l.1 .4h-.2l-.1-.1-.4 .1-.3-.1v-.2l.3 .2h.3l.1-.4-.7 .2a.57 .57 0 0 1 .7-.4 .28 .28 0 0 0-.2-.2 .28 .28 0 0 0-.3 .2l-.2-.1z" fill-rule="evenodd"/>
<path d="M305.9 244.5h.2v.2l.1-.2a.37 .37 0 0 1 .5 .1 .37 .37 0 0 1 .1 .4v.6h-.2v-.6a.27 .27 0 0 0-.3-.3 .27 .27 0 0 0-.2 .3v.6h-.2z" fill-rule="evenodd"/>
<path d="M307 244.5h.2l.3 .9 .3-.9h.2l-.5 1.1a.38 .38 0 0 1-.4 .4l-.1-.1 .3-.1 .1-.2z" fill-rule="evenodd"/>
<path d="M308.2 244.5h.2v.2h-.2z" fill-rule="evenodd"/>
<path d="M308.2 245.4h.2v.2h-.2z" fill-rule="evenodd"/>
</g>
<g fill="#00007f">
<path d="M299.2 248.7h1.1l-.8 1.3a.68 .68 0 0 0 .9-.4l-.1 .5h-1.3l.9-1.3a.54 .54 0 0 0-.8 .3z" fill-rule="evenodd"/>
<path d="M300.6 248.8l.8-.1v.5l-.4-.4-.3 .2 .2 .2a.5 .5 0 0 1 .6 .3 .5 .5 0 0 1-.3 .6l-.7 .1v-.6a.35 .35 0 0 0 .3 .5 .35 .35 0 0 0 .4-.3l-.2-.2a.46 .46 0 0 1-.4-.3 .46 .46 0 0 1 0-.5z" fill-rule="evenodd"/>
<path d="M301.6 248.7h.6l-.1 .2 .3 .8 .2-.5-.3-.5h.7l-.2 .1 .3 .8 .3-.7-.1-.2 .3 .1-.6 1.4-.4-.9-.4 .9z" fill-rule="evenodd"/>
<path d="M303.7 249.3l.4-.2 .3 .1v.8h.2l-.1 .1h-.3l-.1-.1-.2 .1-.2-.1v-.1h.4v-.3l-.2 .3h-.2l.4-.4v-.2h-.2a.15 .15 0 0 1 0 .2 .15 .15 0 0 1-.2 0 .15 .15 0 0 1 0-.2z" fill-rule="evenodd"/>
<path d="M305 248.8v.4h.3l-.3 .1 .1 .7 .2-.1-.2 .2a.26 .26 0 0 1-.3-.3v-.5l-.2-.1z" fill-rule="evenodd"/>
<path d="M305.5 249.3l.2-.2a.23 .23 0 0 1 .4 .1 .23 .23 0 0 1-.1 .3l-.2-.3a.37 .37 0 0 0-.1 .5 .37 .37 0 0 0 .5 .2 .47 .47 0 0 1-.8 .1 .47 .47 0 0 1 .1-.7z" fill-rule="evenodd"/>
<path d="M306.3 248.7h.4v.6l.2-.2a.29 .29 0 0 1 .3 .4l.1 .6h-.4v-.2v-.6l-.2 .1 .1 .7h-.5l.1-.2z" fill-rule="evenodd"/>
<path d="M368.7 259h1.5l-1.1 1.7a.91 .91 0 0 0 1.2-.5l-.1 .6h-1.7l1.1-1.7a.73 .73 0 0 0-.9 .4z" fill-rule="evenodd"/>
<path d="M370.7 259.1l.4-.2 .4 .2 .2-.2-.1 .7a.43 .43 0 0 0-.3-.6 .43 .43 0 0 0-.5 .3l.2 .2a.95 .95 0 0 1 .8 .9 .88 .88 0 0 1-1.2 .4l-.1 .1 .1-.7a.48 .48 0 0 0 .3 .5 .48 .48 0 0 0 .6-.3l-.2-.2a.72 .72 0 0 1-.7-1z" fill-rule="evenodd"/>
<path d="M371.9 259h.8l-.1 .2 .4 1 .3-.7-.4-.5h.9l-.2 .1 .4 1.1 .4-1-.2-.2h.5l-.2 .1-.6 1.8-.5-1.2-.6 1.2z" fill-rule="evenodd"/>
<path d="M374.8 259.7l.1-.1a.5 .5 0 0 1 .6-.1 .5 .5 0 0 1 .2 .5l.1 .6h.1a.29 .29 0 0 1-.3 .3 .29 .29 0 0 1-.2-.3 .33 .33 0 0 1-.4 .3 .33 .33 0 0 1-.3-.4h.4l.1 .1 .2-.1v-.4l-.3 .4h-.4l.7-.5-.1-.3h-.3a.2 .2 0 0 1 .1 .3 .2 .2 0 0 1-.3 0 .2 .2 0 0 1 0-.3z" fill-rule="evenodd"/>
<path d="M376.5 259.1l.1 .5h.3v.1h-.3v.9h.2a.34 .34 0 0 1-.4 .2 .34 .34 0 0 1-.2-.4v-.7l-.2-.1z" fill-rule="evenodd"/>
<path d="M377.2 259.7a.4 .4 0 0 1 .5-.2 .4 .4 0 0 1 .2 .5h-.2l-.1-.4a.52 .52 0 0 0-.2 .7 .52 .52 0 0 0 .7 .2 .62 .62 0 0 1-1 .2 .62 .62 0 0 1 0-.9z" fill-rule="evenodd"/>
<path d="M378.2 259h.6v.7a.4 .4 0 0 1 .5-.2 .4 .4 0 0 1 .2 .6v.6l.1 .1h-.6l.1-.2v-.8l-.1-.1-.2 .2v.8l.1 .1h-.7l.2-.2v-1.5z" fill-rule="evenodd"/>
<path d="M380.4 259h.9a.93 .93 0 0 1 1 .9 .93 .93 0 0 1-1 .9h-.9l.3-.1v-.2h.4l.1 .2a.57 .57 0 0 0 .6-.8 .64 .64 0 0 0-.7-.8v1.4h-.4v-1.3z" fill-rule="evenodd"/>
<path d="M382.8 259.6a.63 .63 0 0 1 .8 .2 .63 .63 0 0 1-.1 .9 .63 .63 0 0 1-.9-.1l-.1-.3h.4v.3a.18 .18 0 0 0 .2 .2 .18 .18 0 0 0 .2-.2v-.8a.19 .19 0 0 0-.3-.2 .19 .19 0 0 0-.1 .3v.4h-.4z" fill-rule="evenodd"/>
<path d="M384.1 259.7a.4 .4 0 0 1 .5-.2 .4 .4 0 0 1 .3 .5h-.2l-.2-.4a.52 .52 0 0 0-.2 .7 .52 .52 0 0 0 .7 .2 .62 .62 0 0 1-.9 .2 .62 .62 0 0 1 0-.9z" fill-rule="evenodd"/>
<path d="M385.1 259h.6v1.2l.4-.5-.1-.1h.5l-.5 .4 .6 .8h-.6l.1-.1-.3-.5-.1 .5 .1 .1h-.7l.2-.2v-1.5z" fill-rule="evenodd"/>
<path d="M299.5 258.7h1.1a1.17 1.17 0 0 1 1.3 1.2 1.17 1.17 0 0 1-1.3 1.1h-1.1l.3-.1 .1-.2h.5v.1a.53 .53 0 0 0 .7 0 .53 .53 0 0 0 .1-.6 .93 .93 0 0 0-.8-1.4v1.9h-.5v-1.7z" fill-rule="evenodd"/>
<path d="M302.5 259.5a.79 .79 0 0 1 1.1 .8 .79 .79 0 0 1-1.3 .5l-.1-.4h.5v.3a.22 .22 0 0 0 .2 .3 .22 .22 0 0 0 .2-.2v-1.1a.23 .23 0 0 0-.3-.2 .23 .23 0 0 0-.1 .3v.6h-.5v-.5z" fill-rule="evenodd"/>
<path d="M304.2 259.6a.53 .53 0 0 1 .6-.2 .53 .53 0 0 1 .3 .6 .38 .38 0 0 1-.5-.5 .42 .42 0 0 0-.2 .7 .51 .51 0 0 0 .3 .6 .51 .51 0 0 0 .5-.1 .76 .76 0 0 1-1 .2 .76 .76 0 0 1-.2-1.1z" fill-rule="evenodd"/>
<path d="M305.4 258.7h.7v1.5l.5-.5-.1-.3h.7l-.7 .6 .8 1h-.8l.1-.1-.4-.6-.1 .6 .2 .1h-.9l.2-.3v-1.8z" fill-rule="evenodd"/>
<path d="M307.4 260.1h1v.3h-1z" fill-rule="evenodd"/>
<path d="M308.5 258.7h1.2l-.3 .2v.9h.8v-.9l-.3-.2h1.2l-.3 .1v.3v1.7l.3 .2h-1.2l.3-.1v-1h-.8v1l.3 .1h-1.2l.3-.1v-.3v-1.6z" fill-rule="evenodd"/>
<path d="M311.2 258.7h1l-.2 .3 .5 1.3 .4-.9-.2-.5-.3-.2h1.1l-.2 .2 .5 1.3 .4-1.2v-.1l-.2-.2 .6 .1-.2 .1-.8 2.2-.6-1.5-.7 1.5-.9-2.2z" fill-rule="evenodd"/>
</g>
<path d="M263 274.5h34.5M297.5 264h-34.5v21" fill="none" stroke="#000" stroke-width=".18"/>
<g fill="#00f">
<path d="M299.2 265.1h1v.2h-.8v.5h.7v.1h-.7v.7h-.2z" fill-rule="evenodd"/>
<path d="M300.4 265.1h.2v.2h-.2z" fill-rule="evenodd"/>
<path d="M300.4 265.5h.2v1.1h-.2z" fill-rule="evenodd"/>
<path d="M300.9 265.1h.2v1.5h-.2z" fill-rule="evenodd"/>
<path d="M301.4 265.7a.51 .51 0 0 1 .6-.1 .51 .51 0 0 1 .3 .5h-.8l.2 .4 .6-.2a.52 .52 0 0 1-.7 .3 .52 .52 0 0 1-.3-.6h.8l-.2-.3a.31 .31 0 0 0-.4 .3h-.2z" fill-rule="evenodd"/>
<path d="M303.1 265.1h.2l.8 1.2v-1.2h.2v1.5h-.2l-.8-1.2v1.2h-.2z" fill-rule="evenodd"/>
<path d="M304.7 265.6l.1-.1a.47 .47 0 0 1 .6 .1 .47 .47 0 0 1 .1 .6l.1 .4h-.2l-.1-.1-.5 .1-.2-.1v-.2l.6 .2 .1-.4-.7 .2a.57 .57 0 0 1 .7-.4 .28 .28 0 0 0-.2-.2 .28 .28 0 0 0-.3 .2l-.2-.1z" fill-rule="evenodd"/>
<path d="M305.8 265.5h.1v.2l.5-.2 .2 .2 .2-.2 .3 .1 .2 .2v.8h-.2v-.7a.24 .24 0 0 0-.3-.2 .24 .24 0 0 0-.2 .3v.6h-.2v-.7a.25 .25 0 0 0-.3-.2 .25 .25 0 0 0-.1 .4v.5h-.2z" fill-rule="evenodd"/>
<path d="M307.6 265.7a.51 .51 0 0 1 .6-.1 .51 .51 0 0 1 .3 .5h-.8l.2 .4 .6-.2a.52 .52 0 0 1-.7 .3 .52 .52 0 0 1-.3-.6h.8l-.2-.3a.31 .31 0 0 0-.4 .3h-.2z" fill-rule="evenodd"/>
<path d="M308.8 265.5h.2v.2h-.2z" fill-rule="evenodd"/>
<path d="M308.8 266.4h.2v.2h-.2z" fill-rule="evenodd"/>
<path d="M264.8 265.2l.3-.1h.4l.2 .4-.1 .1a.32 .32 0 0 0-.4-.4 .32 .32 0 0 0-.3 .5h.1a.57 .57 0 0 1 .8 .7 .64 .64 0 0 1-.7 .2 .64 .64 0 0 1-.5-.5h.2a.39 .39 0 0 0 .4 .4 .39 .39 0 0 0 .4-.4l-.3-.1a.49 .49 0 0 1-.5-.2 .49 .49 0 0 1 0-.6z" fill-rule="evenodd"/>
<path d="M266 265.1h.2v.6l.3-.2 .4 .2v.9h-.2v-.7a.27 .27 0 0 0-.3-.2 .27 .27 0 0 0-.2 .3v.6h-.2z" fill-rule="evenodd"/>
<path d="M267.3 265.7a.51 .51 0 0 1 .6-.1 .51 .51 0 0 1 .2 .5h-.8l.3 .4 .5-.2a.52 .52 0 0 1-.6 .3 .52 .52 0 0 1-.3-.6h.8l-.2-.3a.31 .31 0 0 0-.5 .3h-.1z" fill-rule="evenodd"/>
<path d="M268.5 265.7a.51 .51 0 0 1 .6-.1 .51 .51 0 0 1 .2 .5h-.8l.2 .4 .6-.2a.52 .52 0 0 1-.6 .3 .52 .52 0 0 1-.4-.6h.8l-.2-.3a.31 .31 0 0 0-.4 .3h-.2z" fill-rule="evenodd"/>
<path d="M269.6 265.3l.2-.1v.3h.1v.2h-.1v.6l.2 .3a.27 .27 0 0 1-.3 0 .27 .27 0 0 1-.1-.3v-.6h-.2z" fill-rule="evenodd"/>
<path d="M270.6 265.1h1.2v.2h-.5v1.3h-.2v-1.3h-.5z" fill-rule="evenodd"/>
<path d="M271.9 265.1h.2v.2h-.2z" fill-rule="evenodd"/>
<path d="M271.9 265.5h.2v1.1h-.2z" fill-rule="evenodd"/>
<path d="M272.4 265.3l.2-.1v.3h.1v.2h-.1v.6l.2 .3a.27 .27 0 0 1-.3 0 .27 .27 0 0 1-.1-.3v-.6h-.2z" fill-rule="evenodd"/>
<path d="M272.9 265.1h.2v1.5h-.2z" fill-rule="evenodd"/>
<path d="M273.5 265.7a.51 .51 0 0 1 .6-.1 .51 .51 0 0 1 .2 .5h-.8l.3 .4 .5-.2a.52 .52 0 0 1-.6 .3 .52 .52 0 0 1-.4-.6h.8l-.1-.3a.31 .31 0 0 0-.5 .3h-.2z" fill-rule="evenodd"/>
<path d="M274.6 265.5h.2v.2h-.2z" fill-rule="evenodd"/>
<path d="M274.6 266.4h.2v.2h-.2z" fill-rule="evenodd"/>
<path d="M264.8 275.7l.3-.1h.4l.2 .4-.1 .1a.32 .32 0 0 0-.4-.4 .32 .32 0 0 0-.3 .5h.1a.57 .57 0 0 1 .8 .6 .64 .64 0 0 1-.7 .3 .64 .64 0 0 1-.5-.5h.2a.39 .39 0 0 0 .4 .4 .39 .39 0 0 0 .4-.4l-.3-.1a.49 .49 0 0 1-.5-.2 .49 .49 0 0 1 0-.6z" fill-rule="evenodd"/>
<path d="M266 275.6h.2v.6l.3-.2 .4 .2v.9h-.2v-.7a.27 .27 0 0 0-.3-.2 .27 .27 0 0 0-.2 .3v.6h-.2z" fill-rule="evenodd"/>
<path d="M267.3 276.2a.51 .51 0 0 1 .6-.1 .51 .51 0 0 1 .2 .5h-.8l.3 .4 .5-.2a.52 .52 0 0 1-.6 .3 .52 .52 0 0 1-.3-.6h.8l-.2-.3a.31 .31 0 0 0-.5 .3h-.1z" fill-rule="evenodd"/>
<path d="M268.5 276.2a.51 .51 0 0 1 .6-.1 .51 .51 0 0 1 .2 .5h-.8l.2 .4 .6-.2a.52 .52 0 0 1-.6 .3 .52 .52 0 0 1-.4-.6h.8l-.2-.3a.31 .31 0 0 0-.4 .3h-.2z" fill-rule="evenodd"/>
<path d="M269.6 275.8l.2-.1v.3h.1v.2h-.1v.6l.2 .3a.27 .27 0 0 1-.3 0 .27 .27 0 0 1-.1-.3v-.6h-.2z" fill-rule="evenodd"/>
<path d="M270.7 275.6h.6a.46 .46 0 0 1 .6 .5 .46 .46 0 0 1-.6 .4h-.4v.6h-.2v-.8h.6a.28 .28 0 0 0 .4-.2 .28 .28 0 0 0-.4-.3h-.4v.5h-.2z" fill-rule="evenodd"/>
<path d="M272.2 276.2l.1-.2a.47 .47 0 0 1 .6 .1 .47 .47 0 0 1 .1 .6v.4h-.1l-.1-.1-.5 .1-.2-.1-.1-.2 .4 .2h.2l.2-.4-.8 .2a.57 .57 0 0 1 .8-.4 .28 .28 0 0 0-.2-.2 .28 .28 0 0 0-.3 .2l-.2-.1z" fill-rule="evenodd"/>
<path d="M273.3 275.8l.2-.1v.3h.2v.2h-.2v.6l.2 .3a.27 .27 0 0 1-.3 0 .27 .27 0 0 1-.1-.3v-.6h-.1z" fill-rule="evenodd"/>
<path d="M273.9 275.6h.1v.6l.4-.2 .3 .1v1h-.1v-.7a.27 .27 0 0 0-.4-.2 .27 .27 0 0 0-.2 .3v.6h-.1z" fill-rule="evenodd"/>
<path d="M275.1 276h.2v.2h-.2z" fill-rule="evenodd"/>
<path d="M275.1 276.9h.2v.2h-.2z" fill-rule="evenodd"/>
</g>
<g fill="#00007f">
<path d="M264.6 269.7h1.1v.4l-.1-.2-.4-.1v1.2l.2 .1h-.6l.2-.1v-1.2h-.3l-.1 .3z" fill-rule="evenodd"/>
<path d="M265.9 270.3a.46 .46 0 0 1 .7 .1 .46 .46 0 0 1-.3 .7 .46 .46 0 0 1-.6-.5h.2a.31 .31 0 0 0 .1 .4 .31 .31 0 0 0 .4-.1 .37 .37 0 0 0 0-.5 .37 .37 0 0 0-.4-.1l-.1 .3h-.2z" fill-rule="evenodd"/>
<path d="M266.7 270.3l.3-.1v.2a.39 .39 0 0 1 .6-.1 .39 .39 0 0 1 0 .5l-.2 .3h-.4v.4l.2 .1h-.5l.1-.2v-1h.2v.6a.33 .33 0 0 0 .5-.3 .33 .33 0 0 0-.4-.3h-.3z" fill-rule="evenodd"/>
<path d="M268.3 269.7h1.1l.1 .4-.2-.2-.3-.1v1.2l.2 .1h-.6l.2-.1v-1.2h-.3l-.2 .3z" fill-rule="evenodd"/>
<path d="M269.6 270.3l.3-.1 .3 .2v.1h-.6l.1 .4 .3 .1 .2-.2a.41 .41 0 0 1-.6 .3 .41 .41 0 0 1-.1-.6h.5l-.2-.3-.3 .3z" fill-rule="evenodd"/>
<path d="M270.5 270.2h.5v.3l-.3-.3a.14 .14 0 0 0-.2 .1 .14 .14 0 0 0 .1 .2h.1a.34 .34 0 0 1 .3 .5 .34 .34 0 0 1-.6 .1v-.3l.3 .3 .2-.2-.5-.4z" fill-rule="evenodd"/>
<path d="M271.4 269.9v.3h.3h-.3l.1 .7h.2l-.2 .2-.2-.1v-.8h-.2z" fill-rule="evenodd"/>
<path d="M272.2 269.7h.6a.42 .42 0 0 1 .5 .5 .42 .42 0 0 1-.7 .3l.1 .5 .1 .1h-.6l.2-.1v-1.2h.2v.6a.31 .31 0 0 0 .5-.3 .31 .31 0 0 0-.5-.3z" fill-rule="evenodd"/>
<path d="M273.6 270.3a.46 .46 0 0 1 .7 .1 .46 .46 0 0 1-.3 .7 .46 .46 0 0 1-.5-.5h.1a.31 .31 0 0 0 .1 .4 .31 .31 0 0 0 .4-.1h.1a.38 .38 0 0 0 0-.5 .38 .38 0 0 0-.5-.1l-.1 .3h-.1z" fill-rule="evenodd"/>
<path d="M274.5 270.3l.3-.1v.8l.2 .1h-.5l.1-.1v-.5v-.2z" fill-rule="evenodd"/>
<path d="M275 270.3l.4-.1v.2a.29 .29 0 0 1 .3-.2 .29 .29 0 0 1 .2 .3v.5l.2 .1h-.5l.1-.2v-.5l-.1-.1-.2 .1v.6l.1 .1h-.5l.2-.1v-.6z" fill-rule="evenodd"/>
<path d="M276.4 269.9v.3h.2h-.2v.7h.2l-.2 .2-.2-.1v-.8h-.1z" fill-rule="evenodd"/>
<path d="M276.8 270.2h.5v.3l-.2-.3a.14 .14 0 0 0-.2 .1 .14 .14 0 0 0 0 .2h.1a.34 .34 0 0 1 .4 .5 .34 .34 0 0 1-.6 .1v-.3l.2 .3 .2-.2-.4-.4z" fill-rule="evenodd"/>
<path d="M278.4 269.8l.2-.1a1.42 1.42 0 0 0 0 1.9l-.2-.2a1.12 1.12 0 0 1 0-1.6z" fill-rule="evenodd"/>
<path d="M278.9 269.8l.7-.1v.5a.29 .29 0 0 0-.2-.4 .29 .29 0 0 0-.3 .4h.1a.51 .51 0 0 1 .5 .3 .51 .51 0 0 1-.1 .5l-.8 .2 .1-.5a.33 .33 0 0 0 .3 .4 .33 .33 0 0 0 .3-.4l-.1-.1a.51 .51 0 0 1-.5-.2 .51 .51 0 0 1 0-.6z" fill-rule="evenodd"/>
<path d="M280.1 270.3l.4-.1 .2 .1-.1 .2a.28 .28 0 0 0-.4-.3 .28 .28 0 0 0-.1 .5 .3 .3 0 0 0 .3 .3 .3 .3 0 0 0 .3-.2 .43 .43 0 0 1-.6 .3 .43 .43 0 0 1-.1-.7z" fill-rule="evenodd"/>
<path d="M281 270.2l.5 .1 .1 .7 .1-.1-.1 .2h-.2v-.1l-.3 .1-.2-.1v-.1l.3 .1 .2-.1v-.3l-.5 .3 .5-.4-.2-.3-.3 .3z" fill-rule="evenodd"/>
<path d="M281.8 269.8l.3-.1v1.3l.2 .1h-.5l.1-.1v-.9v-.3z" fill-rule="evenodd"/>
<path d="M282.5 270.3l.4-.1 .2 .2 .1 .1h-.7l.2 .4 .3 .1 .1-.2a.41 .41 0 0 1-.5 .3 .41 .41 0 0 1-.2-.6h.6l-.2-.3-.4 .3z" fill-rule="evenodd"/>
<path d="M284 269.9l.4-.2v1.3l.1 .1h-.5l.2-.1v-.9v-.2z" fill-rule="evenodd"/>
<path d="M285.6 269.9l.4-.2v1.3l.2 .1h-.5l.1-.1v-.9v-.2z" fill-rule="evenodd"/>
<path d="M286.5 269.7a1.08 1.08 0 0 1 0 1.9 1.42 1.42 0 0 0 0-1.9z" fill-rule="evenodd"/>
<circle cx="274.7" cy="269.8" r=".1"/>
<circle cx="285.1" cy="270.3" r=".11"/>
<circle cx="285.1" cy="271" r=".11"/>
</g>
<path d="M297.5 243h-34.5v21" fill="none" stroke="#000" stroke-width=".18"/>
<g fill="#00f">
<path d="M264.8 244.3l.4-.2h.3l.4 .3v.1l-.2 .1a.53 .53 0 0 0-.8-.2 .53 .53 0 0 0 0 .8l.4 .3 .3-.1 .1-.3h.2a.72 .72 0 0 1-1 .4 .72 .72 0 0 1-.2-1.1z" fill-rule="evenodd"/>
<path d="M266.3 244.6a.54 .54 0 0 1 .8 .1 .54 .54 0 0 1-.3 .8 .54 .54 0 0 1-.7-.3v-.1h.2a.36 .36 0 0 0 .4 .4 .36 .36 0 0 0 .2-.6l-.4-.2-.2 .4h-.2z" fill-rule="evenodd"/>
<path d="M267.3 244.5h.2v.2l.4-.2 .2 .2 .3-.2 .3 .1 .1 .2v.8h-.2v-.7a.24 .24 0 0 0-.3-.2 .24 .24 0 0 0-.1 .3v.6h-.2v-.7a.25 .25 0 0 0-.4-.2 .25 .25 0 0 0-.1 .4v.5h-.2z" fill-rule="evenodd"/>
<path d="M269.1 244.5h.1v.2l.4-.2 .3 .2 .2-.2 .3 .1 .1 .2v.8h-.1v-.7a.24 .24 0 0 0-.3-.2 .24 .24 0 0 0-.2 .3v.6h-.2v-.7a.25 .25 0 0 0-.3-.2 .25 .25 0 0 0-.1 .4v.5h-.2z" fill-rule="evenodd"/>
<path d="M270.9 244.7a.51 .51 0 0 1 .6-.1 .51 .51 0 0 1 .3 .5h-.9l.3 .4 .6-.2a.52 .52 0 0 1-.7 .3 .52 .52 0 0 1-.3-.6h.8l-.2-.3a.31 .31 0 0 0-.4 .3h-.2z" fill-rule="evenodd"/>
<path d="M272 244.5h.1v.2l.2-.2a.37 .37 0 0 1 .4 .1 .37 .37 0 0 1 .2 .4v.6h-.2v-.6a.27 .27 0 0 0-.3-.3 .27 .27 0 0 0-.2 .3v.6h-.2z" fill-rule="evenodd"/>
<path d="M273.2 244.3l.2-.1v.3h.2v.2h-.2v.6l.2 .3a.27 .27 0 0 1-.3 0 .27 .27 0 0 1-.1-.3v-.6h-.2z" fill-rule="evenodd"/>
<path d="M273.8 244.6l.2-.1a.39 .39 0 0 1 .5 .3h-.2a.21 .21 0 0 0-.2-.2 .21 .21 0 0 0-.1 .3 .43 .43 0 0 1 .4 .1 .43 .43 0 0 1 .1 .4l-.2 .2h-.4l-.2-.3h.1a.24 .24 0 0 0 .3 .3 .24 .24 0 0 0 .2-.4 .43 .43 0 0 1-.6-.5z" fill-rule="evenodd"/>
<path d="M274.8 244.5h.2v.2h-.2z" fill-rule="evenodd"/>
<path d="M274.8 245.4h.2v.2h-.2z" fill-rule="evenodd"/>
</g>
<g fill="#00007f">
<path d="M264.7 248.7h1l-.9 1.3h.7l.2-.3v.4h-1.2l.9-1.3h-.6l-.1 .3z" fill-rule="evenodd"/>
<path d="M266 248.8l.7-.1v.5a.29 .29 0 0 0-.3-.4 .29 .29 0 0 0-.2 .4h.1a.51 .51 0 0 1 .4 .3 .51 .51 0 0 1 0 .5l-.8 .2 .1-.5a.33 .33 0 0 0 .3 .4 .33 .33 0 0 0 .3-.4l-.1-.1a.51 .51 0 0 1-.5-.2 .51 .51 0 0 1 0-.6z" fill-rule="evenodd"/>
<path d="M267 248.7h.5l-.1 .1 .3 1 .2-.7-.3-.4h.6l-.2 .2 .3 .9 .3-.9-.1-.2h.4l-.2 .2-.4 1.3-.3-.9-.4 .9-.5-1.4z" fill-rule="evenodd"/>
<path d="M269 249.2h.3l.2 .1v.7h.2l-.2 .1-.1-.1a.29 .29 0 0 1-.5 0l-.1-.1 .4 .1 .2-.1v-.3l-.6 .3 .6-.4-.2-.3-.3 .3z" fill-rule="evenodd"/>
<path d="M270 248.9v.3h.3h-.3v.7h.3l-.3 .2-.1-.1v-.8h-.2z" fill-rule="evenodd"/>
<path d="M270.5 249.3l.4-.1 .2 .1-.1 .2a.28 .28 0 0 0-.4-.3 .28 .28 0 0 0-.1 .5 .3 .3 0 0 0 .3 .3 .3 .3 0 0 0 .3-.2 .43 .43 0 0 1-.6 .3 .43 .43 0 0 1-.1-.7z" fill-rule="evenodd"/>
<path d="M271.2 248.8l.3-.1v.7l.3-.2h.2l.1 .8 .1 .1h-.4l.1-.2v-.5l-.1-.1-.3 .1 .1 .6 .1 .1h-.5l.2-.1v-.9v-.3z" fill-rule="evenodd"/>
</g>
<path d="M263 243h-42v42M297.5 243h69" fill="none" stroke="#000" stroke-width=".18"/>
<g fill="#000">
<path d="M17.1 17.5a5.9 5.9 0 0 1 2.7 .1 1.87 1.87 0 0 1 .9 2.2 1.87 1.87 0 0 1-2 1.4h-1.6l.4-.2 .1-.4h.9v.2a.65 .65 0 0 0 .7 .2 .65 .65 0 0 0 .4-.6 2.21 2.21 0 0 0-.5-2.7h-.6v2.9h-.9v-2.8l-.2-.2z" fill-rule="evenodd"/>
<path d="M21.7 18.8a1.31 1.31 0 0 1 2 .9 1.31 1.31 0 0 1-1.5 1.5l-.6-.4-.3-.7h.7l.1 .6a.35 .35 0 0 0 .3 .3 .35 .35 0 0 0 .4-.3v-1.7a.37 .37 0 0 0-.5-.3 .37 .37 0 0 0-.2 .5l-.1 .9h-.7v-.7z" fill-rule="evenodd"/>
<path d="M26.5 17.5h1.1v2.4l.8-.9v-.2l-.3-.2h1.2l-1.1 .9 1.3 1.7h-1.3l.1-.3-.6-.9-.1 .1v.8l.2 .3h-1.3l.2-.2 .1-.4v-2.9z" fill-rule="evenodd"/>
<path d="M29.6 19.6h1.6v.6h-1.6z" fill-rule="evenodd"/>
<path d="M31.4 17.5h2l-.5 .2-.1 1.4h1.3v-1.4l-.5-.2h2l-.5 .2-.1 .4v2.7l.2 .2 .4 .2h-2l.5-.3v-1.5h-1.3l.1 1.5 .5 .3h-2l.5-.2v-.5v-2.7l-.1-.2z" fill-rule="evenodd"/>
<path d="M35.7 17.5h1.6l-.3 .2v.2l.8 2.1 .6-1.4a1.18 1.18 0 0 0-.7-1.1h1.8l-.4 .2 .8 2.2 .7-1.9v-.3l-.4-.2h1l-.3 .3-1.3 3.4h-.1l-1-2.3-1.1 2.3-1.4-3.4z" fill-rule="evenodd"/>
<path d="M42.7 17.5h3.1v1h-.1a.94 .94 0 0 0-1.3-.8h-.3v1.5l.6-.2 .4-.6v1.9h-.1a.79 .79 0 0 0-.9-.9v1.5l.5 .3h-1.9l.4-.2 .1-.5v-2.7l-.2-.2z" fill-rule="evenodd"/>
<path d="M46.4 18.9a1.05 1.05 0 0 1 1.2-.4 1.05 1.05 0 0 1 .7 1v1.2h.3a.52 .52 0 0 1-.5 .5 .52 .52 0 0 1-.5-.4 .75 .75 0 0 1-.7 .4 .75 .75 0 0 1-.7-.4l.1-.4h.7l.3 .3 .3-.1v-.9l-.5 .4-.1 .3h-.7l.4-.4 .9-.4v-.6a.33 .33 0 0 0-.5-.3 .33 .33 0 0 0-.1 .6 .39 .39 0 0 1-.6 .3 .39 .39 0 0 1 0-.7z" fill-rule="evenodd"/>
<path d="M48.9 17.5h1v1.4a1.05 1.05 0 0 1 1.4-.1 1.05 1.05 0 0 1 .3 1.3 1.17 1.17 0 0 1-.7 1 1.17 1.17 0 0 1-1.2-.1l-.5 .2v-2.1h.7l.1 1.6a.4 .4 0 0 0 .4 .4 .4 .4 0 0 0 .4-.4v-1.3a.46 .46 0 0 0-.3-.5 .46 .46 0 0 0-.6 .2h-.7v-1.3z" fill-rule="evenodd"/>
<path d="M52.1 18.6h1v.6l.2-.3a.49 .49 0 0 1 .5-.4 .49 .49 0 0 1 .5 .4 .39 .39 0 0 1-.3 .4 .39 .39 0 0 1-.5-.2l-.3 .3-.1 1.2a.46 .46 0 0 0 .4 .6h-1.4l.2-.2 .1-.4v-1.6z" fill-rule="evenodd"/>
<path d="M54.5 18.6h1l.1 2.3 .3 .3h-1.4l.2-.2 .1-.4v-1.7z" fill-rule="evenodd"/>
<path d="M58.9 18.9a1.05 1.05 0 0 1 1.1-.4 1.05 1.05 0 0 1 .8 1v1.2h.2a.52 .52 0 0 1-.5 .5 .52 .52 0 0 1-.5-.4 .75 .75 0 0 1-.6 .4 .75 .75 0 0 1-.7-.4v-.4h.7l.3 .3 .3-.1v-.9l-.5 .4-.1 .3h-.7l.4-.4 .9-.4v-.6a.33 .33 0 0 0-.5-.3 .33 .33 0 0 0 0 .6 .39 .39 0 0 1-.6 .3 .39 .39 0 0 1 0-.7z" fill-rule="evenodd"/>
<path d="M62.3 17.7l.1 .9h.6v.3h-.6v1.8l.2 .2 .3-.3a.68 .68 0 0 1-.8 .6 .68 .68 0 0 1-.5-.9v-1.4h-.3v-.1z" fill-rule="evenodd"/>
<path d="M63.2 18.6h1.1v2.3l.3 .3h-1.4l.2-.2 .1-.4v-1.7z" fill-rule="evenodd"/>
<path d="M65.3 18.8a1.31 1.31 0 0 1 1.9 .9 1.31 1.31 0 0 1-1.5 1.5l-.6-.4-.3-.7h.8l.1 .6a.35 .35 0 0 0 .3 .3 .35 .35 0 0 0 .4-.3v-1.7a.37 .37 0 0 0-.5-.3 .37 .37 0 0 0-.2 .5l-.1 .9h-.8l.1-.7z" fill-rule="evenodd"/>
<path d="M67.6 18.6h1.1v.4a.79 .79 0 0 1 1-.4 .79 .79 0 0 1 .4 1v1.3l.3 .3h-1.3l.2-.3v-1.7a.28 .28 0 0 0-.2-.3 .28 .28 0 0 0-.3 .2l-.1 .2v1.6l.2 .3h-1.3l.2-.2 .1-.4v-1.7z" fill-rule="evenodd"/>
<path d="M72 17.5a5.9 5.9 0 0 1 2.7 .1 1.87 1.87 0 0 1 1 2.2 1.87 1.87 0 0 1-2 1.4h-1.7l.4-.2 .1-.4h.9v.2a.65 .65 0 0 0 .7 .2 .65 .65 0 0 0 .5-.6 2.21 2.21 0 0 0-.5-2.7h-.7v2.9h-.9v-2.8l-.1-.2z" fill-rule="evenodd"/>
<path d="M76.7 18.8a1.31 1.31 0 0 1 1.9 .9 1.31 1.31 0 0 1-1.5 1.5l-.6-.4-.3-.7h.8v.6a.35 .35 0 0 0 .3 .3 .35 .35 0 0 0 .4-.3v-1.7a.37 .37 0 0 0-.5-.3 .37 .37 0 0 0-.2 .5v.9h-.8l.1-.7z" fill-rule="evenodd"/>
<path d="M81.4 18.6h1.1v2a.27 .27 0 0 0 .2 .3 .27 .27 0 0 0 .3-.2l.1-.2v-1.3v-.4l-.2-.2h1v2.3l.3 .3h-1.1v-.4a.79 .79 0 0 1-1 .4 .79 .79 0 0 1-.4-1v-1.3z" fill-rule="evenodd"/>
<path d="M84.6 18.6h1v.4a.79 .79 0 0 1 .8-.5 .79 .79 0 0 1 .7 .5 .82 .82 0 0 1 1-.4 .82 .82 0 0 1 .5 1v1.3l.3 .3h-1.3l.2-.3v-1.7a.31 .31 0 0 0-.2-.3 .31 .31 0 0 0-.4 .2l-.1 .1v1.7l.3 .3h-1.3l.2-.4v-1.6a.3 .3 0 0 0-.2-.3 .3 .3 0 0 0-.3 .2l-.2 .1v1.4l.1 .4 .2 .2h-1.3l.2-.2v-.4v-1.7z" fill-rule="evenodd"/>
<path d="M89.6 18.9a1.03 1.03 0 0 1 1.2-.3 1.03 1.03 0 0 1 .6 1.2h-1.4a.73 .73 0 0 0 .2 .8 .73 .73 0 0 0 .9 0l.2-.2 .1 .1a1.1 1.1 0 0 1-1.3 .7 1.1 1.1 0 0 1-.9-1.3l.1-.4 1.4 .1v-.6l-.3-.3-.4 .3v.5h-.7z" fill-rule="evenodd"/>
<path d="M91.7 18.6h1v.4a.79 .79 0 0 1 1.1-.4 .79 .79 0 0 1 .4 1v1.3l.3 .3h-1.3l.2-.3v-1.7a.28 .28 0 0 0-.2-.3 .28 .28 0 0 0-.3 .2l-.2 .2 .1 1.6 .2 .3h-1.3l.2-.2 .1-.4v-1.7z" fill-rule="evenodd"/>
<path d="M95.7 17.7l.1 .9h.6v.3h-.6v1.8l.2 .2 .3-.3a.68 .68 0 0 1-.8 .6 .68 .68 0 0 1-.4-.9v-1.4h-.4v-.1z" fill-rule="evenodd"/>
<path d="M24.5 18.8a.91 .91 0 0 1 .9-.3 .91 .91 0 0 1 .7 .8 .43 .43 0 0 1-.6 .1 .43 .43 0 0 1-.1-.5l-.3-.2a1.36 1.36 0 0 0 .5 2.1l.5-.3 .1 .1a1.15 1.15 0 0 1-1.5 .5 1.15 1.15 0 0 1-.6-1.4z" fill-rule="evenodd"/>
<path d="M56.6 18.8a.91 .91 0 0 1 .9-.3 .91 .91 0 0 1 .7 .8 .43 .43 0 0 1-.6 .1 .43 .43 0 0 1-.2-.5l-.2-.2a1.35 1.35 0 0 0 .5 2.1l.5-.3 .1 .1a1.16 1.16 0 0 1-1.5 .5 1.16 1.16 0 0 1-.7-1.4z" fill-rule="evenodd"/>
<path d="M79.4 18.8a.91 .91 0 0 1 1-.3 .91 .91 0 0 1 .6 .8 .43 .43 0 0 1-.6 .1 .43 .43 0 0 1-.1-.5l-.3-.2a1.43 1.43 0 0 0 .4 2.1l.7-.2a1.16 1.16 0 0 1-1.5 .5 1.16 1.16 0 0 1-.6-1.4z" fill-rule="evenodd"/>
<path d="M184.1 64.7h2.7v.9a.82 .82 0 0 0-1-.7l.1 2.5 .4 .3h-1.6l.4-.3v-2.5a.81 .81 0 0 0-1 .7z" fill-rule="evenodd"/>
<path d="M187.1 65.8a1.04 1.04 0 0 1 1.6 .9 1.04 1.04 0 0 1-1.6 .9l-.3-.7h.6v.4a.28 .28 0 0 0 .3 .3 .28 .28 0 0 0 .3-.2v-1.4a.3 .3 0 0 0-.4-.2 .3 .3 0 0 0-.2 .4v.7h-.6v-.6z" fill-rule="evenodd"/>
<path d="M188.9 65.7h.9v.3a.79 .79 0 0 1 1-.3 .79 .79 0 0 1 .4 1 .82 .82 0 0 1-.4 .9 .82 .82 0 0 1-1-.1v1l.3 .2h-1.2l.3-.2v-2.3h.6v1.1a.33 .33 0 0 0 .3 .3 .33 .33 0 0 0 .3-.3v-1.1a.33 .33 0 0 0-.3-.3 .33 .33 0 0 0-.3 .3h-.6l-.1-.4z" fill-rule="evenodd"/>
<path d="M192.6 64.7h2.6v.9a.82 .82 0 0 0-.9-.7v2.5l.4 .3h-1.6l.4-.3v-2.5a.81 .81 0 0 0-.9 .7z" fill-rule="evenodd"/>
<path d="M195.4 65.9a.83 .83 0 0 1 1.1-.2 .83 .83 0 0 1 .4 .9h-1.1a.58 .58 0 0 0 .3 .8 .58 .58 0 0 0 .7-.3 .85 .85 0 0 1-1 .7 .85 .85 0 0 1-.6-1.1v-.3l1.1 .1-.1-.7a.39 .39 0 0 0-.4 .2 .39 .39 0 0 0-.1 .4h-.5z" fill-rule="evenodd"/>
<path d="M197.3 65.8a.87 .87 0 0 1 1-.1l.1-.1 .1 .7a.67 .67 0 0 0-.8-.5v.3a1.42 1.42 0 0 1 .9 1 .77 .77 0 0 1-1.2 .6l-.2 .1v-.8a.74 .74 0 0 0 .9 .6v-.3a1.58 1.58 0 0 1-.9-1.2z" fill-rule="evenodd"/>
<path d="M199.6 64.9l.1 .8h.5v.2h-.5v1.5l.2 .1 .2-.2a.55 .55 0 0 1-.6 .4 .55 .55 0 0 1-.4-.7v-1.1l-.3-.1z" fill-rule="evenodd"/>
<path d="M201.5 64.7h1.3a.86 .86 0 0 1 1 .3 .86 .86 0 0 1 0 1l-.5 .3-.7 .1v1.1l.4 .2h-1.5l.4-.2v-1.3h.7a.65 .65 0 0 0 .7-.6 .65 .65 0 0 0-.7-.7v1.3h-.7v-1.2z" fill-rule="evenodd"/>
<path d="M204.7 65.8a1.04 1.04 0 0 1 1.5 .9 1.04 1.04 0 0 1-1.5 .9l-.4-.7h.7v.4a.28 .28 0 0 0 .2 .3 .28 .28 0 0 0 .3-.2v-1.4a.3 .3 0 0 0-.3-.2 .3 .3 0 0 0-.2 .4v.7h-.7l.1-.6z" fill-rule="evenodd"/>
<path d="M206.5 65.7h.9v1.8l.2 .2h-1.1l.2-.1v-.3v-1.4z" fill-rule="evenodd"/>
<path d="M207.8 65.7h.8v.3a.64 .64 0 0 1 .9-.3 .64 .64 0 0 1 .3 .8v1l.2 .2h-1l.2-.2v-1.4a.23 .23 0 0 0-.2-.2 .23 .23 0 0 0-.3 .2l-.1 1.2 .2 .4h-1l.2-.1v-.3v-1.4z" fill-rule="evenodd"/>
<path d="M211.1 64.9v.8h.5v.2h-.5v1.5l.2 .1 .3-.2a.55 .55 0 0 1-.7 .4 .55 .55 0 0 1-.4-.7v-1.1l-.3-.1z" fill-rule="evenodd"/>
<path d="M212 65.8a.87 .87 0 0 1 1-.1l.1-.1 .1 .7a.68 .68 0 0 0-.8-.5l-.1 .3a1.25 1.25 0 0 1 .9 1.2 .81 .81 0 0 1-1.2 .4l-.1 .1v-.8a.74 .74 0 0 0 .8 .6l.1-.3a1.58 1.58 0 0 1-.9-1.2z" fill-rule="evenodd"/>
<path d="M215.3 65.1l.7-.4a3.2 3.2 0 0 0-.2 3.7l.2 .2a2.2 2.2 0 0 1-.7-3.5z" fill-rule="evenodd"/>
<path d="M216.5 64.9a1.68 1.68 0 0 1 1.5 0l.2-.2v1a.88 .88 0 0 0-1.4-.6l.1 .4a2.28 2.28 0 0 1 1.5 1.4 1.2 1.2 0 0 1-1.9 .7l-.2 .2v-1.1a.98 .98 0 0 0 1.5 .7 .62 .62 0 0 0-.6-.8 1.01 1.01 0 0 1-.8-1.5z" fill-rule="evenodd"/>
<path d="M219.1 65.9a.68 .68 0 0 1 .8-.3 .68 .68 0 0 1 .4 .7 .41 .41 0 0 1-.4 0 .41 .41 0 0 1-.2-.5h-.1a1.04 1.04 0 0 0 .4 1.6l.4-.2a.89 .89 0 0 1-1.2 .5 .89 .89 0 0 1-.5-1.2z" fill-rule="evenodd"/>
<path d="M220.9 65.9a.85 .85 0 0 1 1-.3 .85 .85 0 0 1 .6 .8v1h.2a.42 .42 0 0 1-.4 .4 .42 .42 0 0 1-.4-.4 .6 .6 0 0 1-.6 .4 .6 .6 0 0 1-.5-.3v-.3h.6l.2 .2 .3-.1v-.7l-.5 .6h-.6l.3-.4 .8-.4-.1-.4a.27 .27 0 0 0-.3-.2 .27 .27 0 0 0-.1 .4 .32 .32 0 0 1-.5 .2 .32 .32 0 0 1 0-.5z" fill-rule="evenodd"/>
<path d="M222.9 64.7h.9v2.8l.2 .2h-1.1l.2-.1 .1-.3-.1-2.3z" fill-rule="evenodd"/>
<path d="M224.5 65.9a.83 .83 0 0 1 1-.2 .83 .83 0 0 1 .5 .9h-1.2a.58 .58 0 0 0 .3 .8 .58 .58 0 0 0 .8-.3 .85 .85 0 0 1-1 .7 .85 .85 0 0 1-.7-1.1l.1-.3 1.1 .1-.1-.7a.4 .4 0 0 0-.5 .2 .4 .4 0 0 0 0 .4h-.5z" fill-rule="evenodd"/>
<path d="M227.5 65.2l1.2-.5v2.7l.1 .2 .3 .1h-1.6l.5-.2v-1.9l-.1-.4z" fill-rule="evenodd"/>
<path d="M231.3 65.2l1.1-.5v2.7l.2 .2 .3 .1h-1.6l.5-.2v-1.9l-.1-.4z" fill-rule="evenodd"/>
<path d="M233.3 64.7a2.18 2.18 0 0 1 1.2 2 2.18 2.18 0 0 1-1.2 1.9 3.2 3.2 0 0 0 .2-3.7z" fill-rule="evenodd"/>
<circle cx="55.2" cy="17.8" r=".42"/>
<circle cx="63.9" cy="17.8" r=".42"/>
<circle cx="207" cy="65" r=".34"/>
<circle cx="230.2" cy="67.4" r=".36"/>
<circle cx="230.2" cy="66" r=".36"/>
</g>
<g fill="#00007f">
<path d="M392.2 248.7h.8l-.5 1.4h-.1l.4-1.2h-.5l-.2 .2z" fill-rule="evenodd"/>
<path d="M393.5 248.7h.5l-.1 .2h-.4l-.1 .2a.5 .5 0 0 1 .5 .6 .5 .5 0 0 1-.7 .3 .4 .4 0 0 0 .6-.3 .4 .4 0 0 0-.5-.4h-.1z" fill-rule="evenodd"/>
<path d="M394.4 248.8a.57 .57 0 0 1 .7 .3 .57 .57 0 0 1-.2 .7l-.4 .3h-.3l.4-.2 .2-.4a.39 .39 0 0 1-.5 0 .39 .39 0 0 1-.1-.4h.2l.1 .3a.28 .28 0 0 0 .4 0 .28 .28 0 0 0-.1-.4l-.1-.2a.24 .24 0 0 0-.3 0 .24 .24 0 0 0 0 .3h-.2z" fill-rule="evenodd"/>
<path d="M395.4 248.8a.47 .47 0 0 1 .6 0 .47 .47 0 0 1 .1 .6 .48 .48 0 0 1-.1 .6 .48 .48 0 0 1-.6 0l-.2-.5h.2a.36 .36 0 0 0 0 .4 .36 .36 0 0 0 .4 .1l.1-.6-.1-.6a.24 .24 0 0 0-.3 0 .24 .24 0 0 0 0 .3l-.1 .4h-.2z" fill-rule="evenodd"/>
<path d="M396.4 248.9l.4-.2v1.3l.2 .1h-.5l.1-.1v-.9v-.2z" fill-rule="evenodd"/>
<path d="M397.4 249.2h.4l.2 .1v.7h.2l-.2 .1-.2-.1a.29 .29 0 0 1-.4 0l-.1-.1 .3 .1 .2-.1v-.3l-.5 .3 .5-.4-.1-.3-.3 .3z" fill-rule="evenodd"/>
<path d="M398.4 248.8h.5a.31 .31 0 0 1-.1 .5 .43 .43 0 0 1 .2 .7 .43 .43 0 0 1-.7 0 .34 .34 0 0 0 .5 0 .34 .34 0 0 0-.1-.5l-.2-.1a.28 .28 0 0 0 .3-.2 .28 .28 0 0 0-.1-.3 .28 .28 0 0 0-.4 .1z" fill-rule="evenodd"/>
</g>
<path d="M390.5 243v10.5" fill="none" stroke="#000" stroke-width=".18"/>
<g fill="#00f">
<path d="M392.3 244.3l.3-.2h.5l.3 .3 .1 .1-.2 .1a.58 .58 0 0 0-.8-.2 .58 .58 0 0 0-.2 .8 .58 .58 0 0 0 .8 .2l.2-.1v-.3h-.4v-.1h.6v.5a.81 .81 0 0 1-1.2 .1 .81 .81 0 0 1 0-1.2z" fill-rule="evenodd"/>
<path d="M393.8 244.1h.2v.2h-.2z" fill-rule="evenodd"/>
<path d="M393.8 244.5h.2v1.1h-.2z" fill-rule="evenodd"/>
<path d="M394.3 244.3l.2-.1v.3h.1v.2h-.1v.6l.2 .3a.27 .27 0 0 1-.3 0 .27 .27 0 0 1-.1-.3v-.6h-.2z" fill-rule="evenodd"/>
<path d="M395.4 244.1h.2v.6h.8v-.6h.2v1.5h-.2v-.7h-.8v.7h-.2z" fill-rule="evenodd"/>
<path d="M397 244.6l.1-.1a.47 .47 0 0 1 .6 .1 .47 .47 0 0 1 .1 .6l.1 .4h-.2l-.1-.1-.5 .1-.2-.1v-.2l.3 .2h.3l.1-.4-.7 .2a.57 .57 0 0 1 .7-.4 .28 .28 0 0 0-.2-.2 .28 .28 0 0 0-.3 .2l-.2-.1z" fill-rule="evenodd"/>
<path d="M398.1 244.6l.3-.1a.39 .39 0 0 1 .5 .3h-.2a.21 .21 0 0 0-.3-.2 .21 .21 0 0 0-.1 .3 .43 .43 0 0 1 .5 .1 .43 .43 0 0 1 .1 .4l-.3 .2h-.3l-.3-.3h.2a.24 .24 0 0 0 .3 .3 .24 .24 0 0 0 .1-.4 .43 .43 0 0 1-.5-.5z" fill-rule="evenodd"/>
<path d="M399.1 244.1h.2v.6l.3-.2 .4 .1v1h-.2v-.7a.27 .27 0 0 0-.3-.2 .27 .27 0 0 0-.2 .3v.6h-.2z" fill-rule="evenodd"/>
<path d="M400.4 244.5h.2v.2h-.2z" fill-rule="evenodd"/>
<path d="M400.4 245.4h.2v.2h-.2z" fill-rule="evenodd"/>
</g>
<use href="#words"/>
</svg>
